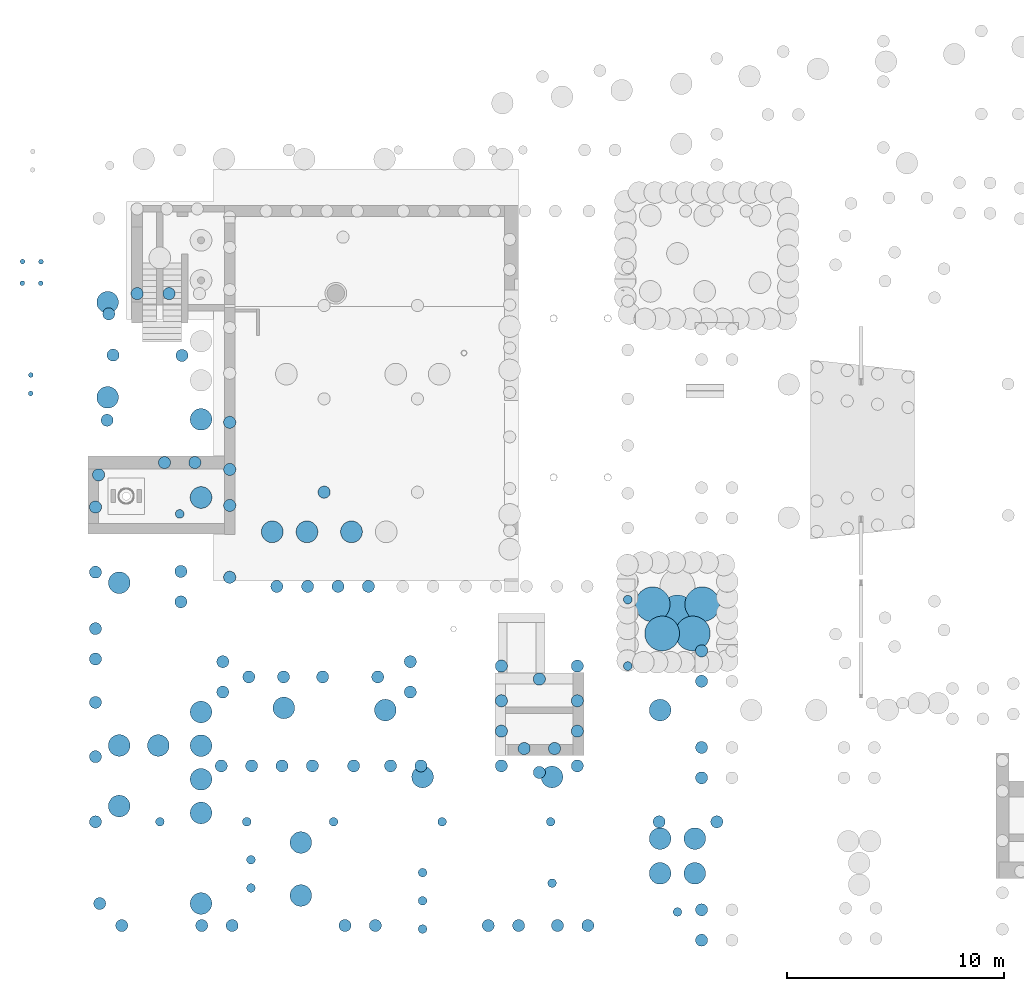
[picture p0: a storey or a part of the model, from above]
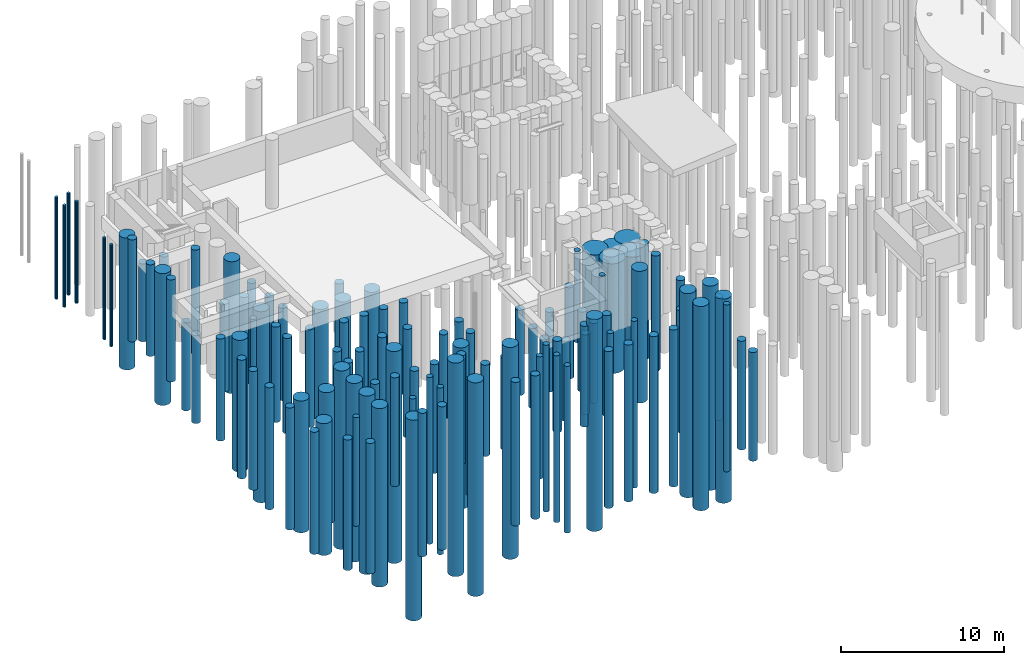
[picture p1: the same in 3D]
Properties of the parts of a building model (IFC2X3), part 1 of 18

# File
Description: ViewDefinition [CoordinationView_V2.0, QuantityTakeOffAddOnView]
File name: 219052
Time: 2021-05-28T06:18:43
Written by: The EXPRESS Data Manager Version 5.02.0100.07 : 28 Aug 2013
Made in: 20210416_1515(x64) - Exporter 19.5.1.0 - Alternate UI 19.5.1.0
Comment: STEP Physical File produced by: The EXPRESS Data Manager Version 5.02.0100.07 : 28 Aug 2013 * Module: EDMstepFileFactory/EDMstandAlone * Creation date: Fri May 28 06:18:43 2021 * Host: pbtutr100 * Database: C:\Users\FDAALH~1\AppData\Local\Temp\{68DC5530-F8EF-4A1F-8CA8-0C31A68B41FF}\ifc * Database version: 5507 * Database creation date: Fri May 28 06:17:17 2021 * Schema: IFC2X3 * Model: DataRepository.ifc * Model creation date: Fri May 28 06:17:18 2021 * Header model: DataRepository.ifc_HeaderModel * Header model creation date: Fri May 28 06:17:18 2021 * EDMuser: sdai-user * EDMgroup: sdai-group * License ID and type: 5605 : Permanent license. Expiry date: * EDMstepFileFactory options: 020000

# IfcProject, 219052
LongName: Theater aan de Parade; Phase: Technisch Ontwerp

# IfcSite, Theater aan de Parade
RefLatitude: 52, 22, 22, 799999; RefLongitude: 4, 53, 41, 279999; RefElevation: 0 mm
Pset_ProductRequirements - Category: Project Information

# IfcBuilding, Theater aan de Parade
LongName: Theater aan de Parade
Pset_BuildingCommon - NumberOfStoreys: 9
Pset_ProductRequirements - Category: Project Information
Pset_Pieters Projectinformatie - 1.1 Bedrijf: Pieters Bouwtechniek Utrecht; 1.2 Website: www.pietersbouwtechniek.nl; 1.3 Projectleider: ir. Y. van Diermen; 1.4 BIM-modelleur: Pieters Bouwtechniek Utrecht; 2.1 Projectnummer: 219052; 2.2 Projectnaam: Theater aan de Parade; 2.3 Project Address: Den Bosch; 2.4 Opdrachtgever: Gemeente Den Bosch; 2.5 Project Status: Technisch Ontwerp; 3.1 Model status: Definitief Ontwerp; 3.2 Datum model: 28-05-2021

# IfcBuildingStorey: Level:PBT_level (9)
In: Theater aan de Parade
Pset_ProductRequirements - Category: Levels
Name | LongName | Elevation (mm) | Pset_AirSideSystemInformation, Name = Pset_ProductRequirements, Name
-2 kelder | -2 kelder | -5520 | palenplan
-1 kelder | -1 kelder | -3300 | -1 kelder
00 begane grond | 00 begane grond | 3.49117e-09 | 00 begane grond
01 eerste verdieping | 01 eerste verdieping | 5020 | 01 eerste verdieping
02 tweede verdieping | 02 tweede verdieping | 8750 | 02 tweede verdieping
03 derde verdieping | 03 derde verdieping | 12480 | 03 derde verdieping
04 vierde verdieping | 04 vierde verdieping | 15820 | 04 vierde verdieping
05 vijfde verdieping | 05 vijfde verdieping | 20300 | 05 vijfde verdieping
06 zesde verdieping | 06 zesde verdieping | 26150 | 06 zesde verdieping

# IfcBeam: 21_PBT_SF_akoestische ontkoppeling:250x200, 21_PBT_SF_akoestische ontkoppeling:250x200:4782382
In: 05 vijfde verdieping
Type - Pset_BeamCommon - IsExternal: no; LoadBearing: yes
Type - Pset_ManufacturerTypeInformation - Manufacturer: Leverancier
Type - Pset_ProductRequirements - Category: Structural Framing
Type - Pset_ReinforcementBarPitchOfBeam - Description: akoestisch isolerende oplegging cf. opgave leverancier
Type - Pset_Pieters - Breedte: 250 mm; Hoogte: 200 mm; Codering - NL-SfB: 21.25; Omschrijving NL-SfB: buitenwanden - constructief, borstweringen; Materiaal: 00_PBT_MAT_volgens leverancier; Materiaalkwaliteit: volgens leverancier; Description: akoestisch isolerende oplegging cf. opgave leverancier
Classification: 21.25 buitenwanden - constructief, borstweringen (Uniformat); Material: 00_PBT_MAT_volgens leverancier
BaseQuantities - CrossSectionArea: 1827897 mm2; NetVolume: 0.197544 m3; Length: 3950.88 mm; NetSurfaceArea: 3655794 mm2
Pset_BeamCommon - Slope: 0 deg; Reference: 21_PBT_SF_akoestische ontkoppeling:250x200; Span: 3950.88 mm
Pset_QuantityTakeOff - Reference: 21_PBT_SF_akoestische ontkoppeling:250x200
Pset_ReinforcementBarPitchOfBeam - Reference: 21_PBT_SF_akoestische ontkoppeling:250x200
Pset_Pieters - Bouwlaag: Level: 05 vijfde verdieping; Naamgeving element: 21_PBT_SF_akoestische ontkoppeling: 250x200; Fase: Nieuw

# IfcBeam: 21_PBT_SF_akoestische ontkoppeling:250x300 (2)
In: 05 vijfde verdieping
Type - Pset_BeamCommon - IsExternal: no; LoadBearing: yes
Type - Pset_ManufacturerTypeInformation - Manufacturer: Leverancier
Type - Pset_ProductRequirements - Category: Structural Framing
Type - Pset_ReinforcementBarPitchOfBeam - Description: akoestisch isolerende oplegging cf. opgave leverancier
Type - Pset_Pieters - Breedte: 250 mm; Hoogte: 300 mm; Codering - NL-SfB: 21.25; Omschrijving NL-SfB: buitenwanden - constructief, borstweringen; Materiaal: 00_PBT_MAT_volgens leverancier; Materiaalkwaliteit: volgens leverancier; Description: akoestisch isolerende oplegging cf. opgave leverancier
Classification: 21.25 buitenwanden - constructief, borstweringen (Uniformat); Material: 00_PBT_MAT_volgens leverancier
Pset_BeamCommon - Slope: 0 deg; Reference: 21_PBT_SF_akoestische ontkoppeling:250x300
Pset_QuantityTakeOff - Reference: 21_PBT_SF_akoestische ontkoppeling:250x300
Pset_ReinforcementBarPitchOfBeam - Reference: 21_PBT_SF_akoestische ontkoppeling:250x300
Pset_Pieters - Bouwlaag: Level: 05 vijfde verdieping; Naamgeving element: 21_PBT_SF_akoestische ontkoppeling: 250x300; Fase: Nieuw
Name (21_PBT_SF_akoestische ontkoppeling:250x300:...) | CrossSectionArea (mm2) | NetVolume (m3) | Span (mm) = Length (mm) | NetSurfaceArea (mm2)
2983572 | 14127500 | 1.91625 | 25550 | 28255000
2986482 | 8379402 | 1.13242 | 15098.9 | 16758803

# IfcBeam: 28_PBT_SF_betonbalk enkele sponning:C30/37_1000x950/330x350_bestaand, 28_PBT_SF_betonbalk enkele sponning:C30/37_1000x950/330x350_bestaand:3179845
In: 00 begane grond
Type - Pset_BeamCommon - IsExternal: no; LoadBearing: yes
Type - Pset_ProductRequirements - Category: Structural Framing
Type - Pset_ReinforcementBarPitchOfBeam - Description: 1000x950/330x350
Type - Pset_Pieters - Breedte: 1000 mm; Hoogte: 950 mm; Codering - NL-SfB: 28.11; Omschrijving NL-SfB: hoofddraagconstructies - kolommen en liggers, kolom-/liggerconstructies; Materiaal: 00_PBT_MAT_beton t.p.g._C30/37; Materiaalkwaliteit: C30/37; Description: 1000x950/330x350
Classification: 28.11 hoofddraagconstructies - kolommen en liggers, kolom-/liggerconstructies (Uniformat); Material: 00_PBT_MAT_beton t.p.g._C30/37
BaseQuantities - CrossSectionArea: 31490673 mm2; NetVolume: 10.4303 m3; Length: 19109.8 mm; NetSurfaceArea: 62981346 mm2
Pset_BeamCommon - Slope: 0 deg; Reference: 28_PBT_SF_betonbalk enkele sponning:C30/37_1000x950/330x350_bestaand; Span: 19109.8 mm
Pset_QuantityTakeOff - Reference: 28_PBT_SF_betonbalk enkele sponning:C30/37_1000x950/330x350_bestaand
Pset_ReinforcementBarPitchOfBeam - Reference: 28_PBT_SF_betonbalk enkele sponning:C30/37_1000x950/330x350_bestaand
Pset_Pieters - Bouwlaag: Level: 00 begane grond; Naamgeving element: 28_PBT_SF_betonbalk enkele sponning: C30/37_1000x950/330x350_bestaand; Fase: Nieuw

# IfcBeam: 28_PBT_SF_betonbalk enkele sponning:C30/37_800x950/300x350_bestaand, 28_PBT_SF_betonbalk enkele sponning:C30/37_800x950/300x350_bestaand:3180236
In: 00 begane grond
Type - Pset_BeamCommon - IsExternal: no; LoadBearing: yes
Type - Pset_ProductRequirements - Category: Structural Framing
Type - Pset_ReinforcementBarPitchOfBeam - Description: 800x950/300x350
Type - Pset_Pieters - Breedte: 800 mm; Hoogte: 950 mm; Codering - NL-SfB: 28.11; Omschrijving NL-SfB: hoofddraagconstructies - kolommen en liggers, kolom-/liggerconstructies; Materiaal: 00_PBT_MAT_beton t.p.g._C30/37; Materiaalkwaliteit: C30/37; Description: 800x950/300x350
Classification: 28.11 hoofddraagconstructies - kolommen en liggers, kolom-/liggerconstructies (Uniformat); Material: 00_PBT_MAT_beton t.p.g._C30/37
BaseQuantities - CrossSectionArea: 5006200 mm2; NetVolume: 1.12397 m3; Length: 3733 mm; NetSurfaceArea: 10012400 mm2
Pset_BeamCommon - Slope: 0 deg; Reference: 28_PBT_SF_betonbalk enkele sponning:C30/37_800x950/300x350_bestaand; Span: 3733 mm
Pset_QuantityTakeOff - Reference: 28_PBT_SF_betonbalk enkele sponning:C30/37_800x950/300x350_bestaand
Pset_ReinforcementBarPitchOfBeam - Reference: 28_PBT_SF_betonbalk enkele sponning:C30/37_800x950/300x350_bestaand
Pset_Pieters - Bouwlaag: Level: 00 begane grond; Naamgeving element: 28_PBT_SF_betonbalk enkele sponning: C30/37_800x950/300x350_bestaand; Fase: Nieuw

# IfcBeam: 28_PBT_SF_betonbalk:250x580_bestaand, 28_PBT_SF_betonbalk:250x580_bestaand:1909526
In: 00 begane grond
Type - Pset_BeamCommon - IsExternal: no; LoadBearing: yes
Type - Pset_ProductRequirements - Category: Structural Framing
Type - Pset_ReinforcementBarPitchOfBeam - Description: 250x580
Type - Pset_Pieters - Breedte: 250 mm; Hoogte: 580 mm; Codering - NL-SfB: 28.11; Omschrijving NL-SfB: hoofddraagconstructies - kolommen en liggers, kolom-/liggerconstructies; Materiaal: 00_PBT_MAT_beton t.p.g.; Description: 250x580
Classification: 28.11 hoofddraagconstructies - kolommen en liggers, kolom-/liggerconstructies (Uniformat); Material: 00_PBT_MAT_beton t.p.g.
BaseQuantities - CrossSectionArea: 4129481 mm2; NetVolume: 0.695609 m3; Length: 4538.37 mm; NetSurfaceArea: 8258963 mm2
Pset_BeamCommon - Slope: 0 deg; Reference: 28_PBT_SF_betonbalk:250x580_bestaand; Span: 4538.37 mm
Pset_QuantityTakeOff - Reference: 28_PBT_SF_betonbalk:250x580_bestaand
Pset_ReinforcementBarPitchOfBeam - Reference: 28_PBT_SF_betonbalk:250x580_bestaand
Pset_Pieters - Dragend/niet dragend: yes; In/uitwendig: no; Bouwlaag: Level: 00 begane grond_Offset1000; Naamgeving element: 28_PBT_SF_betonbalk: 250x580_bestaand; Fase: Bestaand

# IfcBeam: 28_PBT_SF_betonbalk:400x800_bestaand (2)
In: 01 eerste verdieping
Type - PredefinedType: BEAM; Classification: 28.11 hoofddraagconstructies - kolommen en liggers, kolom-/liggerconstructies (Uniformat); Material: 00_PBT_MAT_beton t.p.g.
Type - Pset_BeamCommon - IsExternal: no; LoadBearing: yes
Type - Pset_ProductRequirements - Category: Structural Framing
Type - Pset_ReinforcementBarPitchOfBeam - Description: 400x800
Type - Pset_Pieters - Breedte: 400 mm; Hoogte: 800 mm; Codering - NL-SfB: 28.11; Omschrijving NL-SfB: hoofddraagconstructies - kolommen en liggers, kolom-/liggerconstructies; Materiaal: 00_PBT_MAT_beton t.p.g.; Description: 400x800
Pset_BeamCommon - Reference: 28_PBT_SF_betonbalk:400x800_bestaand; Slope: 14.1361 deg
Pset_QuantityTakeOff - Reference: 28_PBT_SF_betonbalk:400x800_bestaand
Pset_ReinforcementBarPitchOfBeam - Reference: 28_PBT_SF_betonbalk:400x800_bestaand
Pset_Pieters - Dragend/niet dragend: yes; In/uitwendig: no; Bouwlaag: Level: 01 eerste verdieping_Offset1000; Naamgeving element: 28_PBT_SF_betonbalk: 400x800_bestaand; Fase: Bestaand
Name (28_PBT_SF_betonbalk:400x800_bestaand:...) | Span (mm) = Length (mm) | CrossSectionArea (mm2) | NetVolume (m3) | NetSurfaceArea (mm2)
1565912 | 4600 | 4719124 | 1.06921 | 9438249
1930396 | 4625.59 | 4845457 | 1.12009 | 9690914

# IfcBeam: 28_PBT_SF_betonbalk:400x800_bestaand (6)
In: 01 eerste verdieping
Type - Pset_BeamCommon - IsExternal: no; LoadBearing: yes
Type - Pset_ProductRequirements - Category: Structural Framing
Type - Pset_ReinforcementBarPitchOfBeam - Description: 400x800
Type - Pset_Pieters - Breedte: 400 mm; Hoogte: 800 mm; Codering - NL-SfB: 28.11; Omschrijving NL-SfB: hoofddraagconstructies - kolommen en liggers, kolom-/liggerconstructies; Materiaal: 00_PBT_MAT_beton t.p.g.; Description: 400x800
Classification: 28.11 hoofddraagconstructies - kolommen en liggers, kolom-/liggerconstructies (Uniformat); Material: 00_PBT_MAT_beton t.p.g.
Pset_BeamCommon - Reference: 28_PBT_SF_betonbalk:400x800_bestaand
Pset_QuantityTakeOff - Reference: 28_PBT_SF_betonbalk:400x800_bestaand
Pset_ReinforcementBarPitchOfBeam - Reference: 28_PBT_SF_betonbalk:400x800_bestaand
Pset_Pieters - Dragend/niet dragend: yes; In/uitwendig: no; Bouwlaag: Level: 01 eerste verdieping_Offset1000; Naamgeving element: 28_PBT_SF_betonbalk: 400x800_bestaand; Fase: Bestaand
Name (28_PBT_SF_betonbalk:400x800_bestaand:...) | CrossSectionArea (mm2) | NetVolume (m3) | Slope (deg) | Span (mm) = Length (mm) | NetSurfaceArea (mm2)
1565437 | 4204902 | 0.95228 | 0 | 3969.1 | 8409803
1930000 | 4013368 | 0.905608 | 0 | 3773.37 | 8026736
1930004 | 4928468 | 1.14791 | 14.1361 | 4625.59 | 9856937
1930203 | 3938368 | 0.887608 | 0 | 3698.37 | 7876736
1930207 | 5603805 | 1.38064 | 14.1361 | 4625.59 | 11207611
1930394 | 3938368 | 0.887608 | 0 | 3698.37 | 7876736

# IfcBeam: 28_PBT_SF_betonbalk:460x200_bestaand (4)
In: 03 derde verdieping
Type - Pset_BeamCommon - IsExternal: no; LoadBearing: yes
Type - Pset_ProductRequirements - Category: Structural Framing
Type - Pset_ReinforcementBarPitchOfBeam - Description: 460x200
Type - Pset_Pieters - Breedte: 460 mm; Hoogte: 200 mm; Codering - NL-SfB: 28.11; Omschrijving NL-SfB: hoofddraagconstructies - kolommen en liggers, kolom-/liggerconstructies; Materiaal: 00_PBT_MAT_beton t.p.g.; Description: 460x200
Classification: 28.11 hoofddraagconstructies - kolommen en liggers, kolom-/liggerconstructies (Uniformat); Material: 00_PBT_MAT_beton t.p.g.
Pset_BeamCommon - Slope: 0 deg; Reference: 28_PBT_SF_betonbalk:460x200_bestaand
Pset_QuantityTakeOff - Reference: 28_PBT_SF_betonbalk:460x200_bestaand
Pset_ReinforcementBarPitchOfBeam - Reference: 28_PBT_SF_betonbalk:460x200_bestaand
Pset_Pieters - Dragend/niet dragend: yes; In/uitwendig: no; Bouwlaag: Level: 03 derde verdieping_Offset1000; Naamgeving element: 28_PBT_SF_betonbalk: 460x200_bestaand; Fase: Bestaand
Name (28_PBT_SF_betonbalk:460x200_bestaand:...) | CrossSectionArea (mm2) | NetVolume (m3) | Span (mm) = Length (mm) | NetSurfaceArea (mm2)
1677606 | 58809.2 | 0.00246754 | 81.1691 | 117618
1686086 | 50330.3 | 0.00173109 | 56.9438 | 100661
5755660 | 709531 | 0.058753 | 1618.83 | 1419062
5763070 | 751234 | 0.0661246 | 1643.06 | 1502468

# IfcBeam: 28_PBT_SF_betonbalk:460x400_bestaand (2)
In: 03 derde verdieping
Type - Pset_BeamCommon - IsExternal: no; LoadBearing: yes
Type - Pset_ProductRequirements - Category: Structural Framing
Type - Pset_ReinforcementBarPitchOfBeam - Description: 460x400
Type - Pset_Pieters - Breedte: 460 mm; Hoogte: 400 mm; Codering - NL-SfB: 28.11; Omschrijving NL-SfB: hoofddraagconstructies - kolommen en liggers, kolom-/liggerconstructies; Materiaal: 00_PBT_MAT_beton t.p.g.; Description: 460x400
Classification: 28.11 hoofddraagconstructies - kolommen en liggers, kolom-/liggerconstructies (Uniformat); Material: 00_PBT_MAT_beton t.p.g.
Pset_BeamCommon - Slope: 0 deg; Reference: 28_PBT_SF_betonbalk:460x400_bestaand
Pset_QuantityTakeOff - Reference: 28_PBT_SF_betonbalk:460x400_bestaand
Pset_ReinforcementBarPitchOfBeam - Reference: 28_PBT_SF_betonbalk:460x400_bestaand
Pset_Pieters - Dragend/niet dragend: yes; In/uitwendig: no; Bouwlaag: Level: 03 derde verdieping_Offset1000; Naamgeving element: 28_PBT_SF_betonbalk: 460x400_bestaand; Fase: Bestaand
Name (28_PBT_SF_betonbalk:460x400_bestaand:...) | CrossSectionArea (mm2) | NetVolume (m3) | Span (mm) = Length (mm) | NetSurfaceArea (mm2)
1681105 | 1529800 | 0.120005 | 3553.7 | 3059599
1686088 | 1718879 | 0.206605 | 3530.9 | 3437758

# IfcBeam: 28_PBT_SF_betonbalk:660x210_bestaand (3)
In: 03 derde verdieping
Type - Pset_BeamCommon - IsExternal: no; LoadBearing: yes
Type - Pset_ProductRequirements - Category: Structural Framing
Type - Pset_ReinforcementBarPitchOfBeam - Description: 660x210
Type - Pset_Pieters - Breedte: 660 mm; Hoogte: 210 mm; Codering - NL-SfB: 28.11; Omschrijving NL-SfB: hoofddraagconstructies - kolommen en liggers, kolom-/liggerconstructies; Materiaal: 00_PBT_MAT_beton t.p.g.; Description: 660x210
Classification: 28.11 hoofddraagconstructies - kolommen en liggers, kolom-/liggerconstructies (Uniformat); Material: 00_PBT_MAT_beton t.p.g.
Pset_BeamCommon - Slope: 0 deg; Reference: 28_PBT_SF_betonbalk:660x210_bestaand
Pset_QuantityTakeOff - Reference: 28_PBT_SF_betonbalk:660x210_bestaand
Pset_ReinforcementBarPitchOfBeam - Reference: 28_PBT_SF_betonbalk:660x210_bestaand
Pset_Pieters - Dragend/niet dragend: yes; In/uitwendig: no; Bouwlaag: Level: 03 derde verdieping_Offset1000; Naamgeving element: 28_PBT_SF_betonbalk: 660x210_bestaand; Fase: Bestaand
Name (28_PBT_SF_betonbalk:660x210_bestaand:...) | CrossSectionArea (mm2) | NetVolume (m3) | Span (mm) = Length (mm) | NetSurfaceArea (mm2)
1676867 | 1840709 | 0.23369 | 3901.17 | 3681417
1686084 | 2592921 | 0.378573 | 3876.94 | 5185842
1769211 | 1091486 | 0.126744 | 1618.83 | 2182971

# IfcBeam: 28_PBT_SF_betonbalk:C30/37_1000x1800, 28_PBT_SF_betonbalk:C30/37_1000x1800:2594089
In: 01 eerste verdieping
Type - Pset_BeamCommon - IsExternal: no; LoadBearing: yes
Type - Pset_ProductRequirements - Category: Structural Framing
Type - Pset_ReinforcementBarPitchOfBeam - Description: 1000x1800
Type - Pset_Pieters - Breedte: 1000 mm; Hoogte: 1800 mm; Codering - NL-SfB: 28.11; Omschrijving NL-SfB: hoofddraagconstructies - kolommen en liggers, kolom-/liggerconstructies; Materiaal: 00_PBT_MAT_beton t.p.g._C30/37; Materiaalkwaliteit: C30/37; Description: 1000x1800
Classification: 28.11 hoofddraagconstructies - kolommen en liggers, kolom-/liggerconstructies (Uniformat); Material: 00_PBT_MAT_beton t.p.g._C30/37
BaseQuantities - CrossSectionArea: 41120002 mm2; NetVolume: 17.92 m3; Length: 21950 mm; NetSurfaceArea: 82240004 mm2
Pset_BeamCommon - Slope: 0 deg; Reference: 28_PBT_SF_betonbalk:C30/37_1000x1800; Span: 21950 mm
Pset_QuantityTakeOff - Reference: 28_PBT_SF_betonbalk:C30/37_1000x1800
Pset_ReinforcementBarPitchOfBeam - Reference: 28_PBT_SF_betonbalk:C30/37_1000x1800
Pset_Pieters - Bouwlaag: Level: 01 eerste verdieping; Naamgeving element: 28_PBT_SF_betonbalk: C30/37_1000x1800; Fase: Nieuw

# IfcBeam: 28_PBT_SF_betonbalk:C30/37_1000x590, 28_PBT_SF_betonbalk:C30/37_1000x590:2683898
In: 00 begane grond
Type - Pset_BeamCommon - IsExternal: no; LoadBearing: yes
Type - Pset_ProductRequirements - Category: Structural Framing
Type - Pset_ReinforcementBarPitchOfBeam - Description: 1000x590
Type - Pset_Pieters - Breedte: 1000 mm; Hoogte: 590 mm; Codering - NL-SfB: 28.11; Omschrijving NL-SfB: hoofddraagconstructies - kolommen en liggers, kolom-/liggerconstructies; Materiaal: 00_PBT_MAT_beton t.p.g._C30/37; Materiaalkwaliteit: C30/37; Description: 1000x590
Classification: 28.11 hoofddraagconstructies - kolommen en liggers, kolom-/liggerconstructies (Uniformat); Material: 00_PBT_MAT_beton t.p.g._C30/37
BaseQuantities - CrossSectionArea: 7429589 mm2; NetVolume: 0.839773 m3; Length: 6560 mm; NetSurfaceArea: 14859177 mm2
Pset_BeamCommon - Slope: 0 deg; Reference: 28_PBT_SF_betonbalk:C30/37_1000x590; Span: 6560 mm
Pset_QuantityTakeOff - Reference: 28_PBT_SF_betonbalk:C30/37_1000x590
Pset_ReinforcementBarPitchOfBeam - Reference: 28_PBT_SF_betonbalk:C30/37_1000x590
Pset_Pieters - Bouwlaag: Level: 00 begane grond; Naamgeving element: 28_PBT_SF_betonbalk: C30/37_1000x590; Fase: Nieuw

# IfcBeam: 28_PBT_SF_betonbalk:C30/37_1200x800, 28_PBT_SF_betonbalk:C30/37_1200x800:5488795
In: 01 eerste verdieping
Type - Pset_BeamCommon - IsExternal: no; LoadBearing: yes
Type - Pset_ProductRequirements - Category: Structural Framing
Type - Pset_ReinforcementBarPitchOfBeam - Description: 1200x800
Type - Pset_Pieters - Breedte: 1200 mm; Hoogte: 800 mm; Codering - NL-SfB: 28.11; Omschrijving NL-SfB: hoofddraagconstructies - kolommen en liggers, kolom-/liggerconstructies; Materiaal: 00_PBT_MAT_beton t.p.g._C30/37; Materiaalkwaliteit: C30/37; Description: 1200x800
Classification: 28.11 hoofddraagconstructies - kolommen en liggers, kolom-/liggerconstructies (Uniformat); Material: 00_PBT_MAT_beton t.p.g._C30/37
BaseQuantities - CrossSectionArea: 7296007 mm2; NetVolume: 2.304 m3; Length: 4000 mm; NetSurfaceArea: 14592014 mm2
Pset_BeamCommon - Slope: 0 deg; Reference: 28_PBT_SF_betonbalk:C30/37_1200x800; Span: 4000 mm
Pset_QuantityTakeOff - Reference: 28_PBT_SF_betonbalk:C30/37_1200x800
Pset_ReinforcementBarPitchOfBeam - Reference: 28_PBT_SF_betonbalk:C30/37_1200x800
Pset_Pieters - Bouwlaag: Level: 01 eerste verdieping; Naamgeving element: 28_PBT_SF_betonbalk: C30/37_1200x800; Fase: Nieuw

# IfcBeam: 28_PBT_SF_betonbalk:C30/37_1250x550, 28_PBT_SF_betonbalk:C30/37_1250x550:2991065
In: 00 begane grond
Type - Pset_BeamCommon - IsExternal: no; LoadBearing: yes
Type - Pset_ProductRequirements - Category: Structural Framing
Type - Pset_ReinforcementBarPitchOfBeam - Description: 1250x550
Type - Pset_Pieters - Breedte: 1250 mm; Hoogte: 550 mm; Codering - NL-SfB: 28.11; Omschrijving NL-SfB: hoofddraagconstructies - kolommen en liggers, kolom-/liggerconstructies; Materiaal: 00_PBT_MAT_beton t.p.g._C30/37; Materiaalkwaliteit: C30/37; Description: 1250x550
Classification: 28.11 hoofddraagconstructies - kolommen en liggers, kolom-/liggerconstructies (Uniformat); Material: 00_PBT_MAT_beton t.p.g._C30/37
BaseQuantities - CrossSectionArea: 34014676 mm2; NetVolume: 6.55173 m3; Length: 23113.6 mm; NetSurfaceArea: 68029352 mm2
Pset_BeamCommon - Slope: 0 deg; Reference: 28_PBT_SF_betonbalk:C30/37_1250x550; Span: 23113.6 mm
Pset_QuantityTakeOff - Reference: 28_PBT_SF_betonbalk:C30/37_1250x550
Pset_ReinforcementBarPitchOfBeam - Reference: 28_PBT_SF_betonbalk:C30/37_1250x550
Pset_Pieters - Dragend/niet dragend: yes; In/uitwendig: no; Bouwlaag: Level: 00 begane grond; Naamgeving element: 28_PBT_SF_betonbalk: C30/37_1250x550; Fase: Nieuw

# IfcBeam: 28_PBT_SF_betonbalk:C30/37_200x250_opstort, 28_PBT_SF_betonbalk:C30/37_200x250_opstort:6442182
In: -1 kelder
Type - Pset_BeamCommon - IsExternal: no; LoadBearing: yes
Type - Pset_ProductRequirements - Category: Structural Framing
Type - Pset_ReinforcementBarPitchOfBeam - Description: opstort 220x250
Type - Pset_Pieters - Breedte: 220 mm; Hoogte: 250 mm; Codering - NL-SfB: 28.11; Omschrijving NL-SfB: hoofddraagconstructies - kolommen en liggers, kolom-/liggerconstructies; Materiaal: 00_PBT_MAT_beton t.p.g._C30/37; Materiaalkwaliteit: C30/37; Description: opstort 220x250
Classification: 28.11 hoofddraagconstructies - kolommen en liggers, kolom-/liggerconstructies (Uniformat); Material: 00_PBT_MAT_beton t.p.g._C30/37
BaseQuantities - CrossSectionArea: 1230000 mm2; NetVolume: 0.1375 m3; Length: 2632.5 mm; NetSurfaceArea: 2460000 mm2
Pset_BeamCommon - Slope: 0 deg; Reference: 28_PBT_SF_betonbalk:C30/37_200x250_opstort; Span: 2632.5 mm
Pset_QuantityTakeOff - Reference: 28_PBT_SF_betonbalk:C30/37_200x250_opstort
Pset_ReinforcementBarPitchOfBeam - Reference: 28_PBT_SF_betonbalk:C30/37_200x250_opstort
Pset_Pieters - Bouwlaag: Level: -1 kelder; Naamgeving element: 28_PBT_SF_betonbalk: C30/37_200x250_opstort; Fase: Nieuw

# IfcBeam: 28_PBT_SF_betonbalk:C30/37_500x1155, 28_PBT_SF_betonbalk:C30/37_500x1155:3469167
In: 05 vijfde verdieping
Type - Pset_BeamCommon - IsExternal: no; LoadBearing: yes
Type - Pset_ProductRequirements - Category: Structural Framing
Type - Pset_ReinforcementBarPitchOfBeam - Description: 500x1155
Type - Pset_Pieters - Breedte: 500 mm; Hoogte: 1155 mm; Codering - NL-SfB: 28.11; Omschrijving NL-SfB: hoofddraagconstructies - kolommen en liggers, kolom-/liggerconstructies; Materiaal: 00_PBT_MAT_beton t.p.g._C30/37; Materiaalkwaliteit: C30/37; Description: 500x1155
Classification: 28.11 hoofddraagconstructies - kolommen en liggers, kolom-/liggerconstructies (Uniformat); Material: 00_PBT_MAT_beton t.p.g._C30/37
BaseQuantities - CrossSectionArea: 5112010 mm2; NetVolume: 1.50675 m3; Length: 3292 mm; NetSurfaceArea: 10224020 mm2
Pset_BeamCommon - Slope: 0 deg; Reference: 28_PBT_SF_betonbalk:C30/37_500x1155; Span: 3292 mm
Pset_QuantityTakeOff - Reference: 28_PBT_SF_betonbalk:C30/37_500x1155
Pset_ReinforcementBarPitchOfBeam - Reference: 28_PBT_SF_betonbalk:C30/37_500x1155
Pset_Pieters - Bouwlaag: Level: 05 vijfde verdieping; Naamgeving element: 28_PBT_SF_betonbalk: C30/37_500x1155; Fase: Nieuw

# IfcBeam: 28_PBT_SF_betonbalk:C30/37_600x1460, 28_PBT_SF_betonbalk:C30/37_600x1460:6276495
In: -1 kelder
Type - Pset_BeamCommon - IsExternal: no; LoadBearing: yes
Type - Pset_ProductRequirements - Category: Structural Framing
Type - Pset_ReinforcementBarPitchOfBeam - Description: 600x1460
Type - Pset_Pieters - Breedte: 600 mm; Hoogte: 1460 mm; Codering - NL-SfB: 28.11; Omschrijving NL-SfB: hoofddraagconstructies - kolommen en liggers, kolom-/liggerconstructies; Materiaal: 00_PBT_MAT_beton t.p.g._C30/37; Materiaalkwaliteit: C30/37; Description: 600x1460
Classification: 28.11 hoofddraagconstructies - kolommen en liggers, kolom-/liggerconstructies (Uniformat); Material: 00_PBT_MAT_beton t.p.g._C30/37
BaseQuantities - CrossSectionArea: 5406000 mm2; NetVolume: 1.89 m3; Length: 2500 mm; NetSurfaceArea: 10812000 mm2
Pset_BeamCommon - Slope: 0 deg; Reference: 28_PBT_SF_betonbalk:C30/37_600x1460; Span: 2500 mm
Pset_QuantityTakeOff - Reference: 28_PBT_SF_betonbalk:C30/37_600x1460
Pset_ReinforcementBarPitchOfBeam - Reference: 28_PBT_SF_betonbalk:C30/37_600x1460
Pset_Pieters - Bouwlaag: Level: -1 kelder; Naamgeving element: 28_PBT_SF_betonbalk: C30/37_600x1460; Fase: Nieuw

# IfcBeam: 28_PBT_SF_betonbalk:C30/37_700x475 (6)
Type - Pset_BeamCommon - IsExternal: no; LoadBearing: yes
Type - Pset_ProductRequirements - Category: Structural Framing
Type - Pset_ReinforcementBarPitchOfBeam - Description: 700x475
Type - Pset_Pieters - Breedte: 700 mm; Hoogte: 475 mm; Codering - NL-SfB: 28.11; Omschrijving NL-SfB: hoofddraagconstructies - kolommen en liggers, kolom-/liggerconstructies; Materiaal: 00_PBT_MAT_beton t.p.g._C30/37; Materiaalkwaliteit: C30/37; Description: 700x475
Classification: 28.11 hoofddraagconstructies - kolommen en liggers, kolom-/liggerconstructies (Uniformat); Material: 00_PBT_MAT_beton t.p.g._C30/37
Pset_BeamCommon - Slope: 0 deg; Reference: 28_PBT_SF_betonbalk:C30/37_700x475
Pset_QuantityTakeOff - Reference: 28_PBT_SF_betonbalk:C30/37_700x475
Pset_ReinforcementBarPitchOfBeam - Reference: 28_PBT_SF_betonbalk:C30/37_700x475
Pset_Pieters - Naamgeving element: 28_PBT_SF_betonbalk: C30/37_700x475; Fase: Nieuw
Name (28_PBT_SF_betonbalk:C30/37_700x475:...) | In | CrossSectionArea (mm2) | NetVolume (m3) | Span (mm) = Length (mm) | Bouwlaag | NetSurfaceArea (mm2)
4480568 | 01 eerste verdieping | 3214397 | 0.815516 | 2452.68 | Level: 01 eerste verdieping | 6428795
4485362 | 01 eerste verdieping | 3263049 | 0.829283 | 2494.08 | Level: 01 eerste verdieping | 6526099
4485375 | 01 eerste verdieping | 2421318 | 0.31014 | 2400.73 | Level: 01 eerste verdieping | 4842636
4485550 | 02 tweede verdieping | 3142680 | 0.795221 | 2391.64 | Level: 02 tweede verdieping | 6285361
4485687 | 02 tweede verdieping | 3164496 | 0.801394 | 2410.21 | Level: 02 tweede verdieping | 6328991
4485700 | 02 tweede verdieping | 3054407 | 0.770242 | 2316.52 | Level: 02 tweede verdieping | 6108815

# IfcBeam: 28_PBT_SF_betonbalk:C30/37_715x1620, 28_PBT_SF_betonbalk:C30/37_715x1620:3781543
In: 00 begane grond
Type - Pset_BeamCommon - IsExternal: no; LoadBearing: yes
Type - Pset_ProductRequirements - Category: Structural Framing
Type - Pset_ReinforcementBarPitchOfBeam - Description: 715x1620
Type - Pset_Pieters - Breedte: 715 mm; Hoogte: 1620 mm; Codering - NL-SfB: 28.11; Omschrijving NL-SfB: hoofddraagconstructies - kolommen en liggers, kolom-/liggerconstructies; Materiaal: 00_PBT_MAT_beton t.p.g._C30/37; Materiaalkwaliteit: C30/37; Description: 715x1620
Classification: 28.11 hoofddraagconstructies - kolommen en liggers, kolom-/liggerconstructies (Uniformat); Material: 00_PBT_MAT_beton t.p.g._C30/37
BaseQuantities - CrossSectionArea: 28448347 mm2; NetVolume: 12.2539 m3; Length: 14873.2 mm; NetSurfaceArea: 56896695 mm2
Pset_BeamCommon - IsExternal: yes; Slope: 0 deg; Reference: 28_PBT_SF_betonbalk:C30/37_715x1620; Span: 14873.2 mm
Pset_QuantityTakeOff - Reference: 28_PBT_SF_betonbalk:C30/37_715x1620
Pset_ReinforcementBarPitchOfBeam - Reference: 28_PBT_SF_betonbalk:C30/37_715x1620
Pset_Pieters - Dragend/niet dragend: yes; In/uitwendig: yes; Bouwlaag: Level: 00 begane grond; Naamgeving element: 28_PBT_SF_betonbalk: C30/37_715x1620; Fase: Nieuw

# IfcBeam: 28_PBT_SF_betonbalk:C30/37_770x1155, 28_PBT_SF_betonbalk:C30/37_770x1155:3468080
In: 05 vijfde verdieping
Type - PredefinedType: BEAM; Classification: 28.11 hoofddraagconstructies - kolommen en liggers, kolom-/liggerconstructies (Uniformat); Material: 00_PBT_MAT_beton t.p.g._C30/37
Type - Pset_BeamCommon - IsExternal: no; LoadBearing: yes
Type - Pset_ProductRequirements - Category: Structural Framing
Type - Pset_ReinforcementBarPitchOfBeam - Description: 770x1155
Type - Pset_Pieters - Breedte: 770 mm; Hoogte: 1155 mm; Codering - NL-SfB: 28.11; Omschrijving NL-SfB: hoofddraagconstructies - kolommen en liggers, kolom-/liggerconstructies; Materiaal: 00_PBT_MAT_beton t.p.g._C30/37; Materiaalkwaliteit: C30/37; Description: 770x1155
Pset_BeamCommon - Slope: 0 deg; Reference: 28_PBT_SF_betonbalk:C30/37_770x1155; Span: 15448.8 mm
Pset_QuantityTakeOff - Reference: 28_PBT_SF_betonbalk:C30/37_770x1155
Pset_ReinforcementBarPitchOfBeam - Reference: 28_PBT_SF_betonbalk:C30/37_770x1155
Pset_Pieters - Bouwlaag: Level: 05 vijfde verdieping; Naamgeving element: 28_PBT_SF_betonbalk: C30/37_770x1155; Fase: Nieuw
BaseQuantities - Length: 15448.8 mm; CrossSectionArea: 24725361 mm2; OuterSurfaceArea: 2843.04 mm2; GrossSurfaceArea: 1781543 mm2; GrossVolume: 0.000656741 m3; NetVolume: 8.8651 m3; NetSurfaceArea: 49450722 mm2

# IfcBeam: 28_PBT_SF_betonbalk:C30/37_900x900, 28_PBT_SF_betonbalk:C30/37_900x900:5520784
In: 01 eerste verdieping
Type - Pset_BeamCommon - IsExternal: no; LoadBearing: yes
Type - Pset_ProductRequirements - Category: Structural Framing
Type - Pset_ReinforcementBarPitchOfBeam - Description: 900x900
Type - Pset_Pieters - Breedte: 900 mm; Hoogte: 900 mm; Codering - NL-SfB: 28.11; Omschrijving NL-SfB: hoofddraagconstructies - kolommen en liggers, kolom-/liggerconstructies; Materiaal: 00_PBT_MAT_beton t.p.g._C30/37; Materiaalkwaliteit: C30/37; Description: 900x900
Classification: 28.11 hoofddraagconstructies - kolommen en liggers, kolom-/liggerconstructies (Uniformat); Material: 00_PBT_MAT_beton t.p.g._C30/37
BaseQuantities - CrossSectionArea: 32310002 mm2; NetVolume: 14.1138 m3; Length: 17200 mm; NetSurfaceArea: 64620004 mm2
Pset_BeamCommon - Slope: 0 deg; Reference: 28_PBT_SF_betonbalk:C30/37_900x900; Span: 17200 mm
Pset_QuantityTakeOff - Reference: 28_PBT_SF_betonbalk:C30/37_900x900
Pset_ReinforcementBarPitchOfBeam - Reference: 28_PBT_SF_betonbalk:C30/37_900x900
Pset_Pieters - Dragend/niet dragend: yes; Bouwlaag: Level: 01 eerste verdieping; Naamgeving element: 28_PBT_SF_betonbalk: C30/37_900x900; Fase: Nieuw

# IfcBeam: 28_PBT_SF_betonbalk:C30/37_900x980, 28_PBT_SF_betonbalk:C30/37_900x980:2054561
In: 01 eerste verdieping
Type - Pset_BeamCommon - IsExternal: no; LoadBearing: yes
Type - Pset_ProductRequirements - Category: Structural Framing
Type - Pset_ReinforcementBarPitchOfBeam - Description: 900x980
Type - Pset_Pieters - Breedte: 900 mm; Hoogte: 980 mm; Codering - NL-SfB: 28.11; Omschrijving NL-SfB: hoofddraagconstructies - kolommen en liggers, kolom-/liggerconstructies; Materiaal: 00_PBT_MAT_beton t.p.g._C30/37; Materiaalkwaliteit: C30/37; Description: 900x980
Classification: 28.11 hoofddraagconstructies - kolommen en liggers, kolom-/liggerconstructies (Uniformat); Material: 00_PBT_MAT_beton t.p.g._C30/37
BaseQuantities - CrossSectionArea: 7811000 mm2; NetVolume: 2.7531 m3; Length: 4600 mm; NetSurfaceArea: 15622000 mm2
Pset_BeamCommon - Slope: 0 deg; Reference: 28_PBT_SF_betonbalk:C30/37_900x980; Span: 4600 mm
Pset_QuantityTakeOff - Reference: 28_PBT_SF_betonbalk:C30/37_900x980
Pset_ReinforcementBarPitchOfBeam - Reference: 28_PBT_SF_betonbalk:C30/37_900x980
Pset_Pieters - Dragend/niet dragend: yes; Bouwlaag: Level: 01 eerste verdieping; Naamgeving element: 28_PBT_SF_betonbalk: C30/37_900x980; Fase: Nieuw

# IfcBeam: 28_PBT_SF_betonbalk:C40/50_835x1620, 28_PBT_SF_betonbalk:C40/50_835x1620:3780095
In: 00 begane grond
Type - Pset_BeamCommon - IsExternal: no; LoadBearing: yes
Type - Pset_ProductRequirements - Category: Structural Framing
Type - Pset_ReinforcementBarPitchOfBeam - Description: 835x1620
Type - Pset_Pieters - Breedte: 835 mm; Hoogte: 1620 mm; Codering - NL-SfB: 28.11; Omschrijving NL-SfB: hoofddraagconstructies - kolommen en liggers, kolom-/liggerconstructies; Materiaal: 00_PBT_MAT_beton t.p.g._C40/50; Materiaalkwaliteit: C40/50; Description: 835x1620
Classification: 28.11 hoofddraagconstructies - kolommen en liggers, kolom-/liggerconstructies (Uniformat); Material: 00_PBT_MAT_beton t.p.g._C40/50
BaseQuantities - CrossSectionArea: 50391454 mm2; NetVolume: 23.9658 m3; Length: 27351.9 mm; NetSurfaceArea: 100782908 mm2
Pset_BeamCommon - IsExternal: yes; Slope: 0 deg; Reference: 28_PBT_SF_betonbalk:C40/50_835x1620; Span: 27351.9 mm
Pset_QuantityTakeOff - Reference: 28_PBT_SF_betonbalk:C40/50_835x1620
Pset_ReinforcementBarPitchOfBeam - Reference: 28_PBT_SF_betonbalk:C40/50_835x1620
Pset_Pieters - Dragend/niet dragend: yes; In/uitwendig: yes; Bouwlaag: Level: 00 begane grond; Naamgeving element: 28_PBT_SF_betonbalk: C40/50_835x1620; Fase: Nieuw

# IfcBeam: 28_PBT_SF_betontrap kelder A_B_15:betontrap_bestaand, 28_PBT_SF_betontrap kelder A_B_15:betontrap_bestaand:3055888
In: -2 kelder
Type - Pset_BeamCommon - IsExternal: no; LoadBearing: yes
Type - Pset_ProductRequirements - Category: Structural Framing
Type - Pset_Pieters - Codering - NL-SfB: 24.11; Omschrijving NL-SfB: trappen en hellingen - trappen, rechte steektrappen
Classification: 24.11 trappen en hellingen - trappen, rechte steektrappen (Uniformat); Material: 00_PBT_MAT_beton t.p.g.
BaseQuantities - CrossSectionArea: 7618870 mm2; NetVolume: 2.44768 m3; NetSurfaceArea: 15237740 mm2
Pset_BeamCommon - Slope: 90 deg; Reference: 28_PBT_SF_betontrap kelder A_B_15:betontrap_bestaand
Pset_QuantityTakeOff - Reference: 28_PBT_SF_betontrap kelder A_B_15:betontrap_bestaand; sets with these values: 2
Pset_Pieters - Dragend/niet dragend: yes; In/uitwendig: no; Bouwlaag: Level: 00 begane grond; Naamgeving element: 28_PBT_SF_betontrap kelder A_B_15: betontrap_bestaand; Fase: Bestaand; Materiaal: 00_PBT_MAT_beton t.p.g.

# IfcBeam: 28_PBT_SF_betontrap kelder A_B_15_behouden:betontrap_bestaand, 28_PBT_SF_betontrap kelder A_B_15_behouden:betontrap_bestaand:1833537
In: -2 kelder
Type - Pset_BeamCommon - IsExternal: no; LoadBearing: yes
Type - Pset_ProductRequirements - Category: Structural Framing
Type - Pset_Pieters - Codering - NL-SfB: 24.11; Omschrijving NL-SfB: trappen en hellingen - trappen, rechte steektrappen
Classification: 24.11 trappen en hellingen - trappen, rechte steektrappen (Uniformat); Material: 00_PBT_MAT_beton t.p.g.
BaseQuantities - CrossSectionArea: 8538996 mm2; NetVolume: 2.18986 m3; NetSurfaceArea: 17077993 mm2
Pset_BeamCommon - Reference: 28_PBT_SF_betontrap kelder A_B_15_behouden:betontrap_bestaand; Slope: 90 deg
Pset_QuantityTakeOff - Reference: 28_PBT_SF_betontrap kelder A_B_15_behouden:betontrap_bestaand; sets with these values: 2
Pset_Pieters - Dragend/niet dragend: yes; In/uitwendig: no; Bouwlaag: Level: -1 kelder_Offset1000; Naamgeving element: 28_PBT_SF_betontrap kelder A_B_15_behouden: betontrap_bestaand; Fase: Bestaand; Materiaal: 00_PBT_MAT_beton t.p.g.

# IfcBeam: 28_PBT_SF_betonvloer_hoofdzaal:betonvloer_hoofdzaal_bestaand, 28_PBT_SF_betonvloer_hoofdzaal:betonvloer_hoofdzaal_bestaand:1550202
In: 00 begane grond
Type - PredefinedType: BEAM; Classification: 23.21 vloeren - constructief, vrijdragende vloeren (Uniformat); Material: 00_PBT_MAT_beton t.p.g.
Type - Pset_BeamCommon - IsExternal: no; LoadBearing: yes
Type - Pset_ProductRequirements - Category: Structural Framing
Type - Pset_ReinforcementBarPitchOfBeam - Description: tribunevloer beton
Type - Pset_Pieters - Codering - NL-SfB: 23.21; Omschrijving NL-SfB: vloeren - constructief, vrijdragende vloeren; Description: tribunevloer beton
Pset_BeamCommon - Reference: 28_PBT_SF_betonvloer_hoofdzaal:betonvloer_hoofdzaal_bestaand
Pset_QuantityTakeOff - Reference: 28_PBT_SF_betonvloer_hoofdzaal:betonvloer_hoofdzaal_bestaand
Pset_ReinforcementBarPitchOfBeam - Reference: 28_PBT_SF_betonvloer_hoofdzaal:betonvloer_hoofdzaal_bestaand
Pset_Pieters - Dragend/niet dragend: yes; In/uitwendig: no; Naamgeving element: 28_PBT_SF_betonvloer_hoofdzaal: betonvloer_hoofdzaal_bestaand; Fase: Bestaand; Materiaal: 00_PBT_MAT_beton t.p.g.
BaseQuantities - CrossSectionArea: 380977124 mm2; NetVolume: 72.8145 m3; NetSurfaceArea: 761954247 mm2

# IfcBeam: 28_PBT_SF_betonvloer_hoofdzaal_boven:betonvloer_hoofdzaal_boven_bestaand, 28_PBT_SF_betonvloer_hoofdzaal_boven:betonvloer_hoofdzaal_boven_bestaand:1601338
In: 02 tweede verdieping
Type - PredefinedType: BEAM; Classification: 23.21 vloeren - constructief, vrijdragende vloeren (Uniformat); Material: 00_PBT_MAT_beton t.p.g.
Type - Pset_BeamCommon - IsExternal: no; LoadBearing: yes
Type - Pset_ProductRequirements - Category: Structural Framing
Type - Pset_ReinforcementBarPitchOfBeam - Description: tribunevloer beton
Type - Pset_Pieters - Codering - NL-SfB: 23.21; Omschrijving NL-SfB: vloeren - constructief, vrijdragende vloeren; Description: tribunevloer beton
Pset_BeamCommon - Reference: 28_PBT_SF_betonvloer_hoofdzaal_boven:betonvloer_hoofdzaal_boven_bestaand
Pset_QuantityTakeOff - Reference: 28_PBT_SF_betonvloer_hoofdzaal_boven:betonvloer_hoofdzaal_boven_bestaand
Pset_ReinforcementBarPitchOfBeam - Reference: 28_PBT_SF_betonvloer_hoofdzaal_boven:betonvloer_hoofdzaal_boven_bestaand
Pset_Pieters - Dragend/niet dragend: yes; In/uitwendig: no; Naamgeving element: 28_PBT_SF_betonvloer_hoofdzaal_boven: betonvloer_hoofdzaal_boven_bestaand; Fase: Bestaand; Materiaal: 00_PBT_MAT_beton t.p.g.
BaseQuantities - CrossSectionArea: 349638732 mm2; NetVolume: 118.36 m3; NetSurfaceArea: 699277465 mm2

# IfcBeam: 28_PBT_SF_betonvloer_hoofdzaal_boven_NIEUW:betonvloer_hoofdzaal_boven_C30/37, 28_PBT_SF_betonvloer_hoofdzaal_boven_NIEUW:betonvloer_hoofdzaal_boven_C30/37:2543734
In: 02 tweede verdieping
Type - PredefinedType: BEAM; Classification: 23.21 vloeren - constructief, vrijdragende vloeren (Uniformat); Material: 00_PBT_MAT_beton t.p.g._C30/37
Type - Pset_BeamCommon - IsExternal: no; LoadBearing: yes
Type - Pset_ProductRequirements - Category: Structural Framing
Type - Pset_ReinforcementBarPitchOfBeam - Description: betonvloer d=330
Type - Pset_Pieters - Codering - NL-SfB: 23.21; Omschrijving NL-SfB: vloeren - constructief, vrijdragende vloeren; Materiaal: 00_PBT_MAT_beton t.p.g._C30/37; Materiaalkwaliteit: C30/37; Description: betonvloer d=330
Pset_BeamCommon - Slope: 0 deg; Reference: 28_PBT_SF_betonvloer_hoofdzaal_boven_NIEUW:betonvloer_hoofdzaal_boven_C30/37
Pset_QuantityTakeOff - Reference: 28_PBT_SF_betonvloer_hoofdzaal_boven_NIEUW:betonvloer_hoofdzaal_boven_C30/37
Pset_ReinforcementBarPitchOfBeam - Reference: 28_PBT_SF_betonvloer_hoofdzaal_boven_NIEUW:betonvloer_hoofdzaal_boven_C30/37
Pset_Pieters - Dragend/niet dragend: yes; In/uitwendig: no; Naamgeving element: 28_PBT_SF_betonvloer_hoofdzaal_boven_NIEUW: betonvloer_hoofdzaal_boven_C30/37; Fase: Nieuw
BaseQuantities - CrossSectionArea: 38638512 mm2; NetVolume: 8.85695 m3; NetSurfaceArea: 77277024 mm2

# IfcBeam: 28_PBT_SF_paradezaal_dakboog:28_PBT_SF_paradezaal_dakboog (3)
In: 03 derde verdieping
Type - Pset_BeamCommon - IsExternal: no; LoadBearing: yes
Type - Pset_ProductRequirements - Category: Structural Framing
Type - Pset_ReinforcementBarPitchOfBeam - Description: prefab dakelement
Type - Pset_Pieters - Materiaal: 00_PBT_MAT_beton prefab; Materiaalkwaliteit: volgens leverancier; Description: prefab dakelement
Material: 00_PBT_MAT_beton prefab
Pset_BeamCommon - Slope: 0 deg; Reference: 28_PBT_SF_paradezaal_dakboog:28_PBT_SF_paradezaal_dakboog
Pset_QuantityTakeOff - Reference: 28_PBT_SF_paradezaal_dakboog:28_PBT_SF_paradezaal_dakboog
Pset_ReinforcementBarPitchOfBeam - Reference: 28_PBT_SF_paradezaal_dakboog:28_PBT_SF_paradezaal_dakboog
Pset_Pieters - Bouwlaag: Level: 03 derde verdieping; Naamgeving element: 28_PBT_SF_paradezaal_dakboog: 28_PBT_SF_paradezaal_dakboog; Fase: Nieuw
Name (28_PBT_SF_paradezaal_dakboog:28_PBT_SF_paradezaal_dakboog:...) | CrossSectionArea (mm2) | NetVolume (m3) | Span (mm) = Length (mm) | NetSurfaceArea (mm2)
2222553 | 208857253 | 30.4374 | 31573.3 | 222550647
2223689 | 174542821 | 23.1199 | 28925 | 169971156
2223741 | 201286884 | 28.1945 | 31573.3 | 207409909

# IfcBeam: 28_PBT_SF_raveelijzer:L-staal h=200 (3)
Type - PredefinedType: BEAM; Classification: 28.11 hoofddraagconstructies - kolommen en liggers, kolom-/liggerconstructies (Uniformat); Material: 00_PBT_MAT_staal (2)
Type - Pset_BeamCommon - IsExternal: no; LoadBearing: yes
Type - Pset_ProductRequirements - Category: Structural Framing
Type - Pset_ReinforcementBarPitchOfBeam - Description: raveelijzer
Type - Pset_Pieters - Codering - NL-SfB: 28.11; Omschrijving NL-SfB: hoofddraagconstructies - kolommen en liggers, kolom-/liggerconstructies; Materiaal: 00_PBT_MAT_staal; Materiaalkwaliteit: volgens leverancier; Description: raveelijzer; Type Comments: volgens opgave leverancier
Pset_BeamCommon - Slope: 0 deg; Reference: 28_PBT_SF_raveelijzer:L-staal h=200
Pset_QuantityTakeOff - Reference: 28_PBT_SF_raveelijzer:L-staal h=200
Pset_ReinforcementBarPitchOfBeam - Reference: 28_PBT_SF_raveelijzer:L-staal h=200
Pset_Pieters - Naamgeving element: 28_PBT_SF_raveelijzer: L-staal h=200; Fase: Nieuw
BaseQuantities - OuterSurfaceArea: 190500 mm2; GrossSurfaceArea: 196650 mm2; GrossVolume: 0.0009225 m3
Name (28_PBT_SF_raveelijzer:L-staal h=200:...) | In | Span (mm) = Length (mm) | Bouwlaag | CrossSectionArea (mm2) | NetVolume (m3) | NetSurfaceArea (mm2)
3345764 | 01 eerste verdieping | 2455 | Level: 01 eerste verdieping | 1011020 | 0.0140162 | 2022040
3768041 | 03 derde verdieping | 1910 | Level: 03 derde verdieping | 868100 | 0.0119528 | 1736200
3768527 | 02 tweede verdieping | 1925 | Level: 02 tweede verdieping | 874100 | 0.0120394 | 1748200

# IfcBeam: 28_PBT_SF_raveelijzer:L-staal h=320, 28_PBT_SF_raveelijzer:L-staal h=320:3346059
In: 04 vierde verdieping
Type - PredefinedType: BEAM; Classification: 28.11 hoofddraagconstructies - kolommen en liggers, kolom-/liggerconstructies (Uniformat); Material: 00_PBT_MAT_staal (2)
Type - Pset_BeamCommon - IsExternal: no; LoadBearing: yes
Type - Pset_ProductRequirements - Category: Structural Framing
Type - Pset_ReinforcementBarPitchOfBeam - Description: raveelijzer
Type - Pset_Pieters - Codering - NL-SfB: 28.11; Omschrijving NL-SfB: hoofddraagconstructies - kolommen en liggers, kolom-/liggerconstructies; Materiaal: 00_PBT_MAT_staal; Materiaalkwaliteit: volgens leverancier; Description: raveelijzer; Type Comments: volgens opgave leverancier
Pset_BeamCommon - Slope: 0 deg; Reference: 28_PBT_SF_raveelijzer:L-staal h=320; Span: 3130.2 mm
Pset_QuantityTakeOff - Reference: 28_PBT_SF_raveelijzer:L-staal h=320
Pset_ReinforcementBarPitchOfBeam - Reference: 28_PBT_SF_raveelijzer:L-staal h=320
Pset_Pieters - Bouwlaag: Level: 04 vierde verdieping; Naamgeving element: 28_PBT_SF_raveelijzer: L-staal h=320; Fase: Nieuw
BaseQuantities - Length: 3130.2 mm; CrossSectionArea: 1393380 mm2; OuterSurfaceArea: 262500 mm2; GrossSurfaceArea: 271050 mm2; GrossVolume: 0.0012825 m3; NetVolume: 0.0193594 m3; NetSurfaceArea: 2786760 mm2

# IfcBeam: 28_PBT_SF_rechthoekig hout:46x146 (14)
In: 03 derde verdieping
Type - Pset_BeamCommon - IsExternal: no; LoadBearing: yes
Type - Pset_ProductRequirements - Category: Structural Framing
Type - Pset_ReinforcementBarPitchOfBeam - Description: houten balklaag 46x146-600
Type - Pset_Pieters - Breedte: 46 mm; Hoogte: 146 mm; Codering - NL-SfB: 28.11; Omschrijving NL-SfB: hoofddraagconstructies - kolommen en liggers, kolom-/liggerconstructies; Materiaal: 00_PBT_MAT_hout; Description: houten balklaag 46x146-600; Type Comments: geschaafd
Classification: 28.11 hoofddraagconstructies - kolommen en liggers, kolom-/liggerconstructies (Uniformat); Material: 00_PBT_MAT_hout
BaseQuantities - GrossSurfaceArea: 0 mm2
Pset_BeamCommon - Slope: 0 deg; Reference: 28_PBT_SF_rechthoekig hout:46x146
Pset_QuantityTakeOff - Reference: 28_PBT_SF_rechthoekig hout:46x146
Pset_ReinforcementBarPitchOfBeam - Reference: 28_PBT_SF_rechthoekig hout:46x146
Pset_Pieters - Bouwlaag: Level: 03 derde verdieping; Naamgeving element: 28_PBT_SF_rechthoekig hout: 46x146; Fase: Nieuw
Name (28_PBT_SF_rechthoekig hout:46x146:...) | NetVolume (m3) | Span (mm) = Length (mm) | NetSurfaceArea (mm2) | Group
4337457 | 0.010108 | 1505.06 | 591377 | Model Group:Array Group 3:4337902
4337905 | 0.010108 | 1505.06 | 591377 | Model Group:Array Group 3:4337907
4337954 | 0.010108 | 1505.06 | 591377 | Model Group:Array Group 3:4337956
4337958 | 0.010108 | 1505.06 | 591377 | Model Group:Array Group 3:4337960
4337962 | 0.010108 | 1505.06 | 591377 | Model Group:Array Group 3:4337964
4337966 | 0.010108 | 1505.06 | 591377 | Model Group:Array Group 3:4337968
4337970 | 0.010108 | 1505.06 | 591377 | Model Group:Array Group 3:4337972
4337998 | 0.010108 | 1505.06 | 591377 | Model Group:Array Group 3:4338000
4338086 | 0.0149968 | 2233 | 870904 | Model Group:Array Group 6:4338291
4338294 | 0.0149968 | 2233 | 870904 | Model Group:Array Group 6:4338296
4338316 | 0.0149968 | 2233 | 870904 | Model Group:Array Group 6:4338318
4338320 | 0.0149968 | 2233 | 870904 | Model Group:Array Group 6:4338322
4338324 | 0.0149968 | 2233 | 870904 | Model Group:Array Group 6:4338326
4338344 | 0.0149968 | 2233 | 870904 | Model Group:Array Group 6:4338346

# IfcBeam: 28_PBT_SF_rechthoekig hout:59x159 (5)
In: 05 vijfde verdieping
Type - Pset_BeamCommon - IsExternal: no; LoadBearing: yes
Type - Pset_ProductRequirements - Category: Structural Framing
Type - Pset_ReinforcementBarPitchOfBeam - Description: houten balklaag 59x159-600
Type - Pset_Pieters - Breedte: 59 mm; Hoogte: 159 mm; Codering - NL-SfB: 28.11; Omschrijving NL-SfB: hoofddraagconstructies - kolommen en liggers, kolom-/liggerconstructies; Materiaal: 00_PBT_MAT_hout; Description: houten balklaag 59x159-600; Type Comments: geschaafd
Classification: 28.11 hoofddraagconstructies - kolommen en liggers, kolom-/liggerconstructies (Uniformat); Material: 00_PBT_MAT_hout
BaseQuantities - GrossSurfaceArea: 0 mm2; NetVolume: 0.0171203 m3; Length: 1825 mm; NetSurfaceArea: 814462 mm2
Pset_BeamCommon - Slope: 0 deg; Reference: 28_PBT_SF_rechthoekig hout:59x159; Span: 1825 mm
Pset_QuantityTakeOff - Reference: 28_PBT_SF_rechthoekig hout:59x159
Pset_ReinforcementBarPitchOfBeam - Reference: 28_PBT_SF_rechthoekig hout:59x159
Pset_Pieters - Bouwlaag: Level: 05 vijfde verdieping; Naamgeving element: 28_PBT_SF_rechthoekig hout: 59x159; Fase: Nieuw
Name (28_PBT_SF_rechthoekig hout:59x159:...)
4472617
4472976
4473002
4473013
4473024

# IfcBeam: 28_PBT_SF_rechthoekig hout:70x220 (70)
In: 04 vierde verdieping
Type - Pset_BeamCommon - IsExternal: no; LoadBearing: yes
Type - Pset_ProductRequirements - Category: Structural Framing
Type - Pset_ReinforcementBarPitchOfBeam - Description: houten balklaag 70x220
Type - Pset_Pieters - Breedte: 70 mm; Hoogte: 220 mm; Codering - NL-SfB: 28.11; Omschrijving NL-SfB: hoofddraagconstructies - kolommen en liggers, kolom-/liggerconstructies; Materiaal: 00_PBT_MAT_hout; Description: houten balklaag 70x220; Type Comments: geschaafd
Classification: 28.11 hoofddraagconstructies - kolommen en liggers, kolom-/liggerconstructies (Uniformat); Material: 00_PBT_MAT_hout
BaseQuantities - GrossSurfaceArea: 0 mm2
Pset_BeamCommon - Slope: 0 deg; Reference: 28_PBT_SF_rechthoekig hout:70x220
Pset_QuantityTakeOff - Reference: 28_PBT_SF_rechthoekig hout:70x220
Pset_ReinforcementBarPitchOfBeam - Reference: 28_PBT_SF_rechthoekig hout:70x220
Pset_Pieters - Bouwlaag: Level: 04 vierde verdieping; Naamgeving element: 28_PBT_SF_rechthoekig hout: 70x220; Fase: Nieuw
Name (28_PBT_SF_rechthoekig hout:70x220:...) | NetVolume (m3) | Span (mm) = Length (mm) | NetSurfaceArea (mm2) | Group
2967688 | 0.0416508 | 2950 | 1599468 | Model Group:Array Group 2 (members excluded):2967856
2967859 | 0.0424208 | 3000 | 1628468 | Model Group:Array Group 2:2967865
2967863 | 0.0416508 | 2950 | 1599468 | Model Group:Array Group 2:2967865
2967930 | 0.0424208 | 3000 | 1628468 | Model Group:Array Group 2:2967936
2967934 | 0.0416508 | 2950 | 1599468 | Model Group:Array Group 2:2967936
2967938 | 0.0424208 | 3000 | 1628468 | Model Group:Array Group 2:2967944
2967942 | 0.0416508 | 2950 | 1599468 | Model Group:Array Group 2:2967944
2967946 | 0.0424208 | 3000 | 1628468 | Model Group:Array Group 2:2967952
2967950 | 0.0416508 | 2950 | 1599468 | Model Group:Array Group 2:2967952
2967954 | 0.0424208 | 3000 | 1628468 | Model Group:Array Group 2:2967960
2967958 | 0.0416508 | 2950 | 1599468 | Model Group:Array Group 2:2967960
2967962 | 0.0424208 | 3000 | 1628468 | Model Group:Array Group 2:2967968
2967966 | 0.0416508 | 2950 | 1599468 | Model Group:Array Group 2:2967968
2967970 | 0.0424208 | 3000 | 1628468 | Model Group:Array Group 2:2967976
2967974 | 0.0416508 | 2950 | 1599468 | Model Group:Array Group 2:2967976
2967978 | 0.0424208 | 3000 | 1628468 | Model Group:Array Group 2:2967984
2967982 | 0.0416508 | 2950 | 1599468 | Model Group:Array Group 2:2967984
2967986 | 0.0424208 | 3000 | 1628468 | Model Group:Array Group 2:2967992
2967990 | 0.0416508 | 2950 | 1599468 | Model Group:Array Group 2:2967992
2967994 | 0.0424208 | 3000 | 1628468 | Model Group:Array Group 2:2968000
2967998 | 0.0416508 | 2950 | 1599468 | Model Group:Array Group 2:2968000
2968002 | 0.0424208 | 3000 | 1628468 | Model Group:Array Group 2:2968008
2968006 | 0.0416508 | 2950 | 1599468 | Model Group:Array Group 2:2968008
2968010 | 0.0424208 | 3000 | 1628468 | Model Group:Array Group 2:2968016
2968014 | 0.0416508 | 2950 | 1599468 | Model Group:Array Group 2:2968016
2968018 | 0.0424208 | 3000 | 1628468 | Model Group:Array Group 2:2968024
2968022 | 0.0416508 | 2950 | 1599468 | Model Group:Array Group 2:2968024
2968026 | 0.0424208 | 3000 | 1628468 | Model Group:Array Group 2:2968032
2968030 | 0.0416508 | 2950 | 1599468 | Model Group:Array Group 2:2968032
2968034 | 0.0424208 | 3000 | 1628468 | Model Group:Array Group 2:2968040
2968038 | 0.0416508 | 2950 | 1599468 | Model Group:Array Group 2:2968040
2968042 | 0.0424208 | 3000 | 1628468 | Model Group:Array Group 2:2968048
2968046 | 0.0416508 | 2950 | 1599468 | Model Group:Array Group 2:2968048
2968050 | 0.0424208 | 3000 | 1628468 | Model Group:Array Group 2:2968056
2968054 | 0.0416508 | 2950 | 1599468 | Model Group:Array Group 2:2968056
2968058 | 0.0424208 | 3000 | 1628468 | Model Group:Array Group 2:2968064
2968062 | 0.0416508 | 2950 | 1599468 | Model Group:Array Group 2:2968064
2968066 | 0.0424208 | 3000 | 1628468 | Model Group:Array Group 2:2968072
2968070 | 0.0416508 | 2950 | 1599468 | Model Group:Array Group 2:2968072
2968074 | 0.0424208 | 3000 | 1628468 | Model Group:Array Group 2:2968080
2968078 | 0.0416508 | 2950 | 1599468 | Model Group:Array Group 2:2968080
2968082 | 0.0424208 | 3000 | 1628468 | Model Group:Array Group 2:2968088
2968086 | 0.0416508 | 2950 | 1599468 | Model Group:Array Group 2:2968088
2968090 | 0.0424208 | 3000 | 1628468 | Model Group:Array Group 2:2968096
2968094 | 0.0416508 | 2950 | 1599468 | Model Group:Array Group 2:2968096
2968098 | 0.0424208 | 3000 | 1628468 | Model Group:Array Group 2:2968104
2968102 | 0.0416508 | 2950 | 1599468 | Model Group:Array Group 2:2968104
2968106 | 0.0424208 | 3000 | 1628468 | Model Group:Array Group 2:2968112
2968110 | 0.0416508 | 2950 | 1599468 | Model Group:Array Group 2:2968112
2968114 | 0.0424208 | 3000 | 1628468 | Model Group:Array Group 2:2968120
2968118 | 0.0416508 | 2950 | 1599468 | Model Group:Array Group 2:2968120
2968122 | 0.0424208 | 3000 | 1628468 | Model Group:Array Group 2:2968128
2968126 | 0.0416508 | 2950 | 1599468 | Model Group:Array Group 2:2968128
2968130 | 0.0424208 | 3000 | 1628468 | Model Group:Array Group 2:2968136
2968134 | 0.0416508 | 2950 | 1599468 | Model Group:Array Group 2:2968136
2968138 | 0.0424208 | 3000 | 1628468 | Model Group:Array Group 2:2968144
2968142 | 0.0416508 | 2950 | 1599468 | Model Group:Array Group 2:2968144
2968146 | 0.0424208 | 3000 | 1628468 | Model Group:Array Group 2:2968152
2968150 | 0.0416508 | 2950 | 1599468 | Model Group:Array Group 2:2968152
2968593 | 0.0424208 | 3000 | 1628468 | Model Group:Array Group 2:2968599
2968597 | 0.0416508 | 2950 | 1599468 | Model Group:Array Group 2:2968599
2968601 | 0.0424208 | 3000 | 1628468 | Model Group:Array Group 2:2968607
2968605 | 0.0416508 | 2950 | 1599468 | Model Group:Array Group 2:2968607
2968628 | 0.0424208 | 3000 | 1628468 | Model Group:Array Group 2:2968634
2968632 | 0.0416508 | 2950 | 1599468 | Model Group:Array Group 2:2968634
2968636 | 0.0424208 | 3000 | 1628468 | Model Group:Array Group 2:2968642
2968640 | 0.0416508 | 2950 | 1599468 | Model Group:Array Group 2:2968642
2971068 | 0.0183968 | 1365 | 723668
2971131 | 0.0424208 | 3000 | 1628468
2971171 | 0.0041555 | 480.238 | 187306

# IfcBeam: 28_PBT_SF_rechthoekig hout:70x270 (34)
In: 04 vierde verdieping
Type - Pset_BeamCommon - IsExternal: no; LoadBearing: yes
Type - Pset_ProductRequirements - Category: Structural Framing
Type - Pset_ReinforcementBarPitchOfBeam - Description: houten balklaag 70x270-600
Type - Pset_Pieters - Breedte: 70 mm; Hoogte: 270 mm; Codering - NL-SfB: 28.11; Omschrijving NL-SfB: hoofddraagconstructies - kolommen en liggers, kolom-/liggerconstructies; Materiaal: 00_PBT_MAT_hout; Description: houten balklaag 70x270-600; Type Comments: geschaafd
Classification: 28.11 hoofddraagconstructies - kolommen en liggers, kolom-/liggerconstructies (Uniformat); Material: 00_PBT_MAT_hout
BaseQuantities - GrossSurfaceArea: 0 mm2; NetVolume: 0.0837989 m3; Length: 4922.68 mm; NetSurfaceArea: 3092639 mm2
Pset_BeamCommon - Slope: 0 deg; Reference: 28_PBT_SF_rechthoekig hout:70x270; Span: 4922.68 mm
Pset_QuantityTakeOff - Reference: 28_PBT_SF_rechthoekig hout:70x270
Pset_ReinforcementBarPitchOfBeam - Reference: 28_PBT_SF_rechthoekig hout:70x270
Pset_Pieters - Bouwlaag: Level: 04 vierde verdieping; Naamgeving element: 28_PBT_SF_rechthoekig hout: 70x270; Fase: Nieuw
Name (28_PBT_SF_rechthoekig hout:70x270:...) | Group
2967652 | Model Group:Array Group 2 (members excluded):2967856
2967861 | Model Group:Array Group 2:2967865
2967932 | Model Group:Array Group 2:2967936
2967940 | Model Group:Array Group 2:2967944
2967948 | Model Group:Array Group 2:2967952
2967956 | Model Group:Array Group 2:2967960
2967964 | Model Group:Array Group 2:2967968
2967972 | Model Group:Array Group 2:2967976
2967980 | Model Group:Array Group 2:2967984
2967988 | Model Group:Array Group 2:2967992
2967996 | Model Group:Array Group 2:2968000
2968004 | Model Group:Array Group 2:2968008
2968012 | Model Group:Array Group 2:2968016
2968020 | Model Group:Array Group 2:2968024
2968028 | Model Group:Array Group 2:2968032
2968036 | Model Group:Array Group 2:2968040
2968044 | Model Group:Array Group 2:2968048
2968052 | Model Group:Array Group 2:2968056
2968060 | Model Group:Array Group 2:2968064
2968068 | Model Group:Array Group 2:2968072
2968076 | Model Group:Array Group 2:2968080
2968084 | Model Group:Array Group 2:2968088
2968092 | Model Group:Array Group 2:2968096
2968100 | Model Group:Array Group 2:2968104
2968108 | Model Group:Array Group 2:2968112
2968116 | Model Group:Array Group 2:2968120
2968124 | Model Group:Array Group 2:2968128
2968132 | Model Group:Array Group 2:2968136
2968140 | Model Group:Array Group 2:2968144
2968148 | Model Group:Array Group 2:2968152
2968595 | Model Group:Array Group 2:2968599
2968603 | Model Group:Array Group 2:2968607
2968630 | Model Group:Array Group 2:2968634
2968638 | Model Group:Array Group 2:2968642

# IfcBeam: 28_PBT_SF_staal_H-profiel (void):S355_HE1000A, 28_PBT_SF_staal_H-profiel (void):S355_HE1000A:2428143
In: 03 derde verdieping
Type - Pset_BeamCommon - IsExternal: no; LoadBearing: yes
Type - Pset_ProductRequirements - Category: Structural Framing
Type - Pset_ReinforcementBarPitchOfBeam - Description: HE1000A
Type - Pset_Pieters - Breedte: 300 mm; Hoogte: 990 mm; Codering - NL-SfB: 28.11; Omschrijving NL-SfB: hoofddraagconstructies - kolommen en liggers, kolom-/liggerconstructies; Materiaal: 00_PBT_MAT_staal_S355; Materiaalkwaliteit: S355; Description: HE1000A
Classification: 28.11 hoofddraagconstructies - kolommen en liggers, kolom-/liggerconstructies (Uniformat); Material: 00_PBT_MAT_staal_S355
BaseQuantities - CrossSectionArea: 42649672 mm2; NetVolume: 1.97217 m3; Length: 12169.2 mm; NetSurfaceArea: 63264084 mm2
Pset_BeamCommon - Slope: 0 deg; Reference: 28_PBT_SF_staal_H-profiel (void):S355_HE1000A; Span: 12169.2 mm
Pset_QuantityTakeOff - Reference: 28_PBT_SF_staal_H-profiel (void):S355_HE1000A
Pset_ReinforcementBarPitchOfBeam - Reference: 28_PBT_SF_staal_H-profiel (void):S355_HE1000A
Pset_Pieters - Bouwlaag: Level: 03 derde verdieping; Naamgeving element: 28_PBT_SF_staal_H-profiel (void): S355_HE1000A; Fase: Nieuw

# IfcBeam: 28_PBT_SF_staal_H-profiel (void):S355_HE200A (9)
Type - Pset_BeamCommon - IsExternal: no; LoadBearing: yes
Type - Pset_ProductRequirements - Category: Structural Framing
Type - Pset_ReinforcementBarPitchOfBeam - Description: HE200A
Type - Pset_Pieters - Breedte: 200 mm; Hoogte: 190 mm; Codering - NL-SfB: 28.11; Omschrijving NL-SfB: hoofddraagconstructies - kolommen en liggers, kolom-/liggerconstructies; Materiaal: 00_PBT_MAT_staal_S355; Materiaalkwaliteit: S355; Description: HE200A
Classification: 28.11 hoofddraagconstructies - kolommen en liggers, kolom-/liggerconstructies (Uniformat); Material: 00_PBT_MAT_staal_S355
Pset_BeamCommon - Slope: 0 deg; Reference: 28_PBT_SF_staal_H-profiel (void):S355_HE200A
Pset_QuantityTakeOff - Reference: 28_PBT_SF_staal_H-profiel (void):S355_HE200A
Pset_ReinforcementBarPitchOfBeam - Reference: 28_PBT_SF_staal_H-profiel (void):S355_HE200A
Pset_Pieters - Naamgeving element: 28_PBT_SF_staal_H-profiel (void): S355_HE200A; Fase: Nieuw
Name (28_PBT_SF_staal_H-profiel (void):S355_HE200A:...) | In | CrossSectionArea (mm2) | NetVolume (m3) | Span (mm) = Length (mm) | Bouwlaag | NetSurfaceArea (mm2)
2421167 | 02 tweede verdieping | 17620588 | 0.326653 | 15059 | Level: 02 tweede verdieping | 24953089
2421828 | 02 tweede verdieping | 3974234 | 0.0730171 | 3366.15 | Level: 02 tweede verdieping | 5611486
2945531 | 02 tweede verdieping | 4150831 | 0.0633721 | 2921.5 | Level: 02 tweede verdieping | 4875978
3866156 | 02 tweede verdieping | 5375647 | 0.0341719 | 4833.15 | Level: 02 tweede verdieping | 5793341
3875652 | 01 eerste verdieping | 7763309 | 0.12552 | 5786.58 | Level: 01 eerste verdieping | 9615235
3877644 | 03 derde verdieping | 3828949 | 0.0263762 | 3385 | Level: 03 derde verdieping | 4148097
3877647 | 04 vierde verdieping | 3988622 | 0.027181 | 3534.5 | Level: 04 vierde verdieping | 4317944
3878172 | 00 begane grond | 3828949 | 0.0263762 | 3385 | Level: 00 begane grond | 4148097
5912523 | 02 tweede verdieping | 1247772 | 0.0223422 | 1030 | Level: 02 tweede verdieping | 1747147

# IfcBeam: 28_PBT_SF_staal_H-profiel (void):S355_HE220A (4)
Type - Pset_BeamCommon - IsExternal: no; LoadBearing: yes
Type - Pset_ProductRequirements - Category: Structural Framing
Type - Pset_ReinforcementBarPitchOfBeam - Description: HE220A
Type - Pset_Pieters - Breedte: 220 mm; Hoogte: 210 mm; Codering - NL-SfB: 28.11; Omschrijving NL-SfB: hoofddraagconstructies - kolommen en liggers, kolom-/liggerconstructies; Materiaal: 00_PBT_MAT_staal_S355; Materiaalkwaliteit: S355; Description: HE220A
Classification: 28.11 hoofddraagconstructies - kolommen en liggers, kolom-/liggerconstructies (Uniformat); Material: 00_PBT_MAT_staal_S355
Pset_BeamCommon - Reference: 28_PBT_SF_staal_H-profiel (void):S355_HE220A
Pset_QuantityTakeOff - Reference: 28_PBT_SF_staal_H-profiel (void):S355_HE220A
Pset_ReinforcementBarPitchOfBeam - Reference: 28_PBT_SF_staal_H-profiel (void):S355_HE220A
Pset_Pieters - Naamgeving element: 28_PBT_SF_staal_H-profiel (void): S355_HE220A; Fase: Nieuw
Name (28_PBT_SF_staal_H-profiel (void):S355_HE220A:...) | In | CrossSectionArea (mm2) | NetVolume (m3) | Slope (deg) | Span (mm) = Length (mm) | Bouwlaag | NetSurfaceArea (mm2)
2831419 | 04 vierde verdieping | 3642869 | 0.0413115 | 0 | 2635.13 | Level: 04 vierde verdieping | 4062582
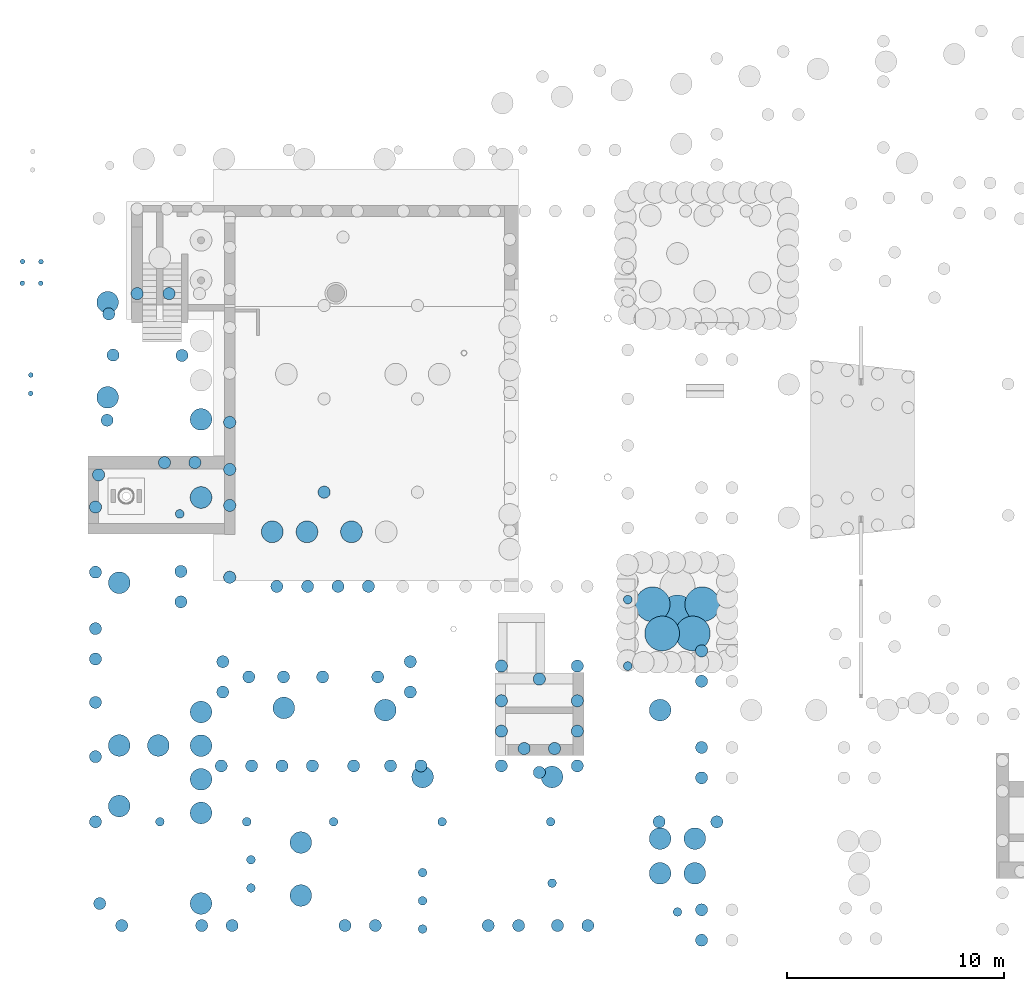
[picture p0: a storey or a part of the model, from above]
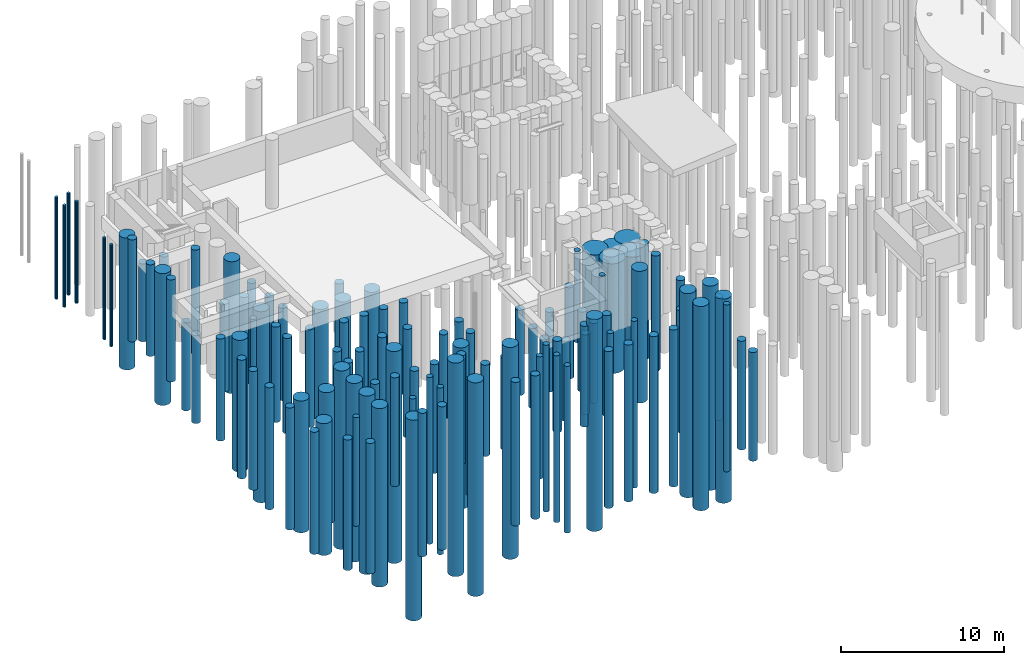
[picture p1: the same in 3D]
Properties of the parts of a building model (IFC2X3), part 2 of 18

# IfcBeam: 28_PBT_SF_staal_H-profiel (void):S355_HE220A (4)
Name (28_PBT_SF_staal_H-profiel (void):S355_HE220A:...) | In | CrossSectionArea (mm2) | NetVolume (m3) | Slope (deg) | Span (mm) = Length (mm) | Bouwlaag | NetSurfaceArea (mm2)
2960478 | 04 vierde verdieping | 5573031 | 0.100531 | 0 | 3820 | Level: 04 vierde verdieping | 7038062
4399534 | 05 vijfde verdieping | 5003120 | 0.032268 | 1.43377 | 4316.31 | Level: 05 vijfde verdieping | 5382078
4402115 | 05 vijfde verdieping | 5258548 | 0.0368873 | 1.34496 | 4601.27 | Level: 05 vijfde verdieping | 5596577

# IfcBeam: 28_PBT_SF_staal_H-profiel (void):S355_HE220B (2)
In: 04 vierde verdieping
Type - Pset_BeamCommon - IsExternal: no; LoadBearing: yes
Type - Pset_ProductRequirements - Category: Structural Framing
Type - Pset_ReinforcementBarPitchOfBeam - Description: HE220B
Type - Pset_Pieters - Breedte: 220 mm; Hoogte: 220 mm; Codering - NL-SfB: 28.11; Omschrijving NL-SfB: hoofddraagconstructies - kolommen en liggers, kolom-/liggerconstructies; Materiaal: 00_PBT_MAT_staal_S355; Materiaalkwaliteit: S355; Description: HE220B
Classification: 28.11 hoofddraagconstructies - kolommen en liggers, kolom-/liggerconstructies (Uniformat); Material: 00_PBT_MAT_staal_S355
Pset_BeamCommon - Slope: 0 deg; Reference: 28_PBT_SF_staal_H-profiel (void):S355_HE220B
Pset_QuantityTakeOff - Reference: 28_PBT_SF_staal_H-profiel (void):S355_HE220B
Pset_ReinforcementBarPitchOfBeam - Reference: 28_PBT_SF_staal_H-profiel (void):S355_HE220B
Pset_Pieters - Bouwlaag: Level: 04 vierde verdieping; Naamgeving element: 28_PBT_SF_staal_H-profiel (void): S355_HE220B; Fase: Nieuw
Name (28_PBT_SF_staal_H-profiel (void):S355_HE220B:...) | CrossSectionArea (mm2) | NetVolume (m3) | Span (mm) = Length (mm) | NetSurfaceArea (mm2)
6306352 | 4442343 | 0.0848186 | 2950 | 5488885
6307639 | 4589400 | 0.0876939 | 3050 | 5673000

# IfcBeam: 28_PBT_SF_staal_H-profiel (void):S355_HE260B, 28_PBT_SF_staal_H-profiel (void):S355_HE260B:4265009
In: 03 derde verdieping
Type - Pset_BeamCommon - IsExternal: no; LoadBearing: yes
Type - Pset_ProductRequirements - Category: Structural Framing
Type - Pset_ReinforcementBarPitchOfBeam - Description: HE260B
Type - Pset_Pieters - Breedte: 260 mm; Hoogte: 260 mm; Codering - NL-SfB: 28.11; Omschrijving NL-SfB: hoofddraagconstructies - kolommen en liggers, kolom-/liggerconstructies; Materiaal: 00_PBT_MAT_staal_S355; Materiaalkwaliteit: S355; Description: HE260B
Classification: 28.11 hoofddraagconstructies - kolommen en liggers, kolom-/liggerconstructies (Uniformat); Material: 00_PBT_MAT_staal_S355
BaseQuantities - CrossSectionArea: 6783762 mm2; NetVolume: 0.0732288 m3; Length: 5241.05 mm; NetSurfaceArea: 8206473 mm2
Pset_BeamCommon - Slope: 0 deg; Reference: 28_PBT_SF_staal_H-profiel (void):S355_HE260B; Span: 5241.05 mm
Pset_QuantityTakeOff - Reference: 28_PBT_SF_staal_H-profiel (void):S355_HE260B
Pset_ReinforcementBarPitchOfBeam - Reference: 28_PBT_SF_staal_H-profiel (void):S355_HE260B
Pset_Pieters - Bouwlaag: Level: 03 derde verdieping; Naamgeving element: 28_PBT_SF_staal_H-profiel (void): S355_HE260B; Fase: Nieuw

# IfcBeam: 28_PBT_SF_staal_H-profiel (void):S355_HE280A (4)
Type - Pset_BeamCommon - IsExternal: no; LoadBearing: yes
Type - Pset_ProductRequirements - Category: Structural Framing
Type - Pset_ReinforcementBarPitchOfBeam - Description: HE280A
Type - Pset_Pieters - Breedte: 280 mm; Hoogte: 270 mm; Codering - NL-SfB: 28.11; Omschrijving NL-SfB: hoofddraagconstructies - kolommen en liggers, kolom-/liggerconstructies; Materiaal: 00_PBT_MAT_staal_S355; Materiaalkwaliteit: S355; Description: HE280A
Classification: 28.11 hoofddraagconstructies - kolommen en liggers, kolom-/liggerconstructies (Uniformat); Material: 00_PBT_MAT_staal_S355
Pset_BeamCommon - Slope: 0 deg; Reference: 28_PBT_SF_staal_H-profiel (void):S355_HE280A
Pset_QuantityTakeOff - Reference: 28_PBT_SF_staal_H-profiel (void):S355_HE280A
Pset_ReinforcementBarPitchOfBeam - Reference: 28_PBT_SF_staal_H-profiel (void):S355_HE280A
Pset_Pieters - Naamgeving element: 28_PBT_SF_staal_H-profiel (void): S355_HE280A; Fase: Nieuw
Name (28_PBT_SF_staal_H-profiel (void):S355_HE280A:...) | In | CrossSectionArea (mm2) | NetVolume (m3) | Span (mm) = Length (mm) | Bouwlaag | NetSurfaceArea (mm2)
2284949 | 01 eerste verdieping | 10493321 | 0.246628 | 5665 | Level: 01 eerste verdieping | 13530642
2285201 | 01 eerste verdieping | 9755005 | 0.226377 | 5306.14 | Level: 01 eerste verdieping | 12513347
2285256 | 01 eerste verdieping | 10067809 | 0.233746 | 5478.86 | Level: 01 eerste verdieping | 12917879
2439401 | 05 vijfde verdieping | 39684382 | 0.931411 | 21831.7 | Level: 05 vijfde verdieping | 51219399

# IfcBeam: 28_PBT_SF_staal_H-profiel (void):S355_HE280B (14)
Type - Pset_BeamCommon - IsExternal: no; LoadBearing: yes
Type - Pset_ProductRequirements - Category: Structural Framing
Type - Pset_ReinforcementBarPitchOfBeam - Description: HE280B
Type - Pset_Pieters - Breedte: 280 mm; Hoogte: 280 mm; Codering - NL-SfB: 28.11; Omschrijving NL-SfB: hoofddraagconstructies - kolommen en liggers, kolom-/liggerconstructies; Materiaal: 00_PBT_MAT_staal_S355; Materiaalkwaliteit: S355; Description: HE280B
Classification: 28.11 hoofddraagconstructies - kolommen en liggers, kolom-/liggerconstructies (Uniformat); Material: 00_PBT_MAT_staal_S355
Pset_BeamCommon - Slope: 0 deg; Reference: 28_PBT_SF_staal_H-profiel (void):S355_HE280B
Pset_QuantityTakeOff - Reference: 28_PBT_SF_staal_H-profiel (void):S355_HE280B
Pset_ReinforcementBarPitchOfBeam - Reference: 28_PBT_SF_staal_H-profiel (void):S355_HE280B
Pset_Pieters - Naamgeving element: 28_PBT_SF_staal_H-profiel (void): S355_HE280B; Fase: Nieuw
Name (28_PBT_SF_staal_H-profiel (void):S355_HE280B:...) | In | CrossSectionArea (mm2) | NetVolume (m3) | Span (mm) = Length (mm) | Bouwlaag | NetSurfaceArea (mm2)
2255932 | 01 eerste verdieping | 26971876 | 0.678212 | 14711.4 | Level: 01 eerste verdieping | 34908301
2307048 | 01 eerste verdieping | 8332503 | 0.0778995 | 5930 | Level: 01 eerste verdieping | 9619806
2423783 | 03 derde verdieping | 33805116 | 0.811263 | 17725.5 | Level: 03 derde verdieping | 41829574
2428490 | 03 derde verdieping | 7540372 | 0.186166 | 4067.58 | Level: 03 derde verdieping | 9669444
2436713 | 04 vierde verdieping | 32361479 | 0.811263 | 17725.5 | Level: 04 vierde verdieping | 41829574
2437564 | 03 derde verdieping | 2178381 | 0.0216438 | 1275 | Level: 03 derde verdieping | 2264762
2440122 | 04 vierde verdieping | 26308135 | 0.937133 | 11953.2 | Level: 04 vierde verdieping | 37111331
2441571 | 04 vierde verdieping | 12539190 | 0.11264 | 8574.55 | Level: 04 vierde verdieping | 13898153
2647335 | 04 vierde verdieping | 2465286 | 0.0583545 | 1275 | Level: 04 vierde verdieping | 3093772
2945181 | 02 tweede verdieping | 27008223 | 0.679127 | 14731.4 | Level: 02 tweede verdieping | 34955395
3532805 | 05 vijfde verdieping | 3196499 | 0.0767695 | 1677.35 | Level: 05 vijfde verdieping | 4041188
3534989 | 06 zesde verdieping | 2322073 | 0.0210515 | 1602.52 | Level: 06 zesde verdieping | 2618823
4360340 | 03 derde verdieping | 7222545 | 0.0674013 | 5130.84 | Level: 03 derde verdieping | 8326921
5914043 | 02 tweede verdieping | 5859327 | 0.0520764 | 3964.25 | Level: 02 tweede verdieping | 6439618

# IfcBeam: 28_PBT_SF_staal_H-profiel (void):S355_HE280B_Z (3)
In: 03 derde verdieping
Type - Pset_BeamCommon - IsExternal: no; LoadBearing: yes
Type - Pset_ProductRequirements - Category: Structural Framing
Type - Pset_ReinforcementBarPitchOfBeam - Description: HE280B(Z)
Type - Pset_Pieters - Breedte: 280 mm; Hoogte: 280 mm; Codering - NL-SfB: 28.11; Omschrijving NL-SfB: hoofddraagconstructies - kolommen en liggers, kolom-/liggerconstructies; Materiaal: 00_PBT_MAT_staal_S355; Materiaalkwaliteit: S355; Description: HE280B(Z)
Classification: 28.11 hoofddraagconstructies - kolommen en liggers, kolom-/liggerconstructies (Uniformat); Material: 00_PBT_MAT_staal_S355
Pset_BeamCommon - Slope: 0 deg; Reference: 28_PBT_SF_staal_H-profiel (void):S355_HE280B_Z
Pset_QuantityTakeOff - Reference: 28_PBT_SF_staal_H-profiel (void):S355_HE280B_Z
Pset_ReinforcementBarPitchOfBeam - Reference: 28_PBT_SF_staal_H-profiel (void):S355_HE280B_Z
Pset_Pieters - Bouwlaag: Level: 03 derde verdieping; Naamgeving element: 28_PBT_SF_staal_H-profiel (void): S355_HE280B_Z; Fase: Nieuw
Name (28_PBT_SF_staal_H-profiel (void):S355_HE280B_Z:...) | CrossSectionArea (mm2) | NetVolume (m3) | Span (mm) = Length (mm) | NetSurfaceArea (mm2)
2838588 | 4846369 | 0.0449269 | 3420 | 5559137
6296691 | 5834241 | 0.0542704 | 4131.26 | 6709817
6296719 | 4962647 | 0.0460267 | 3503.72 | 5694579

# IfcBeam: 28_PBT_SF_staal_H-profiel (void):S355_HE300A (2)
Type - Pset_BeamCommon - IsExternal: no; LoadBearing: yes
Type - Pset_ProductRequirements - Category: Structural Framing
Type - Pset_ReinforcementBarPitchOfBeam - Description: HE300A
Type - Pset_Pieters - Breedte: 300 mm; Hoogte: 290 mm; Codering - NL-SfB: 28.11; Omschrijving NL-SfB: hoofddraagconstructies - kolommen en liggers, kolom-/liggerconstructies; Materiaal: 00_PBT_MAT_staal_S355; Materiaalkwaliteit: S355; Description: HE300A
Classification: 28.11 hoofddraagconstructies - kolommen en liggers, kolom-/liggerconstructies (Uniformat); Material: 00_PBT_MAT_staal_S355
Pset_BeamCommon - Slope: 0 deg; Reference: 28_PBT_SF_staal_H-profiel (void):S355_HE300A
Pset_QuantityTakeOff - Reference: 28_PBT_SF_staal_H-profiel (void):S355_HE300A
Pset_ReinforcementBarPitchOfBeam - Reference: 28_PBT_SF_staal_H-profiel (void):S355_HE300A
Pset_Pieters - Naamgeving element: 28_PBT_SF_staal_H-profiel (void): S355_HE300A; Fase: Nieuw
Name (28_PBT_SF_staal_H-profiel (void):S355_HE300A:...) | In | CrossSectionArea (mm2) | NetVolume (m3) | Span (mm) = Length (mm) | Bouwlaag | NetSurfaceArea (mm2)
2359844 | 01 eerste verdieping | 10480159 | 0.173104 | 6077 | Level: 01 eerste verdieping | 12721081
2831415 | 04 vierde verdieping | 10713527 | 0.178677 | 6202 | Level: 04 vierde verdieping | 13022817

# IfcBeam: 28_PBT_SF_staal_H-profiel (void):S355_HE300B (14)
Type - Pset_BeamCommon - IsExternal: no; LoadBearing: yes
Type - Pset_ProductRequirements - Category: Structural Framing
Type - Pset_ReinforcementBarPitchOfBeam - Description: HE300B
Type - Pset_Pieters - Breedte: 300 mm; Hoogte: 300 mm; Codering - NL-SfB: 28.11; Omschrijving NL-SfB: hoofddraagconstructies - kolommen en liggers, kolom-/liggerconstructies; Materiaal: 00_PBT_MAT_staal_S355; Materiaalkwaliteit: S355; Description: HE300B
Classification: 28.11 hoofddraagconstructies - kolommen en liggers, kolom-/liggerconstructies (Uniformat); Material: 00_PBT_MAT_staal_S355
Pset_BeamCommon - Slope: 0 deg; Reference: 28_PBT_SF_staal_H-profiel (void):S355_HE300B
Pset_QuantityTakeOff - Reference: 28_PBT_SF_staal_H-profiel (void):S355_HE300B
Pset_ReinforcementBarPitchOfBeam - Reference: 28_PBT_SF_staal_H-profiel (void):S355_HE300B
Pset_Pieters - Naamgeving element: 28_PBT_SF_staal_H-profiel (void): S355_HE300B; Fase: Nieuw
Name (28_PBT_SF_staal_H-profiel (void):S355_HE300B:...) | In | CrossSectionArea (mm2) | NetVolume (m3) | Span (mm) = Length (mm) | Bouwlaag | NetSurfaceArea (mm2)
2250741 | 03 derde verdieping | 16820825 | 0.179072 | 10915.4 | Level: 03 derde verdieping | 19119616
2250764 | 04 vierde verdieping | 10180350 | 0.177278 | 10920 | Level: 04 vierde verdieping | 18911200
2253620 | 01 eerste verdieping | 5880726 | 0.0562483 | 3773.06 | Level: 01 eerste verdieping | 6563416
2253622 | 01 eerste verdieping | 8655780 | 0.0827858 | 5553.16 | Level: 01 eerste verdieping | 9645925
2254036 | 02 tweede verdieping | 4018741 | 0.0524134 | 3528.52 | Level: 02 tweede verdieping | 6117978
2254038 | 02 tweede verdieping | 5788636 | 0.0828878 | 5560 | Level: 02 tweede verdieping | 9657768
2254425 | 03 derde verdieping | 13626570 | 0.131928 | 8849.56 | Level: 03 derde verdieping | 15354121
2254427 | 03 derde verdieping | 5788636 | 0.0828878 | 5560 | Level: 03 derde verdieping | 9657768
2254446 | 04 vierde verdieping | 13626570 | 0.131928 | 8849.56 | Level: 04 vierde verdieping | 15354121
2254448 | 04 vierde verdieping | 5788636 | 0.0828878 | 5560 | Level: 04 vierde verdieping | 9657768
2325871 | 01 eerste verdieping | 7713177 | 0.090629 | 4820 | Level: 01 eerste verdieping | 8846353
2329619 | 02 tweede verdieping | 8858420 | 0.199513 | 4820 | Level: 02 tweede verdieping | 11136840
2424006 | 03 derde verdieping | 27878491 | 0.773762 | 14843.8 | Level: 03 derde verdieping | 36969492
3872827 | 04 vierde verdieping | 6930883 | 0.184874 | 3524.5 | Level: 04 vierde verdieping | 8991826

# IfcBeam: 28_PBT_SF_staal_H-profiel (void):S355_HE360B (2)
In: 00 begane grond
Type - Pset_BeamCommon - IsExternal: no; LoadBearing: yes
Type - Pset_ProductRequirements - Category: Structural Framing
Type - Pset_ReinforcementBarPitchOfBeam - Description: HE360B
Type - Pset_Pieters - Breedte: 300 mm; Hoogte: 360 mm; Codering - NL-SfB: 28.11; Omschrijving NL-SfB: hoofddraagconstructies - kolommen en liggers, kolom-/liggerconstructies; Materiaal: 00_PBT_MAT_staal_S355; Materiaalkwaliteit: S355; Description: HE360B
Classification: 28.11 hoofddraagconstructies - kolommen en liggers, kolom-/liggerconstructies (Uniformat); Material: 00_PBT_MAT_staal_S355
Pset_BeamCommon - Slope: 0 deg; Reference: 28_PBT_SF_staal_H-profiel (void):S355_HE360B
Pset_QuantityTakeOff - Reference: 28_PBT_SF_staal_H-profiel (void):S355_HE360B
Pset_ReinforcementBarPitchOfBeam - Reference: 28_PBT_SF_staal_H-profiel (void):S355_HE360B
Pset_Pieters - Bouwlaag: Level: 00 begane grond; Naamgeving element: 28_PBT_SF_staal_H-profiel (void): S355_HE360B; Fase: Nieuw
Name (28_PBT_SF_staal_H-profiel (void):S355_HE360B:...) | CrossSectionArea (mm2) | NetVolume (m3) | Span (mm) = Length (mm) | NetSurfaceArea (mm2)
3466840 | 25304764 | 0.78944 | 12753.9 | 33629873
3467313 | 6023801 | 0.177651 | 2818.45 | 7856977

# IfcBeam: 28_PBT_SF_staal_H-profiel (void):S355_HE360M, 28_PBT_SF_staal_H-profiel (void):S355_HE360M:2449040
In: 03 derde verdieping
Type - Pset_BeamCommon - IsExternal: no; LoadBearing: yes
Type - Pset_ProductRequirements - Category: Structural Framing
Type - Pset_ReinforcementBarPitchOfBeam - Description: HE360M
Type - Pset_Pieters - Breedte: 308 mm; Hoogte: 395 mm; Codering - NL-SfB: 28.11; Omschrijving NL-SfB: hoofddraagconstructies - kolommen en liggers, kolom-/liggerconstructies; Materiaal: 00_PBT_MAT_staal_S355; Materiaalkwaliteit: S355; Description: HE360M
Classification: 28.11 hoofddraagconstructies - kolommen en liggers, kolom-/liggerconstructies (Uniformat); Material: 00_PBT_MAT_staal_S355
BaseQuantities - CrossSectionArea: 13275445 mm2; NetVolume: 0.321021 m3; Length: 7383.02 mm; NetSurfaceArea: 15227498 mm2
Pset_BeamCommon - Slope: 0 deg; Reference: 28_PBT_SF_staal_H-profiel (void):S355_HE360M; Span: 7383.02 mm
Pset_QuantityTakeOff - Reference: 28_PBT_SF_staal_H-profiel (void):S355_HE360M
Pset_ReinforcementBarPitchOfBeam - Reference: 28_PBT_SF_staal_H-profiel (void):S355_HE360M
Pset_Pieters - Bouwlaag: Level: 03 derde verdieping; Naamgeving element: 28_PBT_SF_staal_H-profiel (void): S355_HE360M; Fase: Nieuw

# IfcBeam: 28_PBT_SF_staal_H-profiel (void):S355_HE400B (3)
Type - Pset_BeamCommon - IsExternal: no; LoadBearing: yes
Type - Pset_ProductRequirements - Category: Structural Framing
Type - Pset_ReinforcementBarPitchOfBeam - Description: HE400B
Type - Pset_Pieters - Breedte: 300 mm; Hoogte: 400 mm; Codering - NL-SfB: 28.11; Omschrijving NL-SfB: hoofddraagconstructies - kolommen en liggers, kolom-/liggerconstructies; Materiaal: 00_PBT_MAT_staal_S355; Materiaalkwaliteit: S355; Description: HE400B
Classification: 28.11 hoofddraagconstructies - kolommen en liggers, kolom-/liggerconstructies (Uniformat); Material: 00_PBT_MAT_staal_S355
Pset_BeamCommon - Slope: 0 deg; Reference: 28_PBT_SF_staal_H-profiel (void):S355_HE400B
Pset_QuantityTakeOff - Reference: 28_PBT_SF_staal_H-profiel (void):S355_HE400B
Pset_ReinforcementBarPitchOfBeam - Reference: 28_PBT_SF_staal_H-profiel (void):S355_HE400B
Pset_Pieters - Naamgeving element: 28_PBT_SF_staal_H-profiel (void): S355_HE400B; Fase: Nieuw
Name (28_PBT_SF_staal_H-profiel (void):S355_HE400B:...) | In | CrossSectionArea (mm2) | NetVolume (m3) | Span (mm) = Length (mm) | Bouwlaag | NetSurfaceArea (mm2)
2257584 | 01 eerste verdieping | 45811047 | 1.02861 | 21300 | Level: 01 eerste verdieping_Offset1000 | 52901294
2257586 | 02 tweede verdieping | 49189996 | 1.39593 | 21300 | Level: 02 tweede verdieping | 60091992
4338958 | 03 derde verdieping | 1648625 | 0.0464464 | 695 | Level: 03 derde verdieping | 1996649

# IfcBeam: 28_PBT_SF_staal_H-profiel:S355_HE100A (27)
Type - Pset_BeamCommon - IsExternal: no; LoadBearing: yes
Type - Pset_ProductRequirements - Category: Structural Framing
Type - Pset_ReinforcementBarPitchOfBeam - Description: HE100A
Type - Pset_Pieters - Breedte: 100 mm; Hoogte: 96 mm; Codering - NL-SfB: 28.11; Omschrijving NL-SfB: hoofddraagconstructies - kolommen en liggers, kolom-/liggerconstructies; Materiaal: 00_PBT_MAT_staal_S355; Materiaalkwaliteit: S355; Description: HE100A
Classification: 28.11 hoofddraagconstructies - kolommen en liggers, kolom-/liggerconstructies (Uniformat); Material: 00_PBT_MAT_staal_S355
Pset_BeamCommon - Slope: 0 deg; Reference: 28_PBT_SF_staal_H-profiel:S355_HE100A
Pset_QuantityTakeOff - Reference: 28_PBT_SF_staal_H-profiel:S355_HE100A
Pset_ReinforcementBarPitchOfBeam - Reference: 28_PBT_SF_staal_H-profiel:S355_HE100A
Pset_Pieters - Naamgeving element: 28_PBT_SF_staal_H-profiel: S355_HE100A; Fase: Nieuw
Name (28_PBT_SF_staal_H-profiel:S355_HE100A:...) | In | CrossSectionArea (mm2) | NetVolume (m3) | Span (mm) = Length (mm) | Bouwlaag | NetSurfaceArea (mm2)
4328980 | 06 zesde verdieping | 1191422 | 0.00899764 | 4236.92 | Level: 06 zesde verdieping | 2382845
4329391 | 06 zesde verdieping | 805625 | 0.00607889 | 2862.5 | Level: 06 zesde verdieping | 1611250
4329404 | 06 zesde verdieping | 805789 | 0.00608013 | 2863.08 | Level: 06 zesde verdieping | 1611577
4329417 | 06 zesde verdieping | 960290 | 0.00724901 | 3413.5 | Level: 06 zesde verdieping | 1920580
4329430 | 06 zesde verdieping | 765345 | 0.00577415 | 2719 | Level: 06 zesde verdieping | 1530689
4329443 | 06 zesde verdieping | 819678 | 0.0061852 | 2912.56 | Level: 06 zesde verdieping | 1639356
4330039 | 05 vijfde verdieping | 805625 | 0.00607889 | 2862.5 | Level: 05 vijfde verdieping | 1611250
4330041 | 05 vijfde verdieping | 805789 | 0.00608013 | 2863.08 | Level: 05 vijfde verdieping | 1611577
4404428 | 05 vijfde verdieping | 1969123 | 0.0148813 | 7007.5 | Level: 05 vijfde verdieping | 3938245
4404779 | 05 vijfde verdieping | 1659816 | 0.0125413 | 5905.58 | Level: 05 vijfde verdieping | 3319631
4404820 | 05 vijfde verdieping | 1949310 | 0.0147314 | 6936.92 | Level: 05 vijfde verdieping | 3898620
4406057 | 06 zesde verdieping | 805789 | 0.00608013 | 2863.08 | Level: 06 zesde verdieping | 1611577
4407670 | 06 zesde verdieping | 805789 | 0.00608013 | 2863.08 | Level: 06 zesde verdieping | 1611577
4449139 | 06 zesde verdieping | 960290 | 0.00724901 | 3413.5 | Level: 06 zesde verdieping | 1920580
4449153 | 06 zesde verdieping | 765345 | 0.00577415 | 2719 | Level: 06 zesde verdieping | 1530689
4449167 | 06 zesde verdieping | 788722 | 0.00595101 | 2802.28 | Level: 06 zesde verdieping | 1577444
4449185 | 06 zesde verdieping | 663170 | 0.00500115 | 2355 | Level: 06 zesde verdieping | 1326340
4449199 | 06 zesde verdieping | 709485 | 0.00535154 | 2520 | Level: 06 zesde verdieping | 1418971
4449213 | 06 zesde verdieping | 1191422 | 0.00899764 | 4236.92 | Level: 06 zesde verdieping | 2382845
4790867 | 06 zesde verdieping | 805789 | 0.00608013 | 2863.08 | Level: 06 zesde verdieping | 1611577
4790869 | 06 zesde verdieping | 805789 | 0.00608013 | 2863.08 | Level: 06 zesde verdieping | 1611577
4790871 | 06 zesde verdieping | 960290 | 0.00724901 | 3413.5 | Level: 06 zesde verdieping | 1920580
4790873 | 06 zesde verdieping | 765345 | 0.00577415 | 2719 | Level: 06 zesde verdieping | 1530689
4790875 | 06 zesde verdieping | 788722 | 0.00595101 | 2802.28 | Level: 06 zesde verdieping | 1577444
4790877 | 06 zesde verdieping | 663170 | 0.00500115 | 2355 | Level: 06 zesde verdieping | 1326340
4790879 | 06 zesde verdieping | 709485 | 0.00535154 | 2520 | Level: 06 zesde verdieping | 1418971
4790881 | 06 zesde verdieping | 1191422 | 0.00899764 | 4236.92 | Level: 06 zesde verdieping | 2382845

# IfcBeam: 28_PBT_SF_staal_H-profiel:S355_HE140A (54)
Type - Pset_BeamCommon - IsExternal: no; LoadBearing: yes
Type - Pset_ProductRequirements - Category: Structural Framing
Type - Pset_ReinforcementBarPitchOfBeam - Description: HE140A
Type - Pset_Pieters - Breedte: 140 mm; Hoogte: 133 mm; Codering - NL-SfB: 28.11; Omschrijving NL-SfB: hoofddraagconstructies - kolommen en liggers, kolom-/liggerconstructies; Materiaal: 00_PBT_MAT_staal_S355; Materiaalkwaliteit: S355; Description: HE140A
Classification: 28.11 hoofddraagconstructies - kolommen en liggers, kolom-/liggerconstructies (Uniformat); Material: 00_PBT_MAT_staal_S355
Pset_BeamCommon - Reference: 28_PBT_SF_staal_H-profiel:S355_HE140A
Pset_QuantityTakeOff - Reference: 28_PBT_SF_staal_H-profiel:S355_HE140A
Pset_ReinforcementBarPitchOfBeam - Reference: 28_PBT_SF_staal_H-profiel:S355_HE140A
Pset_Pieters - Naamgeving element: 28_PBT_SF_staal_H-profiel: S355_HE140A; Fase: Nieuw
Name (28_PBT_SF_staal_H-profiel:S355_HE140A:...) | In | CrossSectionArea (mm2) | NetVolume (m3) | Slope (deg) | Span (mm) = Length (mm) | Bouwlaag | NetSurfaceArea (mm2)
2273384 | 02 tweede verdieping | 1760648 | 0.0139009 | 0 | 4424.75 | Level: 02 tweede verdieping | 3521297
2273530 | 02 tweede verdieping | 1476750 | 0.0116554 | 0 | 3710 | Level: 02 tweede verdieping | 2953501
2348000 | 02 tweede verdieping | 1679322 | 0.0132577 | 0 | 4220 | Level: 02 tweede verdieping | 3358644
2348002 | 02 tweede verdieping | 2279093 | 0.0180015 | 0 | 5730 | Level: 02 tweede verdieping | 4558185
2348083 | 02 tweede verdieping | 1679322 | 0.0132577 | 0 | 4220 | Level: 02 tweede verdieping | 3358644
2348085 | 02 tweede verdieping | 2279093 | 0.0180015 | 0 | 5730 | Level: 02 tweede verdieping | 4558185
2478320 | 04 vierde verdieping | 1076471 | 0.00848945 | 0 | 2702.24 | Level: 04 vierde verdieping | 2152942
2478487 | 04 vierde verdieping | 973136 | 0.00767212 | 0 | 2442.08 | Level: 04 vierde verdieping | 1946271
3394576 | 04 vierde verdieping | 898627 | 0.0070828 | 0 | 2254.5 | Level: 04 vierde verdieping | 1797254
3394630 | 04 vierde verdieping | 1264116 | 0.00997362 | 0 | 3174.67 | Level: 04 vierde verdieping | 2528232
3425335 | -1 kelder | 587024 | 0.00461822 | 0 | 1510 | Level: -1 kelder | 1174049
3425922 | -1 kelder | 602912 | 0.00474386 | 0 | 1510 | Level: -1 kelder | 1205825
3425946 | -1 kelder | 602912 | 0.00474386 | 0 | 1510 | Level: -1 kelder | 1205825
3747916 | 00 begane grond | 2216454 | 0.0175061 | 0 | 5710 | Level: 01 bk ruwe vloer bwd midden | 4432909
3747920 | 00 begane grond | 356967 | 0.00279856 | 90 | 1140 | Level: 01 bk ruwe vloer bwd midden | 713933
3747924 | 00 begane grond | 359866 | 0.0028215 | 90 | 1140 | Level: 01 bk ruwe vloer bwd midden | 719732
3747926 | 00 begane grond | 665375 | 0.00521248 | 31.5043 | 2181.56 | Level: 01 bk ruwe vloer bwd midden | 1330750
3747930 | 00 begane grond | 665375 | 0.00521248 | 31.5043 | 2181.56 | Level: 01 bk ruwe vloer bwd midden | 1330750
3747932 | 00 begane grond | 662654 | 0.00519107 | 31.642 | 2173.04 | Level: 01 bk ruwe vloer bwd midden | 1325308
3813184 | 03 derde verdieping | 2255261 | 0.017813 | 0 | 5670 | Level: 03 derde verdieping | 4510521
3813216 | 03 derde verdieping | 1734930 | 0.0136975 | 0 | 4360 | Level: 03 derde verdieping | 3469860
3813570 | 03 derde verdieping | 2255261 | 0.017813 | 0 | 5670 | Level: 03 derde verdieping | 4510521
3813573 | 03 derde verdieping | 1734930 | 0.0136975 | 0 | 4360 | Level: 03 derde verdieping | 3469860
3823307 | 06 zesde verdieping | 519501 | 0.00408412 | 0 | 1300 | Level: 06 zesde verdieping | 1039001
3823484 | 06 zesde verdieping | 519501 | 0.00408412 | 0 | 1300 | Level: 06 zesde verdieping | 1039001
3823530 | 06 zesde verdieping | 519501 | 0.00408412 | 0 | 1300 | Level: 06 zesde verdieping | 1039001
3823552 | 06 zesde verdieping | 519501 | 0.00408412 | 0 | 1300 | Level: 06 zesde verdieping | 1039001
3824672 | 06 zesde verdieping | 519501 | 0.00408412 | 0 | 1300 | Level: 06 zesde verdieping | 1039001
3824676 | 06 zesde verdieping | 519501 | 0.00408412 | 0 | 1300 | Level: 06 zesde verdieping | 1039001
3824680 | 06 zesde verdieping | 519501 | 0.00408412 | 0 | 1300 | Level: 06 zesde verdieping | 1039001
3824684 | 06 zesde verdieping | 519501 | 0.00408412 | 0 | 1300 | Level: 06 zesde verdieping | 1039001
3824688 | 06 zesde verdieping | 519501 | 0.00408412 | 0 | 1300 | Level: 06 zesde verdieping | 1039001
3825958 | 06 zesde verdieping | 519501 | 0.00408412 | 0 | 1300 | Level: 06 zesde verdieping | 1039001
3826049 | 06 zesde verdieping | 519501 | 0.00408412 | 0 | 1300 | Level: 06 zesde verdieping | 1039001
3841884 | 04 vierde verdieping | 1220622 | 0.00962961 | 0 | 3165.16 | Level: 04 vierde verdieping | 2441244
3848743 | 04 vierde verdieping | 1076471 | 0.00848945 | 0 | 2702.24 | Level: 04 vierde verdieping | 2152942
3848745 | 04 vierde verdieping | 400341 | 0.00314163 | 0 | 1100 | Level: 04 vierde verdieping | 800682
3848747 | 04 vierde verdieping | 857120 | 0.0067545 | 0 | 2150 | Level: 04 vierde verdieping | 1714240
3848751 | 04 vierde verdieping | 898627 | 0.0070828 | 0 | 2254.5 | Level: 04 vierde verdieping | 1797254
3848753 | 04 vierde verdieping | 1264116 | 0.00997362 | 0 | 3174.67 | Level: 04 vierde verdieping | 2528232
3849385 | 03 derde verdieping | 1076471 | 0.00848945 | 0 | 2702.24 | Level: 03 derde verdieping | 2152942
3849387 | 03 derde verdieping | 973136 | 0.00767212 | 0 | 2442.08 | Level: 03 derde verdieping | 1946271
3849389 | 03 derde verdieping | 1333759 | 0.0105245 | 0 | 3350 | Level: 03 derde verdieping | 2667517
3849393 | 03 derde verdieping | 898627 | 0.0070828 | 0 | 2254.5 | Level: 03 derde verdieping | 1797254
3849395 | 03 derde verdieping | 1264116 | 0.00997362 | 0 | 3174.67 | Level: 03 derde verdieping | 2528232
3849397 | 03 derde verdieping | 1220622 | 0.00962961 | 0 | 3165.16 | Level: 03 derde verdieping | 2441244
4236214 | 06 zesde verdieping | 519501 | 0.00408412 | 0 | 1300 | Level: 06 zesde verdieping | 1039001
4236497 | 06 zesde verdieping | 519501 | 0.00408412 | 0 | 1300 | Level: 06 zesde verdieping | 1039001
4236540 | 06 zesde verdieping | 519501 | 0.00408412 | 0 | 1300 | Level: 06 zesde verdieping | 1039001
4236642 | 06 zesde verdieping | 519501 | 0.00408412 | 0 | 1300 | Level: 06 zesde verdieping | 1039001
4236646 | 06 zesde verdieping | 519501 | 0.00408412 | 0 | 1300 | Level: 06 zesde verdieping | 1039001
4236650 | 06 zesde verdieping | 519501 | 0.00408412 | 0 | 1300 | Level: 06 zesde verdieping | 1039001
4391016 | 04 vierde verdieping | 1220622 | 0.00962961 | 0 | 3065.16 | Level: 04 vierde verdieping | 2441244
6291646 | 04 vierde verdieping | 973136 | 0.00767212 | 0 | 2542.08 | Level: 04 vierde verdieping | 1946271

# IfcBeam: 28_PBT_SF_staal_H-profiel:S355_HE160A (9)
Type - Pset_BeamCommon - IsExternal: no; LoadBearing: yes
Type - Pset_ProductRequirements - Category: Structural Framing
Type - Pset_ReinforcementBarPitchOfBeam - Description: HE160A
Type - Pset_Pieters - Breedte: 160 mm; Hoogte: 152 mm; Codering - NL-SfB: 28.11; Omschrijving NL-SfB: hoofddraagconstructies - kolommen en liggers, kolom-/liggerconstructies; Materiaal: 00_PBT_MAT_staal_S355; Materiaalkwaliteit: S355; Description: HE160A
Classification: 28.11 hoofddraagconstructies - kolommen en liggers, kolom-/liggerconstructies (Uniformat); Material: 00_PBT_MAT_staal_S355
Pset_BeamCommon - Slope: 0 deg; Reference: 28_PBT_SF_staal_H-profiel:S355_HE160A
Pset_QuantityTakeOff - Reference: 28_PBT_SF_staal_H-profiel:S355_HE160A
Pset_ReinforcementBarPitchOfBeam - Reference: 28_PBT_SF_staal_H-profiel:S355_HE160A
Pset_Pieters - Naamgeving element: 28_PBT_SF_staal_H-profiel: S355_HE160A; Fase: Nieuw
Name (28_PBT_SF_staal_H-profiel:S355_HE160A:...) | In | CrossSectionArea (mm2) | NetVolume (m3) | Span (mm) = Length (mm) | Bouwlaag | NetSurfaceArea (mm2)
2679878 | 06 zesde verdieping | 2092589 | 0.0178721 | 4925 | Level: 06 zesde verdieping | 4185179
2680103 | 06 zesde verdieping | 2133560 | 0.0182227 | 4700 | Level: 06 zesde verdieping | 4267119
2680262 | 06 zesde verdieping | 2133560 | 0.0182227 | 4700 | Level: 06 zesde verdieping | 4267119
2680285 | 06 zesde verdieping | 2133560 | 0.0182227 | 4700 | Level: 06 zesde verdieping | 4267119
2680322 | 06 zesde verdieping | 2246840 | 0.019192 | 4950 | Level: 06 zesde verdieping | 4493681
4544066 | 04 vierde verdieping | 1471999 | 0.012562 | 3240 | Level: 04 vierde verdieping | 2943997
4544069 | 04 vierde verdieping | 1714647 | 0.0146383 | 3775.5 | Level: 04 vierde verdieping | 3429293
4544528 | 04 vierde verdieping | 1714647 | 0.0146383 | 3775.5 | Level: 04 vierde verdieping | 3429293
4544576 | 04 vierde verdieping | 1471999 | 0.012562 | 3240 | Level: 04 vierde verdieping | 2943997

# IfcBeam: 28_PBT_SF_staal_H-profiel:S355_HE160A(Z) (3)
Type - Pset_BeamCommon - IsExternal: no; LoadBearing: yes
Type - Pset_ProductRequirements - Category: Structural Framing
Type - Pset_ReinforcementBarPitchOfBeam - Description: HE160A(Z)
Type - Pset_Pieters - Breedte: 160 mm; Hoogte: 152 mm; Codering - NL-SfB: 28.11; Omschrijving NL-SfB: hoofddraagconstructies - kolommen en liggers, kolom-/liggerconstructies; Materiaal: 00_PBT_MAT_staal_S355; Materiaalkwaliteit: S355; Description: HE160A(Z)
Classification: 28.11 hoofddraagconstructies - kolommen en liggers, kolom-/liggerconstructies (Uniformat); Material: 00_PBT_MAT_staal_S355
Pset_BeamCommon - Slope: 0 deg; Reference: 28_PBT_SF_staal_H-profiel:S355_HE160A(Z)
Pset_QuantityTakeOff - Reference: 28_PBT_SF_staal_H-profiel:S355_HE160A(Z)
Pset_ReinforcementBarPitchOfBeam - Reference: 28_PBT_SF_staal_H-profiel:S355_HE160A(Z)
Pset_Pieters - Naamgeving element: 28_PBT_SF_staal_H-profiel: S355_HE160A(Z); Fase: Nieuw
Name (28_PBT_SF_staal_H-profiel:S355_HE160A(Z):...) | In | CrossSectionArea (mm2) | NetVolume (m3) | Span (mm) = Length (mm) | Bouwlaag | NetSurfaceArea (mm2)
5911919 | 02 tweede verdieping | 2004869 | 0.0171215 | 4415.99 | Level: 02 tweede verdieping | 4009737
5912889 | 03 derde verdieping | 2056978 | 0.0175674 | 4530.99 | Level: 03 derde verdieping | 4113956
5912956 | 04 vierde verdieping | 2054599 | 0.0175471 | 4525.74 | Level: 04 vierde verdieping | 4109198

# IfcBeam: 28_PBT_SF_staal_H-profiel:S355_HE180A (112)
Type - Pset_BeamCommon - IsExternal: no; LoadBearing: yes
Type - Pset_ProductRequirements - Category: Structural Framing
Type - Pset_ReinforcementBarPitchOfBeam - Description: HE180A
Type - Pset_Pieters - Breedte: 180 mm; Hoogte: 171 mm; Codering - NL-SfB: 28.11; Omschrijving NL-SfB: hoofddraagconstructies - kolommen en liggers, kolom-/liggerconstructies; Materiaal: 00_PBT_MAT_staal_S355; Materiaalkwaliteit: S355; Description: HE180A
Classification: 28.11 hoofddraagconstructies - kolommen en liggers, kolom-/liggerconstructies (Uniformat); Material: 00_PBT_MAT_staal_S355
Pset_BeamCommon - Reference: 28_PBT_SF_staal_H-profiel:S355_HE180A
Pset_QuantityTakeOff - Reference: 28_PBT_SF_staal_H-profiel:S355_HE180A
Pset_ReinforcementBarPitchOfBeam - Reference: 28_PBT_SF_staal_H-profiel:S355_HE180A
Pset_Pieters - Naamgeving element: 28_PBT_SF_staal_H-profiel: S355_HE180A; Fase: Nieuw
Name (28_PBT_SF_staal_H-profiel:S355_HE180A:...) | In | CrossSectionArea (mm2) | NetVolume (m3) | Slope (deg) | Span (mm) = Length (mm) | Bouwlaag | NetSurfaceArea (mm2)
2210823 | 04 vierde verdieping | 1329543 | 0.011708 | 90 | 2820 | Level: 04 vierde verdieping | 2659087
2210825 | 04 vierde verdieping | 1329543 | 0.011708 | 90 | 2820 | Level: 04 vierde verdieping | 2659087
2210827 | 04 vierde verdieping | 1323039 | 0.0116505 | 90 | 2820 | Level: 04 vierde verdieping | 2646079
2210829 | 04 vierde verdieping | 1323039 | 0.0116505 | 90 | 2820 | Level: 04 vierde verdieping | 2646079
2210831 | 04 vierde verdieping | 1323039 | 0.0116505 | 90 | 2820 | Level: 04 vierde verdieping | 2646079
2210833 | 04 vierde verdieping | 1323039 | 0.0116505 | 90 | 2820 | Level: 04 vierde verdieping | 2646079
2210835 | 04 vierde verdieping | 1323039 | 0.0116505 | 90 | 2820 | Level: 04 vierde verdieping | 2646079
2210837 | 04 vierde verdieping | 1323039 | 0.0116505 | 90 | 2820 | Level: 04 vierde verdieping | 2646079
2210839 | 04 vierde verdieping | 1323039 | 0.0116505 | 90 | 2820 | Level: 04 vierde verdieping | 2646079
2210841 | 04 vierde verdieping | 1323039 | 0.0116505 | 90 | 2820 | Level: 04 vierde verdieping | 2646079
2210843 | 04 vierde verdieping | 1329543 | 0.011708 | 90 | 2820 | Level: 04 vierde verdieping | 2659087
2210845 | 04 vierde verdieping | 1229233 | 0.0107411 | 70.5472 | 2990.72 | Level: 04 vierde verdieping | 2458466
2210847 | 04 vierde verdieping | 1547881 | 0.0135958 | 54.7633 | 3452.6 | Level: 04 vierde verdieping | 3095762
2210849 | 04 vierde verdieping | 1524353 | 0.0133934 | 54.7633 | 3452.6 | Level: 04 vierde verdieping | 3048705
2210851 | 04 vierde verdieping | 1524353 | 0.0133934 | 54.7633 | 3452.6 | Level: 04 vierde verdieping | 3048705
2210853 | 04 vierde verdieping | 1524353 | 0.0133934 | 54.7633 | 3452.6 | Level: 04 vierde verdieping | 3048705
2210855 | 04 vierde verdieping | 1524352 | 0.0133934 | 54.7633 | 3452.6 | Level: 04 vierde verdieping | 3048705
2210857 | 04 vierde verdieping | 1524352 | 0.0133934 | 54.7633 | 3452.6 | Level: 04 vierde verdieping | 3048705
2210859 | 04 vierde verdieping | 1524352 | 0.0133934 | 54.7633 | 3452.6 | Level: 04 vierde verdieping | 3048705
2210861 | 04 vierde verdieping | 1524352 | 0.0133934 | 54.7633 | 3452.6 | Level: 04 vierde verdieping | 3048705
2210863 | 04 vierde verdieping | 1189813 | 0.0104058 | 70.5472 | 2990.72 | Level: 04 vierde verdieping | 2379625
2212789 | 04 vierde verdieping | 1323039 | 0.0116505 | 90 | 2820 | Level: 04 vierde verdieping | 2646079
2212791 | 04 vierde verdieping | 1323039 | 0.0116505 | 90 | 2820 | Level: 04 vierde verdieping | 2646079
2212793 | 04 vierde verdieping | 1323039 | 0.0116505 | 90 | 2820 | Level: 04 vierde verdieping | 2646079
2212795 | 04 vierde verdieping | 1323039 | 0.0116505 | 90 | 2820 | Level: 04 vierde verdieping | 2646079
2212797 | 04 vierde verdieping | 1323039 | 0.0116505 | 90 | 2820 | Level: 04 vierde verdieping | 2646079
2212799 | 04 vierde verdieping | 1323039 | 0.0116505 | 90 | 2820 | Level: 04 vierde verdieping | 2646079
2212801 | 04 vierde verdieping | 1323039 | 0.0116505 | 90 | 2820 | Level: 04 vierde verdieping | 2646079
2212803 | 04 vierde verdieping | 1323039 | 0.0116505 | 90 | 2820 | Level: 04 vierde verdieping | 2646079
2212805 | 04 vierde verdieping | 1323039 | 0.0116505 | 90 | 2820 | Level: 04 vierde verdieping | 2646079
2212807 | 04 vierde verdieping | 1323039 | 0.0116505 | 90 | 2820 | Level: 04 vierde verdieping | 2646079
2212809 | 04 vierde verdieping | 1323039 | 0.0116505 | 90 | 2820 | Level: 04 vierde verdieping | 2646079
2212811 | 04 vierde verdieping | 1189812 | 0.0104058 | 70.5472 | 2990.72 | Level: 04 vierde verdieping | 2379624
2212813 | 04 vierde verdieping | 1524353 | 0.0133934 | 54.7633 | 3452.6 | Level: 04 vierde verdieping | 3048705
2212815 | 04 vierde verdieping | 1524353 | 0.0133934 | 54.7633 | 3452.6 | Level: 04 vierde verdieping | 3048705
2212817 | 04 vierde verdieping | 1524353 | 0.0133934 | 54.7633 | 3452.6 | Level: 04 vierde verdieping | 3048705
2212819 | 04 vierde verdieping | 1524353 | 0.0133934 | 54.7633 | 3452.6 | Level: 04 vierde verdieping | 3048705
2212821 | 04 vierde verdieping | 1524352 | 0.0133934 | 54.7633 | 3452.6 | Level: 04 vierde verdieping | 3048705
2212823 | 04 vierde verdieping | 1524352 | 0.0133934 | 54.7633 | 3452.6 | Level: 04 vierde verdieping | 3048705
2212825 | 04 vierde verdieping | 1524352 | 0.0133934 | 54.7633 | 3452.6 | Level: 04 vierde verdieping | 3048705
2212827 | 04 vierde verdieping | 1524352 | 0.0133934 | 54.7633 | 3452.6 | Level: 04 vierde verdieping | 3048705
2212829 | 04 vierde verdieping | 1189813 | 0.0104058 | 70.5472 | 2990.72 | Level: 04 vierde verdieping | 2379625
2212914 | 04 vierde verdieping | 1323039 | 0.0116505 | 90 | 2820 | Level: 04 vierde verdieping | 2646079
2212916 | 04 vierde verdieping | 1323039 | 0.0116505 | 90 | 2820 | Level: 04 vierde verdieping | 2646079
2212918 | 04 vierde verdieping | 1323039 | 0.0116505 | 90 | 2820 | Level: 04 vierde verdieping | 2646079
2212920 | 04 vierde verdieping | 1323039 | 0.0116505 | 90 | 2820 | Level: 04 vierde verdieping | 2646079
2212922 | 04 vierde verdieping | 1323039 | 0.0116505 | 90 | 2820 | Level: 04 vierde verdieping | 2646079
2212924 | 04 vierde verdieping | 1323039 | 0.0116505 | 90 | 2820 | Level: 04 vierde verdieping | 2646079
2212926 | 04 vierde verdieping | 1323039 | 0.0116505 | 90 | 2820 | Level: 04 vierde verdieping | 2646079
2212928 | 04 vierde verdieping | 1323039 | 0.0116505 | 90 | 2820 | Level: 04 vierde verdieping | 2646079
2212930 | 04 vierde verdieping | 1323039 | 0.0116505 | 90 | 2820 | Level: 04 vierde verdieping | 2646079
2212932 | 04 vierde verdieping | 1323039 | 0.0116505 | 90 | 2820 | Level: 04 vierde verdieping | 2646079
2212934 | 04 vierde verdieping | 1323039 | 0.0116505 | 90 | 2820 | Level: 04 vierde verdieping | 2646079
2212936 | 04 vierde verdieping | 1189812 | 0.0104058 | 70.5472 | 2990.72 | Level: 04 vierde verdieping | 2379624
2212938 | 04 vierde verdieping | 1524353 | 0.0133934 | 54.7633 | 3452.6 | Level: 04 vierde verdieping | 3048705
2212940 | 04 vierde verdieping | 1524353 | 0.0133934 | 54.7633 | 3452.6 | Level: 04 vierde verdieping | 3048705
2212942 | 04 vierde verdieping | 1524353 | 0.0133934 | 54.7633 | 3452.6 | Level: 04 vierde verdieping | 3048705
2212944 | 04 vierde verdieping | 1524353 | 0.0133934 | 54.7633 | 3452.6 | Level: 04 vierde verdieping | 3048705
2212946 | 04 vierde verdieping | 1524352 | 0.0133934 | 54.7633 | 3452.6 | Level: 04 vierde verdieping | 3048705
2212948 | 04 vierde verdieping | 1524352 | 0.0133934 | 54.7633 | 3452.6 | Level: 04 vierde verdieping | 3048705
2212950 | 04 vierde verdieping | 1524352 | 0.0133934 | 54.7633 | 3452.6 | Level: 04 vierde verdieping | 3048705
2212952 | 04 vierde verdieping | 1524352 | 0.0133934 | 54.7633 | 3452.6 | Level: 04 vierde verdieping | 3048705
2212954 | 04 vierde verdieping | 1189813 | 0.0104058 | 70.5472 | 2990.72 | Level: 04 vierde verdieping | 2379625
2565152 | 04 vierde verdieping | 1072296 | 0.00943491 | 21.3 | 2084.99 | Level: 04 vierde verdieping | 2144592
2565344 | 04 vierde verdieping | 1008288 | 0.00886933 | 21.3 | 1960 | Level: 04 vierde verdieping | 2016576
2566549 | 04 vierde verdieping | 1008288 | 0.00886933 | 21.3 | 1960 | Level: 04 vierde verdieping | 2016576
3602741 | 02 tweede verdieping | 1230857 | 0.010836 | 90 | 2740 | Level: 03 ok ruwe vloer | 2461714
3602743 | 02 tweede verdieping | 1230857 | 0.010836 | 90 | 2740 | Level: 03 ok ruwe vloer | 2461714
3602745 | 02 tweede verdieping | 1230857 | 0.010836 | 90 | 2740 | Level: 03 ok ruwe vloer | 2461714
3602747 | 02 tweede verdieping | 1230857 | 0.010836 | 90 | 2740 | Level: 03 ok ruwe vloer | 2461714
3602749 | 02 tweede verdieping | 1312797 | 0.01156 | 90 | 2820 | Level: 03 ok ruwe vloer | 2625594
3602751 | 02 tweede verdieping | 1312797 | 0.01156 | 90 | 2820 | Level: 03 ok ruwe vloer | 2625594
3602753 | 02 tweede verdieping | 1312797 | 0.01156 | 90 | 2820 | Level: 03 ok ruwe vloer | 2625594
3602755 | 02 tweede verdieping | 1312797 | 0.01156 | 90 | 2820 | Level: 03 ok ruwe vloer | 2625594
3602757 | 02 tweede verdieping | 1312797 | 0.01156 | 90 | 2820 | Level: 03 ok ruwe vloer | 2625594
3602759 | 02 tweede verdieping | 1312797 | 0.01156 | 90 | 2820 | Level: 03 ok ruwe vloer | 2625594
3602761 | 02 tweede verdieping | 1312797 | 0.01156 | 90 | 2820 | Level: 03 ok ruwe vloer | 2625594
3602763 | 02 tweede verdieping | 1517508 | 0.0133348 | 54.7633 | 3452.6 | Level: 03 ok ruwe vloer | 3035015
3602765 | 02 tweede verdieping | 1517507 | 0.0133348 | 54.7633 | 3452.6 | Level: 03 ok ruwe vloer | 3035015
3602767 | 02 tweede verdieping | 1517507 | 0.0133348 | 54.7633 | 3452.6 | Level: 03 ok ruwe vloer | 3035015
3602769 | 02 tweede verdieping | 1517507 | 0.0133348 | 54.7633 | 3452.6 | Level: 03 ok ruwe vloer | 3035015
3602771 | 02 tweede verdieping | 1517507 | 0.0133348 | 54.7633 | 3452.6 | Level: 03 ok ruwe vloer | 3035015
3602773 | 02 tweede verdieping | 1185474 | 0.0103646 | 70.5472 | 2990.72 | Level: 03 ok ruwe vloer | 2370949
3611471 | 02 tweede verdieping | 1134607 | 0.00990957 | 70.0236 | 2915.41 | Level: 03 ok ruwe vloer | 2269214
3611473 | 02 tweede verdieping | 1447331 | 0.0127331 | 53.9826 | 3387.57 | Level: 03 ok ruwe vloer | 2894663
3611475 | 02 tweede verdieping | 1447331 | 0.0127331 | 53.9826 | 3387.57 | Level: 03 ok ruwe vloer | 2894663
3611477 | 02 tweede verdieping | 1447331 | 0.0127331 | 53.9826 | 3387.57 | Level: 03 ok ruwe vloer | 2894663
3819962 | 04 vierde verdieping | 772711 | 0.00678775 | 0 | 1500 | Level: 04 vierde verdieping | 1545422
3820281 | 04 vierde verdieping | 772711 | 0.00678775 | 0 | 1500 | Level: 04 vierde verdieping | 1545422
3820340 | 04 vierde verdieping | 772711 | 0.00678775 | 0 | 1500 | Level: 04 vierde verdieping | 1545422
3820381 | 04 vierde verdieping | 772711 | 0.00678775 | 0 | 1500 | Level: 04 vierde verdieping | 1545422
3820386 | 04 vierde verdieping | 772711 | 0.00678775 | 0 | 1500 | Level: 04 vierde verdieping | 1545422
3820419 | 04 vierde verdieping | 772711 | 0.00678775 | 0 | 1500 | Level: 04 vierde verdieping | 1545422
3820424 | 04 vierde verdieping | 772711 | 0.00678775 | 0 | 1500 | Level: 04 vierde verdieping | 1545422
3820457 | 04 vierde verdieping | 772711 | 0.00678775 | 0 | 1500 | Level: 04 vierde verdieping | 1545422
3820462 | 04 vierde verdieping | 772711 | 0.00678775 | 0 | 1500 | Level: 04 vierde verdieping | 1545422
3820495 | 04 vierde verdieping | 772711 | 0.00678775 | 0 | 1500 | Level: 04 vierde verdieping | 1545422
3820500 | 04 vierde verdieping | 772711 | 0.00678775 | 0 | 1500 | Level: 04 vierde verdieping | 1545422
3820533 | 04 vierde verdieping | 772711 | 0.00678775 | 0 | 1500 | Level: 04 vierde verdieping | 1545422
3820538 | 04 vierde verdieping | 772711 | 0.00678775 | 0 | 1500 | Level: 04 vierde verdieping | 1545422
3820571 | 04 vierde verdieping | 772711 | 0.00678775 | 0 | 1500 | Level: 04 vierde verdieping | 1545422
3820576 | 04 vierde verdieping | 772711 | 0.00678775 | 0 | 1500 | Level: 04 vierde verdieping | 1545422
3822362 | 06 zesde verdieping | 772711 | 0.00678775 | 0 | 1500 | Level: 06 zesde verdieping | 1545422
3823574 | 06 zesde verdieping | 772711 | 0.00678775 | 0 | 1500 | Level: 06 zesde verdieping | 1545422
3824474 | 06 zesde verdieping | 772711 | 0.00678775 | 0 | 1500 | Level: 06 zesde verdieping | 1545422
3824494 | 06 zesde verdieping | 772711 | 0.00678775 | 0 | 1500 | Level: 06 zesde verdieping | 1545422
3824559 | 06 zesde verdieping | 772711 | 0.00678775 | 0 | 1500 | Level: 06 zesde verdieping | 1545422
3824567 | 06 zesde verdieping | 772711 | 0.00678775 | 0 | 1500 | Level: 06 zesde verdieping | 1545422
3824571 | 06 zesde verdieping | 772711 | 0.00678775 | 0 | 1500 | Level: 06 zesde verdieping | 1545422
3824668 | 06 zesde verdieping | 772711 | 0.00678775 | 0 | 1500 | Level: 06 zesde verdieping | 1545422
3824692 | 06 zesde verdieping | 772711 | 0.00678775 | 0 | 1500 | Level: 06 zesde verdieping | 1545422
3826089 | 06 zesde verdieping | 772711 | 0.00678775 | 0 | 1500 | Level: 06 zesde verdieping | 1545422

# IfcBeam: 28_PBT_SF_staal_H-profiel:S355_HE200A (97)
Type - Pset_BeamCommon - IsExternal: no; LoadBearing: yes
Type - Pset_ProductRequirements - Category: Structural Framing
Type - Pset_ReinforcementBarPitchOfBeam - Description: HE200A
Type - Pset_Pieters - Breedte: 200 mm; Hoogte: 190 mm; Codering - NL-SfB: 28.11; Omschrijving NL-SfB: hoofddraagconstructies - kolommen en liggers, kolom-/liggerconstructies; Materiaal: 00_PBT_MAT_staal_S355; Materiaalkwaliteit: S355; Description: HE200A
Classification: 28.11 hoofddraagconstructies - kolommen en liggers, kolom-/liggerconstructies (Uniformat); Material: 00_PBT_MAT_staal_S355
Pset_BeamCommon - Reference: 28_PBT_SF_staal_H-profiel:S355_HE200A
Pset_QuantityTakeOff - Reference: 28_PBT_SF_staal_H-profiel:S355_HE200A
Pset_ReinforcementBarPitchOfBeam - Reference: 28_PBT_SF_staal_H-profiel:S355_HE200A
Pset_Pieters - Naamgeving element: 28_PBT_SF_staal_H-profiel: S355_HE200A; Fase: Nieuw
Name (28_PBT_SF_staal_H-profiel:S355_HE200A:...) | In | CrossSectionArea (mm2) | NetVolume (m3) | Slope (deg) | Span (mm) = Length (mm) | Bouwlaag | NetSurfaceArea (mm2)
2489959 | 05 vijfde verdieping | 1574504 | 0.0148699 | 0 | 2775 | Level: 07 bk ruwe vloer bwd zuid | 3149008
2489963 | 05 vijfde verdieping | 1064567 | 0.0100374 | 90 | 2417.5 | Level: 07 bk ruwe vloer bwd zuid | 2129134
2489965 | 05 vijfde verdieping | 1064567 | 0.0100374 | 90 | 2332.5 | Level: 07 bk ruwe vloer bwd zuid | 2129134
2489967 | 05 vijfde verdieping | 1108875 | 0.0104573 | 90 | 2520 | Level: 07 bk ruwe vloer bwd zuid | 2217749
2489969 | 05 vijfde verdieping | 1108875 | 0.0104573 | 90 | 2520 | Level: 07 bk ruwe vloer bwd zuid | 2217749
2489971 | 05 vijfde verdieping | 1108875 | 0.0104573 | 90 | 2520 | Level: 07 bk ruwe vloer bwd zuid | 2217749
2490050 | 05 vijfde verdieping | 1527016 | 0.0144199 | 0 | 2678.7 | Level: 07 bk ruwe vloer bwd zuid | 3054032
2490054 | 05 vijfde verdieping | 1071781 | 0.0101058 | 90 | 2417.5 | Level: 07 bk ruwe vloer bwd zuid | 2143562
2490056 | 05 vijfde verdieping | 1064567 | 0.0100374 | 90 | 2332.5 | Level: 07 bk ruwe vloer bwd zuid | 2129134
2490058 | 05 vijfde verdieping | 1108875 | 0.0104573 | 90 | 2520 | Level: 07 bk ruwe vloer bwd zuid | 2217749
2490060 | 05 vijfde verdieping | 1108875 | 0.0104573 | 90 | 2520 | Level: 07 bk ruwe vloer bwd zuid | 2217749
2490062 | 05 vijfde verdieping | 1108875 | 0.0104573 | 90 | 2520 | Level: 07 bk ruwe vloer bwd zuid | 2217749
2520239 | 01 eerste verdieping | 1673742 | 0.0158103 | 0 | 2937 | Level: 01 eerste verdieping | 3347484
2520534 | 01 eerste verdieping | 1513552 | 0.0142923 | 0 | 2655 | Level: 01 eerste verdieping | 3027105
2549240 | 03 derde verdieping | 1565686 | 0.0147864 | 0 | 2746.78 | Level: 03 derde verdieping | 3131373
2549258 | 03 derde verdieping | 1496511 | 0.0141308 | 0 | 2625 | Level: 03 derde verdieping | 2993022
2549276 | 03 derde verdieping | 1485150 | 0.0140231 | 0 | 2605 | Level: 03 derde verdieping | 2970300
2549293 | 03 derde verdieping | 1476629 | 0.0139424 | 0 | 2590 | Level: 03 derde verdieping | 2953259
2549309 | 03 derde verdieping | 1493671 | 0.0141039 | 0 | 2620 | Level: 03 derde verdieping | 2987342
2549326 | 03 derde verdieping | 1516393 | 0.0143192 | 0 | 2660 | Level: 03 derde verdieping | 3032786
2576889 | -2 kelder | 1728215 | 0.0162753 | 35.8161 | 3588.61 | Level: palenplan | 3456429
2576895 | -2 kelder | 1728215 | 0.0162753 | 35.8161 | 3588.61 | Level: palenplan | 3456429
2576899 | -2 kelder | 1728214 | 0.0162753 | 35.8161 | 3588.61 | Level: palenplan | 3456429
2585618 | 03 derde verdieping | 1800417 | 0.0170108 | 0 | 3160 | Level: 03 derde verdieping | 3600834
2644785 | 05 vijfde verdieping | 1003786 | 0.00946145 | 90 | 2335 | Level: 07 bk ruwe vloer bwd zuid | 2007571
2644787 | 05 vijfde verdieping | 1003786 | 0.00946145 | 90 | 2335 | Level: 07 bk ruwe vloer bwd zuid | 2007571
2644789 | 05 vijfde verdieping | 1003786 | 0.00946145 | 90 | 2335 | Level: 07 bk ruwe vloer bwd zuid | 2007571
2644791 | 05 vijfde verdieping | 1003786 | 0.00946145 | 90 | 2335 | Level: 07 bk ruwe vloer bwd zuid | 2007571
2644801 | 05 vijfde verdieping | 1574504 | 0.0148699 | 0 | 2775 | Level: 07 bk ruwe vloer bwd zuid | 3149008
2644807 | 05 vijfde verdieping | 1064567 | 0.0100374 | 90 | 2420 | Level: 07 bk ruwe vloer bwd zuid | 2129134
2644931 | 05 vijfde verdieping | 1064567 | 0.0100374 | 90 | 2335 | Level: 07 bk ruwe vloer bwd zuid | 2129134
2644933 | 05 vijfde verdieping | 1109443 | 0.0104627 | 90 | 2521 | Level: 07 bk ruwe vloer bwd zuid | 2218885
2644935 | 05 vijfde verdieping | 1109443 | 0.0104627 | 90 | 2521 | Level: 07 bk ruwe vloer bwd zuid | 2218885
2644937 | 05 vijfde verdieping | 1109443 | 0.0104627 | 90 | 2521 | Level: 07 bk ruwe vloer bwd zuid | 2218885
2644947 | 05 vijfde verdieping | 1574504 | 0.0148699 | 0 | 2775 | Level: 07 bk ruwe vloer bwd zuid | 3149008
2644953 | 05 vijfde verdieping | 1064567 | 0.0100374 | 90 | 2420 | Level: 07 bk ruwe vloer bwd zuid | 2129134
2690410 | 05 vijfde verdieping | 742457 | 0.00698494 | 90 | 1662.5 | Level: 07 bk ruwe vloer bwd zuid | 1484913
2690412 | 05 vijfde verdieping | 743987 | 0.00699944 | 90 | 1662.5 | Level: 07 bk ruwe vloer bwd zuid | 1487973
2690414 | 05 vijfde verdieping | 743987 | 0.00699944 | 90 | 1662.5 | Level: 07 bk ruwe vloer bwd zuid | 1487973
2690416 | 05 vijfde verdieping | 701016 | 0.00659222 | 90 | 1850 | Level: 07 bk ruwe vloer bwd zuid | 1402031
2861232 | 06 zesde verdieping | 232702 | 0.0021542 | 0 | 400.174 | Level: 06 zesde verdieping | 465403
2883638 | 06 zesde verdieping | 232702 | 0.0021542 | 0 | 400.174 | Level: 06 zesde verdieping | 465403
2883660 | 06 zesde verdieping | 214322 | 0.00198003 | 0 | 367.818 | Level: 06 zesde verdieping | 428644
2884175 | 06 zesde verdieping | 232702 | 0.0021542 | 0 | 400.174 | Level: 06 zesde verdieping | 465403
3537033 | 06 zesde verdieping | 233227 | 0.00215918 | 0 | 401.099 | Level: 06 zesde verdieping | 466455
3540780 | 06 zesde verdieping | 233227 | 0.00215918 | 0 | 401.099 | Level: 06 zesde verdieping | 466455
3540900 | 06 zesde verdieping | 233227 | 0.00215918 | 0 | 401.099 | Level: 06 zesde verdieping | 466455
3540952 | 06 zesde verdieping | 215843 | 0.00199444 | 0 | 385.664 | Level: 06 zesde verdieping | 431686
3541003 | 06 zesde verdieping | 233227 | 0.00215918 | 0 | 401.099 | Level: 06 zesde verdieping | 466455
3541018 | 06 zesde verdieping | 233227 | 0.00215918 | 0 | 401.099 | Level: 06 zesde verdieping | 466455
3541031 | 06 zesde verdieping | 233227 | 0.00215918 | 0 | 401.099 | Level: 06 zesde verdieping | 466455
3541044 | 06 zesde verdieping | 233227 | 0.00215918 | 0 | 401.099 | Level: 06 zesde verdieping | 466455
3541260 | 06 zesde verdieping | 915692 | 0.00862662 | 0 | 1602.52 | Level: 06 zesde verdieping | 1831384
3541262 | 06 zesde verdieping | 915692 | 0.00862662 | 0 | 1602.52 | Level: 06 zesde verdieping | 1831384
3541334 | 06 zesde verdieping | 915692 | 0.00862662 | 0 | 1602.52 | Level: 06 zesde verdieping | 1831384
3541348 | 06 zesde verdieping | 915692 | 0.00862662 | 0 | 1602.52 | Level: 06 zesde verdieping | 1831384
3541362 | 06 zesde verdieping | 898651 | 0.00846513 | 0 | 1587.52 | Level: 06 zesde verdieping | 1797301
3541378 | 06 zesde verdieping | 915692 | 0.00862662 | 0 | 1602.52 | Level: 06 zesde verdieping | 1831384
3543545 | 06 zesde verdieping | 738212 | 0.00694471 | 0 | 1290.08 | Level: 06 zesde verdieping | 1476423
3589896 | 05 vijfde verdieping | 374862 | 0.0035014 | 0 | 650.435 | Level: 05 vijfde verdieping | 749724
3702611 | 03 derde verdieping | 1728214 | 0.0162753 | 35.8161 | 3588.61 | Level: 04 ok ruwe vloer paradezaal buitendoos | 3456429
3702613 | 03 derde verdieping | 1728214 | 0.0162753 | 35.8161 | 3588.61 | Level: 04 ok ruwe vloer paradezaal buitendoos | 3456429
3702615 | 03 derde verdieping | 1041845 | 0.00982212 | 90 | 2100 | Level: 04 ok ruwe vloer paradezaal buitendoos | 2083690
3702621 | 03 derde verdieping | 1041845 | 0.00982212 | 90 | 2100 | Level: 04 ok ruwe vloer paradezaal buitendoos | 2083690
3702623 | 03 derde verdieping | 1041845 | 0.00982212 | 90 | 2100 | Level: 04 ok ruwe vloer paradezaal buitendoos | 2083690
3702625 | 03 derde verdieping | 1041845 | 0.00982212 | 90 | 2100 | Level: 04 ok ruwe vloer paradezaal buitendoos | 2083690
3702627 | 03 derde verdieping | 1041845 | 0.00982212 | 90 | 2100 | Level: 04 ok ruwe vloer paradezaal buitendoos | 2083690
3702629 | 03 derde verdieping | 1041845 | 0.00982212 | 90 | 2100 | Level: 04 ok ruwe vloer paradezaal buitendoos | 2083690
3702631 | 03 derde verdieping | 1041845 | 0.00982212 | 90 | 2100 | Level: 04 ok ruwe vloer paradezaal buitendoos | 2083690
3702633 | 03 derde verdieping | 1728215 | 0.0162755 | 35.8161 | 3588.61 | Level: 04 ok ruwe vloer paradezaal buitendoos | 3456430
3753124 | 04 vierde verdieping | 1955359 | 0.0184791 | 0 | 3432.76 | Level: 04 vierde verdieping | 3910718
3753499 | 04 vierde verdieping | 1814157 | 0.017141 | 0 | 3184.19 | Level: 04 vierde verdieping | 3628313
3753510 | 04 vierde verdieping | 1955359 | 0.0184791 | 0 | 3432.76 | Level: 04 vierde verdieping | 3910718
3753521 | 04 vierde verdieping | 1814157 | 0.017141 | 0 | 3184.19 | Level: 04 vierde verdieping | 3628313
3753532 | 04 vierde verdieping | 1961849 | 0.0185406 | 0 | 3444.19 | Level: 04 vierde verdieping | 3923699
3753543 | 04 vierde verdieping | 1814157 | 0.017141 | 0 | 3184.19 | Level: 04 vierde verdieping | 3628313
3753554 | 04 vierde verdieping | 1955359 | 0.0184791 | 0 | 3432.76 | Level: 04 vierde verdieping | 3910718
3753888 | 04 vierde verdieping | 3576492 | 0.0338419 | 0 | 6286.63 | Level: 04 vierde verdieping | 7152985
3754406 | 04 vierde verdieping | 3576492 | 0.0338419 | 0 | 6286.63 | Level: 04 vierde verdieping | 7152985
3754417 | 04 vierde verdieping | 3576492 | 0.0338419 | 0 | 6286.63 | Level: 04 vierde verdieping | 7152985
3754428 | 04 vierde verdieping | 3576492 | 0.0338419 | 0 | 6286.63 | Level: 04 vierde verdieping | 7152985
3754439 | 04 vierde verdieping | 3576492 | 0.0338419 | 0 | 6286.63 | Level: 04 vierde verdieping | 7152985
3754450 | 04 vierde verdieping | 3576492 | 0.0338419 | 0 | 6286.63 | Level: 04 vierde verdieping | 7152985
3754461 | 04 vierde verdieping | 3576492 | 0.0338419 | 0 | 6286.63 | Level: 04 vierde verdieping | 7152985
3971064 | 03 derde verdieping | 832737 | 0.00784286 | 0 | 1545 | Level: 03 derde verdieping | 1665474
3971318 | 03 derde verdieping | 844880 | 0.00795557 | 0 | 1477.86 | Level: 03 derde verdieping | 1689760
3971393 | 03 derde verdieping | 1156266 | 0.0109064 | 0 | 2026.03 | Level: 03 derde verdieping | 2312532
3971483 | 03 derde verdieping | 868817 | 0.00818241 | 0 | 1520 | Level: 03 derde verdieping | 1737635
4250258 | 03 derde verdieping | 883293 | 0.00831959 | 0 | 1545.48 | Level: 03 derde verdieping | 1766585
4250405 | 03 derde verdieping | 897980 | 0.00845877 | 0 | 1571.34 | Level: 03 derde verdieping | 1795959
4250681 | 03 derde verdieping | 895895 | 0.00843901 | 0 | 1567.67 | Level: 03 derde verdieping | 1791789
4328725 | 06 zesde verdieping | 915692 | 0.00862662 | 0 | 1602.52 | Level: 06 zesde verdieping | 1831384
4328771 | 06 zesde verdieping | 915692 | 0.00862662 | 0 | 1602.52 | Level: 06 zesde verdieping | 1831384
4419098 | 06 zesde verdieping | 715490 | 0.00672939 | 0 | 1250.08 | Level: 06 zesde verdieping | 1430979
4714033 | 05 vijfde verdieping | 1652037 | 0.0156047 | 0 | 2898.79 | Level: 07 bk ruwe vloer bwd zuid | 3304074
4714043 | 05 vijfde verdieping | 701016 | 0.00659222 | 90 | 1905 | Level: 07 bk ruwe vloer bwd zuid | 1402031
4720783 | 05 vijfde verdieping | 1772015 | 0.0167416 | 0 | 3110 | Level: 07 bk ruwe vloer bwd zuid | 3544029

# IfcBeam: 28_PBT_SF_staal_H-profiel:S355_HE200B (14)
Type - Pset_BeamCommon - IsExternal: no; LoadBearing: yes
Type - Pset_ProductRequirements - Category: Structural Framing
Type - Pset_ReinforcementBarPitchOfBeam - Description: HE200B
Type - Pset_Pieters - Breedte: 200 mm; Hoogte: 200 mm; Codering - NL-SfB: 28.11; Omschrijving NL-SfB: hoofddraagconstructies - kolommen en liggers, kolom-/liggerconstructies; Materiaal: 00_PBT_MAT_staal_S355; Materiaalkwaliteit: S355; Description: HE200B
Classification: 28.11 hoofddraagconstructies - kolommen en liggers, kolom-/liggerconstructies (Uniformat); Material: 00_PBT_MAT_staal_S355
Pset_BeamCommon - Reference: 28_PBT_SF_staal_H-profiel:S355_HE200B
Pset_QuantityTakeOff - Reference: 28_PBT_SF_staal_H-profiel:S355_HE200B
Pset_ReinforcementBarPitchOfBeam - Reference: 28_PBT_SF_staal_H-profiel:S355_HE200B
Pset_Pieters - Naamgeving element: 28_PBT_SF_staal_H-profiel: S355_HE200B; Fase: Nieuw
Name (28_PBT_SF_staal_H-profiel:S355_HE200B:...) | In | CrossSectionArea (mm2) | NetVolume (m3) | Slope (deg) | Span (mm) = Length (mm) | Bouwlaag | NetSurfaceArea (mm2)
2475106 | 04 vierde verdieping | 1299370 | 0.0175219 | 0 | 2244.05 | Level: 04 vierde verdieping | 2598741
2478048 | 04 vierde verdieping | 1299370 | 0.0175219 | 0 | 2244.05 | Level: 04 vierde verdieping | 2598741
2478125 | 04 vierde verdieping | 1299370 | 0.0175219 | 0 | 2244.05 | Level: 04 vierde verdieping | 2598741
2478132 | 04 vierde verdieping | 1299370 | 0.0175219 | 0 | 2244.05 | Level: 04 vierde verdieping | 2598741
2478139 | 04 vierde verdieping | 1299370 | 0.0175219 | 0 | 2244.05 | Level: 04 vierde verdieping | 2598741
2478515 | 04 vierde verdieping | 1935896 | 0.0261574 | 0 | 3350 | Level: 04 vierde verdieping | 3871793
2576891 | -2 kelder | 1705943 | 0.0229504 | 35.8161 | 3588.61 | Level: palenplan | 3411886
3394503 | 04 vierde verdieping | 1106127 | 0.0148974 | 0 | 2368.38 | Level: 04 vierde verdieping | 2212255
3702609 | 03 derde verdieping | 1747477 | 0.0235441 | 35.8161 | 3588.61 | Level: 04 ok ruwe vloer paradezaal buitendoos | 3494954
3702617 | 03 derde verdieping | 10432175 | 0.141422 | 0 | 17460 | Level: 04 ok ruwe vloer paradezaal buitendoos | 20864350
3841488 | 04 vierde verdieping | 1299370 | 0.0175219 | 0 | 2244.05 | Level: 04 vierde verdieping | 2598741
3877285 | 04 vierde verdieping | 1861075 | 0.0251423 | 0 | 3220 | Level: 04 vierde verdieping | 3722150
6291190 | 04 vierde verdieping | 1299370 | 0.0175219 | 0 | 2244.05 | Level: 04 vierde verdieping | 2598741
6292653 | 04 vierde verdieping | 267386 | 0.00351242 | 36.7474 | 720 | Level: 04 vierde verdieping | 534772

# IfcBeam: 28_PBT_SF_staal_H-profiel:S355_HE200B_Z, 28_PBT_SF_staal_H-profiel:S355_HE200B_Z:4329376
In: 06 zesde verdieping
Type - Pset_BeamCommon - IsExternal: no; LoadBearing: yes
Type - Pset_ProductRequirements - Category: Structural Framing
Type - Pset_ReinforcementBarPitchOfBeam - Description: HE200B(Z)
Type - Pset_Pieters - Breedte: 200 mm; Hoogte: 200 mm; Codering - NL-SfB: 28.11; Omschrijving NL-SfB: hoofddraagconstructies - kolommen en liggers, kolom-/liggerconstructies; Materiaal: 00_PBT_MAT_staal_S355; Materiaalkwaliteit: S355; Description: HE200B(Z)
Classification: 28.11 hoofddraagconstructies - kolommen en liggers, kolom-/liggerconstructies (Uniformat); Material: 00_PBT_MAT_staal_S355
BaseQuantities - CrossSectionArea: 2905696 mm2; NetVolume: 0.0393141 m3; Length: 5035 mm; NetSurfaceArea: 5811391 mm2
Pset_BeamCommon - Slope: 0 deg; Reference: 28_PBT_SF_staal_H-profiel:S355_HE200B_Z; Span: 5035 mm
Pset_QuantityTakeOff - Reference: 28_PBT_SF_staal_H-profiel:S355_HE200B_Z
Pset_ReinforcementBarPitchOfBeam - Reference: 28_PBT_SF_staal_H-profiel:S355_HE200B_Z
Pset_Pieters - Bouwlaag: Level: 06 zesde verdieping; Naamgeving element: 28_PBT_SF_staal_H-profiel: S355_HE200B_Z; Fase: Nieuw

# IfcBeam: 28_PBT_SF_staal_H-profiel:S355_HE220A (143)
Type - Pset_BeamCommon - IsExternal: no; LoadBearing: yes
Type - Pset_ProductRequirements - Category: Structural Framing
Type - Pset_ReinforcementBarPitchOfBeam - Description: HE220A
Type - Pset_Pieters - Breedte: 220 mm; Hoogte: 210 mm; Codering - NL-SfB: 28.11; Omschrijving NL-SfB: hoofddraagconstructies - kolommen en liggers, kolom-/liggerconstructies; Materiaal: 00_PBT_MAT_staal_S355; Materiaalkwaliteit: S355; Description: HE220A
Classification: 28.11 hoofddraagconstructies - kolommen en liggers, kolom-/liggerconstructies (Uniformat); Material: 00_PBT_MAT_staal_S355
Pset_BeamCommon - Reference: 28_PBT_SF_staal_H-profiel:S355_HE220A
Pset_QuantityTakeOff - Reference: 28_PBT_SF_staal_H-profiel:S355_HE220A
Pset_ReinforcementBarPitchOfBeam - Reference: 28_PBT_SF_staal_H-profiel:S355_HE220A
Pset_Pieters - Naamgeving element: 28_PBT_SF_staal_H-profiel: S355_HE220A; Fase: Nieuw
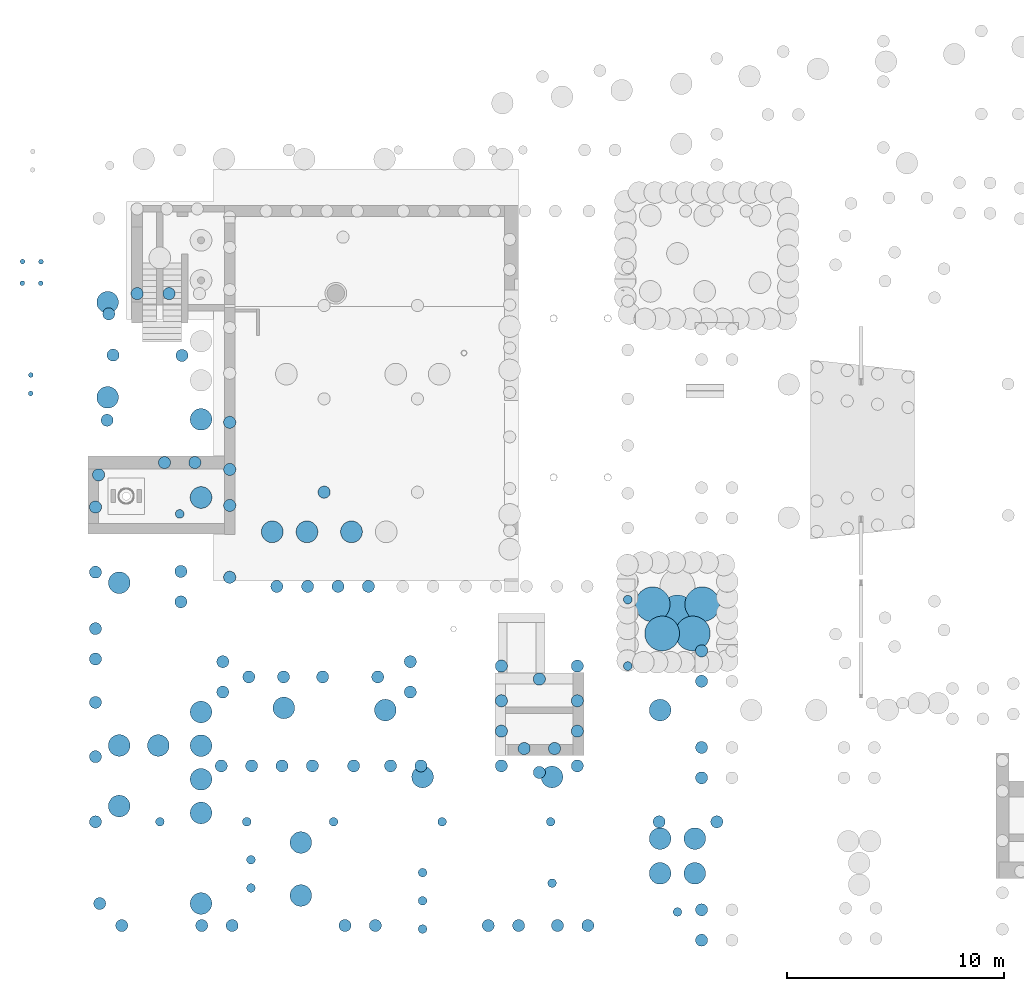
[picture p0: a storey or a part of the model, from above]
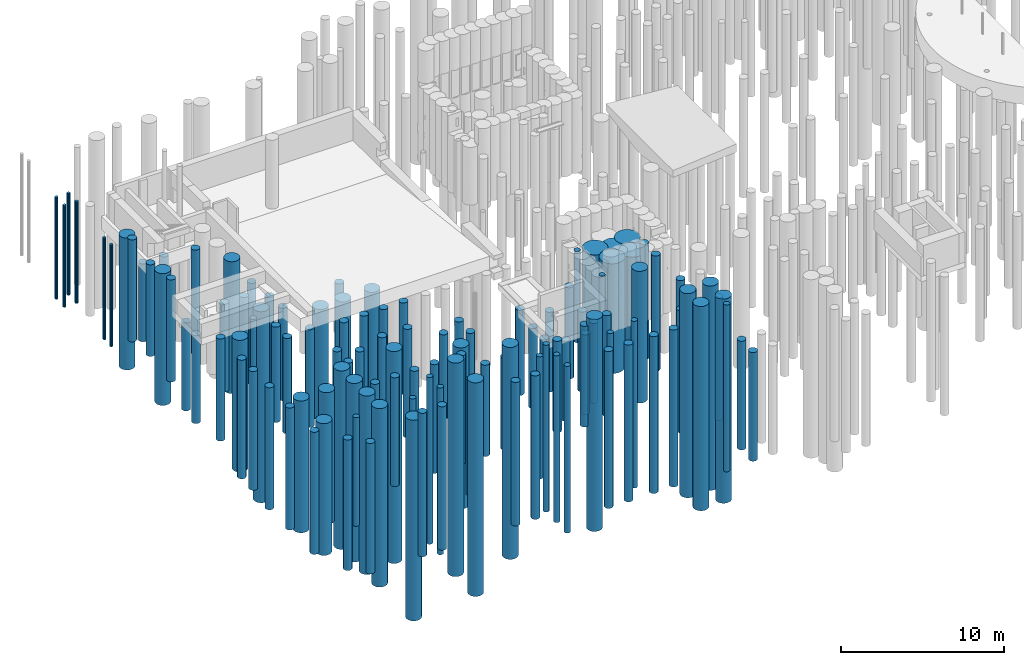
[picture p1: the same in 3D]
Properties of the parts of a building model (IFC2X3), part 3 of 18

# IfcBeam: 28_PBT_SF_staal_H-profiel:S355_HE220A (143)
Name (28_PBT_SF_staal_H-profiel:S355_HE220A:...) | In | CrossSectionArea (mm2) | NetVolume (m3) | Slope (deg) | Span (mm) = Length (mm) | Bouwlaag | NetSurfaceArea (mm2)
2272543 | 02 tweede verdieping | 3674456 | 0.0376077 | 0 | 5845 | Level: 02 tweede verdieping | 7348913
2272825 | 02 tweede verdieping | 2388610 | 0.0244241 | 0 | 3796 | Level: 02 tweede verdieping | 4777220
2272908 | 02 tweede verdieping | 1965955 | 0.0200907 | 0 | 3122.5 | Level: 02 tweede verdieping | 3931910
2498559 | 03 derde verdieping | 11365064 | 0.116458 | 0 | 18100 | Level: 04 bk staal paradezaal binnendoos | 22730129
2498649 | 03 derde verdieping | 3636813 | 0.0372217 | 0 | 5785.02 | Level: 04 bk staal paradezaal binnendoos | 7273627
2515310 | 03 derde verdieping | 3257136 | 0.033329 | 0 | 5180 | Level: 04 bk staal paradezaal binnendoos | 6514273
2515327 | 03 derde verdieping | 3602288 | 0.0368678 | 0 | 5730 | Level: 04 bk staal paradezaal binnendoos | 7204576
2515329 | 03 derde verdieping | 3602288 | 0.0368678 | 0 | 5730 | Level: 04 bk staal paradezaal binnendoos | 7204576
2515346 | 03 derde verdieping | 2692343 | 0.0275382 | 0 | 4280 | Level: 04 bk staal paradezaal binnendoos | 5384685
2515348 | 03 derde verdieping | 2692343 | 0.0275382 | 0 | 4280 | Level: 04 bk staal paradezaal binnendoos | 5384685
2515365 | 03 derde verdieping | 682295 | 0.0069295 | 0 | 1076.98 | Level: 04 bk staal paradezaal binnendoos | 1364589
2515367 | 03 derde verdieping | 682295 | 0.0069295 | 0 | 1076.98 | Level: 04 bk staal paradezaal binnendoos | 1364589
2515699 | 03 derde verdieping | 2624568 | 0.0268433 | 0 | 4172 | Level: 04 bk staal paradezaal binnendoos | 5249137
2516169 | 03 derde verdieping | 966584 | 0.00984428 | 0 | 1530 | Level: 04 bk staal paradezaal binnendoos | 1933169
2516292 | 03 derde verdieping | 966584 | 0.00984427 | 0 | 1530 | Level: 04 bk staal paradezaal binnendoos | 1933168
2516372 | 03 derde verdieping | 3611711 | 0.0369644 | 0 | 5745.02 | Level: 04 bk staal paradezaal binnendoos | 7223423
2516374 | 03 derde verdieping | 3232034 | 0.0330716 | 0 | 5140 | Level: 04 bk staal paradezaal binnendoos | 6464069
2516376 | 03 derde verdieping | 3602288 | 0.0368678 | 0 | 5730 | Level: 04 bk staal paradezaal binnendoos | 7204576
2516378 | 03 derde verdieping | 2692343 | 0.0275382 | 0 | 4280 | Level: 04 bk staal paradezaal binnendoos | 5384685
2516938 | 03 derde verdieping | 2624568 | 0.0268433 | 0 | 4172 | Level: 04 bk staal paradezaal binnendoos | 5249137
2516940 | 03 derde verdieping | 3611711 | 0.0369644 | 0 | 5745.02 | Level: 04 bk staal paradezaal binnendoos | 7223423
2516942 | 03 derde verdieping | 3213208 | 0.0328786 | 0 | 5110 | Level: 04 bk staal paradezaal binnendoos | 6426416
2516944 | 03 derde verdieping | 3583462 | 0.0366747 | 0 | 5700 | Level: 04 bk staal paradezaal binnendoos | 7166923
2516946 | 03 derde verdieping | 2692343 | 0.0275382 | 0 | 4280 | Level: 04 bk staal paradezaal binnendoos | 5384685
2516979 | 03 derde verdieping | 2624568 | 0.0268433 | 0 | 4172 | Level: 04 bk staal paradezaal binnendoos | 5249137
2516981 | 03 derde verdieping | 3636813 | 0.0372217 | 0 | 5785.02 | Level: 04 bk staal paradezaal binnendoos | 7273627
2516983 | 03 derde verdieping | 3257136 | 0.033329 | 0 | 5180 | Level: 04 bk staal paradezaal binnendoos | 6514273
2516985 | 03 derde verdieping | 3602288 | 0.0368678 | 0 | 5730 | Level: 04 bk staal paradezaal binnendoos | 7204576
2516987 | 03 derde verdieping | 2692343 | 0.0275382 | 0 | 4280 | Level: 04 bk staal paradezaal binnendoos | 5384685
2517024 | 03 derde verdieping | 2624568 | 0.0268433 | 0 | 4172 | Level: 04 bk staal paradezaal binnendoos | 5249137
2517026 | 03 derde verdieping | 3636813 | 0.0372217 | 0 | 5785.02 | Level: 04 bk staal paradezaal binnendoos | 7273627
2517028 | 03 derde verdieping | 3257136 | 0.033329 | 0 | 5180 | Level: 04 bk staal paradezaal binnendoos | 6514273
2517030 | 03 derde verdieping | 3602288 | 0.0368678 | 0 | 5730 | Level: 04 bk staal paradezaal binnendoos | 7204576
2517032 | 03 derde verdieping | 2692343 | 0.0275382 | 0 | 4280 | Level: 04 bk staal paradezaal binnendoos | 5384685
2517069 | 03 derde verdieping | 2624568 | 0.0268433 | 0 | 4172 | Level: 04 bk staal paradezaal binnendoos | 5249137
2517071 | 03 derde verdieping | 3636813 | 0.0372217 | 0 | 5785.02 | Level: 04 bk staal paradezaal binnendoos | 7273627
2517073 | 03 derde verdieping | 3257136 | 0.033329 | 0 | 5180 | Level: 04 bk staal paradezaal binnendoos | 6514273
2517075 | 03 derde verdieping | 3602288 | 0.0368678 | 0 | 5730 | Level: 04 bk staal paradezaal binnendoos | 7204576
2517077 | 03 derde verdieping | 2692343 | 0.0275382 | 0 | 4280 | Level: 04 bk staal paradezaal binnendoos | 5384685
2681740 | 03 derde verdieping | 3774874 | 0.0386373 | 0 | 6005.02 | Level: 04 bk staal paradezaal binnendoos | 7549748
2681742 | 03 derde verdieping | 3257136 | 0.033329 | 0 | 5180 | Level: 04 bk staal paradezaal binnendoos | 6514273
2681744 | 03 derde verdieping | 3602288 | 0.0368678 | 0 | 5730 | Level: 04 bk staal paradezaal binnendoos | 7204576
2681770 | 03 derde verdieping | 3774874 | 0.0386373 | 0 | 6005.02 | Level: 04 bk staal paradezaal binnendoos | 7549748
2681772 | 03 derde verdieping | 3257136 | 0.033329 | 0 | 5180 | Level: 04 bk staal paradezaal binnendoos | 6514273
2681774 | 03 derde verdieping | 3602288 | 0.0368678 | 0 | 5730 | Level: 04 bk staal paradezaal binnendoos | 7204576
2681892 | 03 derde verdieping | 3774874 | 0.0386373 | 0 | 6005.02 | Level: 04 bk staal paradezaal binnendoos | 7549748
2681894 | 03 derde verdieping | 3257136 | 0.033329 | 0 | 5180 | Level: 04 bk staal paradezaal binnendoos | 6514273
2681896 | 03 derde verdieping | 3602288 | 0.0368678 | 0 | 5730 | Level: 04 bk staal paradezaal binnendoos | 7204576
2681921 | 03 derde verdieping | 3749772 | 0.0383799 | 0 | 5965.02 | Level: 04 bk staal paradezaal binnendoos | 7499544
2681923 | 03 derde verdieping | 3232034 | 0.0330716 | 0 | 5140 | Level: 04 bk staal paradezaal binnendoos | 6464069
2681925 | 03 derde verdieping | 3602288 | 0.0368678 | 0 | 5730 | Level: 04 bk staal paradezaal binnendoos | 7204576
2682059 | 03 derde verdieping | 3749772 | 0.0383799 | 0 | 5965.02 | Level: 04 bk staal paradezaal binnendoos | 7499544
2682061 | 03 derde verdieping | 3232034 | 0.0330716 | 0 | 5140 | Level: 04 bk staal paradezaal binnendoos | 6464069
2682063 | 03 derde verdieping | 3602288 | 0.0368678 | 0 | 5730 | Level: 04 bk staal paradezaal binnendoos | 7204576
2682065 | 03 derde verdieping | 2692343 | 0.0275382 | 0 | 4280 | Level: 04 bk staal paradezaal binnendoos | 5384685
2682096 | 03 derde verdieping | 3774874 | 0.0386373 | 0 | 6005.02 | Level: 04 bk staal paradezaal binnendoos | 7549748
2682098 | 03 derde verdieping | 3257136 | 0.033329 | 0 | 5180 | Level: 04 bk staal paradezaal binnendoos | 6514273
2682100 | 03 derde verdieping | 3602288 | 0.0368678 | 0 | 5730 | Level: 04 bk staal paradezaal binnendoos | 7204576
2682102 | 03 derde verdieping | 2692343 | 0.0275382 | 0 | 4280 | Level: 04 bk staal paradezaal binnendoos | 5384685
2682369 | 03 derde verdieping | 3232034 | 0.0330716 | 0 | 5140 | Level: 04 bk staal paradezaal binnendoos | 6464069
2682463 | 03 derde verdieping | 3749772 | 0.0383799 | 0 | 5965.02 | Level: 04 bk staal paradezaal binnendoos | 7499544
2956429 | 04 vierde verdieping | 2315018 | 0.0236647 | 60 | 3810.86 | Level: 04 vierde verdieping | 4630035
2957115 | 04 vierde verdieping | 2253257 | 0.0230263 | 60 | 3820 | Level: 04 vierde verdieping | 4506514
2958102 | 04 vierde verdieping | 2253257 | 0.0230263 | 60 | 3810 | Level: 04 vierde verdieping | 4506514
2958132 | 04 vierde verdieping | 2253257 | 0.0230263 | 60 | 3800 | Level: 04 vierde verdieping | 4506514
2958801 | 04 vierde verdieping | 2207411 | 0.022556 | 60 | 3730 | Level: 04 vierde verdieping | 4414822
2958831 | 04 vierde verdieping | 2882329 | 0.0294544 | 60 | 5040 | Level: 04 vierde verdieping | 5764659
2959559 | 04 vierde verdieping | 2878110 | 0.0294111 | 60 | 5120 | Level: 04 vierde verdieping | 5756221
2959743 | 04 vierde verdieping | 2302913 | 0.0235352 | 60 | 3980 | Level: 04 vierde verdieping | 4605826
2965320 | 04 vierde verdieping | 3834596 | 0.0392496 | 0 | 6125.58 | Level: 04 vierde verdieping | 7669193
2965322 | 04 vierde verdieping | 4387676 | 0.0449202 | 0 | 7156.92 | Level: 04 vierde verdieping | 8775351
2965324 | 04 vierde verdieping | 4431970 | 0.0453744 | 0 | 7227.5 | Level: 04 vierde verdieping | 8863941
2965548 | 04 vierde verdieping | 3646332 | 0.0373193 | 0 | 6125.58 | Level: 04 vierde verdieping | 7292663
2965550 | 04 vierde verdieping | 4293543 | 0.0439551 | 0 | 7156.92 | Level: 04 vierde verdieping | 8587087
2965552 | 04 vierde verdieping | 4337838 | 0.0444092 | 0 | 7227.5 | Level: 04 vierde verdieping | 8675676
2965621 | 04 vierde verdieping | 3646332 | 0.0373193 | 0 | 6125.58 | Level: 04 vierde verdieping | 7292663
2965623 | 04 vierde verdieping | 4293543 | 0.0439551 | 0 | 7156.92 | Level: 04 vierde verdieping | 8587087
2965625 | 04 vierde verdieping | 4337838 | 0.0444092 | 0 | 7227.5 | Level: 04 vierde verdieping | 8675676
3669626 | 04 vierde verdieping | 1157735 | 0.0118041 | 90 | 2130 | Level: 04 vierde verdieping | 2315470
3669628 | 04 vierde verdieping | 1157735 | 0.0118041 | 90 | 2130 | Level: 04 vierde verdieping | 2315470
3669630 | 04 vierde verdieping | 1157735 | 0.0118041 | 90 | 2130 | Level: 04 vierde verdieping | 2315470
3669632 | 04 vierde verdieping | 1157735 | 0.0118041 | 90 | 2130 | Level: 04 vierde verdieping | 2315470
3669634 | 04 vierde verdieping | 1157735 | 0.0118041 | 90 | 2130 | Level: 04 vierde verdieping | 2315470
3669636 | 04 vierde verdieping | 1157735 | 0.0118041 | 90 | 2130 | Level: 04 vierde verdieping | 2315470
3669638 | 04 vierde verdieping | 1157735 | 0.0118041 | 90 | 2130 | Level: 04 vierde verdieping | 2315470
3669640 | 04 vierde verdieping | 1157735 | 0.0118041 | 90 | 2130 | Level: 04 vierde verdieping | 2315470
3669642 | 04 vierde verdieping | 1157735 | 0.0118041 | 90 | 2130 | Level: 04 vierde verdieping | 2315470
3669646 | 04 vierde verdieping | 1488104 | 0.0151099 | 46.8029 | 2921.8 | Level: 04 vierde verdieping | 2976209
3669648 | 04 vierde verdieping | 1488104 | 0.0151099 | 46.8029 | 2921.8 | Level: 04 vierde verdieping | 2976209
3669650 | 04 vierde verdieping | 1462351 | 0.014845 | 47.676 | 2880.91 | Level: 04 vierde verdieping | 2924703
3669652 | 04 vierde verdieping | 1488104 | 0.0151099 | 46.8029 | 2921.8 | Level: 04 vierde verdieping | 2976209
3669656 | 04 vierde verdieping | 1488104 | 0.0151099 | 46.8029 | 2921.8 | Level: 04 vierde verdieping | 2976209
3669658 | 04 vierde verdieping | 1488104 | 0.0151099 | 46.8029 | 2921.8 | Level: 04 vierde verdieping | 2976209
3669660 | 04 vierde verdieping | 1488104 | 0.0151099 | 46.8029 | 2921.8 | Level: 04 vierde verdieping | 2976209
3669662 | 04 vierde verdieping | 1488104 | 0.0151099 | 46.8029 | 2921.8 | Level: 04 vierde verdieping | 2976209
3704587 | 03 derde verdieping | 2010587 | 0.0204735 | 39.5138 | 3772.02 | Level: 04 ok ruwe vloer paradezaal buitendoos | 4021174
3704591 | 03 derde verdieping | 2010587 | 0.0204735 | 39.5138 | 3772.02 | Level: 04 ok ruwe vloer paradezaal buitendoos | 4021174
3704593 | 03 derde verdieping | 2010587 | 0.0204735 | 39.5138 | 3772.02 | Level: 04 ok ruwe vloer paradezaal buitendoos | 4021173
3704597 | 03 derde verdieping | 2010587 | 0.0204735 | 39.5138 | 3772.02 | Level: 04 ok ruwe vloer paradezaal buitendoos | 4021173
3704599 | 03 derde verdieping | 2010587 | 0.0204735 | 39.5138 | 3772.02 | Level: 04 ok ruwe vloer paradezaal buitendoos | 4021173
3704601 | 03 derde verdieping | 1327173 | 0.0135413 | 90 | 2400 | Level: 04 ok ruwe vloer paradezaal buitendoos | 2654346
3704607 | 03 derde verdieping | 1327173 | 0.0135413 | 90 | 2400 | Level: 04 ok ruwe vloer paradezaal buitendoos | 2654346
3704609 | 03 derde verdieping | 1327173 | 0.0135413 | 90 | 2400 | Level: 04 ok ruwe vloer paradezaal buitendoos | 2654346
3704611 | 03 derde verdieping | 1327173 | 0.0135413 | 90 | 2400 | Level: 04 ok ruwe vloer paradezaal buitendoos | 2654346
3704613 | 03 derde verdieping | 1327173 | 0.0135413 | 90 | 2400 | Level: 04 ok ruwe vloer paradezaal buitendoos | 2654346
3704615 | 03 derde verdieping | 1327173 | 0.0135413 | 90 | 2400 | Level: 04 ok ruwe vloer paradezaal buitendoos | 2654346
3704617 | 03 derde verdieping | 1327173 | 0.0135413 | 90 | 2400 | Level: 04 ok ruwe vloer paradezaal buitendoos | 2654346
3704619 | 03 derde verdieping | 2010587 | 0.0204735 | 39.5138 | 3772.02 | Level: 04 ok ruwe vloer paradezaal buitendoos | 4021174
3751205 | 03 derde verdieping | 3774874 | 0.0386373 | 0 | 6005.02 | Level: 04 bk staal paradezaal binnendoos | 7549748
3751359 | 03 derde verdieping | 3774874 | 0.0386373 | 0 | 6005.02 | Level: 04 bk staal paradezaal binnendoos | 7549748
3751465 | 03 derde verdieping | 3749772 | 0.0383799 | 0 | 5965.02 | Level: 04 bk staal paradezaal binnendoos | 7499544
3752034 | 03 derde verdieping | 3232034 | 0.0330716 | 0 | 5140 | Level: 04 bk staal paradezaal binnendoos | 6464069
3752094 | 03 derde verdieping | 3257136 | 0.033329 | 0 | 5180 | Level: 04 bk staal paradezaal binnendoos | 6514273
3752122 | 03 derde verdieping | 3257136 | 0.033329 | 0 | 5180 | Level: 04 bk staal paradezaal binnendoos | 6514273
3752161 | 03 derde verdieping | 3602288 | 0.0368678 | 0 | 5730 | Level: 04 bk staal paradezaal binnendoos | 7204576
3752195 | 03 derde verdieping | 3602288 | 0.0368678 | 0 | 5730 | Level: 04 bk staal paradezaal binnendoos | 7204576
3752233 | 03 derde verdieping | 2692343 | 0.0275382 | 0 | 4280 | Level: 04 bk staal paradezaal binnendoos | 5384685
3752245 | 03 derde verdieping | 2692343 | 0.0275382 | 0 | 4280 | Level: 04 bk staal paradezaal binnendoos | 5384685
3752283 | 03 derde verdieping | 2692343 | 0.0275382 | 0 | 4280 | Level: 04 bk staal paradezaal binnendoos | 5384685
3752294 | 03 derde verdieping | 2692343 | 0.0275382 | 0 | 4280 | Level: 04 bk staal paradezaal binnendoos | 5384685
3752336 | 03 derde verdieping | 2692343 | 0.0275382 | 0 | 4280 | Level: 04 bk staal paradezaal binnendoos | 5384685
3752390 | 03 derde verdieping | 2692343 | 0.0275382 | 0 | 4280 | Level: 04 bk staal paradezaal binnendoos | 5384685
3752567 | 03 derde verdieping | 2768905 | 0.0283232 | 0 | 4402 | Level: 04 bk staal paradezaal binnendoos | 5537809
3752569 | 03 derde verdieping | 2768905 | 0.0283232 | 0 | 4402 | Level: 04 bk staal paradezaal binnendoos | 5537809
3752571 | 03 derde verdieping | 2768905 | 0.0283232 | 0 | 4402 | Level: 04 bk staal paradezaal binnendoos | 5537809
3752573 | 03 derde verdieping | 2768905 | 0.0283232 | 0 | 4402 | Level: 04 bk staal paradezaal binnendoos | 5537809
3752726 | 03 derde verdieping | 2768905 | 0.0283232 | 0 | 4402 | Level: 04 bk staal paradezaal binnendoos | 5537809
3752763 | 03 derde verdieping | 2768905 | 0.0283232 | 0 | 4402 | Level: 04 bk staal paradezaal binnendoos | 5537809
3752815 | 03 derde verdieping | 2768905 | 0.0283232 | 0 | 4402 | Level: 04 bk staal paradezaal binnendoos | 5537809
3752862 | 03 derde verdieping | 2768905 | 0.0283232 | 0 | 4402 | Level: 04 bk staal paradezaal binnendoos | 5537809
3754520 | 04 vierde verdieping | 12689193 | 0.130034 | 0 | 20210 | Level: 04 vierde verdieping | 25378386
3754662 | 04 vierde verdieping | 12689193 | 0.130034 | 0 | 20210 | Level: 04 vierde verdieping | 25378386
3754675 | 04 vierde verdieping | 12689193 | 0.130034 | 0 | 20210 | Level: 04 vierde verdieping | 25378386
3754688 | 04 vierde verdieping | 12689193 | 0.130034 | 0 | 20210 | Level: 04 vierde verdieping | 25378386
3754701 | 04 vierde verdieping | 12689193 | 0.130034 | 0 | 20210 | Level: 04 vierde verdieping | 25378386
3754714 | 04 vierde verdieping | 12689193 | 0.130034 | 0 | 20210 | Level: 04 vierde verdieping | 25378386
3754727 | 04 vierde verdieping | 12689193 | 0.130034 | 0 | 20210 | Level: 04 vierde verdieping | 25378386
3754738 | 04 vierde verdieping | 12689193 | 0.130034 | 0 | 20210 | Level: 04 vierde verdieping | 25378386
4397813 | 05 vijfde verdieping | 4359687 | 0.0446333 | 0 | 6936.92 | Level: 05 vijfde verdieping | 8719374
4399443 | 05 vijfde verdieping | 2583009 | 0.0264121 | 0 | 4420 | Level: 05 vijfde verdieping | 5166018
4401622 | 05 vijfde verdieping | 3712475 | 0.0379975 | 0 | 5905.58 | Level: 05 vijfde verdieping | 7424951
4401678 | 05 vijfde verdieping | 4403982 | 0.0450874 | 0 | 7007.5 | Level: 05 vijfde verdieping | 8807963
4402167 | 05 vijfde verdieping | 2633981 | 0.0269347 | 0 | 4950.84 | Level: 05 vijfde verdieping | 5267963

# IfcBeam: 28_PBT_SF_staal_H-profiel:S355_HE220B (137)
Type - Pset_BeamCommon - IsExternal: no; LoadBearing: yes
Type - Pset_ProductRequirements - Category: Structural Framing
Type - Pset_ReinforcementBarPitchOfBeam - Description: HE220B
Type - Pset_Pieters - Breedte: 220 mm; Hoogte: 220 mm; Codering - NL-SfB: 28.11; Omschrijving NL-SfB: hoofddraagconstructies - kolommen en liggers, kolom-/liggerconstructies; Materiaal: 00_PBT_MAT_staal_S355; Materiaalkwaliteit: S355; Description: HE220B
Classification: 28.11 hoofddraagconstructies - kolommen en liggers, kolom-/liggerconstructies (Uniformat); Material: 00_PBT_MAT_staal_S355
Pset_BeamCommon - Reference: 28_PBT_SF_staal_H-profiel:S355_HE220B
Pset_QuantityTakeOff - Reference: 28_PBT_SF_staal_H-profiel:S355_HE220B
Pset_ReinforcementBarPitchOfBeam - Reference: 28_PBT_SF_staal_H-profiel:S355_HE220B
Pset_Pieters - Naamgeving element: 28_PBT_SF_staal_H-profiel: S355_HE220B; Fase: Nieuw
Name (28_PBT_SF_staal_H-profiel:S355_HE220B:...) | In | CrossSectionArea (mm2) | NetVolume (m3) | Slope (deg) | Span (mm) = Length (mm) | Bouwlaag | NetSurfaceArea (mm2)
2210437 | 04 vierde verdieping | 12595769 | 0.180445 | 0 | 19820 | Level: 04 vierde verdieping | 25191538
2210439 | 04 vierde verdieping | 12595769 | 0.180445 | 0 | 19820 | Level: 05 dak bwd midden | 25191538
2212785 | 04 vierde verdieping | 12595769 | 0.180445 | 0 | 19820 | Level: 04 vierde verdieping | 25191538
2212787 | 03 derde verdieping | 12595769 | 0.180445 | 0 | 19820 | Level: 04 bk staal paradezaal binnendoos | 25191538
2212910 | 04 vierde verdieping | 12595769 | 0.180445 | 0 | 19820 | Level: 04 vierde verdieping | 25191538
2212912 | 03 derde verdieping | 12595769 | 0.180445 | 0 | 19820 | Level: 04 bk staal paradezaal binnendoos | 25191538
2315315 | -2 kelder | 6760398 | 0.0967882 | 0 | 11242.6 | Level: palenplan | 13520796
2497730 | 03 derde verdieping | 12957747 | 0.185634 | 0 | 20390 | Level: 04 bk staal paradezaal binnendoos | 25915495
2677506 | 05 vijfde verdieping | 3152595 | 0.0450656 | 0 | 4950 | Level: 05 vijfde verdieping | 6305190
2678072 | 05 vijfde verdieping | 2993833 | 0.0427896 | 0 | 4700 | Level: 05 vijfde verdieping | 5987666
2678121 | 05 vijfde verdieping | 2993833 | 0.0427896 | 0 | 4700 | Level: 05 vijfde verdieping | 5987666
2678149 | 05 vijfde verdieping | 2993833 | 0.0427896 | 0 | 4700 | Level: 05 vijfde verdieping | 5987666
2678176 | 05 vijfde verdieping | 3136719 | 0.044838 | 0 | 4925 | Level: 05 vijfde verdieping | 6273438
2678269 | 05 vijfde verdieping | 3133544 | 0.0447925 | 0 | 4920 | Level: 05 vijfde verdieping | 6267087
2678271 | 05 vijfde verdieping | 2984307 | 0.042653 | 0 | 4685 | Level: 05 vijfde verdieping | 5968615
2678273 | 05 vijfde verdieping | 2993833 | 0.0427896 | 0 | 4700 | Level: 05 vijfde verdieping | 5987666
2678275 | 05 vijfde verdieping | 2993833 | 0.0427896 | 0 | 4700 | Level: 05 vijfde verdieping | 5987666
2678277 | 05 vijfde verdieping | 3136719 | 0.044838 | 0 | 4925 | Level: 05 vijfde verdieping | 6273438
2678306 | 05 vijfde verdieping | 3152595 | 0.0450656 | 0 | 4950 | Level: 05 vijfde verdieping | 6305190
2678308 | 05 vijfde verdieping | 2993833 | 0.0427896 | 0 | 4700 | Level: 05 vijfde verdieping | 5987666
2678310 | 05 vijfde verdieping | 2993833 | 0.0427896 | 0 | 4700 | Level: 05 vijfde verdieping | 5987666
2678312 | 05 vijfde verdieping | 2993833 | 0.0427896 | 0 | 4700 | Level: 05 vijfde verdieping | 5987666
2678314 | 05 vijfde verdieping | 3136719 | 0.044838 | 0 | 4925 | Level: 05 vijfde verdieping | 6273438
2678343 | 05 vijfde verdieping | 3152595 | 0.0450656 | 0 | 4950 | Level: 05 vijfde verdieping | 6305190
2678345 | 05 vijfde verdieping | 2993833 | 0.0427896 | 0 | 4700 | Level: 05 vijfde verdieping | 5987666
2678347 | 05 vijfde verdieping | 2993833 | 0.0427896 | 0 | 4700 | Level: 05 vijfde verdieping | 5987666
2678349 | 05 vijfde verdieping | 2993833 | 0.0427896 | 0 | 4700 | Level: 05 vijfde verdieping | 5987666
2678351 | 05 vijfde verdieping | 3136719 | 0.044838 | 0 | 4925 | Level: 05 vijfde verdieping | 6273438
2678380 | 05 vijfde verdieping | 3152595 | 0.0450656 | 0 | 4950 | Level: 05 vijfde verdieping | 6305190
2678382 | 05 vijfde verdieping | 2993833 | 0.0427896 | 0 | 4700 | Level: 05 vijfde verdieping | 5987666
2678384 | 05 vijfde verdieping | 2993833 | 0.0427896 | 0 | 4700 | Level: 05 vijfde verdieping | 5987666
2678386 | 05 vijfde verdieping | 2993833 | 0.0427896 | 0 | 4700 | Level: 05 vijfde verdieping | 5987666
2678388 | 05 vijfde verdieping | 3136719 | 0.044838 | 0 | 4925 | Level: 05 vijfde verdieping | 6273438
2678518 | 05 vijfde verdieping | 1841883 | 0.026275 | 0 | 3008.74 | Level: 05 vijfde verdieping | 3683765
2678774 | 05 vijfde verdieping | 1841883 | 0.026275 | 0 | 3008.74 | Level: 05 vijfde verdieping | 3683765
2678820 | 05 vijfde verdieping | 1052463 | 0.0149578 | 0 | 1778.36 | Level: 05 vijfde verdieping | 2104926
2678822 | 05 vijfde verdieping | 1052463 | 0.0149578 | 0 | 1778.36 | Level: 05 vijfde verdieping | 2104926
2678884 | 05 vijfde verdieping | 1774953 | 0.0253155 | 0 | 3026.05 | Level: 05 vijfde verdieping | 3549907
2678886 | 05 vijfde verdieping | 1774953 | 0.0253155 | 0 | 3026.05 | Level: 05 vijfde verdieping | 3549907
2678900 | 05 vijfde verdieping | 1774953 | 0.0253155 | 0 | 3026.05 | Level: 05 vijfde verdieping | 3549907
2678902 | 05 vijfde verdieping | 1774953 | 0.0253155 | 0 | 3026.05 | Level: 05 vijfde verdieping | 3549907
2678916 | 05 vijfde verdieping | 1107191 | 0.0157424 | 0 | 1974.54 | Level: 05 vijfde verdieping | 2214382
2678918 | 05 vijfde verdieping | 1107191 | 0.0157424 | 0 | 1974.54 | Level: 05 vijfde verdieping | 2214382
2678932 | 05 vijfde verdieping | 2250572 | 0.0321341 | 0 | 3790 | Level: 05 vijfde verdieping | 4501144
2678934 | 05 vijfde verdieping | 2250572 | 0.0321341 | 0 | 3790 | Level: 05 vijfde verdieping | 4501144
2679289 | 05 vijfde verdieping | 1833818 | 0.0261594 | 0 | 3183.74 | Level: 05 vijfde verdieping | 3667635
2679291 | 05 vijfde verdieping | 1611306 | 0.0229694 | 0 | 2768.36 | Level: 05 vijfde verdieping | 3222612
2679293 | 05 vijfde verdieping | 1774953 | 0.0253155 | 0 | 3026.05 | Level: 05 vijfde verdieping | 3549907
2679295 | 05 vijfde verdieping | 1774953 | 0.0253155 | 0 | 3026.05 | Level: 05 vijfde verdieping | 3549907
2679297 | 05 vijfde verdieping | 1415190 | 0.0201579 | 0 | 2459.54 | Level: 05 vijfde verdieping | 2830380
2679299 | 05 vijfde verdieping | 2501416 | 0.0357302 | 0 | 4185 | Level: 05 vijfde verdieping | 5002833
2679334 | 05 vijfde verdieping | 1833818 | 0.0261594 | 0 | 3183.74 | Level: 05 vijfde verdieping | 3667635
2679336 | 05 vijfde verdieping | 1611306 | 0.0229694 | 0 | 2768.36 | Level: 05 vijfde verdieping | 3222612
2679338 | 05 vijfde verdieping | 1774953 | 0.0253155 | 0 | 3026.05 | Level: 05 vijfde verdieping | 3549907
2679340 | 05 vijfde verdieping | 1774953 | 0.0253155 | 0 | 3026.05 | Level: 05 vijfde verdieping | 3549907
2679342 | 05 vijfde verdieping | 1415190 | 0.0201579 | 0 | 2459.54 | Level: 05 vijfde verdieping | 2830380
2679344 | 05 vijfde verdieping | 2501416 | 0.0357302 | 0 | 4185 | Level: 05 vijfde verdieping | 5002833
2679378 | 05 vijfde verdieping | 1833818 | 0.0261594 | 0 | 3183.74 | Level: 05 vijfde verdieping | 3667635
2679380 | 05 vijfde verdieping | 1611306 | 0.0229694 | 0 | 2768.36 | Level: 05 vijfde verdieping | 3222612
2679382 | 05 vijfde verdieping | 1774953 | 0.0253155 | 0 | 3026.05 | Level: 05 vijfde verdieping | 3549907
2679384 | 05 vijfde verdieping | 1774953 | 0.0253155 | 0 | 3026.05 | Level: 05 vijfde verdieping | 3549907
2679386 | 05 vijfde verdieping | 1415190 | 0.0201579 | 0 | 2459.54 | Level: 05 vijfde verdieping | 2830380
2679388 | 05 vijfde verdieping | 2501416 | 0.0357302 | 0 | 4185 | Level: 05 vijfde verdieping | 5002833
2679422 | 05 vijfde verdieping | 1833818 | 0.0261594 | 0 | 3183.74 | Level: 05 vijfde verdieping | 3667635
2679424 | 05 vijfde verdieping | 1611306 | 0.0229694 | 0 | 2768.36 | Level: 05 vijfde verdieping | 3222612
2679426 | 05 vijfde verdieping | 1774953 | 0.0253155 | 0 | 3026.05 | Level: 05 vijfde verdieping | 3549907
2679428 | 05 vijfde verdieping | 1774953 | 0.0253155 | 0 | 3026.05 | Level: 05 vijfde verdieping | 3549907
2679430 | 05 vijfde verdieping | 1415190 | 0.0201579 | 0 | 2459.54 | Level: 05 vijfde verdieping | 2830380
2679432 | 05 vijfde verdieping | 2501416 | 0.0357302 | 0 | 4185 | Level: 05 vijfde verdieping | 5002833
2679466 | 05 vijfde verdieping | 1833818 | 0.0261594 | 0 | 3183.74 | Level: 05 vijfde verdieping | 3667635
2679468 | 05 vijfde verdieping | 1611306 | 0.0229694 | 0 | 2768.36 | Level: 05 vijfde verdieping | 3222612
2679470 | 05 vijfde verdieping | 1774953 | 0.0253155 | 0 | 3026.05 | Level: 05 vijfde verdieping | 3549907
2679472 | 05 vijfde verdieping | 1774953 | 0.0253155 | 0 | 3026.05 | Level: 05 vijfde verdieping | 3549907
2679474 | 05 vijfde verdieping | 1415190 | 0.0201579 | 0 | 2459.54 | Level: 05 vijfde verdieping | 2830380
2679476 | 05 vijfde verdieping | 2501416 | 0.0357302 | 0 | 4185 | Level: 05 vijfde verdieping | 5002833
2679510 | 05 vijfde verdieping | 1833818 | 0.0261594 | 0 | 3183.74 | Level: 05 vijfde verdieping | 3667635
2679512 | 05 vijfde verdieping | 1611306 | 0.0229694 | 0 | 2768.36 | Level: 05 vijfde verdieping | 3222612
2679514 | 05 vijfde verdieping | 1774953 | 0.0253155 | 0 | 3026.05 | Level: 05 vijfde verdieping | 3549907
2679516 | 05 vijfde verdieping | 1774953 | 0.0253155 | 0 | 3026.05 | Level: 05 vijfde verdieping | 3549907
2679518 | 05 vijfde verdieping | 1415190 | 0.0201579 | 0 | 2459.54 | Level: 05 vijfde verdieping | 2830380
2679520 | 05 vijfde verdieping | 2501416 | 0.0357302 | 0 | 4185 | Level: 05 vijfde verdieping | 5002833
2679554 | 05 vijfde verdieping | 1833818 | 0.0261594 | 0 | 3183.74 | Level: 05 vijfde verdieping | 3667635
2679556 | 05 vijfde verdieping | 1611306 | 0.0229694 | 0 | 2768.36 | Level: 05 vijfde verdieping | 3222612
2679558 | 05 vijfde verdieping | 1774953 | 0.0253155 | 0 | 3026.05 | Level: 05 vijfde verdieping | 3549907
2679560 | 05 vijfde verdieping | 1774953 | 0.0253155 | 0 | 3026.05 | Level: 05 vijfde verdieping | 3549907
2679562 | 05 vijfde verdieping | 1415190 | 0.0201579 | 0 | 2459.54 | Level: 05 vijfde verdieping | 2830380
2679564 | 05 vijfde verdieping | 2501416 | 0.0357302 | 0 | 4185 | Level: 05 vijfde verdieping | 5002833
2679598 | 05 vijfde verdieping | 1833818 | 0.0261594 | 0 | 3183.74 | Level: 05 vijfde verdieping | 3667635
2679600 | 05 vijfde verdieping | 1611306 | 0.0229694 | 0 | 2768.36 | Level: 05 vijfde verdieping | 3222612
2679602 | 05 vijfde verdieping | 1774953 | 0.0253155 | 0 | 3026.05 | Level: 05 vijfde verdieping | 3549907
2679604 | 05 vijfde verdieping | 1774953 | 0.0253155 | 0 | 3026.05 | Level: 05 vijfde verdieping | 3549907
2679606 | 05 vijfde verdieping | 1415190 | 0.0201579 | 0 | 2459.54 | Level: 05 vijfde verdieping | 2830380
2679608 | 05 vijfde verdieping | 2501416 | 0.0357302 | 0 | 4185 | Level: 05 vijfde verdieping | 5002833
2679642 | 05 vijfde verdieping | 1833818 | 0.0261594 | 0 | 3183.74 | Level: 05 vijfde verdieping | 3667635
2679644 | 05 vijfde verdieping | 1611306 | 0.0229694 | 0 | 2768.36 | Level: 05 vijfde verdieping | 3222612
2679646 | 05 vijfde verdieping | 1774953 | 0.0253155 | 0 | 3026.05 | Level: 05 vijfde verdieping | 3549907
2679648 | 05 vijfde verdieping | 1774953 | 0.0253155 | 0 | 3026.05 | Level: 05 vijfde verdieping | 3549907
2679650 | 05 vijfde verdieping | 1415190 | 0.0201579 | 0 | 2459.54 | Level: 05 vijfde verdieping | 2830380
2679652 | 05 vijfde verdieping | 2501416 | 0.0357302 | 0 | 4185 | Level: 05 vijfde verdieping | 5002833
2679686 | 05 vijfde verdieping | 1833818 | 0.0261594 | 0 | 3183.74 | Level: 05 vijfde verdieping | 3667635
2679688 | 05 vijfde verdieping | 1611306 | 0.0229694 | 0 | 2768.36 | Level: 05 vijfde verdieping | 3222612
2679690 | 05 vijfde verdieping | 1774953 | 0.0253155 | 0 | 3026.05 | Level: 05 vijfde verdieping | 3549907
2679692 | 05 vijfde verdieping | 1774953 | 0.0253155 | 0 | 3026.05 | Level: 05 vijfde verdieping | 3549907
2679694 | 05 vijfde verdieping | 1415190 | 0.0201579 | 0 | 2459.54 | Level: 05 vijfde verdieping | 2830380
2679696 | 05 vijfde verdieping | 2501416 | 0.0357302 | 0 | 4185 | Level: 05 vijfde verdieping | 5002833
2679730 | 05 vijfde verdieping | 1833818 | 0.0261594 | 0 | 3183.74 | Level: 05 vijfde verdieping | 3667635
2679732 | 05 vijfde verdieping | 1052463 | 0.0149578 | 0 | 1778.36 | Level: 05 vijfde verdieping | 2104926
2679734 | 05 vijfde verdieping | 1774953 | 0.0253155 | 0 | 3026.05 | Level: 05 vijfde verdieping | 3549907
2679736 | 05 vijfde verdieping | 1774953 | 0.0253155 | 0 | 3026.05 | Level: 05 vijfde verdieping | 3549907
2679738 | 05 vijfde verdieping | 1107191 | 0.0157424 | 0 | 1974.54 | Level: 05 vijfde verdieping | 2214382
2679740 | 05 vijfde verdieping | 2250572 | 0.0321341 | 0 | 3790 | Level: 05 vijfde verdieping | 4501144
2679774 | 05 vijfde verdieping | 1833818 | 0.0261594 | 0 | 3183.74 | Level: 05 vijfde verdieping | 3667635
2679776 | 05 vijfde verdieping | 1052463 | 0.0149578 | 0 | 1778.36 | Level: 05 vijfde verdieping | 2104926
2679778 | 05 vijfde verdieping | 1774953 | 0.0253155 | 0 | 3026.05 | Level: 05 vijfde verdieping | 3549907
2679780 | 05 vijfde verdieping | 1774953 | 0.0253155 | 0 | 3026.05 | Level: 05 vijfde verdieping | 3549907
2679782 | 05 vijfde verdieping | 1107191 | 0.0157424 | 0 | 1974.54 | Level: 05 vijfde verdieping | 2214382
2679784 | 05 vijfde verdieping | 2250572 | 0.0321341 | 0 | 3790 | Level: 05 vijfde verdieping | 4501144
2872945 | 05 vijfde verdieping | 1382397 | 0.0196878 | 0 | 2162.5 | Level: 05 vijfde verdieping | 2764794
2873288 | 05 vijfde verdieping | 1482861 | 0.021128 | 0 | 2320.7 | Level: 05 vijfde verdieping | 2965723
3669622 | 04 vierde verdieping | 10666896 | 0.152792 | 0 | 15939.8 | Level: 04 vierde verdieping | 21333791
3669644 | 04 vierde verdieping | 2056672 | 0.0292784 | 32.1436 | 4003.44 | Level: 04 vierde verdieping | 4113345
3669654 | 04 vierde verdieping | 2083386 | 0.029661 | 31.6908 | 4054.55 | Level: 04 vierde verdieping | 4166773
3704589 | 03 derde verdieping | 1980460 | 0.0281756 | 39.5138 | 3772.02 | Level: 04 ok ruwe vloer paradezaal buitendoos | 3960919
3704595 | 03 derde verdieping | 1980460 | 0.0281756 | 39.5138 | 3772.02 | Level: 04 ok ruwe vloer paradezaal buitendoos | 3960919
3704603 | 03 derde verdieping | 11508093 | 0.164851 | 0 | 17460 | Level: 04 ok ruwe vloer paradezaal buitendoos | 23016186
4312505 | 05 vijfde verdieping | 3136719 | 0.044838 | 0 | 4925 | Level: 05 vijfde verdieping | 6273438
4312648 | 05 vijfde verdieping | 3152595 | 0.0450656 | 0 | 4950 | Level: 05 vijfde verdieping | 6305190
4313011 | 05 vijfde verdieping | 3152595 | 0.0450656 | 0 | 4950 | Level: 05 vijfde verdieping | 6305190
4313126 | 05 vijfde verdieping | 3136719 | 0.044838 | 0 | 4925 | Level: 05 vijfde verdieping | 6273438
4355863 | 05 vijfde verdieping | 3136719 | 0.044838 | 0 | 4925 | Level: 05 vijfde verdieping | 6273438
4355866 | 05 vijfde verdieping | 3136719 | 0.044838 | 0 | 4925 | Level: 05 vijfde verdieping | 6273438
4355986 | 05 vijfde verdieping | 3136719 | 0.044838 | 0 | 4925 | Level: 05 vijfde verdieping | 6273438
4355988 | 05 vijfde verdieping | 3136719 | 0.044838 | 0 | 4925 | Level: 05 vijfde verdieping | 6273438
4356244 | 05 vijfde verdieping | 3152595 | 0.0450656 | 0 | 4950 | Level: 05 vijfde verdieping | 6305190
4356246 | 05 vijfde verdieping | 3152595 | 0.0450656 | 0 | 4950 | Level: 05 vijfde verdieping | 6305190
4356450 | 05 vijfde verdieping | 3152595 | 0.0450656 | 0 | 4950 | Level: 05 vijfde verdieping | 6305190
4356452 | 05 vijfde verdieping | 3152595 | 0.0450656 | 0 | 4950 | Level: 05 vijfde verdieping | 6305190

# IfcBeam: 28_PBT_SF_staal_H-profiel:S355_HE240A, 28_PBT_SF_staal_H-profiel:S355_HE240A:2399531
In: 02 tweede verdieping
Type - Pset_BeamCommon - IsExternal: no; LoadBearing: yes
Type - Pset_ProductRequirements - Category: Structural Framing
Type - Pset_ReinforcementBarPitchOfBeam - Description: HE240A
Type - Pset_Pieters - Breedte: 240 mm; Hoogte: 230 mm; Codering - NL-SfB: 28.11; Omschrijving NL-SfB: hoofddraagconstructies - kolommen en liggers, kolom-/liggerconstructies; Materiaal: 00_PBT_MAT_staal_S355; Materiaalkwaliteit: S355; Description: HE240A
Classification: 28.11 hoofddraagconstructies - kolommen en liggers, kolom-/liggerconstructies (Uniformat); Material: 00_PBT_MAT_staal_S355
BaseQuantities - CrossSectionArea: 926247 mm2; NetVolume: 0.0103114 m3; Length: 1342 mm; NetSurfaceArea: 1852494 mm2
Pset_BeamCommon - Slope: 0 deg; Reference: 28_PBT_SF_staal_H-profiel:S355_HE240A; Span: 1342 mm
Pset_QuantityTakeOff - Reference: 28_PBT_SF_staal_H-profiel:S355_HE240A
Pset_ReinforcementBarPitchOfBeam - Reference: 28_PBT_SF_staal_H-profiel:S355_HE240A
Pset_Pieters - Bouwlaag: Level: 02 tweede verdieping; Naamgeving element: 28_PBT_SF_staal_H-profiel: S355_HE240A; Fase: Nieuw

# IfcBeam: 28_PBT_SF_staal_H-profiel:S355_HE240B (33)
Type - Pset_BeamCommon - IsExternal: no; LoadBearing: yes
Type - Pset_ProductRequirements - Category: Structural Framing
Type - Pset_ReinforcementBarPitchOfBeam - Description: HE240B
Type - Pset_Pieters - Breedte: 240 mm; Hoogte: 240 mm; Codering - NL-SfB: 28.11; Omschrijving NL-SfB: hoofddraagconstructies - kolommen en liggers, kolom-/liggerconstructies; Materiaal: 00_PBT_MAT_staal_S355; Materiaalkwaliteit: S355; Description: HE240B
Classification: 28.11 hoofddraagconstructies - kolommen en liggers, kolom-/liggerconstructies (Uniformat); Material: 00_PBT_MAT_staal_S355
Pset_BeamCommon - Reference: 28_PBT_SF_staal_H-profiel:S355_HE240B
Pset_QuantityTakeOff - Reference: 28_PBT_SF_staal_H-profiel:S355_HE240B
Pset_ReinforcementBarPitchOfBeam - Reference: 28_PBT_SF_staal_H-profiel:S355_HE240B
Pset_Pieters - Naamgeving element: 28_PBT_SF_staal_H-profiel: S355_HE240B; Fase: Nieuw
Name (28_PBT_SF_staal_H-profiel:S355_HE240B:...) | In | CrossSectionArea (mm2) | NetVolume (m3) | Span (mm) = Length (mm) | Slope (deg) | Bouwlaag | NetSurfaceArea (mm2)
2489975 | 05 vijfde verdieping | 1989195 | 0.0303052 | 4086.15 | 38.0768 | Level: 07 bk ruwe vloer bwd zuid | 3978390
2489977 | 05 vijfde verdieping | 1989195 | 0.0303052 | 4086.15 | 38.0768 | Level: 07 bk ruwe vloer bwd zuid | 3978390
2489979 | 05 vijfde verdieping | 1989195 | 0.0303052 | 4086.15 | 38.0768 | Level: 07 bk ruwe vloer bwd zuid | 3978390
2489981 | 05 vijfde verdieping | 1870348 | 0.0284849 | 3850.83 | 38.887 | Level: 07 bk ruwe vloer bwd zuid | 3740696
2490064 | 05 vijfde verdieping | 2145821 | 0.0326048 | 4302.84 | 35.8496 | Level: 07 bk ruwe vloer bwd zuid | 4291642
2490066 | 05 vijfde verdieping | 1992161 | 0.0303506 | 4092.65 | 38.0056 | Level: 07 bk ruwe vloer bwd zuid | 3984323
2490068 | 05 vijfde verdieping | 1989195 | 0.0303052 | 4086.15 | 38.0768 | Level: 07 bk ruwe vloer bwd zuid | 3978390
2490070 | 05 vijfde verdieping | 1992161 | 0.0303506 | 4092.65 | 38.0056 | Level: 07 bk ruwe vloer bwd zuid | 3984323
2490072 | 05 vijfde verdieping | 2219588 | 0.0337857 | 3850.83 | 38.887 | Level: 07 bk ruwe vloer bwd zuid | 4439176
2644793 | 05 vijfde verdieping | 2519913 | 0.0384339 | 4083.73 | 38.1034 | Level: 07 bk ruwe vloer bwd zuid | 5039825
2644795 | 05 vijfde verdieping | 2526131 | 0.0385292 | 4094.09 | 37.9899 | Level: 07 bk ruwe vloer bwd zuid | 5052262
2644797 | 05 vijfde verdieping | 2513739 | 0.0383393 | 4073.45 | 38.2169 | Level: 07 bk ruwe vloer bwd zuid | 5027477
2644799 | 05 vijfde verdieping | 2016504 | 0.0307234 | 3925.19 | 38.0633 | Level: 07 bk ruwe vloer bwd zuid | 4033008
2644939 | 05 vijfde verdieping | 1988753 | 0.0302984 | 4084.35 | 38.1144 | Level: 07 bk ruwe vloer bwd zuid | 3977505
2644941 | 05 vijfde verdieping | 1984059 | 0.0302265 | 4074.07 | 38.2279 | Level: 07 bk ruwe vloer bwd zuid | 3968119
2644943 | 05 vijfde verdieping | 1984059 | 0.0302265 | 4074.07 | 38.2279 | Level: 07 bk ruwe vloer bwd zuid | 3968119
2644945 | 05 vijfde verdieping | 1869257 | 0.0284681 | 3852.4 | 38.916 | Level: 07 bk ruwe vloer bwd zuid | 3738514
2690420 | 05 vijfde verdieping | 2083244 | 0.0317457 | 3526.47 | 28.1274 | Level: 07 bk ruwe vloer bwd zuid | 4166487
2690422 | 05 vijfde verdieping | 1916580 | 0.029193 | 3526.47 | 28.1274 | Level: 07 bk ruwe vloer bwd zuid | 3833161
2690424 | 05 vijfde verdieping | 1956455 | 0.0298037 | 3526.47 | 28.1274 | Level: 07 bk ruwe vloer bwd zuid | 3912910
2690426 | 05 vijfde verdieping | 2044500 | 0.0311523 | 3608.35 | 28.4232 | Level: 07 bk ruwe vloer bwd zuid | 4089000
2846772 | 03 derde verdieping | 2575720 | 0.039259 | 3800 | 60 | Level: 03 derde verdieping | 5151439
3599159 | 05 vijfde verdieping | 2221616 | 0.0336147 | 3625.93 | 40 | Level: 07 bk ruwe vloer bwd zuid | 4443233
3600887 | 02 tweede verdieping | 13133183 | 0.200992 | 18964 | 0 | Level: 03 ok ruwe vloer | 26266366
3600889 | 03 derde verdieping | 9417286 | 0.144078 | 13594 | 0 | Level: 04 ok ruwe vloer bwd zuid | 18834572
3872446 | 03 derde verdieping | 2575720 | 0.039259 | 3955 | 60 | Level: 03 derde verdieping | 5151439
4258446 | 03 derde verdieping | 2645237 | 0.0403238 | 4040 | 60 | Level: 03 derde verdieping | 5290473
4259597 | 03 derde verdieping | 2645237 | 0.0403238 | 4040 | 60 | Level: 03 derde verdieping | 5290473
4526431 | 05 vijfde verdieping | 2105202 | 0.032082 | 3027 | 0 | Level: 05 vijfde verdieping | 4210405
4526433 | 05 vijfde verdieping | 2115582 | 0.032241 | 3042 | 0 | Level: 05 vijfde verdieping | 4231164
4526435 | 05 vijfde verdieping | 2115582 | 0.032241 | 3042 | 0 | Level: 05 vijfde verdieping | 4231164
4526437 | 05 vijfde verdieping | 2115582 | 0.032241 | 3042 | 0 | Level: 05 vijfde verdieping | 4231164
4526439 | 05 vijfde verdieping | 2115582 | 0.032241 | 3042 | 0 | Level: 05 vijfde verdieping | 4231164

# IfcBeam: 28_PBT_SF_staal_H-profiel:S355_HE260A (10)
In: 04 vierde verdieping
Type - Pset_BeamCommon - IsExternal: no; LoadBearing: yes
Type - Pset_ProductRequirements - Category: Structural Framing
Type - Pset_ReinforcementBarPitchOfBeam - Description: HE260A
Type - Pset_Pieters - Breedte: 260 mm; Hoogte: 250 mm; Codering - NL-SfB: 28.11; Omschrijving NL-SfB: hoofddraagconstructies - kolommen en liggers, kolom-/liggerconstructies; Materiaal: 00_PBT_MAT_staal_S355; Materiaalkwaliteit: S355; Description: HE260A
Classification: 28.11 hoofddraagconstructies - kolommen en liggers, kolom-/liggerconstructies (Uniformat); Material: 00_PBT_MAT_staal_S355
Pset_BeamCommon - Reference: 28_PBT_SF_staal_H-profiel:S355_HE260A
Pset_QuantityTakeOff - Reference: 28_PBT_SF_staal_H-profiel:S355_HE260A
Pset_ReinforcementBarPitchOfBeam - Reference: 28_PBT_SF_staal_H-profiel:S355_HE260A
Pset_Pieters - Bouwlaag: Level: 04 vierde verdieping; Naamgeving element: 28_PBT_SF_staal_H-profiel: S355_HE260A; Fase: Nieuw
Name (28_PBT_SF_staal_H-profiel:S355_HE260A:...) | CrossSectionArea (mm2) | NetVolume (m3) | Slope (deg) | Span (mm) = Length (mm) | NetSurfaceArea (mm2)
3689381 | 1343802 | 0.0156242 | 90 | 2250 | 2687605
3689383 | 1343802 | 0.0156242 | 90 | 2250 | 2687605
3689385 | 1343802 | 0.0156242 | 90 | 2250 | 2687605
3689387 | 1274737 | 0.0147982 | 90 | 2250 | 2549474
3689389 | 1343802 | 0.0156242 | 90 | 2250 | 2687605
3689391 | 1343802 | 0.0156242 | 90 | 2250 | 2687605
3689393 | 1279975 | 0.01486 | 90 | 2250 | 2559950
3689399 | 2223915 | 0.0258521 | 36.4164 | 3790.12 | 4447830
3689401 | 2304010 | 0.0267827 | 35.112 | 3911.84 | 4608019
5855955 | 1596344 | 0.0185795 | 0 | 2140 | 3192689

# IfcBeam: 28_PBT_SF_staal_H-profiel:S355_HE260B (14)
Type - Pset_BeamCommon - IsExternal: no; LoadBearing: yes
Type - Pset_ProductRequirements - Category: Structural Framing
Type - Pset_ReinforcementBarPitchOfBeam - Description: HE260B
Type - Pset_Pieters - Breedte: 260 mm; Hoogte: 260 mm; Codering - NL-SfB: 28.11; Omschrijving NL-SfB: hoofddraagconstructies - kolommen en liggers, kolom-/liggerconstructies; Materiaal: 00_PBT_MAT_staal_S355; Materiaalkwaliteit: S355; Description: HE260B
Classification: 28.11 hoofddraagconstructies - kolommen en liggers, kolom-/liggerconstructies (Uniformat); Material: 00_PBT_MAT_staal_S355
Pset_BeamCommon - Reference: 28_PBT_SF_staal_H-profiel:S355_HE260B
Pset_QuantityTakeOff - Reference: 28_PBT_SF_staal_H-profiel:S355_HE260B
Pset_ReinforcementBarPitchOfBeam - Reference: 28_PBT_SF_staal_H-profiel:S355_HE260B
Pset_Pieters - Naamgeving element: 28_PBT_SF_staal_H-profiel: S355_HE260B; Fase: Nieuw
Name (28_PBT_SF_staal_H-profiel:S355_HE260B:...) | In | CrossSectionArea (mm2) | NetVolume (m3) | Span (mm) = Length (mm) | Slope (deg) | Bouwlaag | NetSurfaceArea (mm2)
2489973 | 05 vijfde verdieping | 2241359 | 0.0352383 | 4302.84 | 35.8496 | Level: 07 bk ruwe vloer bwd zuid | 4482719
2644803 | 05 vijfde verdieping | 2859939 | 0.0450152 | 4300.11 | 35.8759 | Level: 07 bk ruwe vloer bwd zuid | 5719878
2644949 | 05 vijfde verdieping | 2240748 | 0.0352286 | 4300.69 | 35.8867 | Level: 07 bk ruwe vloer bwd zuid | 4481497
2970775 | 04 vierde verdieping | 1249127 | 0.0191906 | 2640 | 16.3105 | Level: 04 vierde verdieping | 2498254
2970805 | 04 vierde verdieping | 1527313 | 0.0235995 | 3140 | 19.4479 | Level: 04 vierde verdieping | 3054625
2970999 | -1 kelder | 1249127 | 0.0191906 | 2640 | 16.3105 | Level: -1 kelder | 2498254
2971002 | -1 kelder | 1527313 | 0.0235995 | 3140 | 19.4479 | Level: -1 kelder | 3054625
3599157 | 05 vijfde verdieping | 2210277 | 0.034747 | 3850.83 | 38.887 | Level: 07 bk ruwe vloer bwd zuid | 4420554
3599161 | 05 vijfde verdieping | 2208988 | 0.0347267 | 3852.4 | 38.916 | Level: 07 bk ruwe vloer bwd zuid | 4417976
3599163 | 05 vijfde verdieping | 2208988 | 0.0347267 | 3852.4 | 38.916 | Level: 07 bk ruwe vloer bwd zuid | 4417976
3689397 | 04 vierde verdieping | 1965384 | 0.0307132 | 3363.41 | 41.9872 | Level: 04 vierde verdieping | 3930769
3689403 | 04 vierde verdieping | 1965385 | 0.0307132 | 3363.41 | 41.9872 | Level: 04 vierde verdieping | 3930770
3689407 | 04 vierde verdieping | 2066867 | 0.0323314 | 3514.61 | 39.8056 | Level: 04 vierde verdieping | 4133734
3689409 | 04 vierde verdieping | 2066866 | 0.0323314 | 3514.61 | 39.8056 | Level: 04 vierde verdieping | 4133733

# IfcBeam: 28_PBT_SF_staal_H-profiel:S355_HE280A (3)
In: 03 derde verdieping
Type - Pset_BeamCommon - IsExternal: no; LoadBearing: yes
Type - Pset_ProductRequirements - Category: Structural Framing
Type - Pset_ReinforcementBarPitchOfBeam - Description: HE280A
Type - Pset_Pieters - Breedte: 280 mm; Hoogte: 270 mm; Codering - NL-SfB: 28.11; Omschrijving NL-SfB: hoofddraagconstructies - kolommen en liggers, kolom-/liggerconstructies; Materiaal: 00_PBT_MAT_staal_S355; Materiaalkwaliteit: S355; Description: HE280A
Classification: 28.11 hoofddraagconstructies - kolommen en liggers, kolom-/liggerconstructies (Uniformat); Material: 00_PBT_MAT_staal_S355
Pset_BeamCommon - Slope: 0 deg; Reference: 28_PBT_SF_staal_H-profiel:S355_HE280A
Pset_QuantityTakeOff - Reference: 28_PBT_SF_staal_H-profiel:S355_HE280A
Pset_ReinforcementBarPitchOfBeam - Reference: 28_PBT_SF_staal_H-profiel:S355_HE280A
Pset_Pieters - Bouwlaag: Level: 03 derde verdieping; Naamgeving element: 28_PBT_SF_staal_H-profiel: S355_HE280A; Fase: Nieuw
Name (28_PBT_SF_staal_H-profiel:S355_HE280A:...) | CrossSectionArea (mm2) | NetVolume (m3) | Span (mm) = Length (mm) | NetSurfaceArea (mm2)
2529954 | 4050163 | 0.0490385 | 5041.73 | 8100326
2530096 | 3596899 | 0.0435373 | 4476.14 | 7193798
2530211 | 4050163 | 0.0490385 | 5041.73 | 8100326

# IfcBeam: 28_PBT_SF_staal_H-profiel:S355_HE280B (8)
Type - Pset_BeamCommon - IsExternal: no; LoadBearing: yes
Type - Pset_ProductRequirements - Category: Structural Framing
Type - Pset_ReinforcementBarPitchOfBeam - Description: HE280B
Type - Pset_Pieters - Breedte: 280 mm; Hoogte: 280 mm; Codering - NL-SfB: 28.11; Omschrijving NL-SfB: hoofddraagconstructies - kolommen en liggers, kolom-/liggerconstructies; Materiaal: 00_PBT_MAT_staal_S355; Materiaalkwaliteit: S355; Description: HE280B
Classification: 28.11 hoofddraagconstructies - kolommen en liggers, kolom-/liggerconstructies (Uniformat); Material: 00_PBT_MAT_staal_S355
Pset_BeamCommon - Slope: 0 deg; Reference: 28_PBT_SF_staal_H-profiel:S355_HE280B
Pset_QuantityTakeOff - Reference: 28_PBT_SF_staal_H-profiel:S355_HE280B
Pset_ReinforcementBarPitchOfBeam - Reference: 28_PBT_SF_staal_H-profiel:S355_HE280B
Pset_Pieters - Naamgeving element: 28_PBT_SF_staal_H-profiel: S355_HE280B; Fase: Nieuw
Name (28_PBT_SF_staal_H-profiel:S355_HE280B:...) | In | CrossSectionArea (mm2) | NetVolume (m3) | Span (mm) = Length (mm) | Bouwlaag | NetSurfaceArea (mm2)
2362754 | 02 tweede verdieping | 704689 | 0.0112308 | 854.931 | Level: 02 tweede verdieping | 1409378
2400074 | 02 tweede verdieping | 716014 | 0.0114147 | 868.931 | Level: 02 tweede verdieping | 1432027
2400200 | 02 tweede verdieping | 716014 | 0.0114147 | 868.931 | Level: 02 tweede verdieping | 1432027
2400220 | 02 tweede verdieping | 716014 | 0.0114147 | 868.931 | Level: 02 tweede verdieping | 1432027
2400240 | 02 tweede verdieping | 716014 | 0.0114147 | 868.931 | Level: 02 tweede verdieping | 1432027
3814043 | 02 tweede verdieping | 3653179 | 0.0591143 | 4000 | Level: 02 tweede verdieping | 7306358
4403636 | 05 vijfde verdieping | 2491763 | 0.0402529 | 3064.2 | Level: 05 vijfde verdieping | 4983526
4405419 | 05 vijfde verdieping | 2491763 | 0.0402529 | 3064.2 | Level: 05 vijfde verdieping | 4983526

# IfcBeam: 28_PBT_SF_staal_H-profiel:S355_HE300A, 28_PBT_SF_staal_H-profiel:S355_HE300A:4321634
In: 05 vijfde verdieping
Type - Pset_BeamCommon - IsExternal: no; LoadBearing: yes
Type - Pset_ProductRequirements - Category: Structural Framing
Type - Pset_ReinforcementBarPitchOfBeam - Description: HE300A
Type - Pset_Pieters - Breedte: 300 mm; Hoogte: 290 mm; Codering - NL-SfB: 28.11; Omschrijving NL-SfB: hoofddraagconstructies - kolommen en liggers, kolom-/liggerconstructies; Materiaal: 00_PBT_MAT_staal_S355; Materiaalkwaliteit: S355; Description: HE300A
Classification: 28.11 hoofddraagconstructies - kolommen en liggers, kolom-/liggerconstructies (Uniformat); Material: 00_PBT_MAT_staal_S355
BaseQuantities - CrossSectionArea: 17426627 mm2; NetVolume: 0.228321 m3; Length: 20290 mm; NetSurfaceArea: 34853254 mm2
Pset_BeamCommon - Slope: 0 deg; Reference: 28_PBT_SF_staal_H-profiel:S355_HE300A; Span: 20290 mm
Pset_QuantityTakeOff - Reference: 28_PBT_SF_staal_H-profiel:S355_HE300A
Pset_ReinforcementBarPitchOfBeam - Reference: 28_PBT_SF_staal_H-profiel:S355_HE300A
Pset_Pieters - Bouwlaag: Level: 05 vijfde verdieping; Naamgeving element: 28_PBT_SF_staal_H-profiel: S355_HE300A; Fase: Nieuw

# IfcBeam: 28_PBT_SF_staal_H-profiel:S355_HE300B (12)
Type - Pset_BeamCommon - IsExternal: no; LoadBearing: yes
Type - Pset_ProductRequirements - Category: Structural Framing
Type - Pset_ReinforcementBarPitchOfBeam - Description: HE300B
Type - Pset_Pieters - Breedte: 300 mm; Hoogte: 300 mm; Codering - NL-SfB: 28.11; Omschrijving NL-SfB: hoofddraagconstructies - kolommen en liggers, kolom-/liggerconstructies; Materiaal: 00_PBT_MAT_staal_S355; Materiaalkwaliteit: S355; Description: HE300B
Classification: 28.11 hoofddraagconstructies - kolommen en liggers, kolom-/liggerconstructies (Uniformat); Material: 00_PBT_MAT_staal_S355
Pset_BeamCommon - Reference: 28_PBT_SF_staal_H-profiel:S355_HE300B
Pset_QuantityTakeOff - Reference: 28_PBT_SF_staal_H-profiel:S355_HE300B
Pset_ReinforcementBarPitchOfBeam - Reference: 28_PBT_SF_staal_H-profiel:S355_HE300B
Pset_Pieters - Naamgeving element: 28_PBT_SF_staal_H-profiel: S355_HE300B; Fase: Nieuw
Name (28_PBT_SF_staal_H-profiel:S355_HE300B:...) | In | CrossSectionArea (mm2) | NetVolume (m3) | Slope (deg) | Span (mm) = Length (mm) | Bouwlaag | NetSurfaceArea (mm2)
2315317 | -2 kelder | 9586497 | 0.164805 | 0 | 11242.6 | Level: NAP | 19172995
2315319 | -2 kelder | 9599484 | 0.165029 | 0 | 11132.6 | Level: NAP | 19198968
2398780 | 05 vijfde verdieping | 3297732 | 0.0565242 | 0 | 3791.56 | Level: 05 vijfde verdieping | 6595464
2398782 | 05 vijfde verdieping | 3296070 | 0.0564955 | 0 | 3789.64 | Level: 05 vijfde verdieping | 6592139
2398784 | 05 vijfde verdieping | 3296070 | 0.0564955 | 0 | 3789.64 | Level: 05 vijfde verdieping | 6592139
2868189 | 03 derde verdieping | 5455351 | 0.0936744 | 0 | 6283.55 | Level: 03 derde verdieping | 10910702
3588231 | 05 vijfde verdieping | 3296070 | 0.0564955 | 0 | 3789.64 | Level: 05 vijfde verdieping | 6592139
3588248 | 05 vijfde verdieping | 3296070 | 0.0564955 | 0 | 3789.64 | Level: 05 vijfde verdieping | 6592139
3702619 | 04 vierde verdieping | 20149276 | 0.346677 | 0 | 23580 | Level: 05 ok ruwe vloer bwd zuid | 40298552
4714035 | 05 vijfde verdieping | 2743620 | 0.0469834 | 25.9134 | 3400 | Level: 07 bk ruwe vloer bwd zuid | 5487240
4714037 | 05 vijfde verdieping | 10763754 | 0.185075 | 0 | 12440 | Level: 07 bk ruwe vloer bwd zuid | 21527509
4714045 | 05 vijfde verdieping | 2014147 | 0.0344232 | 27.9747 | 4061.12 | Level: 07 bk ruwe vloer bwd zuid | 4028293

# IfcBeam: 28_PBT_SF_staal_H-profiel:S355_HE320B (2)
In: 04 vierde verdieping
Type - Pset_BeamCommon - IsExternal: no; LoadBearing: yes
Type - Pset_ProductRequirements - Category: Structural Framing
Type - Pset_ReinforcementBarPitchOfBeam - Description: HE320B
Type - Pset_Pieters - Breedte: 300 mm; Hoogte: 320 mm; Codering - NL-SfB: 28.11; Omschrijving NL-SfB: hoofddraagconstructies - kolommen en liggers, kolom-/liggerconstructies; Materiaal: 00_PBT_MAT_staal_S355; Materiaalkwaliteit: S355; Description: HE320B
Classification: 28.11 hoofddraagconstructies - kolommen en liggers, kolom-/liggerconstructies (Uniformat); Material: 00_PBT_MAT_staal_S355
Pset_BeamCommon - Slope: 0 deg; Reference: 28_PBT_SF_staal_H-profiel:S355_HE320B
Pset_QuantityTakeOff - Reference: 28_PBT_SF_staal_H-profiel:S355_HE320B
Pset_ReinforcementBarPitchOfBeam - Reference: 28_PBT_SF_staal_H-profiel:S355_HE320B
Pset_Pieters - Naamgeving element: 28_PBT_SF_staal_H-profiel: S355_HE320B; Fase: Nieuw
Name (28_PBT_SF_staal_H-profiel:S355_HE320B:...) | CrossSectionArea (mm2) | NetVolume (m3) | Span (mm) = Length (mm) | Bouwlaag | NetSurfaceArea (mm2)
3669624 | 20110400 | 0.366203 | 23079.6 | Level: 05 dak bwd midden | 40220799
3704605 | 20603967 | 0.375198 | 23580 | Level: 05 ok ruwe vloer bwd zuid | 41207934

# IfcBeam: 28_PBT_SF_staal_H-profiel:S355_HE360B (4)
In: 05 vijfde verdieping
Type - Pset_BeamCommon - IsExternal: no; LoadBearing: yes
Type - Pset_ProductRequirements - Category: Structural Framing
Type - Pset_ReinforcementBarPitchOfBeam - Description: HE360B
Type - Pset_Pieters - Breedte: 300 mm; Hoogte: 360 mm; Codering - NL-SfB: 28.11; Omschrijving NL-SfB: hoofddraagconstructies - kolommen en liggers, kolom-/liggerconstructies; Materiaal: 00_PBT_MAT_staal_S355; Materiaalkwaliteit: S355; Description: HE360B
Classification: 28.11 hoofddraagconstructies - kolommen en liggers, kolom-/liggerconstructies (Uniformat); Material: 00_PBT_MAT_staal_S355
Pset_BeamCommon - Slope: 0 deg; Reference: 28_PBT_SF_staal_H-profiel:S355_HE360B
Pset_QuantityTakeOff - Reference: 28_PBT_SF_staal_H-profiel:S355_HE360B
Pset_ReinforcementBarPitchOfBeam - Reference: 28_PBT_SF_staal_H-profiel:S355_HE360B
Pset_Pieters - Bouwlaag: Level: 07 bk ruwe vloer bwd zuid; Naamgeving element: 28_PBT_SF_staal_H-profiel: S355_HE360B; Fase: Nieuw
Name (28_PBT_SF_staal_H-profiel:S355_HE360B:...) | CrossSectionArea (mm2) | NetVolume (m3) | Span (mm) = Length (mm) | NetSurfaceArea (mm2)
4671535 | 13871019 | 0.270718 | 14987.1 | 27742039
4671539 | 13960022 | 0.272458 | 15083.4 | 27920045
4671543 | 13871019 | 0.270718 | 14987.1 | 27742039
4671547 | 13871019 | 0.270718 | 14987.1 | 27742039

# IfcBeam: 28_PBT_SF_staal_H-profiel:S355_HE400B (6)
Type - Pset_BeamCommon - IsExternal: no; LoadBearing: yes
Type - Pset_ProductRequirements - Category: Structural Framing
Type - Pset_ReinforcementBarPitchOfBeam - Description: HE400B
Type - Pset_Pieters - Breedte: 300 mm; Hoogte: 400 mm; Codering - NL-SfB: 28.11; Omschrijving NL-SfB: hoofddraagconstructies - kolommen en liggers, kolom-/liggerconstructies; Materiaal: 00_PBT_MAT_staal_S355; Materiaalkwaliteit: S355; Description: HE400B
Classification: 28.11 hoofddraagconstructies - kolommen en liggers, kolom-/liggerconstructies (Uniformat); Material: 00_PBT_MAT_staal_S355
Pset_BeamCommon - Reference: 28_PBT_SF_staal_H-profiel:S355_HE400B
Pset_QuantityTakeOff - Reference: 28_PBT_SF_staal_H-profiel:S355_HE400B
Pset_ReinforcementBarPitchOfBeam - Reference: 28_PBT_SF_staal_H-profiel:S355_HE400B
Pset_Pieters - Naamgeving element: 28_PBT_SF_staal_H-profiel: S355_HE400B; Fase: Nieuw
Name (28_PBT_SF_staal_H-profiel:S355_HE400B:...) | In | CrossSectionArea (mm2) | NetVolume (m3) | Slope (deg) | Span (mm) = Length (mm) | Bouwlaag | NetSurfaceArea (mm2)
2963310 | 04 vierde verdieping | 10882811 | 0.223028 | 0 | 11276.6 | Level: 04 vierde verdieping | 21765621
2964126 | 04 vierde verdieping | 10882811 | 0.223028 | 0 | 11276.6 | Level: 04 vierde verdieping | 21765621
3611469 | 03 derde verdieping | 6017427 | 0.123137 | 0 | 6226 | Level: 04 ok ruwe vloer bwd zuid | 12034855
3689377 | 04 vierde verdieping | 16177831 | 0.331739 | 0 | 16650 | Level: 04 vierde verdieping | 32355662
3689395 | 04 vierde verdieping | 2922257 | 0.0595476 | 40.8724 | 3438.39 | Level: 04 vierde verdieping | 5844513
3689405 | 04 vierde verdieping | 2805758 | 0.057128 | 42.5634 | 3326.41 | Level: 04 vierde verdieping | 5611516

# IfcBeam: 28_PBT_SF_staal_H-profiel:S355_HE450B, 28_PBT_SF_staal_H-profiel:S355_HE450B:3689379
In: 04 vierde verdieping
Type - Pset_BeamCommon - IsExternal: no; LoadBearing: yes
Type - Pset_ProductRequirements - Category: Structural Framing
Type - Pset_ReinforcementBarPitchOfBeam - Description: HE450B
Type - Pset_Pieters - Breedte: 300 mm; Hoogte: 450 mm; Codering - NL-SfB: 28.11; Omschrijving NL-SfB: hoofddraagconstructies - kolommen en liggers, kolom-/liggerconstructies; Materiaal: 00_PBT_MAT_staal_S355; Materiaalkwaliteit: S355; Description: HE450B
Classification: 28.11 hoofddraagconstructies - kolommen en liggers, kolom-/liggerconstructies (Uniformat); Material: 00_PBT_MAT_staal_S355
BaseQuantities - CrossSectionArea: 22312787 mm2; NetVolume: 0.479744 m3; Length: 22200 mm; NetSurfaceArea: 44625574 mm2
Pset_BeamCommon - Slope: 0 deg; Reference: 28_PBT_SF_staal_H-profiel:S355_HE450B; Span: 22200 mm
Pset_QuantityTakeOff - Reference: 28_PBT_SF_staal_H-profiel:S355_HE450B
Pset_ReinforcementBarPitchOfBeam - Reference: 28_PBT_SF_staal_H-profiel:S355_HE450B
Pset_Pieters - Bouwlaag: Level: 05 dak bwd midden; Naamgeving element: 28_PBT_SF_staal_H-profiel: S355_HE450B; Fase: Nieuw

# IfcBeam: 28_PBT_SF_staal_H-profiel:S355_HE600B (2)
In: 03 derde verdieping
Type - Pset_BeamCommon - IsExternal: no; LoadBearing: yes
Type - Pset_ProductRequirements - Category: Structural Framing
Type - Pset_ReinforcementBarPitchOfBeam - Description: HE600B
Type - Pset_Pieters - Breedte: 300 mm; Hoogte: 600 mm; Codering - NL-SfB: 28.11; Omschrijving NL-SfB: hoofddraagconstructies - kolommen en liggers, kolom-/liggerconstructies; Materiaal: 00_PBT_MAT_staal_S355; Materiaalkwaliteit: S355; Description: HE600B
Classification: 28.11 hoofddraagconstructies - kolommen en liggers, kolom-/liggerconstructies (Uniformat); Material: 00_PBT_MAT_staal_S355
Pset_BeamCommon - Slope: 0 deg; Reference: 28_PBT_SF_staal_H-profiel:S355_HE600B
Pset_QuantityTakeOff - Reference: 28_PBT_SF_staal_H-profiel:S355_HE600B
Pset_ReinforcementBarPitchOfBeam - Reference: 28_PBT_SF_staal_H-profiel:S355_HE600B
Pset_Pieters - Naamgeving element: 28_PBT_SF_staal_H-profiel: S355_HE600B; Fase: Nieuw
Name (28_PBT_SF_staal_H-profiel:S355_HE600B:...) | CrossSectionArea (mm2) | NetVolume (m3) | Span (mm) = Length (mm) | Bouwlaag | NetSurfaceArea (mm2)
2276159 | 12966824 | 0.300797 | 11155 | Level: 04 bk staal paradezaal binnendoos | 25933648
2278884 | 12931985 | 0.299987 | 11125 | Level: 03 derde verdieping | 25863969

# IfcBeam: 28_PBT_SF_staal_H-profiel_geknikt:S355_HE500B_knikhoogte=275, 28_PBT_SF_staal_H-profiel_geknikt:S355_HE500B_knikhoogte=275:2530737
In: 03 derde verdieping
Type - PredefinedType: BEAM; Classification: 28.11 hoofddraagconstructies - kolommen en liggers, kolom-/liggerconstructies (Uniformat); Material: 00_PBT_MAT_staal_S355
Type - Pset_BeamCommon - IsExternal: no; LoadBearing: yes
Type - Pset_ProductRequirements - Category: Structural Framing
Type - Pset_ReinforcementBarPitchOfBeam - Description: HE500B
Type - Pset_Pieters - Breedte: 300 mm; Hoogte: 500 mm; Codering - NL-SfB: 28.11; Omschrijving NL-SfB: hoofddraagconstructies - kolommen en liggers, kolom-/liggerconstructies; Materiaal: 00_PBT_MAT_staal_S355; Materiaalkwaliteit: S355; Description: HE500B
Pset_BeamCommon - Slope: 0 deg; Reference: 28_PBT_SF_staal_H-profiel_geknikt:S355_HE500B_knikhoogte=275; Span: 2404.15 mm
Pset_QuantityTakeOff - Reference: 28_PBT_SF_staal_H-profiel_geknikt:S355_HE500B_knikhoogte=275
Pset_ReinforcementBarPitchOfBeam - Reference: 28_PBT_SF_staal_H-profiel_geknikt:S355_HE500B_knikhoogte=275
Pset_Pieters - Bouwlaag: Level: 03 derde verdieping; Naamgeving element: 28_PBT_SF_staal_H-profiel_geknikt: S355_HE500B_knikhoogte=275; Fase: Nieuw
BaseQuantities - Length: 2404.15 mm; CrossSectionArea: 5461628 mm2; NetVolume: 0.127545 m3; NetSurfaceArea: 10923255 mm2

# IfcBeam: 28_PBT_SF_staal_H-profiel_geknikt:S355_HE500B_knikhoogte=335 (2)
In: 03 derde verdieping
Type - PredefinedType: BEAM; Classification: 28.11 hoofddraagconstructies - kolommen en liggers, kolom-/liggerconstructies (Uniformat); Material: 00_PBT_MAT_staal_S355
Type - Pset_BeamCommon - IsExternal: no; LoadBearing: yes
Type - Pset_ProductRequirements - Category: Structural Framing
Type - Pset_ReinforcementBarPitchOfBeam - Description: HE500B
Type - Pset_Pieters - Breedte: 300 mm; Hoogte: 500 mm; Codering - NL-SfB: 28.11; Omschrijving NL-SfB: hoofddraagconstructies - kolommen en liggers, kolom-/liggerconstructies; Materiaal: 00_PBT_MAT_staal_S355; Materiaalkwaliteit: S355; Description: HE500B
Pset_BeamCommon - Slope: 0 deg; Reference: 28_PBT_SF_staal_H-profiel_geknikt:S355_HE500B_knikhoogte=335
Pset_QuantityTakeOff - Reference: 28_PBT_SF_staal_H-profiel_geknikt:S355_HE500B_knikhoogte=335
Pset_ReinforcementBarPitchOfBeam - Reference: 28_PBT_SF_staal_H-profiel_geknikt:S355_HE500B_knikhoogte=335
Pset_Pieters - Bouwlaag: Level: 03 derde verdieping; Naamgeving element: 28_PBT_SF_staal_H-profiel_geknikt: S355_HE500B_knikhoogte=335; Fase: Nieuw
Name (28_PBT_SF_staal_H-profiel_geknikt:S355_HE500B_knikhoogte=335:...) | Span (mm) = Length (mm) | CrossSectionArea (mm2) | NetVolume (m3) | NetSurfaceArea (mm2)
2525202 | 6620 | 7836025 | 0.180939 | 15672050
2529843 | 6640 | 7857272 | 0.181416 | 15714543

# IfcBeam: 28_PBT_SF_staal_H-profiel_geknikt:S355_HE550B_knikhoogte=210, 28_PBT_SF_staal_H-profiel_geknikt:S355_HE550B_knikhoogte=210:5345146
In: 04 vierde verdieping
Type - PredefinedType: BEAM; Classification: 28.11 hoofddraagconstructies - kolommen en liggers, kolom-/liggerconstructies (Uniformat); Material: 00_PBT_MAT_staal_S355
Type - Pset_BeamCommon - IsExternal: no; LoadBearing: yes
Type - Pset_ProductRequirements - Category: Structural Framing
Type - Pset_ReinforcementBarPitchOfBeam - Description: HE550B
Type - Pset_Pieters - Breedte: 300 mm; Hoogte: 550 mm; Codering - NL-SfB: 28.11; Omschrijving NL-SfB: hoofddraagconstructies - kolommen en liggers, kolom-/liggerconstructies; Materiaal: 00_PBT_MAT_staal_S355; Materiaalkwaliteit: S355; Description: HE550B
Pset_BeamCommon - Slope: 0 deg; Reference: 28_PBT_SF_staal_H-profiel_geknikt:S355_HE550B_knikhoogte=210; Span: 900 mm
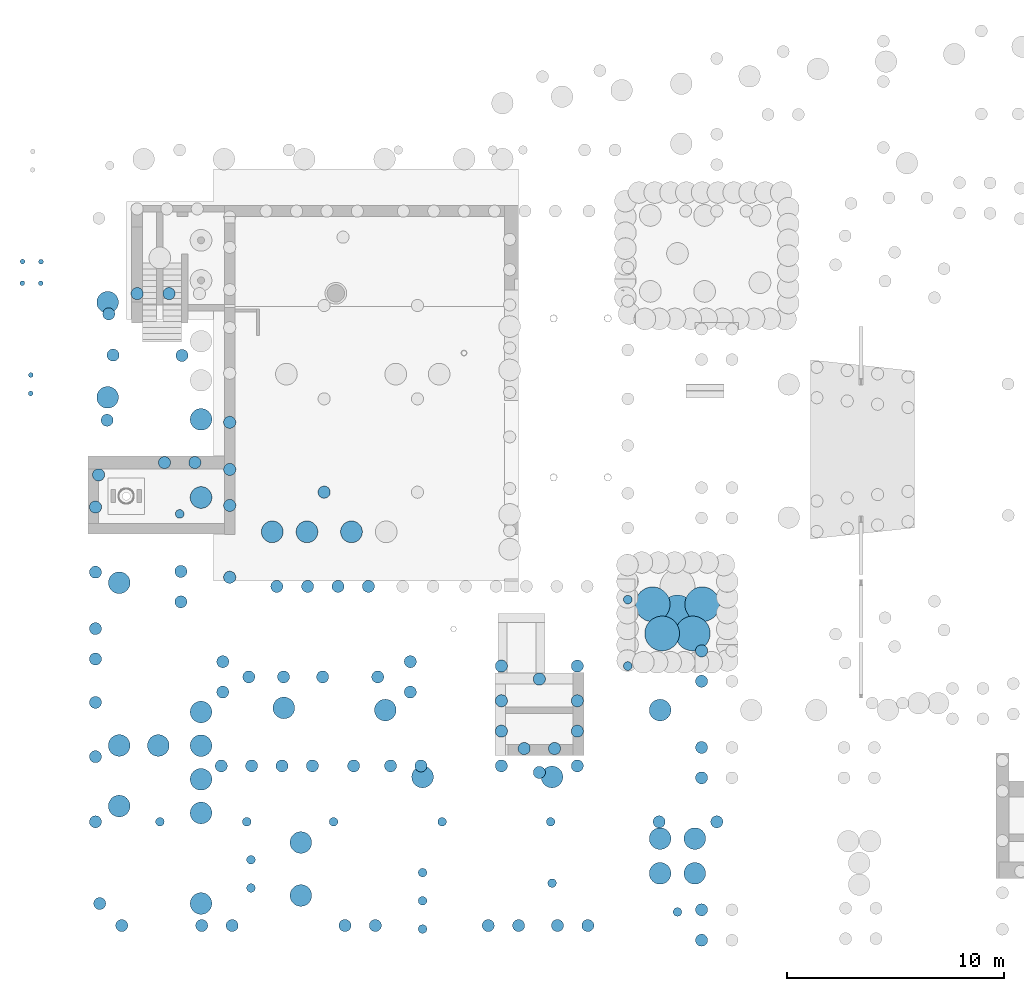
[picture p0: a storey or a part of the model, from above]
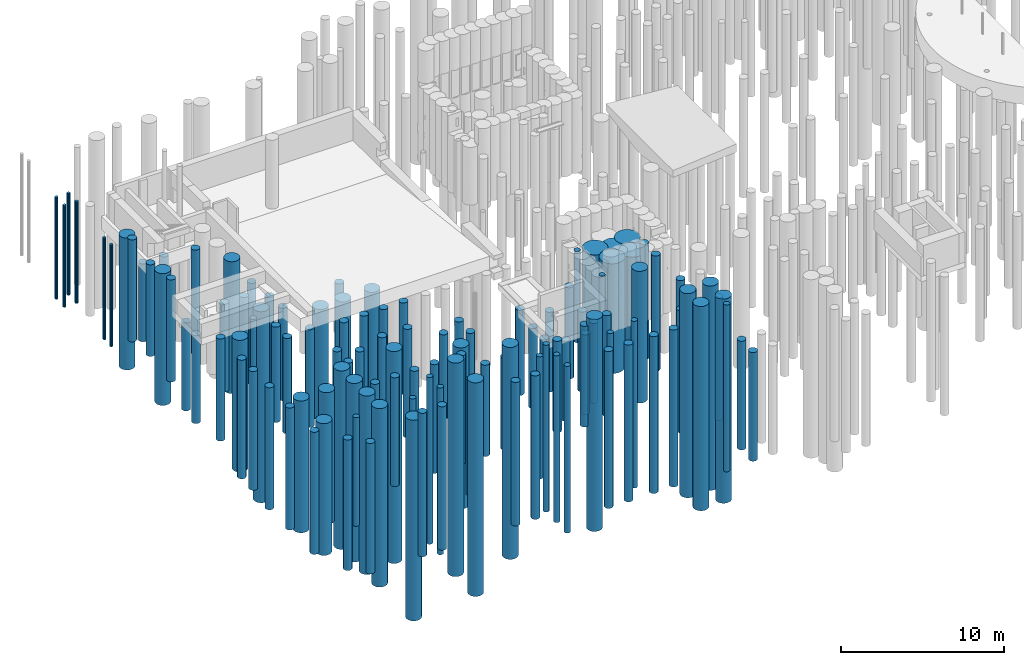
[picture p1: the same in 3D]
Properties of the parts of a building model (IFC2X3), part 4 of 18

# IfcBeam: 28_PBT_SF_staal_H-profiel_geknikt:S355_HE550B_knikhoogte=210, 28_PBT_SF_staal_H-profiel_geknikt:S355_HE550B_knikhoogte=210:5345146
Pset_QuantityTakeOff - Reference: 28_PBT_SF_staal_H-profiel_geknikt:S355_HE550B_knikhoogte=210
Pset_ReinforcementBarPitchOfBeam - Reference: 28_PBT_SF_staal_H-profiel_geknikt:S355_HE550B_knikhoogte=210
Pset_Pieters - Bouwlaag: Level: 04 vierde verdieping; Naamgeving element: 28_PBT_SF_staal_H-profiel_geknikt: S355_HE550B_knikhoogte=210; Fase: Nieuw
BaseQuantities - Length: 900 mm; CrossSectionArea: 1787265 mm2; NetVolume: 0.0459337 m3; NetSurfaceArea: 3574529 mm2

# IfcBeam: 28_PBT_SF_staal_H-profiel_geknikt:S355_HE550B_knikhoogte=335, 28_PBT_SF_staal_H-profiel_geknikt:S355_HE550B_knikhoogte=335:2530340
In: 03 derde verdieping
Type - PredefinedType: BEAM; Classification: 28.11 hoofddraagconstructies - kolommen en liggers, kolom-/liggerconstructies (Uniformat); Material: 00_PBT_MAT_staal_S355
Type - Pset_BeamCommon - IsExternal: no; LoadBearing: yes
Type - Pset_ProductRequirements - Category: Structural Framing
Type - Pset_ReinforcementBarPitchOfBeam - Description: HE550B
Type - Pset_Pieters - Breedte: 300 mm; Hoogte: 550 mm; Codering - NL-SfB: 28.11; Omschrijving NL-SfB: hoofddraagconstructies - kolommen en liggers, kolom-/liggerconstructies; Materiaal: 00_PBT_MAT_staal_S355; Materiaalkwaliteit: S355; Description: HE550B
Pset_BeamCommon - Slope: 0 deg; Reference: 28_PBT_SF_staal_H-profiel_geknikt:S355_HE550B_knikhoogte=335; Span: 7760 mm
Pset_QuantityTakeOff - Reference: 28_PBT_SF_staal_H-profiel_geknikt:S355_HE550B_knikhoogte=335
Pset_ReinforcementBarPitchOfBeam - Reference: 28_PBT_SF_staal_H-profiel_geknikt:S355_HE550B_knikhoogte=335
Pset_Pieters - Bouwlaag: Level: 03 derde verdieping; Naamgeving element: 28_PBT_SF_staal_H-profiel_geknikt: S355_HE550B_knikhoogte=335; Fase: Nieuw
BaseQuantities - Length: 7760 mm; CrossSectionArea: 9484861 mm2; NetVolume: 0.22213 m3; NetSurfaceArea: 18969721 mm2

# IfcBeam: 28_PBT_SF_staal_H-profiel_geknikt_met onderplaat:S355_HE400B_d=15_knikhoogte=460, 28_PBT_SF_staal_H-profiel_geknikt_met onderplaat:S355_HE400B_d=15_knikhoogte=460:3873777
In: 03 derde verdieping
Type - PredefinedType: BEAM; Classification: 28.11 hoofddraagconstructies - kolommen en liggers, kolom-/liggerconstructies (Uniformat); Material: 00_PBT_MAT_staal_S355
Type - Pset_BeamCommon - IsExternal: no; LoadBearing: yes
Type - Pset_ProductRequirements - Category: Structural Framing
Type - Pset_ReinforcementBarPitchOfBeam - Description: HE400B + onderplaat d=15
Type - Pset_Pieters - Breedte: 300 mm; Hoogte: 400 mm; Codering - NL-SfB: 28.11; Omschrijving NL-SfB: hoofddraagconstructies - kolommen en liggers, kolom-/liggerconstructies; Materiaal: 00_PBT_MAT_staal_S355; Materiaalkwaliteit: S355; Description: HE400B + onderplaat d=15
Pset_BeamCommon - Slope: 0 deg; Reference: 28_PBT_SF_staal_H-profiel_geknikt_met onderplaat:S355_HE400B_d=15_knikhoogte=460; Span: 6980 mm
Pset_QuantityTakeOff - Reference: 28_PBT_SF_staal_H-profiel_geknikt_met onderplaat:S355_HE400B_d=15_knikhoogte=460
Pset_ReinforcementBarPitchOfBeam - Reference: 28_PBT_SF_staal_H-profiel_geknikt_met onderplaat:S355_HE400B_d=15_knikhoogte=460
Pset_Pieters - Bouwlaag: Level: 03 derde verdieping; Naamgeving element: 28_PBT_SF_staal_H-profiel_geknikt_met onderplaat: S355_HE400B_d=15_knikhoogte=460; Fase: Nieuw
BaseQuantities - Length: 6980 mm; CrossSectionArea: 15523468 mm2; NetVolume: 0.273732 m3; NetSurfaceArea: 31046936 mm2

# IfcBeam: 28_PBT_SF_staal_H-profiel_geknikt_met onderplaat:S355_HE400B_d=30_knikhoogte=460 (2)
In: 03 derde verdieping
Type - PredefinedType: BEAM; Classification: 28.11 hoofddraagconstructies - kolommen en liggers, kolom-/liggerconstructies (Uniformat); Material: 00_PBT_MAT_staal_S355
Type - Pset_BeamCommon - IsExternal: no; LoadBearing: yes
Type - Pset_ProductRequirements - Category: Structural Framing
Type - Pset_ReinforcementBarPitchOfBeam - Description: HE400B + onderplaat d=30
Type - Pset_Pieters - Breedte: 300 mm; Hoogte: 400 mm; Codering - NL-SfB: 28.11; Omschrijving NL-SfB: hoofddraagconstructies - kolommen en liggers, kolom-/liggerconstructies; Materiaal: 00_PBT_MAT_staal_S355; Materiaalkwaliteit: S355; Description: HE400B + onderplaat d=30
Pset_BeamCommon - Slope: 0 deg; Reference: 28_PBT_SF_staal_H-profiel_geknikt_met onderplaat:S355_HE400B_d=30_knikhoogte=460
Pset_QuantityTakeOff - Reference: 28_PBT_SF_staal_H-profiel_geknikt_met onderplaat:S355_HE400B_d=30_knikhoogte=460
Pset_ReinforcementBarPitchOfBeam - Reference: 28_PBT_SF_staal_H-profiel_geknikt_met onderplaat:S355_HE400B_d=30_knikhoogte=460
Pset_Pieters - Bouwlaag: Level: 03 derde verdieping; Naamgeving element: 28_PBT_SF_staal_H-profiel_geknikt_met onderplaat: S355_HE400B_d=30_knikhoogte=460; Fase: Nieuw
Name (28_PBT_SF_staal_H-profiel_geknikt_met onderplaat:S355_HE400B_d=30_knikhoogte=460:...) | Span (mm) = Length (mm) | CrossSectionArea (mm2) | NetVolume (m3) | NetSurfaceArea (mm2)
2453547 | 7440 | 15866887 | 0.391169 | 31733774
2845420 | 6680 | 14476627 | 0.357652 | 28953254

# IfcBeam: 28_PBT_SF_staal_H-profiel_met_ondergelaste_strip (void):S355_HE180A + ondergelaste strip d=12 (4)
In: 05 vijfde verdieping
Type - PredefinedType: BEAM; Classification: 28.11 hoofddraagconstructies - kolommen en liggers, kolom-/liggerconstructies (Uniformat); Material: 00_PBT_MAT_staal_S355, 00_PBT_MAT_Lucht
Type - Pset_BeamCommon - IsExternal: no; LoadBearing: yes
Type - Pset_ProductRequirements - Category: Structural Framing
Type - Pset_ReinforcementBarPitchOfBeam - Description: HE180A + ondergelaste strip d=12
Type - Pset_Pieters - Breedte: 180 mm; Hoogte: 171 mm; Codering - NL-SfB: 28.11; Omschrijving NL-SfB: hoofddraagconstructies - kolommen en liggers, kolom-/liggerconstructies; Materiaal: 00_PBT_MAT_staal_S355; Materiaalkwaliteit: S355; Description: HE180A + ondergelaste strip d=12
Material: 00_PBT_MAT_staal_S355
Pset_BeamCommon - Slope: 0 deg; Reference: 28_PBT_SF_staal_H-profiel_met_ondergelaste_strip (void):S355_HE180A + ondergelaste strip d=12
Pset_QuantityTakeOff - Reference: 28_PBT_SF_staal_H-profiel_met_ondergelaste_strip (void):S355_HE180A + ondergelaste strip d=12
Pset_ReinforcementBarPitchOfBeam - Reference: 28_PBT_SF_staal_H-profiel_met_ondergelaste_strip (void):S355_HE180A + ondergelaste strip d=12
Pset_Pieters - Bouwlaag: Level: 05 vijfde verdieping; Naamgeving element: 28_PBT_SF_staal_H-profiel_met_ondergelaste_strip (void): S355_HE180A + ondergelaste strip d=12; Fase: Nieuw
Name (28_PBT_SF_staal_H-profiel_met_ondergelaste_strip (void):S355_HE180A + ondergelaste strip d=12:...) | Span (mm) = Length (mm) | CrossSectionArea (mm2) | OuterSurfaceArea (mm2) | GrossSurfaceArea (mm2) | GrossVolume (m3) | NetVolume (m3) | NetSurfaceArea (mm2)
4408519 | 3717.52 | 4932493 | 2318483 | 2325683 | 0.0133759 | 0.0301983 | 6142393
4408908 | 3245.31 | 4314315 | 2023826 | 2031026 | 0.0116759 | 0.0263615 | 5364079
4410622 | 3499.75 | 4647402 | 2182593 | 2189793 | 0.0125919 | 0.0284288 | 5783450
4410710 | 3462.32 | 4598411 | 2159241 | 2166441 | 0.0124572 | 0.0281248 | 5721768

# IfcBeam: 28_PBT_SF_staal_H-profiel_met_ondergelaste_strip (void):S355_HE200B + ondergelaste strip d=12, 28_PBT_SF_staal_H-profiel_met_ondergelaste_strip (void):S355_HE200B + ondergelaste strip d=12:4270043
In: 03 derde verdieping
Type - PredefinedType: BEAM; Classification: 28.11 hoofddraagconstructies - kolommen en liggers, kolom-/liggerconstructies (Uniformat); Material: 00_PBT_MAT_staal_S355, 00_PBT_MAT_Lucht
Type - Pset_BeamCommon - IsExternal: no; LoadBearing: yes
Type - Pset_ProductRequirements - Category: Structural Framing
Type - Pset_ReinforcementBarPitchOfBeam - Description: HE200B + ondergelaste strip d=12
Type - Pset_Pieters - Breedte: 200 mm; Hoogte: 200 mm; Codering - NL-SfB: 28.11; Omschrijving NL-SfB: hoofddraagconstructies - kolommen en liggers, kolom-/liggerconstructies; Materiaal: 00_PBT_MAT_staal_S355; Materiaalkwaliteit: S355; Description: HE200B + ondergelaste strip d=12
Material: 00_PBT_MAT_staal_S355
Pset_BeamCommon - Slope: 0 deg; Reference: 28_PBT_SF_staal_H-profiel_met_ondergelaste_strip (void):S355_HE200B + ondergelaste strip d=12; Span: 4885.52 mm
Pset_QuantityTakeOff - Reference: 28_PBT_SF_staal_H-profiel_met_ondergelaste_strip (void):S355_HE200B + ondergelaste strip d=12
Pset_ReinforcementBarPitchOfBeam - Reference: 28_PBT_SF_staal_H-profiel_met_ondergelaste_strip (void):S355_HE200B + ondergelaste strip d=12
Pset_Pieters - Bouwlaag: Level: 03 derde verdieping; Naamgeving element: 28_PBT_SF_staal_H-profiel_met_ondergelaste_strip (void): S355_HE200B + ondergelaste strip d=12; Fase: Nieuw
BaseQuantities - Length: 4885.52 mm; CrossSectionArea: 7943539 mm2; OuterSurfaceArea: 3242655 mm2; GrossSurfaceArea: 3250335 mm2; GrossVolume: 0.0187527 m3; NetVolume: 0.135536 m3; NetSurfaceArea: 11440568 mm2

# IfcBeam: 28_PBT_SF_staal_H-profiel_met_ondergelaste_strip (void):S355_HE220A + ondergelaste strip d=12 (3)
Type - PredefinedType: BEAM; Classification: 28.11 hoofddraagconstructies - kolommen en liggers, kolom-/liggerconstructies (Uniformat); Material: 00_PBT_MAT_staal_S355, 00_PBT_MAT_Lucht
Type - Pset_BeamCommon - IsExternal: no; LoadBearing: yes
Type - Pset_ProductRequirements - Category: Structural Framing
Type - Pset_ReinforcementBarPitchOfBeam - Description: HE220A + ondergelaste strip d=12
Type - Pset_Pieters - Breedte: 220 mm; Hoogte: 210 mm; Codering - NL-SfB: 28.11; Omschrijving NL-SfB: hoofddraagconstructies - kolommen en liggers, kolom-/liggerconstructies; Materiaal: 00_PBT_MAT_staal_S355; Materiaalkwaliteit: S355; Description: HE220A + ondergelaste strip d=12
Material: 00_PBT_MAT_staal_S355
Pset_BeamCommon - Slope: 0 deg; Reference: 28_PBT_SF_staal_H-profiel_met_ondergelaste_strip (void):S355_HE220A + ondergelaste strip d=12
Pset_QuantityTakeOff - Reference: 28_PBT_SF_staal_H-profiel_met_ondergelaste_strip (void):S355_HE220A + ondergelaste strip d=12
Pset_ReinforcementBarPitchOfBeam - Reference: 28_PBT_SF_staal_H-profiel_met_ondergelaste_strip (void):S355_HE220A + ondergelaste strip d=12
Pset_Pieters - Naamgeving element: 28_PBT_SF_staal_H-profiel_met_ondergelaste_strip (void): S355_HE220A + ondergelaste strip d=12; Fase: Nieuw
Name (28_PBT_SF_staal_H-profiel_met_ondergelaste_strip (void):S355_HE220A + ondergelaste strip d=12:...) | In | Span (mm) = Length (mm) | Bouwlaag | CrossSectionArea (mm2) | OuterSurfaceArea (mm2) | GrossSurfaceArea (mm2) | GrossVolume (m3) | NetVolume (m3) | NetSurfaceArea (mm2)
2402046 | 01 eerste verdieping | 1599 | Level: 01 eerste verdieping | 2596024 | 1124288 | 1132448 | 0.00651576 | 0.016804 | 3152217
2442303 | 04 vierde verdieping | 2477.21 | Level: 04 vierde verdieping | 4700314 | 1742550 | 1750710 | 0.0100989 | 0.0752919 | 6333289
3047887 | 02 tweede verdieping | 2480.14 | Level: 02 tweede verdieping | 3922514 | 964581 | 972741 | 0.00559018 | 0.043598 | 4774261

# IfcBeam: 28_PBT_SF_staal_H-profiel_met_ondergelaste_strip (void):S355_HE260A + ondergelaste strip d=12 (2)
Type - PredefinedType: BEAM; Classification: 28.11 hoofddraagconstructies - kolommen en liggers, kolom-/liggerconstructies (Uniformat); Material: 00_PBT_MAT_staal_S355, 00_PBT_MAT_Lucht
Type - Pset_BeamCommon - IsExternal: no; LoadBearing: yes
Type - Pset_ProductRequirements - Category: Structural Framing
Type - Pset_ReinforcementBarPitchOfBeam - Description: HE260A + ondergelaste strip d=12
Type - Pset_Pieters - Breedte: 260 mm; Hoogte: 250 mm; Codering - NL-SfB: 28.11; Omschrijving NL-SfB: hoofddraagconstructies - kolommen en liggers, kolom-/liggerconstructies; Materiaal: 00_PBT_MAT_staal_S355; Materiaalkwaliteit: S355; Description: HE260A + ondergelaste strip d=12
Material: 00_PBT_MAT_staal_S355
Pset_BeamCommon - Slope: 0 deg; Reference: 28_PBT_SF_staal_H-profiel_met_ondergelaste_strip (void):S355_HE260A + ondergelaste strip d=12; Span: 5372.37 mm
Pset_QuantityTakeOff - Reference: 28_PBT_SF_staal_H-profiel_met_ondergelaste_strip (void):S355_HE260A + ondergelaste strip d=12
Pset_ReinforcementBarPitchOfBeam - Reference: 28_PBT_SF_staal_H-profiel_met_ondergelaste_strip (void):S355_HE260A + ondergelaste strip d=12
Pset_Pieters - Naamgeving element: 28_PBT_SF_staal_H-profiel_met_ondergelaste_strip (void): S355_HE260A + ondergelaste strip d=12; Fase: Nieuw; Zeeg: 10
BaseQuantities - Length: 5372.37 mm
Name (28_PBT_SF_staal_H-profiel_met_ondergelaste_strip (void):S355_HE260A + ondergelaste strip d=12:...) | In | Bouwlaag | CrossSectionArea (mm2) | OuterSurfaceArea (mm2) | GrossSurfaceArea (mm2) | GrossVolume (m3) | NetVolume (m3) | NetSurfaceArea (mm2)
2351361 | 02 tweede verdieping | Level: 02 tweede verdieping | 9409137 | 1464805 | 1473925 | 0.00851978 | 0.153804 | 11907806
2360572 | 03 derde verdieping | Level: 03 derde verdieping | 9397548 | 1286837 | 1295957 | 0.00748466 | 0.159161 | 11884629

# IfcBeam: 28_PBT_SF_staal_H-profiel_met_ondergelaste_strip (void):S355_HE280A + ondergelaste strip d=15, 28_PBT_SF_staal_H-profiel_met_ondergelaste_strip (void):S355_HE280A + ondergelaste strip d=15:2331756
In: 02 tweede verdieping
Type - PredefinedType: BEAM; Classification: 28.11 hoofddraagconstructies - kolommen en liggers, kolom-/liggerconstructies (Uniformat); Material: 00_PBT_MAT_Lucht, 00_PBT_MAT_staal_S355
Type - Pset_BeamCommon - IsExternal: no; LoadBearing: yes
Type - Pset_ProductRequirements - Category: Structural Framing
Type - Pset_ReinforcementBarPitchOfBeam - Description: HE280A + ondergelaste strip d=15
Type - Pset_Pieters - Breedte: 280 mm; Hoogte: 270 mm; Codering - NL-SfB: 28.11; Omschrijving NL-SfB: hoofddraagconstructies - kolommen en liggers, kolom-/liggerconstructies; Materiaal: 00_PBT_MAT_staal_S355; Materiaalkwaliteit: S355; Description: HE280A + ondergelaste strip d=15
Material: 00_PBT_MAT_staal_S355
Pset_BeamCommon - Slope: 0 deg; Reference: 28_PBT_SF_staal_H-profiel_met_ondergelaste_strip (void):S355_HE280A + ondergelaste strip d=15; Span: 3344.23 mm
Pset_QuantityTakeOff - Reference: 28_PBT_SF_staal_H-profiel_met_ondergelaste_strip (void):S355_HE280A + ondergelaste strip d=15
Pset_ReinforcementBarPitchOfBeam - Reference: 28_PBT_SF_staal_H-profiel_met_ondergelaste_strip (void):S355_HE280A + ondergelaste strip d=15
Pset_Pieters - Bouwlaag: Level: 02 tweede verdieping; Naamgeving element: 28_PBT_SF_staal_H-profiel_met_ondergelaste_strip (void): S355_HE280A + ondergelaste strip d=15; Fase: Nieuw
BaseQuantities - Length: 3344.23 mm; CrossSectionArea: 7589602 mm2; OuterSurfaceArea: 2055517 mm2; GrossSurfaceArea: 2067517 mm2; GrossVolume: 0.0148592 m3; NetVolume: 0.185667 m3; NetSurfaceArea: 10669664 mm2

# IfcBeam: 28_PBT_SF_staal_H-profiel_met_ondergelaste_strip (void):S355_HE280B + ondergelaste strip d=12, 28_PBT_SF_staal_H-profiel_met_ondergelaste_strip (void):S355_HE280B + ondergelaste strip d=12:2213443
In: 02 tweede verdieping
Type - PredefinedType: BEAM; Classification: 28.11 hoofddraagconstructies - kolommen en liggers, kolom-/liggerconstructies (Uniformat); Material: 00_PBT_MAT_Lucht, 00_PBT_MAT_staal_S355
Type - Pset_BeamCommon - IsExternal: no; LoadBearing: yes
Type - Pset_ProductRequirements - Category: Structural Framing
Type - Pset_ReinforcementBarPitchOfBeam - Description: HE280B + ondergelaste strip d=12
Type - Pset_Pieters - Breedte: 280 mm; Hoogte: 280 mm; Codering - NL-SfB: 28.11; Omschrijving NL-SfB: hoofddraagconstructies - kolommen en liggers, kolom-/liggerconstructies; Materiaal: 00_PBT_MAT_staal_S355; Materiaalkwaliteit: S355; Description: HE280B + ondergelaste strip d=12
Material: 00_PBT_MAT_staal_S355
Pset_BeamCommon - Slope: 0 deg; Reference: 28_PBT_SF_staal_H-profiel_met_ondergelaste_strip (void):S355_HE280B + ondergelaste strip d=12; Span: 1817 mm
Pset_QuantityTakeOff - Reference: 28_PBT_SF_staal_H-profiel_met_ondergelaste_strip (void):S355_HE280B + ondergelaste strip d=12
Pset_ReinforcementBarPitchOfBeam - Reference: 28_PBT_SF_staal_H-profiel_met_ondergelaste_strip (void):S355_HE280B + ondergelaste strip d=12
Pset_Pieters - Bouwlaag: Level: 02 tweede verdieping; Naamgeving element: 28_PBT_SF_staal_H-profiel_met_ondergelaste_strip (void): S355_HE280B + ondergelaste strip d=12; Fase: Nieuw; Comments: Momentvast verbinden aan kolom
BaseQuantities - Length: 1817 mm; CrossSectionArea: 3995039 mm2; OuterSurfaceArea: 1454360 mm2; GrossSurfaceArea: 1463960 mm2; GrossVolume: 0.008472 m3; NetVolume: 0.0909761 m3; NetSurfaceArea: 5753087 mm2

# IfcBeam: 28_PBT_SF_staal_H-profiel_met_ondergelaste_strip (void):S355_HE280B + ondergelaste strip d=12 (4)
Type - PredefinedType: BEAM; Classification: 28.11 hoofddraagconstructies - kolommen en liggers, kolom-/liggerconstructies (Uniformat); Material: 00_PBT_MAT_staal_S355, 00_PBT_MAT_Lucht
Type - Pset_BeamCommon - IsExternal: no; LoadBearing: yes
Type - Pset_ProductRequirements - Category: Structural Framing
Type - Pset_ReinforcementBarPitchOfBeam - Description: HE280B + ondergelaste strip d=12
Type - Pset_Pieters - Breedte: 280 mm; Hoogte: 280 mm; Codering - NL-SfB: 28.11; Omschrijving NL-SfB: hoofddraagconstructies - kolommen en liggers, kolom-/liggerconstructies; Materiaal: 00_PBT_MAT_staal_S355; Materiaalkwaliteit: S355; Description: HE280B + ondergelaste strip d=12
Material: 00_PBT_MAT_staal_S355
Pset_BeamCommon - Slope: 0 deg; Reference: 28_PBT_SF_staal_H-profiel_met_ondergelaste_strip (void):S355_HE280B + ondergelaste strip d=12
Pset_QuantityTakeOff - Reference: 28_PBT_SF_staal_H-profiel_met_ondergelaste_strip (void):S355_HE280B + ondergelaste strip d=12
Pset_ReinforcementBarPitchOfBeam - Reference: 28_PBT_SF_staal_H-profiel_met_ondergelaste_strip (void):S355_HE280B + ondergelaste strip d=12
Pset_Pieters - Naamgeving element: 28_PBT_SF_staal_H-profiel_met_ondergelaste_strip (void): S355_HE280B + ondergelaste strip d=12; Fase: Nieuw
Name (28_PBT_SF_staal_H-profiel_met_ondergelaste_strip (void):S355_HE280B + ondergelaste strip d=12:...) | In | Span (mm) = Length (mm) | Bouwlaag | Comments | CrossSectionArea (mm2) | OuterSurfaceArea (mm2) | GrossSurfaceArea (mm2) | GrossVolume (m3) | NetVolume (m3) | NetSurfaceArea (mm2)
2213528 | 02 tweede verdieping | 1817 | Level: 02 tweede verdieping | Momentvast verbinden aan kolom | 3995041 | 1454361 | 1463961 | 0.00847201 | 0.0909761 | 5753090
2647634 | 06 zesde verdieping | 4088.16 | Level: 06 zesde verdieping |  | 7484707 | 3366993 | 3376593 | 0.0196136 | 0.0733177 | 10016671
3629863 | 02 tweede verdieping | 1817 | Level: 02 tweede verdieping | Momentvast verbinden aan kolom | 2545197 | 2858648 | 2884922 | 0.0232127 | 0.0316842 | 4348883
3629909 | 02 tweede verdieping | 1817 | Level: 02 tweede verdieping | Momentvast verbinden aan kolom | 3292935 | 1454360 | 1463960 | 0.008472 | 0.0316842 | 4348880

# IfcBeam: 28_PBT_SF_staal_H-profiel_met_ondergelaste_strip (void):S355_HE280B + ondergelaste strip d=15 (3)
In: 03 derde verdieping
Type - PredefinedType: BEAM; Classification: 28.11 hoofddraagconstructies - kolommen en liggers, kolom-/liggerconstructies (Uniformat); Material: 00_PBT_MAT_Lucht, 00_PBT_MAT_staal_S355
Type - Pset_BeamCommon - IsExternal: no; LoadBearing: yes
Type - Pset_ProductRequirements - Category: Structural Framing
Type - Pset_ReinforcementBarPitchOfBeam - Description: HE280B + ondergelaste strip d=15
Type - Pset_Pieters - Breedte: 280 mm; Hoogte: 280 mm; Codering - NL-SfB: 28.11; Omschrijving NL-SfB: hoofddraagconstructies - kolommen en liggers, kolom-/liggerconstructies; Materiaal: 00_PBT_MAT_staal_S355; Materiaalkwaliteit: S355; Description: HE280B + ondergelaste strip d=15
Material: 00_PBT_MAT_staal_S355
Pset_BeamCommon - Slope: 0 deg; Reference: 28_PBT_SF_staal_H-profiel_met_ondergelaste_strip (void):S355_HE280B + ondergelaste strip d=15
Pset_QuantityTakeOff - Reference: 28_PBT_SF_staal_H-profiel_met_ondergelaste_strip (void):S355_HE280B + ondergelaste strip d=15
Pset_ReinforcementBarPitchOfBeam - Reference: 28_PBT_SF_staal_H-profiel_met_ondergelaste_strip (void):S355_HE280B + ondergelaste strip d=15
Pset_Pieters - Bouwlaag: Level: 03 derde verdieping; Naamgeving element: 28_PBT_SF_staal_H-profiel_met_ondergelaste_strip (void): S355_HE280B + ondergelaste strip d=15; Fase: Nieuw
Name (28_PBT_SF_staal_H-profiel_met_ondergelaste_strip (void):S355_HE280B + ondergelaste strip d=15:...) | Span (mm) = Length (mm) | CrossSectionArea (mm2) | OuterSurfaceArea (mm2) | GrossSurfaceArea (mm2) | GrossVolume (m3) | NetVolume (m3) | NetSurfaceArea (mm2)
2428219 | 14736.7 | 32007107 | 7209959 | 7221959 | 0.0521202 | 0.924015 | 46602678
2478668 | 4226.69 | 9521202 | 1307824 | 1319824 | 0.00945415 | 0.289377 | 13381973
4261968 | 5445.52 | 12107828 | 4518118 | 4530118 | 0.0326611 | 0.281893 | 17444182

# IfcBeam: 28_PBT_SF_staal_H-profiel_met_ondergelaste_strip (void):S355_HE280B + ondergelaste strip d=15 (2)
In: 03 derde verdieping
Type - PredefinedType: BEAM; Classification: 28.11 hoofddraagconstructies - kolommen en liggers, kolom-/liggerconstructies (Uniformat); Material: 00_PBT_MAT_staal_S355, 00_PBT_MAT_Lucht
Type - Pset_BeamCommon - IsExternal: no; LoadBearing: yes
Type - Pset_ProductRequirements - Category: Structural Framing
Type - Pset_ReinforcementBarPitchOfBeam - Description: HE280B + ondergelaste strip d=15
Type - Pset_Pieters - Breedte: 280 mm; Hoogte: 280 mm; Codering - NL-SfB: 28.11; Omschrijving NL-SfB: hoofddraagconstructies - kolommen en liggers, kolom-/liggerconstructies; Materiaal: 00_PBT_MAT_staal_S355; Materiaalkwaliteit: S355; Description: HE280B + ondergelaste strip d=15
Material: 00_PBT_MAT_staal_S355
Pset_BeamCommon - Slope: 0 deg; Reference: 28_PBT_SF_staal_H-profiel_met_ondergelaste_strip (void):S355_HE280B + ondergelaste strip d=15
Pset_QuantityTakeOff - Reference: 28_PBT_SF_staal_H-profiel_met_ondergelaste_strip (void):S355_HE280B + ondergelaste strip d=15
Pset_ReinforcementBarPitchOfBeam - Reference: 28_PBT_SF_staal_H-profiel_met_ondergelaste_strip (void):S355_HE280B + ondergelaste strip d=15
Pset_Pieters - Bouwlaag: Level: 03 derde verdieping; Naamgeving element: 28_PBT_SF_staal_H-profiel_met_ondergelaste_strip (void): S355_HE280B + ondergelaste strip d=15; Fase: Nieuw
Name (28_PBT_SF_staal_H-profiel_met_ondergelaste_strip (void):S355_HE280B + ondergelaste strip d=15:...) | Span (mm) = Length (mm) | CrossSectionArea (mm2) | OuterSurfaceArea (mm2) | GrossSurfaceArea (mm2) | GrossVolume (m3) | NetVolume (m3) | NetSurfaceArea (mm2)
2067540 | 3762.23 | 6940603 | 2042818 | 2054818 | 0.0147674 | 0.104641 | 9013434 | Pset_Pieters - Dragend/niet dragend: yes
2431790 | 17054.8 | 38312340 | 14153783 | 14165783 | 0.102317 | 0.882883 | 54416052

# IfcBeam: 28_PBT_SF_staal_H-profiel_met_ondergelaste_strip (void):S355_HE300A + ondergelaste strip d=12 (6)
Type - PredefinedType: BEAM; Classification: 28.11 hoofddraagconstructies - kolommen en liggers, kolom-/liggerconstructies (Uniformat); Material: 00_PBT_MAT_Lucht, 00_PBT_MAT_staal_S355
Type - Pset_BeamCommon - IsExternal: no; LoadBearing: yes
Type - Pset_ProductRequirements - Category: Structural Framing
Type - Pset_ReinforcementBarPitchOfBeam - Description: HE300A + ondergelaste strip d=12
Type - Pset_Pieters - Breedte: 300 mm; Hoogte: 290 mm; Codering - NL-SfB: 28.11; Omschrijving NL-SfB: hoofddraagconstructies - kolommen en liggers, kolom-/liggerconstructies; Materiaal: 00_PBT_MAT_staal_S355; Materiaalkwaliteit: S355; Description: HE300A + ondergelaste strip d=12
Material: 00_PBT_MAT_staal_S355
Pset_BeamCommon - Slope: 0 deg; Reference: 28_PBT_SF_staal_H-profiel_met_ondergelaste_strip (void):S355_HE300A + ondergelaste strip d=12
Pset_QuantityTakeOff - Reference: 28_PBT_SF_staal_H-profiel_met_ondergelaste_strip (void):S355_HE300A + ondergelaste strip d=12
Pset_ReinforcementBarPitchOfBeam - Reference: 28_PBT_SF_staal_H-profiel_met_ondergelaste_strip (void):S355_HE300A + ondergelaste strip d=12
Pset_Pieters - Naamgeving element: 28_PBT_SF_staal_H-profiel_met_ondergelaste_strip (void): S355_HE300A + ondergelaste strip d=12; Fase: Nieuw
Name (28_PBT_SF_staal_H-profiel_met_ondergelaste_strip (void):S355_HE300A + ondergelaste strip d=12:...) | In | Span (mm) = Length (mm) | Bouwlaag | CrossSectionArea (mm2) | OuterSurfaceArea (mm2) | GrossSurfaceArea (mm2) | GrossVolume (m3) | NetVolume (m3) | NetSurfaceArea (mm2)
2250739 | 03 derde verdieping | 7920 | Level: 03 derde verdieping | 15595411 | 6809480 | 6817880 | 0.0332556 | 0.122378 | 20436223
2250745 | 03 derde verdieping | 4017.19 | Level: 03 derde verdieping | 7953559 | 2012566 | 2020966 | 0.00982881 | 0.11851 | 10343251
2451249 | 04 vierde verdieping | 3400 | Level: 04 vierde verdieping | 7567298 | 2592812 | 2601212 | 0.0126626 | 0.16324 | 10391597
2846327 | 04 vierde verdieping | 4697 | Level: 04 vierde verdieping | 9329642 | 2542158 | 2550558 | 0.0124152 | 0.13117 | 12090537
3747918 | 00 begane grond | 5710 | Level: 01 ok ruwe vloer | 11009595 | 4790458 | 4798858 | 0.0233953 | 0.0860996 | 14387031
3872601 | 04 vierde verdieping | 4500 | Level: 04 vierde verdieping | 10160905 | 3518785 | 3527185 | 0.0171848 | 0.220657 | 14019009

# IfcBeam: 28_PBT_SF_staal_H-profiel_met_ondergelaste_strip (void):S355_HE300A + ondergelaste strip d=12, 28_PBT_SF_staal_H-profiel_met_ondergelaste_strip (void):S355_HE300A + ondergelaste strip d=12:2356882
In: 02 tweede verdieping
Type - PredefinedType: BEAM; Classification: 28.11 hoofddraagconstructies - kolommen en liggers, kolom-/liggerconstructies (Uniformat); Material: 00_PBT_MAT_staal_S355, 00_PBT_MAT_Lucht
Type - Pset_BeamCommon - IsExternal: no; LoadBearing: yes
Type - Pset_ProductRequirements - Category: Structural Framing
Type - Pset_ReinforcementBarPitchOfBeam - Description: HE300A + ondergelaste strip d=12
Type - Pset_Pieters - Breedte: 300 mm; Hoogte: 290 mm; Codering - NL-SfB: 28.11; Omschrijving NL-SfB: hoofddraagconstructies - kolommen en liggers, kolom-/liggerconstructies; Materiaal: 00_PBT_MAT_staal_S355; Materiaalkwaliteit: S355; Description: HE300A + ondergelaste strip d=12
Material: 00_PBT_MAT_staal_S355
Pset_BeamCommon - Slope: 0 deg; Reference: 28_PBT_SF_staal_H-profiel_met_ondergelaste_strip (void):S355_HE300A + ondergelaste strip d=12; Span: 3727.77 mm
Pset_QuantityTakeOff - Reference: 28_PBT_SF_staal_H-profiel_met_ondergelaste_strip (void):S355_HE300A + ondergelaste strip d=12
Pset_ReinforcementBarPitchOfBeam - Reference: 28_PBT_SF_staal_H-profiel_met_ondergelaste_strip (void):S355_HE300A + ondergelaste strip d=12
Pset_Pieters - Bouwlaag: Level: 02 tweede verdieping; Naamgeving element: 28_PBT_SF_staal_H-profiel_met_ondergelaste_strip (void): S355_HE300A + ondergelaste strip d=12; Fase: Nieuw
BaseQuantities - Length: 3727.77 mm; CrossSectionArea: 5011809 mm2; OuterSurfaceArea: 6399258 mm2; GrossSurfaceArea: 6421765 mm2; GrossVolume: 0.0419493 m3; NetVolume: 0.114037 m3; NetSurfaceArea: 9597506 mm2

# IfcBeam: 28_PBT_SF_staal_H-profiel_met_ondergelaste_strip (void):S355_HE300B + ondergelaste strip (2)
Type - PredefinedType: BEAM; Classification: 28.11 hoofddraagconstructies - kolommen en liggers, kolom-/liggerconstructies (Uniformat); Material: 00_PBT_MAT_Lucht, 00_PBT_MAT_staal_S355
Type - Pset_BeamCommon - IsExternal: no; LoadBearing: yes
Type - Pset_ProductRequirements - Category: Structural Framing
Type - Pset_ReinforcementBarPitchOfBeam - Description: HE300B + ondergelaste strip
Type - Pset_Pieters - Breedte: 300 mm; Hoogte: 300 mm; Codering - NL-SfB: 28.11; Omschrijving NL-SfB: hoofddraagconstructies - kolommen en liggers, kolom-/liggerconstructies; Materiaal: 00_PBT_MAT_staal_S355; Materiaalkwaliteit: S355; Description: HE300B + ondergelaste strip
Material: 00_PBT_MAT_staal_S355
Pset_BeamCommon - Slope: 0 deg; Reference: 28_PBT_SF_staal_H-profiel_met_ondergelaste_strip (void):S355_HE300B + ondergelaste strip
Pset_QuantityTakeOff - Reference: 28_PBT_SF_staal_H-profiel_met_ondergelaste_strip (void):S355_HE300B + ondergelaste strip
Pset_ReinforcementBarPitchOfBeam - Reference: 28_PBT_SF_staal_H-profiel_met_ondergelaste_strip (void):S355_HE300B + ondergelaste strip
Pset_Pieters - Naamgeving element: 28_PBT_SF_staal_H-profiel_met_ondergelaste_strip (void): S355_HE300B + ondergelaste strip; Fase: Nieuw
Name (28_PBT_SF_staal_H-profiel_met_ondergelaste_strip (void):S355_HE300B + ondergelaste strip:...) | In | Span (mm) = Length (mm) | Bouwlaag | CrossSectionArea (mm2) | OuterSurfaceArea (mm2) | GrossSurfaceArea (mm2) | GrossVolume (m3) | NetVolume (m3) | NetSurfaceArea (mm2)
2254423 | 03 derde verdieping | 8227.18 | Level: 03 derde verdieping | 10963382 | 14246565 | 14276381 | 0.122652 | 0.304458 | 21187314
2926933 | 04 vierde verdieping | 3747.17 | Level: 04 vierde verdieping | 5302407 | 6488769 | 6518585 | 0.0558635 | 0.0794569 | 9789482

# IfcBeam: 28_PBT_SF_staal_H-profiel_met_ondergelaste_strip (void):S355_HE300B + ondergelaste strip, 28_PBT_SF_staal_H-profiel_met_ondergelaste_strip (void):S355_HE300B + ondergelaste strip:2835996
In: 04 vierde verdieping
Type - PredefinedType: BEAM; Classification: 28.11 hoofddraagconstructies - kolommen en liggers, kolom-/liggerconstructies (Uniformat); Material: 00_PBT_MAT_staal_S355, 00_PBT_MAT_Lucht
Type - Pset_BeamCommon - IsExternal: no; LoadBearing: yes
Type - Pset_ProductRequirements - Category: Structural Framing
Type - Pset_ReinforcementBarPitchOfBeam - Description: HE300B + ondergelaste strip
Type - Pset_Pieters - Breedte: 300 mm; Hoogte: 300 mm; Codering - NL-SfB: 28.11; Omschrijving NL-SfB: hoofddraagconstructies - kolommen en liggers, kolom-/liggerconstructies; Materiaal: 00_PBT_MAT_staal_S355; Materiaalkwaliteit: S355; Description: HE300B + ondergelaste strip
Material: 00_PBT_MAT_staal_S355
Pset_BeamCommon - Slope: 0 deg; Reference: 28_PBT_SF_staal_H-profiel_met_ondergelaste_strip (void):S355_HE300B + ondergelaste strip; Span: 4851.66 mm
Pset_QuantityTakeOff - Reference: 28_PBT_SF_staal_H-profiel_met_ondergelaste_strip (void):S355_HE300B + ondergelaste strip
Pset_ReinforcementBarPitchOfBeam - Reference: 28_PBT_SF_staal_H-profiel_met_ondergelaste_strip (void):S355_HE300B + ondergelaste strip
Pset_Pieters - Bouwlaag: Level: 04 vierde verdieping; Naamgeving element: 28_PBT_SF_staal_H-profiel_met_ondergelaste_strip (void): S355_HE300B + ondergelaste strip; Fase: Nieuw
BaseQuantities - Length: 4851.66 mm; CrossSectionArea: 9668352 mm2; OuterSurfaceArea: 4219208 mm2; GrossSurfaceArea: 4231808 mm2; GrossVolume: 0.0305529 m3; NetVolume: 0.102881 m3; NetSurfaceArea: 12662990 mm2

# IfcBeam: 28_PBT_SF_staal_H-profiel_met_ondergelaste_strip (void):S355_HE300B + ondergelaste strip d=12 (5)
Type - PredefinedType: BEAM; Classification: 28.11 hoofddraagconstructies - kolommen en liggers, kolom-/liggerconstructies (Uniformat); Material: 00_PBT_MAT_Lucht, 00_PBT_MAT_staal_S355
Type - Pset_BeamCommon - IsExternal: no; LoadBearing: yes
Type - Pset_ProductRequirements - Category: Structural Framing
Type - Pset_ReinforcementBarPitchOfBeam - Description: HE300B + ondergelaste strip d=12
Type - Pset_Pieters - Breedte: 300 mm; Hoogte: 300 mm; Codering - NL-SfB: 28.11; Omschrijving NL-SfB: hoofddraagconstructies - kolommen en liggers, kolom-/liggerconstructies; Materiaal: 00_PBT_MAT_staal_S355; Materiaalkwaliteit: S355; Description: HE300B + ondergelaste strip d=12
Material: 00_PBT_MAT_staal_S355
Pset_BeamCommon - Slope: 0 deg; Reference: 28_PBT_SF_staal_H-profiel_met_ondergelaste_strip (void):S355_HE300B + ondergelaste strip d=12
Pset_QuantityTakeOff - Reference: 28_PBT_SF_staal_H-profiel_met_ondergelaste_strip (void):S355_HE300B + ondergelaste strip d=12
Pset_ReinforcementBarPitchOfBeam - Reference: 28_PBT_SF_staal_H-profiel_met_ondergelaste_strip (void):S355_HE300B + ondergelaste strip d=12
Pset_Pieters - Naamgeving element: 28_PBT_SF_staal_H-profiel_met_ondergelaste_strip (void): S355_HE300B + ondergelaste strip d=12; Fase: Nieuw
Name (28_PBT_SF_staal_H-profiel_met_ondergelaste_strip (void):S355_HE300B + ondergelaste strip d=12:...) | In | Span (mm) = Length (mm) | Bouwlaag | CrossSectionArea (mm2) | OuterSurfaceArea (mm2) | GrossSurfaceArea (mm2) | GrossVolume (m3) | NetVolume (m3) | NetSurfaceArea (mm2)
2250762 | 04 vierde verdieping | 8227.18 | Level: 04 vierde verdieping | 10963461 | 14246565 | 14276381 | 0.122652 | 0.28747 | 21187472
2253618 | 01 eerste verdieping | 8227.18 | Level: 01 eerste verdieping | 16278084 | 7106556 | 7116636 | 0.0414549 | 0.164105 | 21393018
2254444 | 04 vierde verdieping | 8227.18 | Level: 04 vierde verdieping | 10941579 | 14246565 | 14276381 | 0.122652 | 0.306649 | 21143707
2452982 | 03 derde verdieping | 5867.39 | Level: 03 derde verdieping | 11646242 | 5067701 | 5077781 | 0.0295616 | 0.117032 | 15267849
3866412 | 03 derde verdieping | 4820 | Level: 03 derde verdieping | 9181542 | 966816 | 976896 | 0.00563976 | 0.216416 | 12350683

# IfcBeam: 28_PBT_SF_staal_H-profiel_met_ondergelaste_strip (void):S355_HE300B + ondergelaste strip d=12 (5)
Type - PredefinedType: BEAM; Classification: 28.11 hoofddraagconstructies - kolommen en liggers, kolom-/liggerconstructies (Uniformat); Material: 00_PBT_MAT_staal_S355, 00_PBT_MAT_Lucht
Type - Pset_BeamCommon - IsExternal: no; LoadBearing: yes
Type - Pset_ProductRequirements - Category: Structural Framing
Type - Pset_ReinforcementBarPitchOfBeam - Description: HE300B + ondergelaste strip d=12
Type - Pset_Pieters - Breedte: 300 mm; Hoogte: 300 mm; Codering - NL-SfB: 28.11; Omschrijving NL-SfB: hoofddraagconstructies - kolommen en liggers, kolom-/liggerconstructies; Materiaal: 00_PBT_MAT_staal_S355; Materiaalkwaliteit: S355; Description: HE300B + ondergelaste strip d=12
Material: 00_PBT_MAT_staal_S355
Pset_BeamCommon - Slope: 0 deg; Reference: 28_PBT_SF_staal_H-profiel_met_ondergelaste_strip (void):S355_HE300B + ondergelaste strip d=12
Pset_QuantityTakeOff - Reference: 28_PBT_SF_staal_H-profiel_met_ondergelaste_strip (void):S355_HE300B + ondergelaste strip d=12
Pset_ReinforcementBarPitchOfBeam - Reference: 28_PBT_SF_staal_H-profiel_met_ondergelaste_strip (void):S355_HE300B + ondergelaste strip d=12
Pset_Pieters - Naamgeving element: 28_PBT_SF_staal_H-profiel_met_ondergelaste_strip (void): S355_HE300B + ondergelaste strip d=12; Fase: Nieuw
Name (28_PBT_SF_staal_H-profiel_met_ondergelaste_strip (void):S355_HE300B + ondergelaste strip d=12:...) | In | Span (mm) = Length (mm) | Bouwlaag | CrossSectionArea (mm2) | OuterSurfaceArea (mm2) | GrossSurfaceArea (mm2) | GrossVolume (m3) | NetVolume (m3) | NetSurfaceArea (mm2)
2254034 | 02 tweede verdieping | 8227.18 | Level: 02 tweede verdieping | 11104175 | 14246565 | 14276381 | 0.122652 | 0.164105 | 21393018
2351251 | 02 tweede verdieping | 6077 | Level: 02 tweede verdieping | 11987150 | 2722462 | 2732542 | 0.015881 | 0.216298 | 15670892
2360570 | 03 derde verdieping | 6077 | Level: 03 derde verdieping | 11987521 | 2731102 | 2741182 | 0.0159314 | 0.215973 | 15671634
3874815 | 02 tweede verdieping | 4071.14 | Level: 02 tweede verdieping | 8517518 | 3515739 | 3525819 | 0.0205085 | 0.0812005 | 10605412
3875765 | 01 eerste verdieping | 5111.14 | Level: 01 eerste verdieping | 10652454 | 4414299 | 4424379 | 0.0257501 | 0.101946 | 13304883

# IfcBeam: 28_PBT_SF_staal_H-profiel_met_ondergelaste_strip (void):S355_HE300B + ondergelaste strip d=15 (2)
Type - PredefinedType: BEAM; Classification: 28.11 hoofddraagconstructies - kolommen en liggers, kolom-/liggerconstructies (Uniformat); Material: 00_PBT_MAT_staal_S355, 00_PBT_MAT_Lucht
Type - Pset_BeamCommon - IsExternal: no; LoadBearing: yes
Type - Pset_ProductRequirements - Category: Structural Framing
Type - Pset_ReinforcementBarPitchOfBeam - Description: HE300B + ondergelaste strip d=15
Type - Pset_Pieters - Breedte: 300 mm; Hoogte: 300 mm; Codering - NL-SfB: 28.11; Omschrijving NL-SfB: hoofddraagconstructies - kolommen en liggers, kolom-/liggerconstructies; Materiaal: 00_PBT_MAT_staal_S355; Materiaalkwaliteit: S355; Description: HE300B + ondergelaste strip d=15
Material: 00_PBT_MAT_staal_S355
Pset_BeamCommon - Slope: 0 deg; Reference: 28_PBT_SF_staal_H-profiel_met_ondergelaste_strip (void):S355_HE300B + ondergelaste strip d=15; Span: 8227.18 mm
Pset_QuantityTakeOff - Reference: 28_PBT_SF_staal_H-profiel_met_ondergelaste_strip (void):S355_HE300B + ondergelaste strip d=15
Pset_ReinforcementBarPitchOfBeam - Reference: 28_PBT_SF_staal_H-profiel_met_ondergelaste_strip (void):S355_HE300B + ondergelaste strip d=15
Pset_Pieters - Naamgeving element: 28_PBT_SF_staal_H-profiel_met_ondergelaste_strip (void): S355_HE300B + ondergelaste strip d=15; Fase: Nieuw
BaseQuantities - Length: 8227.18 mm; NetVolume: 0.174468 m3; NetSurfaceArea: 21444889 mm2
Name (28_PBT_SF_staal_H-profiel_met_ondergelaste_strip (void):S355_HE300B + ondergelaste strip d=15:...) | In | Bouwlaag | CrossSectionArea (mm2) | OuterSurfaceArea (mm2) | GrossSurfaceArea (mm2) | GrossVolume (m3)
2245718 | 01 eerste verdieping | Level: 01 eerste verdieping | 16304020 | 7155907 | 7168507 | 0.0518186
2250346 | 02 tweede verdieping | Level: 02 tweede verdieping | 11130110 | 14246565 | 14276381 | 0.122652

# IfcBeam: 28_PBT_SF_staal_H-profiel_met_ondergelaste_strip (void):S355_HE320B + ondergelaste strip, 28_PBT_SF_staal_H-profiel_met_ondergelaste_strip (void):S355_HE320B + ondergelaste strip:4474228
In: 03 derde verdieping
Type - PredefinedType: BEAM; Classification: 28.11 hoofddraagconstructies - kolommen en liggers, kolom-/liggerconstructies (Uniformat); Material: 00_PBT_MAT_Lucht, 00_PBT_MAT_staal_S355
Type - Pset_BeamCommon - IsExternal: no; LoadBearing: yes
Type - Pset_ProductRequirements - Category: Structural Framing
Type - Pset_ReinforcementBarPitchOfBeam - Description: HE320B + ondergelaste strip
Type - Pset_Pieters - Breedte: 300 mm; Hoogte: 320 mm; Codering - NL-SfB: 28.11; Omschrijving NL-SfB: hoofddraagconstructies - kolommen en liggers, kolom-/liggerconstructies; Materiaal: 00_PBT_MAT_staal_S355; Materiaalkwaliteit: S355; Description: HE320B + ondergelaste strip
Material: 00_PBT_MAT_staal_S355
Pset_BeamCommon - Slope: 0 deg; Reference: 28_PBT_SF_staal_H-profiel_met_ondergelaste_strip (void):S355_HE320B + ondergelaste strip; Span: 783.882 mm
Pset_QuantityTakeOff - Reference: 28_PBT_SF_staal_H-profiel_met_ondergelaste_strip (void):S355_HE320B + ondergelaste strip
Pset_ReinforcementBarPitchOfBeam - Reference: 28_PBT_SF_staal_H-profiel_met_ondergelaste_strip (void):S355_HE320B + ondergelaste strip
Pset_Pieters - Bouwlaag: Level: 03 derde verdieping; Naamgeving element: 28_PBT_SF_staal_H-profiel_met_ondergelaste_strip (void): S355_HE320B + ondergelaste strip; Fase: Nieuw
BaseQuantities - Length: 783.882 mm; CrossSectionArea: 1372496 mm2; OuterSurfaceArea: 539979 mm2; GrossSurfaceArea: 548379 mm2; GrossVolume: 0.00263711 m3; NetVolume: 0.0127999 m3; NetSurfaceArea: 1695947 mm2

# IfcBeam: 28_PBT_SF_staal_H-profiel_met_ondergelaste_strip (void):S355_HE320B + ondergelaste strip, 28_PBT_SF_staal_H-profiel_met_ondergelaste_strip (void):S355_HE320B + ondergelaste strip:2444342
In: 01 eerste verdieping
Type - PredefinedType: BEAM; Classification: 28.11 hoofddraagconstructies - kolommen en liggers, kolom-/liggerconstructies (Uniformat); Material: 00_PBT_MAT_staal_S355, 00_PBT_MAT_Lucht
Type - Pset_BeamCommon - IsExternal: no; LoadBearing: yes
Type - Pset_ProductRequirements - Category: Structural Framing
Type - Pset_ReinforcementBarPitchOfBeam - Description: HE320B + ondergelaste strip
Type - Pset_Pieters - Breedte: 300 mm; Hoogte: 320 mm; Codering - NL-SfB: 28.11; Omschrijving NL-SfB: hoofddraagconstructies - kolommen en liggers, kolom-/liggerconstructies; Materiaal: 00_PBT_MAT_staal_S355; Materiaalkwaliteit: S355; Description: HE320B + ondergelaste strip
Material: 00_PBT_MAT_staal_S355
Pset_BeamCommon - Slope: 0 deg; Reference: 28_PBT_SF_staal_H-profiel_met_ondergelaste_strip (void):S355_HE320B + ondergelaste strip; Span: 2468 mm
Pset_QuantityTakeOff - Reference: 28_PBT_SF_staal_H-profiel_met_ondergelaste_strip (void):S355_HE320B + ondergelaste strip
Pset_ReinforcementBarPitchOfBeam - Reference: 28_PBT_SF_staal_H-profiel_met_ondergelaste_strip (void):S355_HE320B + ondergelaste strip
Pset_Pieters - Bouwlaag: Level: 01 eerste verdieping; Naamgeving element: 28_PBT_SF_staal_H-profiel_met_ondergelaste_strip (void): S355_HE320B + ondergelaste strip; Fase: Nieuw
BaseQuantities - Length: 2468 mm; CrossSectionArea: 6018633 mm2; NetVolume: 0.135233 m3; NetSurfaceArea: 8084545 mm2

# IfcBeam: 28_PBT_SF_staal_H-profiel_met_ondergelaste_strip (void):S355_HE320B + ondergelaste strip d=15, 28_PBT_SF_staal_H-profiel_met_ondergelaste_strip (void):S355_HE320B + ondergelaste strip d=15:4264880
In: 03 derde verdieping
Type - PredefinedType: BEAM; Classification: 28.11 hoofddraagconstructies - kolommen en liggers, kolom-/liggerconstructies (Uniformat); Material: 00_PBT_MAT_Lucht, 00_PBT_MAT_staal_S355
Type - Pset_BeamCommon - IsExternal: no; LoadBearing: yes
Type - Pset_ProductRequirements - Category: Structural Framing
Type - Pset_ReinforcementBarPitchOfBeam - Description: HE320B + ondergelaste strip d=15
Type - Pset_Pieters - Breedte: 300 mm; Hoogte: 320 mm; Codering - NL-SfB: 28.11; Omschrijving NL-SfB: hoofddraagconstructies - kolommen en liggers, kolom-/liggerconstructies; Materiaal: 00_PBT_MAT_staal_S355; Materiaalkwaliteit: S355; Description: HE320B + ondergelaste strip d=15
Material: 00_PBT_MAT_staal_S355
Pset_BeamCommon - Slope: 0 deg; Reference: 28_PBT_SF_staal_H-profiel_met_ondergelaste_strip (void):S355_HE320B + ondergelaste strip d=15; Span: 8730.4 mm
Pset_QuantityTakeOff - Reference: 28_PBT_SF_staal_H-profiel_met_ondergelaste_strip (void):S355_HE320B + ondergelaste strip d=15
Pset_ReinforcementBarPitchOfBeam - Reference: 28_PBT_SF_staal_H-profiel_met_ondergelaste_strip (void):S355_HE320B + ondergelaste strip d=15
Pset_Pieters - Bouwlaag: Level: 03 derde verdieping; Naamgeving element: 28_PBT_SF_staal_H-profiel_met_ondergelaste_strip (void): S355_HE320B + ondergelaste strip d=15; Fase: Nieuw; Zeeg: 20
BaseQuantities - Length: 8730.4 mm; CrossSectionArea: 17419369 mm2; OuterSurfaceArea: 7593705 mm2; GrossSurfaceArea: 7606305 mm2; GrossVolume: 0.0549889 m3; NetVolume: 0.195848 m3; NetSurfaceArea: 23097015 mm2

# IfcBeam: 28_PBT_SF_staal_H-profiel_met_ondergelaste_strip (void):S355_HE360B + ondergelaste strip d=12 (2)
In: 06 zesde verdieping
Type - PredefinedType: BEAM; Classification: 28.11 hoofddraagconstructies - kolommen en liggers, kolom-/liggerconstructies (Uniformat); Material: 00_PBT_MAT_staal_S355, 00_PBT_MAT_Lucht
Type - Pset_BeamCommon - IsExternal: no; LoadBearing: yes
Type - Pset_ProductRequirements - Category: Structural Framing
Type - Pset_ReinforcementBarPitchOfBeam - Description: HE360B + ondergelaste strip d=12
Type - Pset_Pieters - Breedte: 300 mm; Hoogte: 360 mm; Codering - NL-SfB: 28.11; Omschrijving NL-SfB: hoofddraagconstructies - kolommen en liggers, kolom-/liggerconstructies; Materiaal: 00_PBT_MAT_staal_S355; Materiaalkwaliteit: S355; Description: HE360B + ondergelaste strip d=12
Material: 00_PBT_MAT_staal_S355
Pset_BeamCommon - Slope: 0 deg; Reference: 28_PBT_SF_staal_H-profiel_met_ondergelaste_strip (void):S355_HE360B + ondergelaste strip d=12; Span: 11989.7 mm
Pset_QuantityTakeOff - Reference: 28_PBT_SF_staal_H-profiel_met_ondergelaste_strip (void):S355_HE360B + ondergelaste strip d=12
Pset_ReinforcementBarPitchOfBeam - Reference: 28_PBT_SF_staal_H-profiel_met_ondergelaste_strip (void):S355_HE360B + ondergelaste strip d=12
Pset_Pieters - Bouwlaag: Level: 06 zesde verdieping; Naamgeving element: 28_PBT_SF_staal_H-profiel_met_ondergelaste_strip (void): S355_HE360B + ondergelaste strip d=12; Fase: Nieuw
BaseQuantities - Length: 11989.7 mm; CrossSectionArea: 16763146 mm2; OuterSurfaceArea: 22164729 mm2; GrossSurfaceArea: 22200857 mm2; GrossVolume: 0.216579 m3; NetVolume: 0.296962 m3; NetSurfaceArea: 32674280 mm2
Name (28_PBT_SF_staal_H-profiel_met_ondergelaste_strip (void):S355_HE360B + ondergelaste strip d=12:...)
4671545
4671840

# IfcBeam: 28_PBT_SF_staal_H-profiel_met_ondergelaste_strip (void):S355_HE400B + ondergelaste strip (3)
Type - PredefinedType: BEAM; Classification: 28.11 hoofddraagconstructies - kolommen en liggers, kolom-/liggerconstructies (Uniformat); Material: 00_PBT_MAT_Lucht, 00_PBT_MAT_staal_S355
Type - Pset_BeamCommon - IsExternal: no; LoadBearing: yes
Type - Pset_ProductRequirements - Category: Structural Framing
Type - Pset_ReinforcementBarPitchOfBeam - Description: HE400B + ondergelaste strip
Type - Pset_Pieters - Breedte: 300 mm; Hoogte: 400 mm; Codering - NL-SfB: 28.11; Omschrijving NL-SfB: hoofddraagconstructies - kolommen en liggers, kolom-/liggerconstructies; Materiaal: 00_PBT_MAT_staal_S355; Materiaalkwaliteit: S355; Description: HE400B + ondergelaste strip
Material: 00_PBT_MAT_staal_S355
Pset_BeamCommon - Slope: 0 deg; Reference: 28_PBT_SF_staal_H-profiel_met_ondergelaste_strip (void):S355_HE400B + ondergelaste strip
Pset_QuantityTakeOff - Reference: 28_PBT_SF_staal_H-profiel_met_ondergelaste_strip (void):S355_HE400B + ondergelaste strip
Pset_ReinforcementBarPitchOfBeam - Reference: 28_PBT_SF_staal_H-profiel_met_ondergelaste_strip (void):S355_HE400B + ondergelaste strip
Pset_Pieters - Naamgeving element: 28_PBT_SF_staal_H-profiel_met_ondergelaste_strip (void): S355_HE400B + ondergelaste strip; Fase: Nieuw
Name (28_PBT_SF_staal_H-profiel_met_ondergelaste_strip (void):S355_HE400B + ondergelaste strip:...) | In | Span (mm) = Length (mm) | Bouwlaag | CrossSectionArea (mm2) | OuterSurfaceArea (mm2) | GrossSurfaceArea (mm2) | GrossVolume (m3) | NetVolume (m3) | NetSurfaceArea (mm2)
2448124 | 02 tweede verdieping | 2413 | Level: 02 tweede verdieping | 6551933 | 2097570 | 2110170 | 0.0151893 | 0.183831 | 9233095
2988721 | 01 eerste verdieping | 8014.96 | Level: 01 eerste verdieping | 21351746 | 6971276 | 6983876 | 0.0504817 | 0.610639 | 30318701
2989325 | 02 tweede verdieping | 8014.96 | Level: 02 tweede verdieping | 21351746 | 6971276 | 6983876 | 0.0504817 | 0.610639 | 30318701

# IfcBeam: 28_PBT_SF_staal_H-profiel_met_ondergelaste_strip (void):S355_HE400B + ondergelaste strip, 28_PBT_SF_staal_H-profiel_met_ondergelaste_strip (void):S355_HE400B + ondergelaste strip:2447906
In: 02 tweede verdieping
Type - PredefinedType: BEAM; Classification: 28.11 hoofddraagconstructies - kolommen en liggers, kolom-/liggerconstructies (Uniformat); Material: 00_PBT_MAT_staal_S355, 00_PBT_MAT_Lucht
Type - Pset_BeamCommon - IsExternal: no; LoadBearing: yes
Type - Pset_ProductRequirements - Category: Structural Framing
Type - Pset_ReinforcementBarPitchOfBeam - Description: HE400B + ondergelaste strip
Type - Pset_Pieters - Breedte: 300 mm; Hoogte: 400 mm; Codering - NL-SfB: 28.11; Omschrijving NL-SfB: hoofddraagconstructies - kolommen en liggers, kolom-/liggerconstructies; Materiaal: 00_PBT_MAT_staal_S355; Materiaalkwaliteit: S355; Description: HE400B + ondergelaste strip
Material: 00_PBT_MAT_staal_S355
Pset_BeamCommon - Slope: 0 deg; Reference: 28_PBT_SF_staal_H-profiel_met_ondergelaste_strip (void):S355_HE400B + ondergelaste strip; Span: 2468 mm
Pset_QuantityTakeOff - Reference: 28_PBT_SF_staal_H-profiel_met_ondergelaste_strip (void):S355_HE400B + ondergelaste strip
Pset_ReinforcementBarPitchOfBeam - Reference: 28_PBT_SF_staal_H-profiel_met_ondergelaste_strip (void):S355_HE400B + ondergelaste strip
Pset_Pieters - Bouwlaag: Level: 02 tweede verdieping; Naamgeving element: 28_PBT_SF_staal_H-profiel_met_ondergelaste_strip (void): S355_HE400B + ondergelaste strip; Fase: Nieuw
BaseQuantities - Length: 2468 mm; CrossSectionArea: 6696417 mm2; OuterSurfaceArea: 2145420 mm2; GrossSurfaceArea: 2158020 mm2; GrossVolume: 0.0155358 m3; NetVolume: 0.188022 m3; NetSurfaceArea: 9440114 mm2

# IfcBeam: 28_PBT_SF_staal_H-profiel_met_ondergelaste_strip (void):S355_HE400B + ondergelaste strip d=15, 28_PBT_SF_staal_H-profiel_met_ondergelaste_strip (void):S355_HE400B + ondergelaste strip d=15:4254267
In: 03 derde verdieping
Type - PredefinedType: BEAM; Classification: 28.11 hoofddraagconstructies - kolommen en liggers, kolom-/liggerconstructies (Uniformat); Material: 00_PBT_MAT_Lucht, 00_PBT_MAT_staal_S355
Type - Pset_BeamCommon - IsExternal: no; LoadBearing: yes
Type - Pset_ProductRequirements - Category: Structural Framing
Type - Pset_ReinforcementBarPitchOfBeam - Description: HE400B + ondergelaste strip d=15
Type - Pset_Pieters - Breedte: 300 mm; Hoogte: 400 mm; Codering - NL-SfB: 28.11; Omschrijving NL-SfB: hoofddraagconstructies - kolommen en liggers, kolom-/liggerconstructies; Materiaal: 00_PBT_MAT_staal_S355; Materiaalkwaliteit: S355; Description: HE400B + ondergelaste strip d=15
Material: 00_PBT_MAT_staal_S355
Pset_BeamCommon - Slope: 0 deg; Reference: 28_PBT_SF_staal_H-profiel_met_ondergelaste_strip (void):S355_HE400B + ondergelaste strip d=15; Span: 8014.96 mm
Pset_QuantityTakeOff - Reference: 28_PBT_SF_staal_H-profiel_met_ondergelaste_strip (void):S355_HE400B + ondergelaste strip d=15
Pset_ReinforcementBarPitchOfBeam - Reference: 28_PBT_SF_staal_H-profiel_met_ondergelaste_strip (void):S355_HE400B + ondergelaste strip d=15
Pset_Pieters - Bouwlaag: Level: 03 derde verdieping; Naamgeving element: 28_PBT_SF_staal_H-profiel_met_ondergelaste_strip (void): S355_HE400B + ondergelaste strip d=15; Fase: Nieuw
BaseQuantities - Length: 8014.96 mm; CrossSectionArea: 21351746 mm2; OuterSurfaceArea: 6971276 mm2; GrossSurfaceArea: 6983876 mm2; GrossVolume: 0.0504817 m3; NetVolume: 0.610639 m3; NetSurfaceArea: 30318702 mm2

# IfcBeam: 28_PBT_SF_staal_H-profiel_met_ondergelaste_strip (void):S355_HE400B + ondergelaste strip d=25, 28_PBT_SF_staal_H-profiel_met_ondergelaste_strip (void):S355_HE400B + ondergelaste strip d=25:2449092
In: 03 derde verdieping
Type - PredefinedType: BEAM; Classification: 28.11 hoofddraagconstructies - kolommen en liggers, kolom-/liggerconstructies (Uniformat); Material: 00_PBT_MAT_Lucht, 00_PBT_MAT_staal_S355
Type - Pset_BeamCommon - IsExternal: no; LoadBearing: yes
Type - Pset_ProductRequirements - Category: Structural Framing
Type - Pset_ReinforcementBarPitchOfBeam - Description: HE400B + ondergelaste strip d=25
Type - Pset_Pieters - Breedte: 300 mm; Hoogte: 400 mm; Codering - NL-SfB: 28.11; Omschrijving NL-SfB: hoofddraagconstructies - kolommen en liggers, kolom-/liggerconstructies; Materiaal: 00_PBT_MAT_staal_S355; Materiaalkwaliteit: S355; Description: HE400B + ondergelaste strip d=25
Material: 00_PBT_MAT_staal_S355
Pset_BeamCommon - Slope: 0 deg; Reference: 28_PBT_SF_staal_H-profiel_met_ondergelaste_strip (void):S355_HE400B + ondergelaste strip d=25; Span: 7357.23 mm
Pset_QuantityTakeOff - Reference: 28_PBT_SF_staal_H-profiel_met_ondergelaste_strip (void):S355_HE400B + ondergelaste strip d=25
Pset_ReinforcementBarPitchOfBeam - Reference: 28_PBT_SF_staal_H-profiel_met_ondergelaste_strip (void):S355_HE400B + ondergelaste strip d=25
Pset_Pieters - Bouwlaag: Level: 03 derde verdieping; Naamgeving element: 28_PBT_SF_staal_H-profiel_met_ondergelaste_strip (void): S355_HE400B + ondergelaste strip d=25; Fase: Nieuw
BaseQuantities - Length: 7357.23 mm; CrossSectionArea: 18628489 mm2; OuterSurfaceArea: 4246392 mm2; GrossSurfaceArea: 4267392 mm2; GrossVolume: 0.0500979 m3; NetVolume: 0.575701 m3; NetSurfaceArea: 26019310 mm2

# IfcBeam: 28_PBT_SF_staal_H-profiel_met_ondergelaste_strip (void):S355_HE400B + ondergelaste strip d=25, 28_PBT_SF_staal_H-profiel_met_ondergelaste_strip (void):S355_HE400B + ondergelaste strip d=25:2449281
In: 03 derde verdieping
Type - PredefinedType: BEAM; Classification: 28.11 hoofddraagconstructies - kolommen en liggers, kolom-/liggerconstructies (Uniformat); Material: 00_PBT_MAT_staal_S355, 00_PBT_MAT_Lucht
Type - Pset_BeamCommon - IsExternal: no; LoadBearing: yes
Type - Pset_ProductRequirements - Category: Structural Framing
Type - Pset_ReinforcementBarPitchOfBeam - Description: HE400B + ondergelaste strip d=25
Type - Pset_Pieters - Breedte: 300 mm; Hoogte: 400 mm; Codering - NL-SfB: 28.11; Omschrijving NL-SfB: hoofddraagconstructies - kolommen en liggers, kolom-/liggerconstructies; Materiaal: 00_PBT_MAT_staal_S355; Materiaalkwaliteit: S355; Description: HE400B + ondergelaste strip d=25
Material: 00_PBT_MAT_staal_S355
Pset_BeamCommon - Slope: 0 deg; Reference: 28_PBT_SF_staal_H-profiel_met_ondergelaste_strip (void):S355_HE400B + ondergelaste strip d=25; Span: 4965.52 mm
Pset_QuantityTakeOff - Reference: 28_PBT_SF_staal_H-profiel_met_ondergelaste_strip (void):S355_HE400B + ondergelaste strip d=25
Pset_ReinforcementBarPitchOfBeam - Reference: 28_PBT_SF_staal_H-profiel_met_ondergelaste_strip (void):S355_HE400B + ondergelaste strip d=25
Pset_Pieters - Bouwlaag: Level: 03 derde verdieping; Naamgeving element: 28_PBT_SF_staal_H-profiel_met_ondergelaste_strip (void): S355_HE400B + ondergelaste strip d=25; Fase: Nieuw
BaseQuantities - Length: 4965.52 mm; CrossSectionArea: 13407670 mm2; OuterSurfaceArea: 4417529 mm2; GrossSurfaceArea: 4438529 mm2; GrossVolume: 0.0521169 m3; NetVolume: 0.409148 m3; NetSurfaceArea: 19141322 mm2

# IfcBeam: 28_PBT_SF_staal_H-profiel_met_onderplaat (void):S355_HE220A + onderplaat d=12 (2)
In: 05 vijfde verdieping
Type - PredefinedType: BEAM; Classification: 28.11 hoofddraagconstructies - kolommen en liggers, kolom-/liggerconstructies (Uniformat); Material: 00_PBT_MAT_Lucht, 00_PBT_MAT_staal_S355
Type - Pset_BeamCommon - IsExternal: no; LoadBearing: yes
Type - Pset_ProductRequirements - Category: Structural Framing
Type - Pset_ReinforcementBarPitchOfBeam - Description: HE220A + onderplaat d=12
Type - Pset_Pieters - Breedte: 220 mm; Hoogte: 210 mm; Codering - NL-SfB: 28.11; Omschrijving NL-SfB: hoofddraagconstructies - kolommen en liggers, kolom-/liggerconstructies; Materiaal: 00_PBT_MAT_staal_S355; Materiaalkwaliteit: S355; Description: HE220A + onderplaat d=12
Material: 00_PBT_MAT_staal_S355
Pset_BeamCommon - Reference: 28_PBT_SF_staal_H-profiel_met_onderplaat (void):S355_HE220A + onderplaat d=12; Slope: 1.41522 deg
Pset_QuantityTakeOff - Reference: 28_PBT_SF_staal_H-profiel_met_onderplaat (void):S355_HE220A + onderplaat d=12
Pset_ReinforcementBarPitchOfBeam - Reference: 28_PBT_SF_staal_H-profiel_met_onderplaat (void):S355_HE220A + onderplaat d=12
Pset_Pieters - Bouwlaag: Level: 05 vijfde verdieping; Naamgeving element: 28_PBT_SF_staal_H-profiel_met_onderplaat (void): S355_HE220A + onderplaat d=12; Fase: Nieuw
Name (28_PBT_SF_staal_H-profiel_met_onderplaat (void):S355_HE220A + onderplaat d=12:...) | Span (mm) = Length (mm) | CrossSectionArea (mm2) | OuterSurfaceArea (mm2) | GrossSurfaceArea (mm2) | GrossVolume (m3) | NetVolume (m3) | NetSurfaceArea (mm2)
4401308 | 6716.93 | 10849306 | 5631623 | 5642903 | 0.0329485 | 0.0832896 | 13737383
4401380 | 10008.1 | 16218943 | 11883369 | 11896238 | 0.0609207 | 0.2151 | 21894224

# IfcBeam: 28_PBT_SF_staal_H-profiel_met_onderplaat (void):S355_HE220A + onderplaat d=12 (2)
In: 05 vijfde verdieping
Type - PredefinedType: BEAM; Classification: 28.11 hoofddraagconstructies - kolommen en liggers, kolom-/liggerconstructies (Uniformat); Material: 00_PBT_MAT_staal_S355, 00_PBT_MAT_Lucht
Type - Pset_BeamCommon - IsExternal: no; LoadBearing: yes
Type - Pset_ProductRequirements - Category: Structural Framing
Type - Pset_ReinforcementBarPitchOfBeam - Description: HE220A + onderplaat d=12
Type - Pset_Pieters - Breedte: 220 mm; Hoogte: 210 mm; Codering - NL-SfB: 28.11; Omschrijving NL-SfB: hoofddraagconstructies - kolommen en liggers, kolom-/liggerconstructies; Materiaal: 00_PBT_MAT_staal_S355; Materiaalkwaliteit: S355; Description: HE220A + onderplaat d=12
Material: 00_PBT_MAT_staal_S355
Pset_BeamCommon - Reference: 28_PBT_SF_staal_H-profiel_met_onderplaat (void):S355_HE220A + onderplaat d=12; Slope: 1.41522 deg
Pset_QuantityTakeOff - Reference: 28_PBT_SF_staal_H-profiel_met_onderplaat (void):S355_HE220A + onderplaat d=12
Pset_ReinforcementBarPitchOfBeam - Reference: 28_PBT_SF_staal_H-profiel_met_onderplaat (void):S355_HE220A + onderplaat d=12
Pset_Pieters - Bouwlaag: Level: 05 vijfde verdieping; Naamgeving element: 28_PBT_SF_staal_H-profiel_met_onderplaat (void): S355_HE220A + onderplaat d=12; Fase: Nieuw
Name (28_PBT_SF_staal_H-profiel_met_onderplaat (void):S355_HE220A + onderplaat d=12:...) | Span (mm) = Length (mm) | CrossSectionArea (mm2) | OuterSurfaceArea (mm2) | GrossSurfaceArea (mm2) | GrossVolume (m3) | NetVolume (m3) | NetSurfaceArea (mm2)
4397451 | 6716.93 | 10849306 | 5631623 | 5642903 | 0.0329485 | 0.0832896 | 13737383
4399096 | 10008.1 | 16218943 | 11883369 | 11896238 | 0.0609207 | 0.2151 | 21894224

# IfcBeam: 28_PBT_SF_staal_H-profiel_met_onderplaat (void):S355_HE240A + onderplaat (2)
In: 02 tweede verdieping
Type - PredefinedType: BEAM; Classification: 28.11 hoofddraagconstructies - kolommen en liggers, kolom-/liggerconstructies (Uniformat); Material: 00_PBT_MAT_Lucht, 00_PBT_MAT_staal_S355
Type - Pset_BeamCommon - IsExternal: no; LoadBearing: yes
Type - Pset_ProductRequirements - Category: Structural Framing
Type - Pset_ReinforcementBarPitchOfBeam - Description: HE240A + onderplaat
Type - Pset_Pieters - Breedte: 240 mm; Hoogte: 230 mm; Codering - NL-SfB: 28.11; Omschrijving NL-SfB: hoofddraagconstructies - kolommen en liggers, kolom-/liggerconstructies; Materiaal: 00_PBT_MAT_staal_S355; Materiaalkwaliteit: S355; Description: HE240A + onderplaat
Material: 00_PBT_MAT_staal_S355
Pset_BeamCommon - Slope: 0 deg; Reference: 28_PBT_SF_staal_H-profiel_met_onderplaat (void):S355_HE240A + onderplaat
Pset_QuantityTakeOff - Reference: 28_PBT_SF_staal_H-profiel_met_onderplaat (void):S355_HE240A + onderplaat
Pset_ReinforcementBarPitchOfBeam - Reference: 28_PBT_SF_staal_H-profiel_met_onderplaat (void):S355_HE240A + onderplaat
Pset_Pieters - Bouwlaag: Level: 02 tweede verdieping; Naamgeving element: 28_PBT_SF_staal_H-profiel_met_onderplaat (void): S355_HE240A + onderplaat; Fase: Nieuw
Name (28_PBT_SF_staal_H-profiel_met_onderplaat (void):S355_HE240A + onderplaat:...) | Span (mm) = Length (mm) | CrossSectionArea (mm2) | OuterSurfaceArea (mm2) | GrossSurfaceArea (mm2) | GrossVolume (m3) | NetVolume (m3) | NetSurfaceArea (mm2)
2362312 | 3752.13 | 6819693 | 2410128 | 2419928 | 0.0118096 | 0.104407 | 9348246
2399548 | 3737.13 | 6793750 | 2395128 | 2404928 | 0.0117361 | 0.104218 | 9312712

# IfcBeam: 28_PBT_SF_staal_H-profiel_met_onderplaat (void):S355_HE240A + onderplaat, 28_PBT_SF_staal_H-profiel_met_onderplaat (void):S355_HE240A + onderplaat:2399695
In: 02 tweede verdieping
Type - PredefinedType: BEAM; Classification: 28.11 hoofddraagconstructies - kolommen en liggers, kolom-/liggerconstructies (Uniformat); Material: 00_PBT_MAT_staal_S355, 00_PBT_MAT_Lucht
Type - Pset_BeamCommon - IsExternal: no; LoadBearing: yes
Type - Pset_ProductRequirements - Category: Structural Framing
Type - Pset_ReinforcementBarPitchOfBeam - Description: HE240A + onderplaat
Type - Pset_Pieters - Breedte: 240 mm; Hoogte: 230 mm; Codering - NL-SfB: 28.11; Omschrijving NL-SfB: hoofddraagconstructies - kolommen en liggers, kolom-/liggerconstructies; Materiaal: 00_PBT_MAT_staal_S355; Materiaalkwaliteit: S355; Description: HE240A + onderplaat
Material: 00_PBT_MAT_staal_S355
Pset_BeamCommon - Slope: 0 deg; Reference: 28_PBT_SF_staal_H-profiel_met_onderplaat (void):S355_HE240A + onderplaat; Span: 3752.13 mm
Pset_QuantityTakeOff - Reference: 28_PBT_SF_staal_H-profiel_met_onderplaat (void):S355_HE240A + onderplaat
Pset_ReinforcementBarPitchOfBeam - Reference: 28_PBT_SF_staal_H-profiel_met_onderplaat (void):S355_HE240A + onderplaat
Pset_Pieters - Bouwlaag: Level: 02 tweede verdieping; Naamgeving element: 28_PBT_SF_staal_H-profiel_met_onderplaat (void): S355_HE240A + onderplaat; Fase: Nieuw
BaseQuantities - Length: 3752.13 mm; CrossSectionArea: 6819693 mm2; OuterSurfaceArea: 2410128 mm2; GrossSurfaceArea: 2419928 mm2; GrossVolume: 0.0118096 m3; NetVolume: 0.104407 m3; NetSurfaceArea: 9348246 mm2

# IfcBeam: 28_PBT_SF_staal_H-profiel_met_onderplaat (void):S355_HE260A + onderplaat d=12 (9)
In: 04 vierde verdieping
Type - PredefinedType: BEAM; Classification: 28.11 hoofddraagconstructies - kolommen en liggers, kolom-/liggerconstructies (Uniformat); Material: 00_PBT_MAT_Lucht, 00_PBT_MAT_staal_S355
Type - Pset_BeamCommon - IsExternal: no; LoadBearing: yes
Type - Pset_ProductRequirements - Category: Structural Framing
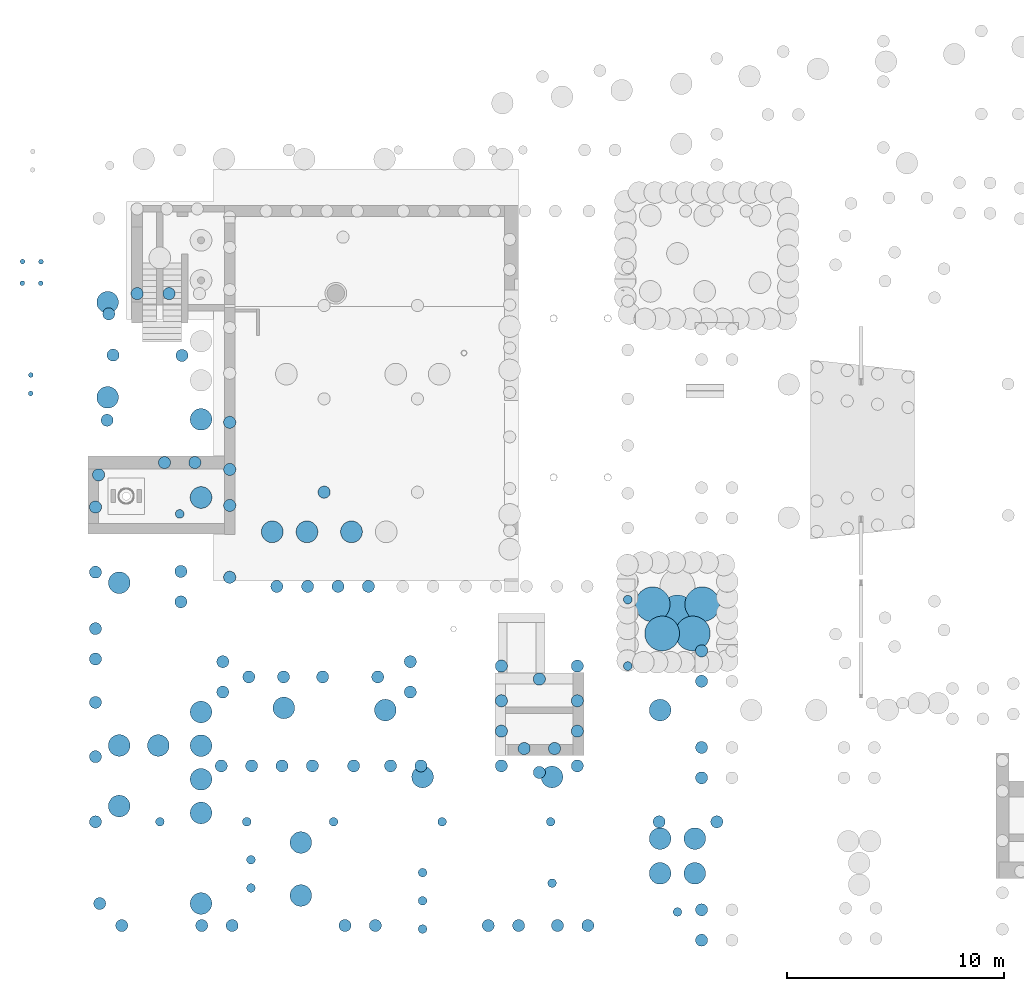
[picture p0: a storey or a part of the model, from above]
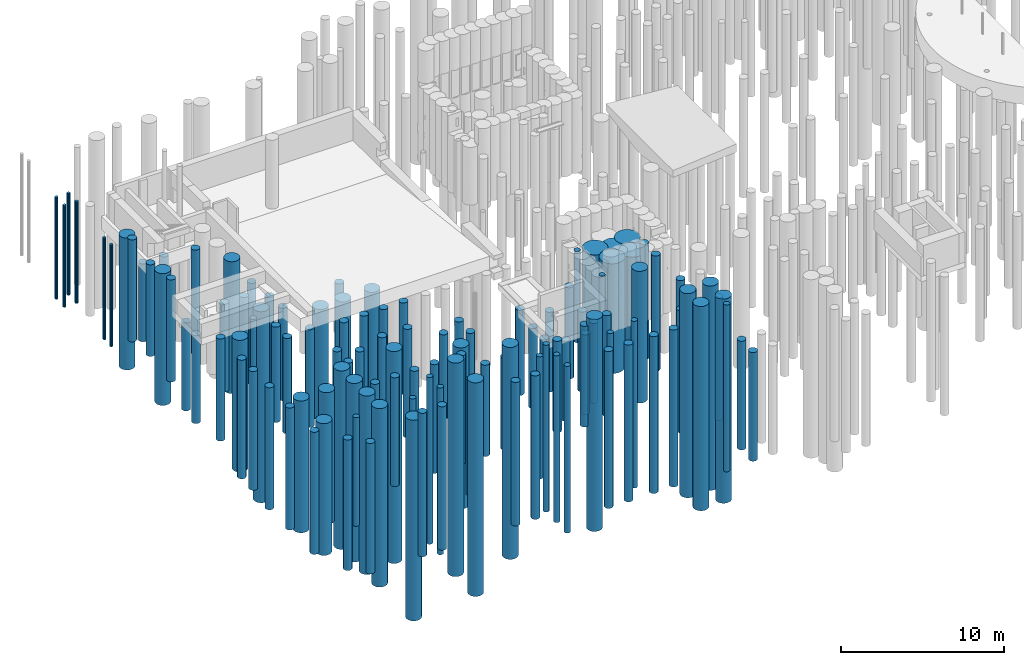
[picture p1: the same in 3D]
Properties of the parts of a building model (IFC2X3), part 5 of 18

# IfcBeam: 28_PBT_SF_staal_H-profiel_met_onderplaat (void):S355_HE260A + onderplaat d=12 (9)
Type - Pset_ReinforcementBarPitchOfBeam - Description: HE260A + onderplaat d=12
Type - Pset_Pieters - Breedte: 260 mm; Hoogte: 250 mm; Codering - NL-SfB: 28.11; Omschrijving NL-SfB: hoofddraagconstructies - kolommen en liggers, kolom-/liggerconstructies; Materiaal: 00_PBT_MAT_staal_S355; Materiaalkwaliteit: S355; Description: HE260A + onderplaat d=12
Material: 00_PBT_MAT_staal_S355
Pset_BeamCommon - Reference: 28_PBT_SF_staal_H-profiel_met_onderplaat (void):S355_HE260A + onderplaat d=12
Pset_QuantityTakeOff - Reference: 28_PBT_SF_staal_H-profiel_met_onderplaat (void):S355_HE260A + onderplaat d=12
Pset_ReinforcementBarPitchOfBeam - Reference: 28_PBT_SF_staal_H-profiel_met_onderplaat (void):S355_HE260A + onderplaat d=12
Pset_Pieters - Bouwlaag: Level: 04 vierde verdieping; Naamgeving element: 28_PBT_SF_staal_H-profiel_met_onderplaat (void): S355_HE260A + onderplaat d=12; Fase: Nieuw
Name (28_PBT_SF_staal_H-profiel_met_onderplaat (void):S355_HE260A + onderplaat d=12:...) | Span (mm) = Length (mm) | Slope (deg) | CrossSectionArea (mm2) | OuterSurfaceArea (mm2) | GrossSurfaceArea (mm2) | GrossVolume (m3) | NetVolume (m3) | NetSurfaceArea (mm2)
2795669 | 1540.6 | 4.57 | 2862092 | 1369999 | 1382239 | 0.00803103 | 0.0195079 | 3361101
2797981 | 2300 | 9 | 4328692 | 2183520 | 2195760 | 0.0127999 | 0.0311243 | 5345044
2797983 | 3215.52 | 9 | 4583623 | 4771182 | 4788546 | 0.027918 | 0.0475962 | 8157792
2798065 | 3560 | 4.57 | 5019007 | 5282315 | 5299680 | 0.0309089 | 0.0526952 | 9028560
2798067 | 2300 | 9 | 4328692 | 2183520 | 2195760 | 0.0127999 | 0.0311243 | 5345044
2798073 | 5520 | 21.3 | 7496247 | 8190556 | 8207921 | 0.0479261 | 0.0817071 | 13983041
2798128 | 3622.7 | 4.57 | 4760133 | 4978402 | 4995767 | 0.0291306 | 0.0496634 | 8510813
2798130 | 2300 | 9 | 4328692 | 2183520 | 2195760 | 0.0127999 | 0.0311243 | 5345044
2831417 | 5372.37 | 0 | 11250097 | 7971509 | 7988874 | 0.0466444 | 0.187514 | 15379097 | Pset_Pieters - Zeeg: 10

# IfcBeam: 28_PBT_SF_staal_H-profiel_met_onderplaat (void):S355_HE260A + onderplaat d=12 (12)
In: 04 vierde verdieping
Type - PredefinedType: BEAM; Classification: 28.11 hoofddraagconstructies - kolommen en liggers, kolom-/liggerconstructies (Uniformat); Material: 00_PBT_MAT_staal_S355, 00_PBT_MAT_Lucht
Type - Pset_BeamCommon - IsExternal: no; LoadBearing: yes
Type - Pset_ProductRequirements - Category: Structural Framing
Type - Pset_ReinforcementBarPitchOfBeam - Description: HE260A + onderplaat d=12
Type - Pset_Pieters - Breedte: 260 mm; Hoogte: 250 mm; Codering - NL-SfB: 28.11; Omschrijving NL-SfB: hoofddraagconstructies - kolommen en liggers, kolom-/liggerconstructies; Materiaal: 00_PBT_MAT_staal_S355; Materiaalkwaliteit: S355; Description: HE260A + onderplaat d=12
Material: 00_PBT_MAT_staal_S355
Pset_BeamCommon - Reference: 28_PBT_SF_staal_H-profiel_met_onderplaat (void):S355_HE260A + onderplaat d=12
Pset_QuantityTakeOff - Reference: 28_PBT_SF_staal_H-profiel_met_onderplaat (void):S355_HE260A + onderplaat d=12
Pset_ReinforcementBarPitchOfBeam - Reference: 28_PBT_SF_staal_H-profiel_met_onderplaat (void):S355_HE260A + onderplaat d=12
Pset_Pieters - Bouwlaag: Level: 04 vierde verdieping; Naamgeving element: 28_PBT_SF_staal_H-profiel_met_onderplaat (void): S355_HE260A + onderplaat d=12; Fase: Nieuw
Name (28_PBT_SF_staal_H-profiel_met_onderplaat (void):S355_HE260A + onderplaat d=12:...) | Span (mm) = Length (mm) | Slope (deg) | CrossSectionArea (mm2) | OuterSurfaceArea (mm2) | GrossSurfaceArea (mm2) | GrossVolume (m3) | NetVolume (m3) | NetSurfaceArea (mm2)
2751438 | 3520 | 4.57 | 4952399 | 5204119 | 5221484 | 0.0304513 | 0.0519151 | 8895345
2751693 | 2300 | 9 | 4328692 | 2183520 | 2195760 | 0.0127999 | 0.0311243 | 5345044
2751732 | 3180 | 9 | 4538726 | 4718473 | 4735837 | 0.0276096 | 0.0470704 | 8067997
2796358 | 5524.77 | 21.3 | 7502276 | 8197634 | 8214998 | 0.0479676 | 0.0817777 | 13995098
2797978 | 3652.32 | 4.57 | 4797571 | 5022353 | 5039718 | 0.0293878 | 0.0501019 | 8585689
2797985 | 1320 | 4.57 | 2445410 | 1139697 | 1151937 | 0.00668098 | 0.0162426 | 2803481
2797987 | 4265 | 21.3 | 8446840 | 6167300 | 6184664 | 0.0360873 | 0.107556 | 11156800
2798069 | 3180 | 9 | 4538726 |  |  |  | 0.0470704 | 8067997
2798071 | 1320 | 4.57 | 2445410 | 1139697 | 1151937 | 0.00668098 | 0.0162426 | 2803481
2798132 | 3200 | 9 | 4564004 | 4748149 | 4765513 | 0.0277833 | 0.0473665 | 8118553
2798134 | 1300 | 4.57 | 2407633 | 1118817 | 1131057 | 0.00655858 | 0.0159466 | 2752925
2798136 | 4140 | 21.3 | 5752068 | 6142917 | 6160282 | 0.0359446 | 0.0612803 | 10494682

# IfcBeam: 28_PBT_SF_staal_H-profiel_met_onderplaat (void):S355_HE260B + onderplaat d=12, 28_PBT_SF_staal_H-profiel_met_onderplaat (void):S355_HE260B + onderplaat d=12:2359846
In: 01 eerste verdieping
Type - PredefinedType: BEAM; Classification: 28.11 hoofddraagconstructies - kolommen en liggers, kolom-/liggerconstructies (Uniformat); Material: 00_PBT_MAT_staal_S355, 00_PBT_MAT_Lucht
Type - Pset_BeamCommon - IsExternal: no; LoadBearing: yes
Type - Pset_ProductRequirements - Category: Structural Framing
Type - Pset_ReinforcementBarPitchOfBeam - Description: HE260B + onderplaat d=12
Type - Pset_Pieters - Breedte: 260 mm; Hoogte: 260 mm; Codering - NL-SfB: 28.11; Omschrijving NL-SfB: hoofddraagconstructies - kolommen en liggers, kolom-/liggerconstructies; Materiaal: 00_PBT_MAT_staal_S355; Materiaalkwaliteit: S355; Description: HE260B + onderplaat d=12
Material: 00_PBT_MAT_staal_S355
Pset_BeamCommon - Slope: 0 deg; Reference: 28_PBT_SF_staal_H-profiel_met_onderplaat (void):S355_HE260B + onderplaat d=12; Span: 5372.37 mm
Pset_QuantityTakeOff - Reference: 28_PBT_SF_staal_H-profiel_met_onderplaat (void):S355_HE260B + onderplaat d=12
Pset_ReinforcementBarPitchOfBeam - Reference: 28_PBT_SF_staal_H-profiel_met_onderplaat (void):S355_HE260B + onderplaat d=12
Pset_Pieters - Bouwlaag: Level: 01 eerste verdieping; Naamgeving element: 28_PBT_SF_staal_H-profiel_met_onderplaat (void): S355_HE260B + onderplaat d=12; Fase: Nieuw; Zeeg: 10
BaseQuantities - Length: 5372.37 mm; CrossSectionArea: 11114310 mm2; OuterSurfaceArea: 8052095 mm2; GrossSurfaceArea: 8075784 mm2; GrossVolume: 0.0636345 m3; NetVolume: 0.194677 m3; NetSurfaceArea: 15316893 mm2

# IfcBeam: 28_PBT_SF_staal_H-profiel_met_onderplaat (void):S355_HE280B + onderplaat d=12 (11)
Type - PredefinedType: BEAM; Classification: 28.11 hoofddraagconstructies - kolommen en liggers, kolom-/liggerconstructies (Uniformat); Material: 00_PBT_MAT_Lucht, 00_PBT_MAT_staal_S355
Type - Pset_BeamCommon - IsExternal: no; LoadBearing: yes
Type - Pset_ProductRequirements - Category: Structural Framing
Type - Pset_ReinforcementBarPitchOfBeam - Description: HE280B + onderplaat d=12
Type - Pset_Pieters - Breedte: 280 mm; Hoogte: 280 mm; Codering - NL-SfB: 28.11; Omschrijving NL-SfB: hoofddraagconstructies - kolommen en liggers, kolom-/liggerconstructies; Materiaal: 00_PBT_MAT_staal_S355; Materiaalkwaliteit: S355; Description: HE280B + onderplaat d=12
Material: 00_PBT_MAT_staal_S355
Pset_BeamCommon - Slope: 0 deg; Reference: 28_PBT_SF_staal_H-profiel_met_onderplaat (void):S355_HE280B + onderplaat d=12
Pset_QuantityTakeOff - Reference: 28_PBT_SF_staal_H-profiel_met_onderplaat (void):S355_HE280B + onderplaat d=12
Pset_ReinforcementBarPitchOfBeam - Reference: 28_PBT_SF_staal_H-profiel_met_onderplaat (void):S355_HE280B + onderplaat d=12
Pset_Pieters - Naamgeving element: 28_PBT_SF_staal_H-profiel_met_onderplaat (void): S355_HE280B + onderplaat d=12; Fase: Nieuw
Name (28_PBT_SF_staal_H-profiel_met_onderplaat (void):S355_HE280B + onderplaat d=12:...) | In | Span (mm) = Length (mm) | Bouwlaag | CrossSectionArea (mm2) | OuterSurfaceArea (mm2) | GrossSurfaceArea (mm2) | GrossVolume (m3) | NetVolume (m3) | NetSurfaceArea (mm2)
2270918 | 02 tweede verdieping | 1327 | Level: 02 tweede verdieping | 2366385 | 2146820 | 2173094 | 0.0174325 | 0.0258719 | 3624284 | Pset_Pieters - Comments: Momentvast verbinden aan kolom
2271828 | 02 tweede verdieping | 1327 | Level: 02 tweede verdieping | 2366385 |  |  |  | 0.0258719 | 3624284 | Pset_Pieters - Comments: Momentvast verbinden aan kolom
2271833 | 02 tweede verdieping | 1327 | Level: 02 tweede verdieping | 2366385 |  |  |  | 0.0258719 | 3624284 | Pset_Pieters - Comments: Momentvast verbinden aan kolom
2273016 | 02 tweede verdieping | 1327 | Level: 02 tweede verdieping | 2366385 |  |  |  | 0.0258719 | 3624284 | Pset_Pieters - Comments: Momentvast verbinden aan kolom
2646918 | 05 vijfde verdieping | 4498 | Level: 05 vijfde verdieping | 10004416 | 7276849 | 7303122 | 0.0590892 | 0.187436 | 13787781
2647691 | 06 zesde verdieping | 4088.16 | Level: 06 zesde verdieping | 8416757 | 6699761 | 6726035 | 0.0544032 | 0.0796007 | 11040911
2662486 | 05 vijfde verdieping | 4498 | Level: 05 vijfde verdieping | 9222217 | 4875832 | 4888552 | 0.0286073 | 0.0876953 | 12191675
2662552 | 05 vijfde verdieping | 4498 | Level: 05 vijfde verdieping | 10009666 | 7276849 | 7303122 | 0.0590892 | 0.187436 | 13787781
2666648 | 06 zesde verdieping | 4088.16 | Level: 06 zesde verdieping | 8404211 | 4431561 | 4444281 | 0.0260007 | 0.0797048 | 11084360
3729274 | 05 vijfde verdieping | 4498 | Level: 05 vijfde verdieping | 9222217 | 4875832 | 4888552 | 0.0286073 | 0.0876953 | 12191675
3729825 | 06 zesde verdieping | 4088.16 | Level: 06 zesde verdieping | 8416757 | 6699761 | 6726035 | 0.0544032 | 0.0796007 | 11040911

# IfcBeam: 28_PBT_SF_staal_H-profiel_met_onderplaat (void):S355_HE280B + onderplaat d=12 (6)
Type - PredefinedType: BEAM; Classification: 28.11 hoofddraagconstructies - kolommen en liggers, kolom-/liggerconstructies (Uniformat); Material: 00_PBT_MAT_staal_S355, 00_PBT_MAT_Lucht
Type - Pset_BeamCommon - IsExternal: no; LoadBearing: yes
Type - Pset_ProductRequirements - Category: Structural Framing
Type - Pset_ReinforcementBarPitchOfBeam - Description: HE280B + onderplaat d=12
Type - Pset_Pieters - Breedte: 280 mm; Hoogte: 280 mm; Codering - NL-SfB: 28.11; Omschrijving NL-SfB: hoofddraagconstructies - kolommen en liggers, kolom-/liggerconstructies; Materiaal: 00_PBT_MAT_staal_S355; Materiaalkwaliteit: S355; Description: HE280B + onderplaat d=12
Material: 00_PBT_MAT_staal_S355
Pset_BeamCommon - Slope: 0 deg; Reference: 28_PBT_SF_staal_H-profiel_met_onderplaat (void):S355_HE280B + onderplaat d=12
Pset_QuantityTakeOff - Reference: 28_PBT_SF_staal_H-profiel_met_onderplaat (void):S355_HE280B + onderplaat d=12
Pset_ReinforcementBarPitchOfBeam - Reference: 28_PBT_SF_staal_H-profiel_met_onderplaat (void):S355_HE280B + onderplaat d=12
Pset_Pieters - Naamgeving element: 28_PBT_SF_staal_H-profiel_met_onderplaat (void): S355_HE280B + onderplaat d=12; Fase: Nieuw
Name (28_PBT_SF_staal_H-profiel_met_onderplaat (void):S355_HE280B + onderplaat d=12:...) | In | Span (mm) = Length (mm) | Bouwlaag | CrossSectionArea (mm2) | OuterSurfaceArea (mm2) | GrossSurfaceArea (mm2) | GrossVolume (m3) | NetVolume (m3) | NetSurfaceArea (mm2)
2213754 | 02 tweede verdieping | 1817 | Level: 02 tweede verdieping | 2960777 | 2858646 | 2884920 | 0.0232127 | 0.0344503 | 4813068 | Pset_Pieters - Comments: Momentvast verbinden aan kolom
2213756 | 02 tweede verdieping | 1817 | Level: 02 tweede verdieping | 2960778 | 2858648 | 2884922 | 0.0232127 | 0.0344504 | 4813071 | Pset_Pieters - Comments: Momentvast verbinden aan kolom
2646921 | 06 zesde verdieping | 4088.16 | Level: 06 zesde verdieping | 8404211 | 4431561 | 4444281 | 0.0260007 | 0.0797048 | 11084360
2647297 | 05 vijfde verdieping | 4533 | Level: 05 vijfde verdieping | 9286824 | 4913772 | 4926492 | 0.0288299 | 0.0883777 | 12286238
2666637 | 06 zesde verdieping | 4088.16 | Level: 06 zesde verdieping | 8465123 |  |  |  | 0.0800709 | 11137644
5913829 | 02 tweede verdieping | 1582.95 | Level: 02 tweede verdieping | 3556300 | 1715913 | 1728633 | 0.0100675 | 0.0308619 | 4315789

# IfcBeam: 28_PBT_SF_staal_H-profiel_met_onderplaat (void):S355_HE280B + onderplaat d=15 (3)
Type - PredefinedType: BEAM; Classification: 28.11 hoofddraagconstructies - kolommen en liggers, kolom-/liggerconstructies (Uniformat); Material: 00_PBT_MAT_Lucht, 00_PBT_MAT_staal_S355
Type - Pset_BeamCommon - IsExternal: no; LoadBearing: yes
Type - Pset_ProductRequirements - Category: Structural Framing
Type - Pset_ReinforcementBarPitchOfBeam - Description: HE280B + onderplaat d=15
Type - Pset_Pieters - Breedte: 280 mm; Hoogte: 280 mm; Codering - NL-SfB: 28.11; Omschrijving NL-SfB: hoofddraagconstructies - kolommen en liggers, kolom-/liggerconstructies; Materiaal: 00_PBT_MAT_staal_S355; Materiaalkwaliteit: S355; Description: HE280B + onderplaat d=15
Material: 00_PBT_MAT_staal_S355
Pset_BeamCommon - Slope: 0 deg; Reference: 28_PBT_SF_staal_H-profiel_met_onderplaat (void):S355_HE280B + onderplaat d=15
Pset_QuantityTakeOff - Reference: 28_PBT_SF_staal_H-profiel_met_onderplaat (void):S355_HE280B + onderplaat d=15
Pset_ReinforcementBarPitchOfBeam - Reference: 28_PBT_SF_staal_H-profiel_met_onderplaat (void):S355_HE280B + onderplaat d=15
Pset_Pieters - Naamgeving element: 28_PBT_SF_staal_H-profiel_met_onderplaat (void): S355_HE280B + onderplaat d=15; Fase: Nieuw
Name (28_PBT_SF_staal_H-profiel_met_onderplaat (void):S355_HE280B + onderplaat d=15:...) | In | Span (mm) = Length (mm) | Bouwlaag | CrossSectionArea (mm2) | OuterSurfaceArea (mm2) | GrossSurfaceArea (mm2) | GrossVolume (m3) | NetVolume (m3) | NetSurfaceArea (mm2)
2646747 | 04 vierde verdieping | 4498 | Level: 04 vierde verdieping | 9237301 | 4902820 | 4918720 | 0.0357591 | 0.0948471 | 12221843
3391876 | 03 derde verdieping | 4274.69 | Level: 03 derde verdieping | 9338264 | 1770914 | 1786814 | 0.0129163 | 0.242019 | 12764756
4256499 | 03 derde verdieping | 8880.4 | Level: 03 derde verdieping | 17146650 | 9511772 | 9527672 | 0.0693748 | 0.184009 | 23671478

# IfcBeam: 28_PBT_SF_staal_H-profiel_met_onderplaat (void):S355_HE280B + onderplaat d=15 (4)
Type - PredefinedType: BEAM; Classification: 28.11 hoofddraagconstructies - kolommen en liggers, kolom-/liggerconstructies (Uniformat); Material: 00_PBT_MAT_staal_S355, 00_PBT_MAT_Lucht
Type - Pset_BeamCommon - IsExternal: no; LoadBearing: yes
Type - Pset_ProductRequirements - Category: Structural Framing
Type - Pset_ReinforcementBarPitchOfBeam - Description: HE280B + onderplaat d=15
Type - Pset_Pieters - Breedte: 280 mm; Hoogte: 280 mm; Codering - NL-SfB: 28.11; Omschrijving NL-SfB: hoofddraagconstructies - kolommen en liggers, kolom-/liggerconstructies; Materiaal: 00_PBT_MAT_staal_S355; Materiaalkwaliteit: S355; Description: HE280B + onderplaat d=15
Material: 00_PBT_MAT_staal_S355
Pset_BeamCommon - Slope: 0 deg; Reference: 28_PBT_SF_staal_H-profiel_met_onderplaat (void):S355_HE280B + onderplaat d=15
Pset_QuantityTakeOff - Reference: 28_PBT_SF_staal_H-profiel_met_onderplaat (void):S355_HE280B + onderplaat d=15
Pset_ReinforcementBarPitchOfBeam - Reference: 28_PBT_SF_staal_H-profiel_met_onderplaat (void):S355_HE280B + onderplaat d=15
Pset_Pieters - Naamgeving element: 28_PBT_SF_staal_H-profiel_met_onderplaat (void): S355_HE280B + onderplaat d=15; Fase: Nieuw
Name (28_PBT_SF_staal_H-profiel_met_onderplaat (void):S355_HE280B + onderplaat d=15:...) | In | Span (mm) = Length (mm) | Bouwlaag | CrossSectionArea (mm2) | OuterSurfaceArea (mm2) | GrossSurfaceArea (mm2) | GrossVolume (m3) | NetVolume (m3) | NetSurfaceArea (mm2)
2452160 | 04 vierde verdieping | 4498 | Level: 04 vierde verdieping | 9237301 | 4902820 | 4918720 | 0.0357591 | 0.0948471 | 12221843
3391861 | 03 derde verdieping | 4274.69 | Level: 03 derde verdieping | 9338264 | 1770914 | 1786814 | 0.0129163 | 0.242019 | 12764756
3392078 | 03 derde verdieping | 4274.69 | Level: 03 derde verdieping | 9338264 | 1770914 | 1786814 | 0.0129163 | 0.242019 | 12764756
3393210 | 03 derde verdieping | 4274.69 | Level: 03 derde verdieping | 9707347 | 6915581 | 6941855 | 0.0561557 | 0.171445 | 12946212

# IfcBeam: 28_PBT_SF_staal_H-profiel_met_onderplaat (void):S355_HE300A + onderplaat d=12 (2)
In: 04 vierde verdieping
Type - PredefinedType: BEAM; Classification: 28.11 hoofddraagconstructies - kolommen en liggers, kolom-/liggerconstructies (Uniformat); Material: 00_PBT_MAT_staal_S355, 00_PBT_MAT_Lucht
Type - Pset_BeamCommon - IsExternal: no; LoadBearing: yes
Type - Pset_ProductRequirements - Category: Structural Framing
Type - Pset_ReinforcementBarPitchOfBeam - Description: HE300A + onderplaat d=12
Type - Pset_Pieters - Breedte: 300 mm; Hoogte: 290 mm; Codering - NL-SfB: 28.11; Omschrijving NL-SfB: hoofddraagconstructies - kolommen en liggers, kolom-/liggerconstructies; Materiaal: 00_PBT_MAT_staal_S355; Materiaalkwaliteit: S355; Description: HE300A + onderplaat d=12
Material: 00_PBT_MAT_staal_S355
Pset_BeamCommon - Slope: 0 deg; Reference: 28_PBT_SF_staal_H-profiel_met_onderplaat (void):S355_HE300A + onderplaat d=12
Pset_QuantityTakeOff - Reference: 28_PBT_SF_staal_H-profiel_met_onderplaat (void):S355_HE300A + onderplaat d=12
Pset_ReinforcementBarPitchOfBeam - Reference: 28_PBT_SF_staal_H-profiel_met_onderplaat (void):S355_HE300A + onderplaat d=12
Pset_Pieters - Bouwlaag: Level: 04 vierde verdieping; Naamgeving element: 28_PBT_SF_staal_H-profiel_met_onderplaat (void): S355_HE300A + onderplaat d=12; Fase: Nieuw
Name (28_PBT_SF_staal_H-profiel_met_onderplaat (void):S355_HE300A + onderplaat d=12:...) | Span (mm) = Length (mm) | CrossSectionArea (mm2) | OuterSurfaceArea (mm2) | GrossSurfaceArea (mm2) | GrossVolume (m3) | NetVolume (m3) | NetSurfaceArea (mm2)
2846329 | 3300 | 6643883 | 3290634 | 3303834 | 0.0193222 | 0.0528078 | 8435426
4258443 | 3420 | 6849079 | 3389869 | 3403069 | 0.0199049 | 0.054384 | 8686218

# IfcBeam: 28_PBT_SF_staal_H-profiel_met_onderplaat (void):S355_HE300B + onderplaat d=12 (2)
Type - PredefinedType: BEAM; Classification: 28.11 hoofddraagconstructies - kolommen en liggers, kolom-/liggerconstructies (Uniformat); Material: 00_PBT_MAT_Lucht, 00_PBT_MAT_staal_S355
Type - Pset_BeamCommon - IsExternal: no; LoadBearing: yes
Type - Pset_ProductRequirements - Category: Structural Framing
Type - Pset_ReinforcementBarPitchOfBeam - Description: HE300B + onderplaat d=12
Type - Pset_Pieters - Breedte: 300 mm; Hoogte: 300 mm; Codering - NL-SfB: 28.11; Omschrijving NL-SfB: hoofddraagconstructies - kolommen en liggers, kolom-/liggerconstructies; Materiaal: 00_PBT_MAT_staal_S355; Materiaalkwaliteit: S355; Description: HE300B + onderplaat d=12
Material: 00_PBT_MAT_staal_S355
Pset_BeamCommon - Slope: 0 deg; Reference: 28_PBT_SF_staal_H-profiel_met_onderplaat (void):S355_HE300B + onderplaat d=12
Pset_QuantityTakeOff - Reference: 28_PBT_SF_staal_H-profiel_met_onderplaat (void):S355_HE300B + onderplaat d=12
Pset_ReinforcementBarPitchOfBeam - Reference: 28_PBT_SF_staal_H-profiel_met_onderplaat (void):S355_HE300B + onderplaat d=12
Pset_Pieters - Naamgeving element: 28_PBT_SF_staal_H-profiel_met_onderplaat (void): S355_HE300B + onderplaat d=12; Fase: Nieuw
Name (28_PBT_SF_staal_H-profiel_met_onderplaat (void):S355_HE300B + onderplaat d=12:...) | In | Span (mm) = Length (mm) | Bouwlaag | CrossSectionArea (mm2) | OuterSurfaceArea (mm2) | GrossSurfaceArea (mm2) | GrossVolume (m3) | NetVolume (m3) | NetSurfaceArea (mm2)
2830634 | 04 vierde verdieping | 4815 | Level: 04 vierde verdieping | 11232784 | 8337876 | 8367692 | 0.071783 | 0.237069 | 15833687
2961882 | 05 vijfde verdieping | 7228 | Level: 05 vijfde verdieping | 16178341 | 12251915 | 12281731 | 0.10548 | 0.395029 | 22536113 | Pset_Pieters - Zeeg: 20

# IfcBeam: 28_PBT_SF_staal_H-profiel_met_onderplaat (void):S355_HE300B + onderplaat d=12 (5)
Type - PredefinedType: BEAM; Classification: 28.11 hoofddraagconstructies - kolommen en liggers, kolom-/liggerconstructies (Uniformat); Material: 00_PBT_MAT_staal_S355, 00_PBT_MAT_Lucht
Type - Pset_BeamCommon - IsExternal: no; LoadBearing: yes
Type - Pset_ProductRequirements - Category: Structural Framing
Type - Pset_ReinforcementBarPitchOfBeam - Description: HE300B + onderplaat d=12
Type - Pset_Pieters - Breedte: 300 mm; Hoogte: 300 mm; Codering - NL-SfB: 28.11; Omschrijving NL-SfB: hoofddraagconstructies - kolommen en liggers, kolom-/liggerconstructies; Materiaal: 00_PBT_MAT_staal_S355; Materiaalkwaliteit: S355; Description: HE300B + onderplaat d=12
Material: 00_PBT_MAT_staal_S355
Pset_BeamCommon - Slope: 0 deg; Reference: 28_PBT_SF_staal_H-profiel_met_onderplaat (void):S355_HE300B + onderplaat d=12
Pset_QuantityTakeOff - Reference: 28_PBT_SF_staal_H-profiel_met_onderplaat (void):S355_HE300B + onderplaat d=12
Pset_ReinforcementBarPitchOfBeam - Reference: 28_PBT_SF_staal_H-profiel_met_onderplaat (void):S355_HE300B + onderplaat d=12
Pset_Pieters - Naamgeving element: 28_PBT_SF_staal_H-profiel_met_onderplaat (void): S355_HE300B + onderplaat d=12; Fase: Nieuw
Name (28_PBT_SF_staal_H-profiel_met_onderplaat (void):S355_HE300B + onderplaat d=12:...) | In | Span (mm) = Length (mm) | Bouwlaag | CrossSectionArea (mm2) | OuterSurfaceArea (mm2) | GrossSurfaceArea (mm2) | GrossVolume (m3) | NetVolume (m3) | NetSurfaceArea (mm2)
2449946 | 03 derde verdieping | 3953.21 | Level: 03 derde verdieping | 9322317 | 6845560 | 6875377 | 0.0589352 | 0.157357 | 12472021
2450725 | 04 vierde verdieping | 7200 | Level: 04 vierde verdieping | 16409705 | 12467851 | 12497668 | 0.107339 | 0.303299 | 22864279
2961576 | 05 vijfde verdieping | 6672 | Level: 05 vijfde verdieping | 13795769 | 7499326 | 7512526 | 0.0440352 | 0.1435 | 19095881
4237456 | 03 derde verdieping | 4685 | Level: 03 derde verdieping | 10560848 | 5265937 | 5279137 | 0.030921 | 0.100764 | 13421711
4714041 | 05 vijfde verdieping | 12440 | Level: 06 ok ruwe vloer toneeltoren | 18351691 | 21497692 | 21527509 | 0.185079 | 0.267012 | 35494719

# IfcBeam: 28_PBT_SF_staal_H-profiel_met_onderplaat (void):S355_HE300B + onderplaat d=15 (2)
Type - PredefinedType: BEAM; Classification: 28.11 hoofddraagconstructies - kolommen en liggers, kolom-/liggerconstructies (Uniformat); Material: 00_PBT_MAT_Lucht, 00_PBT_MAT_staal_S355
Type - Pset_BeamCommon - IsExternal: no; LoadBearing: yes
Type - Pset_ProductRequirements - Category: Structural Framing
Type - Pset_ReinforcementBarPitchOfBeam - Description: HE300B + onderplaat d=15
Type - Pset_Pieters - Breedte: 300 mm; Hoogte: 300 mm; Codering - NL-SfB: 28.11; Omschrijving NL-SfB: hoofddraagconstructies - kolommen en liggers, kolom-/liggerconstructies; Materiaal: 00_PBT_MAT_staal_S355; Materiaalkwaliteit: S355; Description: HE300B + onderplaat d=15
Material: 00_PBT_MAT_staal_S355
Pset_BeamCommon - Slope: 0 deg; Reference: 28_PBT_SF_staal_H-profiel_met_onderplaat (void):S355_HE300B + onderplaat d=15; Span: 10580.6 mm
Pset_QuantityTakeOff - Reference: 28_PBT_SF_staal_H-profiel_met_onderplaat (void):S355_HE300B + onderplaat d=15
Pset_ReinforcementBarPitchOfBeam - Reference: 28_PBT_SF_staal_H-profiel_met_onderplaat (void):S355_HE300B + onderplaat d=15
Pset_Pieters - Naamgeving element: 28_PBT_SF_staal_H-profiel_met_onderplaat (void): S355_HE300B + onderplaat d=15; Fase: Nieuw
BaseQuantities - Length: 10580.6 mm; OuterSurfaceArea: 18040134 mm2; GrossSurfaceArea: 18069950 mm2; GrossVolume: 0.155312 m3
Name (28_PBT_SF_staal_H-profiel_met_onderplaat (void):S355_HE300B + onderplaat d=15:...) | In | Bouwlaag | CrossSectionArea (mm2) | NetVolume (m3) | NetSurfaceArea (mm2)
2393541 | 01 eerste verdieping | Level: 01 eerste verdieping | 23484953 | 0.429453 | 32734955
2413498 | 02 tweede verdieping | Level: 02 tweede verdieping | 23766554 | 0.467292 | 33298157

# IfcBeam: 28_PBT_SF_staal_H-profiel_met_onderplaat (void):S355_HE300B + onderplaat d=15 (2)
In: 04 vierde verdieping
Type - PredefinedType: BEAM; Classification: 28.11 hoofddraagconstructies - kolommen en liggers, kolom-/liggerconstructies (Uniformat); Material: 00_PBT_MAT_staal_S355, 00_PBT_MAT_Lucht
Type - Pset_BeamCommon - IsExternal: no; LoadBearing: yes
Type - Pset_ProductRequirements - Category: Structural Framing
Type - Pset_ReinforcementBarPitchOfBeam - Description: HE300B + onderplaat d=15
Type - Pset_Pieters - Breedte: 300 mm; Hoogte: 300 mm; Codering - NL-SfB: 28.11; Omschrijving NL-SfB: hoofddraagconstructies - kolommen en liggers, kolom-/liggerconstructies; Materiaal: 00_PBT_MAT_staal_S355; Materiaalkwaliteit: S355; Description: HE300B + onderplaat d=15
Material: 00_PBT_MAT_staal_S355
Pset_BeamCommon - Slope: 0 deg; Reference: 28_PBT_SF_staal_H-profiel_met_onderplaat (void):S355_HE300B + onderplaat d=15; Span: 4062 mm
Pset_QuantityTakeOff - Reference: 28_PBT_SF_staal_H-profiel_met_onderplaat (void):S355_HE300B + onderplaat d=15
Pset_ReinforcementBarPitchOfBeam - Reference: 28_PBT_SF_staal_H-profiel_met_onderplaat (void):S355_HE300B + onderplaat d=15
Pset_Pieters - Bouwlaag: Level: 04 vierde verdieping; Naamgeving element: 28_PBT_SF_staal_H-profiel_met_onderplaat (void): S355_HE300B + onderplaat d=15; Fase: Nieuw
BaseQuantities - Length: 4062 mm; CrossSectionArea: 8909486 mm2; OuterSurfaceArea: 4025060 mm2; GrossSurfaceArea: 4041560 mm2; GrossVolume: 0.0293865 m3; NetVolume: 0.127488 m3; NetSurfaceArea: 12195513 mm2
Name (28_PBT_SF_staal_H-profiel_met_onderplaat (void):S355_HE300B + onderplaat d=15:...)
2397561
2397565

# IfcBeam: 28_PBT_SF_staal_H-profiel_met_onderplaat (void):S355_HE360B + onderplaat d=12, 28_PBT_SF_staal_H-profiel_met_onderplaat (void):S355_HE360B + onderplaat d=12:4671541
In: 06 zesde verdieping
Type - PredefinedType: BEAM; Classification: 28.11 hoofddraagconstructies - kolommen en liggers, kolom-/liggerconstructies (Uniformat); Material: 00_PBT_MAT_Lucht, 00_PBT_MAT_staal_S355
Type - Pset_BeamCommon - IsExternal: no; LoadBearing: yes
Type - Pset_ProductRequirements - Category: Structural Framing
Type - Pset_ReinforcementBarPitchOfBeam - Description: HE360B + onderplaat d=12
Type - Pset_Pieters - Breedte: 300 mm; Hoogte: 360 mm; Codering - NL-SfB: 28.11; Omschrijving NL-SfB: hoofddraagconstructies - kolommen en liggers, kolom-/liggerconstructies; Materiaal: 00_PBT_MAT_staal_S355; Materiaalkwaliteit: S355; Description: HE360B + onderplaat d=12
Material: 00_PBT_MAT_staal_S355
Pset_BeamCommon - Slope: 0 deg; Reference: 28_PBT_SF_staal_H-profiel_met_onderplaat (void):S355_HE360B + onderplaat d=12; Span: 11989.7 mm
Pset_QuantityTakeOff - Reference: 28_PBT_SF_staal_H-profiel_met_onderplaat (void):S355_HE360B + onderplaat d=12
Pset_ReinforcementBarPitchOfBeam - Reference: 28_PBT_SF_staal_H-profiel_met_onderplaat (void):S355_HE360B + onderplaat d=12
Pset_Pieters - Bouwlaag: Level: 06 zesde verdieping; Naamgeving element: 28_PBT_SF_staal_H-profiel_met_onderplaat (void): S355_HE360B + onderplaat d=12; Fase: Nieuw
BaseQuantities - Length: 11989.7 mm; CrossSectionArea: 26543261 mm2; OuterSurfaceArea: 13476434 mm2; GrossSurfaceArea: 13489634 mm2; GrossVolume: 0.0791321 m3; NetVolume: 0.295707 m3; NetSurfaceArea: 35690491 mm2

# IfcBeam: 28_PBT_SF_staal_H-profiel_met_onderplaat (void):S355_HE360B + onderplaat d=12, 28_PBT_SF_staal_H-profiel_met_onderplaat (void):S355_HE360B + onderplaat d=12:4671537
In: 06 zesde verdieping
Type - PredefinedType: BEAM; Classification: 28.11 hoofddraagconstructies - kolommen en liggers, kolom-/liggerconstructies (Uniformat); Material: 00_PBT_MAT_staal_S355, 00_PBT_MAT_Lucht
Type - Pset_BeamCommon - IsExternal: no; LoadBearing: yes
Type - Pset_ProductRequirements - Category: Structural Framing
Type - Pset_ReinforcementBarPitchOfBeam - Description: HE360B + onderplaat d=12
Type - Pset_Pieters - Breedte: 300 mm; Hoogte: 360 mm; Codering - NL-SfB: 28.11; Omschrijving NL-SfB: hoofddraagconstructies - kolommen en liggers, kolom-/liggerconstructies; Materiaal: 00_PBT_MAT_staal_S355; Materiaalkwaliteit: S355; Description: HE360B + onderplaat d=12
Material: 00_PBT_MAT_staal_S355
Pset_BeamCommon - Slope: 0 deg; Reference: 28_PBT_SF_staal_H-profiel_met_onderplaat (void):S355_HE360B + onderplaat d=12; Span: 11989.7 mm
Pset_QuantityTakeOff - Reference: 28_PBT_SF_staal_H-profiel_met_onderplaat (void):S355_HE360B + onderplaat d=12
Pset_ReinforcementBarPitchOfBeam - Reference: 28_PBT_SF_staal_H-profiel_met_onderplaat (void):S355_HE360B + onderplaat d=12
Pset_Pieters - Bouwlaag: Level: 06 zesde verdieping; Naamgeving element: 28_PBT_SF_staal_H-profiel_met_onderplaat (void): S355_HE360B + onderplaat d=12; Fase: Nieuw
BaseQuantities - Length: 11989.7 mm; CrossSectionArea: 18539354 mm2; OuterSurfaceArea: 22164729 mm2; GrossSurfaceArea: 22200857 mm2; GrossVolume: 0.216579 m3; NetVolume: 0.295707 m3; NetSurfaceArea: 35690491 mm2

# IfcBeam: 28_PBT_SF_staal_H-profiel_met_onderplaat (void):S355_HE360M + onderplaat d=25 (2)
In: 03 derde verdieping
Type - PredefinedType: BEAM; Classification: 28.11 hoofddraagconstructies - kolommen en liggers, kolom-/liggerconstructies (Uniformat); Material: 00_PBT_MAT_Lucht, 00_PBT_MAT_staal_S355
Type - Pset_BeamCommon - IsExternal: no; LoadBearing: yes
Type - Pset_ProductRequirements - Category: Structural Framing
Type - Pset_ReinforcementBarPitchOfBeam - Description: HE360M + onderplaat d=25
Type - Pset_Pieters - Breedte: 308 mm; Hoogte: 395 mm; Codering - NL-SfB: 28.11; Omschrijving NL-SfB: hoofddraagconstructies - kolommen en liggers, kolom-/liggerconstructies; Materiaal: 00_PBT_MAT_staal_S355; Materiaalkwaliteit: S355; Description: HE360M + onderplaat d=25
Material: 00_PBT_MAT_staal_S355
Pset_BeamCommon - Slope: 0 deg; Reference: 28_PBT_SF_staal_H-profiel_met_onderplaat (void):S355_HE360M + onderplaat d=25
Pset_QuantityTakeOff - Reference: 28_PBT_SF_staal_H-profiel_met_onderplaat (void):S355_HE360M + onderplaat d=25
Pset_ReinforcementBarPitchOfBeam - Reference: 28_PBT_SF_staal_H-profiel_met_onderplaat (void):S355_HE360M + onderplaat d=25
Pset_Pieters - Bouwlaag: Level: 03 derde verdieping; Naamgeving element: 28_PBT_SF_staal_H-profiel_met_onderplaat (void): S355_HE360M + onderplaat d=25; Fase: Nieuw
Name (28_PBT_SF_staal_H-profiel_met_onderplaat (void):S355_HE360M + onderplaat d=25:...) | Span (mm) = Length (mm) | CrossSectionArea (mm2) | OuterSurfaceArea (mm2) | GrossSurfaceArea (mm2) | GrossVolume (m3) | NetVolume (m3) | NetSurfaceArea (mm2)
2449289 | 5115.52 | 12607164 | 9891597 | 9955359 | 0.163089 | 0.240694 | 16132803
2449952 | 8890 | 22411535 | 17190113 | 17253875 | 0.283424 | 0.696836 | 31131641

# IfcBeam: 28_PBT_SF_staal_H-profiel_met_onderplaat (void):S355_HE400A + onderplaat d=20 (8)
In: 04 vierde verdieping
Type - PredefinedType: BEAM; Classification: 28.11 hoofddraagconstructies - kolommen en liggers, kolom-/liggerconstructies (Uniformat); Material: 00_PBT_MAT_Lucht, 00_PBT_MAT_staal_S355
Type - Pset_BeamCommon - IsExternal: no; LoadBearing: yes
Type - Pset_ProductRequirements - Category: Structural Framing
Type - Pset_ReinforcementBarPitchOfBeam - Description: HE400A + onderplaat d=20
Type - Pset_Pieters - Breedte: 300 mm; Hoogte: 390 mm; Codering - NL-SfB: 28.11; Omschrijving NL-SfB: hoofddraagconstructies - kolommen en liggers, kolom-/liggerconstructies; Materiaal: 00_PBT_MAT_staal_S355; Materiaalkwaliteit: S355; Description: HE400A + onderplaat d=20
Material: 00_PBT_MAT_staal_S355
Pset_BeamCommon - Slope: 0 deg; Reference: 28_PBT_SF_staal_H-profiel_met_onderplaat (void):S355_HE400A + onderplaat d=20
Pset_QuantityTakeOff - Reference: 28_PBT_SF_staal_H-profiel_met_onderplaat (void):S355_HE400A + onderplaat d=20
Pset_ReinforcementBarPitchOfBeam - Reference: 28_PBT_SF_staal_H-profiel_met_onderplaat (void):S355_HE400A + onderplaat d=20
Pset_Pieters - Bouwlaag: Level: 04 vierde verdieping; Naamgeving element: 28_PBT_SF_staal_H-profiel_met_onderplaat (void): S355_HE400A + onderplaat d=20; Fase: Nieuw
Name (28_PBT_SF_staal_H-profiel_met_onderplaat (void):S355_HE400A + onderplaat d=20:...) | Span (mm) = Length (mm) | CrossSectionArea (mm2) | OuterSurfaceArea (mm2) | GrossSurfaceArea (mm2) | GrossVolume (m3) | NetVolume (m3) | NetSurfaceArea (mm2)
3382420 | 3980 | 8486869 | 4177530 | 4199530 | 0.0403095 | 0.0985672 | 11236553
3382422 | 3980 | 8486869 | 4177530 | 4199530 | 0.0403095 | 0.0985672 | 11236553
3382437 | 3979.08 | 6061716 | 7305032 | 7336828 | 0.0607525 | 0.102786 | 11715146
3382439 | 3979.08 | 6061716 | 7305032 | 7336828 | 0.0607525 | 0.102786 | 11715146
3382486 | 3980 | 8486869 | 4177530 | 4199530 | 0.0403095 | 0.0985672 | 11236553
3382488 | 3980 | 8486869 | 4177530 | 4199530 | 0.0403095 | 0.0985672 | 11236553
3382503 | 3980 | 8486869 | 4177530 | 4199530 | 0.0403095 | 0.0985672 | 11236553
3382505 | 3980 | 8486869 | 4177530 | 4199530 | 0.0403095 | 0.0985672 | 11236553

# IfcBeam: 28_PBT_SF_staal_H-profiel_met_onderplaat (void):S355_HE400A + onderplaat d=20 (6)
In: 04 vierde verdieping
Type - PredefinedType: BEAM; Classification: 28.11 hoofddraagconstructies - kolommen en liggers, kolom-/liggerconstructies (Uniformat); Material: 00_PBT_MAT_staal_S355, 00_PBT_MAT_Lucht
Type - Pset_BeamCommon - IsExternal: no; LoadBearing: yes
Type - Pset_ProductRequirements - Category: Structural Framing
Type - Pset_ReinforcementBarPitchOfBeam - Description: HE400A + onderplaat d=20
Type - Pset_Pieters - Breedte: 300 mm; Hoogte: 390 mm; Codering - NL-SfB: 28.11; Omschrijving NL-SfB: hoofddraagconstructies - kolommen en liggers, kolom-/liggerconstructies; Materiaal: 00_PBT_MAT_staal_S355; Materiaalkwaliteit: S355; Description: HE400A + onderplaat d=20
Material: 00_PBT_MAT_staal_S355
Pset_BeamCommon - Slope: 0 deg; Reference: 28_PBT_SF_staal_H-profiel_met_onderplaat (void):S355_HE400A + onderplaat d=20; Span: 3980 mm
Pset_QuantityTakeOff - Reference: 28_PBT_SF_staal_H-profiel_met_onderplaat (void):S355_HE400A + onderplaat d=20
Pset_ReinforcementBarPitchOfBeam - Reference: 28_PBT_SF_staal_H-profiel_met_onderplaat (void):S355_HE400A + onderplaat d=20
Pset_Pieters - Bouwlaag: Level: 04 vierde verdieping; Naamgeving element: 28_PBT_SF_staal_H-profiel_met_onderplaat (void): S355_HE400A + onderplaat d=20; Fase: Nieuw
BaseQuantities - Length: 3980 mm; NetVolume: 0.0985672 m3; NetSurfaceArea: 11236553 mm2
Name (28_PBT_SF_staal_H-profiel_met_onderplaat (void):S355_HE400A + onderplaat d=20:...) | CrossSectionArea (mm2)
3381166 | 8486869 | BaseQuantities - OuterSurfaceArea: 4177530 mm2; GrossSurfaceArea: 4199530 mm2; GrossVolume: 0.0403095 m3
3381663 | 5822420 | BaseQuantities - OuterSurfaceArea: 7005227 mm2; GrossSurfaceArea: 7037023 mm2; GrossVolume: 0.0582591 m3
3382522 | 5822420 | BaseQuantities - OuterSurfaceArea: 7005227 mm2; GrossSurfaceArea: 7037023 mm2; GrossVolume: 0.0582591 m3
3382524 | 5822420
3382539 | 5822420
3382541 | 5822420

# IfcBeam: 28_PBT_SF_staal_H-profiel_met_onderplaat (void):S355_HE400B + onderplaat, 28_PBT_SF_staal_H-profiel_met_onderplaat (void):S355_HE400B + onderplaat:2969722
In: -1 kelder
Type - PredefinedType: BEAM; Classification: 28.11 hoofddraagconstructies - kolommen en liggers, kolom-/liggerconstructies (Uniformat); Material: 00_PBT_MAT_Lucht, 00_PBT_MAT_staal_S355
Type - Pset_BeamCommon - IsExternal: no; LoadBearing: yes
Type - Pset_ProductRequirements - Category: Structural Framing
Type - Pset_ReinforcementBarPitchOfBeam - Description: HE400B + onderplaat
Type - Pset_Pieters - Breedte: 300 mm; Hoogte: 400 mm; Codering - NL-SfB: 28.11; Omschrijving NL-SfB: hoofddraagconstructies - kolommen en liggers, kolom-/liggerconstructies; Materiaal: 00_PBT_MAT_staal_S355; Materiaalkwaliteit: S355; Description: HE400B + onderplaat
Material: 00_PBT_MAT_staal_S355
Pset_BeamCommon - Reference: 28_PBT_SF_staal_H-profiel_met_onderplaat (void):S355_HE400B + onderplaat; Span: 7380 mm; Slope: 9 deg
Pset_QuantityTakeOff - Reference: 28_PBT_SF_staal_H-profiel_met_onderplaat (void):S355_HE400B + onderplaat
Pset_ReinforcementBarPitchOfBeam - Reference: 28_PBT_SF_staal_H-profiel_met_onderplaat (void):S355_HE400B + onderplaat
Pset_Pieters - Bouwlaag: Level: -1 kelder; Naamgeving element: 28_PBT_SF_staal_H-profiel_met_onderplaat (void): S355_HE400B + onderplaat; Fase: Nieuw
BaseQuantities - Length: 7380 mm; CrossSectionArea: 14224493 mm2; OuterSurfaceArea: 13547594 mm2; GrossSurfaceArea: 13587150 mm2; GrossVolume: 0.139075 m3; NetVolume: 0.171114 m3; NetSurfaceArea: 19108186 mm2

# IfcBeam: 28_PBT_SF_staal_H-profiel_met_onderplaat (void):S355_HE400B + onderplaat (3)
In: 04 vierde verdieping
Type - PredefinedType: BEAM; Classification: 28.11 hoofddraagconstructies - kolommen en liggers, kolom-/liggerconstructies (Uniformat); Material: 00_PBT_MAT_staal_S355, 00_PBT_MAT_Lucht
Type - Pset_BeamCommon - IsExternal: no; LoadBearing: yes
Type - Pset_ProductRequirements - Category: Structural Framing
Type - Pset_ReinforcementBarPitchOfBeam - Description: HE400B + onderplaat
Type - Pset_Pieters - Breedte: 300 mm; Hoogte: 400 mm; Codering - NL-SfB: 28.11; Omschrijving NL-SfB: hoofddraagconstructies - kolommen en liggers, kolom-/liggerconstructies; Materiaal: 00_PBT_MAT_staal_S355; Materiaalkwaliteit: S355; Description: HE400B + onderplaat
Material: 00_PBT_MAT_staal_S355
Pset_BeamCommon - Reference: 28_PBT_SF_staal_H-profiel_met_onderplaat (void):S355_HE400B + onderplaat
Pset_QuantityTakeOff - Reference: 28_PBT_SF_staal_H-profiel_met_onderplaat (void):S355_HE400B + onderplaat
Pset_ReinforcementBarPitchOfBeam - Reference: 28_PBT_SF_staal_H-profiel_met_onderplaat (void):S355_HE400B + onderplaat
Pset_Pieters - Bouwlaag: Level: 04 vierde verdieping; Naamgeving element: 28_PBT_SF_staal_H-profiel_met_onderplaat (void): S355_HE400B + onderplaat; Fase: Nieuw
Name (28_PBT_SF_staal_H-profiel_met_onderplaat (void):S355_HE400B + onderplaat:...) | Span (mm) = Length (mm) | Slope (deg) | CrossSectionArea (mm2) | OuterSurfaceArea (mm2) | GrossSurfaceArea (mm2) | GrossVolume (m3) | NetVolume (m3) | NetSurfaceArea (mm2)
2968889 | 7380 | 9 | 14224493 | 13547594 | 13587150 | 0.139075 | 0.171114 | 19108186
2969124 | 3744.83 | 0 | 8679269 | 4530328 | 4546528 | 0.0330592 | 0.113447 | 12416289
2969908 | 3744.83 | 0 | 8679269 | 4530328 | 4546528 | 0.0330592 | 0.113447 | 12416289

# IfcBeam: 28_PBT_SF_staal_H-profiel_met_onderplaat (void):S355_HE400B + onderplaat d=15 (3)
Type - PredefinedType: BEAM; Classification: 28.11 hoofddraagconstructies - kolommen en liggers, kolom-/liggerconstructies (Uniformat); Material: 00_PBT_MAT_Lucht, 00_PBT_MAT_staal_S355
Type - Pset_BeamCommon - IsExternal: no; LoadBearing: yes
Type - Pset_ProductRequirements - Category: Structural Framing
Type - Pset_ReinforcementBarPitchOfBeam - Description: HE400B + onderplaat d=15
Type - Pset_Pieters - Breedte: 300 mm; Hoogte: 400 mm; Codering - NL-SfB: 28.11; Omschrijving NL-SfB: hoofddraagconstructies - kolommen en liggers, kolom-/liggerconstructies; Materiaal: 00_PBT_MAT_staal_S355; Materiaalkwaliteit: S355; Description: HE400B + onderplaat d=15
Material: 00_PBT_MAT_staal_S355
Pset_BeamCommon - Slope: 0 deg; Reference: 28_PBT_SF_staal_H-profiel_met_onderplaat (void):S355_HE400B + onderplaat d=15
Pset_QuantityTakeOff - Reference: 28_PBT_SF_staal_H-profiel_met_onderplaat (void):S355_HE400B + onderplaat d=15
Pset_ReinforcementBarPitchOfBeam - Reference: 28_PBT_SF_staal_H-profiel_met_onderplaat (void):S355_HE400B + onderplaat d=15
Pset_Pieters - Naamgeving element: 28_PBT_SF_staal_H-profiel_met_onderplaat (void): S355_HE400B + onderplaat d=15; Fase: Nieuw
Name (28_PBT_SF_staal_H-profiel_met_onderplaat (void):S355_HE400B + onderplaat d=15:...) | In | Span (mm) = Length (mm) | Bouwlaag | CrossSectionArea (mm2) | OuterSurfaceArea (mm2) | GrossSurfaceArea (mm2) | GrossVolume (m3) | NetVolume (m3) | NetSurfaceArea (mm2)
2448393 | 01 eerste verdieping | 7190 | Level: 01 eerste verdieping | 16554271 | 7980900 | 7997100 | 0.058239 | 0.200442 | 21889241
2448521 | 02 tweede verdieping | 7190 | Level: 02 tweede verdieping | 16554271 | 7980900 | 7997100 | 0.058239 | 0.200442 | 21889241
4394029 | 01 eerste verdieping | 8600 | Level: 01 eerste verdieping | 19745556 | 9546000 | 9562200 | 0.06966 | 0.23975 | 26170912

# IfcBeam: 28_PBT_SF_staal_H-profiel_met_onderplaat (void):S355_HE400B + onderplaat d=15 (5)
Type - PredefinedType: BEAM; Classification: 28.11 hoofddraagconstructies - kolommen en liggers, kolom-/liggerconstructies (Uniformat); Material: 00_PBT_MAT_staal_S355, 00_PBT_MAT_Lucht
Type - Pset_BeamCommon - IsExternal: no; LoadBearing: yes
Type - Pset_ProductRequirements - Category: Structural Framing
Type - Pset_ReinforcementBarPitchOfBeam - Description: HE400B + onderplaat d=15
Type - Pset_Pieters - Breedte: 300 mm; Hoogte: 400 mm; Codering - NL-SfB: 28.11; Omschrijving NL-SfB: hoofddraagconstructies - kolommen en liggers, kolom-/liggerconstructies; Materiaal: 00_PBT_MAT_staal_S355; Materiaalkwaliteit: S355; Description: HE400B + onderplaat d=15
Material: 00_PBT_MAT_staal_S355
Pset_BeamCommon - Slope: 0 deg; Reference: 28_PBT_SF_staal_H-profiel_met_onderplaat (void):S355_HE400B + onderplaat d=15
Pset_QuantityTakeOff - Reference: 28_PBT_SF_staal_H-profiel_met_onderplaat (void):S355_HE400B + onderplaat d=15
Pset_ReinforcementBarPitchOfBeam - Reference: 28_PBT_SF_staal_H-profiel_met_onderplaat (void):S355_HE400B + onderplaat d=15
Pset_Pieters - Naamgeving element: 28_PBT_SF_staal_H-profiel_met_onderplaat (void): S355_HE400B + onderplaat d=15; Fase: Nieuw
Name (28_PBT_SF_staal_H-profiel_met_onderplaat (void):S355_HE400B + onderplaat d=15:...) | In | Span (mm) = Length (mm) | Bouwlaag | CrossSectionArea (mm2) | OuterSurfaceArea (mm2) | GrossSurfaceArea (mm2) | GrossVolume (m3) | NetVolume (m3) | NetSurfaceArea (mm2)
2447585 | 01 eerste verdieping | 7957.52 | Level: 01 eerste verdieping | 18291420 | 8832849 | 8849049 | 0.0644559 | 0.221839 | 24219933
2447610 | 01 eerste verdieping | 8600 | Level: 01 eerste verdieping | 19745556 | 9546000 | 9562200 | 0.06966 | 0.23975 | 26170912
2448501 | 02 tweede verdieping | 7977.52 | Level: 02 tweede verdieping | 18336686 | 8855049 | 8871249 | 0.0646179 | 0.222396 | 24280665
2448507 | 02 tweede verdieping | 8600 | Level: 02 tweede verdieping | 20739280 | 16569156 | 16608712 | 0.170093 | 0.368685 | 28288760
4394360 | 02 tweede verdieping | 8600 | Level: 02 tweede verdieping | 19745556 | 9546000 | 9562200 | 0.06966 | 0.23975 | 26170912

# IfcBeam: 28_PBT_SF_staal_H-profiel_met_onderplaat (void):S355_HE400B + onderplaat d=25 (4)
Type - PredefinedType: BEAM; Classification: 28.11 hoofddraagconstructies - kolommen en liggers, kolom-/liggerconstructies (Uniformat); Material: 00_PBT_MAT_Lucht, 00_PBT_MAT_staal_S355
Type - Pset_BeamCommon - IsExternal: no; LoadBearing: yes
Type - Pset_ProductRequirements - Category: Structural Framing
Type - Pset_ReinforcementBarPitchOfBeam - Description: HE400B + onderplaat d=25
Type - Pset_Pieters - Breedte: 300 mm; Hoogte: 400 mm; Codering - NL-SfB: 28.11; Omschrijving NL-SfB: hoofddraagconstructies - kolommen en liggers, kolom-/liggerconstructies; Materiaal: 00_PBT_MAT_staal_S355; Materiaalkwaliteit: S355; Description: HE400B + onderplaat d=25
Material: 00_PBT_MAT_staal_S355
Pset_BeamCommon - Slope: 0 deg; Reference: 28_PBT_SF_staal_H-profiel_met_onderplaat (void):S355_HE400B + onderplaat d=25
Pset_QuantityTakeOff - Reference: 28_PBT_SF_staal_H-profiel_met_onderplaat (void):S355_HE400B + onderplaat d=25
Pset_ReinforcementBarPitchOfBeam - Reference: 28_PBT_SF_staal_H-profiel_met_onderplaat (void):S355_HE400B + onderplaat d=25
Pset_Pieters - Naamgeving element: 28_PBT_SF_staal_H-profiel_met_onderplaat (void): S355_HE400B + onderplaat d=25; Fase: Nieuw
Name (28_PBT_SF_staal_H-profiel_met_onderplaat (void):S355_HE400B + onderplaat d=25:...) | In | Span (mm) = Length (mm) | Bouwlaag | CrossSectionArea (mm2) | OuterSurfaceArea (mm2) | GrossSurfaceArea (mm2) | GrossVolume (m3) | NetVolume (m3) | NetSurfaceArea (mm2)
2039694 | 01 eerste verdieping | 8014.31 | Level: 01 eerste verdieping | 18755486 | 8592869 | 8619869 | 0.102658 | 0.302255 | 25294252 | Pset_Pieters - Dragend/niet dragend: yes
2041812 | 01 eerste verdieping | 8014.31 | Level: 01 eerste verdieping | 19101520 |  |  |  | 0.348921 | 25986321 | Pset_Pieters - Dragend/niet dragend: yes
2444647 | 01 eerste verdieping | 7190 | Level: 01 eerste verdieping | 16631571 | 8124700 | 8151700 | 0.097065 | 0.239268 | 22043841
2448495 | 02 tweede verdieping | 7190 | Level: 02 tweede verdieping | 16631571 | 8124700 | 8151700 | 0.097065 | 0.239268 | 22043841

# IfcBeam: 28_PBT_SF_staal_H-profiel_met_onderplaat (void):S355_HE400B + onderplaat d=25 (5)
Type - PredefinedType: BEAM; Classification: 28.11 hoofddraagconstructies - kolommen en liggers, kolom-/liggerconstructies (Uniformat); Material: 00_PBT_MAT_staal_S355, 00_PBT_MAT_Lucht
Type - Pset_BeamCommon - IsExternal: no; LoadBearing: yes
Type - Pset_ProductRequirements - Category: Structural Framing
Type - Pset_ReinforcementBarPitchOfBeam - Description: HE400B + onderplaat d=25
Type - Pset_Pieters - Breedte: 300 mm; Hoogte: 400 mm; Codering - NL-SfB: 28.11; Omschrijving NL-SfB: hoofddraagconstructies - kolommen en liggers, kolom-/liggerconstructies; Materiaal: 00_PBT_MAT_staal_S355; Materiaalkwaliteit: S355; Description: HE400B + onderplaat d=25
Material: 00_PBT_MAT_staal_S355
Pset_BeamCommon - Slope: 0 deg; Reference: 28_PBT_SF_staal_H-profiel_met_onderplaat (void):S355_HE400B + onderplaat d=25
Pset_QuantityTakeOff - Reference: 28_PBT_SF_staal_H-profiel_met_onderplaat (void):S355_HE400B + onderplaat d=25
Pset_ReinforcementBarPitchOfBeam - Reference: 28_PBT_SF_staal_H-profiel_met_onderplaat (void):S355_HE400B + onderplaat d=25
Pset_Pieters - Naamgeving element: 28_PBT_SF_staal_H-profiel_met_onderplaat (void): S355_HE400B + onderplaat d=25; Fase: Nieuw
Name (28_PBT_SF_staal_H-profiel_met_onderplaat (void):S355_HE400B + onderplaat d=25:...) | In | Span (mm) = Length (mm) | Bouwlaag | CrossSectionArea (mm2) | OuterSurfaceArea (mm2) | GrossSurfaceArea (mm2) | GrossVolume (m3) | NetVolume (m3) | NetSurfaceArea (mm2)
2039521 | 01 eerste verdieping | 8014.31 | Level: 01 eerste verdieping | 18755486 | 8592869 | 8619869 | 0.102658 | 0.302255 | 25294252 | Pset_Pieters - Dragend/niet dragend: yes
2444641 | 01 eerste verdieping | 7013.24 | Level: 01 eerste verdieping | 16229748 | 7924966 | 7951966 | 0.0946788 | 0.233386 | 21503562
2448098 | 02 tweede verdieping | 2468 | Level: 02 tweede verdieping | 5896939 | 2788840 | 2815840 | 0.033318 | 0.0821298 | 7610359
2448489 | 02 tweede verdieping | 4245.24 | Level: 02 tweede verdieping | 9937190 | 4797126 | 4824126 | 0.0573108 | 0.141273 | 13042766
2450734 | 04 vierde verdieping | 7866.85 | Level: 04 vierde verdieping | 19871263 | 15156635 | 15196191 | 0.155592 | 0.480042 | 27544919

# IfcBeam: 28_PBT_SF_staal_H-profiel_met_oplegstrippen (void):S355_HE300M + oplegstrippen d=12 (2)
In: 03 derde verdieping
Type - PredefinedType: BEAM; Classification: 28.11 hoofddraagconstructies - kolommen en liggers, kolom-/liggerconstructies (Uniformat); Material: 00_PBT_MAT_Lucht, 00_PBT_MAT_staal_S355
Type - Pset_BeamCommon - IsExternal: no; LoadBearing: yes
Type - Pset_ProductRequirements - Category: Structural Framing
Type - Pset_ReinforcementBarPitchOfBeam - Description: HE300M + oplegstrippen d=12
Type - Pset_Pieters - Breedte: 310 mm; Hoogte: 340 mm; Codering - NL-SfB: 28.11; Omschrijving NL-SfB: hoofddraagconstructies - kolommen en liggers, kolom-/liggerconstructies; Materiaal: 00_PBT_MAT_staal_S355; Materiaalkwaliteit: S355; Description: HE300M + oplegstrippen d=12
Material: 00_PBT_MAT_staal_S355
Pset_BeamCommon - Slope: 0 deg; Reference: 28_PBT_SF_staal_H-profiel_met_oplegstrippen (void):S355_HE300M + oplegstrippen d=12
Pset_QuantityTakeOff - Reference: 28_PBT_SF_staal_H-profiel_met_oplegstrippen (void):S355_HE300M + oplegstrippen d=12
Pset_ReinforcementBarPitchOfBeam - Reference: 28_PBT_SF_staal_H-profiel_met_oplegstrippen (void):S355_HE300M + oplegstrippen d=12
Pset_Pieters - Bouwlaag: Level: 03 derde verdieping; Naamgeving element: 28_PBT_SF_staal_H-profiel_met_oplegstrippen (void): S355_HE300M + oplegstrippen d=12; Fase: Nieuw
Name (28_PBT_SF_staal_H-profiel_met_oplegstrippen (void):S355_HE300M + oplegstrippen d=12:...) | Span (mm) = Length (mm) | CrossSectionArea (mm2) | OuterSurfaceArea (mm2) | GrossSurfaceArea (mm2) | GrossVolume (m3) | NetVolume (m3) | NetSurfaceArea (mm2)
2423106 | 4728 | 9877194 | 3037999 | 3045679 | 0.0175692 | 0.173806 | 14532305
2423117 | 4680 | 9919890 | 3051279 | 3058959 | 0.017646 | 0.174566 | 14595498

# IfcBeam: 28_PBT_SF_staal_H-profiel_met_oplegstrippen (void):S355_HE300M + oplegstrippen d=12 (2)
In: 03 derde verdieping
Type - PredefinedType: BEAM; Classification: 28.11 hoofddraagconstructies - kolommen en liggers, kolom-/liggerconstructies (Uniformat); Material: 00_PBT_MAT_staal_S355, 00_PBT_MAT_Lucht
Type - Pset_BeamCommon - IsExternal: no; LoadBearing: yes
Type - Pset_ProductRequirements - Category: Structural Framing
Type - Pset_ReinforcementBarPitchOfBeam - Description: HE300M + oplegstrippen d=12
Type - Pset_Pieters - Breedte: 310 mm; Hoogte: 340 mm; Codering - NL-SfB: 28.11; Omschrijving NL-SfB: hoofddraagconstructies - kolommen en liggers, kolom-/liggerconstructies; Materiaal: 00_PBT_MAT_staal_S355; Materiaalkwaliteit: S355; Description: HE300M + oplegstrippen d=12
Material: 00_PBT_MAT_staal_S355
Pset_BeamCommon - Slope: 0 deg; Reference: 28_PBT_SF_staal_H-profiel_met_oplegstrippen (void):S355_HE300M + oplegstrippen d=12; Span: 4728 mm
Pset_QuantityTakeOff - Reference: 28_PBT_SF_staal_H-profiel_met_oplegstrippen (void):S355_HE300M + oplegstrippen d=12
Pset_ReinforcementBarPitchOfBeam - Reference: 28_PBT_SF_staal_H-profiel_met_oplegstrippen (void):S355_HE300M + oplegstrippen d=12
Pset_Pieters - Bouwlaag: Level: 03 derde verdieping; Naamgeving element: 28_PBT_SF_staal_H-profiel_met_oplegstrippen (void): S355_HE300M + oplegstrippen d=12; Fase: Nieuw
BaseQuantities - Length: 4728 mm; CrossSectionArea: 9877194 mm2; OuterSurfaceArea: 3037999 mm2; GrossSurfaceArea: 3045679 mm2; GrossVolume: 0.0175692 m3; NetVolume: 0.173806 m3; NetSurfaceArea: 14532305 mm2
Name (28_PBT_SF_staal_H-profiel_met_oplegstrippen (void):S355_HE300M + oplegstrippen d=12:...)
2422621
2439096

# IfcBeam: 28_PBT_SF_staal_H-profiel_met_oplegstrippen (void):S355_HE450B + oplegstrip d=12, 28_PBT_SF_staal_H-profiel_met_oplegstrippen (void):S355_HE450B + oplegstrip d=12:2644805
In: 06 zesde verdieping
Type - PredefinedType: BEAM; Classification: 28.11 hoofddraagconstructies - kolommen en liggers, kolom-/liggerconstructies (Uniformat); Material: 00_PBT_MAT_Lucht, 00_PBT_MAT_staal_S355
Type - Pset_BeamCommon - IsExternal: no; LoadBearing: yes
Type - Pset_ProductRequirements - Category: Structural Framing
Type - Pset_ReinforcementBarPitchOfBeam - Description: HE450B + oplegstrip d=12
Type - Pset_Pieters - Breedte: 300 mm; Hoogte: 450 mm; Codering - NL-SfB: 28.11; Omschrijving NL-SfB: hoofddraagconstructies - kolommen en liggers, kolom-/liggerconstructies; Materiaal: 00_PBT_MAT_staal_S355; Materiaalkwaliteit: S355; Description: HE450B + oplegstrip d=12
Material: 00_PBT_MAT_staal_S355
Pset_BeamCommon - Slope: 0 deg; Reference: 28_PBT_SF_staal_H-profiel_met_oplegstrippen (void):S355_HE450B + oplegstrip d=12; Span: 6158.85 mm
Pset_QuantityTakeOff - Reference: 28_PBT_SF_staal_H-profiel_met_oplegstrippen (void):S355_HE450B + oplegstrip d=12
Pset_ReinforcementBarPitchOfBeam - Reference: 28_PBT_SF_staal_H-profiel_met_oplegstrippen (void):S355_HE450B + oplegstrip d=12
Pset_Pieters - Bouwlaag: Level: 06 zesde verdieping; Naamgeving element: 28_PBT_SF_staal_H-profiel_met_oplegstrippen (void): S355_HE450B + oplegstrip d=12; Fase: Nieuw
BaseQuantities - Length: 6158.85 mm; CrossSectionArea: 11759314 mm2; OuterSurfaceArea: 3466431 mm2; GrossSurfaceArea: 3472911 mm2; GrossVolume: 0.0199135 m3; NetVolume: 0.153887 m3; NetSurfaceArea: 15966442 mm2

# IfcBeam: 28_PBT_SF_staal_H-profiel_met_oplegstrippen (void):S355_HE450B + oplegstrip d=12, 28_PBT_SF_staal_H-profiel_met_oplegstrippen (void):S355_HE450B + oplegstrip d=12:2644951
In: 06 zesde verdieping
Type - PredefinedType: BEAM; Classification: 28.11 hoofddraagconstructies - kolommen en liggers, kolom-/liggerconstructies (Uniformat); Material: 00_PBT_MAT_staal_S355, 00_PBT_MAT_Lucht
Type - Pset_BeamCommon - IsExternal: no; LoadBearing: yes
Type - Pset_ProductRequirements - Category: Structural Framing
Type - Pset_ReinforcementBarPitchOfBeam - Description: HE450B + oplegstrip d=12
Type - Pset_Pieters - Breedte: 300 mm; Hoogte: 450 mm; Codering - NL-SfB: 28.11; Omschrijving NL-SfB: hoofddraagconstructies - kolommen en liggers, kolom-/liggerconstructies; Materiaal: 00_PBT_MAT_staal_S355; Materiaalkwaliteit: S355; Description: HE450B + oplegstrip d=12
Material: 00_PBT_MAT_staal_S355
Pset_BeamCommon - Slope: 0 deg; Reference: 28_PBT_SF_staal_H-profiel_met_oplegstrippen (void):S355_HE450B + oplegstrip d=12; Span: 6158.85 mm
Pset_QuantityTakeOff - Reference: 28_PBT_SF_staal_H-profiel_met_oplegstrippen (void):S355_HE450B + oplegstrip d=12
Pset_ReinforcementBarPitchOfBeam - Reference: 28_PBT_SF_staal_H-profiel_met_oplegstrippen (void):S355_HE450B + oplegstrip d=12
Pset_Pieters - Bouwlaag: Level: 06 zesde verdieping; Naamgeving element: 28_PBT_SF_staal_H-profiel_met_oplegstrippen (void): S355_HE450B + oplegstrip d=12; Fase: Nieuw
BaseQuantities - Length: 6158.85 mm; CrossSectionArea: 11783378 mm2; OuterSurfaceArea: 3473594 mm2; GrossSurfaceArea: 3480074 mm2; GrossVolume: 0.0199547 m3; NetVolume: 0.154205 m3; NetSurfaceArea: 15999331 mm2

# IfcBeam: 28_PBT_SF_staal_H-profiel_met_oplegstrippen (void):S355_HE450B + oplegstrippen d=12, 28_PBT_SF_staal_H-profiel_met_oplegstrippen (void):S355_HE450B + oplegstrippen d=12:4720785
In: 05 vijfde verdieping
Type - PredefinedType: BEAM; Classification: 28.11 hoofddraagconstructies - kolommen en liggers, kolom-/liggerconstructies (Uniformat); Material: 00_PBT_MAT_Lucht, 00_PBT_MAT_staal_S355
Type - Pset_BeamCommon - IsExternal: no; LoadBearing: yes
Type - Pset_ProductRequirements - Category: Structural Framing
Type - Pset_ReinforcementBarPitchOfBeam - Description: HE450B + oplegstrippen d=12
Type - Pset_Pieters - Breedte: 300 mm; Hoogte: 450 mm; Codering - NL-SfB: 28.11; Omschrijving NL-SfB: hoofddraagconstructies - kolommen en liggers, kolom-/liggerconstructies; Materiaal: 00_PBT_MAT_staal_S355; Materiaalkwaliteit: S355; Description: HE450B + oplegstrippen d=12
Material: 00_PBT_MAT_staal_S355
Pset_BeamCommon - Slope: 0 deg; Reference: 28_PBT_SF_staal_H-profiel_met_oplegstrippen (void):S355_HE450B + oplegstrippen d=12; Span: 3110 mm
Pset_QuantityTakeOff - Reference: 28_PBT_SF_staal_H-profiel_met_oplegstrippen (void):S355_HE450B + oplegstrippen d=12
Pset_ReinforcementBarPitchOfBeam - Reference: 28_PBT_SF_staal_H-profiel_met_oplegstrippen (void):S355_HE450B + oplegstrippen d=12
Pset_Pieters - Bouwlaag: Level: 06 ok ruwe vloer toneeltoren; Naamgeving element: 28_PBT_SF_staal_H-profiel_met_oplegstrippen (void): S355_HE450B + oplegstrippen d=12; Fase: Nieuw
BaseQuantities - Length: 3110 mm; CrossSectionArea: 6243895 mm2; OuterSurfaceArea: 6299759 mm2; GrossSurfaceArea: 6343356 mm2; GrossVolume: 0.0677926 m3; NetVolume: 0.0879442 m3; NetSurfaceArea: 9864396 mm2

# IfcBeam: 28_PBT_SF_staal_H-profiel_met_oplegstrippen (void):S355_HE450B + oplegstrippen d=12 (3)
Type - PredefinedType: BEAM; Classification: 28.11 hoofddraagconstructies - kolommen en liggers, kolom-/liggerconstructies (Uniformat); Material: 00_PBT_MAT_staal_S355, 00_PBT_MAT_Lucht
Type - Pset_BeamCommon - IsExternal: no; LoadBearing: yes
Type - Pset_ProductRequirements - Category: Structural Framing
Type - Pset_ReinforcementBarPitchOfBeam - Description: HE450B + oplegstrippen d=12
Type - Pset_Pieters - Breedte: 300 mm; Hoogte: 450 mm; Codering - NL-SfB: 28.11; Omschrijving NL-SfB: hoofddraagconstructies - kolommen en liggers, kolom-/liggerconstructies; Materiaal: 00_PBT_MAT_staal_S355; Materiaalkwaliteit: S355; Description: HE450B + oplegstrippen d=12
Material: 00_PBT_MAT_staal_S355
Pset_BeamCommon - Slope: 0 deg; Reference: 28_PBT_SF_staal_H-profiel_met_oplegstrippen (void):S355_HE450B + oplegstrippen d=12
Pset_QuantityTakeOff - Reference: 28_PBT_SF_staal_H-profiel_met_oplegstrippen (void):S355_HE450B + oplegstrippen d=12
Pset_ReinforcementBarPitchOfBeam - Reference: 28_PBT_SF_staal_H-profiel_met_oplegstrippen (void):S355_HE450B + oplegstrippen d=12
Pset_Pieters - Naamgeving element: 28_PBT_SF_staal_H-profiel_met_oplegstrippen (void): S355_HE450B + oplegstrippen d=12; Fase: Nieuw
Name (28_PBT_SF_staal_H-profiel_met_oplegstrippen (void):S355_HE450B + oplegstrippen d=12:...) | In | Span (mm) = Length (mm) | Bouwlaag | CrossSectionArea (mm2) | OuterSurfaceArea (mm2) | GrossSurfaceArea (mm2) | GrossVolume (m3) | NetVolume (m3) | NetSurfaceArea (mm2)
2489961 | 06 zesde verdieping | 6158.85 | Level: 06 zesde verdieping | 13523415 | 3473594 | 3480074 | 0.0199547 | 0.174159 | 19479405
2490052 | 06 zesde verdieping | 6070 | Level: 06 zesde verdieping | 13329994 | 3423480 | 3429960 | 0.0196668 | 0.171647 | 19199188
4714039 | 05 vijfde verdieping | 3274 | Level: 06 ok ruwe vloer toneeltoren | 6206524 | 6251751 | 6295348 | 0.067276 | 0.087274 | 9789654

# IfcBeam: 28_PBT_SF_staal_H-profiel_met_oplegstrippen (void):S355_HE500B + oplegstrip_d=12_vloer=300, 28_PBT_SF_staal_H-profiel_met_oplegstrippen (void):S355_HE500B + oplegstrip_d=12_vloer=300:2330946
In: 02 tweede verdieping
Type - PredefinedType: BEAM; Classification: 28.11 hoofddraagconstructies - kolommen en liggers, kolom-/liggerconstructies (Uniformat); Material: 00_PBT_MAT_Lucht, 00_PBT_MAT_staal_S355
Type - Pset_BeamCommon - IsExternal: no; LoadBearing: yes
Type - Pset_ProductRequirements - Category: Structural Framing
Type - Pset_ReinforcementBarPitchOfBeam - Description: HE500B + oplegstrippen d=12
Type - Pset_Pieters - Breedte: 300 mm; Hoogte: 500 mm; Codering - NL-SfB: 28.11; Omschrijving NL-SfB: hoofddraagconstructies - kolommen en liggers, kolom-/liggerconstructies; Materiaal: 00_PBT_MAT_staal_S355; Materiaalkwaliteit: S355; Description: HE500B + oplegstrippen d=12
Material: 00_PBT_MAT_staal_S355
Pset_BeamCommon - Slope: 0 deg; Reference: 28_PBT_SF_staal_H-profiel_met_oplegstrippen (void):S355_HE500B + oplegstrip_d=12_vloer=300; Span: 10320 mm
Pset_QuantityTakeOff - Reference: 28_PBT_SF_staal_H-profiel_met_oplegstrippen (void):S355_HE500B + oplegstrip_d=12_vloer=300
Pset_ReinforcementBarPitchOfBeam - Reference: 28_PBT_SF_staal_H-profiel_met_oplegstrippen (void):S355_HE500B + oplegstrip_d=12_vloer=300
Pset_Pieters - Bouwlaag: Level: 02 tweede verdieping; Naamgeving element: 28_PBT_SF_staal_H-profiel_met_oplegstrippen (void): S355_HE500B + oplegstrip_d=12_vloer=300; Fase: Nieuw
BaseQuantities - Length: 10320 mm; CrossSectionArea: 23061999 mm2; OuterSurfaceArea: 2460120 mm2; GrossSurfaceArea: 2467800 mm2; GrossVolume: 0.0142272 m3; NetVolume: 0.677698 m3; NetSurfaceArea: 32177398 mm2

# IfcBeam: 28_PBT_SF_staal_H-profiel_met_oplegstrippen (void):S355_HE500B + oplegstrip_d=15_vloer=300, 28_PBT_SF_staal_H-profiel_met_oplegstrippen (void):S355_HE500B + oplegstrip_d=15_vloer=300:2255717
In: 01 eerste verdieping
Type - PredefinedType: BEAM; Classification: 28.11 hoofddraagconstructies - kolommen en liggers, kolom-/liggerconstructies (Uniformat); Material: 00_PBT_MAT_staal_S355, 00_PBT_MAT_Lucht
Type - Pset_BeamCommon - IsExternal: no; LoadBearing: yes
Type - Pset_ProductRequirements - Category: Structural Framing
Type - Pset_ReinforcementBarPitchOfBeam - Description: HE500B + oplegstrippen d=15
Type - Pset_Pieters - Breedte: 300 mm; Hoogte: 500 mm; Codering - NL-SfB: 28.11; Omschrijving NL-SfB: hoofddraagconstructies - kolommen en liggers, kolom-/liggerconstructies; Materiaal: 00_PBT_MAT_staal_S355; Materiaalkwaliteit: S355; Description: HE500B + oplegstrippen d=15
Material: 00_PBT_MAT_staal_S355
Pset_BeamCommon - Slope: 0 deg; Reference: 28_PBT_SF_staal_H-profiel_met_oplegstrippen (void):S355_HE500B + oplegstrip_d=15_vloer=300; Span: 10317.6 mm
Pset_QuantityTakeOff - Reference: 28_PBT_SF_staal_H-profiel_met_oplegstrippen (void):S355_HE500B + oplegstrip_d=15_vloer=300
Pset_ReinforcementBarPitchOfBeam - Reference: 28_PBT_SF_staal_H-profiel_met_oplegstrippen (void):S355_HE500B + oplegstrip_d=15_vloer=300
Pset_Pieters - Bouwlaag: Level: 01 eerste verdieping; Naamgeving element: 28_PBT_SF_staal_H-profiel_met_oplegstrippen (void): S355_HE500B + oplegstrip_d=15_vloer=300; Fase: Nieuw
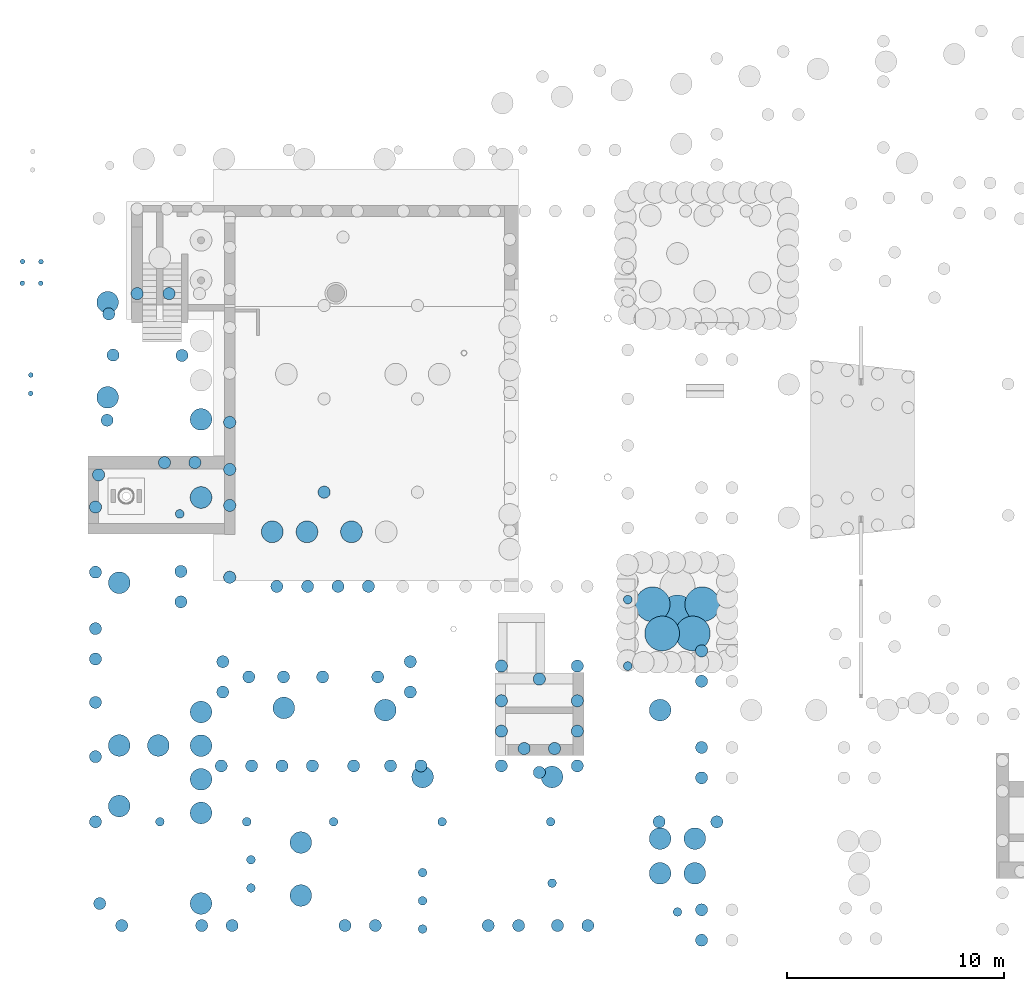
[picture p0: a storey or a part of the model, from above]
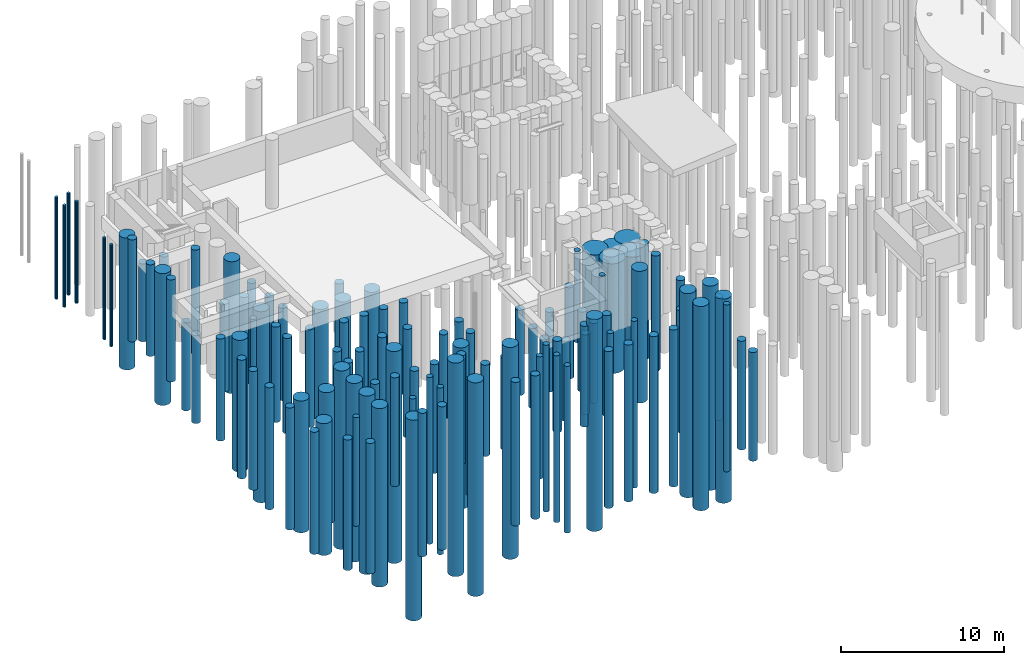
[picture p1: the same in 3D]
Properties of the parts of a building model (IFC2X3), part 6 of 18

# IfcBeam: 28_PBT_SF_staal_H-profiel_met_oplegstrippen (void):S355_HE500B + oplegstrip_d=15_vloer=300, 28_PBT_SF_staal_H-profiel_met_oplegstrippen (void):S355_HE500B + oplegstrip_d=15_vloer=300:2255717
BaseQuantities - Length: 10317.6 mm; CrossSectionArea: 23309190 mm2; OuterSurfaceArea: 1810711 mm2; GrossSurfaceArea: 1820311 mm2; GrossVolume: 0.0129723 m3; NetVolume: 0.739452 m3; NetSurfaceArea: 32675033 mm2

# IfcBeam: 28_PBT_SF_staal_H-profiel_met_oplegstrippen (void):S355_HE550B + oplegstrip d=15_ h=325, 28_PBT_SF_staal_H-profiel_met_oplegstrippen (void):S355_HE550B + oplegstrip d=15_ h=325:5343958
In: 04 vierde verdieping
Type - PredefinedType: BEAM; Classification: 28.11 hoofddraagconstructies - kolommen en liggers, kolom-/liggerconstructies (Uniformat); Material: 00_PBT_MAT_Lucht, 00_PBT_MAT_staal_S355
Type - Pset_BeamCommon - IsExternal: no; LoadBearing: yes
Type - Pset_ProductRequirements - Category: Structural Framing
Type - Pset_ReinforcementBarPitchOfBeam - Description: HE550B + oplegstrippen
Type - Pset_Pieters - Breedte: 300 mm; Hoogte: 550 mm; Codering - NL-SfB: 28.11; Omschrijving NL-SfB: hoofddraagconstructies - kolommen en liggers, kolom-/liggerconstructies; Materiaal: 00_PBT_MAT_staal_S355; Materiaalkwaliteit: S355; Description: HE550B + oplegstrippen
Material: 00_PBT_MAT_staal_S355
Pset_BeamCommon - Slope: 0 deg; Reference: 28_PBT_SF_staal_H-profiel_met_oplegstrippen (void):S355_HE550B + oplegstrip d=15_ h=325; Span: 2167 mm
Pset_QuantityTakeOff - Reference: 28_PBT_SF_staal_H-profiel_met_oplegstrippen (void):S355_HE550B + oplegstrip d=15_ h=325
Pset_ReinforcementBarPitchOfBeam - Reference: 28_PBT_SF_staal_H-profiel_met_oplegstrippen (void):S355_HE550B + oplegstrip d=15_ h=325
Pset_Pieters - Bouwlaag: Level: 04 vierde verdieping; Naamgeving element: 28_PBT_SF_staal_H-profiel_met_oplegstrippen (void): S355_HE550B + oplegstrip d=15_ h=325; Fase: Nieuw
BaseQuantities - Length: 2167 mm; CrossSectionArea: 6675678 mm2; OuterSurfaceArea: 1451890 mm2; GrossSurfaceArea: 1461490 mm2; GrossVolume: 0.0104016 m3; NetVolume: 0.216706 m3; NetSurfaceArea: 9170236 mm2

# IfcBeam: 28_PBT_SF_staal_H-profiel_met_oplegstrippen (void):S355_HE550B + oplegstrippen d=25_ h=115/325, 28_PBT_SF_staal_H-profiel_met_oplegstrippen (void):S355_HE550B + oplegstrippen d=25_ h=115/325:5008854
In: 04 vierde verdieping
Type - PredefinedType: BEAM; Classification: 28.11 hoofddraagconstructies - kolommen en liggers, kolom-/liggerconstructies (Uniformat); Material: 00_PBT_MAT_Lucht, 00_PBT_MAT_staal_S355
Type - Pset_BeamCommon - IsExternal: no; LoadBearing: yes
Type - Pset_ProductRequirements - Category: Structural Framing
Type - Pset_ReinforcementBarPitchOfBeam - Description: HE550B + oplegstrippen
Type - Pset_Pieters - Breedte: 300 mm; Hoogte: 550 mm; Codering - NL-SfB: 28.11; Omschrijving NL-SfB: hoofddraagconstructies - kolommen en liggers, kolom-/liggerconstructies; Materiaal: 00_PBT_MAT_staal_S355; Materiaalkwaliteit: S355; Description: HE550B + oplegstrippen
Material: 00_PBT_MAT_staal_S355
Pset_BeamCommon - Slope: 0 deg; Reference: 28_PBT_SF_staal_H-profiel_met_oplegstrippen (void):S355_HE550B + oplegstrippen d=25_ h=115/325; Span: 1354.8 mm
Pset_QuantityTakeOff - Reference: 28_PBT_SF_staal_H-profiel_met_oplegstrippen (void):S355_HE550B + oplegstrippen d=25_ h=115/325
Pset_ReinforcementBarPitchOfBeam - Reference: 28_PBT_SF_staal_H-profiel_met_oplegstrippen (void):S355_HE550B + oplegstrippen d=25_ h=115/325
Pset_Pieters - Bouwlaag: Level: 04 vierde verdieping; Naamgeving element: 28_PBT_SF_staal_H-profiel_met_oplegstrippen (void): S355_HE550B + oplegstrippen d=25_ h=115/325; Fase: Nieuw
BaseQuantities - Length: 1354.8 mm; CrossSectionArea: 3754921 mm2; NetVolume: 0.0532421 m3; NetSurfaceArea: 4758188 mm2

# IfcBeam: 28_PBT_SF_staal_H-profiel_met_oplegstrippen (void):S355_HE550B + oplegstrippen d=25_ h=325, 28_PBT_SF_staal_H-profiel_met_oplegstrippen (void):S355_HE550B + oplegstrippen d=25_ h=325:5007343
In: 04 vierde verdieping
Type - PredefinedType: BEAM; Classification: 28.11 hoofddraagconstructies - kolommen en liggers, kolom-/liggerconstructies (Uniformat); Material: 00_PBT_MAT_staal_S355, 00_PBT_MAT_Lucht
Type - Pset_BeamCommon - IsExternal: no; LoadBearing: yes
Type - Pset_ProductRequirements - Category: Structural Framing
Type - Pset_ReinforcementBarPitchOfBeam - Description: HE550B + oplegstrippen d=25
Type - Pset_Pieters - Breedte: 300 mm; Hoogte: 550 mm; Codering - NL-SfB: 28.11; Omschrijving NL-SfB: hoofddraagconstructies - kolommen en liggers, kolom-/liggerconstructies; Materiaal: 00_PBT_MAT_staal_S355; Materiaalkwaliteit: S355; Description: HE550B + oplegstrippen d=25
Material: 00_PBT_MAT_staal_S355
Pset_BeamCommon - Slope: 0 deg; Reference: 28_PBT_SF_staal_H-profiel_met_oplegstrippen (void):S355_HE550B + oplegstrippen d=25_ h=325; Span: 5368.2 mm
Pset_QuantityTakeOff - Reference: 28_PBT_SF_staal_H-profiel_met_oplegstrippen (void):S355_HE550B + oplegstrippen d=25_ h=325
Pset_ReinforcementBarPitchOfBeam - Reference: 28_PBT_SF_staal_H-profiel_met_oplegstrippen (void):S355_HE550B + oplegstrippen d=25_ h=325
Pset_Pieters - Bouwlaag: Level: 04 vierde verdieping; Naamgeving element: 28_PBT_SF_staal_H-profiel_met_oplegstrippen (void): S355_HE550B + oplegstrippen d=25_ h=325; Fase: Nieuw
BaseQuantities - Length: 5368.2 mm; CrossSectionArea: 13678926 mm2; OuterSurfaceArea: 3596692 mm2; GrossSurfaceArea: 3606292 mm2; GrossVolume: 0.0257673 m3; NetVolume: 0.259169 m3; NetSurfaceArea: 19940068 mm2

# IfcBeam: 28_PBT_SF_staal_H-profiel_met_oplegstrippen (void):S355_HE600B + oplegstrip_vloer h=500, 28_PBT_SF_staal_H-profiel_met_oplegstrippen (void):S355_HE600B + oplegstrip_vloer h=500:2465474
In: 04 vierde verdieping
Type - PredefinedType: BEAM; Classification: 28.11 hoofddraagconstructies - kolommen en liggers, kolom-/liggerconstructies (Uniformat); Material: 00_PBT_MAT_staal_S355, 00_PBT_MAT_Lucht
Type - Pset_BeamCommon - IsExternal: no; LoadBearing: yes
Type - Pset_ProductRequirements - Category: Structural Framing
Type - Pset_ReinforcementBarPitchOfBeam - Description: HE600B + oplegstrippen
Type - Pset_Pieters - Breedte: 300 mm; Hoogte: 600 mm; Codering - NL-SfB: 28.11; Omschrijving NL-SfB: hoofddraagconstructies - kolommen en liggers, kolom-/liggerconstructies; Materiaal: 00_PBT_MAT_staal_S355; Materiaalkwaliteit: S355; Description: HE600B + oplegstrippen
Material: 00_PBT_MAT_staal_S355
Pset_BeamCommon - Slope: 0 deg; Reference: 28_PBT_SF_staal_H-profiel_met_oplegstrippen (void):S355_HE600B + oplegstrip_vloer h=500; Span: 21812.1 mm
Pset_QuantityTakeOff - Reference: 28_PBT_SF_staal_H-profiel_met_oplegstrippen (void):S355_HE600B + oplegstrip_vloer h=500
Pset_ReinforcementBarPitchOfBeam - Reference: 28_PBT_SF_staal_H-profiel_met_oplegstrippen (void):S355_HE600B + oplegstrip_vloer h=500
Pset_Pieters - Bouwlaag: Level: 04 vierde verdieping; Naamgeving element: 28_PBT_SF_staal_H-profiel_met_oplegstrippen (void): S355_HE600B + oplegstrip_vloer h=500; Fase: Nieuw; Zeeg: 100
BaseQuantities - Length: 21812.1 mm; CrossSectionArea: 49808366 mm2; OuterSurfaceArea: 4639519 mm2; GrossSurfaceArea: 4641919 mm2; GrossVolume: 0.0248546 m3; NetVolume: 0.704863 m3; NetSurfaceArea: 67062769 mm2

# IfcBeam: 28_PBT_SF_staal_H-profiel_met_oplegstrippen (void):S355_HE600B + oplegstrippen d=15_vloer h=500 (3)
In: 04 vierde verdieping
Type - PredefinedType: BEAM; Classification: 28.11 hoofddraagconstructies - kolommen en liggers, kolom-/liggerconstructies (Uniformat); Material: 00_PBT_MAT_Lucht, 00_PBT_MAT_staal_S355
Type - Pset_BeamCommon - IsExternal: no; LoadBearing: yes
Type - Pset_ProductRequirements - Category: Structural Framing
Type - Pset_ReinforcementBarPitchOfBeam - Description: HE600B + oplegstrippen d=15
Type - Pset_Pieters - Breedte: 300 mm; Hoogte: 600 mm; Codering - NL-SfB: 28.11; Omschrijving NL-SfB: hoofddraagconstructies - kolommen en liggers, kolom-/liggerconstructies; Materiaal: 00_PBT_MAT_staal_S355; Materiaalkwaliteit: S355; Description: HE600B + oplegstrippen d=15
Material: 00_PBT_MAT_staal_S355
Pset_BeamCommon - Slope: 0 deg; Reference: 28_PBT_SF_staal_H-profiel_met_oplegstrippen (void):S355_HE600B + oplegstrippen d=15_vloer h=500; Span: 21812.1 mm
Pset_QuantityTakeOff - Reference: 28_PBT_SF_staal_H-profiel_met_oplegstrippen (void):S355_HE600B + oplegstrippen d=15_vloer h=500
Pset_ReinforcementBarPitchOfBeam - Reference: 28_PBT_SF_staal_H-profiel_met_oplegstrippen (void):S355_HE600B + oplegstrippen d=15_vloer h=500
Pset_Pieters - Bouwlaag: Level: 04 vierde verdieping; Naamgeving element: 28_PBT_SF_staal_H-profiel_met_oplegstrippen (void): S355_HE600B + oplegstrippen d=15_vloer h=500; Fase: Nieuw; Zeeg: 100
BaseQuantities - Length: 21812.1 mm; CrossSectionArea: 53742540 mm2; OuterSurfaceArea: 13290771 mm2; GrossSurfaceArea: 13297971 mm2; GrossVolume: 0.0766775 m3; NetVolume: 0.730928 m3; NetSurfaceArea: 74931117 mm2
Name (28_PBT_SF_staal_H-profiel_met_oplegstrippen (void):S355_HE600B + oplegstrippen d=15_vloer h=500:...) | Group
3373589 | Model Group:Array Group 17:3373591
3373593 | Model Group:Array Group 17:3373595
3373605 | Model Group:Array Group 17:3373607

# IfcBeam: 28_PBT_SF_staal_H-profiel_met_oplegstrippen (void):S355_HE600B + oplegstrippen d=15_vloer h=500 (3)
In: 04 vierde verdieping
Type - PredefinedType: BEAM; Classification: 28.11 hoofddraagconstructies - kolommen en liggers, kolom-/liggerconstructies (Uniformat); Material: 00_PBT_MAT_staal_S355, 00_PBT_MAT_Lucht
Type - Pset_BeamCommon - IsExternal: no; LoadBearing: yes
Type - Pset_ProductRequirements - Category: Structural Framing
Type - Pset_ReinforcementBarPitchOfBeam - Description: HE600B + oplegstrippen d=15
Type - Pset_Pieters - Breedte: 300 mm; Hoogte: 600 mm; Codering - NL-SfB: 28.11; Omschrijving NL-SfB: hoofddraagconstructies - kolommen en liggers, kolom-/liggerconstructies; Materiaal: 00_PBT_MAT_staal_S355; Materiaalkwaliteit: S355; Description: HE600B + oplegstrippen d=15
Material: 00_PBT_MAT_staal_S355
Pset_BeamCommon - Slope: 0 deg; Reference: 28_PBT_SF_staal_H-profiel_met_oplegstrippen (void):S355_HE600B + oplegstrippen d=15_vloer h=500; Span: 21812.1 mm
Pset_QuantityTakeOff - Reference: 28_PBT_SF_staal_H-profiel_met_oplegstrippen (void):S355_HE600B + oplegstrippen d=15_vloer h=500
Pset_ReinforcementBarPitchOfBeam - Reference: 28_PBT_SF_staal_H-profiel_met_oplegstrippen (void):S355_HE600B + oplegstrippen d=15_vloer h=500
Pset_Pieters - Bouwlaag: Level: 04 vierde verdieping; Naamgeving element: 28_PBT_SF_staal_H-profiel_met_oplegstrippen (void): S355_HE600B + oplegstrippen d=15_vloer h=500; Fase: Nieuw; Zeeg: 100
BaseQuantities - Length: 21812.1 mm; CrossSectionArea: 53742540 mm2; OuterSurfaceArea: 13290771 mm2; GrossSurfaceArea: 13297971 mm2; GrossVolume: 0.0766775 m3; NetVolume: 0.730928 m3; NetSurfaceArea: 74931117 mm2
Name (28_PBT_SF_staal_H-profiel_met_oplegstrippen (void):S355_HE600B + oplegstrippen d=15_vloer h=500:...) | Group
3373577 | Model Group:Array Group 17:3373579
3373597 | Model Group:Array Group 17:3373599
3373601 | Model Group:Array Group 17:3373603

# IfcBeam: 28_PBT_SF_staal_IPE-profiel:S355_IPE100 (14)
Type - Pset_BeamCommon - IsExternal: no; LoadBearing: yes
Type - Pset_ProductRequirements - Category: Structural Framing
Type - Pset_ReinforcementBarPitchOfBeam - Description: IPE100
Type - Pset_Pieters - Breedte: 55 mm; Hoogte: 100 mm; Codering - NL-SfB: 28.11; Omschrijving NL-SfB: hoofddraagconstructies - kolommen en liggers, kolom-/liggerconstructies; Materiaal: 00_PBT_MAT_staal_S355; Materiaalkwaliteit: S355; Description: IPE100
Classification: 28.11 hoofddraagconstructies - kolommen en liggers, kolom-/liggerconstructies (Uniformat); Material: 00_PBT_MAT_staal_S355
Pset_BeamCommon - Slope: 0 deg; Reference: 28_PBT_SF_staal_IPE-profiel:S355_IPE100
Pset_QuantityTakeOff - Reference: 28_PBT_SF_staal_IPE-profiel:S355_IPE100
Pset_ReinforcementBarPitchOfBeam - Reference: 28_PBT_SF_staal_IPE-profiel:S355_IPE100
Pset_Pieters - Naamgeving element: 28_PBT_SF_staal_IPE-profiel: S355_IPE100; Fase: Nieuw
Name (28_PBT_SF_staal_IPE-profiel:S355_IPE100:...) | In | CrossSectionArea (mm2) | NetVolume (m3) | Span (mm) = Length (mm) | Bouwlaag | NetSurfaceArea (mm2)
3471057 | 02 tweede verdieping | 257293 | 0.00132344 | 1282 | Level: 02 tweede verdieping | 514586
3471087 | 02 tweede verdieping | 257293 | 0.00132344 | 1282 | Level: 02 tweede verdieping | 514586
3471197 | 02 tweede verdieping | 257293 | 0.00132344 | 1282 | Level: 02 tweede verdieping | 514586
3471492 | 02 tweede verdieping | 162731 | 0.000835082 | 808.931 | Level: 02 tweede verdieping | 325461
3471580 | 02 tweede verdieping | 162731 | 0.000835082 | 808.931 | Level: 02 tweede verdieping | 325461
3471594 | 02 tweede verdieping | 162731 | 0.000835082 | 808.931 | Level: 02 tweede verdieping | 325461
3471610 | 02 tweede verdieping | 162731 | 0.000835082 | 808.931 | Level: 02 tweede verdieping | 325461
3471685 | 02 tweede verdieping | 162731 | 0.000835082 | 808.931 | Level: 02 tweede verdieping | 325461
3817148 | 04 vierde verdieping | 575639 | 0.00296753 | 3000 | Level: 04 vierde verdieping_bk staal drycooler | 1151279
3817711 | 04 vierde verdieping | 2248808 | 0.0116085 | 11245 | Level: 04 vierde verdieping_bk staal drycooler | 4497617
3817815 | 04 vierde verdieping | 2248808 | 0.0116085 | 11245 | Level: 04 vierde verdieping_bk staal drycooler | 4497617
3817900 | 04 vierde verdieping | 575639 | 0.00296753 | 3000 | Level: 04 vierde verdieping_bk staal drycooler | 1151279
3818018 | 04 vierde verdieping | 575639 | 0.00296753 | 3000 | Level: 04 vierde verdieping_bk staal drycooler | 1151279
3818032 | 04 vierde verdieping | 575639 | 0.00296753 | 3000 | Level: 04 vierde verdieping_bk staal drycooler | 1151279

# IfcBeam: 28_PBT_SF_staal_IPE-profiel:S355_IPE220 (13)
Type - Pset_BeamCommon - IsExternal: no; LoadBearing: yes
Type - Pset_ProductRequirements - Category: Structural Framing
Type - Pset_ReinforcementBarPitchOfBeam - Description: IPE220
Type - Pset_Pieters - Breedte: 110 mm; Hoogte: 220 mm; Codering - NL-SfB: 28.11; Omschrijving NL-SfB: hoofddraagconstructies - kolommen en liggers, kolom-/liggerconstructies; Materiaal: 00_PBT_MAT_staal_S355; Materiaalkwaliteit: S355; Description: IPE220
Classification: 28.11 hoofddraagconstructies - kolommen en liggers, kolom-/liggerconstructies (Uniformat); Material: 00_PBT_MAT_staal_S355
Pset_BeamCommon - Slope: 0 deg; Reference: 28_PBT_SF_staal_IPE-profiel:S355_IPE220
Pset_QuantityTakeOff - Reference: 28_PBT_SF_staal_IPE-profiel:S355_IPE220
Pset_ReinforcementBarPitchOfBeam - Reference: 28_PBT_SF_staal_IPE-profiel:S355_IPE220
Pset_Pieters - Naamgeving element: 28_PBT_SF_staal_IPE-profiel: S355_IPE220; Fase: Nieuw
Name (28_PBT_SF_staal_IPE-profiel:S355_IPE220:...) | In | CrossSectionArea (mm2) | NetVolume (m3) | Span (mm) = Length (mm) | Bouwlaag | NetSurfaceArea (mm2)
2873399 | 05 vijfde verdieping | 782762 | 0.00613733 | 1974.54 | Level: 05 vijfde verdieping | 1565525
2873494 | 05 vijfde verdieping | 782762 | 0.00613733 | 1974.54 | Level: 05 vijfde verdieping | 1565525
2873625 | 05 vijfde verdieping | 1221058 | 0.00958855 | 3183.74 | Level: 05 vijfde verdieping | 2442115
2873627 | 05 vijfde verdieping | 746240 | 0.00584974 | 1888.36 | Level: 05 vijfde verdieping | 1492479
2873629 | 05 vijfde verdieping | 1275011 | 0.0100134 | 3026.05 | Level: 05 vijfde verdieping | 2550021
2873631 | 05 vijfde verdieping | 1275011 | 0.0100134 | 3026.05 | Level: 05 vijfde verdieping | 2550021
2873633 | 05 vijfde verdieping | 1180036 | 0.00926554 | 3790 | Level: 05 vijfde verdieping | 2360073
2873730 | 06 zesde verdieping | 1273058 | 0.009998 | 3183.74 | Level: 06 zesde verdieping | 2546116
2873732 | 05 vijfde verdieping | 1000519 | 0.00785199 | 2488.36 | Level: 05 vijfde verdieping | 2001038
2873734 | 05 vijfde verdieping | 1275011 | 0.0100134 | 3026.05 | Level: 05 vijfde verdieping | 2550021
2873736 | 05 vijfde verdieping | 1275011 | 0.0100134 | 3026.05 | Level: 05 vijfde verdieping | 2550021
2873738 | 05 vijfde verdieping | 1180036 | 0.00926554 | 3789.56 | Level: 05 vijfde verdieping | 2360073
2873830 | 05 vijfde verdieping | 483114 | 0.00377785 | 1392.49 | Level: 05 vijfde verdieping | 966229

# IfcBeam: 28_PBT_SF_staal_L-profiel:S355_L100x100x10 (32)
In: 03 derde verdieping
Type - Pset_BeamCommon - IsExternal: no; LoadBearing: yes
Type - Pset_ProductRequirements - Category: Structural Framing
Type - Pset_ReinforcementBarPitchOfBeam - Description: L100x100x10
Type - Pset_Pieters - Breedte: 100 mm; Hoogte: 100 mm; Codering - NL-SfB: 28.11; Omschrijving NL-SfB: hoofddraagconstructies - kolommen en liggers, kolom-/liggerconstructies; Materiaal: 00_PBT_MAT_staal_S355; Materiaalkwaliteit: S355; Description: L100x100x10
Classification: 28.11 hoofddraagconstructies - kolommen en liggers, kolom-/liggerconstructies (Uniformat); Material: 00_PBT_MAT_staal_S355
Pset_BeamCommon - Slope: 0 deg; Reference: 28_PBT_SF_staal_L-profiel:S355_L100x100x10
Pset_QuantityTakeOff - Reference: 28_PBT_SF_staal_L-profiel:S355_L100x100x10
Pset_ReinforcementBarPitchOfBeam - Reference: 28_PBT_SF_staal_L-profiel:S355_L100x100x10
Pset_Pieters - Bouwlaag: Level: 04 bk staal paradezaal binnendoos; Naamgeving element: 28_PBT_SF_staal_L-profiel: S355_L100x100x10; Fase: Nieuw
Name (28_PBT_SF_staal_L-profiel:S355_L100x100x10:...) | CrossSectionArea (mm2) | NetVolume (m3) | Span (mm) = Length (mm) | NetSurfaceArea (mm2)
2518120 | 1152470 | 0.0113104 | 6204.84 | 2304941
2518122 | 1168686 | 0.0114698 | 6288.06 | 2337372
6302145 | 1152470 | 0.0113104 | 6204.84 | 2304941
6302147 | 1168686 | 0.0114698 | 6288.06 | 2337372
6302644 | 1152470 | 0.0113104 | 6204.84 | 2304941
6302646 | 1168686 | 0.0114698 | 6288.06 | 2337372
6302651 | 1152470 | 0.0113104 | 6204.84 | 2304941
6302653 | 1168686 | 0.0114698 | 6288.06 | 2337372
6302719 | 1062369 | 0.0104247 | 5809.04 | 2124738
6302726 | 1043916 | 0.0102433 | 5809.03 | 2087831
6303147 | 1044343 | 0.0102475 | 5716.52 | 2088685
6303150 | 1026343 | 0.0100705 | 5718.85 | 2052685
6303393 | 829865 | 0.0081391 | 4615.79 | 1659731
6303396 | 811671 | 0.00796023 | 4617.11 | 1623342
6303563 | 1062369 | 0.0104247 | 5809.04 | 2124738
6303566 | 1043916 | 0.0102433 | 5809.03 | 2087831
6303569 | 1044796 | 0.010252 | 5718.85 | 2089591
6303572 | 1026343 | 0.0100705 | 5718.85 | 2052685
6303618 | 829866 | 0.0081391 | 4615.79 | 1659731
6303621 | 811412 | 0.00795769 | 4615.79 | 1622825
6304722 | 1370312 | 0.0134519 | 7322.84 | 2740624
6304726 | 1370312 | 0.0134519 | 7322.84 | 2740624
6304729 | 1370312 | 0.0134519 | 7322.84 | 2740624
6304732 | 1370312 | 0.0134519 | 7322.84 | 2740624
6304735 | 1277659 | 0.0125411 | 6913.94 | 2555318
6304738 | 1259581 | 0.0123634 | 6915.86 | 2519161
6304741 | 1106531 | 0.0108588 | 6035.68 | 2213062
6304744 | 1088275 | 0.0106794 | 6036.69 | 2176551
6304747 | 1278034 | 0.0125448 | 6915.86 | 2556067
6304750 | 1259581 | 0.0123634 | 6915.86 | 2519161
6304753 | 1106531 | 0.0108588 | 6035.68 | 2213062
6304756 | 1088078 | 0.0106774 | 6035.68 | 2176155

# IfcBeam: 28_PBT_SF_staal_L-profiel:S355_L150x150x15 (60)
Type - Pset_BeamCommon - IsExternal: no; LoadBearing: yes
Type - Pset_ProductRequirements - Category: Structural Framing
Type - Pset_ReinforcementBarPitchOfBeam - Description: L150x150x15
Type - Pset_Pieters - Breedte: 150 mm; Hoogte: 150 mm; Codering - NL-SfB: 28.11; Omschrijving NL-SfB: hoofddraagconstructies - kolommen en liggers, kolom-/liggerconstructies; Materiaal: 00_PBT_MAT_staal_S355; Materiaalkwaliteit: S355; Description: L150x150x15
Classification: 28.11 hoofddraagconstructies - kolommen en liggers, kolom-/liggerconstructies (Uniformat); Material: 00_PBT_MAT_staal_S355
Pset_BeamCommon - Slope: 0 deg; Reference: 28_PBT_SF_staal_L-profiel:S355_L150x150x15
Pset_QuantityTakeOff - Reference: 28_PBT_SF_staal_L-profiel:S355_L150x150x15
Pset_ReinforcementBarPitchOfBeam - Reference: 28_PBT_SF_staal_L-profiel:S355_L150x150x15
Pset_Pieters - Naamgeving element: 28_PBT_SF_staal_L-profiel: S355_L150x150x15; Fase: Nieuw
Name (28_PBT_SF_staal_L-profiel:S355_L150x150x15:...) | In | CrossSectionArea (mm2) | NetVolume (m3) | Span (mm) = Length (mm) | Bouwlaag | NetSurfaceArea (mm2)
2317201 | 01 eerste verdieping | 906897 | 0.0132479 | 3079.13 | Level: 01 eerste verdieping | 1813793
2317203 | 01 eerste verdieping | 994956 | 0.0145404 | 3379.54 | Level: 01 eerste verdieping | 1989913
2326061 | 02 tweede verdieping | 1294889 | 0.0189427 | 4402.74 | Level: 02 tweede verdieping | 2589779
2326063 | 02 tweede verdieping | 1295092 | 0.0189456 | 4403.43 | Level: 02 tweede verdieping | 2590184
2394180 | 01 eerste verdieping | 367784 | 0.00533502 | 1239.99 | Level: 01 eerste verdieping | 735568
2394418 | 01 eerste verdieping | 303297 | 0.00438851 | 1020 | Level: 01 eerste verdieping | 606594
2405117 | 02 tweede verdieping | 367784 | 0.00533502 | 1239.99 | Level: 02 tweede verdieping | 735568
2414082 | 02 tweede verdieping | 303297 | 0.00438851 | 1020 | Level: 02 tweede verdieping | 606594
2427904 | 03 derde verdieping | 367784 | 0.00533502 | 1239.99 | Level: 03 derde verdieping | 735568
2427907 | 03 derde verdieping | 303297 | 0.00438851 | 1020 | Level: 03 derde verdieping | 606594
2427918 | 04 vierde verdieping | 360457 | 0.00522747 | 1214.99 | Level: 04 vierde verdieping | 720913
2427921 | 04 vierde verdieping | 353923 | 0.00513158 | 1192.71 | Level: 04 vierde verdieping | 707847
3352167 | 02 tweede verdieping | 371228 | 0.00538557 | 1251.74 | Level: 02 tweede verdieping | 742456
3352170 | 02 tweede verdieping | 357591 | 0.00518541 | 1205.22 | Level: 02 tweede verdieping | 715181
3352280 | 01 eerste verdieping | 293104 | 0.00423889 | 985.223 | Level: 01 eerste verdieping | 586207
3352282 | 01 eerste verdieping | 357591 | 0.00518541 | 1205.22 | Level: 01 eerste verdieping | 715181
3352462 | 00 begane grond | 293104 | 0.00423889 | 985.223 | Level: 00 begane grond | 586207
3352464 | 00 begane grond | 357591 | 0.00518541 | 1205.22 | Level: 00 begane grond | 715181
3424955 | -1 kelder | 473315 | 0.00688396 | 1600 | Level: -1 kelder | 946630
3425197 | -1 kelder | 474781 | 0.00690547 | 1605 | Level: -1 kelder | 949561
3460667 | 02 tweede verdieping | 710790 | 0.0103695 | 2410.13 | Level: 02 tweede verdieping | 1421580
3461618 | 02 tweede verdieping | 710790 | 0.0103695 | 2410.13 | Level: 02 tweede verdieping | 1421580
3523348 | 05 vijfde verdieping | 4532884 | 0.0664685 | 15448.9 | Level: 05 vijfde verdieping | 9065769
3523678 | 05 vijfde verdieping | 8244503 | 0.120946 | 28110.8 | Level: 05 vijfde verdieping | 16489005
4330768 | 01 eerste verdieping | 629740 | 0.0091799 | 2246.33 | Level: 01 eerste verdieping | 1259480
4330978 | 01 eerste verdieping | 849486 | 0.0124052 | 2883.28 | Level: 01 eerste verdieping | 1698972
4331112 | 01 eerste verdieping | 502628 | 0.0073142 | 1700 | Level: 01 eerste verdieping | 1005256
4331114 | 01 eerste verdieping | 440279 | 0.00639907 | 1600 | Level: 01 eerste verdieping | 880558
4334365 | 01 eerste verdieping | 641732 | 0.00935591 | 2174.54 | Level: 01 eerste verdieping | 1283465
4340781 | 01 eerste verdieping | 641732 | 0.00935591 | 2174.54 | Level: 01 eerste verdieping | 1283465
5488321 | 00 begane grond | 354596 | 0.00514145 | 1195 | Level: 00 begane grond | 709192
5916852 | 04 vierde verdieping | 73645 | 0.00101687 | 315 | Level: 04 vierde verdieping | 147290
5917143 | 04 vierde verdieping | 157694 | 0.00225045 | 743.365 | Level: 04 vierde verdieping | 315387
6068208 | 01 eerste verdieping | 394169 | 0.00572229 | 1330 | Level: 01 eerste verdieping | 788338
6068379 | 01 eerste verdieping | 394169 | 0.00572229 | 1330 | Level: 01 eerste verdieping | 788338
6068577 | 01 eerste verdieping | 579514 | 0.0084427 | 1962.29 | Level: 01 eerste verdieping | 1159028
6068579 | 01 eerste verdieping | 512888 | 0.00746479 | 1735 | Level: 01 eerste verdieping | 1025776
6068962 | 02 tweede verdieping | 394169 | 0.00572229 | 1330 | Level: 02 tweede verdieping | 788338
6068966 | 02 tweede verdieping | 403635 | 0.00586123 | 1362.29 | Level: 02 tweede verdieping | 807270
6068968 | 02 tweede verdieping | 341405 | 0.00494784 | 1150 | Level: 02 tweede verdieping | 682810
6068971 | 03 derde verdieping | 394169 | 0.00572229 | 1330 | Level: 03 derde verdieping | 788338
6068973 | 03 derde verdieping | 320214 | 0.00463681 | 1077.71 | Level: 03 derde verdieping | 640428
6068975 | 03 derde verdieping | 300583 | 0.00434867 | 1010.74 | Level: 03 derde verdieping | 601165
6069040 | 00 begane grond | 271053 | 0.00391525 | 910 | Level: 00 begane grond | 542107
6069042 | 00 begane grond | 461590 | 0.00671186 | 1560 | Level: 00 begane grond | 923179
6069044 | 00 begane grond | 759117 | 0.0110788 | 2574.99 | Level: 00 begane grond | 1518234
6069046 | 00 begane grond | 580306 | 0.00845432 | 1964.99 | Level: 00 begane grond | 1160612
6069555 | 00 begane grond | 275450 | 0.00397979 | 925 | Level: 00 begane grond | 550901
6069722 | 00 begane grond | 461590 | 0.00671186 | 1560 | Level: 00 begane grond | 923179
6070199 | 04 vierde verdieping | 394169 | 0.00572229 | 1330 | Level: 04 vierde verdieping | 788338
6070203 | 04 vierde verdieping | 535329 | 0.00779417 | 1811.56 | Level: 04 vierde verdieping | 1070657
6070205 | 04 vierde verdieping | 303970 | 0.00439839 | 1022.29 | Level: 04 vierde verdieping | 607940
6070580 | 02 tweede verdieping | 353803 | 0.00512981 | 1192.29 | Level: 02 tweede verdieping | 707605
6136187 | 04 vierde verdieping | 358993 | 0.00520599 | 1210 | Level: 04 vierde verdieping | 717986
6136294 | 02 tweede verdieping | 320214 | 0.00463681 | 1077.71 | Level: 02 tweede verdieping | 640428
6136772 | 02 tweede verdieping | 600034 | 0.00874388 | 2032.29 | Level: 02 tweede verdieping | 1200068
6217357 | 02 tweede verdieping | 350199 | 0.00507692 | 1180 | Level: 02 tweede verdieping | 700398
6360991 | 02 tweede verdieping | 962238 | 0.0140602 | 3267.93 | Level: 02 tweede verdieping | 1924477
6382215 | -1 kelder | 322938 | 0.00467679 | 1087 | Level: -1 kelder | 645876
6386432 | -1 kelder | 319007 | 0.00461909 | 1073.59 | Level: -1 kelder | 638014

# IfcBeam: 28_PBT_SF_staal_L-profiel:S355_L150x150x15 + opgelaste doken (2)
In: 03 derde verdieping
Type - Pset_BeamCommon - IsExternal: no; LoadBearing: yes
Type - Pset_ProductRequirements - Category: Structural Framing
Type - Pset_ReinforcementBarPitchOfBeam - Description: L150x150x15 + opgelaste doken
Type - Pset_Pieters - Breedte: 150 mm; Hoogte: 150 mm; Codering - NL-SfB: 28.11; Omschrijving NL-SfB: hoofddraagconstructies - kolommen en liggers, kolom-/liggerconstructies; Materiaal: 00_PBT_MAT_staal_S355; Materiaalkwaliteit: S355; Description: L150x150x15 + opgelaste doken
Classification: 28.11 hoofddraagconstructies - kolommen en liggers, kolom-/liggerconstructies (Uniformat); Material: 00_PBT_MAT_staal_S355
BaseQuantities - CrossSectionArea: 279326 mm2; NetVolume: 0.00403667 m3; Length: 950.921 mm; NetSurfaceArea: 558651 mm2
Pset_BeamCommon - Slope: 0 deg; Reference: 28_PBT_SF_staal_L-profiel:S355_L150x150x15 + opgelaste doken; Span: 950.921 mm
Pset_QuantityTakeOff - Reference: 28_PBT_SF_staal_L-profiel:S355_L150x150x15 + opgelaste doken
Pset_ReinforcementBarPitchOfBeam - Reference: 28_PBT_SF_staal_L-profiel:S355_L150x150x15 + opgelaste doken
Pset_Pieters - Bouwlaag: Level: 03 derde verdieping; Naamgeving element: 28_PBT_SF_staal_L-profiel: S355_L150x150x15 + opgelaste doken; Fase: Nieuw
Name (28_PBT_SF_staal_L-profiel:S355_L150x150x15 + opgelaste doken:...)
4335813
4335971

# IfcBeam: 28_PBT_SF_staal_L-profiel:S355_L200x200x20 (80)
Type - Pset_BeamCommon - IsExternal: no; LoadBearing: yes
Type - Pset_ProductRequirements - Category: Structural Framing
Type - Pset_ReinforcementBarPitchOfBeam - Description: L200x200x20
Type - Pset_Pieters - Breedte: 200 mm; Hoogte: 200 mm; Codering - NL-SfB: 28.11; Omschrijving NL-SfB: hoofddraagconstructies - kolommen en liggers, kolom-/liggerconstructies; Materiaal: 00_PBT_MAT_staal_S355; Materiaalkwaliteit: S355; Description: L200x200x20
Classification: 28.11 hoofddraagconstructies - kolommen en liggers, kolom-/liggerconstructies (Uniformat); Material: 00_PBT_MAT_staal_S355
Pset_BeamCommon - Reference: 28_PBT_SF_staal_L-profiel:S355_L200x200x20
Pset_QuantityTakeOff - Reference: 28_PBT_SF_staal_L-profiel:S355_L200x200x20
Pset_ReinforcementBarPitchOfBeam - Reference: 28_PBT_SF_staal_L-profiel:S355_L200x200x20
Pset_Pieters - Naamgeving element: 28_PBT_SF_staal_L-profiel: S355_L200x200x20; Fase: Nieuw
Name (28_PBT_SF_staal_L-profiel:S355_L200x200x20:...) | In | CrossSectionArea (mm2) | NetVolume (m3) | Slope (deg) | Span (mm) = Length (mm) | Bouwlaag | NetSurfaceArea (mm2)
2390046 | 01 eerste verdieping | 2632319 | 0.0510837 | 0 | 6916.34 | Level: 01 eerste verdieping | 5264638
2392705 | 01 eerste verdieping | 1587265 | 0.030744 | 0 | 4026.85 | Level: 01 eerste verdieping | 3174530
2394531 | 01 eerste verdieping | 635274 | 0.0122156 | 0 | 1600 | Level: 01 eerste verdieping | 1270547
2394778 | 01 eerste verdieping | 8559216 | 0.166438 | 0 | 21800 | Level: 01 eerste verdieping | 17118431
2394838 | 01 eerste verdieping | 6354464 | 0.123527 | 0 | 16179.6 | Level: 01 eerste verdieping | 12708928
2396037 | 04 vierde verdieping | 596781 | 0.0114664 | 0 | 1501.87 | Level: 04 vierde verdieping | 1193561
2397563 | 04 vierde verdieping | 1404916 | 0.027195 | 0 | 3562 | Level: 04 vierde verdieping | 2809832
2401627 | 01 eerste verdieping | 875859 | 0.0168981 | 0 | 2213.31 | Level: 01 eerste verdieping | 1751718
2401712 | 01 eerste verdieping | 720274 | 0.01387 | 0 | 1816.69 | Level: 01 eerste verdieping | 1440548
2401766 | 01 eerste verdieping | 1588498 | 0.0307681 | 0 | 4029.99 | Level: 01 eerste verdieping | 3176996
2405115 | 02 tweede verdieping | 1587265 | 0.030744 | 0 | 4026.85 | Level: 02 tweede verdieping | 3174530
2405119 | 02 tweede verdieping | 639196 | 0.012292 | 0 | 1610 | Level: 02 tweede verdieping | 1278393
2405123 | 02 tweede verdieping | 8559216 | 0.166438 | 0 | 21800 | Level: 02 tweede verdieping | 17118431
2405125 | 02 tweede verdieping | 5552448 | 0.107918 | 0 | 14135 | Level: 02 tweede verdieping | 11104897
2405129 | 02 tweede verdieping | 11305400 | 0.219886 | 0 | 28800.7 | Level: 02 tweede verdieping | 22610799
2405131 | 02 tweede verdieping | 12267769 | 0.238617 | 0 | 31254 | Level: 02 tweede verdieping | 24535539
2414255 | 02 tweede verdieping | 1940623 | 0.0374226 | 0 | 5265.15 | Level: 02 tweede verdieping | 3881245
2414397 | 02 tweede verdieping | 1917691 | 0.0370038 | 0 | 5160 | Level: 02 tweede verdieping | 3835382
2414658 | 02 tweede verdieping | 1862352 | 0.036098 | 0 | 4840.81 | Level: 02 tweede verdieping | 3724705
2415474 | 02 tweede verdieping | 588201 | 0.0112995 | 0 | 1480 | Level: 02 tweede verdieping | 1176402
2424641 | 03 derde verdieping | 1478664 | 0.0286304 | 0 | 3750 | Level: 03 derde verdieping | 2957327
2424643 | 03 derde verdieping | 12267769 | 0.238617 | 0 | 31254 | Level: 03 derde verdieping | 24535539
2425838 | 03 derde verdieping | 11305400 | 0.219886 | 0 | 28800.7 | Level: 03 derde verdieping | 22610799
2425936 | 03 derde verdieping | 1126793 | 0.021782 | 0 | 2853 | Level: 03 derde verdieping | 2253587
2426628 | 03 derde verdieping | 1469583 | 0.0284536 | 0 | 3726.85 | Level: 03 derde verdieping | 2939165
2426630 | 03 derde verdieping | 639196 | 0.012292 | 0 | 1610 | Level: 03 derde verdieping | 1278393
2428150 | 03 derde verdieping | 1776007 | 0.0344175 | 0 | 4508 | Level: 03 derde verdieping | 3552015
2428152 | 03 derde verdieping | 964885 | 0.0186308 | 0 | 2440.26 | Level: 03 derde verdieping | 1929770
2431702 | 03 derde verdieping | 6687812 | 0.130015 | 0 | 17344.8 | Level: 03 derde verdieping | 13375624
2454956 | 03 derde verdieping | 917711 | 0.0177126 | 0 | 2320 | Level: 03 derde verdieping | 1835422
2504722 | 01 eerste verdieping | 3047333 | 0.0591611 | 0 | 8364.31 | Level: 01 eerste verdieping | 6094665
2645333 | 06 zesde verdieping | 7205376 | 0.140088 | 0 | 18348.7 | Level: 06 zesde verdieping | 14410752
2645545 | 06 zesde verdieping | 7205376 | 0.140088 | 0 | 18348.7 | Level: 06 zesde verdieping | 14410752
2645825 | 06 zesde verdieping | 7205205 | 0.140085 | 0 | 18348.3 | Level: 06 zesde verdieping | 14410411
2646155 | 06 zesde verdieping | 7028682 | 0.136649 | 0 | 17898.3 | Level: 06 zesde verdieping | 14057364
2691509 | 04 vierde verdieping | 1759257 | 0.0340915 | 0 | 4653 | Level: 04 vierde verdieping | 3518515
2691970 | 05 vijfde verdieping | 1772085 | 0.0343412 | 0 | 4498 | Level: 05 vijfde verdieping | 3544170
2752360 | 04 vierde verdieping | 1325677 | 0.0256528 | 4.57 | 3360 | Level: 04 vierde verdieping | 2651353
2752362 | 04 vierde verdieping | 440106 | 0.00841712 | 9 | 1102.47 | Level: 04 vierde verdieping | 880212
2800102 | 04 vierde verdieping | 368527 | 0.00702399 | 4.57 | 920 | Level: 04 vierde verdieping | 737054
2800380 | 04 vierde verdieping | 1242338 | 0.0240308 | 8.86743 | 3147.55 | Level: 04 vierde verdieping | 2484675
2800893 | 04 vierde verdieping | 357978 | 0.00681867 | 8.86743 | 893.108 | Level: 04 vierde verdieping | 715956
2801314 | 04 vierde verdieping | 399909 | 0.00763477 | 21.3 | 1000 | Level: 04 vierde verdieping | 799818
2801467 | 04 vierde verdieping | 1325677 | 0.0256528 | 4.57 | 3360 | Level: 04 vierde verdieping | 2651353
2801469 | 04 vierde verdieping | 440106 | 0.00841712 | 9 | 1102.47 | Level: 04 vierde verdieping | 880212
2801471 | 04 vierde verdieping | 368527 | 0.00702399 | 4.57 | 920 | Level: 04 vierde verdieping | 737054
2801473 | 04 vierde verdieping | 1242338 | 0.0240308 | 8.86743 | 3147.55 | Level: 04 vierde verdieping | 2484675
2801475 | 04 vierde verdieping | 357978 | 0.00681867 | 8.86743 | 893.108 | Level: 04 vierde verdieping | 715956
2801477 | 04 vierde verdieping | 1098157 | 0.0212247 | 21.3 | 2780 | Level: 04 vierde verdieping | 2196315
2831422 | 04 vierde verdieping | 517591 | 0.00992519 | 0 | 1300 | Level: 04 vierde verdieping | 1035183
2843328 | 03 derde verdieping | 2307146 | 0.044755 | 0 | 5862 | Level: 03 derde verdieping | 4614292
2974552 | 04 vierde verdieping | 1290728 | 0.0249726 | 8.86743 | 3270.91 | Level: 04 vierde verdieping | 2581457
2974554 | 04 vierde verdieping | 1515116 | 0.0293399 | 9 | 4169.75 | Level: 04 vierde verdieping | 3030233
2974556 | 04 vierde verdieping | 1616031 | 0.0313039 | 0 | 3944.83 | Level: 04 vierde verdieping | 3232061
2974585 | 04 vierde verdieping | 1361255 | 0.0263453 | 8.86743 | 3450.7 | Level: 04 vierde verdieping | 2722510
2974587 | 04 vierde verdieping | 1443544 | 0.0279469 | 9 | 3987.3 | Level: 04 vierde verdieping | 2887088
2974589 | 04 vierde verdieping | 1616031 | 0.0313039 | 0 | 3944.83 | Level: 04 vierde verdieping | 3232061
3046235 | 02 tweede verdieping | 510019 | 0.00977782 | 0 | 1280.7 | Level: 02 tweede verdieping | 1020038
3047146 | 02 tweede verdieping | 1392363 | 0.0269507 | 0 | 3530 | Level: 02 tweede verdieping | 2784726
3155228 | 01 eerste verdieping | 3933904 | 0.0764162 | 0 | 10009 | Level: 01 eerste verdieping | 7867807
3155230 | 01 eerste verdieping | 3933904 | 0.0764162 | 0 | 10009 | Level: 01 eerste verdieping | 7867807
3454714 | 04 vierde verdieping | 1541646 | 0.0298562 | 0 | 3910.56 | Level: 04 vierde verdieping | 3083292
3574589 | 03 derde verdieping | 1797426 | 0.0348344 | 0 | 4878 | Level: 03 derde verdieping | 3594851
3768877 | 02 tweede verdieping | 497703 | 0.0095381 | 0 | 1249.3 | Level: 02 tweede verdieping | 995406
3769063 | 03 derde verdieping | 497703 | 0.00953811 | 0 | 1249.3 | Level: 03 derde verdieping | 995406
3862565 | 01 eerste verdieping | 1670878 | 0.0323714 | 0 | 4240 | Level: 01 eerste verdieping | 3341756
3863877 | 01 eerste verdieping | 6260488 | 0.121698 | 0 | 15940 | Level: 01 eerste verdieping | 12520975
3864693 | 01 eerste verdieping | 1317831 | 0.0255001 | 0 | 3465 | Level: 01 eerste verdieping | 2635662
3865100 | 02 tweede verdieping | 1384518 | 0.026798 | 0 | 3510 | Level: 02 tweede verdieping | 2769035
3865655 | 02 tweede verdieping | 6268333 | 0.121851 | 0 | 15960 | Level: 02 tweede verdieping | 12536666
3865803 | 02 tweede verdieping | 1648980 | 0.0319452 | 0 | 4184.18 | Level: 02 tweede verdieping | 3297961
3867305 | 03 derde verdieping | 3098757 | 0.0601619 | 0 | 7880 | Level: 03 derde verdieping | 6197513
3868760 | 03 derde verdieping | 293004 | 0.0055541 | 0 | 727.475 | Level: 03 derde verdieping | 586009
3927398 | -1 kelder | 3686227 | 0.0715958 | 0 | 9778 | Level: -1 kelder | 7372453
4265517 | 03 derde verdieping | 1924097 | 0.0372997 | 0 | 4885.52 | Level: 03 derde verdieping | 3848194
4267286 | 03 derde verdieping | 1994707 | 0.038674 | 0 | 5065.52 | Level: 03 derde verdieping | 3989413
4467022 | 04 vierde verdieping | 2253876 | 0.0437182 | 0 | 5876.2 | Level: 04 vierde verdieping | 4507752
4756884 | 04 vierde verdieping | 1154344 | 0.0222808 | 0 | 2917.52 | Level: 04 vierde verdieping | 2308688
5177315 | 02 tweede verdieping | 1235945 | 0.0239064 | 0 | 3313.95 | Level: 02 tweede verdieping | 2471890
6214959 | 01 eerste verdieping | 182404 | 0.0034015 | 0 | 445.528 | Level: 01 eerste verdieping | 364808

# IfcBeam: 28_PBT_SF_staal_L-profiel:S355_L70x70x7 (8)
In: 03 derde verdieping
Type - Pset_BeamCommon - IsExternal: no; LoadBearing: yes
Type - Pset_ProductRequirements - Category: Structural Framing
Type - Pset_ReinforcementBarPitchOfBeam - Description: L70x70x7
Type - Pset_Pieters - Breedte: 70 mm; Hoogte: 70 mm; Codering - NL-SfB: 28.11; Omschrijving NL-SfB: hoofddraagconstructies - kolommen en liggers, kolom-/liggerconstructies; Materiaal: 00_PBT_MAT_staal_S355; Materiaalkwaliteit: S355; Description: L70x70x7
Classification: 28.11 hoofddraagconstructies - kolommen en liggers, kolom-/liggerconstructies (Uniformat); Material: 00_PBT_MAT_staal_S355
Pset_BeamCommon - Slope: 0 deg; Reference: 28_PBT_SF_staal_L-profiel:S355_L70x70x7
Pset_QuantityTakeOff - Reference: 28_PBT_SF_staal_L-profiel:S355_L70x70x7
Pset_ReinforcementBarPitchOfBeam - Reference: 28_PBT_SF_staal_L-profiel:S355_L70x70x7
Pset_Pieters - Bouwlaag: Level: 04 bk staal paradezaal binnendoos; Naamgeving element: 28_PBT_SF_staal_L-profiel: S355_L70x70x7; Fase: Nieuw
Name (28_PBT_SF_staal_L-profiel:S355_L70x70x7:...) | CrossSectionArea (mm2) | NetVolume (m3) | Span (mm) = Length (mm) | NetSurfaceArea (mm2)
2517668 | 917037 | 0.0063234 | 7029.23 | 1834075
2517966 | 975690 | 0.00672825 | 7460.06 | 1951380
2518248 | 805685 | 0.00555479 | 6211.28 | 1611370
2518288 | 735005 | 0.00506691 | 5692.1 | 1470010
2518442 | 917037 | 0.0063234 | 7029.22 | 1834075
2518446 | 975690 | 0.00672825 | 7460.06 | 1951380
2518456 | 805685 | 0.00555479 | 6211.28 | 1611370
2518460 | 735005 | 0.00506691 | 5692.1 | 1470010

# IfcBeam: 28_PBT_SF_staal_L-profiel_achtergelaste plaat:S355_L200x200x20, 28_PBT_SF_staal_L-profiel_achtergelaste plaat:S355_L200x200x20:2414814
In: 02 tweede verdieping
Type - PredefinedType: BEAM; Classification: 28.11 hoofddraagconstructies - kolommen en liggers, kolom-/liggerconstructies (Uniformat); Material: 00_PBT_MAT_staal_S355
Type - Pset_BeamCommon - IsExternal: no; LoadBearing: yes
Type - Pset_ProductRequirements - Category: Structural Framing
Type - Pset_ReinforcementBarPitchOfBeam - Description: L200x200x20 + plaat t=20
Type - Pset_Pieters - Breedte: 200 mm; Hoogte: 200 mm; Codering - NL-SfB: 28.11; Omschrijving NL-SfB: hoofddraagconstructies - kolommen en liggers, kolom-/liggerconstructies; Materiaal: 00_PBT_MAT_staal_S355; Materiaalkwaliteit: S355; Description: L200x200x20 + plaat t=20
Pset_BeamCommon - Slope: 0 deg; Reference: 28_PBT_SF_staal_L-profiel_achtergelaste plaat:S355_L200x200x20; Span: 1517.06 mm
Pset_QuantityTakeOff - Reference: 28_PBT_SF_staal_L-profiel_achtergelaste plaat:S355_L200x200x20
Pset_ReinforcementBarPitchOfBeam - Reference: 28_PBT_SF_staal_L-profiel_achtergelaste plaat:S355_L200x200x20
Pset_Pieters - Bouwlaag: Level: 02 tweede verdieping; Naamgeving element: 28_PBT_SF_staal_L-profiel_achtergelaste plaat: S355_L200x200x20; Fase: Nieuw
BaseQuantities - Length: 1517.06 mm; CrossSectionArea: 1201795 mm2; OuterSurfaceArea: 1183310 mm2; GrossSurfaceArea: 1198110 mm2; GrossVolume: 0.0112263 m3; NetVolume: 0.0228087 m3; NetSurfaceArea: 2403590 mm2

# IfcBeam: 28_PBT_SF_staal_UNP-profiel:S355_UNP140 (20)
In: 02 tweede verdieping
Type - Pset_BeamCommon - IsExternal: no; LoadBearing: yes
Type - Pset_ProductRequirements - Category: Structural Framing
Type - Pset_ReinforcementBarPitchOfBeam - Description: UNP140
Type - Pset_Pieters - Breedte: 60 mm; Hoogte: 140 mm; Codering - NL-SfB: 28.11; Omschrijving NL-SfB: hoofddraagconstructies - kolommen en liggers, kolom-/liggerconstructies; Materiaal: 00_PBT_MAT_staal_S355; Materiaalkwaliteit: S355; Description: UNP140
Classification: 28.11 hoofddraagconstructies - kolommen en liggers, kolom-/liggerconstructies (Uniformat); Material: 00_PBT_MAT_staal_S355
Pset_BeamCommon - Slope: 0 deg; Reference: 28_PBT_SF_staal_UNP-profiel:S355_UNP140
Pset_QuantityTakeOff - Reference: 28_PBT_SF_staal_UNP-profiel:S355_UNP140
Pset_ReinforcementBarPitchOfBeam - Reference: 28_PBT_SF_staal_UNP-profiel:S355_UNP140
Pset_Pieters - Bouwlaag: Level: 02 tweede verdieping; Naamgeving element: 28_PBT_SF_staal_UNP-profiel: S355_UNP140; Fase: Nieuw
Name (28_PBT_SF_staal_UNP-profiel:S355_UNP140:...) | CrossSectionArea (mm2) | NetVolume (m3) | Span (mm) = Length (mm) | NetSurfaceArea (mm2)
2362403 | 832706 | 0.0069461 | 3410 | 1665412
2362617 | 1001697 | 0.00835921 | 4103.73 | 2003394
2362644 | 832706 | 0.0069461 | 3410 | 1665412
2362756 | 1151819 | 0.00961454 | 4720 | 2303639
2400198 | 1151819 | 0.00961454 | 4720 | 2303639
2400218 | 1151819 | 0.00961454 | 4720 | 2303639
2400238 | 1005661 | 0.00839235 | 4120 | 2011321
2400939 | 138452 | 0.00114071 | 560 | 276904
2401383 | 314330 | 0.00261141 | 1282 | 628659
3467813 | 1224868 | 0.0102254 | 5019.87 | 2449736
6362503 | 2531798 | 0.021154 | 10385 | 5063597 | Pset_Pieters - Dragend/niet dragend: yes; In/uitwendig: no
6377401 | 3959530 | 0.0330928 | 16246 | 7919060 | Pset_Pieters - Dragend/niet dragend: yes; In/uitwendig: no
6377729 | 2531798 | 0.021154 | 10385 | 5063597 | Pset_Pieters - Dragend/niet dragend: yes; In/uitwendig: no
6377778 | 403243 | 0.0033549 | 1647 | 806486 | Pset_Pieters - Dragend/niet dragend: yes; In/uitwendig: no
6377922 | 403243 | 0.0033549 | 1647 | 806486 | Pset_Pieters - Dragend/niet dragend: yes; In/uitwendig: no
6488270 | 313593 | 0.00260525 | 1278.98 | 627186 | Pset_Pieters - Dragend/niet dragend: yes; In/uitwendig: no
6488287 | 726162 | 0.00605524 | 2973.5 | 1452325 | Pset_Pieters - Dragend/niet dragend: yes; In/uitwendig: no
6488304 | 4193238 | 0.035046 | 17205.9 | 8386476 | Pset_Pieters - Dragend/niet dragend: yes; In/uitwendig: no
6488320 | 726162 | 0.00605524 | 2973.5 | 1452325 | Pset_Pieters - Dragend/niet dragend: yes; In/uitwendig: no
6488338 | 2037.01 | 0.00223164 | 1095.56 | 537828 | Pset_Pieters - Dragend/niet dragend: yes; In/uitwendig: no; BaseQuantities - OuterSurfaceArea: 533754 mm2; GrossVolume: 2231668 m3; GrossSurfaceArea: 537828 mm2

# IfcBeam: 28_PBT_SF_staal_UNP-profiel:S355_UNP180 (14)
Type - Pset_BeamCommon - IsExternal: no; LoadBearing: yes
Type - Pset_ProductRequirements - Category: Structural Framing
Type - Pset_ReinforcementBarPitchOfBeam - Description: UNP180
Type - Pset_Pieters - Breedte: 70 mm; Hoogte: 180 mm; Codering - NL-SfB: 28.11; Omschrijving NL-SfB: hoofddraagconstructies - kolommen en liggers, kolom-/liggerconstructies; Materiaal: 00_PBT_MAT_staal_S355; Materiaalkwaliteit: S355; Description: UNP180
Classification: 28.11 hoofddraagconstructies - kolommen en liggers, kolom-/liggerconstructies (Uniformat); Material: 00_PBT_MAT_staal_S355
Pset_BeamCommon - Slope: 0 deg; Reference: 28_PBT_SF_staal_UNP-profiel:S355_UNP180
Pset_QuantityTakeOff - Reference: 28_PBT_SF_staal_UNP-profiel:S355_UNP180
Pset_ReinforcementBarPitchOfBeam - Reference: 28_PBT_SF_staal_UNP-profiel:S355_UNP180
Pset_Pieters - Naamgeving element: 28_PBT_SF_staal_UNP-profiel: S355_UNP180; Fase: Nieuw
Name (28_PBT_SF_staal_UNP-profiel:S355_UNP180:...) | In | CrossSectionArea (mm2) | NetVolume (m3) | Span (mm) = Length (mm) | Bouwlaag | NetSurfaceArea (mm2)
3843659 | 06 zesde verdieping | 3829639 | 0.0355109 | 12698 | Level: 06 zesde verdieping_bk staal dakopbouw | 7659277
3844513 | 06 zesde verdieping | 3213620 | 0.0297946 | 10654 | Level: 06 zesde verdieping_bk staal dakopbouw | 6427239
3844619 | 06 zesde verdieping | 3213620 | 0.0297946 | 10654 | Level: 06 zesde verdieping_bk staal dakopbouw | 6427239
3844676 | 06 zesde verdieping | 3829639 | 0.0355109 | 12698 | Level: 06 zesde verdieping_bk staal dakopbouw | 7659277
3844734 | 04 vierde verdieping | 1395143 | 0.0129202 | 4620 | Level: 05 vijfde verdieping_bk staal dakopbouw | 2790285
3844737 | 04 vierde verdieping | 7787704 | 0.0722396 | 25831.4 | Level: 05 vijfde verdieping_bk staal dakopbouw | 15575407
3844739 | 04 vierde verdieping | 5153271 | 0.0477935 | 17090 | Level: 05 vijfde verdieping_bk staal dakopbouw | 10306543
3844741 | 04 vierde verdieping | 1395143 | 0.0129202 | 4620 | Level: 05 vijfde verdieping_bk staal dakopbouw | 2790285
3845132 | 04 vierde verdieping | 1395143 | 0.0129202 | 4620 | Level: 05 vijfde verdieping_bk staal dakopbouw | 2790285
4235399 | 06 zesde verdieping | 3417498 | 0.0316865 | 11330.5 | Level: 06 zesde verdieping_bk staal dakopbouw | 6834996
4235459 | 06 zesde verdieping | 3417498 | 0.0316865 | 11330.5 | Level: 06 zesde verdieping_bk staal dakopbouw | 6834996
4236741 | 06 zesde verdieping | 3829639 | 0.0355109 | 12698 | Level: 06 zesde verdieping_bk staal dakopbouw | 7659277
4236757 | 06 zesde verdieping | 3829639 | 0.0355109 | 12698 | Level: 06 zesde verdieping_bk staal dakopbouw | 7659277
4314383 | 04 vierde verdieping | 2275581 | 0.0210902 | 7541.42 | Level: 05 vijfde verdieping_bk staal dakopbouw | 4551161

# IfcBeam: 28_PBT_SF_staal_UNP-profiel:S355_UNP200 (2)
In: 01 eerste verdieping
Type - Pset_BeamCommon - IsExternal: no; LoadBearing: yes
Type - Pset_ProductRequirements - Category: Structural Framing
Type - Pset_ReinforcementBarPitchOfBeam - Description: UNP200
Type - Pset_Pieters - Breedte: 75 mm; Hoogte: 200 mm; Codering - NL-SfB: 28.11; Omschrijving NL-SfB: hoofddraagconstructies - kolommen en liggers, kolom-/liggerconstructies; Materiaal: 00_PBT_MAT_staal_S355; Materiaalkwaliteit: S355; Description: UNP200
Classification: 28.11 hoofddraagconstructies - kolommen en liggers, kolom-/liggerconstructies (Uniformat); Material: 00_PBT_MAT_staal_S355
Pset_BeamCommon - Slope: 0 deg; Reference: 28_PBT_SF_staal_UNP-profiel:S355_UNP200
Pset_QuantityTakeOff - Reference: 28_PBT_SF_staal_UNP-profiel:S355_UNP200
Pset_ReinforcementBarPitchOfBeam - Reference: 28_PBT_SF_staal_UNP-profiel:S355_UNP200
Pset_Pieters - Bouwlaag: Level: 01 eerste verdieping; Naamgeving element: 28_PBT_SF_staal_UNP-profiel: S355_UNP200; Fase: Nieuw
Name (28_PBT_SF_staal_UNP-profiel:S355_UNP200:...) | CrossSectionArea (mm2) | NetVolume (m3) | Span (mm) = Length (mm) | NetSurfaceArea (mm2)
3756775 | 991779 | 0.0096364 | 2994.07 | 1983558
3757448 | 989550 | 0.00961467 | 2987.32 | 1979099

# IfcBeam: 28_PBT_SF_staal_UNP-profiel_met_ingelaste_strip (void):S355_UNP400 + ingelaste strip_d=15 (12)
Type - PredefinedType: BEAM; Classification: 28.11 hoofddraagconstructies - kolommen en liggers, kolom-/liggerconstructies (Uniformat); Material: 00_PBT_MAT_staal_S355
Type - Pset_BeamCommon - IsExternal: no; LoadBearing: yes
Type - Pset_ProductRequirements - Category: Structural Framing
Type - Pset_ReinforcementBarPitchOfBeam - Description: UNP400 + ingelaste strip d=15
Type - Pset_Pieters - Breedte: 110 mm; Hoogte: 400 mm; Codering - NL-SfB: 28.11; Omschrijving NL-SfB: hoofddraagconstructies - kolommen en liggers, kolom-/liggerconstructies; Materiaal: 00_PBT_MAT_staal_S355; Materiaalkwaliteit: S355; Description: UNP400 + ingelaste strip d=15
Pset_BeamCommon - Slope: 0 deg; Reference: 28_PBT_SF_staal_UNP-profiel_met_ingelaste_strip (void):S355_UNP400 + ingelaste strip_d=15
Pset_QuantityTakeOff - Reference: 28_PBT_SF_staal_UNP-profiel_met_ingelaste_strip (void):S355_UNP400 + ingelaste strip_d=15
Pset_ReinforcementBarPitchOfBeam - Reference: 28_PBT_SF_staal_UNP-profiel_met_ingelaste_strip (void):S355_UNP400 + ingelaste strip_d=15
Pset_Pieters - Naamgeving element: 28_PBT_SF_staal_UNP-profiel_met_ingelaste_strip (void): S355_UNP400 + ingelaste strip_d=15; Fase: Nieuw
Name (28_PBT_SF_staal_UNP-profiel_met_ingelaste_strip (void):S355_UNP400 + ingelaste strip_d=15:...) | In | Span (mm) = Length (mm) | Bouwlaag | CrossSectionArea (mm2) | OuterSurfaceArea (mm2) | GrossSurfaceArea (mm2) | GrossVolume (m3) | NetVolume (m3) | NetSurfaceArea (mm2)
2315803 | 01 eerste verdieping | 5686.26 | Level: 01 eerste verdieping | 4876942 | 6759956 | 6778277 | 0.0520888 | 0.0730702 | 9753885
2317068 | 01 eerste verdieping | 5403.92 | Level: 01 eerste verdieping | 4648723 | 2820844 | 2828224 | 0.0199405 | 0.069442 | 9270846
2317142 | 01 eerste verdieping | 5460.14 | Level: 01 eerste verdieping | 4696820 | 2850195 | 2857575 | 0.0201479 | 0.0701645 | 9367040
2317144 | 01 eerste verdieping | 5466.83 | Level: 01 eerste verdieping | 3912891 | 1287686 | 1295066 | 0.00910261 | 0.0591805 | 7812483
2317178 | 01 eerste verdieping | 5495.44 | Level: 01 eerste verdieping | 3937366 | 1302622 | 1310002 | 0.00920819 | 0.0595481 | 7861432
2317180 | 01 eerste verdieping | 5497.98 | Level: 01 eerste verdieping | 4729186 | 2869946 | 2877326 | 0.0202875 | 0.0706507 | 9431773
2326049 | 02 tweede verdieping | 6695.63 | Level: 02 tweede verdieping | 5740366 | 7959914 | 7978235 | 0.0613351 | 0.0860408 | 11480731
2326051 | 02 tweede verdieping | 6705.31 | Level: 02 tweede verdieping | 5761952 | 3500173 | 3507553 | 0.0247426 | 0.0861653 | 11497304
2326053 | 02 tweede verdieping | 6797.87 | Level: 02 tweede verdieping | 5841129 | 3548489 | 3555869 | 0.0250841 | 0.0873547 | 11655657
2326055 | 02 tweede verdieping | 6800.92 | Level: 02 tweede verdieping | 5843740 | 3550083 | 3557463 | 0.0250954 | 0.087394 | 11660879
2326057 | 02 tweede verdieping | 6789.35 | Level: 02 tweede verdieping | 5833842 | 3544043 | 3551423 | 0.0250527 | 0.0872453 | 11641083
2326059 | 02 tweede verdieping | 6784.94 | Level: 02 tweede verdieping | 5830069 | 3541740 | 3549120 | 0.0250364 | 0.0871886 | 11633538

# IfcBeam: 28_PBT_SF_staal_aangelaste plaat trapboom willemsanker:plaat (4)
Type - Pset_BeamCommon - IsExternal: no; LoadBearing: yes; Span: 160 mm
Type - Pset_ProductRequirements - Category: Structural Framing
Type - Pset_ReinforcementBarPitchOfBeam - Description: stalen oplegschoen
Type - Pset_Pieters - Breedte: 25 mm; Hoogte: 266 mm; Materiaal: 00_PBT_MAT_staal_S355; Materiaalkwaliteit: S355; Description: stalen oplegschoen; Type Comments: stalen oplegschoen t.b.v. glijdende oplegging in 1 horizontale richting
Material: 00_PBT_MAT_staal_S355
BaseQuantities - Length: 25 mm; CrossSectionArea: 26523.6 mm2; OuterSurfaceArea: 20504.1 mm2; GrossVolume: 663089 m3; NetVolume: 0.000663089 m3; GrossSurfaceArea: 71195.1 mm2; NetSurfaceArea: 73552 mm2
Pset_BeamCommon - Reference: 28_PBT_SF_staal_aangelaste plaat trapboom willemsanker:plaat
Pset_QuantityTakeOff - Reference: 28_PBT_SF_staal_aangelaste plaat trapboom willemsanker:plaat
Pset_ReinforcementBarPitchOfBeam - Reference: 28_PBT_SF_staal_aangelaste plaat trapboom willemsanker:plaat
Pset_Pieters - Naamgeving element: 28_PBT_SF_staal_aangelaste plaat trapboom willemsanker: plaat; Fase: Nieuw
Name (28_PBT_SF_staal_aangelaste plaat trapboom willemsanker:plaat:...) | In
6322598 | 01 eerste verdieping
6324470 | 01 eerste verdieping
6324694 | 00 begane grond
6324822 | 00 begane grond

# IfcBeam: 28_PBT_SF_staal_baluster balkon:baluster HEA100 (28)
In: 02 tweede verdieping
Type - PredefinedType: BEAM; Material: 00_PBT_MAT_staal_S355
Type - Pset_BeamCommon - IsExternal: no; LoadBearing: yes
Type - Pset_ProductRequirements - Category: Structural Framing
Type - Pset_ReinforcementBarPitchOfBeam - Description: baluster HEA100
Type - Pset_Pieters - Materiaal: 00_PBT_MAT_staal_S355; Description: baluster HEA100; Type Comments: h.o.h. 1000mm
Pset_BeamCommon - Reference: 28_PBT_SF_staal_baluster balkon:baluster HEA100
Pset_QuantityTakeOff - Reference: 28_PBT_SF_staal_baluster balkon:baluster HEA100
Pset_ReinforcementBarPitchOfBeam - Reference: 28_PBT_SF_staal_baluster balkon:baluster HEA100
Pset_Pieters - Dragend/niet dragend: yes; In/uitwendig: no; Naamgeving element: 28_PBT_SF_staal_baluster balkon: baluster HEA100; Fase: Nieuw
BaseQuantities - CrossSectionArea: 336184 mm2; NetVolume: 0.00256048 m3; NetSurfaceArea: 672367 mm2
Name (28_PBT_SF_staal_baluster balkon:baluster HEA100:...)
6480655 | BaseQuantities - Length: 133 mm; OuterSurfaceArea: 40432 mm2; GrossSurfaceArea: 43792 mm2; GrossVolume: 0.00022344 m3
6489355
6489550 | BaseQuantities - Length: 133 mm; OuterSurfaceArea: 40432 mm2; GrossSurfaceArea: 43792 mm2; GrossVolume: 0.00022344 m3
6489570
6489571
6489584
6489585
6489586
6489587
6489873
6489881
6489891
6490118
6490152
6490245
6490246
6490247
6490248
6490249
6490250
6490251
6490252
6490253
6490254
6490255
6490256
6490257
6490258

# IfcBeam: 28_PBT_SF_staal_buis:S355_B152.4x10, 28_PBT_SF_staal_buis:S355_B152.4x10:3739971
In: 02 tweede verdieping
Type - Pset_BeamCommon - IsExternal: no; LoadBearing: yes
Type - Pset_ProductRequirements - Category: Structural Framing
Type - Pset_ReinforcementBarPitchOfBeam - Description: B152.4x10
Type - Pset_Pieters - Diameter: 152.4 mm; Codering - NL-SfB: 28.11; Omschrijving NL-SfB: hoofddraagconstructies - kolommen en liggers, kolom-/liggerconstructies; Materiaal: 00_PBT_MAT_staal_S355; Materiaalkwaliteit: S355; Description: B152.4x10
Classification: 28.11 hoofddraagconstructies - kolommen en liggers, kolom-/liggerconstructies (Uniformat); Material: 00_PBT_MAT_staal_S355
BaseQuantities - CrossSectionArea: 1536830 mm2; NetVolume: 0.0153192 m3; Length: 3600 mm; NetSurfaceArea: 3073661 mm2
Pset_BeamCommon - Reference: 28_PBT_SF_staal_buis:S355_B152.4x10; Span: 3600 mm; Slope: 67.1188 deg
Pset_QuantityTakeOff - Reference: 28_PBT_SF_staal_buis:S355_B152.4x10
Pset_ReinforcementBarPitchOfBeam - Reference: 28_PBT_SF_staal_buis:S355_B152.4x10
Pset_Pieters - Bouwlaag: Level: 02 tweede verdieping; Naamgeving element: 28_PBT_SF_staal_buis: S355_B152.4x10; Fase: Nieuw; Comments: wanddikte ter indicatie

# IfcBeam: 28_PBT_SF_staal_ingelaste schotten roldeur expeditie:schotten, 28_PBT_SF_staal_ingelaste schotten roldeur expeditie:schotten:6018711
In: 01 eerste verdieping
Type - PredefinedType: BEAM; Material: 00_PBT_MAT_staal_S355
Type - Pset_BeamCommon - IsExternal: no; LoadBearing: yes
Type - Pset_ProductRequirements - Category: Structural Framing
Type - Pset_ReinforcementBarPitchOfBeam - Description: ingelaste schotten
Type - Pset_Pieters - Materiaal: 00_PBT_MAT_staal_S355; Materiaalkwaliteit: S355; Description: ingelaste schotten
Pset_BeamCommon - Slope: 0 deg; Reference: 28_PBT_SF_staal_ingelaste schotten roldeur expeditie:schotten
Pset_QuantityTakeOff - Reference: 28_PBT_SF_staal_ingelaste schotten roldeur expeditie:schotten
Pset_ReinforcementBarPitchOfBeam - Reference: 28_PBT_SF_staal_ingelaste schotten roldeur expeditie:schotten
Pset_Pieters - Bouwlaag: Level: 01 eerste verdieping; Naamgeving element: 28_PBT_SF_staal_ingelaste schotten roldeur expeditie: schotten; Fase: Nieuw
BaseQuantities - Length: 205 mm; CrossSectionArea: 485775 mm2; OuterSurfaceArea: 129150 mm2; GrossSurfaceArea: 138150 mm2; GrossVolume: 0.0009225 m3; NetVolume: 0.0066825 m3; NetSurfaceArea: 971550 mm2

# IfcBeam: 28_PBT_SF_staal_koker:S235_K100x100x6.3 (6)
In: 06 zesde verdieping
Type - Pset_BeamCommon - IsExternal: no; LoadBearing: yes
Type - Pset_ProductRequirements - Category: Structural Framing
Type - Pset_ReinforcementBarPitchOfBeam - Description: #100x100x6.3
Type - Pset_Pieters - Breedte: 100 mm; Hoogte: 100 mm; Codering - NL-SfB: 28.11; Omschrijving NL-SfB: hoofddraagconstructies - kolommen en liggers, kolom-/liggerconstructies; Materiaal: 00_PBT_MAT_staal_S235; Materiaalkwaliteit: S235; Description: #100x100x6.3
Classification: 28.11 hoofddraagconstructies - kolommen en liggers, kolom-/liggerconstructies (Uniformat); Material: 00_PBT_MAT_staal_S235
BaseQuantities - Length: 11989.7 mm; CrossSectionArea: 2318.62 mm2; OuterSurfaceArea: 8663287 mm2; GrossVolume: 27799546 m3; NetVolume: 0.0277998 m3; GrossSurfaceArea: 4606001 mm2; NetSurfaceArea: 8667924 mm2
Pset_BeamCommon - Slope: 0 deg; Reference: 28_PBT_SF_staal_koker:S235_K100x100x6.3; Span: 11989.7 mm
Pset_QuantityTakeOff - Reference: 28_PBT_SF_staal_koker:S235_K100x100x6.3
Pset_ReinforcementBarPitchOfBeam - Reference: 28_PBT_SF_staal_koker:S235_K100x100x6.3
Pset_Pieters - Bouwlaag: Level: 06 zesde verdieping; Naamgeving element: 28_PBT_SF_staal_koker: S235_K100x100x6.3; Fase: Nieuw
Name (28_PBT_SF_staal_koker:S235_K100x100x6.3:...)
2984234
2984660
2984685
2984747
2984749
2984766

# IfcBeam: 28_PBT_SF_staal_koker:S235_K100x200x8 (8)
In: 03 derde verdieping
Type - Pset_BeamCommon - IsExternal: no; LoadBearing: yes
Type - Pset_ProductRequirements - Category: Structural Framing
Type - Pset_ReinforcementBarPitchOfBeam - Description: K200x100x8
Type - Pset_Pieters - Breedte: 100 mm; Hoogte: 200 mm; Codering - NL-SfB: 28.11; Omschrijving NL-SfB: hoofddraagconstructies - kolommen en liggers, kolom-/liggerconstructies; Materiaal: 00_PBT_MAT_staal_S235; Materiaalkwaliteit: S235; Description: K200x100x8
Classification: 28.11 hoofddraagconstructies - kolommen en liggers, kolom-/liggerconstructies (Uniformat); Material: 00_PBT_MAT_staal_S235
BaseQuantities - CrossSectionArea: 4475.27 mm2
Pset_BeamCommon - Slope: 0 deg; Reference: 28_PBT_SF_staal_koker:S235_K100x200x8
Pset_QuantityTakeOff - Reference: 28_PBT_SF_staal_koker:S235_K100x200x8
Pset_ReinforcementBarPitchOfBeam - Reference: 28_PBT_SF_staal_koker:S235_K100x200x8
Pset_Pieters - Bouwlaag: Level: 03 derde verdieping; Naamgeving element: 28_PBT_SF_staal_koker: S235_K100x200x8; Fase: Nieuw
Name (28_PBT_SF_staal_koker:S235_K100x200x8:...) | Length (mm) = Span (mm) | OuterSurfaceArea (mm2) | GrossVolume (m3) | NetVolume (m3) | GrossSurfaceArea (mm2) | NetSurfaceArea (mm2)
2449094 | 4802.48 | 5290722 | 21492399 | 0.0214926 | 2791501 | 5299673
3240918 | 2285 | 2517302 | 10225985 | 0.0102261 | 1332875 | 2526252
3240920 | 2340 | 2577893 | 10472125 | 0.0104722 | 1364742 | 2586844
3965333 | 1615 | 1779187 | 7227556 | 0.00722763 | 944679 | 1788137
3965335 | 1670.08 | 1839870 | 7474069 | 0.00747414 | 976594 | 1848821
3965368 | 905 | 997006 | 4050117 | 0.00405016 | 533306 | 1005956
3965370 | 939.229 | 1034714 | 4203300 | 0.00420334 | 553138 | 1043665
4254412 | 8014.96 | 8829791 | 35869089 | 0.0358694 | 4652804 | 8838742

# IfcBeam: 28_PBT_SF_staal_koker:S235_K120x120x6.3 (4)
Type - Pset_BeamCommon - IsExternal: no; LoadBearing: yes
Type - Pset_ProductRequirements - Category: Structural Framing
Type - Pset_ReinforcementBarPitchOfBeam - Description: #120x120x6.3
Type - Pset_Pieters - Breedte: 120 mm; Hoogte: 120 mm; Codering - NL-SfB: 28.11; Omschrijving NL-SfB: hoofddraagconstructies - kolommen en liggers, kolom-/liggerconstructies; Materiaal: 00_PBT_MAT_staal_S235; Materiaalkwaliteit: S235; Description: #120x120x6.3
Classification: 28.11 hoofddraagconstructies - kolommen en liggers, kolom-/liggerconstructies (Uniformat); Material: 00_PBT_MAT_staal_S235
BaseQuantities - CrossSectionArea: 2822.61 mm2
Pset_BeamCommon - Slope: 0 deg; Reference: 28_PBT_SF_staal_koker:S235_K120x120x6.3
Pset_QuantityTakeOff - Reference: 28_PBT_SF_staal_koker:S235_K120x120x6.3
Pset_ReinforcementBarPitchOfBeam - Reference: 28_PBT_SF_staal_koker:S235_K120x120x6.3
Pset_Pieters - Naamgeving element: 28_PBT_SF_staal_koker: S235_K120x120x6.3; Fase: Nieuw
Name (28_PBT_SF_staal_koker:S235_K120x120x6.3:...) | In | Length (mm) = Span (mm) | OuterSurfaceArea (mm2) | GrossVolume (m3) | NetVolume (m3) | Bouwlaag | GrossSurfaceArea (mm2) | NetSurfaceArea (mm2)
5868452 | 00 begane grond | 1690.83 | 1492260 | 4772564 | 0.00477261 | Level: 00 begane grond | 789812 | 1497905
5869530 | 00 begane grond | 1755 | 1548893 | 4953689 | 0.00495373 | Level: 00 begane grond | 819572 | 1554538
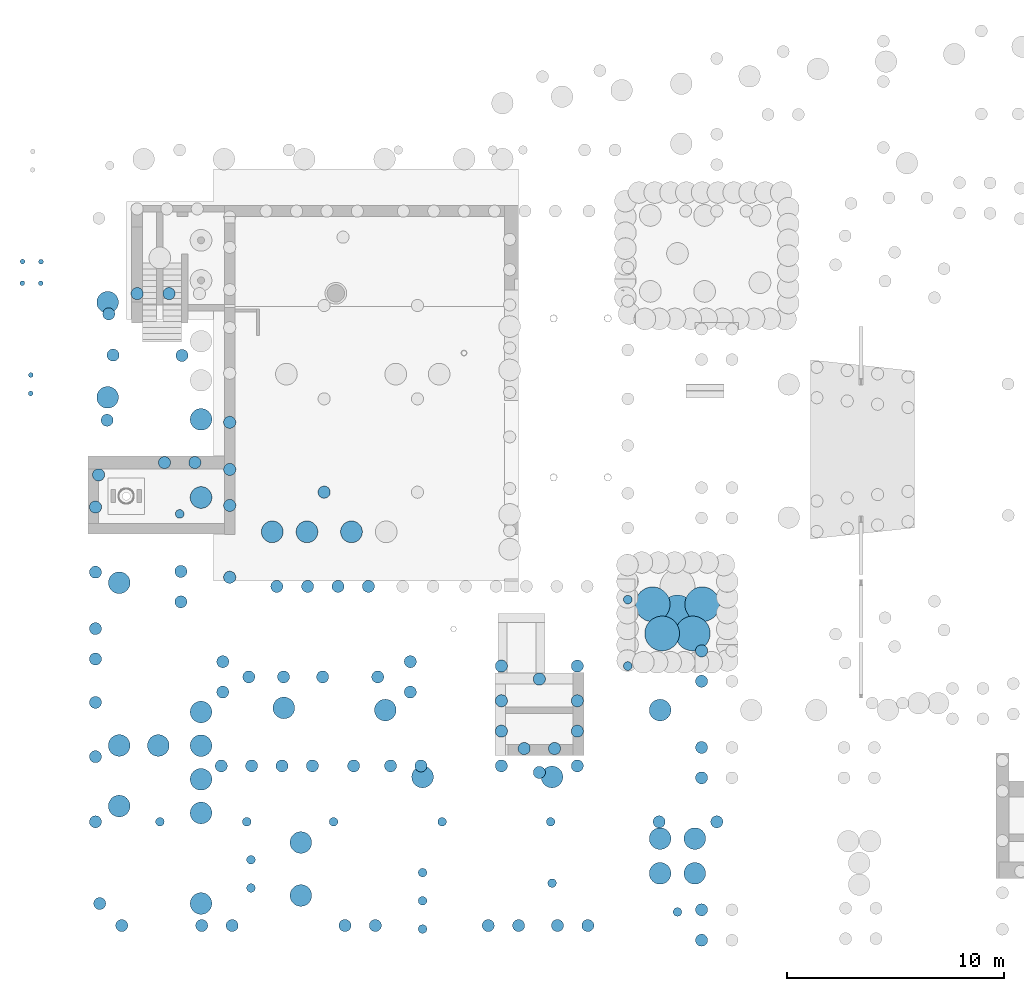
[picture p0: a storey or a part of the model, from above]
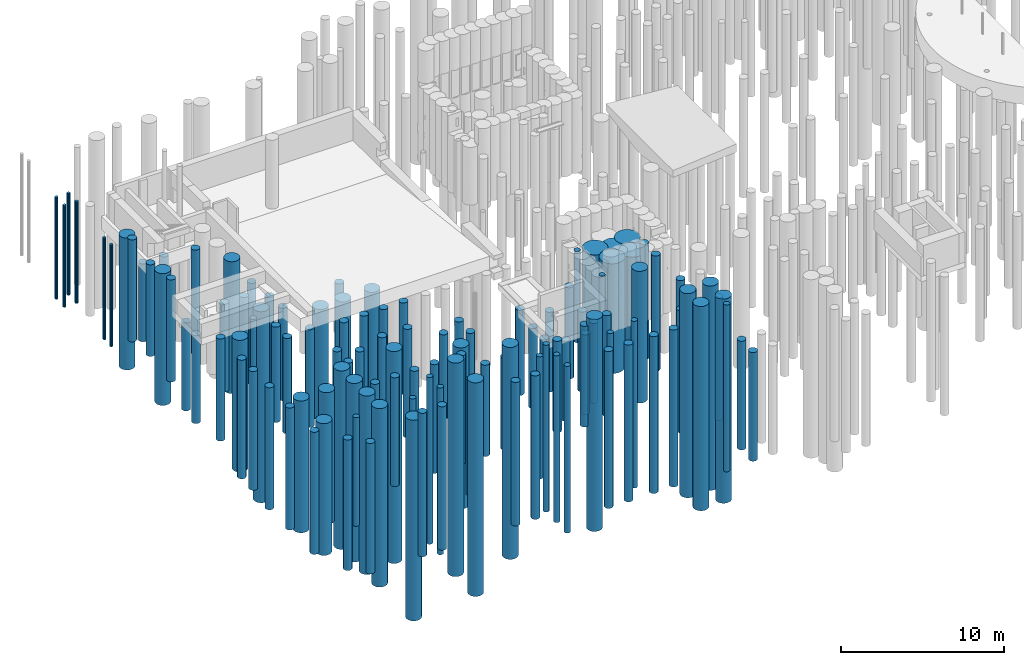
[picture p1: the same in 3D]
Properties of the parts of a building model (IFC2X3), part 7 of 18

# IfcBeam: 28_PBT_SF_staal_koker:S235_K120x120x6.3 (4)
Name (28_PBT_SF_staal_koker:S235_K120x120x6.3:...) | In | Length (mm) = Span (mm) | OuterSurfaceArea (mm2) | GrossVolume (m3) | NetVolume (m3) | Bouwlaag | GrossSurfaceArea (mm2) | NetSurfaceArea (mm2)
5870344 | 01 eerste verdieping | 1735 | 1531242 | 4897236 | 0.00489728 | Level: 01 eerste verdieping | 810297 | 1536887
5871057 | 01 eerste verdieping | 1735 | 1531242 | 4897236 | 0.00489728 | Level: 01 eerste verdieping | 810297 | 1536887

# IfcBeam: 28_PBT_SF_staal_koker:S235_K40x80x5 (2)
In: 06 zesde verdieping
Type - Pset_BeamCommon - IsExternal: no; LoadBearing: yes
Type - Pset_ProductRequirements - Category: Structural Framing
Type - Pset_ReinforcementBarPitchOfBeam - Description: K80x40x5
Type - Pset_Pieters - Breedte: 80 mm; Hoogte: 40 mm; Codering - NL-SfB: 28.11; Omschrijving NL-SfB: hoofddraagconstructies - kolommen en liggers, kolom-/liggerconstructies; Materiaal: 00_PBT_MAT_staal_S235; Materiaalkwaliteit: S235; Description: K80x40x5
Classification: 28.11 hoofddraagconstructies - kolommen en liggers, kolom-/liggerconstructies (Uniformat); Material: 00_PBT_MAT_staal_S235
BaseQuantities - Length: 12426.3 mm; CrossSectionArea: 1073.15 mm2; OuterSurfaceArea: 5200901 mm2; GrossVolume: 13335340 m3; NetVolume: 0.0133355 m3; GrossSurfaceArea: 2824456 mm2; NetSurfaceArea: 5203048 mm2
Pset_BeamCommon - Slope: 0 deg; Reference: 28_PBT_SF_staal_koker:S235_K40x80x5; Span: 12426.3 mm
Pset_QuantityTakeOff - Reference: 28_PBT_SF_staal_koker:S235_K40x80x5
Pset_ReinforcementBarPitchOfBeam - Reference: 28_PBT_SF_staal_koker:S235_K40x80x5
Pset_Pieters - Bouwlaag: Level: 06 zesde verdieping; Naamgeving element: 28_PBT_SF_staal_koker: S235_K40x80x5; Fase: Nieuw
Name (28_PBT_SF_staal_koker:S235_K40x80x5:...)
2984818
2984903

# IfcBeam: 28_PBT_SF_staal_koker:S235_K50x90x5 (16)
In: 02 tweede verdieping
Type - Pset_BeamCommon - IsExternal: no; LoadBearing: yes
Type - Pset_ProductRequirements - Category: Structural Framing
Type - Pset_ReinforcementBarPitchOfBeam - Description: #90x50x5
Type - Pset_Pieters - Breedte: 90 mm; Hoogte: 50 mm; Codering - NL-SfB: 28.11; Omschrijving NL-SfB: hoofddraagconstructies - kolommen en liggers, kolom-/liggerconstructies; Materiaal: 00_PBT_MAT_staal_S235; Materiaalkwaliteit: S235; Description: #90x50x5
Classification: 28.11 hoofddraagconstructies - kolommen en liggers, kolom-/liggerconstructies (Uniformat); Material: 00_PBT_MAT_staal_S235
BaseQuantities - CrossSectionArea: 1273.15 mm2
Pset_BeamCommon - Slope: 0 deg; Reference: 28_PBT_SF_staal_koker:S235_K50x90x5
Pset_QuantityTakeOff - Reference: 28_PBT_SF_staal_koker:S235_K50x90x5
Pset_ReinforcementBarPitchOfBeam - Reference: 28_PBT_SF_staal_koker:S235_K50x90x5
Pset_Pieters - Bouwlaag: Level: 02 tweede verdieping; Naamgeving element: 28_PBT_SF_staal_koker: S235_K50x90x5; Fase: Nieuw
Name (28_PBT_SF_staal_koker:S235_K50x90x5:...) | Length (mm) | OuterSurfaceArea (mm2) | GrossVolume (m3) | NetVolume (m3) | Span (mm) | GrossSurfaceArea (mm2) | NetSurfaceArea (mm2)
3630729 | 1837 | 915818 | 2338783 | 0.00233881 | 1837 | 493253 | 918364
3630969 | 1837 | 915818 | 2338783 | 0.00233881 | 1907 | 493253 | 918364
3631001 | 1837 | 915818 | 2338783 | 0.00233881 | 1907 | 493253 | 918364
3631044 | 1837 | 915818 | 2338783 | 0.00233881 | 1907 | 493253 | 918364
3631165 | 1837 | 915818 | 2338785 | 0.00233881 | 1837 | 493253 | 918365
3631167 | 1837 | 915818 | 2338785 | 0.00233881 | 1907 | 493253 | 918365
3631169 | 1837 | 915818 | 2338785 | 0.00233881 | 1907 | 493253 | 918365
3631171 | 1837 | 915818 | 2338785 | 0.00233881 | 1907 | 493253 | 918365
3816344 | 1327 | 661564 | 1689478 | 0.0016895 | 1327 | 357020 | 664110
3816531 | 1327 | 661564 | 1689478 | 0.0016895 | 1327 | 357020 | 664110
3816652 | 1327 | 661564 | 1689478 | 0.0016895 | 1327 | 357020 | 664110
3816654 | 1327 | 661564 | 1689478 | 0.0016895 | 1327 | 357020 | 664110
3816671 | 1326 | 661065 | 1688205 | 0.00168822 | 1326 | 356753 | 663611
3816673 | 1326 | 661065 | 1688205 | 0.00168822 | 1326 | 356753 | 663611
3816690 | 1327 | 661564 | 1689478 | 0.0016895 | 1327 | 357020 | 664110
3816692 | 1327 | 661564 | 1689478 | 0.0016895 | 1327 | 357020 | 664110

# IfcBeam: 28_PBT_SF_staal_koker:S235_K80x120x6.3 (58)
Type - Pset_BeamCommon - IsExternal: no; LoadBearing: yes
Type - Pset_ProductRequirements - Category: Structural Framing
Type - Pset_ReinforcementBarPitchOfBeam - Description: #120x80x6.3
Type - Pset_Pieters - Breedte: 120 mm; Hoogte: 80 mm; Codering - NL-SfB: 28.11; Omschrijving NL-SfB: hoofddraagconstructies - kolommen en liggers, kolom-/liggerconstructies; Materiaal: 00_PBT_MAT_staal_S235; Materiaalkwaliteit: S235; Description: #120x80x6.3
Classification: 28.11 hoofddraagconstructies - kolommen en liggers, kolom-/liggerconstructies (Uniformat); Material: 00_PBT_MAT_staal_S235
BaseQuantities - CrossSectionArea: 2318.62 mm2
Pset_BeamCommon - Slope: 0 deg; Reference: 28_PBT_SF_staal_koker:S235_K80x120x6.3
Pset_QuantityTakeOff - Reference: 28_PBT_SF_staal_koker:S235_K80x120x6.3
Pset_ReinforcementBarPitchOfBeam - Reference: 28_PBT_SF_staal_koker:S235_K80x120x6.3
Pset_Pieters - Naamgeving element: 28_PBT_SF_staal_koker: S235_K80x120x6.3; Fase: Nieuw
Name (28_PBT_SF_staal_koker:S235_K80x120x6.3:...) | In | Length (mm) = Span (mm) | OuterSurfaceArea (mm2) | GrossVolume (m3) | NetVolume (m3) | Bouwlaag | GrossSurfaceArea (mm2) | NetSurfaceArea (mm2)
2443934 | 01 eerste verdieping | 2183 | 1577349 | 5061541 | 0.00506159 | Level: 01 eerste verdieping | 842420 | 1581986
2444643 | 01 eerste verdieping | 7013.24 | 5067491 | 16261028 | 0.0162612 | Level: 01 eerste verdieping | 2696153 | 5072128
2444645 | 01 eerste verdieping | 4245.24 | 3067444 | 9843096 | 0.00984319 | Level: 01 eerste verdieping | 1633861 | 3072082
2444649 | 01 eerste verdieping | 4256.31 | 3075439 | 9868749 | 0.00986885 | Level: 01 eerste verdieping | 1638107 | 3080076
2444651 | 01 eerste verdieping | 6741.34 | 4871024 | 15630586 | 0.0156307 | Level: 01 eerste verdieping | 2591802 | 4875661
2447587 | 01 eerste verdieping | 7977.52 | 5764239 | 18496818 | 0.018497 | Level: 01 eerste verdieping | 3066219 | 5768877
2447589 | 01 eerste verdieping | 7957.52 | 5749788 | 18450445 | 0.0184506 | Level: 01 eerste verdieping | 3058544 | 5754425
2447612 | 01 eerste verdieping | 8600 | 6214017 | 19940107 | 0.0199403 | Level: 01 eerste verdieping | 3305112 | 6218655
2447614 | 01 eerste verdieping | 6716.34 | 4852960 | 15572621 | 0.0155728 | Level: 01 eerste verdieping | 2582208 | 4857597
2447908 | 02 tweede verdieping | 2413 | 1743538 | 5594823 | 0.00559488 | Level: 02 tweede verdieping | 930689 | 1748175
2448100 | 02 tweede verdieping | 2468 | 1783278 | 5722347 | 0.0057224 | Level: 02 tweede verdieping | 951797 | 1787916
2448126 | 02 tweede verdieping | 2413 | 1743538 | 5594823 | 0.00559488 | Level: 02 tweede verdieping | 930689 | 1748175
2448395 | 01 eerste verdieping | 6761.34 | 4885475 | 15676959 | 0.0156771 | Level: 01 eerste verdieping | 2599478 | 4890112
2448397 | 01 eerste verdieping | 6761.34 | 4885475 | 15676959 | 0.0156771 | Level: 01 eerste verdieping | 2599478 | 4890112
2448491 | 02 tweede verdieping | 4245.24 | 3067444 | 9843096 | 0.00984319 | Level: 02 tweede verdieping | 1633861 | 3072082
2448493 | 02 tweede verdieping | 4245.24 | 3067444 | 9843096 | 0.00984319 | Level: 02 tweede verdieping | 1633861 | 3072082
2448497 | 02 tweede verdieping | 4225.24 | 3052993 | 9796724 | 0.00979682 | Level: 02 tweede verdieping | 1626185 | 3057631
2448499 | 02 tweede verdieping | 7190 | 5195208 | 16670857 | 0.016671 | Level: 02 tweede verdieping | 2763987 | 5199845
2448503 | 02 tweede verdieping | 7977.52 | 5764239 | 18496818 | 0.018497 | Level: 02 tweede verdieping | 3066219 | 5768877
2448505 | 02 tweede verdieping | 7977.52 | 5764239 | 18496818 | 0.018497 | Level: 02 tweede verdieping | 3066219 | 5768877
2448509 | 02 tweede verdieping | 8600 | 6214017 | 19940107 | 0.0199403 | Level: 02 tweede verdieping | 3305112 | 6218655
2448511 | 02 tweede verdieping | 5950.41 | 4299527 | 13796715 | 0.0137968 | Level: 02 tweede verdieping | 2288261 | 4304164
2448523 | 02 tweede verdieping | 7190 | 5195208 | 16670857 | 0.016671 | Level: 02 tweede verdieping | 2763987 | 5199845
2448525 | 02 tweede verdieping | 7190 | 5195208 | 16670857 | 0.016671 | Level: 02 tweede verdieping | 2763987 | 5199845
2449283 | 03 derde verdieping | 4945.52 | 3573433 | 11466758 | 0.0114669 | Level: 03 derde verdieping | 1902608 | 3578070
2449291 | 03 derde verdieping | 4965.52 | 3587884 | 11513130 | 0.0115132 | Level: 03 derde verdieping | 1910284 | 3592521
2449293 | 03 derde verdieping | 3260 | 2355546 | 7558692 | 0.00755877 | Level: 03 derde verdieping | 1255747 | 2360183
2449954 | 03 derde verdieping | 4660 | 3367130 | 10804756 | 0.0108049 | Level: 03 derde verdieping | 1793034 | 3371768
2449956 | 03 derde verdieping | 5790.41 | 4183917 | 13425736 | 0.0134259 | Level: 03 derde verdieping | 2226857 | 4188555
2450736 | 04 vierde verdieping | 7866.85 | 5684272 | 18240212 | 0.0182404 | Level: 04 vierde verdieping | 3023746 | 5688910
2450738 | 04 vierde verdieping | 3221.8 | 2327947 | 7470128 | 0.0074702 | Level: 04 vierde verdieping | 1241088 | 2332584
2513725 | 02 tweede verdieping | 8014.96 | 5791291 | 18583624 | 0.0185838 | Level: 02 tweede verdieping | 3080588 | 5795928
2812901 | 01 eerste verdieping | 7711.31 | 5571884 | 17879571 | 0.0178797 | Level: 01 eerste verdieping | 2964053 | 5576522
2812903 | 01 eerste verdieping | 7711.31 | 5571884 | 17879571 | 0.0178797 | Level: 01 eerste verdieping | 2964053 | 5576522
2813071 | 01 eerste verdieping | 7711.31 | 5571884 | 17879571 | 0.0178797 | Level: 01 eerste verdieping | 2964053 | 5576522
2813073 | 01 eerste verdieping | 6734.31 | 4865943 | 15614283 | 0.0156144 | Level: 01 eerste verdieping | 2589104 | 4870580
2813094 | 01 eerste verdieping | 7711.31 | 5571884 | 17879571 | 0.0178797 | Level: 01 eerste verdieping | 2964053 | 5576522
2813096 | 01 eerste verdieping | 7711.31 | 5571884 | 17879571 | 0.0178797 | Level: 01 eerste verdieping | 2964053 | 5576522
2948648 | 01 eerste verdieping | 8014.96 | 5791291 | 18583624 | 0.0185838 | Level: 01 eerste verdieping | 3080588 | 5795928
3240611 | 03 derde verdieping | 4820.02 | 3482757 | 11175788 | 0.0111759 | Level: 03 derde verdieping | 1854447 | 3487394
3240785 | 03 derde verdieping | 4820.02 | 3482757 | 11175788 | 0.0111759 | Level: 03 derde verdieping | 1854447 | 3487394
3965329 | 03 derde verdieping | 4820 | 3482740 | 11175734 | 0.0111758 | Level: 03 derde verdieping | 1854438 | 3487377
3965331 | 03 derde verdieping | 4820.02 | 3482757 | 11175788 | 0.0111759 | Level: 03 derde verdieping | 1854447 | 3487394
3965364 | 03 derde verdieping | 5862 | 4235646 | 13591729 | 0.0135919 | Level: 03 derde verdieping | 2254332 | 4240283
3965366 | 03 derde verdieping | 5862 | 4235646 | 13591729 | 0.0135919 | Level: 03 derde verdieping | 2254332 | 4240283
4247275 | 03 derde verdieping | 1499.69 | 1083617 | 3477211 | 0.00347724 | Level: 03 derde verdieping | 580183 | 1088255
4247493 | 03 derde verdieping | 4149.69 | 2998402 | 9621546 | 0.00962164 | Level: 03 derde verdieping | 1597190 | 3003039
4247555 | 03 derde verdieping | 1499.69 | 1083617 | 3477211 | 0.00347724 | Level: 03 derde verdieping | 580183 | 1088255
4247590 | 03 derde verdieping | 1499.69 | 1083617 | 3477211 | 0.00347724 | Level: 03 derde verdieping | 580183 | 1088255
4247632 | 03 derde verdieping | 1499.69 | 1083617 | 3477211 | 0.00347724 | Level: 03 derde verdieping | 580183 | 1088255
4247634 | 03 derde verdieping | 1499.69 | 1083617 | 3477211 | 0.00347724 | Level: 03 derde verdieping | 580183 | 1088255
4247649 | 03 derde verdieping | 1499.69 | 1083617 | 3477211 | 0.00347724 | Level: 03 derde verdieping | 580183 | 1088255
4247651 | 03 derde verdieping | 1499.69 | 1083617 | 3477211 | 0.00347724 | Level: 03 derde verdieping | 580183 | 1088255
4247668 | 03 derde verdieping | 1576.69 | 1139255 | 3655744 | 0.00365578 | Level: 03 derde verdieping | 609734 | 1143892
4394031 | 01 eerste verdieping | 8600 | 6214017 | 19940107 | 0.0199403 | Level: 01 eerste verdieping | 3305112 | 6218655
4394033 | 01 eerste verdieping | 8600 | 6214017 | 19940107 | 0.0199403 | Level: 01 eerste verdieping | 3305112 | 6218655
4394362 | 02 tweede verdieping | 8600 | 6214017 | 19940107 | 0.0199403 | Level: 02 tweede verdieping | 3305112 | 6218655
4394364 | 02 tweede verdieping | 8600 | 6214017 | 19940107 | 0.0199403 | Level: 02 tweede verdieping | 3305112 | 6218655

# IfcBeam: 28_PBT_SF_staal_koker:S355_K100x100x8 (12)
In: 03 derde verdieping
Type - Pset_BeamCommon - IsExternal: no; LoadBearing: yes
Type - Pset_ProductRequirements - Category: Structural Framing
Type - Pset_ReinforcementBarPitchOfBeam - Description: #100x100x6.3
Type - Pset_Pieters - Breedte: 100 mm; Hoogte: 100 mm; Codering - NL-SfB: 28.11; Omschrijving NL-SfB: hoofddraagconstructies - kolommen en liggers, kolom-/liggerconstructies; Materiaal: 00_PBT_MAT_staal_S355; Materiaalkwaliteit: S355; Description: #100x100x6.3
Classification: 28.11 hoofddraagconstructies - kolommen en liggers, kolom-/liggerconstructies (Uniformat); Material: 00_PBT_MAT_staal_S355
BaseQuantities - CrossSectionArea: 2875.27 mm2
Pset_BeamCommon - Slope: 0 deg; Reference: 28_PBT_SF_staal_koker:S355_K100x100x8
Pset_QuantityTakeOff - Reference: 28_PBT_SF_staal_koker:S355_K100x100x8
Pset_ReinforcementBarPitchOfBeam - Reference: 28_PBT_SF_staal_koker:S355_K100x100x8
Pset_Pieters - Bouwlaag: Level: 04 bk staal paradezaal binnendoos; Naamgeving element: 28_PBT_SF_staal_koker: S355_K100x100x8; Fase: Nieuw
Name (28_PBT_SF_staal_koker:S355_K100x100x8:...) | Length (mm) = Span (mm) | OuterSurfaceArea (mm2) | GrossVolume (m3) | NetVolume (m3) | GrossSurfaceArea (mm2) | NetSurfaceArea (mm2)
6303682 | 3582 | 2513359 | 10299235 | 0.0102994 | 1364755 | 2519110
6304128 | 4280 | 3003121 | 12306179 | 0.0123063 | 1629575 | 3008872
6304145 | 4280 | 3003121 | 12306177 | 0.0123063 | 1629575 | 3008871
6304160 | 3582 | 2513359 | 10299235 | 0.0102994 | 1364755 | 2519110
6304177 | 1528 | 1072143 | 4393425 | 0.00439348 | 585472 | 1077894
6304258 | 1528 | 1072142 | 4393418 | 0.00439347 | 585471 | 1077892
6305861 | 3582 | 2513359 | 10299235 | 0.0102994 | 1364755 | 2519110
6305863 | 4280 | 3003121 | 12306179 | 0.0123063 | 1629575 | 3008872
6305865 | 4280 | 3003121 | 12306177 | 0.0123063 | 1629575 | 3008871
6305867 | 3582 | 2513359 | 10299235 | 0.0102994 | 1364755 | 2519110
6305869 | 1528 | 1072143 | 4393425 | 0.00439348 | 585472 | 1077894
6305871 | 1528 | 1072142 | 4393418 | 0.00439347 | 585471 | 1077892

# IfcBeam: 28_PBT_SF_staal_koker:S355_K140x70x5 (4)
In: 02 tweede verdieping
Type - Pset_BeamCommon - IsExternal: no; LoadBearing: yes
Type - Pset_ProductRequirements - Category: Structural Framing
Type - Pset_ReinforcementBarPitchOfBeam - Description: #70x140x5
Type - Pset_Pieters - Breedte: 70 mm; Hoogte: 140 mm; Codering - NL-SfB: 28.11; Omschrijving NL-SfB: hoofddraagconstructies - kolommen en liggers, kolom-/liggerconstructies; Materiaal: 00_PBT_MAT_staal_S355; Materiaalkwaliteit: S355; Description: #70x140x5
Classification: 28.11 hoofddraagconstructies - kolommen en liggers, kolom-/liggerconstructies (Uniformat); Material: 00_PBT_MAT_staal_S355
BaseQuantities - CrossSectionArea: 1966.49 mm2
Pset_BeamCommon - Slope: 0 deg; Reference: 28_PBT_SF_staal_koker:S355_K140x70x5
Pset_QuantityTakeOff - Reference: 28_PBT_SF_staal_koker:S355_K140x70x5
Pset_ReinforcementBarPitchOfBeam - Reference: 28_PBT_SF_staal_koker:S355_K140x70x5
Pset_Pieters - Bouwlaag: Level: 02 tweede verdieping; Naamgeving element: 28_PBT_SF_staal_koker: S355_K140x70x5; Fase: Nieuw
Name (28_PBT_SF_staal_koker:S355_K140x70x5:...) | Length (mm) = Span (mm) | OuterSurfaceArea (mm2) | GrossVolume (m3) | NetVolume (m3) | GrossSurfaceArea (mm2) | NetSurfaceArea (mm2)
2362589 | 3800 | 2955189 | 7472671 | 0.00747275 | 1547742 | 2959122
2362691 | 3705.01 | 2881321 | 7285883 | 0.00728596 | 1509153 | 2885254
3470906 | 1272 | 989211 | 2501378 | 0.00250141 | 520703 | 993144
3471759 | 1272 | 989211 | 2501378 | 0.00250141 | 520703 | 993144

# IfcBeam: 28_PBT_SF_staal_koker:S355_K150x150x10 (9)
In: 02 tweede verdieping
Type - Pset_BeamCommon - IsExternal: no; LoadBearing: yes
Type - Pset_ProductRequirements - Category: Structural Framing
Type - Pset_ReinforcementBarPitchOfBeam - Description: #150x150x10
Type - Pset_Pieters - Breedte: 150 mm; Hoogte: 150 mm; Codering - NL-SfB: 28.11; Omschrijving NL-SfB: hoofddraagconstructies - kolommen en liggers, kolom-/liggerconstructies; Materiaal: 00_PBT_MAT_staal_S355; Materiaalkwaliteit: S355; Description: #150x150x10
Classification: 28.11 hoofddraagconstructies - kolommen en liggers, kolom-/liggerconstructies (Uniformat); Material: 00_PBT_MAT_staal_S355
BaseQuantities - CrossSectionArea: 5492.61 mm2
Pset_BeamCommon - Slope: 0 deg; Reference: 28_PBT_SF_staal_koker:S355_K150x150x10
Pset_QuantityTakeOff - Reference: 28_PBT_SF_staal_koker:S355_K150x150x10
Pset_ReinforcementBarPitchOfBeam - Reference: 28_PBT_SF_staal_koker:S355_K150x150x10
Pset_Pieters - Bouwlaag: Level: 02 tweede verdieping; Naamgeving element: 28_PBT_SF_staal_koker: S355_K150x150x10; Fase: Nieuw
Name (28_PBT_SF_staal_koker:S355_K150x150x10:...) | Length (mm) = Span (mm) | OuterSurfaceArea (mm2) | GrossVolume (m3) | NetVolume (m3) | GrossSurfaceArea (mm2) | NetSurfaceArea (mm2)
2272116 | 3122.5 | 3363181 | 17150681 | 0.0171509 | 1804074 | 3374166
2272318 | 1323.5 | 1425514 | 7269465 | 0.00726954 | 771001 | 1436499
2272821 | 1033 | 1112623 | 5673868 | 0.00567393 | 604183 | 1123608
2347826 | 4220 | 4545276 | 23178823 | 0.0231791 | 2434311 | 4556261
2347878 | 5670 | 6107042 | 31143111 | 0.0311434 | 3266970 | 6118027
2348087 | 4220 | 4545276 | 23178823 | 0.0231791 | 2434311 | 4556261
2348089 | 5670 | 6107042 | 31143111 | 0.0311434 | 3266970 | 6118027
3815707 | 5845 | 6295530 | 32104318 | 0.0321047 | 3367464 | 6306516
6394974 | 3796 | 4088596 | 20849962 | 0.0208502 | 2190830 | 4099581

# IfcBeam: 28_PBT_SF_staal_koker:S355_K150x250x10 (3)
In: 02 tweede verdieping
Type - Pset_BeamCommon - IsExternal: no; LoadBearing: yes
Type - Pset_ProductRequirements - Category: Structural Framing
Type - Pset_ReinforcementBarPitchOfBeam - Description: #250x150x10
Type - Pset_Pieters - Breedte: 250 mm; Hoogte: 150 mm; Codering - NL-SfB: 28.11; Omschrijving NL-SfB: hoofddraagconstructies - kolommen en liggers, kolom-/liggerconstructies; Materiaal: 00_PBT_MAT_staal_S355; Materiaalkwaliteit: S355; Description: #250x150x10
Classification: 28.11 hoofddraagconstructies - kolommen en liggers, kolom-/liggerconstructies (Uniformat); Material: 00_PBT_MAT_staal_S355
BaseQuantities - CrossSectionArea: 7492.6 mm2
Pset_BeamCommon - Slope: 0 deg; Reference: 28_PBT_SF_staal_koker:S355_K150x250x10
Pset_QuantityTakeOff - Reference: 28_PBT_SF_staal_koker:S355_K150x250x10
Pset_ReinforcementBarPitchOfBeam - Reference: 28_PBT_SF_staal_koker:S355_K150x250x10
Pset_Pieters - Bouwlaag: Level: 02 tweede verdieping; Naamgeving element: 28_PBT_SF_staal_koker: S355_K150x250x10; Fase: Nieuw
Name (28_PBT_SF_staal_koker:S355_K150x250x10:...) | Length (mm) = Span (mm) | OuterSurfaceArea (mm2) | GrossVolume (m3) | NetVolume (m3) | GrossSurfaceArea (mm2) | NetSurfaceArea (mm2)
2345738 | 5381.14 | 7948377 | 40318764 | 0.0403191 | 4181323 | 7963362
2347308 | 5815 | 8589218 | 43569482 | 0.0435698 | 4517236 | 8604203
2347359 | 5628.86 | 8314272 | 42174795 | 0.0421751 | 4373116 | 8329257

# IfcBeam: 28_PBT_SF_staal_koker:S355_K180x180x12.5 (7)
In: -2 kelder
Type - Pset_BeamCommon - IsExternal: no; LoadBearing: yes
Type - Pset_ProductRequirements - Category: Structural Framing
Type - Pset_ReinforcementBarPitchOfBeam - Description: K180x180x12.5
Type - Pset_Pieters - Breedte: 180 mm; Hoogte: 180 mm; Codering - NL-SfB: 28.11; Omschrijving NL-SfB: hoofddraagconstructies - kolommen en liggers, kolom-/liggerconstructies; Materiaal: 00_PBT_MAT_staal_S355; Materiaalkwaliteit: S355; Description: K180x180x12.5
Classification: 28.11 hoofddraagconstructies - kolommen en liggers, kolom-/liggerconstructies (Uniformat); Material: 00_PBT_MAT_staal_S355
Pset_BeamCommon - Reference: 28_PBT_SF_staal_koker:S355_K180x180x12.5
Pset_QuantityTakeOff - Reference: 28_PBT_SF_staal_koker:S355_K180x180x12.5
Pset_ReinforcementBarPitchOfBeam - Reference: 28_PBT_SF_staal_koker:S355_K180x180x12.5
Pset_Pieters - Bouwlaag: Level: palenplan; Naamgeving element: 28_PBT_SF_staal_koker: S355_K180x180x12.5; Fase: Nieuw
Name (28_PBT_SF_staal_koker:S355_K180x180x12.5:...) | Length (mm) | CrossSectionArea (mm2) | NetVolume (m3) | Slope (deg) | Span (mm) | NetSurfaceArea (mm2)
2315321 | 7207.3 | 8207.21 | 0.0591525 | 90 | 7330 | 9287521 | BaseQuantities - OuterSurfaceArea: 9271107 mm2; GrossVolume: 59151813 m3; GrossSurfaceArea: 4973665 mm2
2315323 | 7207.3 | 8207.21 | 0.0591525 | 90 | 7330 | 9287521 | BaseQuantities - OuterSurfaceArea: 9271107 mm2; GrossVolume: 59151813 m3; GrossSurfaceArea: 4973665 mm2
2315325 | 7207.3 | 8207.21 | 0.0591525 | 90 | 7330 | 9287521 | BaseQuantities - OuterSurfaceArea: 9271107 mm2; GrossVolume: 59151813 m3; GrossSurfaceArea: 4973665 mm2
2315327 | 4799.14 | 4290379 | 0.0348309 | 53.3433 | 4799.14 | 5480638
2315329 | 4782.76 | 4344032 | 0.0349441 | 53.6078 | 4782.76 | 5502748
2315331 | 4719.58 | 4332538 | 0.0350052 | 54.6616 | 4719.58 | 5510674
2315333 | 4733.55 | 4300599 | 0.0346624 | 54.4238 | 4733.55 | 5457272

# IfcBeam: 28_PBT_SF_staal_koker:S355_K200x200x10 (7)
In: -1 kelder
Type - Pset_BeamCommon - IsExternal: no; LoadBearing: yes
Type - Pset_ProductRequirements - Category: Structural Framing
Type - Pset_ReinforcementBarPitchOfBeam - Description: #200x200x10
Type - Pset_Pieters - Breedte: 150 mm; Hoogte: 150 mm; Codering - NL-SfB: 28.11; Omschrijving NL-SfB: hoofddraagconstructies - kolommen en liggers, kolom-/liggerconstructies; Materiaal: 00_PBT_MAT_staal_S355; Materiaalkwaliteit: S355; Description: #200x200x10
Classification: 28.11 hoofddraagconstructies - kolommen en liggers, kolom-/liggerconstructies (Uniformat); Material: 00_PBT_MAT_staal_S355
BaseQuantities - CrossSectionArea: 5492.61 mm2
Pset_BeamCommon - Slope: 0 deg; Reference: 28_PBT_SF_staal_koker:S355_K200x200x10
Pset_QuantityTakeOff - Reference: 28_PBT_SF_staal_koker:S355_K200x200x10
Pset_ReinforcementBarPitchOfBeam - Reference: 28_PBT_SF_staal_koker:S355_K200x200x10
Pset_Pieters - Dragend/niet dragend: yes; In/uitwendig: no; Bouwlaag: Level: -1 kelder; Naamgeving element: 28_PBT_SF_staal_koker: S355_K200x200x10; Fase: Nieuw
Name (28_PBT_SF_staal_koker:S355_K200x200x10:...) | Length (mm) = Span (mm) | OuterSurfaceArea (mm2) | GrossVolume (m3) | NetVolume (m3) | GrossSurfaceArea (mm2) | NetSurfaceArea (mm2)
6466478 | 2713.75 | 2922925 | 14905576 | 0.0149057 | 1569350 | 2933910
6467162 | 2692.01 | 2899511 | 14786178 | 0.0147863 | 1556867 | 2910497
6467452 | 2675.3 | 2881513 | 14694393 | 0.0146945 | 1547271 | 2892498
6467483 | 2648.94 | 2853116 | 14549582 | 0.0145497 | 1532131 | 2864101
6468019 | 2706.25 | 2914847 | 14864382 | 0.0148645 | 1565043 | 2925832
6468021 | 2719.51 | 2929131 | 14937225 | 0.0149374 | 1572659 | 2940116
6468023 | 2662.8 | 2868049 | 14625735 | 0.0146259 | 1540093 | 2879034

# IfcBeam: 28_PBT_SF_staal_koker:S355_K250x150x10, 28_PBT_SF_staal_koker:S355_K250x150x10:4340427
In: 01 eerste verdieping
Type - Pset_BeamCommon - IsExternal: no; LoadBearing: yes
Type - Pset_ProductRequirements - Category: Structural Framing
Type - Pset_ReinforcementBarPitchOfBeam - Description: K250x150x10
Type - Pset_Pieters - Breedte: 150 mm; Hoogte: 250 mm; Codering - NL-SfB: 28.11; Omschrijving NL-SfB: hoofddraagconstructies - kolommen en liggers, kolom-/liggerconstructies; Materiaal: 00_PBT_MAT_staal_S355; Materiaalkwaliteit: S355; Description: K250x150x10
Classification: 28.11 hoofddraagconstructies - kolommen en liggers, kolom-/liggerconstructies (Uniformat); Material: 00_PBT_MAT_staal_S355
BaseQuantities - Length: 1599 mm; CrossSectionArea: 7492.6 mm2; OuterSurfaceArea: 2361850 mm2; GrossVolume: 11980671 m3; NetVolume: 0.0119808 m3; GrossSurfaceArea: 1253007 mm2; NetSurfaceArea: 2376836 mm2
Pset_BeamCommon - Slope: 0 deg; Reference: 28_PBT_SF_staal_koker:S355_K250x150x10; Span: 1599 mm
Pset_QuantityTakeOff - Reference: 28_PBT_SF_staal_koker:S355_K250x150x10
Pset_ReinforcementBarPitchOfBeam - Reference: 28_PBT_SF_staal_koker:S355_K250x150x10
Pset_Pieters - Bouwlaag: Level: 01 eerste verdieping; Naamgeving element: 28_PBT_SF_staal_koker: S355_K250x150x10; Fase: Nieuw

# IfcBeam: 28_PBT_SF_staal_koker:S355_K300x100x10 (2)
In: 00 begane grond
Type - Pset_BeamCommon - IsExternal: no; LoadBearing: yes
Type - Pset_ProductRequirements - Category: Structural Framing
Type - Pset_ReinforcementBarPitchOfBeam - Description: K300x100x10
Type - Pset_Pieters - Breedte: 100 mm; Hoogte: 300 mm; Codering - NL-SfB: 28.11; Omschrijving NL-SfB: hoofddraagconstructies - kolommen en liggers, kolom-/liggerconstructies; Materiaal: 00_PBT_MAT_staal_S355; Materiaalkwaliteit: S355; Description: K300x100x10
Classification: 28.11 hoofddraagconstructies - kolommen en liggers, kolom-/liggerconstructies (Uniformat); Material: 00_PBT_MAT_staal_S355
BaseQuantities - Length: 4117.04 mm; CrossSectionArea: 7492.6 mm2; OuterSurfaceArea: 6081196 mm2; GrossVolume: 30847344 m3; NetVolume: 0.0308476 m3; GrossSurfaceArea: 3202594 mm2; NetSurfaceArea: 6096181 mm2
Pset_BeamCommon - Slope: 0 deg; Reference: 28_PBT_SF_staal_koker:S355_K300x100x10; Span: 4117.04 mm
Pset_QuantityTakeOff - Reference: 28_PBT_SF_staal_koker:S355_K300x100x10
Pset_ReinforcementBarPitchOfBeam - Reference: 28_PBT_SF_staal_koker:S355_K300x100x10
Pset_Pieters - Bouwlaag: Level: 00 begane grond; Naamgeving element: 28_PBT_SF_staal_koker: S355_K300x100x10; Fase: Nieuw
Name (28_PBT_SF_staal_koker:S355_K300x100x10:...)
5867976
5868390

# IfcBeam: 28_PBT_SF_staal_koker:S355_K300x300x16 (11)
Type - Pset_BeamCommon - IsExternal: no; LoadBearing: yes
Type - Pset_ProductRequirements - Category: Structural Framing
Type - Pset_ReinforcementBarPitchOfBeam - Description: K300x300x12.5
Type - Pset_Pieters - Breedte: 300 mm; Hoogte: 300 mm; Codering - NL-SfB: 28.11; Omschrijving NL-SfB: hoofddraagconstructies - kolommen en liggers, kolom-/liggerconstructies; Materiaal: 00_PBT_MAT_staal_S355; Materiaalkwaliteit: S355; Description: K300x300x12.5
Classification: 28.11 hoofddraagconstructies - kolommen en liggers, kolom-/liggerconstructies (Uniformat); Material: 00_PBT_MAT_staal_S355
Pset_BeamCommon - Reference: 28_PBT_SF_staal_koker:S355_K300x300x16
Pset_QuantityTakeOff - Reference: 28_PBT_SF_staal_koker:S355_K300x300x16
Pset_ReinforcementBarPitchOfBeam - Reference: 28_PBT_SF_staal_koker:S355_K300x300x16
Pset_Pieters - Naamgeving element: 28_PBT_SF_staal_koker: S355_K300x300x16; Fase: Nieuw
Name (28_PBT_SF_staal_koker:S355_K300x300x16:...) | In | CrossSectionArea (mm2) | NetVolume (m3) | Span (mm) | Slope (deg) | Bouwlaag | Length (mm) | NetSurfaceArea (mm2)
2257588 | 01 eerste verdieping | 6751526 | 0.0681771 | 4592.96 | 54.3028 | Level: 01 eerste verdieping_Offset1000 | 4592.96 | 8480174
2257590 | 01 eerste verdieping | 7526094 | 0.0767446 | 5056.51 | 47.5327 | Level: 01 eerste verdieping_Offset1000 | 5056.51 | 9520188
2257592 | 01 eerste verdieping | 6996987 | 0.0710295 | 4746.89 | 51.7926 | Level: 01 eerste verdieping_Offset1000 | 4746.89 | 8811394
2257594 | 01 eerste verdieping | 8542725 | 0.0872166 | 5665.96 | 41.1717 | Level: 01 eerste verdieping_Offset1000 | 5665.96 | 10805173
2257596 | 01 eerste verdieping | 8711579 | 0.0890798 | 5776.66 | 40.2183 | Level: 01 eerste verdieping_Offset1000 | 5776.66 | 11035119
2261302 | 00 begane grond | 17859 | 0.0590174 | 3730 | 90 | Level: 01 ok ruwe vloer | 3304.6 | 7311160 | BaseQuantities - OuterSurfaceArea: 7275442 mm2; GrossVolume: 59016768 m3; GrossSurfaceArea: 3859403 mm2
2589252 | 00 begane grond | 7735863 | 0.0785135 | 5076.81 | 47.283 | Level: 01 ok ruwe vloer | 5076.81 | 9729863
2593129 | 00 begane grond | 17859 | 0.0590174 | 3730 | 90 | Level: 01 ok ruwe vloer | 3304.6 | 7311160 | BaseQuantities - OuterSurfaceArea: 7275442 mm2; GrossVolume: 59016768 m3; GrossSurfaceArea: 3859403 mm2
2593131 | 00 begane grond | 17859 | 0.0590174 | 3730 | 90 | Level: 01 ok ruwe vloer | 3304.6 | 7311160 | BaseQuantities - OuterSurfaceArea: 7275442 mm2; GrossVolume: 59016768 m3; GrossSurfaceArea: 3859403 mm2
2745194 | 00 begane grond | 17859 | 0.0590174 | 3730 | 90 | Level: 01 ok ruwe vloer | 3304.6 | 7311160 | BaseQuantities - OuterSurfaceArea: 7275442 mm2; GrossVolume: 59016768 m3; GrossSurfaceArea: 3859403 mm2
2745196 | 00 begane grond | 17859 | 0.0590174 | 3730 | 90 | Level: 01 ok ruwe vloer | 3304.6 | 7311160 | BaseQuantities - OuterSurfaceArea: 7275442 mm2; GrossVolume: 59016768 m3; GrossSurfaceArea: 3859403 mm2

# IfcBeam: 28_PBT_SF_staal_koker:S355_K80x80x5 (4)
In: 04 vierde verdieping
Type - PredefinedType: BEAM; Classification: 28.11 hoofddraagconstructies - kolommen en liggers, kolom-/liggerconstructies (Uniformat); Material: 00_PBT_MAT_staal_S355
Type - Pset_BeamCommon - IsExternal: no; LoadBearing: yes
Type - Pset_ProductRequirements - Category: Structural Framing
Type - Pset_ReinforcementBarPitchOfBeam - Description: K80x80x5
Type - Pset_Pieters - Breedte: 80 mm; Hoogte: 80 mm; Codering - NL-SfB: 28.11; Omschrijving NL-SfB: hoofddraagconstructies - kolommen en liggers, kolom-/liggerconstructies; Materiaal: 00_PBT_MAT_staal_S355; Materiaalkwaliteit: S355; Description: K80x80x5
Pset_BeamCommon - Reference: 28_PBT_SF_staal_koker:S355_K80x80x5
Pset_QuantityTakeOff - Reference: 28_PBT_SF_staal_koker:S355_K80x80x5
Pset_ReinforcementBarPitchOfBeam - Reference: 28_PBT_SF_staal_koker:S355_K80x80x5
Pset_Pieters - Bouwlaag: Level: 04 vierde verdieping; Naamgeving element: 28_PBT_SF_staal_koker: S355_K80x80x5; Fase: Nieuw
Name (28_PBT_SF_staal_koker:S355_K80x80x5:...) | Span (mm) = Length (mm) | Slope (deg) | CrossSectionArea (mm2) | NetVolume (m3) | NetSurfaceArea (mm2)
3707448 | 3935.81 | 34.675 | 1718459 | 0.00560308 | 2215432
3707780 | 3935.81 | 34.675 | 1718459 | 0.00560308 | 2215432
4523744 | 4090 | 27.1473 | 1781617 | 0.00580205 | 2294393
4523750 | 4080 | 27.1473 | 1779284 | 0.00579799 | 2292799

# IfcBeam: 28_PBT_SF_staal_koker:S355_K80x80x5 (16)
Type - Pset_BeamCommon - IsExternal: no; LoadBearing: yes
Type - Pset_ProductRequirements - Category: Structural Framing
Type - Pset_ReinforcementBarPitchOfBeam - Description: K80x80x5
Type - Pset_Pieters - Breedte: 80 mm; Hoogte: 80 mm; Codering - NL-SfB: 28.11; Omschrijving NL-SfB: hoofddraagconstructies - kolommen en liggers, kolom-/liggerconstructies; Materiaal: 00_PBT_MAT_staal_S355; Materiaalkwaliteit: S355; Description: K80x80x5
Classification: 28.11 hoofddraagconstructies - kolommen en liggers, kolom-/liggerconstructies (Uniformat); Material: 00_PBT_MAT_staal_S355
Pset_BeamCommon - Reference: 28_PBT_SF_staal_koker:S355_K80x80x5
Pset_QuantityTakeOff - Reference: 28_PBT_SF_staal_koker:S355_K80x80x5
Pset_ReinforcementBarPitchOfBeam - Reference: 28_PBT_SF_staal_koker:S355_K80x80x5
Pset_Pieters - Naamgeving element: 28_PBT_SF_staal_koker: S355_K80x80x5; Fase: Nieuw
Name (28_PBT_SF_staal_koker:S355_K80x80x5:...) | In | Length (mm) = Span (mm) | CrossSectionArea (mm2) | OuterSurfaceArea (mm2) | GrossVolume (m3) | NetVolume (m3) | Slope (deg) | Bouwlaag | GrossSurfaceArea (mm2) | NetSurfaceArea (mm2)
3707080 | 04 vierde verdieping | 3418.27 | 1473.15 | 1977607 | 5035638 | 0.00503569 | 5.20325 | Level: 04 vierde verdieping | 1052780 | 1980553
3707406 | 04 vierde verdieping | 3660 | 1592323 |  |  | 0.00520219 | 22.5141 | Level: 04 vierde verdieping |  | 2047869
3707774 | 04 vierde verdieping | 3418.27 | 1473.15 | 1977607 | 5035638 | 0.00503569 | 5.20325 | Level: 04 vierde verdieping | 1052780 | 1980553
3707777 | 04 vierde verdieping | 3660 | 1592323 |  |  | 0.00520219 | 22.5141 | Level: 04 vierde verdieping |  | 2047869
4523738 | 04 vierde verdieping | 3715.75 | 1473.15 | 2149709 | 5473867 | 0.00547392 | 0 | Level: 04 vierde verdieping | 1144142 | 2152656
4523741 | 04 vierde verdieping | 4125 | 1820829 |  |  | 0.00600422 | 30.9309 | Level: 04 vierde verdieping |  | 2362068
4523746 | 04 vierde verdieping | 3715.75 | 1473.15 | 2149709 | 5473867 | 0.00547392 | 0 | Level: 04 vierde verdieping | 1144142 | 2152656
4523748 | 04 vierde verdieping | 4125 | 1820829 |  |  | 0.00600422 | 30.9309 | Level: 04 vierde verdieping |  | 2362068
6410625 | 01 eerste verdieping | 4065.5 | 1473.15 | 2352054 | 5989103 | 0.00598916 | 0 | Level: 01 eerste verdieping | 1251559 | 2355001
6411885 | 01 eerste verdieping | 3940 | 1473.15 | 2279447 | 5804221 | 0.00580428 | 0 | Level: 01 eerste verdieping | 1213014 | 2282393
6412188 | 01 eerste verdieping | 4540 | 1473.15 | 2626571 | 6688113 | 0.00668818 | 0 | Level: 01 eerste verdieping | 1397289 | 2629517
6412972 | 01 eerste verdieping | 2323.25 | 1473.15 | 1344093 | 3422502 | 0.00342254 | 0 | Level: 01 eerste verdieping | 716472 | 1347039
6413077 | 01 eerste verdieping | 2323.25 | 1473.15 | 1344093 | 3422502 | 0.00342254 | 0 | Level: 01 eerste verdieping | 716472 | 1347039
6419560 | 02 tweede verdieping | 2340 | 1473.15 | 1353783 | 3447177 | 0.00344721 | 0 | Level: 02 tweede verdieping | 721616 | 1356729
6426661 | 02 tweede verdieping | 3239.99 | 1473.15 | 1874461 | 4772995 | 0.00477304 | 0 | Level: 02 tweede verdieping | 998024 | 1877408
6426798 | 02 tweede verdieping | 2140 | 1473.15 | 1238075 | 3152546 | 0.00315258 | 0 | Level: 02 tweede verdieping | 660191 | 1241022

# IfcBeam: 28_PBT_SF_staal_koker_met_ondergelaste_strip:S355_K150x150x10 + ondergelaste strip (2)
Type - PredefinedType: BEAM; Classification: 28.11 hoofddraagconstructies - kolommen en liggers, kolom-/liggerconstructies (Uniformat); Material: 00_PBT_MAT_staal_S355
Type - Pset_BeamCommon - IsExternal: no; LoadBearing: yes
Type - Pset_ProductRequirements - Category: Structural Framing
Type - Pset_ReinforcementBarPitchOfBeam - Description: #150x150x10 + ondergelaste strip
Type - Pset_Pieters - Breedte: 150 mm; Hoogte: 150 mm; Codering - NL-SfB: 28.11; Omschrijving NL-SfB: hoofddraagconstructies - kolommen en liggers, kolom-/liggerconstructies; Materiaal: 00_PBT_MAT_staal_S355; Materiaalkwaliteit: S355; Description: #150x150x10 + ondergelaste strip
Pset_BeamCommon - Slope: 0 deg; Reference: 28_PBT_SF_staal_koker_met_ondergelaste_strip:S355_K150x150x10 + ondergelaste strip
Pset_QuantityTakeOff - Reference: 28_PBT_SF_staal_koker_met_ondergelaste_strip:S355_K150x150x10 + ondergelaste strip
Pset_ReinforcementBarPitchOfBeam - Reference: 28_PBT_SF_staal_koker_met_ondergelaste_strip:S355_K150x150x10 + ondergelaste strip
Pset_Pieters - Naamgeving element: 28_PBT_SF_staal_koker_met_ondergelaste_strip: S355_K150x150x10 + ondergelaste strip; Fase: Nieuw
Name (28_PBT_SF_staal_koker_met_ondergelaste_strip:S355_K150x150x10 + ondergelaste strip:...) | In | Span (mm) = Length (mm) | Bouwlaag | CrossSectionArea (mm2) | NetVolume (m3) | NetSurfaceArea (mm2)
2319187 | 01 eerste verdieping | 24235.8 | Level: 01 eerste verdieping | 26865525 | 0.199119 | 39804374
2329224 | 02 tweede verdieping | 24800.2 | Level: 02 tweede verdieping | 27408208 | 0.203146 | 40608779

# IfcBeam: 28_PBT_SF_staal_koker_met_ondergelaste_strip:S355_K150x150x10 + ondergelaste strip (4)
Type - PredefinedType: BEAM; Classification: 28.11 hoofddraagconstructies - kolommen en liggers, kolom-/liggerconstructies (Uniformat); Material: 00_PBT_MAT_staal_S355 (2)
Type - Pset_BeamCommon - IsExternal: no; LoadBearing: yes
Type - Pset_ProductRequirements - Category: Structural Framing
Type - Pset_ReinforcementBarPitchOfBeam - Description: #150x150x10 + ondergelaste strip
Type - Pset_Pieters - Breedte: 150 mm; Hoogte: 150 mm; Codering - NL-SfB: 28.11; Omschrijving NL-SfB: hoofddraagconstructies - kolommen en liggers, kolom-/liggerconstructies; Materiaal: 00_PBT_MAT_staal_S355; Materiaalkwaliteit: S355; Description: #150x150x10 + ondergelaste strip
Pset_BeamCommon - Slope: 0 deg; Reference: 28_PBT_SF_staal_koker_met_ondergelaste_strip:S355_K150x150x10 + ondergelaste strip
Pset_QuantityTakeOff - Reference: 28_PBT_SF_staal_koker_met_ondergelaste_strip:S355_K150x150x10 + ondergelaste strip
Pset_ReinforcementBarPitchOfBeam - Reference: 28_PBT_SF_staal_koker_met_ondergelaste_strip:S355_K150x150x10 + ondergelaste strip
Pset_Pieters - Naamgeving element: 28_PBT_SF_staal_koker_met_ondergelaste_strip: S355_K150x150x10 + ondergelaste strip; Fase: Nieuw
Name (28_PBT_SF_staal_koker_met_ondergelaste_strip:S355_K150x150x10 + ondergelaste strip:...) | In | Span (mm) = Length (mm) | Bouwlaag | CrossSectionArea (mm2) | OuterSurfaceArea (mm2) | GrossSurfaceArea (mm2) | GrossVolume (m3) | NetVolume (m3) | NetSurfaceArea (mm2)
2348323 | 02 tweede verdieping | 861.986 | Level: 02 tweede verdieping | 718123 | 494994 | 505979 | 0.00473456 | 0.00710507 | 1436246
2390398 | 01 eerste verdieping | 2590.81 | Level: 01 eerste verdieping | 2908068 | 1430445 | 1482261 | 0.00712473 | 0.0213552 | 4283755
2402703 | 02 tweede verdieping | 2590.81 | Level: 02 tweede verdieping | 2908068 | 1430445 | 1482261 | 0.00712473 | 0.0213552 | 4283755
3629774 | 02 tweede verdieping | 1096.98 | Level: 02 tweede verdieping | 911652 | 629941 | 640926 | 0.00602531 | 0.00904208 | 1823305

# IfcBeam: 28_PBT_SF_staal_krans:28_PBT_SF_staal_krans_d=700_323.9 (17)
In: 00 begane grond
Type - PredefinedType: BEAM; Material: 00_PBT_MAT_staal_S355
Type - Pset_BeamCommon - IsExternal: no; LoadBearing: yes
Type - Pset_ProductRequirements - Category: Structural Framing
Type - Pset_Pieters - Materiaal: 00_PBT_MAT_staal_S355; Materiaalkwaliteit: S355
Pset_BeamCommon - Reference: 28_PBT_SF_staal_krans:28_PBT_SF_staal_krans_d=700_323.9
Pset_QuantityTakeOff - Reference: 28_PBT_SF_staal_krans:28_PBT_SF_staal_krans_d=700_323.9; sets with these values: 2
Pset_Pieters - Naamgeving element: 28_PBT_SF_staal_krans: 28_PBT_SF_staal_krans_d=700_323.9; Fase: Nieuw
BaseQuantities - CrossSectionArea: 526180 mm2; NetVolume: 0.010971 m3; NetSurfaceArea: 1052360 mm2
Name (28_PBT_SF_staal_krans:28_PBT_SF_staal_krans_d=700_323.9:...)
4594690 | BaseQuantities - Length: 25 mm; OuterSurfaceArea: 54977.9 mm2; GrossSurfaceArea: 824635 mm2; GrossVolume: 0.00962071 m3
4598077
4599129
4599137
4599145
4599153
4599159
4607987
4608387
4608403
4608411
4608487
4608495
4608511
4608519
4608537
4608545

# IfcBeam: 28_PBT_SF_staal_krans:28_PBT_SF_staal_krans_d=700_323.9_VOID_235 (2)
In: 00 begane grond
Type - PredefinedType: BEAM; Material: 00_PBT_MAT_staal_S355
Type - Pset_BeamCommon - IsExternal: no; LoadBearing: yes
Type - Pset_ProductRequirements - Category: Structural Framing
Type - Pset_Pieters - Materiaal: 00_PBT_MAT_staal_S355; Materiaalkwaliteit: S355
Pset_BeamCommon - Reference: 28_PBT_SF_staal_krans:28_PBT_SF_staal_krans_d=700_323.9_VOID_235
Pset_QuantityTakeOff - Reference: 28_PBT_SF_staal_krans:28_PBT_SF_staal_krans_d=700_323.9_VOID_235; sets with these values: 2
Pset_Pieters - Naamgeving element: 28_PBT_SF_staal_krans: 28_PBT_SF_staal_krans_d=700_323.9_VOID_235; Fase: Nieuw
BaseQuantities - CrossSectionArea: 477366 mm2; NetVolume: 0.00985132 m3; NetSurfaceArea: 954733 mm2
Name (28_PBT_SF_staal_krans:28_PBT_SF_staal_krans_d=700_323.9_VOID_235:...)
4599113 | BaseQuantities - Length: 25 mm; OuterSurfaceArea: 53340 mm2; GrossSurfaceArea: 740420 mm2; GrossVolume: 0.0085885 m3
4599121

# IfcBeam: 28_PBT_SF_staal_krans:28_PBT_SF_staal_krans_d=700_323.9_VOID_250 (6)
In: 00 begane grond
Type - PredefinedType: BEAM; Material: 00_PBT_MAT_staal_S355
Type - Pset_BeamCommon - IsExternal: no; LoadBearing: yes
Type - Pset_ProductRequirements - Category: Structural Framing
Type - Pset_Pieters - Materiaal: 00_PBT_MAT_staal_S355; Materiaalkwaliteit: S355
Pset_BeamCommon - Reference: 28_PBT_SF_staal_krans:28_PBT_SF_staal_krans_d=700_323.9_VOID_250
Pset_QuantityTakeOff - Reference: 28_PBT_SF_staal_krans:28_PBT_SF_staal_krans_d=700_323.9_VOID_250; sets with these values: 2
Pset_Pieters - Naamgeving element: 28_PBT_SF_staal_krans: 28_PBT_SF_staal_krans_d=700_323.9_VOID_250; Fase: Nieuw
BaseQuantities - CrossSectionArea: 486711 mm2; NetVolume: 0.0100622 m3; NetSurfaceArea: 973423 mm2
Name (28_PBT_SF_staal_krans:28_PBT_SF_staal_krans_d=700_323.9_VOID_250:...)
4608427 | BaseQuantities - Length: 25 mm; OuterSurfaceArea: 53659.4 mm2; GrossSurfaceArea: 755875 mm2; GrossVolume: 0.00877769 m3
4608435
4608445
4608453
4608461
4608471

# IfcBeam: 28_PBT_SF_staal_krans:28_PBT_SF_staal_krans_d=700_355.6_VOID_250 2 (5)
In: 00 begane grond
Type - PredefinedType: BEAM; Material: 00_PBT_MAT_staal_S355
Type - Pset_BeamCommon - IsExternal: no; LoadBearing: yes
Type - Pset_ProductRequirements - Category: Structural Framing
Type - Pset_Pieters - Materiaal: 00_PBT_MAT_staal_S355; Materiaalkwaliteit: S355
Pset_BeamCommon - Reference: 28_PBT_SF_staal_krans:28_PBT_SF_staal_krans_d=700_355.6_VOID_250 2
Pset_QuantityTakeOff - Reference: 28_PBT_SF_staal_krans:28_PBT_SF_staal_krans_d=700_355.6_VOID_250 2; sets with these values: 2
Pset_Pieters - Naamgeving element: 28_PBT_SF_staal_krans: 28_PBT_SF_staal_krans_d=700_355.6_VOID_250 2; Fase: Nieuw
BaseQuantities - CrossSectionArea: 484998 mm2; NetVolume: 0.0100392 m3; NetSurfaceArea: 969996 mm2
Name (28_PBT_SF_staal_krans:28_PBT_SF_staal_krans_d=700_355.6_VOID_250 2:...)
4608395 | BaseQuantities - Length: 25 mm; OuterSurfaceArea: 53659.4 mm2; GrossSurfaceArea: 755875 mm2; GrossVolume: 0.00877769 m3
4608419
4608479
4608503
4608527

# IfcBeam: 28_PBT_SF_staal_massief_rond:S355_D16 (8)
In: 04 vierde verdieping
Type - Pset_BeamCommon - IsExternal: no; LoadBearing: yes
Type - Pset_ProductRequirements - Category: Structural Framing
Type - Pset_ReinforcementBarPitchOfBeam - Description: $16
Type - Pset_Pieters - Diameter: 16 mm; Codering - NL-SfB: 28.11; Omschrijving NL-SfB: hoofddraagconstructies - kolommen en liggers, kolom-/liggerconstructies; Materiaal: 00_PBT_MAT_staal_S355; Materiaalkwaliteit: S355; Description: $16
Classification: 28.11 hoofddraagconstructies - kolommen en liggers, kolom-/liggerconstructies (Uniformat); Material: 00_PBT_MAT_staal_S355
Pset_BeamCommon - Reference: 28_PBT_SF_staal_massief_rond:S355_D16
Pset_QuantityTakeOff - Reference: 28_PBT_SF_staal_massief_rond:S355_D16
Pset_ReinforcementBarPitchOfBeam - Reference: 28_PBT_SF_staal_massief_rond:S355_D16
Pset_Pieters - Bouwlaag: Level: 04 vierde verdieping; Naamgeving element: 28_PBT_SF_staal_massief_rond: S355_D16; Fase: Nieuw
Name (28_PBT_SF_staal_massief_rond:S355_D16:...) | CrossSectionArea (mm2) | NetVolume (m3) | Span (mm) = Length (mm) | Slope (deg) | NetSurfaceArea (mm2)
3847465 | 81231.3 | 0.000648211 | 3370.32 | 27.1011 | 162463
3847507 | 81229.5 | 0.000648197 | 3360 | 27.0987 | 162459
3847554 | 81231.3 | 0.000648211 | 3370.32 | 27.1011 | 162463
3847557 | 82904.5 | 0.000661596 | 3360 | 27.0987 | 165809
3847948 | 101235 | 0.000808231 | 4020 | 22.4916 | 202469
3848086 | 101109 | 0.000807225 | 4015 | 22.4926 | 202218
3848125 | 101235 | 0.000808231 | 4020 | 22.4916 | 202469
3848128 | 101235 | 0.000808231 | 4020 | 22.4926 | 202469

# IfcBeam: 28_PBT_SF_staal_massief_rond:S355_D20 (16)
Type - Pset_BeamCommon - IsExternal: no; LoadBearing: yes
Type - Pset_ProductRequirements - Category: Structural Framing
Type - Pset_ReinforcementBarPitchOfBeam - Description: $20
Type - Pset_Pieters - Diameter: 20 mm; Codering - NL-SfB: 28.11; Omschrijving NL-SfB: hoofddraagconstructies - kolommen en liggers, kolom-/liggerconstructies; Materiaal: 00_PBT_MAT_staal_S355; Materiaalkwaliteit: S355; Description: $20
Classification: 28.11 hoofddraagconstructies - kolommen en liggers, kolom-/liggerconstructies (Uniformat); Material: 00_PBT_MAT_staal_S355
Pset_BeamCommon - Reference: 28_PBT_SF_staal_massief_rond:S355_D20
Pset_QuantityTakeOff - Reference: 28_PBT_SF_staal_massief_rond:S355_D20
Pset_ReinforcementBarPitchOfBeam - Reference: 28_PBT_SF_staal_massief_rond:S355_D20
Pset_Pieters - Naamgeving element: 28_PBT_SF_staal_massief_rond: S355_D20; Fase: Nieuw
Name (28_PBT_SF_staal_massief_rond:S355_D20:...) | In | CrossSectionArea (mm2) | NetVolume (m3) | Slope (deg) | Span (mm) = Length (mm) | Bouwlaag | NetSurfaceArea (mm2)
3847134 | 04 vierde verdieping | 174567 | 0.00174245 | 0 | 5797.56 | Level: 05 vijfde verdieping_bk staal dakopbouw | 349134
3847270 | 04 vierde verdieping | 174567 | 0.00174245 | 0 | 5797.56 | Level: 05 vijfde verdieping_bk staal dakopbouw | 349134
3849098 | 04 vierde verdieping | 105018 | 0.00104699 | 0 | 3622.83 | Level: 04 vierde verdieping | 210036
3849196 | 04 vierde verdieping | 105018 | 0.00104699 | 0 | 3622.83 | Level: 04 vierde verdieping | 210036
3850554 | 03 derde verdieping | 109810 | 0.0010949 | 24.4845 | 3788.61 | Level: 03 derde verdieping | 219619
3850619 | 03 derde verdieping | 109810 | 0.0010949 | 24.4845 | 3788.61 | Level: 03 derde verdieping | 219619
3850794 | 03 derde verdieping | 106992 | 0.00106673 | 35.6341 | 3475 | Level: 03 derde verdieping | 213984
3850908 | 03 derde verdieping | 106992 | 0.00106673 | 35.6341 | 3475 | Level: 03 derde verdieping | 213984
4406810 | 05 vijfde verdieping | 108010 | 0.0010769 | 31.0363 | 3563.84 | Level: 05 vijfde verdieping | 216019
4407176 | 05 vijfde verdieping | 106703 | 0.00106383 | 31.243 | 3583.05 | Level: 05 vijfde verdieping | 213405
4407264 | 06 zesde verdieping | 97066.8 | 0.000967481 | 19.6569 | 3269.07 | Level: 06 zesde verdieping | 194134
4407441 | 05 vijfde verdieping | 108010 | 0.0010769 | 31.0363 | 3563.84 | Level: 05 vijfde verdieping | 216019
4407444 | 05 vijfde verdieping | 106724 | 0.00106405 | 31.243 | 3583.05 | Level: 05 vijfde verdieping | 213448
4407447 | 06 zesde verdieping | 97238.6 | 0.000969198 | 19.6717 | 3274.85 | Level: 06 zesde verdieping | 194477
4790938 | 06 zesde verdieping | 102425 | 0.00102107 | 11.4054 | 3303.69 | Level: 06 zesde verdieping | 204851
4790940 | 06 zesde verdieping | 101587 | 0.00101268 | 11.4044 | 3303.01 | Level: 06 zesde verdieping | 203173

# IfcBeam: 28_PBT_SF_staal_massief_rond:S355_D32 (4)
In: 01 eerste verdieping
Type - Pset_BeamCommon - IsExternal: no; LoadBearing: yes
Type - Pset_ProductRequirements - Category: Structural Framing
Type - Pset_ReinforcementBarPitchOfBeam - Description: $32
Type - Pset_Pieters - Diameter: 32 mm; Codering - NL-SfB: 28.11; Omschrijving NL-SfB: hoofddraagconstructies - kolommen en liggers, kolom-/liggerconstructies; Materiaal: 00_PBT_MAT_staal_S355; Materiaalkwaliteit: S355; Description: $32
Classification: 28.11 hoofddraagconstructies - kolommen en liggers, kolom-/liggerconstructies (Uniformat); Material: 00_PBT_MAT_staal_S355
Pset_BeamCommon - Reference: 28_PBT_SF_staal_massief_rond:S355_D32; Slope: 56.0374 deg
Pset_QuantityTakeOff - Reference: 28_PBT_SF_staal_massief_rond:S355_D32
Pset_ReinforcementBarPitchOfBeam - Reference: 28_PBT_SF_staal_massief_rond:S355_D32
Pset_Pieters - Bouwlaag: Level: 01 eerste verdieping; Naamgeving element: 28_PBT_SF_staal_massief_rond: S355_D32; Fase: Nieuw
Name (28_PBT_SF_staal_massief_rond:S355_D32:...) | CrossSectionArea (mm2) | NetVolume (m3) | Span (mm) = Length (mm) | NetSurfaceArea (mm2)
3829177 | 201866 | 0.00321684 | 4000 | 403732
3829181 | 200852 | 0.00318971 | 3980 | 401705
3830365 | 201866 | 0.00321684 | 4000 | 403732
3830367 | 200861 | 0.00320075 | 3980 | 401722

# IfcBeam: 28_PBT_SF_staal_oplegschoen vakwerk:oplegschoen HEB400 PZ (3)
In: 01 eerste verdieping
Type - PredefinedType: BEAM; Material: 00_PBT_MAT_staal_S355
Type - Pset_BeamCommon - IsExternal: no; LoadBearing: yes
Type - Pset_ProductRequirements - Category: Structural Framing
Type - Pset_ReinforcementBarPitchOfBeam - Description: stalen oplegschoen
Type - Pset_Pieters - Materiaal: 00_PBT_MAT_staal_S355; Materiaalkwaliteit: S355; Description: stalen oplegschoen; Type Comments: stalen oplegschoen t.b.v. glijdende oplegging in 1 horizontale richting
Pset_BeamCommon - Reference: 28_PBT_SF_staal_oplegschoen vakwerk:oplegschoen HEB400 PZ
Pset_QuantityTakeOff - Reference: 28_PBT_SF_staal_oplegschoen vakwerk:oplegschoen HEB400 PZ
Pset_ReinforcementBarPitchOfBeam - Reference: 28_PBT_SF_staal_oplegschoen vakwerk:oplegschoen HEB400 PZ
Pset_Pieters - Naamgeving element: 28_PBT_SF_staal_oplegschoen vakwerk: oplegschoen HEB400 PZ; Fase: Nieuw
BaseQuantities - CrossSectionArea: 577816 mm2; NetVolume: 0.012098 m3; NetSurfaceArea: 1155632 mm2
Name (28_PBT_SF_staal_oplegschoen vakwerk:oplegschoen HEB400 PZ:...)
4905537 | BaseQuantities - Length: 675 mm; OuterSurfaceArea: 573750 mm2; GrossSurfaceArea: 593750 mm2; GrossVolume: 0.00675 m3
4906930
4906960

# IfcBeam: 28_PBT_SF_staal_oplegschoen vakwerk:oplegschoen vakwerk toneeltoren (5)
In: 05 vijfde verdieping
Type - PredefinedType: BEAM; Material: 00_PBT_MAT_staal_S355
Type - Pset_BeamCommon - IsExternal: no; LoadBearing: yes
Type - Pset_ProductRequirements - Category: Structural Framing
Type - Pset_ReinforcementBarPitchOfBeam - Description: stalen oplegschoen
Type - Pset_Pieters - Materiaal: 00_PBT_MAT_staal_S355; Materiaalkwaliteit: S355; Description: stalen oplegschoen; Type Comments: stalen oplegschoen t.b.v. glijdende oplegging in 1 horizontale richting
Pset_BeamCommon - Reference: 28_PBT_SF_staal_oplegschoen vakwerk:oplegschoen vakwerk toneeltoren
Pset_QuantityTakeOff - Reference: 28_PBT_SF_staal_oplegschoen vakwerk:oplegschoen vakwerk toneeltoren
Pset_ReinforcementBarPitchOfBeam - Reference: 28_PBT_SF_staal_oplegschoen vakwerk:oplegschoen vakwerk toneeltoren
Pset_Pieters - Naamgeving element: 28_PBT_SF_staal_oplegschoen vakwerk: oplegschoen vakwerk toneeltoren; Fase: Nieuw
BaseQuantities - CrossSectionArea: 246377 mm2; NetVolume: 0.0039695 m3; NetSurfaceArea: 492755 mm2
Name (28_PBT_SF_staal_oplegschoen vakwerk:oplegschoen vakwerk toneeltoren:...)
4797855 | BaseQuantities - Length: 330 mm; OuterSurfaceArea: 204600 mm2; GrossSurfaceArea: 216200 mm2; GrossVolume: 0.001914 m3
4800775
4800783
4800793
4801022

# IfcBeam: 28_PBT_SF_staal_strip:strip 100x10 (42)
Type - Pset_BeamCommon - IsExternal: no; LoadBearing: yes
Type - Pset_ProductRequirements - Category: Structural Framing
Type - Pset_ReinforcementBarPitchOfBeam - Description: wvb ǵ 100x10
Type - Pset_Pieters - Breedte: 100 mm; Hoogte: 10 mm; Codering - NL-SfB: 28.11; Omschrijving NL-SfB: hoofddraagconstructies - kolommen en liggers, kolom-/liggerconstructies; Materiaal: 00_PBT_MAT_staal; Description: wvb ǵ 100x10
Classification: 28.11 hoofddraagconstructies - kolommen en liggers, kolom-/liggerconstructies (Uniformat); Material: 00_PBT_MAT_staal
Pset_BeamCommon - Reference: 28_PBT_SF_staal_strip:strip 100x10
Pset_QuantityTakeOff - Reference: 28_PBT_SF_staal_strip:strip 100x10
Pset_ReinforcementBarPitchOfBeam - Reference: 28_PBT_SF_staal_strip:strip 100x10
Pset_Pieters - Naamgeving element: 28_PBT_SF_staal_strip: strip 100x10; Fase: Nieuw
Name (28_PBT_SF_staal_strip:strip 100x10:...) | In | CrossSectionArea (mm2) | NetVolume (m3) | Span (mm) = Length (mm) | Slope (deg) | Bouwlaag | NetSurfaceArea (mm2)
2754867 | 04 vierde verdieping | 499696 | 0.0045336 | 4868.17 | 3.69585 | Level: 04 vierde verdieping | 999392
2754914 | 04 vierde verdieping | 444570 | 0.00403246 | 4885.56 | 3.70279 | Level: 04 vierde verdieping | 889141
2755276 | 04 vierde verdieping | 512328 | 0.00464844 | 4983 | 3.69585 | Level: 04 vierde verdieping | 1024657
2755278 | 04 vierde verdieping | 449433 | 0.00407666 | 4593.94 | 3.70279 | Level: 04 vierde verdieping | 898865
2801189 | 04 vierde verdieping | 493092 | 0.00447356 | 4473.56 | 6.83175 | Level: 04 vierde verdieping | 986183
2801191 | 04 vierde verdieping | 492692 | 0.00446992 | 4469.92 | 6.83734 | Level: 04 vierde verdieping | 985383
2852029 | 04 vierde verdieping | 488375 | 0.00443068 | 4430.68 | 3.37816 | Level: 04 vierde verdieping | 976751
2852117 | 04 vierde verdieping | 481065 | 0.00436423 | 4436.52 | 3.37816 | Level: 04 vierde verdieping | 962131
2852222 | 04 vierde verdieping | 493092 | 0.00447356 | 4473.56 | 6.83175 | Level: 04 vierde verdieping | 986183
2852224 | 04 vierde verdieping | 492692 | 0.00446992 | 4469.92 | 6.83734 | Level: 04 vierde verdieping | 985383
2852227 | 04 vierde verdieping | 488375 | 0.00443068 | 4430.68 | 3.37816 | Level: 04 vierde verdieping | 976751
2852229 | 04 vierde verdieping | 493632 | 0.00447847 | 4436.52 | 3.37816 | Level: 04 vierde verdieping | 987264
2852249 | 04 vierde verdieping | 493092 | 0.00447356 | 4473.56 | 6.83175 | Level: 04 vierde verdieping | 986183
2852251 | 04 vierde verdieping | 492692 | 0.00446992 | 4469.92 | 6.83734 | Level: 04 vierde verdieping | 985383
2852253 | 04 vierde verdieping | 488375 | 0.00443068 | 4430.68 | 3.37816 | Level: 04 vierde verdieping | 976751
2852255 | 04 vierde verdieping | 489017 | 0.00443652 | 4436.52 | 3.37816 | Level: 04 vierde verdieping | 978034
4403963 | 05 vijfde verdieping | 742516 | 0.00674105 | 7266.3 | 0.761182 | Level: 05 vijfde verdieping | 1485032
4404926 | 05 vijfde verdieping | 684809 | 0.00621644 | 6524.43 | 0.34672 | Level: 05 vijfde verdieping | 1369617
4405040 | 05 vijfde verdieping | 742516 | 0.00674105 | 7266.3 | 0.761182 | Level: 05 vijfde verdieping | 1485032
4405043 | 05 vijfde verdieping | 684809 | 0.00621644 | 6494.95 | 0.348294 | Level: 05 vijfde verdieping | 1369617
4405086 | 05 vijfde verdieping | 866589 | 0.00786899 | 8229.16 | 0.676631 | Level: 05 vijfde verdieping | 1733178
4405089 | 05 vijfde verdieping | 773440 | 0.00702219 | 7548.32 | 0.299689 | Level: 05 vijfde verdieping | 1546881
4405222 | 05 vijfde verdieping | 869345 | 0.00789404 | 8229.16 | 0.676631 | Level: 05 vijfde verdieping | 1738690
4405224 | 05 vijfde verdieping | 773440 | 0.00702219 | 7548.32 | 0.299689 | Level: 05 vijfde verdieping | 1546881
4405272 | 05 vijfde verdieping | 856920 | 0.00778109 | 8148.79 | 0.676631 | Level: 05 vijfde verdieping | 1713840
4405274 | 05 vijfde verdieping | 765736 | 0.00695215 | 7548.32 | 0.299689 | Level: 05 vijfde verdieping | 1531473
4405276 | 05 vijfde verdieping | 856920 | 0.00778109 | 8148.79 | 0.676631 | Level: 05 vijfde verdieping | 1713840
4405278 | 05 vijfde verdieping | 784186 | 0.00711988 | 7519.29 | 0.300846 | Level: 05 vijfde verdieping | 1568373
4408037 | 05 vijfde verdieping | 578093 | 0.0052463 | 5573.88 | 2.12483 | Level: 05 vijfde verdieping | 1156186
4408039 | 05 vijfde verdieping | 576240 | 0.00522945 | 5557.03 | 0.20621 | Level: 05 vijfde verdieping | 1152479
4408041 | 05 vijfde verdieping | 580780 | 0.00527073 | 5598.31 | 1.02881 | Level: 05 vijfde verdieping | 1161561
4408246 | 05 vijfde verdieping | 578287 | 0.00524807 | 5575.65 | 1.08438 | Level: 05 vijfde verdieping | 1156575
4411615 | 05 vijfde verdieping | 588507 | 0.00534097 | 5668.55 | 0.016791 | Level: 05 vijfde verdieping | 1177014
4411617 | 05 vijfde verdieping | 560451 | 0.00508592 | 5413.5 | 1.42897 | Level: 05 vijfde verdieping | 1120903
4411619 | 05 vijfde verdieping | 565566 | 0.00513242 | 5460 | 0.896659 | Level: 05 vijfde verdieping | 1131132
4411621 | 05 vijfde verdieping | 593559 | 0.0053869 | 5714.48 | 0.974293 | Level: 05 vijfde verdieping | 1187118
5859327 | 02 tweede verdieping | 241262 | 0.0021842 | 2184.2 | 0 | Level: 02 tweede verdieping | 482525
5859329 | 02 tweede verdieping | 241262 | 0.0021842 | 2184.2 | 0 | Level: 02 tweede verdieping | 482525
5859434 | 02 tweede verdieping | 265656 | 0.00240596 | 2405.96 | 0 | Level: 02 tweede verdieping | 531311
5859436 | 02 tweede verdieping | 265656 | 0.00240596 | 2405.96 | 0 | Level: 02 tweede verdieping | 531311
5859687 | 02 tweede verdieping | 265656 | 0.00240596 | 2405.96 | 0 | Level: 02 tweede verdieping | 531311
5859689 | 02 tweede verdieping | 265656 | 0.00240596 | 2405.96 | 0 | Level: 02 tweede verdieping | 531311

# IfcBeam: 28_PBT_SF_staal_strip:strip 100x15 (10)
Type - Pset_BeamCommon - IsExternal: no; LoadBearing: yes
Type - Pset_ProductRequirements - Category: Structural Framing
Type - Pset_ReinforcementBarPitchOfBeam - Description: wvb ǵ 100x15
Type - Pset_Pieters - Breedte: 100 mm; Hoogte: 15 mm; Codering - NL-SfB: 28.11; Omschrijving NL-SfB: hoofddraagconstructies - kolommen en liggers, kolom-/liggerconstructies; Materiaal: 00_PBT_MAT_staal; Description: wvb ǵ 100x15
Classification: 28.11 hoofddraagconstructies - kolommen en liggers, kolom-/liggerconstructies (Uniformat); Material: 00_PBT_MAT_staal
Pset_BeamCommon - Slope: 0 deg; Reference: 28_PBT_SF_staal_strip:strip 100x15
Pset_QuantityTakeOff - Reference: 28_PBT_SF_staal_strip:strip 100x15
Pset_ReinforcementBarPitchOfBeam - Reference: 28_PBT_SF_staal_strip:strip 100x15
Pset_Pieters - Naamgeving element: 28_PBT_SF_staal_strip: strip 100x15; Fase: Nieuw
Name (28_PBT_SF_staal_strip:strip 100x15:...) | In | CrossSectionArea (mm2) | NetVolume (m3) | Span (mm) = Length (mm) | Bouwlaag | NetSurfaceArea (mm2)
5868857 | 00 begane grond | 306612 | 0.00397972 | 2881.53 | Level: 00 begane grond | 613224
5869021 | 00 begane grond | 265830 | 0.00344778 | 2414.9 | Level: 00 begane grond | 531659
5869260 | 00 begane grond | 306612 | 0.00397972 | 2881.53 | Level: 00 begane grond | 613224
5869262 | 00 begane grond | 265830 | 0.00344778 | 2414.9 | Level: 00 begane grond | 531659
5870009 | 00 begane grond | 232535 | 0.00301351 | 2200.32 | Level: 00 begane grond | 465071
5870011 | 00 begane grond | 234054 | 0.00303331 | 2206.92 | Level: 00 begane grond | 468108
5870036 | 00 begane grond | 232467 | 0.00301261 | 2259.88 | Level: 00 begane grond | 464934
5870038 | 00 begane grond | 234054 | 0.00303331 | 2206.92 | Level: 00 begane grond | 468108
5870348 | 01 eerste verdieping | 254718 | 0.00330284 | 2383.92 | Level: 01 eerste verdieping | 509436
5871334 | 01 eerste verdieping | 254718 | 0.00330284 | 2383.92 | Level: 01 eerste verdieping | 509436

# IfcBeam: 28_PBT_SF_staal_strip:strip 10x100 (2)
In: 03 derde verdieping
Type - Pset_BeamCommon - IsExternal: no; LoadBearing: yes
Type - Pset_ProductRequirements - Category: Structural Framing
Type - Pset_ReinforcementBarPitchOfBeam - Description: wvb ǵ 10x100
Type - Pset_Pieters - Breedte: 10 mm; Hoogte: 100 mm; Codering - NL-SfB: 28.11; Omschrijving NL-SfB: hoofddraagconstructies - kolommen en liggers, kolom-/liggerconstructies; Materiaal: 00_PBT_MAT_staal; Description: wvb ǵ 10x100
Classification: 28.11 hoofddraagconstructies - kolommen en liggers, kolom-/liggerconstructies (Uniformat); Material: 00_PBT_MAT_staal
BaseQuantities - CrossSectionArea: 525768 mm2; NetVolume: 0.00477061 m3; Length: 4770.61 mm; NetSurfaceArea: 1051535 mm2
Pset_BeamCommon - Reference: 28_PBT_SF_staal_strip:strip 10x100; Span: 4770.61 mm; Slope: 47.3913 deg
Pset_QuantityTakeOff - Reference: 28_PBT_SF_staal_strip:strip 10x100
Pset_ReinforcementBarPitchOfBeam - Reference: 28_PBT_SF_staal_strip:strip 10x100
Pset_Pieters - Bouwlaag: Level: 03 derde verdieping; Naamgeving element: 28_PBT_SF_staal_strip: strip 10x100; Fase: Nieuw
Name (28_PBT_SF_staal_strip:strip 10x100:...)
4547787
4548062

# IfcBeam: 28_PBT_SF_staal_strip:strip 10x150 (32)
Type - Pset_BeamCommon - IsExternal: no; LoadBearing: yes
Type - Pset_ProductRequirements - Category: Structural Framing
Type - Pset_ReinforcementBarPitchOfBeam - Description: wvb ǵ 10x150
Type - Pset_Pieters - Breedte: 10 mm; Hoogte: 150 mm; Codering - NL-SfB: 28.11; Omschrijving NL-SfB: hoofddraagconstructies - kolommen en liggers, kolom-/liggerconstructies; Materiaal: 00_PBT_MAT_staal; Description: wvb ǵ 10x150
Classification: 28.11 hoofddraagconstructies - kolommen en liggers, kolom-/liggerconstructies (Uniformat); Material: 00_PBT_MAT_staal
Pset_BeamCommon - Reference: 28_PBT_SF_staal_strip:strip 10x150
Pset_QuantityTakeOff - Reference: 28_PBT_SF_staal_strip:strip 10x150
Pset_ReinforcementBarPitchOfBeam - Reference: 28_PBT_SF_staal_strip:strip 10x150
Pset_Pieters - Naamgeving element: 28_PBT_SF_staal_strip: strip 10x150; Fase: Nieuw
Name (28_PBT_SF_staal_strip:strip 10x150:...) | In | CrossSectionArea (mm2) | NetVolume (m3) | Span (mm) = Length (mm) | Slope (deg) | Bouwlaag | NetSurfaceArea (mm2)
2805408 | 00 begane grond | 885285 | 0.00828549 | 6025.85 | 56.2462 | Level: 00 begane grond | 1770571
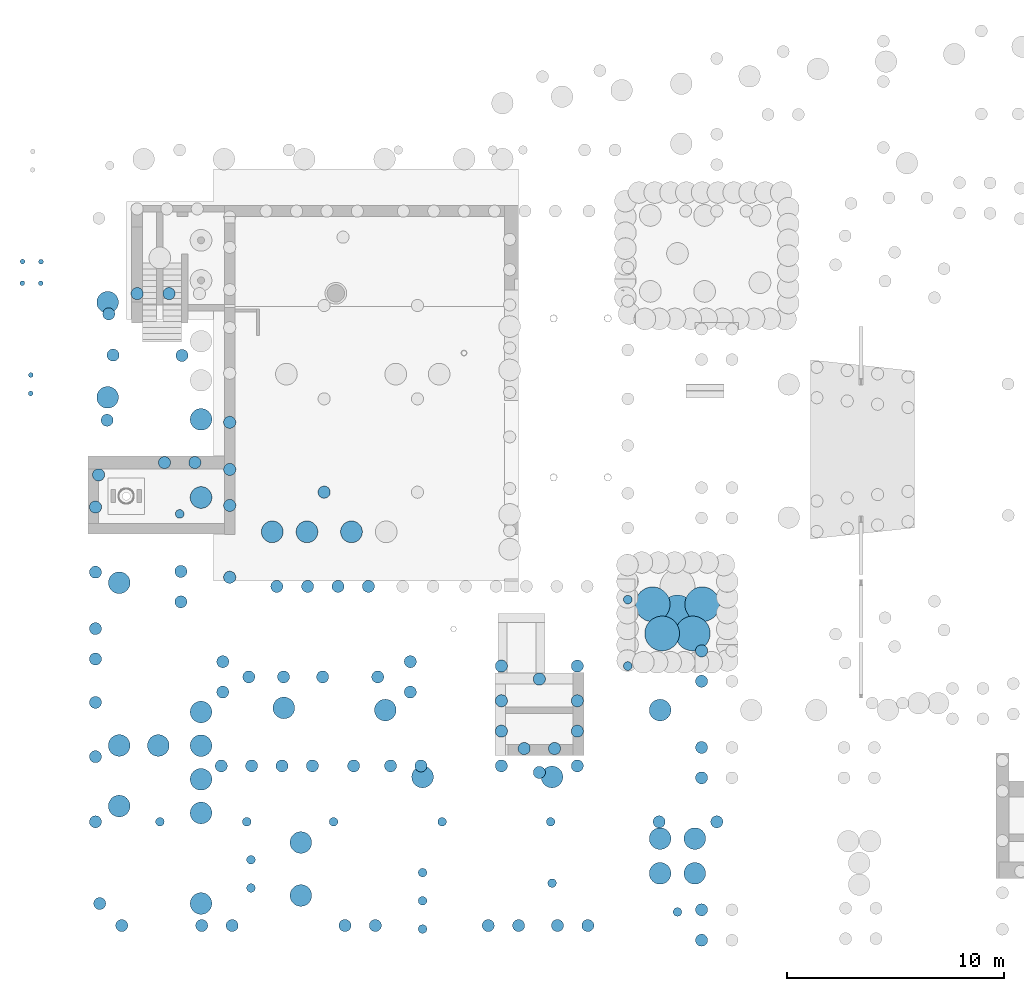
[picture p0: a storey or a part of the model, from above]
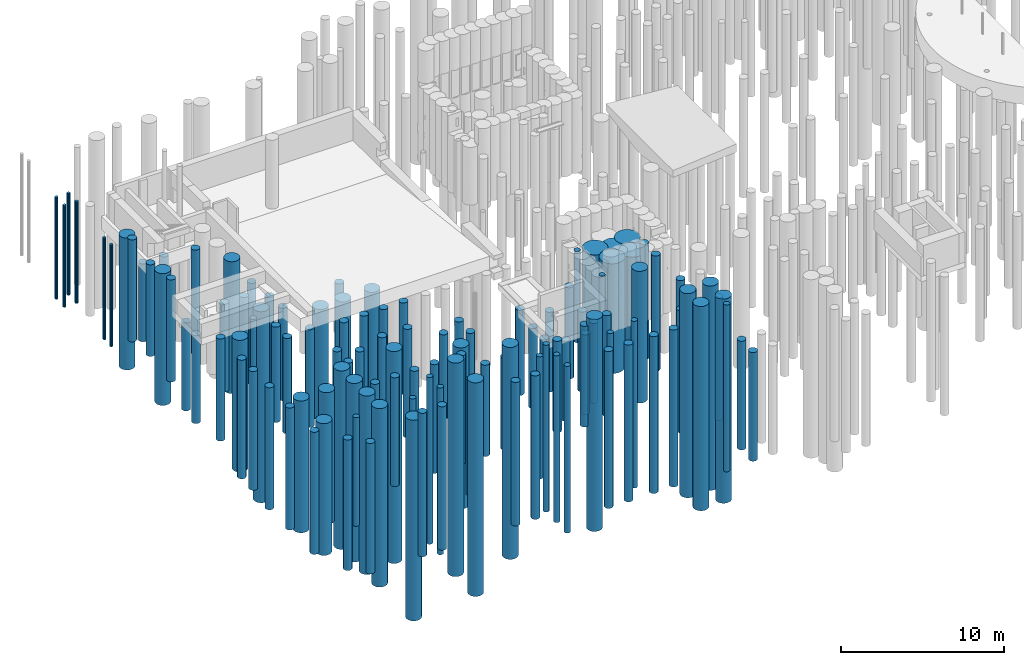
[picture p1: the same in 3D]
Properties of the parts of a building model (IFC2X3), part 8 of 18

# IfcBeam: 28_PBT_SF_staal_strip:strip 10x150 (32)
Name (28_PBT_SF_staal_strip:strip 10x150:...) | In | CrossSectionArea (mm2) | NetVolume (m3) | Span (mm) = Length (mm) | Slope (deg) | Bouwlaag | NetSurfaceArea (mm2)
2805516 | 00 begane grond | 885285 | 0.00828549 | 6025.85 | 56.2462 | Level: 00 begane grond | 1770571
2805634 | 01 eerste verdieping | 690739 | 0.00646162 | 5012.23 | 48.0887 | Level: 01 eerste verdieping | 1381478
2805727 | 01 eerste verdieping | 690739 | 0.00646162 | 5012.23 | 48.0887 | Level: 01 eerste verdieping | 1381478
2805775 | 02 tweede verdieping | 714323 | 0.00668272 | 5162.79 | 49.5715 | Level: 02 tweede verdieping | 1428646
2805777 | 02 tweede verdieping | 713018 | 0.00667048 | 5162.79 | 49.6434 | Level: 02 tweede verdieping | 1426035
2806174 | 03 derde verdieping | 702492 | 0.0065718 | 4883.39 | 46.6365 | Level: 03 derde verdieping | 1404984
2806240 | 03 derde verdieping | 701328 | 0.00656089 | 4876.11 | 46.7171 | Level: 03 derde verdieping | 1402656
2807151 | 00 begane grond | 796153 | 0.00744987 | 5620 | 67.2572 | Level: 00 begane grond | 1592306
2807245 | 01 eerste verdieping | 625852 | 0.0058533 | 4300 | 59.5462 | Level: 01 eerste verdieping | 1251704
2807362 | 02 tweede verdieping | 641852 | 0.0060033 | 4400 | 62.1025 | Level: 02 tweede verdieping | 1283704
2807589 | 03 derde verdieping | 633073 | 0.005921 | 4345.13 | 59.6253 | Level: 03 derde verdieping | 1266147
2807707 | 00 begane grond | 780605 | 0.00730411 | 5620 | 67.2572 | Level: 00 begane grond | 1561210
2807710 | 01 eerste verdieping | 625852 | 0.0058533 | 4300 | 59.5462 | Level: 01 eerste verdieping | 1251704
2807854 | 01 eerste verdieping | 625852 | 0.0058533 | 4300 | 59.5462 | Level: 01 eerste verdieping | 1251704
2807857 | 02 tweede verdieping | 647734 | 0.00605845 | 4436.77 | 62.1025 | Level: 02 tweede verdieping | 1295469
2807860 | 03 derde verdieping | 600252 | 0.0056133 | 4140 | 59.6253 | Level: 03 derde verdieping | 1200504
2807869 | 01 eerste verdieping | 625852 | 0.0058533 | 4300 | 59.5462 | Level: 01 eerste verdieping | 1251704
2811694 | 00 begane grond | 790829 | 0.00739996 | 4933.3 | 51.4623 | Level: 00 begane grond | 1581658
2811919 | 00 begane grond | 783378 | 0.0073301 | 4886.74 | 51.3709 | Level: 00 begane grond | 1566756
2812077 | 01 eerste verdieping | 699804 | 0.0065466 | 5012.23 | 48.0887 | Level: 01 eerste verdieping | 1399609
2812167 | 02 tweede verdieping | 723895 | 0.00677245 | 5162.79 | 49.584 | Level: 02 tweede verdieping | 1447790
2812269 | 03 derde verdieping | 675448 | 0.00631826 | 4860 | 46.6386 | Level: 03 derde verdieping | 1350896
2812359 | 01 eerste verdieping | 699804 | 0.0065466 | 5012.23 | 48.0887 | Level: 01 eerste verdieping | 1399609
2834286 | 03 derde verdieping | 625852 | 0.0058533 | 4300 | 60.0237 | Level: 03 derde verdieping | 1251704
2853790 | 02 tweede verdieping | 657852 | 0.0061533 | 4500 | 60.9327 | Level: 02 tweede verdieping | 1315704
2853912 | 03 derde verdieping | 557695 | 0.00521433 | 3880 | 60.0237 | Level: 03 derde verdieping | 1115390
2854320 | 02 tweede verdieping | 708610 | 0.00662915 | 5162.79 | 49.6096 | Level: 02 tweede verdieping | 1417219
2854369 | 03 derde verdieping | 665308 | 0.0062232 | 4880 | 46.5417 | Level: 03 derde verdieping | 1330616
2854968 | 02 tweede verdieping | 657852 | 0.0061533 | 4500 | 60.9327 | Level: 02 tweede verdieping | 1315704
5402115 | 00 begane grond | 776378 | 0.00726448 | 5360 | 67.2572 | Level: 00 begane grond | 1552756
5402285 | 00 begane grond | 675971 | 0.00632316 | 5360 | 67.2572 | Level: 00 begane grond | 1351942

# IfcBeam: 28_PBT_SF_staal_strip:strip 10x60 (8)
In: 04 vierde verdieping
Type - Pset_BeamCommon - IsExternal: no; LoadBearing: yes
Type - Pset_ProductRequirements - Category: Structural Framing
Type - Pset_ReinforcementBarPitchOfBeam - Description: wvb ǵ 10x60
Type - Pset_Pieters - Breedte: 10 mm; Hoogte: 60 mm; Codering - NL-SfB: 28.11; Omschrijving NL-SfB: hoofddraagconstructies - kolommen en liggers, kolom-/liggerconstructies; Materiaal: 00_PBT_MAT_staal; Description: wvb ǵ 10x60
Classification: 28.11 hoofddraagconstructies - kolommen en liggers, kolom-/liggerconstructies (Uniformat); Material: 00_PBT_MAT_staal
Pset_BeamCommon - Reference: 28_PBT_SF_staal_strip:strip 10x60
Pset_QuantityTakeOff - Reference: 28_PBT_SF_staal_strip:strip 10x60
Pset_ReinforcementBarPitchOfBeam - Reference: 28_PBT_SF_staal_strip:strip 10x60
Pset_Pieters - Bouwlaag: Level: 04 vierde verdieping; Naamgeving element: 28_PBT_SF_staal_strip: strip 10x60; Fase: Nieuw
Name (28_PBT_SF_staal_strip:strip 10x60:...) | CrossSectionArea (mm2) | NetVolume (m3) | Span (mm) = Length (mm) | Slope (deg) | NetSurfaceArea (mm2)
4546061 | 247000 | 0.002112 | 3520 | 12.7584 | 494000
4546506 | 247000 | 0.002112 | 3520 | 12.7584 | 494000
4546905 | 235417 | 0.00201272 | 3354.53 | 13.5955 | 470834
4547033 | 226000 | 0.001932 | 3220 | 13.5983 | 452000
4547340 | 227400 | 0.001944 | 3240 | 13.5955 | 454800
4547343 | 228800 | 0.001956 | 3260 | 13.5983 | 457600
4547382 | 247000 | 0.002112 | 3520 | 12.7584 | 494000
4547385 | 247000 | 0.002112 | 3520 | 12.7584 | 494000

# IfcBeam: 28_PBT_SF_staal_strip:strip 15x95, 28_PBT_SF_staal_strip:strip 15x95:4264194
In: 03 derde verdieping
Type - Pset_BeamCommon - IsExternal: no; LoadBearing: yes
Type - Pset_ProductRequirements - Category: Structural Framing
Type - Pset_ReinforcementBarPitchOfBeam - Description: wvb ǵ 15x95
Type - Pset_Pieters - Breedte: 15 mm; Hoogte: 95 mm; Codering - NL-SfB: 28.11; Omschrijving NL-SfB: hoofddraagconstructies - kolommen en liggers, kolom-/liggerconstructies; Materiaal: 00_PBT_MAT_staal; Description: wvb ǵ 15x95
Classification: 28.11 hoofddraagconstructies - kolommen en liggers, kolom-/liggerconstructies (Uniformat); Material: 00_PBT_MAT_staal
BaseQuantities - CrossSectionArea: 282447 mm2; NetVolume: 0.00364051 m3; Length: 2554.74 mm; NetSurfaceArea: 564894 mm2
Pset_BeamCommon - Slope: 0 deg; Reference: 28_PBT_SF_staal_strip:strip 15x95; Span: 2554.74 mm
Pset_QuantityTakeOff - Reference: 28_PBT_SF_staal_strip:strip 15x95
Pset_ReinforcementBarPitchOfBeam - Reference: 28_PBT_SF_staal_strip:strip 15x95
Pset_Pieters - Bouwlaag: Level: 03 derde verdieping; Naamgeving element: 28_PBT_SF_staal_strip: strip 15x95; Fase: Nieuw

# IfcBeam: 28_PBT_SF_staal_strip:strip 200x30_opgelaste plaat (12)
Type - Pset_BeamCommon - IsExternal: no; LoadBearing: yes
Type - Pset_ProductRequirements - Category: Structural Framing
Type - Pset_ReinforcementBarPitchOfBeam - Description: opgelaste plaat ǵ 200x30
Type - Pset_Pieters - Breedte: 200 mm; Hoogte: 30 mm; Codering - NL-SfB: 28.11; Omschrijving NL-SfB: hoofddraagconstructies - kolommen en liggers, kolom-/liggerconstructies; Materiaal: 00_PBT_MAT_staal; Description: opgelaste plaat ǵ 200x30
Classification: 28.11 hoofddraagconstructies - kolommen en liggers, kolom-/liggerconstructies (Uniformat); Material: 00_PBT_MAT_staal
BaseQuantities - CrossSectionArea: 52000 mm2; NetVolume: 0.0012 m3; Length: 200 mm; NetSurfaceArea: 104000 mm2
Pset_BeamCommon - Slope: 0 deg; Reference: 28_PBT_SF_staal_strip:strip 200x30_opgelaste plaat; Span: 200 mm
Pset_QuantityTakeOff - Reference: 28_PBT_SF_staal_strip:strip 200x30_opgelaste plaat
Pset_ReinforcementBarPitchOfBeam - Reference: 28_PBT_SF_staal_strip:strip 200x30_opgelaste plaat
Pset_Pieters - Naamgeving element: 28_PBT_SF_staal_strip: strip 200x30_opgelaste plaat; Fase: Nieuw
Name (28_PBT_SF_staal_strip:strip 200x30_opgelaste plaat:...) | In | Bouwlaag
5850602 | 01 eerste verdieping | Level: 01 eerste verdieping
5850980 | 01 eerste verdieping | Level: 01 eerste verdieping
5851088 | 01 eerste verdieping | Level: 01 eerste verdieping
5851308 | 01 eerste verdieping | Level: 01 eerste verdieping
5851393 | 01 eerste verdieping | Level: 01 eerste verdieping
5851395 | 01 eerste verdieping | Level: 01 eerste verdieping
6472001 | 02 tweede verdieping | Level: 02 tweede verdieping
6472003 | 02 tweede verdieping | Level: 02 tweede verdieping
6472005 | 02 tweede verdieping | Level: 02 tweede verdieping
6472007 | 02 tweede verdieping | Level: 02 tweede verdieping
6472009 | 02 tweede verdieping | Level: 02 tweede verdieping
6472011 | 02 tweede verdieping | Level: 02 tweede verdieping

# IfcBeam: 28_PBT_SF_staal_strip:strip 270x15, 28_PBT_SF_staal_strip:strip 270x15:3505815
In: 04 vierde verdieping
Type - Pset_BeamCommon - IsExternal: no; LoadBearing: yes
Type - Pset_ProductRequirements - Category: Structural Framing
Type - Pset_ReinforcementBarPitchOfBeam - Description: plaat ǵ 270x15
Type - Pset_Pieters - Breedte: 270 mm; Hoogte: 15 mm; Codering - NL-SfB: 28.11; Omschrijving NL-SfB: hoofddraagconstructies - kolommen en liggers, kolom-/liggerconstructies; Materiaal: 00_PBT_MAT_staal; Description: plaat ǵ 270x15
Classification: 28.11 hoofddraagconstructies - kolommen en liggers, kolom-/liggerconstructies (Uniformat); Material: 00_PBT_MAT_staal
BaseQuantities - CrossSectionArea: 748180 mm2; NetVolume: 0.0105745 m3; Length: 2610.98 mm; NetSurfaceArea: 1496361 mm2
Pset_BeamCommon - Slope: 0 deg; Reference: 28_PBT_SF_staal_strip:strip 270x15; Span: 2610.98 mm
Pset_QuantityTakeOff - Reference: 28_PBT_SF_staal_strip:strip 270x15
Pset_ReinforcementBarPitchOfBeam - Reference: 28_PBT_SF_staal_strip:strip 270x15
Pset_Pieters - Bouwlaag: Level: 04 vierde verdieping; Naamgeving element: 28_PBT_SF_staal_strip: strip 270x15; Fase: Nieuw

# IfcBeam: 28_PBT_SF_staal_strip:strip 6x100 (12)
Type - Pset_BeamCommon - IsExternal: no; LoadBearing: yes
Type - Pset_ProductRequirements - Category: Structural Framing
Type - Pset_ReinforcementBarPitchOfBeam - Description: wvb ǵ 6x100
Type - Pset_Pieters - Breedte: 6 mm; Hoogte: 100 mm; Codering - NL-SfB: 28.11; Omschrijving NL-SfB: hoofddraagconstructies - kolommen en liggers, kolom-/liggerconstructies; Materiaal: 00_PBT_MAT_staal; Description: wvb ǵ 6x100
Classification: 28.11 hoofddraagconstructies - kolommen en liggers, kolom-/liggerconstructies (Uniformat); Material: 00_PBT_MAT_staal
Pset_BeamCommon - Reference: 28_PBT_SF_staal_strip:strip 6x100
Pset_QuantityTakeOff - Reference: 28_PBT_SF_staal_strip:strip 6x100
Pset_ReinforcementBarPitchOfBeam - Reference: 28_PBT_SF_staal_strip:strip 6x100
Pset_Pieters - Naamgeving element: 28_PBT_SF_staal_strip: strip 6x100; Fase: Nieuw
Name (28_PBT_SF_staal_strip:strip 6x100:...) | In | CrossSectionArea (mm2) | NetVolume (m3) | Span (mm) = Length (mm) | Slope (deg) | Bouwlaag | NetSurfaceArea (mm2)
2274010 | 01 eerste verdieping | 634242 | 0.00358665 | 6380 | 51.6375 | Level: 01 eerste verdieping | 1268484
2275544 | 01 eerste verdieping | 677385 | 0.00383086 | 6700 | 47.913 | Level: 01 eerste verdieping | 1354769
2275829 | 02 tweede verdieping | 672011 | 0.00380044 | 6800 | 54.807 | Level: 02 tweede verdieping | 1344023
2275960 | 02 tweede verdieping | 718122 | 0.00406145 | 6960 | 51.0995 | Level: 02 tweede verdieping | 1436244
3564761 | 01 eerste verdieping | 549113 | 0.00310479 | 5320 | 40.8133 | Level: 01 eerste verdieping | 1098226
3564764 | 01 eerste verdieping | 531557 | 0.00300542 | 5389.53 | 40.7771 | Level: 01 eerste verdieping | 1063114
3569489 | 02 tweede verdieping | 621623 | 0.00351522 | 5858.7 | 68.7092 | Level: 02 tweede verdieping | 1243245
3569492 | 02 tweede verdieping | 621617 | 0.00351519 | 5858.66 | 68.8038 | Level: 02 tweede verdieping | 1243235
3569524 | 02 tweede verdieping | 625716 | 0.00353839 | 5897.32 | 66.98 | Level: 02 tweede verdieping | 1251433
3569527 | 02 tweede verdieping | 629709 | 0.00356099 | 5934.99 | 66.9681 | Level: 02 tweede verdieping | 1259417
3570429 | 02 tweede verdieping | 678652 | 0.00383803 | 6396.72 | 59.6841 | Level: 02 tweede verdieping | 1357304
3570432 | 02 tweede verdieping | 673208 | 0.00380721 | 6345.36 | 59.5238 | Level: 02 tweede verdieping | 1346416

# IfcBeam: 28_PBT_SF_staal_strip:strip 6x60 (24)
Type - Pset_BeamCommon - IsExternal: no; LoadBearing: yes
Type - Pset_ProductRequirements - Category: Structural Framing
Type - Pset_ReinforcementBarPitchOfBeam - Description: wvb ǵ 6x60
Type - Pset_Pieters - Breedte: 6 mm; Hoogte: 60 mm; Codering - NL-SfB: 28.11; Omschrijving NL-SfB: hoofddraagconstructies - kolommen en liggers, kolom-/liggerconstructies; Materiaal: 00_PBT_MAT_staal; Description: wvb ǵ 6x60
Classification: 28.11 hoofddraagconstructies - kolommen en liggers, kolom-/liggerconstructies (Uniformat); Material: 00_PBT_MAT_staal
Pset_BeamCommon - Reference: 28_PBT_SF_staal_strip:strip 6x60
Pset_QuantityTakeOff - Reference: 28_PBT_SF_staal_strip:strip 6x60
Pset_ReinforcementBarPitchOfBeam - Reference: 28_PBT_SF_staal_strip:strip 6x60
Pset_Pieters - Naamgeving element: 28_PBT_SF_staal_strip: strip 6x60; Fase: Nieuw
Name (28_PBT_SF_staal_strip:strip 6x60:...) | In | CrossSectionArea (mm2) | NetVolume (m3) | Span (mm) = Length (mm) | Slope (deg) | Bouwlaag | NetSurfaceArea (mm2)
2749070 | 02 tweede verdieping | 330360 | 0.0018 | 5000 | 34.5066 | Level: 02 tweede verdieping | 660720
2749138 | 02 tweede verdieping | 322440 | 0.0017568 | 4880 | 34.4502 | Level: 02 tweede verdieping | 644880
2749456 | 02 tweede verdieping | 326400 | 0.0017784 | 4940 | 34.5066 | Level: 02 tweede verdieping | 652800
2749459 | 02 tweede verdieping | 323760 | 0.001764 | 4900 | 34.4502 | Level: 02 tweede verdieping | 647520
3570763 | 02 tweede verdieping | 224760 | 0.001224 | 3400 | 52.2148 | Level: 02 tweede verdieping | 449520
3570766 | 02 tweede verdieping | 277560 | 0.001512 | 4200 | 40.9904 | Level: 02 tweede verdieping | 555120
3571221 | 02 tweede verdieping | 237960 | 0.001296 | 3600 | 52.2148 | Level: 02 tweede verdieping | 475920
3571224 | 02 tweede verdieping | 284160 | 0.001548 | 4300 | 40.9904 | Level: 02 tweede verdieping | 568320
3828466 | 02 tweede verdieping | 268696 | 0.00146365 | 4380 | 36.5462 | Level: 02 tweede verdieping | 537392
3828591 | 02 tweede verdieping | 212882 | 0.00115921 | 3554.75 | 47.7317 | Level: 02 tweede verdieping | 425764
3828774 | 02 tweede verdieping | 239280 | 0.0013032 | 3620 | 52.2148 | Level: 02 tweede verdieping | 478560
3828856 | 02 tweede verdieping | 286800 | 0.0015624 | 4340 | 40.9904 | Level: 02 tweede verdieping | 573600
3828955 | 02 tweede verdieping | 212509 | 0.00115718 | 3580 | 47.8546 | Level: 02 tweede verdieping | 425018
3829047 | 02 tweede verdieping | 267827 | 0.00145891 | 4400 | 36.5982 | Level: 02 tweede verdieping | 535654
3829609 | 02 tweede verdieping | 320397 | 0.00174565 | 5120 | 30.3513 | Level: 02 tweede verdieping | 640793
3829611 | 02 tweede verdieping | 316212 | 0.00172283 | 5180 | 30.3435 | Level: 02 tweede verdieping | 632424
3830248 | 03 derde verdieping | 263052 | 0.00143287 | 4120 | 36.5462 | Level: 03 derde verdieping | 526104
3830250 | 03 derde verdieping | 212882 | 0.00115921 | 3534.89 | 47.7317 | Level: 03 derde verdieping | 425764
3830252 | 02 tweede verdieping | 239280 | 0.0013032 | 3620 | 52.2148 | Level: 02 tweede verdieping | 478560
3830254 | 02 tweede verdieping | 286800 | 0.0015624 | 4340 | 40.9904 | Level: 02 tweede verdieping | 573600
3830256 | 03 derde verdieping | 212132 | 0.00115512 | 3560 | 47.8546 | Level: 03 derde verdieping | 424264
3830258 | 03 derde verdieping | 261993 | 0.00142709 | 4400 | 36.5982 | Level: 03 derde verdieping | 523987
3830260 | 03 derde verdieping | 318464 | 0.00173511 | 5120 | 30.3513 | Level: 03 derde verdieping | 636927
3830262 | 03 derde verdieping | 319531 | 0.00174093 | 5200 | 30.3435 | Level: 03 derde verdieping | 639062

# IfcBeam: 28_PBT_SF_staal_strip:strip 70x7 (6)
In: 04 vierde verdieping
Type - Pset_BeamCommon - IsExternal: no; LoadBearing: yes
Type - Pset_ProductRequirements - Category: Structural Framing
Type - Pset_ReinforcementBarPitchOfBeam - Description: wvb ǵ 70x7
Type - Pset_Pieters - Breedte: 70 mm; Hoogte: 7 mm; Codering - NL-SfB: 28.11; Omschrijving NL-SfB: hoofddraagconstructies - kolommen en liggers, kolom-/liggerconstructies; Materiaal: 00_PBT_MAT_staal; Description: wvb ǵ 70x7
Classification: 28.11 hoofddraagconstructies - kolommen en liggers, kolom-/liggerconstructies (Uniformat); Material: 00_PBT_MAT_staal
Pset_BeamCommon - Slope: 0 deg; Reference: 28_PBT_SF_staal_strip:strip 70x7
Pset_QuantityTakeOff - Reference: 28_PBT_SF_staal_strip:strip 70x7
Pset_ReinforcementBarPitchOfBeam - Reference: 28_PBT_SF_staal_strip:strip 70x7
Pset_Pieters - Bouwlaag: Level: 04 vierde verdieping; Naamgeving element: 28_PBT_SF_staal_strip: strip 70x7; Fase: Nieuw
Name (28_PBT_SF_staal_strip:strip 70x7:...) | CrossSectionArea (mm2) | NetVolume (m3) | Span (mm) = Length (mm) | NetSurfaceArea (mm2)
2972912 | 589683 | 0.00374941 | 7651.85 | 1179366
2973385 | 702025 | 0.00446431 | 9110.85 | 1404050
2973404 | 525274 | 0.00333953 | 6815.37 | 1050547
2973408 | 525481 | 0.00334085 | 6818.07 | 1050962
2973547 | 698814 | 0.00444388 | 9069.14 | 1397627
2973549 | 585846 | 0.00372499 | 7602.03 | 1171693

# IfcBeam: 28_PBT_SF_staal_strip:strip 8x80 (26)
Type - Pset_BeamCommon - IsExternal: no; LoadBearing: yes
Type - Pset_ProductRequirements - Category: Structural Framing
Type - Pset_ReinforcementBarPitchOfBeam - Description: wvb ǵ 8x80
Type - Pset_Pieters - Breedte: 8 mm; Hoogte: 80 mm; Codering - NL-SfB: 28.11; Omschrijving NL-SfB: hoofddraagconstructies - kolommen en liggers, kolom-/liggerconstructies; Materiaal: 00_PBT_MAT_staal; Description: wvb ǵ 8x80
Classification: 28.11 hoofddraagconstructies - kolommen en liggers, kolom-/liggerconstructies (Uniformat); Material: 00_PBT_MAT_staal
Pset_BeamCommon - Reference: 28_PBT_SF_staal_strip:strip 8x80
Pset_QuantityTakeOff - Reference: 28_PBT_SF_staal_strip:strip 8x80
Pset_ReinforcementBarPitchOfBeam - Reference: 28_PBT_SF_staal_strip:strip 8x80
Pset_Pieters - Naamgeving element: 28_PBT_SF_staal_strip: strip 8x80; Fase: Nieuw
Name (28_PBT_SF_staal_strip:strip 8x80:...) | In | CrossSectionArea (mm2) | NetVolume (m3) | Span (mm) = Length (mm) | Slope (deg) | Bouwlaag | NetSurfaceArea (mm2)
3820927 | 04 vierde verdieping | 304283 | 0.00220831 | 3706.76 | 49.6827 | Level: 04 vierde verdieping | 608565
3821098 | 04 vierde verdieping | 291108 | 0.0021125 | 3600 | 47.8156 | Level: 04 vierde verdieping | 582217
3821387 | 04 vierde verdieping | 356160 | 0.0025856 | 4040 | 39.6104 | Level: 04 vierde verdieping | 712320
3821450 | 04 vierde verdieping | 363200 | 0.0026368 | 4120 | 39.6101 | Level: 04 vierde verdieping | 726400
3821609 | 04 vierde verdieping | 356160 | 0.0025856 | 4040 | 39.6104 | Level: 04 vierde verdieping | 712320
3821612 | 04 vierde verdieping | 363200 | 0.0026368 | 4120 | 39.6101 | Level: 04 vierde verdieping | 726400
3821707 | 04 vierde verdieping | 360930 | 0.00262029 | 4094.2 | 39.5861 | Level: 04 vierde verdieping | 721860
3821711 | 04 vierde verdieping | 365857 | 0.00265613 | 4150.2 | 39.6358 | Level: 04 vierde verdieping | 731714
3821713 | 04 vierde verdieping | 361370 | 0.00262349 | 4099.2 | 39.5861 | Level: 04 vierde verdieping | 722740
3821715 | 04 vierde verdieping | 366264 | 0.00265908 | 4154.82 | 39.6358 | Level: 04 vierde verdieping | 732528
3824990 | 06 zesde verdieping | 254127 | 0.00184354 | 2960 | 40.621 | Level: 06 zesde verdieping | 508254
3825188 | 06 zesde verdieping | 246584 | 0.00178868 | 2900 | 40.7278 | Level: 06 zesde verdieping | 493167
3826446 | 06 zesde verdieping | 256767 | 0.00186274 | 2990 | 40.621 | Level: 06 zesde verdieping | 513534
3826450 | 06 zesde verdieping | 258354 | 0.00187428 | 3000 | 40.7278 | Level: 06 zesde verdieping | 516707
3826820 | 06 zesde verdieping | 343840 | 0.002496 | 3900 | 29.0634 | Level: 06 zesde verdieping | 687680
3826954 | 06 zesde verdieping | 342080 | 0.0024832 | 3880 | 29.082 | Level: 06 zesde verdieping | 684160
3827100 | 06 zesde verdieping | 323991 | 0.00235164 | 3674.44 | 32.0688 | Level: 06 zesde verdieping | 647982
3827104 | 06 zesde verdieping | 324920 | 0.0023584 | 3685 | 32.0466 | Level: 06 zesde verdieping | 649840
3827523 | 06 zesde verdieping | 361440 | 0.002624 | 4100 | 39.9349 | Level: 06 zesde verdieping | 722880
3827627 | 06 zesde verdieping | 364960 | 0.0026496 | 4140 | 39.9349 | Level: 06 zesde verdieping | 729920
3827793 | 06 zesde verdieping | 361440 | 0.002624 | 4100 | 39.9349 | Level: 06 zesde verdieping | 722880
3827796 | 06 zesde verdieping | 364960 | 0.0026496 | 4140 | 39.9349 | Level: 06 zesde verdieping | 729920
4313996 | 06 zesde verdieping | 326240 | 0.002368 | 3700 | 31.7928 | Level: 06 zesde verdieping | 652480
4314121 | 06 zesde verdieping | 320960 | 0.0023296 | 3640 | 31.7928 | Level: 06 zesde verdieping | 641920
4314332 | 06 zesde verdieping | 326240 | 0.002368 | 3700 | 31.7928 | Level: 06 zesde verdieping | 652480
4314335 | 06 zesde verdieping | 320960 | 0.0023296 | 3640 | 31.7928 | Level: 06 zesde verdieping | 641920

# IfcBeam: 28_PBT_SF_staal_strip:trekstrip 20x200 (20)
Type - Pset_BeamCommon - IsExternal: no; LoadBearing: yes
Type - Pset_ProductRequirements - Category: Structural Framing
Type - Pset_ReinforcementBarPitchOfBeam - Description: trekstrip ǵ 20x200
Type - Pset_Pieters - Breedte: 20 mm; Hoogte: 200 mm; Codering - NL-SfB: 28.11; Omschrijving NL-SfB: hoofddraagconstructies - kolommen en liggers, kolom-/liggerconstructies; Materiaal: 00_PBT_MAT_staal; Description: trekstrip ǵ 20x200
Classification: 28.11 hoofddraagconstructies - kolommen en liggers, kolom-/liggerconstructies (Uniformat); Material: 00_PBT_MAT_staal
Pset_BeamCommon - Slope: 0 deg; Reference: 28_PBT_SF_staal_strip:trekstrip 20x200
Pset_QuantityTakeOff - Reference: 28_PBT_SF_staal_strip:trekstrip 20x200
Pset_ReinforcementBarPitchOfBeam - Reference: 28_PBT_SF_staal_strip:trekstrip 20x200
Pset_Pieters - Naamgeving element: 28_PBT_SF_staal_strip: trekstrip 20x200; Fase: Nieuw; Comments: boven deursparing
Name (28_PBT_SF_staal_strip:trekstrip 20x200:...) | In | CrossSectionArea (mm2) | NetVolume (m3) | Span (mm) = Length (mm) | Bouwlaag | NetSurfaceArea (mm2)
5363791 | 03 derde verdieping | 1154807 | 0.0209238 | 5230.94 | Level: 03 derde verdieping | 2309613
5364147 | 04 vierde verdieping | 1459232 | 0.0264588 | 6614.69 | Level: 04 vierde verdieping | 2918463
5399096 | 03 derde verdieping | 1154807 | 0.0209238 | 5230.94 | Level: 03 derde verdieping | 2309613
5399103 | 04 vierde verdieping | 1459232 | 0.0264588 | 6614.69 | Level: 04 vierde verdieping | 2918463
5452318 | 03 derde verdieping | 1459232 | 0.0264588 | 6614.69 | Level: 03 derde verdieping | 2918463
5452443 | 02 tweede verdieping | 1154807 | 0.0209238 | 5230.94 | Level: 02 tweede verdieping | 2309613
5452637 | 02 tweede verdieping | 1154807 | 0.0209238 | 5230.94 | Level: 02 tweede verdieping | 2309613
5452679 | 03 derde verdieping | 1407600 | 0.02552 | 6380 | Level: 03 derde verdieping | 2815200
5453166 | 03 derde verdieping | 1154807 | 0.0209238 | 5230.94 | Level: 03 derde verdieping | 2309613
5453169 | 04 vierde verdieping | 1459232 | 0.0264588 | 6614.69 | Level: 04 vierde verdieping | 2918463
5453171 | 03 derde verdieping | 1459232 | 0.0264588 | 6614.69 | Level: 03 derde verdieping | 2918463
5453248 | 03 derde verdieping | 1154807 | 0.0209238 | 5230.94 | Level: 03 derde verdieping | 2309613
5453250 | 04 vierde verdieping | 1459232 | 0.0264588 | 6614.69 | Level: 04 vierde verdieping | 2918463
5453252 | 03 derde verdieping | 1412000 | 0.0256 | 6400 | Level: 03 derde verdieping | 2824000
5772031 | 00 begane grond | 777783 | 0.0140688 | 3517.2 | Level: 00 begane grond | 1555566
5772033 | 00 begane grond | 777783 | 0.0140688 | 3517.2 | Level: 00 begane grond | 1555566
5772035 | 00 begane grond | 777783 | 0.0140688 | 3517.2 | Level: 00 begane grond | 1555566
5772246 | 00 begane grond | 777783 | 0.0140688 | 3517.2 | Level: 00 begane grond | 1555566
5772248 | 00 begane grond | 777783 | 0.0140688 | 3517.2 | Level: 00 begane grond | 1555566
5772250 | 00 begane grond | 777783 | 0.0140688 | 3517.2 | Level: 00 begane grond | 1555566

# IfcBeam: 28_PBT_SF_staal_trapboom_glas:trapboom (12)
Type - PredefinedType: BEAM; Classification: 28.11 hoofddraagconstructies - kolommen en liggers, kolom-/liggerconstructies (Uniformat); Material: 00_PBT_MAT_staal_S355
Type - Pset_BeamCommon - IsExternal: no; LoadBearing: yes
Type - Pset_ProductRequirements - Category: Structural Framing
Type - Pset_ReinforcementBarPitchOfBeam - Description: trapboom
Type - Pset_Pieters - Breedte: 30 mm; Codering - NL-SfB: 28.11; Omschrijving NL-SfB: hoofddraagconstructies - kolommen en liggers, kolom-/liggerconstructies; Materiaal: 00_PBT_MAT_staal_S355; Description: trapboom
Pset_BeamCommon - Reference: 28_PBT_SF_staal_trapboom_glas:trapboom
Pset_QuantityTakeOff - Reference: 28_PBT_SF_staal_trapboom_glas:trapboom
Pset_ReinforcementBarPitchOfBeam - Reference: 28_PBT_SF_staal_trapboom_glas:trapboom
Pset_Pieters - Naamgeving element: 28_PBT_SF_staal_trapboom_glas: trapboom; Fase: Nieuw
Name (28_PBT_SF_staal_trapboom_glas:trapboom:...) | In | Span (mm) = Length (mm) | Slope (deg) | Bouwlaag | CrossSectionArea (mm2) | OuterSurfaceArea (mm2) | GrossSurfaceArea (mm2) | GrossVolume (m3) | NetVolume (m3) | NetSurfaceArea (mm2)
5496641 | -1 kelder | 7720 | 30.1772 | Level: -1 kelder | 4781347 | 4286872 | 4305472 | 0.0586293 | 0.120691 | 9562694
5501805 | 00 begane grond | 8583.94 | 29.9854 | Level: 00 begane grond | 5695258 | 5033894 | 5052494 | 0.0688459 | 0.144001 | 11390516
5501808 | -1 kelder | 7720 | 30.1772 | Level: -1 kelder | 4759777 | 4286872 | 4305472 | 0.0586293 | 0.120321 | 9519555
5501810 | 01 eerste verdieping | 4573.59 | 29.9854 | Level: 01 eerste verdieping | 2166444 | 1927280 | 1945880 | 0.0263584 | 0.054474 | 4332888
5501836 | 01 eerste verdieping | 2340 | 0 | Level: 01 eerste verdieping | 1349946 | 1215461 | 1234061 | 0.0166232 | 0.0337475 | 2699893
5503405 | -1 kelder | 7720 | 30.1772 | Level: -1 kelder | 4790736 | 4280514 | 4299114 | 0.0585423 | 0.121116 | 9581472
5508329 | 00 begane grond | 4800 | 0 | Level: 00 begane grond | 3498032 | 3061751 | 3080351 | 0.0418739 | 0.0883026 | 6996063
5508782 | 01 eerste verdieping | 2260 | 0 | Level: 01 eerste verdieping | 1349946 | 1215461 | 1234061 | 0.0166232 | 0.0337475 | 2699893
5508818 | 01 eerste verdieping | 4573.59 | 29.9854 | Level: 01 eerste verdieping | 2166444 | 1927280 | 1945880 | 0.0263584 | 0.054474 | 4332888
5869304 | 00 begane grond | 2544.38 | 0 | Level: 00 begane grond | 1955507 | 1687540 | 1706140 | 0.0230796 | 0.0491372 | 3911015
6336705 | 01 eerste verdieping | 462.388 | 0 | Level: 01 eerste verdieping | 262800 | 240937 | 259537 | 0.00329517 | 0.00617754 | 525601
6337207 | 01 eerste verdieping | 462.388 | 0 | Level: 01 eerste verdieping | 262800 | 240937 | 259537 | 0.00329517 | 0.00617754 | 525601

# IfcBeam: 28_PBT_SF_staal_trapboom_glas:trapboom, 28_PBT_SF_staal_trapboom_glas:trapboom:5508729
In: 00 begane grond
Type - PredefinedType: BEAM; Classification: 28.11 hoofddraagconstructies - kolommen en liggers, kolom-/liggerconstructies (Uniformat); Material: 00_PBT_MAT_staal_S355 (7)
Type - Pset_BeamCommon - IsExternal: no; LoadBearing: yes
Type - Pset_ProductRequirements - Category: Structural Framing
Type - Pset_ReinforcementBarPitchOfBeam - Description: trapboom
Type - Pset_Pieters - Breedte: 30 mm; Codering - NL-SfB: 28.11; Omschrijving NL-SfB: hoofddraagconstructies - kolommen en liggers, kolom-/liggerconstructies; Materiaal: 00_PBT_MAT_staal_S355; Description: trapboom
Pset_BeamCommon - Reference: 28_PBT_SF_staal_trapboom_glas:trapboom; Span: 8583.94 mm; Slope: 29.9854 deg
Pset_QuantityTakeOff - Reference: 28_PBT_SF_staal_trapboom_glas:trapboom
Pset_ReinforcementBarPitchOfBeam - Reference: 28_PBT_SF_staal_trapboom_glas:trapboom
Pset_Pieters - Bouwlaag: Level: 00 begane grond; Naamgeving element: 28_PBT_SF_staal_trapboom_glas: trapboom; Fase: Nieuw
BaseQuantities - Length: 8583.94 mm; CrossSectionArea: 5489648 mm2; OuterSurfaceArea: 466529 mm2; GrossSurfaceArea: 4762748 mm2; GrossVolume: 0.0644433 m3; NetVolume: 0.13755 m3; NetSurfaceArea: 10979297 mm2

# IfcBeam: 28_PBT_SF_staal_trapboom_oplegplaat:kopplaat, 28_PBT_SF_staal_trapboom_oplegplaat:kopplaat:6337323
In: 00 begane grond
Type - PredefinedType: BEAM; Material: 00_PBT_MAT_staal_S355
Type - Pset_BeamCommon - IsExternal: no; LoadBearing: yes; Span: 1940 mm
Type - Pset_ProductRequirements - Category: Structural Framing
Type - Pset_ReinforcementBarPitchOfBeam - Description: oplegplaat
Type - Pset_Pieters - Breedte: 30 mm; Hoogte: 310 mm; Materiaal: 00_PBT_MAT_staal_S355; Description: oplegplaat
Pset_BeamCommon - Reference: 28_PBT_SF_staal_trapboom_oplegplaat:kopplaat
Pset_QuantityTakeOff - Reference: 28_PBT_SF_staal_trapboom_oplegplaat:kopplaat
Pset_ReinforcementBarPitchOfBeam - Reference: 28_PBT_SF_staal_trapboom_oplegplaat:kopplaat
Pset_Pieters - Naamgeving element: 28_PBT_SF_staal_trapboom_oplegplaat: kopplaat; Fase: Nieuw; Comments: betonvulling
BaseQuantities - Length: 1940 mm; CrossSectionArea: 776985 mm2; NetVolume: 0.019486 m3; NetSurfaceArea: 1553969 mm2

# IfcBeam: 28_PBT_SF_staal_trede:K70x70x5 (64)
Type - PredefinedType: BEAM; Material: 00_PBT_MAT_staal_S355, 00_PBT_MAT_beton t.p.g._C30/37
Type - Pset_BeamCommon - IsExternal: no; LoadBearing: yes; Span: 1760 mm
Type - Pset_ProductRequirements - Category: Structural Framing
Type - Pset_ReinforcementBarPitchOfBeam - Description: #70x70x5
Type - Pset_Pieters - Breedte: 70 mm; Hoogte: 70 mm; Materiaal: 00_PBT_MAT_staal_S355; Materiaalkwaliteit: S355; Description: #70x70x5; Type Comments: plaat t=10
Material: 00_PBT_MAT_beton t.p.g._C30/37, 00_PBT_MAT_staal_S355
Pset_BeamCommon - Reference: 28_PBT_SF_staal_trede:K70x70x5
Pset_QuantityTakeOff - Reference: 28_PBT_SF_staal_trede:K70x70x5
Pset_ReinforcementBarPitchOfBeam - Reference: 28_PBT_SF_staal_trede:K70x70x5
Pset_Pieters - Naamgeving element: 28_PBT_SF_staal_trede: K70x70x5; Fase: Nieuw
BaseQuantities - Length: 1760 mm; CrossSectionArea: 1999984 mm2; NetVolume: 0.0346143 m3; NetSurfaceArea: 3999969 mm2
Name (28_PBT_SF_staal_trede:K70x70x5:...) | In | Group
5980830 | -1 kelder | Model Group:Array Group 9:5989923
5989926 | -1 kelder | Model Group:Array Group 9:5989927
5989946 | -1 kelder | Model Group:Array Group 9:5989947
5989949 | -1 kelder | Model Group:Array Group 9:5989950
5989952 | -1 kelder | Model Group:Array Group 9:5989953
5989955 | -1 kelder | Model Group:Array Group 9:5989956
5989958 | -1 kelder | Model Group:Array Group 9:5989959
5989961 | -1 kelder | Model Group:Array Group 9:5989962
5989964 | -1 kelder | Model Group:Array Group 9:5989965
5989967 | -1 kelder | Model Group:Array Group 9:5989968
5989970 | -1 kelder | Model Group:Array Group 9:5989971
5989973 | -1 kelder | Model Group:Array Group 9:5989974
5989976 | -1 kelder | Model Group:Array Group 9:5989977
5989979 | -1 kelder | Model Group:Array Group 9:5989980
5989982 | -1 kelder | Model Group:Array Group 9:5989983
5989985 | -1 kelder | Model Group:Array Group 9:5989986
5989988 | -1 kelder | Model Group:Array Group 9:5989989
5990208 | -2 kelder | Model Group:Array Group 10:5990271
5990274 | -2 kelder | Model Group:Array Group 10:5990275
5990298 | -1 kelder | Model Group:Array Group 10:5990299
5990301 | -1 kelder | Model Group:Array Group 10:5990302
5990304 | -1 kelder | Model Group:Array Group 10:5990305
5990307 | -1 kelder | Model Group:Array Group 10:5990308
5990310 | -1 kelder | Model Group:Array Group 10:5990311
5990313 | -1 kelder | Model Group:Array Group 10:5990314
5990316 | -1 kelder | Model Group:Array Group 10:5990317
5990319 | -1 kelder | Model Group:Array Group 10:5990320
5990322 | -1 kelder | Model Group:Array Group 10:5990323
5990325 | -1 kelder | Model Group:Array Group 10:5990326
5990328 | -1 kelder | Model Group:Array Group 10:5990329
5990331 | -1 kelder | Model Group:Array Group 10:5990332
5990334 | -1 kelder | Model Group:Array Group 10:5990335
5990337 | -1 kelder | Model Group:Array Group 10:5990338
5990340 | -1 kelder | Model Group:Array Group 10:5990341
5990354 | -1 kelder | Model Group:Array Group 11:5990420
5990423 | -1 kelder | Model Group:Array Group 11:5990424
5990440 | -1 kelder | Model Group:Array Group 11:5990441
5990443 | 00 begane grond | Model Group:Array Group 11:5990444
5990446 | 00 begane grond | Model Group:Array Group 11:5990447
5990449 | 00 begane grond | Model Group:Array Group 11:5990450
5990452 | 00 begane grond | Model Group:Array Group 11:5990453
5990455 | 00 begane grond | Model Group:Array Group 11:5990456
5990458 | 00 begane grond | Model Group:Array Group 11:5990459
5990461 | 00 begane grond | Model Group:Array Group 11:5990462
5990464 | 00 begane grond | Model Group:Array Group 11:5990465
5990467 | 00 begane grond | Model Group:Array Group 11:5990468
5990470 | 00 begane grond | Model Group:Array Group 11:5990471
5990473 | 00 begane grond | Model Group:Array Group 11:5990474
5990476 | 00 begane grond | Model Group:Array Group 11:5990477
5990479 | 00 begane grond | Model Group:Array Group 11:5990480
5990482 | 00 begane grond | Model Group:Array Group 11:5990483
5990485 | 00 begane grond | Model Group:Array Group 11:5990486
5990488 | 00 begane grond | Model Group:Array Group 11:5990489
5990491 | 00 begane grond | Model Group:Array Group 11:5990492
5990494 | 00 begane grond | Model Group:Array Group 11:5990495
5990511 | 00 begane grond | Model Group:Array Group 12:5990580 | Pset_Pieters - Comments: betonvulling
5990583 | 00 begane grond | Model Group:Array Group 12:5990584 | Pset_Pieters - Comments: betonvulling
5990616 | 00 begane grond | Model Group:Array Group 12:5990617 | Pset_Pieters - Comments: betonvulling
5990619 | 00 begane grond | Model Group:Array Group 12:5990620 | Pset_Pieters - Comments: betonvulling
5990622 | 00 begane grond | Model Group:Array Group 12:5990623 | Pset_Pieters - Comments: betonvulling
5990625 | 00 begane grond | Model Group:Array Group 12:5990626 | Pset_Pieters - Comments: betonvulling
5990628 | 00 begane grond | Model Group:Array Group 12:5990629 | Pset_Pieters - Comments: betonvulling
5990631 | 00 begane grond | Model Group:Array Group 12:5990632 | Pset_Pieters - Comments: betonvulling
5990634 | 00 begane grond | Model Group:Array Group 12:5990635 | Pset_Pieters - Comments: betonvulling

# IfcBeam: 28_PBT_SF_staal_voetplaat_vloerrand:voetplaat_280x280x15_geen kopplaat (10)
In: 02 tweede verdieping
Type - Pset_BeamCommon - IsExternal: no; LoadBearing: yes
Type - Pset_ProductRequirements - Category: Structural Framing
Type - Pset_ReinforcementBarPitchOfBeam - Description: #70x70x5
Type - Pset_Pieters - Materiaal: 00_PBT_MAT_staal_S355; Description: #70x70x5; Type Comments: plaat t=10
Material: 00_PBT_MAT_staal_S355
BaseQuantities - Length: 280 mm; CrossSectionArea: 4200 mm2; OuterSurfaceArea: 165200 mm2; GrossVolume: 1176000 m3; NetVolume: 0.001176 m3; GrossSurfaceArea: 173600 mm2; NetSurfaceArea: 173600 mm2
Pset_BeamCommon - Reference: 28_PBT_SF_staal_voetplaat_vloerrand:voetplaat_280x280x15_geen kopplaat
Pset_QuantityTakeOff - Reference: 28_PBT_SF_staal_voetplaat_vloerrand:voetplaat_280x280x15_geen kopplaat
Pset_ReinforcementBarPitchOfBeam - Reference: 28_PBT_SF_staal_voetplaat_vloerrand:voetplaat_280x280x15_geen kopplaat
Pset_Pieters - Dragend/niet dragend: yes; In/uitwendig: no; Naamgeving element: 28_PBT_SF_staal_voetplaat_vloerrand: voetplaat_280x280x15_geen kopplaat; Fase: Nieuw
Name (28_PBT_SF_staal_voetplaat_vloerrand:voetplaat_280x280x15_geen kopplaat:...)
6366577
6375978
6376263
6376419
6376485
6377483
6377484
6377486
6377487
6378309

# IfcBeam: 28_PBT_SF_staal_voetplaat_vloerrand:voetplaat_280x280x15_kopplaat_280x210x15 (17)
In: 02 tweede verdieping
Type - PredefinedType: BEAM; Material: 00_PBT_MAT_staal_S355
Type - Pset_BeamCommon - IsExternal: no; LoadBearing: yes
Type - Pset_ProductRequirements - Category: Structural Framing
Type - Pset_ReinforcementBarPitchOfBeam - Description: voetplaat
Type - Pset_Pieters - Materiaal: 00_PBT_MAT_staal_S355; Description: voetplaat
Pset_BeamCommon - IsExternal: yes; Reference: 28_PBT_SF_staal_voetplaat_vloerrand:voetplaat_280x280x15_kopplaat_280x210x15
Pset_QuantityTakeOff - Reference: 28_PBT_SF_staal_voetplaat_vloerrand:voetplaat_280x280x15_kopplaat_280x210x15
Pset_ReinforcementBarPitchOfBeam - Reference: 28_PBT_SF_staal_voetplaat_vloerrand:voetplaat_280x280x15_kopplaat_280x210x15
Pset_Pieters - Dragend/niet dragend: yes; In/uitwendig: yes; Naamgeving element: 28_PBT_SF_staal_voetplaat_vloerrand: voetplaat_280x280x15_kopplaat_280x210x15; Fase: Nieuw
BaseQuantities - CrossSectionArea: 158850 mm2; NetVolume: 0.002142 m3; NetSurfaceArea: 317700 mm2
Name (28_PBT_SF_staal_voetplaat_vloerrand:voetplaat_280x280x15_kopplaat_280x210x15:...)
6375888 | BaseQuantities - Length: 15 mm; OuterSurfaceArea: 16800 mm2; GrossSurfaceArea: 173600 mm2; GrossVolume: 0.001176 m3
6375962
6375970
6376159
6376468
6376591
6376628
6377485 | BaseQuantities - Length: 15 mm; OuterSurfaceArea: 16800 mm2; GrossSurfaceArea: 173600 mm2; GrossVolume: 0.001176 m3
6377534
6377535
6377536
6377537
6377538
6377539
6377540
6378380
6378415

# IfcBeam: 28_PBT_SF_toneeltoren_dakafschuining:28_PBT_SF_toneeltoren_dakafschuining, 28_PBT_SF_toneeltoren_dakafschuining:28_PBT_SF_toneeltoren_dakafschuining:2601638
In: 06 zesde verdieping
Type - Pset_BeamCommon - IsExternal: no; LoadBearing: yes
Type - Pset_ProductRequirements - Category: Structural Framing
Type - Pset_Pieters - Materiaal: 00_PBT_MAT_beton t.p.g._C30/37; Materiaalkwaliteit: C30/37
Material: 00_PBT_MAT_beton t.p.g._C30/37
BaseQuantities - CrossSectionArea: 19661444 mm2; NetVolume: 3.85189 m3; Length: 15380.2 mm; NetSurfaceArea: 39322888 mm2
Pset_BeamCommon - Slope: 0 deg; Reference: 28_PBT_SF_toneeltoren_dakafschuining:28_PBT_SF_toneeltoren_dakafschuining; Span: 15380.2 mm
Pset_QuantityTakeOff - Reference: 28_PBT_SF_toneeltoren_dakafschuining:28_PBT_SF_toneeltoren_dakafschuining; sets with these values: 2
Pset_Pieters - Bouwlaag: Level: 06 zesde verdieping; Naamgeving element: 28_PBT_SF_toneeltoren_dakafschuining: 28_PBT_SF_toneeltoren_dakafschuining; Fase: Nieuw

# IfcBeam: 28_PBT_SF_toneeltoren_dakboog:28_PBT_SF_toneeltoren_dakboog as 1, 28_PBT_SF_toneeltoren_dakboog:28_PBT_SF_toneeltoren_dakboog as 1:2583254
In: 05 vijfde verdieping
Type - Pset_BeamCommon - IsExternal: no; LoadBearing: yes
Type - Pset_ProductRequirements - Category: Structural Framing
Type - Pset_ReinforcementBarPitchOfBeam - Description: prefab dakelement
Type - Pset_Pieters - Materiaal: 00_PBT_MAT_beton prefab; Materiaalkwaliteit: volgens leverancier; Description: prefab dakelement
Material: 00_PBT_MAT_beton prefab
BaseQuantities - CrossSectionArea: 119269135 mm2; NetVolume: 27.2415 m3; Length: 22995.5 mm; NetSurfaceArea: 238538269 mm2
Pset_BeamCommon - Slope: 0 deg; Reference: 28_PBT_SF_toneeltoren_dakboog:28_PBT_SF_toneeltoren_dakboog as 1; Span: 22995.5 mm
Pset_QuantityTakeOff - Reference: 28_PBT_SF_toneeltoren_dakboog:28_PBT_SF_toneeltoren_dakboog as 1
Pset_ReinforcementBarPitchOfBeam - Reference: 28_PBT_SF_toneeltoren_dakboog:28_PBT_SF_toneeltoren_dakboog as 1
Pset_Pieters - Bouwlaag: Level: 05 vijfde verdieping; Naamgeving element: 28_PBT_SF_toneeltoren_dakboog: 28_PBT_SF_toneeltoren_dakboog as 1; Fase: Nieuw

# IfcBeam: 28_PBT_SF_toneeltoren_dakboog:28_PBT_SF_toneeltoren_dakboog as K/2, 28_PBT_SF_toneeltoren_dakboog:28_PBT_SF_toneeltoren_dakboog as K/2:4317351
In: 05 vijfde verdieping
Type - Pset_BeamCommon - IsExternal: no; LoadBearing: yes
Type - Pset_ProductRequirements - Category: Structural Framing
Type - Pset_ReinforcementBarPitchOfBeam - Description: prefab dakelement
Type - Pset_Pieters - Materiaal: 00_PBT_MAT_beton prefab; Materiaalkwaliteit: volgens leverancier; Description: prefab dakelement
Material: 00_PBT_MAT_beton prefab
BaseQuantities - CrossSectionArea: 30841837 mm2; NetVolume: 6.97621 m3; Length: 4853 mm; NetSurfaceArea: 61683675 mm2
Pset_BeamCommon - Slope: 0 deg; Reference: 28_PBT_SF_toneeltoren_dakboog:28_PBT_SF_toneeltoren_dakboog as K/2; Span: 4853 mm
Pset_QuantityTakeOff - Reference: 28_PBT_SF_toneeltoren_dakboog:28_PBT_SF_toneeltoren_dakboog as K/2
Pset_ReinforcementBarPitchOfBeam - Reference: 28_PBT_SF_toneeltoren_dakboog:28_PBT_SF_toneeltoren_dakboog as K/2
Pset_Pieters - Bouwlaag: Level: 05 vijfde verdieping; Naamgeving element: 28_PBT_SF_toneeltoren_dakboog: 28_PBT_SF_toneeltoren_dakboog as K/2; Fase: Nieuw

# IfcBeam: 28_PBT_SF_toneeltoren_dakboog:28_PBT_SF_toneeltoren_dakboog as K/20, 28_PBT_SF_toneeltoren_dakboog:28_PBT_SF_toneeltoren_dakboog as K/20:2582059
In: 05 vijfde verdieping
Type - Pset_BeamCommon - IsExternal: no; LoadBearing: yes
Type - Pset_ProductRequirements - Category: Structural Framing
Type - Pset_ReinforcementBarPitchOfBeam - Description: prefab dakelement
Type - Pset_Pieters - Materiaal: 00_PBT_MAT_beton prefab; Materiaalkwaliteit: volgens leverancier; Description: prefab dakelement
Material: 00_PBT_MAT_beton prefab
BaseQuantities - CrossSectionArea: 27890044 mm2; NetVolume: 6.26138 m3; Length: 4316.56 mm; NetSurfaceArea: 55780088 mm2
Pset_BeamCommon - Slope: 0 deg; Reference: 28_PBT_SF_toneeltoren_dakboog:28_PBT_SF_toneeltoren_dakboog as K/20; Span: 4316.56 mm
Pset_QuantityTakeOff - Reference: 28_PBT_SF_toneeltoren_dakboog:28_PBT_SF_toneeltoren_dakboog as K/20
Pset_ReinforcementBarPitchOfBeam - Reference: 28_PBT_SF_toneeltoren_dakboog:28_PBT_SF_toneeltoren_dakboog as K/20
Pset_Pieters - Bouwlaag: Level: 05 vijfde verdieping; Naamgeving element: 28_PBT_SF_toneeltoren_dakboog: 28_PBT_SF_toneeltoren_dakboog as K/20; Fase: Nieuw

# IfcBeam: 28_PBT_SF_toneeltoren_dakboog:28_PBT_SF_toneeltoren_dakboog as R (2)
In: 05 vijfde verdieping
Type - Pset_BeamCommon - IsExternal: no; LoadBearing: yes
Type - Pset_ProductRequirements - Category: Structural Framing
Type - Pset_ReinforcementBarPitchOfBeam - Description: prefab dakelement
Type - Pset_Pieters - Materiaal: 00_PBT_MAT_beton prefab; Materiaalkwaliteit: volgens leverancier; Description: prefab dakelement
Material: 00_PBT_MAT_beton prefab
Pset_BeamCommon - Slope: 0 deg; Reference: 28_PBT_SF_toneeltoren_dakboog:28_PBT_SF_toneeltoren_dakboog as R
Pset_QuantityTakeOff - Reference: 28_PBT_SF_toneeltoren_dakboog:28_PBT_SF_toneeltoren_dakboog as R
Pset_ReinforcementBarPitchOfBeam - Reference: 28_PBT_SF_toneeltoren_dakboog:28_PBT_SF_toneeltoren_dakboog as R
Pset_Pieters - Bouwlaag: Level: 05 vijfde verdieping; Naamgeving element: 28_PBT_SF_toneeltoren_dakboog: 28_PBT_SF_toneeltoren_dakboog as R; Fase: Nieuw
Name (28_PBT_SF_toneeltoren_dakboog:28_PBT_SF_toneeltoren_dakboog as R:...) | CrossSectionArea (mm2) | NetVolume (m3) | Span (mm) = Length (mm) | NetSurfaceArea (mm2)
2583113 | 238328700 | 56.9556 | 35200 | 476657401
2584242 | 141572963 | 33.4335 | 22167.1 | 283145927

# IfcBuildingElementProxy: 00_PBT_GM_nulpunt:Kubus, 00_PBT_GM_nulpunt:Kubus:1048449
In: 00 begane grond
Type - Classification: - (Uniformat); Material: White
Type - Pset_ProductRequirements - Category: Generic Models
Material: White, Pieters blauw
Pset_BuildingElementProxyCommon - Reference: 00_PBT_GM_nulpunt:Kubus; sets with these values: 2

# IfcBuildingElementProxy: 28_SCO_WTS530:M30 (4)
Type - Classification: 2B(28.10) (Uniformat); Material: <Unnamed>
Type - Pset_ManufacturerTypeInformation - Manufacturer: Willems Anker BV
Type - Pset_ProductRequirements - Category: Structural Connections
Pset_BuildingElementProxyCommon - Reference: 28_SCO_WTS530:M30; sets with these values: 2
Name (28_SCO_WTS530:M30:...) | In
6320878 | 01 eerste verdieping
6324619 | 01 eerste verdieping
6324940 | 00 begane grond
6325063 | 00 begane grond

# IfcBuildingElementProxy: Generic Models 1:Generic Models 1, Generic Models 1:Generic Models 1:1317685
In: -1 kelder
Type - Classification: 16.20 funderingsconstructies - keerwanden, algemeen (verzamelniveau) (Uniformat); Material: 00_PBT_MAT_beton t.p.g.
Type - Pset_ProductRequirements - Category: Generic Models
Pset_BuildingElementProxyCommon - Reference: Generic Models 1:Generic Models 1; sets with these values: 2
Pset_ProvisionForVoid - Width: 1840 mm; Depth: 1840 mm

# IfcBuildingElementProxy: Generic Models 4:Generic Models 1, Generic Models 4:Generic Models 1:1390084
In: -1 kelder
Type - Classification: 28.10 hoofddraagconstructies - kolommen en liggers, algemeen (verzamelniveau) (Uniformat); Material: 00_PBT_MAT_beton t.p.g.
Type - Pset_ProductRequirements - Category: Generic Models
Pset_BuildingElementProxyCommon - Reference: Generic Models 4:Generic Models 1; sets with these values: 2
Pset_ProvisionForVoid - Width: 1690 mm; Depth: 1690 mm

# IfcBuildingElementProxy: Poer P20:Poer P20, Poer P20:Poer P20:1326230
In: -2 kelder
Type - Classification: 16.13 funderingsconstructies - voeten en balken, fundatie poeren (Uniformat); Material: 00_PBT_MAT_beton t.p.g.
Type - Pset_ProductRequirements - Category: Generic Models
Pset_BuildingElementProxyCommon - Reference: Poer P20:Poer P20; sets with these values: 2

# IfcColumn: 16_PBT_SC_beton_rechthoekig:1100x400_bestaand, 16_PBT_SC_beton_rechthoekig:1100x400_bestaand:1387818
In: -1 kelder
Type - PredefinedType: COLUMN; Classification: 28.11 hoofddraagconstructies - kolommen en liggers, kolom-/liggerconstructies (Uniformat); Material: 00_PBT_MAT_beton t.p.g.
Type - Pset_ColumnCommon - IsExternal: no; LoadBearing: yes
Type - Pset_ProductRequirements - Category: Structural Columns
Type - Pset_ReinforcementBarPitchOfColumn - Description: 1100x400
Type - Pset_Pieters - Breedte: 1100 mm; Hoogte: 400 mm; Codering - NL-SfB: 28.11; Omschrijving NL-SfB: hoofddraagconstructies - kolommen en liggers, kolom-/liggerconstructies; Materiaal: 00_PBT_MAT_beton t.p.g.; Description: 1100x400
BaseQuantities - CrossSectionArea: 3479650 mm2; NetVolume: 0.794073 m3
Pset_ColumnCommon - Reference: 16_PBT_SC_beton_rechthoekig:1100x400_bestaand
Pset_QuantityTakeOff - Reference: 16_PBT_SC_beton_rechthoekig:1100x400_bestaand
Pset_ReinforcementBarPitchOfColumn - Reference: 16_PBT_SC_beton_rechthoekig:1100x400_bestaand
Pset_Pieters - Dragend/niet dragend: yes; In/uitwendig: no; Bouwlaag: Level: -1 kelder_Offset1000; Naamgeving element: 16_PBT_SC_beton_rechthoekig: 1100x400_bestaand; Fase: Bestaand

# IfcColumn: 16_PBT_SC_beton_rechthoekig:350x350_bestaand (6)
In: -1 kelder
Type - PredefinedType: COLUMN; Classification: 28.11 hoofddraagconstructies - kolommen en liggers, kolom-/liggerconstructies (Uniformat); Material: 00_PBT_MAT_beton t.p.g.
Type - Pset_ColumnCommon - IsExternal: no; LoadBearing: yes
Type - Pset_ProductRequirements - Category: Structural Columns
Type - Pset_ReinforcementBarPitchOfColumn - Description: 350x350
Type - Pset_Pieters - Breedte: 350 mm; Hoogte: 350 mm; Codering - NL-SfB: 28.11; Omschrijving NL-SfB: hoofddraagconstructies - kolommen en liggers, kolom-/liggerconstructies; Materiaal: 00_PBT_MAT_beton t.p.g.; Description: 350x350
Pset_ColumnCommon - IsExternal: yes; Reference: 16_PBT_SC_beton_rechthoekig:350x350_bestaand
Pset_QuantityTakeOff - Reference: 16_PBT_SC_beton_rechthoekig:350x350_bestaand
Pset_ReinforcementBarPitchOfColumn - Reference: 16_PBT_SC_beton_rechthoekig:350x350_bestaand
Pset_Pieters - Dragend/niet dragend: yes; In/uitwendig: yes; Bouwlaag: Level: -1 kelder_Offset1000; Naamgeving element: 16_PBT_SC_beton_rechthoekig: 350x350_bestaand; Fase: Bestaand
Name (16_PBT_SC_beton_rechthoekig:350x350_bestaand:...) | CrossSectionArea (mm2) | NetVolume (m3)
1315917 | 906800 | 0.07728 | Pset_ColumnCommon - Slope: 0 deg
1315998 | 906800 | 0.07728
1316017 | 845000 | 0.0532
1316038 | 845000 | 0.0532
1316057 | 845000 | 0.0532
1316076 | 822500 | 0.04655

# IfcColumn: 16_PBT_SC_beton_rechthoekig:500x500_bestaand, 16_PBT_SC_beton_rechthoekig:500x500_bestaand:1356606
In: -1 kelder
Type - PredefinedType: COLUMN; Classification: 28.11 hoofddraagconstructies - kolommen en liggers, kolom-/liggerconstructies (Uniformat); Material: 00_PBT_MAT_beton t.p.g.
Type - Pset_ColumnCommon - IsExternal: no; LoadBearing: yes
Type - Pset_ProductRequirements - Category: Structural Columns
Type - Pset_ReinforcementBarPitchOfColumn - Description: 500x500
Type - Pset_Pieters - Breedte: 500 mm; Hoogte: 500 mm; Codering - NL-SfB: 28.11; Omschrijving NL-SfB: hoofddraagconstructies - kolommen en liggers, kolom-/liggerconstructies; Materiaal: 00_PBT_MAT_beton t.p.g.; Description: 500x500
BaseQuantities - CrossSectionArea: 1700000 mm2; NetVolume: 0.2625 m3
Pset_ColumnCommon - IsExternal: yes; Reference: 16_PBT_SC_beton_rechthoekig:500x500_bestaand
Pset_QuantityTakeOff - Reference: 16_PBT_SC_beton_rechthoekig:500x500_bestaand
Pset_ReinforcementBarPitchOfColumn - Reference: 16_PBT_SC_beton_rechthoekig:500x500_bestaand
Pset_Pieters - Dragend/niet dragend: yes; In/uitwendig: yes; Bouwlaag: Level: -1 kelder_Offset1000; Naamgeving element: 16_PBT_SC_beton_rechthoekig: 500x500_bestaand; Fase: Bestaand

# IfcColumn: 16_PBT_SC_beton_rechthoekig:510x500_bestaand (2)
Type - PredefinedType: COLUMN; Classification: 28.11 hoofddraagconstructies - kolommen en liggers, kolom-/liggerconstructies (Uniformat); Material: 00_PBT_MAT_beton t.p.g.
Type - Pset_ColumnCommon - IsExternal: no; LoadBearing: yes
Type - Pset_ProductRequirements - Category: Structural Columns
Type - Pset_ReinforcementBarPitchOfColumn - Description: 510x500
Type - Pset_Pieters - Breedte: 510 mm; Hoogte: 500 mm; Codering - NL-SfB: 28.11; Omschrijving NL-SfB: hoofddraagconstructies - kolommen en liggers, kolom-/liggerconstructies; Materiaal: 00_PBT_MAT_beton t.p.g.; Description: 510x500
Pset_ColumnCommon - Reference: 16_PBT_SC_beton_rechthoekig:510x500_bestaand
Pset_QuantityTakeOff - Reference: 16_PBT_SC_beton_rechthoekig:510x500_bestaand
Pset_ReinforcementBarPitchOfColumn - Reference: 16_PBT_SC_beton_rechthoekig:510x500_bestaand
Pset_Pieters - Dragend/niet dragend: yes; In/uitwendig: no; Naamgeving element: 16_PBT_SC_beton_rechthoekig: 510x500_bestaand; Fase: Bestaand
Name (16_PBT_SC_beton_rechthoekig:510x500_bestaand:...) | In | CrossSectionArea (mm2) | NetVolume (m3) | Bouwlaag
1386857 | -1 kelder | 1983500 | 0.2703 | Level: -1 kelder_Offset1000
1407315 | -2 kelder | 1678200 | 0.22644 | Level: -2 kelder_Offset1000

# IfcColumn: 16_PBT_SC_beton_rechthoekig:640x500_bestaand, 16_PBT_SC_beton_rechthoekig:640x500_bestaand:1302164
In: -1 kelder
Type - PredefinedType: COLUMN; Classification: 28.11 hoofddraagconstructies - kolommen en liggers, kolom-/liggerconstructies (Uniformat); Material: 00_PBT_MAT_beton t.p.g.
Type - Pset_ColumnCommon - IsExternal: no; LoadBearing: yes
Type - Pset_ProductRequirements - Category: Structural Columns
Type - Pset_ReinforcementBarPitchOfColumn - Description: 640x500
Type - Pset_Pieters - Breedte: 640 mm; Hoogte: 500 mm; Codering - NL-SfB: 28.11; Omschrijving NL-SfB: hoofddraagconstructies - kolommen en liggers, kolom-/liggerconstructies; Materiaal: 00_PBT_MAT_beton t.p.g.; Description: 640x500
BaseQuantities - CrossSectionArea: 1431100 mm2; NetVolume: 0.16224 m3
Pset_ColumnCommon - Reference: 16_PBT_SC_beton_rechthoekig:640x500_bestaand; IsExternal: yes
Pset_QuantityTakeOff - Reference: 16_PBT_SC_beton_rechthoekig:640x500_bestaand
Pset_ReinforcementBarPitchOfColumn - Reference: 16_PBT_SC_beton_rechthoekig:640x500_bestaand
Pset_Pieters - Dragend/niet dragend: yes; Bouwlaag: Level: -1 kelder_Offset1000; Naamgeving element: 16_PBT_SC_beton_rechthoekig: 640x500_bestaand; Fase: Bestaand; In/uitwendig: yes

# IfcColumn: 16_PBT_SC_beton_rechthoekig:660x570_bestaand, 16_PBT_SC_beton_rechthoekig:660x570_bestaand:1333022
In: -1 kelder
Type - PredefinedType: COLUMN; Classification: 28.11 hoofddraagconstructies - kolommen en liggers, kolom-/liggerconstructies (Uniformat); Material: 00_PBT_MAT_beton t.p.g.
Type - Pset_ColumnCommon - IsExternal: no; LoadBearing: yes
Type - Pset_ProductRequirements - Category: Structural Columns
Type - Pset_ReinforcementBarPitchOfColumn - Description: 660x570
Type - Pset_Pieters - Breedte: 660 mm; Hoogte: 570 mm; Codering - NL-SfB: 28.11; Omschrijving NL-SfB: hoofddraagconstructies - kolommen en liggers, kolom-/liggerconstructies; Materiaal: 00_PBT_MAT_beton t.p.g.; Description: 660x570
BaseQuantities - CrossSectionArea: 3072800 mm2; NetVolume: 0.616704 m3
Pset_ColumnCommon - IsExternal: yes; Reference: 16_PBT_SC_beton_rechthoekig:660x570_bestaand
Pset_QuantityTakeOff - Reference: 16_PBT_SC_beton_rechthoekig:660x570_bestaand
Pset_ReinforcementBarPitchOfColumn - Reference: 16_PBT_SC_beton_rechthoekig:660x570_bestaand
Pset_Pieters - Dragend/niet dragend: yes; In/uitwendig: yes; Bouwlaag: Level: -1 kelder_Offset1000; Naamgeving element: 16_PBT_SC_beton_rechthoekig: 660x570_bestaand; Fase: Bestaand

# IfcColumn: 16_PBT_SC_beton_rechthoekig:700x350_bestaand, 16_PBT_SC_beton_rechthoekig:700x350_bestaand:1302572
In: -1 kelder
Type - PredefinedType: COLUMN; Classification: 28.11 hoofddraagconstructies - kolommen en liggers, kolom-/liggerconstructies (Uniformat); Material: 00_PBT_MAT_beton t.p.g.
Type - Pset_ColumnCommon - IsExternal: no; LoadBearing: yes
Type - Pset_ProductRequirements - Category: Structural Columns
Type - Pset_ReinforcementBarPitchOfColumn - Description: 700x350
Type - Pset_Pieters - Breedte: 700 mm; Hoogte: 350 mm; Codering - NL-SfB: 28.11; Omschrijving NL-SfB: hoofddraagconstructies - kolommen en liggers, kolom-/liggerconstructies; Materiaal: 00_PBT_MAT_beton t.p.g.; Description: 700x350
BaseQuantities - CrossSectionArea: 3468201 mm2; NetVolume: 0.752045 m3
Pset_ColumnCommon - Reference: 16_PBT_SC_beton_rechthoekig:700x350_bestaand
Pset_QuantityTakeOff - Reference: 16_PBT_SC_beton_rechthoekig:700x350_bestaand
Pset_ReinforcementBarPitchOfColumn - Reference: 16_PBT_SC_beton_rechthoekig:700x350_bestaand
Pset_Pieters - Dragend/niet dragend: yes; In/uitwendig: no; Bouwlaag: Level: -1 kelder_Offset1000; Naamgeving element: 16_PBT_SC_beton_rechthoekig: 700x350_bestaand; Fase: Bestaand

# IfcColumn: 16_PBT_SC_beton_rechthoekig:C30/37_300x300_penant, 16_PBT_SC_beton_rechthoekig:C30/37_300x300_penant:5976961
In: 00 begane grond
Type - PredefinedType: COLUMN; Classification: 28.11 hoofddraagconstructies - kolommen en liggers, kolom-/liggerconstructies (Uniformat); Material: 00_PBT_MAT_beton t.p.g._C30/37
Type - Pset_ColumnCommon - IsExternal: no; LoadBearing: yes
Type - Pset_ProductRequirements - Category: Structural Columns
Type - Pset_ReinforcementBarPitchOfColumn - Description: penant 300x300
Type - Pset_Pieters - Breedte: 300 mm; Hoogte: 300 mm; Codering - NL-SfB: 28.11; Omschrijving NL-SfB: hoofddraagconstructies - kolommen en liggers, kolom-/liggerconstructies; Materiaal: 00_PBT_MAT_beton t.p.g._C30/37; Materiaalkwaliteit: C30/37; Description: penant 300x300
BaseQuantities - CrossSectionArea: 2334000 mm2; NetVolume: 0.3366 m3
Pset_ColumnCommon - Reference: 16_PBT_SC_beton_rechthoekig:C30/37_300x300_penant
Pset_QuantityTakeOff - Reference: 16_PBT_SC_beton_rechthoekig:C30/37_300x300_penant
Pset_ReinforcementBarPitchOfColumn - Reference: 16_PBT_SC_beton_rechthoekig:C30/37_300x300_penant
Pset_Pieters - Bouwlaag: Level: 00 begane grond; Naamgeving element: 16_PBT_SC_beton_rechthoekig: C30/37_300x300_penant; Fase: Nieuw

# IfcColumn: 16_PBT_SC_beton_rechthoekig:C30/37_300x400_penant, 16_PBT_SC_beton_rechthoekig:C30/37_300x400_penant:4915226
In: 00 begane grond
Type - PredefinedType: COLUMN; Classification: 28.11 hoofddraagconstructies - kolommen en liggers, kolom-/liggerconstructies (Uniformat); Material: 00_PBT_MAT_beton t.p.g._C30/37
Type - Pset_ColumnCommon - IsExternal: no; LoadBearing: yes
Type - Pset_ProductRequirements - Category: Structural Columns
Type - Pset_ReinforcementBarPitchOfColumn - Description: penant 300x400
Type - Pset_Pieters - Breedte: 400 mm; Hoogte: 300 mm; Codering - NL-SfB: 28.11; Omschrijving NL-SfB: hoofddraagconstructies - kolommen en liggers, kolom-/liggerconstructies; Materiaal: 00_PBT_MAT_beton t.p.g._C30/37; Materiaalkwaliteit: C30/37; Description: penant 300x400
BaseQuantities - CrossSectionArea: 1930000 mm2; NetVolume: 0.2244 m3
Pset_ColumnCommon - Reference: 16_PBT_SC_beton_rechthoekig:C30/37_300x400_penant
Pset_QuantityTakeOff - Reference: 16_PBT_SC_beton_rechthoekig:C30/37_300x400_penant
Pset_ReinforcementBarPitchOfColumn - Reference: 16_PBT_SC_beton_rechthoekig:C30/37_300x400_penant
Pset_Pieters - Bouwlaag: Level: 00 begane grond; Naamgeving element: 16_PBT_SC_beton_rechthoekig: C30/37_300x400_penant; Fase: Nieuw

# IfcColumn: 16_PBT_SC_beton_rechthoekig:C30/37_690x660, 16_PBT_SC_beton_rechthoekig:C30/37_690x660:4636520
In: -1 kelder
Type - PredefinedType: COLUMN; Classification: 28.11 hoofddraagconstructies - kolommen en liggers, kolom-/liggerconstructies (Uniformat); Material: 00_PBT_MAT_beton t.p.g._C30/37
Type - Pset_ColumnCommon - IsExternal: no; LoadBearing: yes
Type - Pset_ProductRequirements - Category: Structural Columns
Type - Pset_ReinforcementBarPitchOfColumn - Description: 690x660
Type - Pset_Pieters - Breedte: 690 mm; Hoogte: 660 mm; Codering - NL-SfB: 28.11; Omschrijving NL-SfB: hoofddraagconstructies - kolommen en liggers, kolom-/liggerconstructies; Materiaal: 00_PBT_MAT_beton t.p.g._C30/37; Materiaalkwaliteit: C30/37; Description: 690x660
BaseQuantities - CrossSectionArea: 3772800 mm2; NetVolume: 0.92736 m3
Pset_ColumnCommon - Reference: 16_PBT_SC_beton_rechthoekig:C30/37_690x660
Pset_QuantityTakeOff - Reference: 16_PBT_SC_beton_rechthoekig:C30/37_690x660
Pset_ReinforcementBarPitchOfColumn - Reference: 16_PBT_SC_beton_rechthoekig:C30/37_690x660
Pset_Pieters - Dragend/niet dragend: yes; In/uitwendig: no; Bouwlaag: Level: -1 kelder_Offset1000; Naamgeving element: 16_PBT_SC_beton_rechthoekig: C30/37_690x660; Fase: Nieuw

# IfcColumn: 28_PBT_SC_beton_opdikking wand:opdikking wand grote zaal_bestaand (2)
In: 03 derde verdieping
Type - PredefinedType: COLUMN; Classification: 28.11 hoofddraagconstructies - kolommen en liggers, kolom-/liggerconstructies (Uniformat); Material: 00_PBT_MAT_beton t.p.g.
Type - Pset_ColumnCommon - IsExternal: no; LoadBearing: yes
Type - Pset_ProductRequirements - Category: Structural Columns
Type - Pset_ReinforcementBarPitchOfColumn - Description: 350x350
Type - Pset_Pieters - Breedte: 350 mm; Hoogte: 350 mm; Codering - NL-SfB: 28.11; Omschrijving NL-SfB: hoofddraagconstructies - kolommen en liggers, kolom-/liggerconstructies; Materiaal: 00_PBT_MAT_beton t.p.g.; Description: 350x350
Pset_ColumnCommon - Reference: 28_PBT_SC_beton_opdikking wand:opdikking wand grote zaal_bestaand
Pset_QuantityTakeOff - Reference: 28_PBT_SC_beton_opdikking wand:opdikking wand grote zaal_bestaand
Pset_ReinforcementBarPitchOfColumn - Reference: 28_PBT_SC_beton_opdikking wand:opdikking wand grote zaal_bestaand
Pset_Pieters - Dragend/niet dragend: yes; In/uitwendig: no; Bouwlaag: Level: 03 derde verdieping_Offset1000; Naamgeving element: 28_PBT_SC_beton_opdikking wand: opdikking wand grote zaal_bestaand; Fase: Bestaand
Name (28_PBT_SC_beton_opdikking wand:opdikking wand grote zaal_bestaand:...) | CrossSectionArea (mm2) | NetVolume (m3)
1770934 | 11247892 | 1.7557
1802126 | 11642718 | 1.87708

# IfcColumn: 28_PBT_SC_beton_rechthoekig:1120x400_bestaand, 28_PBT_SC_beton_rechthoekig:1120x400_bestaand:1313276
In: -1 kelder
Type - PredefinedType: COLUMN; Classification: 28.11 hoofddraagconstructies - kolommen en liggers, kolom-/liggerconstructies (Uniformat); Material: 00_PBT_MAT_beton t.p.g.
Type - Pset_ColumnCommon - IsExternal: no; LoadBearing: yes
Type - Pset_ProductRequirements - Category: Structural Columns
Type - Pset_ReinforcementBarPitchOfColumn - Description: 1120x400
Type - Pset_Pieters - Breedte: 1120 mm; Hoogte: 400 mm; Codering - NL-SfB: 28.11; Omschrijving NL-SfB: hoofddraagconstructies - kolommen en liggers, kolom-/liggerconstructies; Materiaal: 00_PBT_MAT_beton t.p.g.; Description: 1120x400
BaseQuantities - CrossSectionArea: 4256400 mm2; NetVolume: 1.05616 m3
Pset_ColumnCommon - Reference: 28_PBT_SC_beton_rechthoekig:1120x400_bestaand
Pset_QuantityTakeOff - Reference: 28_PBT_SC_beton_rechthoekig:1120x400_bestaand
Pset_ReinforcementBarPitchOfColumn - Reference: 28_PBT_SC_beton_rechthoekig:1120x400_bestaand
Pset_Pieters - Dragend/niet dragend: yes; In/uitwendig: no; Bouwlaag: Level: -1 kelder_Offset1000; Naamgeving element: 28_PBT_SC_beton_rechthoekig: 1120x400_bestaand; Fase: Bestaand

# IfcColumn: 28_PBT_SC_beton_rechthoekig:1520x350_bestaand, 28_PBT_SC_beton_rechthoekig:1520x350_bestaand:1313274
In: -1 kelder
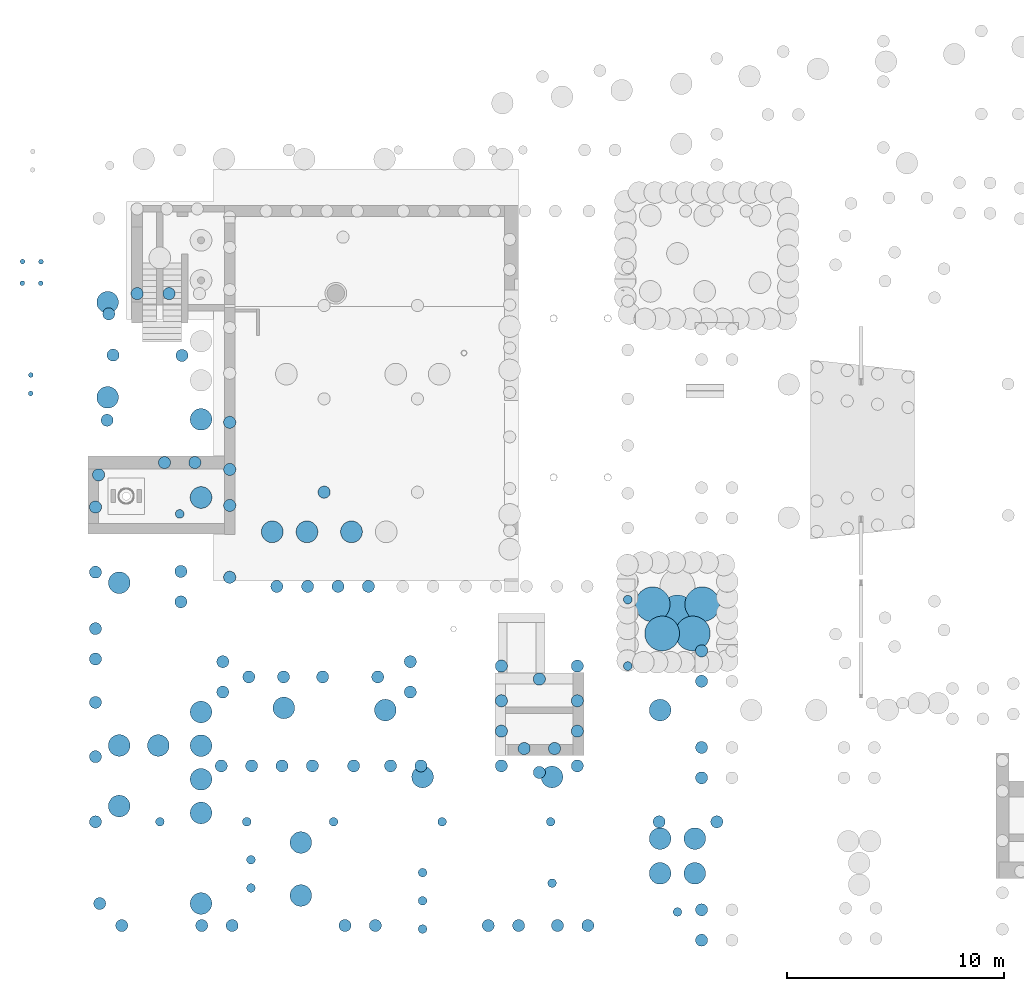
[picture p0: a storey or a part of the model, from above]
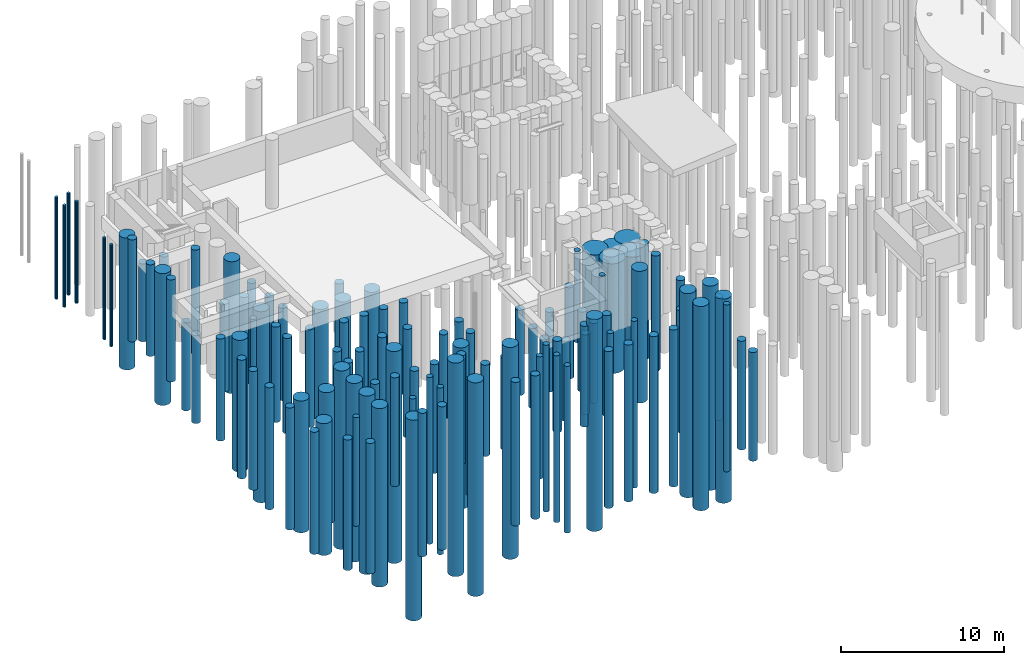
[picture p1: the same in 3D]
Properties of the parts of a building model (IFC2X3), part 9 of 18

# IfcColumn: 28_PBT_SC_beton_rechthoekig:1520x350_bestaand, 28_PBT_SC_beton_rechthoekig:1520x350_bestaand:1313274
Type - PredefinedType: COLUMN; Classification: 28.11 hoofddraagconstructies - kolommen en liggers, kolom-/liggerconstructies (Uniformat); Material: 00_PBT_MAT_beton t.p.g.
Type - Pset_ColumnCommon - IsExternal: no; LoadBearing: yes
Type - Pset_ProductRequirements - Category: Structural Columns
Type - Pset_ReinforcementBarPitchOfColumn - Description: 1520x350
Type - Pset_Pieters - Breedte: 1520 mm; Hoogte: 350 mm; Codering - NL-SfB: 28.11; Omschrijving NL-SfB: hoofddraagconstructies - kolommen en liggers, kolom-/liggerconstructies; Materiaal: 00_PBT_MAT_beton t.p.g.; Description: 1520x350
BaseQuantities - CrossSectionArea: 5482400 mm2; NetVolume: 1.37494 m3
Pset_ColumnCommon - Reference: 28_PBT_SC_beton_rechthoekig:1520x350_bestaand
Pset_QuantityTakeOff - Reference: 28_PBT_SC_beton_rechthoekig:1520x350_bestaand
Pset_ReinforcementBarPitchOfColumn - Reference: 28_PBT_SC_beton_rechthoekig:1520x350_bestaand
Pset_Pieters - Dragend/niet dragend: yes; In/uitwendig: no; Bouwlaag: Level: -1 kelder_Offset1000; Naamgeving element: 28_PBT_SC_beton_rechthoekig: 1520x350_bestaand; Fase: Bestaand

# IfcColumn: 28_PBT_SC_beton_rechthoekig:300x300_bestaand (12)
In: -1 kelder
Type - PredefinedType: COLUMN; Classification: 28.11 hoofddraagconstructies - kolommen en liggers, kolom-/liggerconstructies (Uniformat); Material: 00_PBT_MAT_beton t.p.g.
Type - Pset_ColumnCommon - IsExternal: no; LoadBearing: yes
Type - Pset_ProductRequirements - Category: Structural Columns
Type - Pset_ReinforcementBarPitchOfColumn - Description: 300x300
Type - Pset_Pieters - Breedte: 300 mm; Hoogte: 300 mm; Codering - NL-SfB: 28.11; Omschrijving NL-SfB: hoofddraagconstructies - kolommen en liggers, kolom-/liggerconstructies; Materiaal: 00_PBT_MAT_beton t.p.g.; Description: 300x300
Pset_ColumnCommon - Reference: 28_PBT_SC_beton_rechthoekig:300x300_bestaand
Pset_QuantityTakeOff - Reference: 28_PBT_SC_beton_rechthoekig:300x300_bestaand
Pset_ReinforcementBarPitchOfColumn - Reference: 28_PBT_SC_beton_rechthoekig:300x300_bestaand
Pset_Pieters - Dragend/niet dragend: yes; In/uitwendig: no; Bouwlaag: Level: -1 kelder_Offset1000; Naamgeving element: 28_PBT_SC_beton_rechthoekig: 300x300_bestaand; Fase: Bestaand
Name (28_PBT_SC_beton_rechthoekig:300x300_bestaand:...) | CrossSectionArea (mm2) | NetVolume (m3)
1371060 | 1878000 | 0.2682
1371077 | 1878000 | 0.2682
1371146 | 1878000 | 0.2682
1371148 | 1878000 | 0.2682
1371764 | 1878000 | 0.2682
1372634 | 1878000 | 0.2682
1372653 | 1878000 | 0.2682
1372907 | 1878000 | 0.2682
1373101 | 1896000 | 0.2574
1373103 | 1878000 | 0.2682
1373105 | 1896000 | 0.2574
1373107 | 1878000 | 0.2682

# IfcColumn: 28_PBT_SC_beton_rechthoekig:350x350_bestaand (7)
In: -1 kelder
Type - PredefinedType: COLUMN; Classification: 28.11 hoofddraagconstructies - kolommen en liggers, kolom-/liggerconstructies (Uniformat); Material: 00_PBT_MAT_beton t.p.g.
Type - Pset_ColumnCommon - IsExternal: no; LoadBearing: yes
Type - Pset_ProductRequirements - Category: Structural Columns
Type - Pset_ReinforcementBarPitchOfColumn - Description: 350x350
Type - Pset_Pieters - Breedte: 350 mm; Hoogte: 350 mm; Codering - NL-SfB: 28.11; Omschrijving NL-SfB: hoofddraagconstructies - kolommen en liggers, kolom-/liggerconstructies; Materiaal: 00_PBT_MAT_beton t.p.g.; Description: 350x350
BaseQuantities - CrossSectionArea: 2271500 mm2; NetVolume: 0.376075 m3
Pset_ColumnCommon - Reference: 28_PBT_SC_beton_rechthoekig:350x350_bestaand
Pset_QuantityTakeOff - Reference: 28_PBT_SC_beton_rechthoekig:350x350_bestaand
Pset_ReinforcementBarPitchOfColumn - Reference: 28_PBT_SC_beton_rechthoekig:350x350_bestaand
Pset_Pieters - Bouwlaag: Level: -1 kelder_Offset1000; Naamgeving element: 28_PBT_SC_beton_rechthoekig: 350x350_bestaand; Fase: Bestaand; Dragend/niet dragend: yes; In/uitwendig: no
Name (28_PBT_SC_beton_rechthoekig:350x350_bestaand:...)
1297378
1298959
1298975
1298990
1299005
1299020
1299074

# IfcColumn: 28_PBT_SC_beton_rechthoekig:420x250_bestaand, 28_PBT_SC_beton_rechthoekig:420x250_bestaand:1369682
In: -1 kelder
Type - PredefinedType: COLUMN; Classification: 28.11 hoofddraagconstructies - kolommen en liggers, kolom-/liggerconstructies (Uniformat); Material: 00_PBT_MAT_beton t.p.g.
Type - Pset_ColumnCommon - IsExternal: no; LoadBearing: yes
Type - Pset_ProductRequirements - Category: Structural Columns
Type - Pset_ReinforcementBarPitchOfColumn - Description: 420x250
Type - Pset_Pieters - Breedte: 420 mm; Hoogte: 250 mm; Codering - NL-SfB: 28.11; Omschrijving NL-SfB: hoofddraagconstructies - kolommen en liggers, kolom-/liggerconstructies; Materiaal: 00_PBT_MAT_beton t.p.g.; Description: 420x250
BaseQuantities - CrossSectionArea: 1512000 mm2; NetVolume: 0.2205 m3
Pset_ColumnCommon - Reference: 28_PBT_SC_beton_rechthoekig:420x250_bestaand
Pset_QuantityTakeOff - Reference: 28_PBT_SC_beton_rechthoekig:420x250_bestaand
Pset_ReinforcementBarPitchOfColumn - Reference: 28_PBT_SC_beton_rechthoekig:420x250_bestaand
Pset_Pieters - Dragend/niet dragend: yes; In/uitwendig: no; Bouwlaag: Level: -1 kelder_Offset1000; Naamgeving element: 28_PBT_SC_beton_rechthoekig: 420x250_bestaand; Fase: Bestaand

# IfcColumn: 28_PBT_SC_beton_rechthoekig:500x300_bestaand (2)
In: -1 kelder
Type - PredefinedType: COLUMN; Classification: 28.11 hoofddraagconstructies - kolommen en liggers, kolom-/liggerconstructies (Uniformat); Material: 00_PBT_MAT_beton t.p.g.
Type - Pset_ColumnCommon - IsExternal: no; LoadBearing: yes
Type - Pset_ProductRequirements - Category: Structural Columns
Type - Pset_ReinforcementBarPitchOfColumn - Description: 500x300
Type - Pset_Pieters - Breedte: 500 mm; Hoogte: 300 mm; Codering - NL-SfB: 28.11; Omschrijving NL-SfB: hoofddraagconstructies - kolommen en liggers, kolom-/liggerconstructies; Materiaal: 00_PBT_MAT_beton t.p.g.; Description: 500x300
Pset_ColumnCommon - Reference: 28_PBT_SC_beton_rechthoekig:500x300_bestaand
Pset_QuantityTakeOff - Reference: 28_PBT_SC_beton_rechthoekig:500x300_bestaand
Pset_ReinforcementBarPitchOfColumn - Reference: 28_PBT_SC_beton_rechthoekig:500x300_bestaand
Pset_Pieters - Dragend/niet dragend: yes; In/uitwendig: no; Bouwlaag: Level: -1 kelder_Offset1000; Naamgeving element: 28_PBT_SC_beton_rechthoekig: 500x300_bestaand; Fase: Bestaand
Name (28_PBT_SC_beton_rechthoekig:500x300_bestaand:...) | CrossSectionArea (mm2) | NetVolume (m3)
1369363 | 1830000 | 0.315
1369752 | 2278000 | 0.399

# IfcColumn: 28_PBT_SC_beton_rechthoekig:600x200_bestaand (2)
In: -2 kelder
Type - PredefinedType: COLUMN; Classification: 28.11 hoofddraagconstructies - kolommen en liggers, kolom-/liggerconstructies (Uniformat); Material: 00_PBT_MAT_beton t.p.g.
Type - Pset_ColumnCommon - IsExternal: no; LoadBearing: yes
Type - Pset_ProductRequirements - Category: Structural Columns
Type - Pset_ReinforcementBarPitchOfColumn - Description: 600x200
Type - Pset_Pieters - Breedte: 600 mm; Hoogte: 200 mm; Codering - NL-SfB: 28.11; Omschrijving NL-SfB: hoofddraagconstructies - kolommen en liggers, kolom-/liggerconstructies; Materiaal: 00_PBT_MAT_beton t.p.g.; Description: 600x200
BaseQuantities - CrossSectionArea: 760000 mm2; NetVolume: 0.096 m3
Pset_ColumnCommon - Reference: 28_PBT_SC_beton_rechthoekig:600x200_bestaand
Pset_QuantityTakeOff - Reference: 28_PBT_SC_beton_rechthoekig:600x200_bestaand
Pset_ReinforcementBarPitchOfColumn - Reference: 28_PBT_SC_beton_rechthoekig:600x200_bestaand
Pset_Pieters - Dragend/niet dragend: yes; In/uitwendig: no; Bouwlaag: Level: -2 kelder_Offset1000; Naamgeving element: 28_PBT_SC_beton_rechthoekig: 600x200_bestaand; Fase: Bestaand
Name (28_PBT_SC_beton_rechthoekig:600x200_bestaand:...)
1657491
1658145

# IfcColumn: 28_PBT_SC_beton_rechthoekig:600x600_bestaand, 28_PBT_SC_beton_rechthoekig:600x600_bestaand:1377782
In: -1 kelder
Type - PredefinedType: COLUMN; Classification: 28.11 hoofddraagconstructies - kolommen en liggers, kolom-/liggerconstructies (Uniformat); Material: 00_PBT_MAT_beton t.p.g.
Type - Pset_ColumnCommon - IsExternal: no; LoadBearing: yes
Type - Pset_ProductRequirements - Category: Structural Columns
Type - Pset_ReinforcementBarPitchOfColumn - Description: 600x600
Type - Pset_Pieters - Breedte: 600 mm; Hoogte: 600 mm; Codering - NL-SfB: 28.11; Omschrijving NL-SfB: hoofddraagconstructies - kolommen en liggers, kolom-/liggerconstructies; Materiaal: 00_PBT_MAT_beton t.p.g.; Description: 600x600
BaseQuantities - CrossSectionArea: 3696000 mm2; NetVolume: 1.0008 m3
Pset_ColumnCommon - Reference: 28_PBT_SC_beton_rechthoekig:600x600_bestaand
Pset_QuantityTakeOff - Reference: 28_PBT_SC_beton_rechthoekig:600x600_bestaand
Pset_ReinforcementBarPitchOfColumn - Reference: 28_PBT_SC_beton_rechthoekig:600x600_bestaand
Pset_Pieters - Dragend/niet dragend: yes; In/uitwendig: no; Bouwlaag: Level: -1 kelder_Offset1000; Naamgeving element: 28_PBT_SC_beton_rechthoekig: 600x600_bestaand; Fase: Bestaand

# IfcColumn: 28_PBT_SC_beton_rechthoekig:645x400_bestaand, 28_PBT_SC_beton_rechthoekig:645x400_bestaand:1302621
In: -1 kelder
Type - PredefinedType: COLUMN; Classification: 28.11 hoofddraagconstructies - kolommen en liggers, kolom-/liggerconstructies (Uniformat); Material: 00_PBT_MAT_beton t.p.g.
Type - Pset_ColumnCommon - IsExternal: no; LoadBearing: yes
Type - Pset_ProductRequirements - Category: Structural Columns
Type - Pset_ReinforcementBarPitchOfColumn - Description: 645x400
Type - Pset_Pieters - Breedte: 645 mm; Hoogte: 400 mm; Codering - NL-SfB: 28.11; Omschrijving NL-SfB: hoofddraagconstructies - kolommen en liggers, kolom-/liggerconstructies; Materiaal: 00_PBT_MAT_beton t.p.g.; Description: 645x400
BaseQuantities - CrossSectionArea: 2536888 mm2; NetVolume: 0.444356 m3
Pset_ColumnCommon - Reference: 28_PBT_SC_beton_rechthoekig:645x400_bestaand
Pset_QuantityTakeOff - Reference: 28_PBT_SC_beton_rechthoekig:645x400_bestaand
Pset_ReinforcementBarPitchOfColumn - Reference: 28_PBT_SC_beton_rechthoekig:645x400_bestaand
Pset_Pieters - Dragend/niet dragend: yes; In/uitwendig: no; Bouwlaag: Level: -1 kelder_Offset1000; Naamgeving element: 28_PBT_SC_beton_rechthoekig: 645x400_bestaand; Fase: Bestaand

# IfcColumn: 28_PBT_SC_beton_rechthoekig:700x350_bestaand (5)
In: -1 kelder
Type - PredefinedType: COLUMN; Classification: 28.11 hoofddraagconstructies - kolommen en liggers, kolom-/liggerconstructies (Uniformat); Material: 00_PBT_MAT_beton t.p.g.
Type - Pset_ColumnCommon - IsExternal: no; LoadBearing: yes
Type - Pset_ProductRequirements - Category: Structural Columns
Type - Pset_ReinforcementBarPitchOfColumn - Description: 700x350
Type - Pset_Pieters - Breedte: 700 mm; Hoogte: 350 mm; Codering - NL-SfB: 28.11; Omschrijving NL-SfB: hoofddraagconstructies - kolommen en liggers, kolom-/liggerconstructies; Materiaal: 00_PBT_MAT_beton t.p.g.; Description: 700x350
Pset_ColumnCommon - Reference: 28_PBT_SC_beton_rechthoekig:700x350_bestaand
Pset_QuantityTakeOff - Reference: 28_PBT_SC_beton_rechthoekig:700x350_bestaand
Pset_ReinforcementBarPitchOfColumn - Reference: 28_PBT_SC_beton_rechthoekig:700x350_bestaand
Pset_Pieters - Dragend/niet dragend: yes; In/uitwendig: no; Bouwlaag: Level: -1 kelder_Offset1000; Naamgeving element: 28_PBT_SC_beton_rechthoekig: 700x350_bestaand; Fase: Bestaand
Name (28_PBT_SC_beton_rechthoekig:700x350_bestaand:...) | CrossSectionArea (mm2) | NetVolume (m3)
1299123 | 3468500 | 0.75215
1299125 | 3468500 | 0.75215
1299127 | 3468500 | 0.75215
1299129 | 3468500 | 0.75215
1328565 | 2442500 | 0.4298

# IfcColumn: 28_PBT_SC_beton_rechthoekig:C30/37_1785x600 (2)
Type - PredefinedType: COLUMN; Classification: 28.11 hoofddraagconstructies - kolommen en liggers, kolom-/liggerconstructies (Uniformat); Material: 00_PBT_MAT_beton t.p.g._C30/37
Type - Pset_ColumnCommon - IsExternal: no; LoadBearing: yes
Type - Pset_ProductRequirements - Category: Structural Columns
Type - Pset_ReinforcementBarPitchOfColumn - Description: 1785x600
Type - Pset_Pieters - Breedte: 1785 mm; Hoogte: 600 mm; Codering - NL-SfB: 28.11; Omschrijving NL-SfB: hoofddraagconstructies - kolommen en liggers, kolom-/liggerconstructies; Materiaal: 00_PBT_MAT_beton t.p.g._C30/37; Materiaalkwaliteit: C30/37; Description: 1785x600
Pset_ColumnCommon - Slope: 0 deg; Reference: 28_PBT_SC_beton_rechthoekig:C30/37_1785x600
Pset_QuantityTakeOff - Reference: 28_PBT_SC_beton_rechthoekig:C30/37_1785x600
Pset_ReinforcementBarPitchOfColumn - Reference: 28_PBT_SC_beton_rechthoekig:C30/37_1785x600
Pset_Pieters - Dragend/niet dragend: yes; Naamgeving element: 28_PBT_SC_beton_rechthoekig: C30/37_1785x600; Fase: Nieuw
Name (28_PBT_SC_beton_rechthoekig:C30/37_1785x600:...) | In | CrossSectionArea (mm2) | NetVolume (m3) | Bouwlaag
1985242 | -1 kelder | 8583750 | 3.37365 | Level: -1 kelder
2005862 | 00 begane grond | 11469600 | 4.66956 | Level: 00 begane grond

# IfcColumn: 28_PBT_SC_beton_rechthoekig:C40/50_1500x700 (6)
In: 00 begane grond
Type - PredefinedType: COLUMN; Classification: 28.11 hoofddraagconstructies - kolommen en liggers, kolom-/liggerconstructies (Uniformat); Material: 00_PBT_MAT_beton t.p.g._C40/50
Type - Pset_ColumnCommon - IsExternal: no; LoadBearing: yes
Type - Pset_ProductRequirements - Category: Structural Columns
Type - Pset_ReinforcementBarPitchOfColumn - Description: 1500x700
Type - Pset_Pieters - Breedte: 1500 mm; Hoogte: 700 mm; Codering - NL-SfB: 28.11; Omschrijving NL-SfB: hoofddraagconstructies - kolommen en liggers, kolom-/liggerconstructies; Materiaal: 00_PBT_MAT_beton t.p.g._C40/50; Materiaalkwaliteit: C40/50; Description: 1500x700
Pset_ColumnCommon - Reference: 28_PBT_SC_beton_rechthoekig:C40/50_1500x700
Pset_QuantityTakeOff - Reference: 28_PBT_SC_beton_rechthoekig:C40/50_1500x700
Pset_ReinforcementBarPitchOfColumn - Reference: 28_PBT_SC_beton_rechthoekig:C40/50_1500x700
Pset_Pieters - Bouwlaag: Level: 00 begane grond; Naamgeving element: 28_PBT_SC_beton_rechthoekig: C40/50_1500x700; Fase: Nieuw
Name (28_PBT_SC_beton_rechthoekig:C40/50_1500x700:...) | CrossSectionArea (mm2) | NetVolume (m3) | Slope (deg)
2415780 | 39655350 | 14.1426
2416001 | 37839500 | 13.2892 | 0
2416022 | 37839500 | 13.2892 | 0
2416041 | 37839500 | 13.2892 | 0
2416060 | 37839500 | 13.2892 | 0
2416079 | 37839500 | 13.2892

# IfcColumn: 28_PBT_SC_beton_rond:C30/37_Ø800, 28_PBT_SC_beton_rond:C30/37_Ø800:2857955
In: -2 kelder
Type - PredefinedType: COLUMN; Classification: 28.11 hoofddraagconstructies - kolommen en liggers, kolom-/liggerconstructies (Uniformat); Material: 00_PBT_MAT_beton t.p.g._C30/37
Type - Pset_ColumnCommon - IsExternal: no; LoadBearing: yes
Type - Pset_ProductRequirements - Category: Structural Columns
Type - Pset_ReinforcementBarPitchOfColumn - Description: Ø800
Type - Pset_Pieters - Diameter: 800 mm; Codering - NL-SfB: 28.11; Omschrijving NL-SfB: hoofddraagconstructies - kolommen en liggers, kolom-/liggerconstructies; Materiaal: 00_PBT_MAT_beton t.p.g._C30/37; Materiaalkwaliteit: C30/37; Description: Ø800
BaseQuantities - CrossSectionArea: 6974318 mm2; NetVolume: 2.58863 m3
Pset_ColumnCommon - Reference: 28_PBT_SC_beton_rond:C30/37_Ø800
Pset_QuantityTakeOff - Reference: 28_PBT_SC_beton_rond:C30/37_Ø800
Pset_ReinforcementBarPitchOfColumn - Reference: 28_PBT_SC_beton_rond:C30/37_Ø800
Pset_Pieters - Dragend/niet dragend: yes; Bouwlaag: Level: -2 kelder; Naamgeving element: 28_PBT_SC_beton_rond: C30/37_Ø800; Fase: Nieuw

# IfcColumn: 28_PBT_SC_beton_rond:Ø300_bestaand (2)
In: -1 kelder
Type - PredefinedType: COLUMN; Classification: 28.11 hoofddraagconstructies - kolommen en liggers, kolom-/liggerconstructies (Uniformat); Material: 00_PBT_MAT_beton t.p.g.
Type - Pset_ColumnCommon - IsExternal: no; LoadBearing: yes
Type - Pset_ProductRequirements - Category: Structural Columns
Type - Pset_ReinforcementBarPitchOfColumn - Description: Ø300
Type - Pset_Pieters - Diameter: 300 mm; Codering - NL-SfB: 28.11; Omschrijving NL-SfB: hoofddraagconstructies - kolommen en liggers, kolom-/liggerconstructies; Materiaal: 00_PBT_MAT_beton t.p.g.; Description: Ø300
BaseQuantities - CrossSectionArea: 1517380 mm2; NetVolume: 0.216995 m3
Pset_ColumnCommon - Reference: 28_PBT_SC_beton_rond:Ø300_bestaand
Pset_QuantityTakeOff - Reference: 28_PBT_SC_beton_rond:Ø300_bestaand
Pset_ReinforcementBarPitchOfColumn - Reference: 28_PBT_SC_beton_rond:Ø300_bestaand
Pset_Pieters - Dragend/niet dragend: yes; In/uitwendig: no; Bouwlaag: Level: -1 kelder_Offset1000; Naamgeving element: 28_PBT_SC_beton_rond: Ø300_bestaand; Fase: Bestaand
Name (28_PBT_SC_beton_rond:Ø300_bestaand:...)
1299252
1299254

# IfcColumn: 28_PBT_SC_staal_H-profiel:HE140A_bestaand (4)
In: 00 begane grond
Type - PredefinedType: COLUMN; Classification: 28.11 hoofddraagconstructies - kolommen en liggers, kolom-/liggerconstructies (Uniformat); Material: 00_PBT_MAT_staal
Type - Pset_ColumnCommon - IsExternal: no; LoadBearing: yes
Type - Pset_ProductRequirements - Category: Structural Columns
Type - Pset_ReinforcementBarPitchOfColumn - Description: HE140A
Type - Pset_Pieters - Breedte: 140 mm; Hoogte: 133 mm; Codering - NL-SfB: 28.11; Omschrijving NL-SfB: hoofddraagconstructies - kolommen en liggers, kolom-/liggerconstructies; Materiaal: 00_PBT_MAT_staal; Description: HE140A
Pset_ColumnCommon - Reference: 28_PBT_SC_staal_H-profiel:HE140A_bestaand
Pset_QuantityTakeOff - Reference: 28_PBT_SC_staal_H-profiel:HE140A_bestaand
Pset_ReinforcementBarPitchOfColumn - Reference: 28_PBT_SC_staal_H-profiel:HE140A_bestaand
Pset_Pieters - Dragend/niet dragend: yes; In/uitwendig: no; Bouwlaag: Level: 00 begane grond_Offset1000; Naamgeving element: 28_PBT_SC_staal_H-profiel: HE140A_bestaand; Fase: Bestaand
Name (28_PBT_SC_staal_H-profiel:HE140A_bestaand:...) | CrossSectionArea (mm2) | NetVolume (m3)
1533858 | 477795 | 0.00375425
1533986 | 358635 | 0.00281176
1570779 | 477795 | 0.00375425
1570781 | 358635 | 0.00281176

# IfcColumn: 28_PBT_SC_staal_H-profiel:S355_HE140A (25)
Type - PredefinedType: COLUMN; Classification: 28.11 hoofddraagconstructies - kolommen en liggers, kolom-/liggerconstructies (Uniformat); Material: 00_PBT_MAT_staal_S355
Type - Pset_ColumnCommon - IsExternal: no; LoadBearing: yes
Type - Pset_ProductRequirements - Category: Structural Columns
Type - Pset_ReinforcementBarPitchOfColumn - Description: HE140A
Type - Pset_Pieters - Breedte: 140 mm; Hoogte: 133 mm; Codering - NL-SfB: 28.11; Omschrijving NL-SfB: hoofddraagconstructies - kolommen en liggers, kolom-/liggerconstructies; Materiaal: 00_PBT_MAT_staal_S355; Materiaalkwaliteit: S355; Description: HE140A
Pset_ColumnCommon - Reference: 28_PBT_SC_staal_H-profiel:S355_HE140A
Pset_QuantityTakeOff - Reference: 28_PBT_SC_staal_H-profiel:S355_HE140A
Pset_ReinforcementBarPitchOfColumn - Reference: 28_PBT_SC_staal_H-profiel:S355_HE140A
Pset_Pieters - Naamgeving element: 28_PBT_SC_staal_H-profiel: S355_HE140A; Fase: Nieuw
Name (28_PBT_SC_staal_H-profiel:S355_HE140A:...) | In | CrossSectionArea (mm2) | NetVolume (m3) | Bouwlaag
3823486 | 06 zesde verdieping | 784315 | 0.00617866 | Level: 06 zesde verdieping
3823532 | 06 zesde verdieping | 784315 | 0.00617866 | Level: 06 zesde verdieping
3823554 | 06 zesde verdieping | 784315 | 0.00617866 | Level: 06 zesde verdieping
3824674 | 06 zesde verdieping | 784315 | 0.00617866 | Level: 06 zesde verdieping
3824678 | 06 zesde verdieping | 784315 | 0.00617866 | Level: 06 zesde verdieping
3824682 | 06 zesde verdieping | 784315 | 0.00617866 | Level: 06 zesde verdieping
3824686 | 06 zesde verdieping | 784315 | 0.00617866 | Level: 06 zesde verdieping
3824690 | 06 zesde verdieping | 784315 | 0.00617866 | Level: 06 zesde verdieping
3825613 | 06 zesde verdieping | 784315 | 0.00617866 | Level: 06 zesde verdieping
3825960 | 06 zesde verdieping | 784315 | 0.00617866 | Level: 06 zesde verdieping
3826051 | 06 zesde verdieping | 784315 | 0.00617866 | Level: 06 zesde verdieping
3827898 | 01 eerste verdieping | 1435044 | 0.0113256 | Level: 01 eerste verdieping | Pset_ColumnCommon - Slope: 0 deg
3827962 | 02 tweede verdieping | 1188384 | 0.00937462 | Level: 02 tweede verdieping | Pset_ColumnCommon - Slope: 0 deg
3828038 | 03 derde verdieping | 996139 | 0.00785407 | Level: 03 derde verdieping | Pset_ColumnCommon - Slope: 0 deg
3830111 | 01 eerste verdieping | 1435044 | 0.0113256 | Level: 01 eerste verdieping | Pset_ColumnCommon - Slope: 0 deg
3830114 | 02 tweede verdieping | 1188384 | 0.00937462 | Level: 02 tweede verdieping | Pset_ColumnCommon - Slope: 0 deg
3830117 | 03 derde verdieping | 996139 | 0.00785407 | Level: 03 derde verdieping | Pset_ColumnCommon - Slope: 0 deg
4236216 | 06 zesde verdieping | 784315 | 0.00617866 | Level: 06 zesde verdieping
4236499 | 06 zesde verdieping | 784315 | 0.00617866 | Level: 06 zesde verdieping
4236542 | 06 zesde verdieping | 784315 | 0.00617866 | Level: 06 zesde verdieping
4236644 | 06 zesde verdieping | 784315 | 0.00617866 | Level: 06 zesde verdieping
4236648 | 06 zesde verdieping | 784315 | 0.00617866 | Level: 06 zesde verdieping
4236652 | 06 zesde verdieping | 784315 | 0.00617866 | Level: 06 zesde verdieping
4544682 | 04 vierde verdieping | 306205 | 0.00239706 | Level: 04 vierde verdieping | Pset_ColumnCommon - Slope: 0 deg
4544684 | 04 vierde verdieping | 306205 | 0.00239706 | Level: 04 vierde verdieping | Pset_ColumnCommon - Slope: 0 deg

# IfcColumn: 28_PBT_SC_staal_H-profiel:S355_HE160A (8)
In: 04 vierde verdieping
Type - PredefinedType: COLUMN; Classification: 28.11 hoofddraagconstructies - kolommen en liggers, kolom-/liggerconstructies (Uniformat); Material: 00_PBT_MAT_staal_S355
Type - Pset_ColumnCommon - IsExternal: no; LoadBearing: yes
Type - Pset_ProductRequirements - Category: Structural Columns
Type - Pset_ReinforcementBarPitchOfColumn - Description: HE160A
Type - Pset_Pieters - Breedte: 160 mm; Hoogte: 152 mm; Codering - NL-SfB: 28.11; Omschrijving NL-SfB: hoofddraagconstructies - kolommen en liggers, kolom-/liggerconstructies; Materiaal: 00_PBT_MAT_staal_S355; Materiaalkwaliteit: S355; Description: HE160A
Pset_ColumnCommon - Reference: 28_PBT_SC_staal_H-profiel:S355_HE160A
Pset_QuantityTakeOff - Reference: 28_PBT_SC_staal_H-profiel:S355_HE160A
Pset_ReinforcementBarPitchOfColumn - Reference: 28_PBT_SC_staal_H-profiel:S355_HE160A
Pset_Pieters - Bouwlaag: Level: 04 vierde verdieping; Naamgeving element: 28_PBT_SC_staal_H-profiel: S355_HE160A; Fase: Nieuw
Name (28_PBT_SC_staal_H-profiel:S355_HE160A:...) | CrossSectionArea (mm2) | NetVolume (m3)
2957430 | 1520030 | 0.012973
2957994 | 1520030 | 0.012973
2958108 | 1512417 | 0.0129079 | Pset_ColumnCommon - Slope: 0 deg
2958138 | 1408652 | 0.01202 | Pset_ColumnCommon - Slope: 0 deg
2970148 | 330126 | 0.00279156
2970150 | 330126 | 0.00279156
2970221 | 172668 | 0.00144405 | Pset_ColumnCommon - Slope: 0 deg
2970320 | 172668 | 0.00144405 | Pset_ColumnCommon - Slope: 0 deg

# IfcColumn: 28_PBT_SC_staal_H-profiel:S355_HE180A (36)
Type - PredefinedType: COLUMN; Classification: 28.11 hoofddraagconstructies - kolommen en liggers, kolom-/liggerconstructies (Uniformat); Material: 00_PBT_MAT_staal_S355
Type - Pset_ColumnCommon - IsExternal: no; LoadBearing: yes
Type - Pset_ProductRequirements - Category: Structural Columns
Type - Pset_ReinforcementBarPitchOfColumn - Description: HE180A
Type - Pset_Pieters - Breedte: 180 mm; Hoogte: 171 mm; Codering - NL-SfB: 28.11; Omschrijving NL-SfB: hoofddraagconstructies - kolommen en liggers, kolom-/liggerconstructies; Materiaal: 00_PBT_MAT_staal_S355; Materiaalkwaliteit: S355; Description: HE180A
Pset_ColumnCommon - Reference: 28_PBT_SC_staal_H-profiel:S355_HE180A
Pset_QuantityTakeOff - Reference: 28_PBT_SC_staal_H-profiel:S355_HE180A
Pset_ReinforcementBarPitchOfColumn - Reference: 28_PBT_SC_staal_H-profiel:S355_HE180A
Pset_Pieters - Naamgeving element: 28_PBT_SC_staal_H-profiel: S355_HE180A; Fase: Nieuw
Name (28_PBT_SC_staal_H-profiel:S355_HE180A:...) | In | CrossSectionArea (mm2) | NetVolume (m3) | Bouwlaag
3819014 | 04 vierde verdieping | 1453836 | 0.0128062 | Level: 04 vierde verdieping
3819959 | 04 vierde verdieping | 1361654 | 0.0119917 | Level: 04 vierde verdieping
3819982 | 04 vierde verdieping | 1453836 | 0.0128062 | Level: 04 vierde verdieping
3820095 | 04 vierde verdieping | 1090228 | 0.00959336 | Level: 04 vierde verdieping
3820098 | 04 vierde verdieping | 1314538 | 0.0115754 | Level: 04 vierde verdieping | Pset_ColumnCommon - Slope: 0 deg
3820102 | 04 vierde verdieping | 1314538 | 0.0115754 | Level: 04 vierde verdieping
3820193 | 04 vierde verdieping | 1361654 | 0.0119917 | Level: 04 vierde verdieping
3820196 | 04 vierde verdieping | 1361654 | 0.0119917 | Level: 04 vierde verdieping
3820377 | 04 vierde verdieping | 1361654 | 0.0119917 | Level: 04 vierde verdieping
3820379 | 04 vierde verdieping | 1361654 | 0.0119917 | Level: 04 vierde verdieping
3820415 | 04 vierde verdieping | 1361654 | 0.0119917 | Level: 04 vierde verdieping
3820417 | 04 vierde verdieping | 1361654 | 0.0119917 | Level: 04 vierde verdieping
3820453 | 04 vierde verdieping | 1361654 | 0.0119917 | Level: 04 vierde verdieping
3820455 | 04 vierde verdieping | 1361654 | 0.0119917 | Level: 04 vierde verdieping
3820491 | 04 vierde verdieping | 1361654 | 0.0119917 | Level: 04 vierde verdieping
3820493 | 04 vierde verdieping | 1361654 | 0.0119917 | Level: 04 vierde verdieping
3820529 | 04 vierde verdieping | 1361654 | 0.0119917 | Level: 04 vierde verdieping
3820531 | 04 vierde verdieping | 1361654 | 0.0119917 | Level: 04 vierde verdieping
3820567 | 04 vierde verdieping | 1361654 | 0.0119917 | Level: 04 vierde verdieping
3820569 | 04 vierde verdieping | 1361654 | 0.0119917 | Level: 04 vierde verdieping
3822436 | 06 zesde verdieping | 1352284 | 0.0119089 | Level: 06 zesde verdieping
3822843 | 06 zesde verdieping | 1441906 | 0.0127008 | Level: 06 zesde verdieping
3823142 | 06 zesde verdieping | 1441906 | 0.0127008 | Level: 06 zesde verdieping
3823287 | 06 zesde verdieping | 1352284 | 0.0119089 | Level: 06 zesde verdieping
3823576 | 06 zesde verdieping | 1352284 | 0.0119089 | Level: 06 zesde verdieping
3824005 | 06 zesde verdieping | 1441906 | 0.0127008 | Level: 06 zesde verdieping
3824476 | 06 zesde verdieping | 1352284 | 0.0119089 | Level: 06 zesde verdieping
3824496 | 06 zesde verdieping | 1352284 | 0.0119089 | Level: 06 zesde verdieping
3824561 | 06 zesde verdieping | 1352284 | 0.0119089 | Level: 06 zesde verdieping
3824565 | 06 zesde verdieping | 1441906 | 0.0127008 | Level: 06 zesde verdieping
3824569 | 06 zesde verdieping | 1352284 | 0.0119089 | Level: 06 zesde verdieping
3824573 | 06 zesde verdieping | 1352284 | 0.0119089 | Level: 06 zesde verdieping
3824670 | 06 zesde verdieping | 1352284 | 0.0119089 | Level: 06 zesde verdieping
3824694 | 06 zesde verdieping | 1352284 | 0.0119089 | Level: 06 zesde verdieping
3913034 | 03 derde verdieping | 2272210 | 0.0200375 | Level: 03 derde verdieping | Pset_ColumnCommon - Slope: 0 deg
3913036 | 03 derde verdieping | 2318301 | 0.0204447 | Level: 03 derde verdieping | Pset_ColumnCommon - Slope: 0 deg

# IfcColumn: 28_PBT_SC_staal_H-profiel:S355_HE180A_1/2, 28_PBT_SC_staal_H-profiel:S355_HE180A_1/2:4773609
In: 05 vijfde verdieping
Type - PredefinedType: COLUMN; Classification: 28.11 hoofddraagconstructies - kolommen en liggers, kolom-/liggerconstructies (Uniformat); Material: 00_PBT_MAT_staal_S355
Type - Pset_ColumnCommon - IsExternal: no; LoadBearing: yes
Type - Pset_ProductRequirements - Category: Structural Columns
Type - Pset_ReinforcementBarPitchOfColumn - Description: 1/2 HE180A
Type - Pset_Pieters - Breedte: 180 mm; Hoogte: 171 mm; Codering - NL-SfB: 28.11; Omschrijving NL-SfB: hoofddraagconstructies - kolommen en liggers, kolom-/liggerconstructies; Materiaal: 00_PBT_MAT_staal_S355; Materiaalkwaliteit: S355; Description: 1/2 HE180A
BaseQuantities - CrossSectionArea: 116250 mm2; NetVolume: 0.000995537 m3
Pset_ColumnCommon - Slope: 0 deg; Reference: 28_PBT_SC_staal_H-profiel:S355_HE180A_1/2
Pset_QuantityTakeOff - Reference: 28_PBT_SC_staal_H-profiel:S355_HE180A_1/2
Pset_ReinforcementBarPitchOfColumn - Reference: 28_PBT_SC_staal_H-profiel:S355_HE180A_1/2
Pset_Pieters - Bouwlaag: Level: 05 vijfde verdieping; Naamgeving element: 28_PBT_SC_staal_H-profiel: S355_HE180A_1/2; Fase: Nieuw

# IfcColumn: 28_PBT_SC_staal_H-profiel:S355_HE200A (12)
In: 06 zesde verdieping
Type - PredefinedType: COLUMN; Classification: 28.11 hoofddraagconstructies - kolommen en liggers, kolom-/liggerconstructies (Uniformat); Material: 00_PBT_MAT_staal_S355
Type - Pset_ColumnCommon - IsExternal: no; LoadBearing: yes
Type - Pset_ProductRequirements - Category: Structural Columns
Type - Pset_ReinforcementBarPitchOfColumn - Description: HE200A
Type - Pset_Pieters - Breedte: 200 mm; Hoogte: 190 mm; Codering - NL-SfB: 28.11; Omschrijving NL-SfB: hoofddraagconstructies - kolommen en liggers, kolom-/liggerconstructies; Materiaal: 00_PBT_MAT_staal_S355; Materiaalkwaliteit: S355; Description: HE200A
Pset_ColumnCommon - Slope: 0 deg; Reference: 28_PBT_SC_staal_H-profiel:S355_HE200A
Pset_QuantityTakeOff - Reference: 28_PBT_SC_staal_H-profiel:S355_HE200A
Pset_ReinforcementBarPitchOfColumn - Reference: 28_PBT_SC_staal_H-profiel:S355_HE200A
Pset_Pieters - Bouwlaag: Level: 06 zesde verdieping; Naamgeving element: 28_PBT_SC_staal_H-profiel: S355_HE200A; Fase: Nieuw; Comments: om-en-om met staanders vakwerk t.b.v. opvang L-staal
Name (28_PBT_SC_staal_H-profiel:S355_HE200A:...) | CrossSectionArea (mm2) | NetVolume (m3)
5302071 | 421823 | 0.00393913
5302892 | 460384 | 0.00430456
5302923 | 475159 | 0.00444489
5302981 | 475159 | 0.00444489
5302999 | 439719 | 0.0041106
5303016 | 421465 | 0.00393704
5303146 | 402889 | 0.00376009
5303148 | 460384 | 0.00430456
5303150 | 475433 | 0.00444748
5303152 | 481028 | 0.00450061
5303154 | 440370 | 0.00411526
5303156 | 421757 | 0.00393981

# IfcColumn: 28_PBT_SC_staal_H-profiel:S355_HE200B (18)
Type - PredefinedType: COLUMN; Classification: 28.11 hoofddraagconstructies - kolommen en liggers, kolom-/liggerconstructies (Uniformat); Material: 00_PBT_MAT_staal_S355
Type - Pset_ColumnCommon - IsExternal: no; LoadBearing: yes
Type - Pset_ProductRequirements - Category: Structural Columns
Type - Pset_ReinforcementBarPitchOfColumn - Description: HE200B
Type - Pset_Pieters - Breedte: 200 mm; Hoogte: 200 mm; Codering - NL-SfB: 28.11; Omschrijving NL-SfB: hoofddraagconstructies - kolommen en liggers, kolom-/liggerconstructies; Materiaal: 00_PBT_MAT_staal_S355; Materiaalkwaliteit: S355; Description: HE200B
Pset_ColumnCommon - Reference: 28_PBT_SC_staal_H-profiel:S355_HE200B
Pset_QuantityTakeOff - Reference: 28_PBT_SC_staal_H-profiel:S355_HE200B
Pset_ReinforcementBarPitchOfColumn - Reference: 28_PBT_SC_staal_H-profiel:S355_HE200B
Pset_Pieters - Naamgeving element: 28_PBT_SC_staal_H-profiel: S355_HE200B; Fase: Nieuw
Name (28_PBT_SC_staal_H-profiel:S355_HE200B:...) | In | CrossSectionArea (mm2) | NetVolume (m3) | Bouwlaag
2434991 | 03 derde verdieping | 2088417 | 0.0282265 | Level: 03 derde verdieping
2435399 | 03 derde verdieping | 2088417 | 0.0282265 | Level: 03 derde verdieping
2435418 | 03 derde verdieping | 2088417 | 0.0282265 | Level: 03 derde verdieping
2585323 | 02 tweede verdieping | 2051006 | 0.027719 | Level: 02 tweede verdieping | Pset_ColumnCommon - Slope: 0 deg
2585329 | 01 eerste verdieping | 2033740 | 0.0274847 | Level: 01 eerste verdieping | Pset_ColumnCommon - Slope: 0 deg
2802157 | 03 derde verdieping | 1915752 | 0.0258841 | Level: 03 derde verdieping | Pset_ColumnCommon - Slope: 0 deg
3840993 | 04 vierde verdieping | 301338 | 0.00398216 | Level: 04 vierde verdieping
3841146 | 04 vierde verdieping | 49247.8 | 0.000562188 | Level: 04 vierde verdieping
3841172 | 04 vierde verdieping | 49247.8 | 0.000562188 | Level: 04 vierde verdieping
3841194 | 04 vierde verdieping | 49247.8 | 0.000562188 | Level: 04 vierde verdieping
3841490 | 04 vierde verdieping | 49247.8 | 0.000562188 | Level: 04 vierde verdieping
3842310 | 04 vierde verdieping | 49247.8 | 0.000562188 | Level: 04 vierde verdieping
4262473 | 03 derde verdieping | 33708 | 0.000351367 | Level: 03 derde verdieping | Pset_ColumnCommon - Slope: 0 deg; Pset_Pieters - Comments: momentvast aan liggers verbinden
4265415 | 03 derde verdieping | 111407 | 0.00140547 | Level: 03 derde verdieping | Pset_ColumnCommon - Slope: 0 deg; Pset_Pieters - Comments: momentvast aan liggers verbinden
4390942 | 04 vierde verdieping | 49247.8 | 0.000562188 | Level: 04 vierde verdieping
5209305 | 03 derde verdieping | 145940 | 0.00187396 | Level: 03 derde verdieping | Pset_ColumnCommon - Slope: 0 deg; Pset_Pieters - Comments: momentvast aan liggers verbinden
6291527 | 04 vierde verdieping | 47907.3 | 0.000537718 | Level: 04 vierde verdieping
6291574 | 04 vierde verdieping | 49247.8 | 0.000562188 | Level: 04 vierde verdieping

# IfcColumn: 28_PBT_SC_staal_H-profiel:S355_HE220B (5)
In: 04 vierde verdieping
Type - PredefinedType: COLUMN; Classification: 28.11 hoofddraagconstructies - kolommen en liggers, kolom-/liggerconstructies (Uniformat); Material: 00_PBT_MAT_staal_S355
Type - Pset_ColumnCommon - IsExternal: no; LoadBearing: yes
Type - Pset_ProductRequirements - Category: Structural Columns
Type - Pset_ReinforcementBarPitchOfColumn - Description: HE220B
Type - Pset_Pieters - Breedte: 220 mm; Hoogte: 220 mm; Codering - NL-SfB: 28.11; Omschrijving NL-SfB: hoofddraagconstructies - kolommen en liggers, kolom-/liggerconstructies; Materiaal: 00_PBT_MAT_staal_S355; Materiaalkwaliteit: S355; Description: HE220B
Pset_ColumnCommon - Reference: 28_PBT_SC_staal_H-profiel:S355_HE220B
Pset_QuantityTakeOff - Reference: 28_PBT_SC_staal_H-profiel:S355_HE220B
Pset_ReinforcementBarPitchOfColumn - Reference: 28_PBT_SC_staal_H-profiel:S355_HE220B
Pset_Pieters - Bouwlaag: Level: 04 vierde verdieping; Naamgeving element: 28_PBT_SC_staal_H-profiel: S355_HE220B; Fase: Nieuw
Name (28_PBT_SC_staal_H-profiel:S355_HE220B:...) | CrossSectionArea (mm2) | NetVolume (m3)
2439548 | 2288929 | 0.0326839
2439550 | 2273053 | 0.0324563
2439552 | 2273053 | 0.0324563
2439554 | 2273053 | 0.0324563
2977634 | 2273053 | 0.0324563

# IfcColumn: 28_PBT_SC_staal_H-profiel:S355_HE240B (17)
Type - PredefinedType: COLUMN; Classification: 28.11 hoofddraagconstructies - kolommen en liggers, kolom-/liggerconstructies (Uniformat); Material: 00_PBT_MAT_staal_S355
Type - Pset_ColumnCommon - IsExternal: no; LoadBearing: yes
Type - Pset_ProductRequirements - Category: Structural Columns
Type - Pset_ReinforcementBarPitchOfColumn - Description: HE240B
Type - Pset_Pieters - Breedte: 240 mm; Hoogte: 240 mm; Codering - NL-SfB: 28.11; Omschrijving NL-SfB: hoofddraagconstructies - kolommen en liggers, kolom-/liggerconstructies; Materiaal: 00_PBT_MAT_staal_S355; Materiaalkwaliteit: S355; Description: HE240B
Pset_ColumnCommon - Reference: 28_PBT_SC_staal_H-profiel:S355_HE240B
Pset_QuantityTakeOff - Reference: 28_PBT_SC_staal_H-profiel:S355_HE240B
Pset_ReinforcementBarPitchOfColumn - Reference: 28_PBT_SC_staal_H-profiel:S355_HE240B
Pset_Pieters - Naamgeving element: 28_PBT_SC_staal_H-profiel: S355_HE240B; Fase: Nieuw
Name (28_PBT_SC_staal_H-profiel:S355_HE240B:...) | In | CrossSectionArea (mm2) | NetVolume (m3) | Bouwlaag
2226099 | 01 eerste verdieping | 7376656 | 0.112822 | Level: 01 eerste verdieping | Pset_ColumnCommon - Slope: 0 deg
2226187 | 01 eerste verdieping | 7376656 | 0.112822 | Level: 01 eerste verdieping | Pset_ColumnCommon - Slope: 0 deg
2226220 | 01 eerste verdieping | 7376656 | 0.112822 | Level: 01 eerste verdieping | Pset_ColumnCommon - Slope: 0 deg
2226289 | 02 tweede verdieping | 3868351 | 0.0590873 | Level: 02 tweede verdieping
2226291 | 02 tweede verdieping | 3868351 | 0.0590873 | Level: 02 tweede verdieping
2226295 | 02 tweede verdieping | 3868351 | 0.0590873 | Level: 02 tweede verdieping
2226298 | 02 tweede verdieping | 3868351 | 0.0590873 | Level: 02 tweede verdieping
2226301 | 02 tweede verdieping | 3868351 | 0.0590873 | Level: 02 tweede verdieping
2437091 | 03 derde verdieping | 2456725 | 0.0374661 | Level: 03 derde verdieping
2437108 | 03 derde verdieping | 2456725 | 0.0374661 | Level: 03 derde verdieping
2437218 | 03 derde verdieping | 2456725 | 0.0374661 | Level: 03 derde verdieping
2437233 | 03 derde verdieping | 2456725 | 0.0374661 | Level: 03 derde verdieping
3569361 | 02 tweede verdieping | 3902949 | 0.0596172 | Level: 02 tweede verdieping | Pset_ColumnCommon - Slope: 0 deg
4308229 | 03 derde verdieping | 62053.7 | 0.000785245 | Level: 03 derde verdieping
5526717 | 03 derde verdieping | 103572 | 0.00142116 | Level: 03 derde verdieping
5877230 | 03 derde verdieping | 98037.9 | 0.0013364 | Level: 03 derde verdieping
5877548 | 03 derde verdieping | 98037.9 | 0.0013364 | Level: 03 derde verdieping

# IfcColumn: 28_PBT_SC_staal_H-profiel:S355_HE260B (2)
In: 04 vierde verdieping
Type - PredefinedType: COLUMN; Classification: 28.11 hoofddraagconstructies - kolommen en liggers, kolom-/liggerconstructies (Uniformat); Material: 00_PBT_MAT_staal_S355
Type - Pset_ColumnCommon - IsExternal: no; LoadBearing: yes
Type - Pset_ProductRequirements - Category: Structural Columns
Type - Pset_ReinforcementBarPitchOfColumn - Description: HE260B
Type - Pset_Pieters - Breedte: 260 mm; Hoogte: 260 mm; Codering - NL-SfB: 28.11; Omschrijving NL-SfB: hoofddraagconstructies - kolommen en liggers, kolom-/liggerconstructies; Materiaal: 00_PBT_MAT_staal_S355; Materiaalkwaliteit: S355; Description: HE260B
BaseQuantities - CrossSectionArea: 551411 mm2; NetVolume: 0.00852805 m3
Pset_ColumnCommon - Reference: 28_PBT_SC_staal_H-profiel:S355_HE260B
Pset_QuantityTakeOff - Reference: 28_PBT_SC_staal_H-profiel:S355_HE260B
Pset_ReinforcementBarPitchOfColumn - Reference: 28_PBT_SC_staal_H-profiel:S355_HE260B
Pset_Pieters - Bouwlaag: Level: 04 vierde verdieping; Naamgeving element: 28_PBT_SC_staal_H-profiel: S355_HE260B; Fase: Nieuw
Name (28_PBT_SC_staal_H-profiel:S355_HE260B:...)
2992933
2992988

# IfcColumn: 28_PBT_SC_staal_H-profiel:S355_HE280B (75)
Type - PredefinedType: COLUMN; Classification: 28.11 hoofddraagconstructies - kolommen en liggers, kolom-/liggerconstructies (Uniformat); Material: 00_PBT_MAT_staal_S355
Type - Pset_ColumnCommon - IsExternal: no; LoadBearing: yes
Type - Pset_ProductRequirements - Category: Structural Columns
Type - Pset_ReinforcementBarPitchOfColumn - Description: HE280B
Type - Pset_Pieters - Breedte: 280 mm; Hoogte: 280 mm; Codering - NL-SfB: 28.11; Omschrijving NL-SfB: hoofddraagconstructies - kolommen en liggers, kolom-/liggerconstructies; Materiaal: 00_PBT_MAT_staal_S355; Materiaalkwaliteit: S355; Description: HE280B
Pset_ColumnCommon - Reference: 28_PBT_SC_staal_H-profiel:S355_HE280B
Pset_QuantityTakeOff - Reference: 28_PBT_SC_staal_H-profiel:S355_HE280B
Pset_ReinforcementBarPitchOfColumn - Reference: 28_PBT_SC_staal_H-profiel:S355_HE280B
Pset_Pieters - Naamgeving element: 28_PBT_SC_staal_H-profiel: S355_HE280B; Fase: Nieuw
Name (28_PBT_SC_staal_H-profiel:S355_HE280B:...) | In | CrossSectionArea (mm2) | NetVolume (m3) | Bouwlaag | Slope (deg)
2211713 | 01 eerste verdieping | 8801816 | 0.142728 | Level: 01 eerste verdieping
2212583 | 01 eerste verdieping | 8801816 | 0.142728 | Level: 01 eerste verdieping
2212641 | 03 derde verdieping | 2003026 | 0.0323158 | Level: 03 derde verdieping | 0
2212660 | 01 eerste verdieping | 7750248 | 0.125651 | Level: 01 eerste verdieping
2212662 | 01 eerste verdieping | 7750248 | 0.125651 | Level: 01 eerste verdieping
2212681 | 01 eerste verdieping | 7750248 | 0.125651 | Level: 01 eerste verdieping
2212683 | 01 eerste verdieping | 7750248 | 0.125651 | Level: 01 eerste verdieping
2225752 | 01 eerste verdieping | 8623858 | 0.139838 | Level: 01 eerste verdieping | 0
2225755 | 01 eerste verdieping | 8623858 | 0.139838 | Level: 01 eerste verdieping | 0
2242575 | 00 begane grond | 3196151 | 0.0516922 | Level: 00 begane grond | 0
2242939 | 00 begane grond | 3232552 | 0.0522833 | Level: 00 begane grond
2246467 | 00 begane grond | 3232552 | 0.0522833 | Level: 00 begane grond | 0
2250340 | 01 eerste verdieping | 2840236 | 0.0459121 | Level: 01 eerste verdieping | 0
2250344 | 01 eerste verdieping | 2783613 | 0.0449926 | Level: 01 eerste verdieping | 0
2250350 | 01 eerste verdieping | 2775524 | 0.0448612 | Level: 01 eerste verdieping | 0
2250528 | 01 eerste verdieping | 2795747 | 0.0451896 | Level: 01 eerste verdieping | 0
2250731 | 02 tweede verdieping | 2949437 | 0.0476855 | Level: 02 tweede verdieping | 0
2250733 | 02 tweede verdieping | 2880681 | 0.0465689 | Level: 02 tweede verdieping | 0
2250737 | 02 tweede verdieping | 2941348 | 0.0475542 | Level: 02 tweede verdieping | 0
2250743 | 02 tweede verdieping | 2941348 | 0.0475542 | Level: 02 tweede verdieping | 0
2250747 | 02 tweede verdieping | 2957526 | 0.0478169 | Level: 02 tweede verdieping
2250754 | 03 derde verdieping | 2698679 | 0.0436132 | Level: 03 derde verdieping | 0
2250756 | 03 derde verdieping | 2690590 | 0.0434819 | Level: 03 derde verdieping | 0
2250760 | 03 derde verdieping | 2690590 | 0.0434819 | Level: 03 derde verdieping | 0
2250766 | 03 derde verdieping | 2876636 | 0.0465033 | Level: 03 derde verdieping | 0
2250770 | 03 derde verdieping | 3596556 | 0.0581948 | Level: 03 derde verdieping
2252923 | 00 begane grond | 3786647 | 0.0612818 | Level: 00 begane grond
2252927 | 00 begane grond | 3772896 | 0.0610585 | Level: 00 begane grond | 0
2252929 | 00 begane grond | 3772896 | 0.0610585 | Level: 00 begane grond | 0
2252931 | 00 begane grond | 3760762 | 0.0608615 | Level: 00 begane grond | 0
2253829 | 01 eerste verdieping | 2771480 | 0.0447955 | Level: 01 eerste verdieping
2253833 | 01 eerste verdieping | 2777951 | 0.0449006 | Level: 01 eerste verdieping | 0
2253835 | 01 eerste verdieping | 2777951 | 0.0449006 | Level: 01 eerste verdieping | 0
2253837 | 01 eerste verdieping | 2777951 | 0.0449006 | Level: 01 eerste verdieping | 0
2253839 | 01 eerste verdieping | 2731035 | 0.0441387 | Level: 01 eerste verdieping
2254413 | 02 tweede verdieping | 2949437 | 0.0476855 | Level: 02 tweede verdieping | 0
2254415 | 02 tweede verdieping | 2949437 | 0.0476855 | Level: 02 tweede verdieping | 0
2254417 | 02 tweede verdieping | 2949437 | 0.0476855 | Level: 02 tweede verdieping | 0
2254419 | 02 tweede verdieping | 2937304 | 0.0474885 | Level: 02 tweede verdieping | 0
2254421 | 02 tweede verdieping | 2949437 | 0.0476855 | Level: 02 tweede verdieping
2254434 | 03 derde verdieping | 2694634 | 0.0435475 | Level: 03 derde verdieping | 0
2254436 | 03 derde verdieping | 2698679 | 0.0436132 | Level: 03 derde verdieping
2254438 | 03 derde verdieping | 2698679 | 0.0436132 | Level: 03 derde verdieping
2254440 | 03 derde verdieping | 2698679 | 0.0436132 | Level: 03 derde verdieping
2254442 | 03 derde verdieping | 2864503 | 0.0463062 | Level: 03 derde verdieping
2270698 | 01 eerste verdieping | 2880681 | 0.0465689 | Level: 01 eerste verdieping
2271825 | 01 eerste verdieping | 2880681 | 0.0465689 | Level: 01 eerste verdieping
2271830 | 01 eerste verdieping | 2880681 | 0.0465689 | Level: 01 eerste verdieping
2273013 | 01 eerste verdieping | 2880681 | 0.0465689 | Level: 01 eerste verdieping
2330386 | 00 begane grond | 3786647 | 0.0612818 | Level: 00 begane grond
2330390 | 01 eerste verdieping | 2771480 | 0.0447955 | Level: 01 eerste verdieping
2330816 | 00 begane grond | 3758336 | 0.0608221 | Level: 00 begane grond | 0
2330820 | 01 eerste verdieping | 2775524 | 0.0448612 | Level: 01 eerste verdieping | 0
2428312 | 02 tweede verdieping | 2561166 | 0.04138 | Level: 02 tweede verdieping | 0
2429258 | 02 tweede verdieping | 2472187 | 0.039935 | Level: 02 tweede verdieping
2429314 | 02 tweede verdieping | 2864503 | 0.0463062 | Level: 02 tweede verdieping | 0
2429329 | 02 tweede verdieping | 5853382 | 0.0948456 | Level: 02 tweede verdieping | 0
2440031 | 03 derde verdieping | 2500499 | 0.0403948 | Level: 03 derde verdieping | 0
2496788 | 02 tweede verdieping | 2601611 | 0.0420368 | Level: 02 tweede verdieping | 0
2524230 | 01 eerste verdieping | 8316477 | 0.134846 | Level: 01 eerste verdieping | 0
2524247 | 01 eerste verdieping | 8316477 | 0.134846 | Level: 01 eerste verdieping | 0
2524295 | 01 eerste verdieping | 6326587 | 0.10253 | Level: 01 eerste verdieping | 0
2524310 | 01 eerste verdieping | 6326587 | 0.10253 | Level: 01 eerste verdieping | 0
2589623 | 02 tweede verdieping | 5812937 | 0.0941888 | Level: 02 tweede verdieping | 0
2758811 | 02 tweede verdieping | 3167840 | 0.0512324 | Level: 02 tweede verdieping | 65.7
2802281 | 03 derde verdieping | 2981837 | 0.0482013 | Level: 03 derde verdieping | 65.7
2803526 | 02 tweede verdieping | 3238655 | 0.052372 | Level: 02 tweede verdieping | 65.7
2803528 | 03 derde verdieping | 2908665 | 0.0470032 | Level: 03 derde verdieping | 65.7
2809397 | 01 eerste verdieping | 2775524 | 0.0448612 | Level: 01 eerste verdieping | 0
2926853 | 04 vierde verdieping | 692611 | 0.0110347 | Level: 04 vierde verdieping
2926855 | 04 vierde verdieping | 692611 | 0.0110347 | Level: 04 vierde verdieping
3869787 | 03 derde verdieping | 2705150 | 0.0437183 | Level: 03 derde verdieping | 0
4259721 | 03 derde verdieping | 2985838 | 0.0482767 | Level: 03 derde verdieping
4339116 | 03 derde verdieping | 336696 | 0.00525461 | Level: 03 derde verdieping
5356305 | 00 begane grond | 3721935 | 0.0602309 | Level: 00 begane grond | 0

# IfcColumn: 28_PBT_SC_staal_H-profiel:S355_HE800B (4)
In: 05 vijfde verdieping
Type - PredefinedType: COLUMN; Classification: 28.11 hoofddraagconstructies - kolommen en liggers, kolom-/liggerconstructies (Uniformat); Material: 00_PBT_MAT_staal_S355
Type - Pset_ColumnCommon - IsExternal: no; LoadBearing: yes
Type - Pset_ProductRequirements - Category: Structural Columns
Type - Pset_ReinforcementBarPitchOfColumn - Description: HE800B
Type - Pset_Pieters - Breedte: 300 mm; Hoogte: 800 mm; Codering - NL-SfB: 28.11; Omschrijving NL-SfB: hoofddraagconstructies - kolommen en liggers, kolom-/liggerconstructies; Materiaal: 00_PBT_MAT_staal_S355; Materiaalkwaliteit: S355; Description: HE800B
BaseQuantities - CrossSectionArea: 7595453 mm2; NetVolume: 0.185674 m3
Pset_ColumnCommon - Reference: 28_PBT_SC_staal_H-profiel:S355_HE800B
Pset_QuantityTakeOff - Reference: 28_PBT_SC_staal_H-profiel:S355_HE800B
Pset_ReinforcementBarPitchOfColumn - Reference: 28_PBT_SC_staal_H-profiel:S355_HE800B
Pset_Pieters - Bouwlaag: Level: 05 vijfde verdieping; Naamgeving element: 28_PBT_SC_staal_H-profiel: S355_HE800B; Fase: Nieuw
Name (28_PBT_SC_staal_H-profiel:S355_HE800B:...)
2479958
2489985
2490076
2490167

# IfcColumn: 28_PBT_SC_staal_H-profiel_dak toneeltoren:S355_HE800B (4)
In: 05 vijfde verdieping
Type - PredefinedType: COLUMN; Material: 00_PBT_MAT_staal_S355
Type - Pset_ColumnCommon - IsExternal: no; LoadBearing: yes
Type - Pset_ProductRequirements - Category: Structural Columns
Type - Pset_ReinforcementBarPitchOfColumn - Description: stalen console HE800B
Type - Pset_Pieters - Breedte: 300 mm; Hoogte: 800 mm; Materiaal: 00_PBT_MAT_staal_S355; Materiaalkwaliteit: S355; Description: stalen console HE800B; Type Comments: oplegnok HEM400 in later aan te storten kas
BaseQuantities - CrossSectionArea: 7834666 mm2; NetVolume: 0.240709 m3
Pset_ColumnCommon - Reference: 28_PBT_SC_staal_H-profiel_dak toneeltoren:S355_HE800B
Pset_QuantityTakeOff - Reference: 28_PBT_SC_staal_H-profiel_dak toneeltoren:S355_HE800B
Pset_ReinforcementBarPitchOfColumn - Reference: 28_PBT_SC_staal_H-profiel_dak toneeltoren:S355_HE800B
Pset_Pieters - Naamgeving element: 28_PBT_SC_staal_H-profiel_dak toneeltoren: S355_HE800B; Fase: Nieuw
Name (28_PBT_SC_staal_H-profiel_dak toneeltoren:S355_HE800B:...)
2483945
2489987
2490078
2490169

# IfcColumn: 28_PBT_SC_staal_H-profiel_geknikt_dubbel:S355_HE180A (6)
In: 03 derde verdieping
Type - PredefinedType: COLUMN; Classification: 28.11 hoofddraagconstructies - kolommen en liggers, kolom-/liggerconstructies (Uniformat); Material: 00_PBT_MAT_staal_S355
Type - Pset_ColumnCommon - IsExternal: no; LoadBearing: yes
Type - Pset_ProductRequirements - Category: Structural Columns
Type - Pset_ReinforcementBarPitchOfColumn - Description: HE180A
Type - Pset_Pieters - Breedte: 180 mm; Hoogte: 171 mm; Codering - NL-SfB: 28.11; Omschrijving NL-SfB: hoofddraagconstructies - kolommen en liggers, kolom-/liggerconstructies; Materiaal: 00_PBT_MAT_staal_S355; Materiaalkwaliteit: S355; Description: HE180A
Pset_ColumnCommon - Reference: 28_PBT_SC_staal_H-profiel_geknikt_dubbel:S355_HE180A
Pset_QuantityTakeOff - Reference: 28_PBT_SC_staal_H-profiel_geknikt_dubbel:S355_HE180A
Pset_ReinforcementBarPitchOfColumn - Reference: 28_PBT_SC_staal_H-profiel_geknikt_dubbel:S355_HE180A
Pset_Pieters - Bouwlaag: Level: 03 derde verdieping; Naamgeving element: 28_PBT_SC_staal_H-profiel_geknikt_dubbel: S355_HE180A; Fase: Nieuw
Name (28_PBT_SC_staal_H-profiel_geknikt_dubbel:S355_HE180A:...) | CrossSectionArea (mm2) | NetVolume (m3)
2559423 | 1344763 | 0.0118417
2562157 | 1318254 | 0.0116075
2562178 | 1477311 | 0.0130129
2562932 | 1318254 | 0.0116075
2562934 | 1477311 | 0.0130129
2562936 | 1583349 | 0.0139499

# IfcColumn: 28_PBT_SC_staal_H-profiel_gekromd_dak paradezaal voorgevel:S355_HE200B_betondak voorgevel (5)
In: 03 derde verdieping
Type - PredefinedType: COLUMN; Material: 00_PBT_MAT_staal_S355
Type - Pset_ColumnCommon - IsExternal: no; LoadBearing: yes
Type - Pset_ProductRequirements - Category: Structural Columns
Type - Pset_ReinforcementBarPitchOfColumn - Description: HE200B + zijplaat
Type - Pset_Pieters - Breedte: 200 mm; Hoogte: 200 mm; Materiaal: 00_PBT_MAT_staal_S355; Materiaalkwaliteit: S355; Description: HE200B + zijplaat
BaseQuantities - CrossSectionArea: 3898097 mm2; NetVolume: 0.0506167 m3
Pset_ColumnCommon - Reference: 28_PBT_SC_staal_H-profiel_gekromd_dak paradezaal voorgevel:S355_HE200B_betondak voorgevel
Pset_QuantityTakeOff - Reference: 28_PBT_SC_staal_H-profiel_gekromd_dak paradezaal voorgevel:S355_HE200B_betondak voorgevel
Pset_ReinforcementBarPitchOfColumn - Reference: 28_PBT_SC_staal_H-profiel_gekromd_dak paradezaal voorgevel:S355_HE200B_betondak voorgevel
Pset_Pieters - Naamgeving element: 28_PBT_SC_staal_H-profiel_gekromd_dak paradezaal voorgevel: S355_HE200B_betondak voorgevel; Fase: Nieuw
Name (28_PBT_SC_staal_H-profiel_gekromd_dak paradezaal voorgevel:S355_HE200B_betondak voorgevel:...) | Group
2468604 | Model Group:Array Group 1:2468830
2468833 | Model Group:Array Group 1:2468835
2468917 | Model Group:Array Group 1:2468919
2468921 | Model Group:Array Group 1:2468923
2468925 | Model Group:Array Group 1:2468927

# IfcColumn: 28_PBT_SC_staal_H-profiel_gekromd_dak paradezaal zijgevel:S355_HE180M_betondak as B (7)
In: 03 derde verdieping
Type - PredefinedType: COLUMN; Material: 00_PBT_MAT_staal_S355
Type - Pset_ColumnCommon - IsExternal: no; LoadBearing: yes
Type - Pset_ProductRequirements - Category: Structural Columns
Type - Pset_ReinforcementBarPitchOfColumn - Description: HE180M + zijplaat
Type - Pset_Pieters - Breedte: 186 mm; Hoogte: 200 mm; Materiaal: 00_PBT_MAT_staal_S355; Materiaalkwaliteit: S355; Description: HE180M + zijplaat
BaseQuantities - CrossSectionArea: 3208443 mm2; NetVolume: 0.0529765 m3
Pset_ColumnCommon - Reference: 28_PBT_SC_staal_H-profiel_gekromd_dak paradezaal zijgevel:S355_HE180M_betondak as B
Pset_QuantityTakeOff - Reference: 28_PBT_SC_staal_H-profiel_gekromd_dak paradezaal zijgevel:S355_HE180M_betondak as B
Pset_ReinforcementBarPitchOfColumn - Reference: 28_PBT_SC_staal_H-profiel_gekromd_dak paradezaal zijgevel:S355_HE180M_betondak as B
Pset_Pieters - Naamgeving element: 28_PBT_SC_staal_H-profiel_gekromd_dak paradezaal zijgevel: S355_HE180M_betondak as B; Fase: Nieuw
Name (28_PBT_SC_staal_H-profiel_gekromd_dak paradezaal zijgevel:S355_HE180M_betondak as B:...) | Group
2458107 | Model Group:Array Group 21:3378563
3378566 | Model Group:Array Group 21:3378568
3378583 | Model Group:Array Group 21:3378585
3378587 | Model Group:Array Group 21:3378589
3378591 | Model Group:Array Group 21:3378593
3378595 | Model Group:Array Group 21:3378597
3378599 | Model Group:Array Group 21:3378601

# IfcColumn: 28_PBT_SC_staal_H-profiel_gekromd_dak paradezaal zijgevel:S355_HE180M_betondak as F (7)
In: 03 derde verdieping
Type - PredefinedType: COLUMN; Material: 00_PBT_MAT_staal_S355
Type - Pset_ColumnCommon - IsExternal: no; LoadBearing: yes
Type - Pset_ProductRequirements - Category: Structural Columns
Type - Pset_ReinforcementBarPitchOfColumn - Description: HE180M + zijplaat
Type - Pset_Pieters - Breedte: 186 mm; Hoogte: 200 mm; Materiaal: 00_PBT_MAT_staal_S355; Materiaalkwaliteit: S355; Description: HE180M + zijplaat
BaseQuantities - CrossSectionArea: 2946721 mm2; NetVolume: 0.0486279 m3
Pset_ColumnCommon - Reference: 28_PBT_SC_staal_H-profiel_gekromd_dak paradezaal zijgevel:S355_HE180M_betondak as F
Pset_QuantityTakeOff - Reference: 28_PBT_SC_staal_H-profiel_gekromd_dak paradezaal zijgevel:S355_HE180M_betondak as F
Pset_ReinforcementBarPitchOfColumn - Reference: 28_PBT_SC_staal_H-profiel_gekromd_dak paradezaal zijgevel:S355_HE180M_betondak as F
Pset_Pieters - Naamgeving element: 28_PBT_SC_staal_H-profiel_gekromd_dak paradezaal zijgevel: S355_HE180M_betondak as F; Fase: Nieuw
Name (28_PBT_SC_staal_H-profiel_gekromd_dak paradezaal zijgevel:S355_HE180M_betondak as F:...) | Group
2463025 | Model Group:Array Group 22:3381867
3381870 | Model Group:Array Group 22:3381872
3381890 | Model Group:Array Group 22:3381892
3381894 | Model Group:Array Group 22:3381896
3381898 | Model Group:Array Group 22:3381900 | Pset_ColumnCommon - Slope: 0 deg
3381902 | Model Group:Array Group 22:3381904
3381906 | Model Group:Array Group 22:3381908

# IfcColumn: 28_PBT_SC_staal_H-profiel_gekromd_dak paradezaal_hout_hoog:S355_HE200B_houten dak (9)
In: 03 derde verdieping
Type - PredefinedType: COLUMN; Material: 00_PBT_MAT_staal_S355
Type - Pset_ColumnCommon - IsExternal: no; LoadBearing: yes
Type - Pset_ProductRequirements - Category: Structural Columns
Type - Pset_ReinforcementBarPitchOfColumn - Description: HE200B
Type - Pset_Pieters - Breedte: 200 mm; Hoogte: 200 mm; Materiaal: 00_PBT_MAT_staal_S355; Materiaalkwaliteit: S355; Description: HE200B
BaseQuantities - CrossSectionArea: 2972132 mm2; NetVolume: 0.0399675 m3
Pset_ColumnCommon - Reference: 28_PBT_SC_staal_H-profiel_gekromd_dak paradezaal_hout_hoog:S355_HE200B_houten dak
Pset_QuantityTakeOff - Reference: 28_PBT_SC_staal_H-profiel_gekromd_dak paradezaal_hout_hoog:S355_HE200B_houten dak
Pset_ReinforcementBarPitchOfColumn - Reference: 28_PBT_SC_staal_H-profiel_gekromd_dak paradezaal_hout_hoog:S355_HE200B_houten dak
Pset_Pieters - Naamgeving element: 28_PBT_SC_staal_H-profiel_gekromd_dak paradezaal_hout_hoog: S355_HE200B_houten dak; Fase: Nieuw
Name (28_PBT_SC_staal_H-profiel_gekromd_dak paradezaal_hout_hoog:S355_HE200B_houten dak:...)
2469065
2478046
2478123
2478130
2478137
3392717
3394751
3841953
3889131

# IfcColumn: 28_PBT_SC_staal_H-profiel_gekromd_dak toneeltoren hoek:S355_HE200B_betondak_as 1 (2)
In: 05 vijfde verdieping
Type - PredefinedType: COLUMN; Material: 00_PBT_MAT_staal_S355
Type - Pset_ColumnCommon - IsExternal: no; LoadBearing: yes
Type - Pset_ProductRequirements - Category: Structural Columns
Type - Pset_ReinforcementBarPitchOfColumn - Description: HE200B
Type - Pset_Pieters - Breedte: 200 mm; Hoogte: 200 mm; Materiaal: 00_PBT_MAT_staal_S355; Materiaalkwaliteit: S355; Description: HE200B
BaseQuantities - CrossSectionArea: 4082367 mm2; NetVolume: 0.0552709 m3
Pset_ColumnCommon - Reference: 28_PBT_SC_staal_H-profiel_gekromd_dak toneeltoren hoek:S355_HE200B_betondak_as 1
Pset_QuantityTakeOff - Reference: 28_PBT_SC_staal_H-profiel_gekromd_dak toneeltoren hoek:S355_HE200B_betondak_as 1
Pset_ReinforcementBarPitchOfColumn - Reference: 28_PBT_SC_staal_H-profiel_gekromd_dak toneeltoren hoek:S355_HE200B_betondak_as 1
Pset_Pieters - Naamgeving element: 28_PBT_SC_staal_H-profiel_gekromd_dak toneeltoren hoek: S355_HE200B_betondak_as 1; Fase: Nieuw
Name (28_PBT_SC_staal_H-profiel_gekromd_dak toneeltoren hoek:S355_HE200B_betondak_as 1:...)
3620106
3625016

# IfcColumn: 28_PBT_SC_staal_H-profiel_gekromd_dak toneeltoren hoek:S355_HE200B_betondak_as 20, 28_PBT_SC_staal_H-profiel_gekromd_dak toneeltoren hoek:S355_HE200B_betondak_as 20:3625036
In: 05 vijfde verdieping
Type - PredefinedType: COLUMN; Material: 00_PBT_MAT_staal_S355
Type - Pset_ColumnCommon - IsExternal: no; LoadBearing: yes
Type - Pset_ProductRequirements - Category: Structural Columns
Type - Pset_ReinforcementBarPitchOfColumn - Description: HE200B
Type - Pset_Pieters - Breedte: 200 mm; Hoogte: 200 mm; Materiaal: 00_PBT_MAT_staal_S355; Materiaalkwaliteit: S355; Description: HE200B
BaseQuantities - CrossSectionArea: 4059344 mm2; NetVolume: 0.0549585 m3
Pset_ColumnCommon - Reference: 28_PBT_SC_staal_H-profiel_gekromd_dak toneeltoren hoek:S355_HE200B_betondak_as 20
Pset_QuantityTakeOff - Reference: 28_PBT_SC_staal_H-profiel_gekromd_dak toneeltoren hoek:S355_HE200B_betondak_as 20
Pset_ReinforcementBarPitchOfColumn - Reference: 28_PBT_SC_staal_H-profiel_gekromd_dak toneeltoren hoek:S355_HE200B_betondak_as 20
Pset_Pieters - Naamgeving element: 28_PBT_SC_staal_H-profiel_gekromd_dak toneeltoren hoek: S355_HE200B_betondak_as 20; Fase: Nieuw

# IfcColumn: 28_PBT_SC_staal_H-profiel_gekromd_dak toneeltoren hoek:S355_HE200B_betondak_as K, 28_PBT_SC_staal_H-profiel_gekromd_dak toneeltoren hoek:S355_HE200B_betondak_as K:3625055
In: 05 vijfde verdieping
Type - PredefinedType: COLUMN; Material: 00_PBT_MAT_staal_S355
Type - Pset_ColumnCommon - IsExternal: no; LoadBearing: yes
Type - Pset_ProductRequirements - Category: Structural Columns
Type - Pset_ReinforcementBarPitchOfColumn - Description: HE200B
Type - Pset_Pieters - Breedte: 200 mm; Hoogte: 200 mm; Materiaal: 00_PBT_MAT_staal_S355; Materiaalkwaliteit: S355; Description: HE200B
BaseQuantities - CrossSectionArea: 4065100 mm2; NetVolume: 0.0550366 m3
Pset_ColumnCommon - Reference: 28_PBT_SC_staal_H-profiel_gekromd_dak toneeltoren hoek:S355_HE200B_betondak_as K
Pset_QuantityTakeOff - Reference: 28_PBT_SC_staal_H-profiel_gekromd_dak toneeltoren hoek:S355_HE200B_betondak_as K
Pset_ReinforcementBarPitchOfColumn - Reference: 28_PBT_SC_staal_H-profiel_gekromd_dak toneeltoren hoek:S355_HE200B_betondak_as K
Pset_Pieters - Naamgeving element: 28_PBT_SC_staal_H-profiel_gekromd_dak toneeltoren hoek: S355_HE200B_betondak_as K; Fase: Nieuw

# IfcColumn: 28_PBT_SC_staal_H-profiel_gekromd_dak toneeltoren:S355_HE200B_betondak_as 1 (6)
In: 05 vijfde verdieping
Type - PredefinedType: COLUMN; Material: 00_PBT_MAT_staal_S355
Type - Pset_ColumnCommon - IsExternal: no; LoadBearing: yes
Type - Pset_ProductRequirements - Category: Structural Columns
Type - Pset_ReinforcementBarPitchOfColumn - Description: HE200B + zijplaat
Type - Pset_Pieters - Breedte: 200 mm; Hoogte: 200 mm; Materiaal: 00_PBT_MAT_staal_S355; Materiaalkwaliteit: S355; Description: HE200B + zijplaat
Pset_ColumnCommon - Reference: 28_PBT_SC_staal_H-profiel_gekromd_dak toneeltoren:S355_HE200B_betondak_as 1
Pset_QuantityTakeOff - Reference: 28_PBT_SC_staal_H-profiel_gekromd_dak toneeltoren:S355_HE200B_betondak_as 1
Pset_ReinforcementBarPitchOfColumn - Reference: 28_PBT_SC_staal_H-profiel_gekromd_dak toneeltoren:S355_HE200B_betondak_as 1
Pset_Pieters - Naamgeving element: 28_PBT_SC_staal_H-profiel_gekromd_dak toneeltoren: S355_HE200B_betondak_as 1; Fase: Nieuw
Name (28_PBT_SC_staal_H-profiel_gekromd_dak toneeltoren:S355_HE200B_betondak_as 1:...) | CrossSectionArea (mm2) | NetVolume (m3)
2664401 | 7026012 | 0.0893508
2666505 | 7026012 | 0.0893508
2666520 | 7026012 | 0.0893508
2666537 | 7026012 | 0.0893508
2666552 | 6985213 | 0.0888443
3532573 | 6985213 | 0.0888443

# IfcColumn: 28_PBT_SC_staal_H-profiel_gekromd_dak toneeltoren:S355_HE200B_betondak_as 20 (5)
In: 05 vijfde verdieping
Type - PredefinedType: COLUMN; Material: 00_PBT_MAT_staal_S355
Type - Pset_ColumnCommon - IsExternal: no; LoadBearing: yes
Type - Pset_ProductRequirements - Category: Structural Columns
Type - Pset_ReinforcementBarPitchOfColumn - Description: HE200B + zijplaat
Type - Pset_Pieters - Breedte: 200 mm; Hoogte: 200 mm; Materiaal: 00_PBT_MAT_staal_S355; Materiaalkwaliteit: S355; Description: HE200B + zijplaat
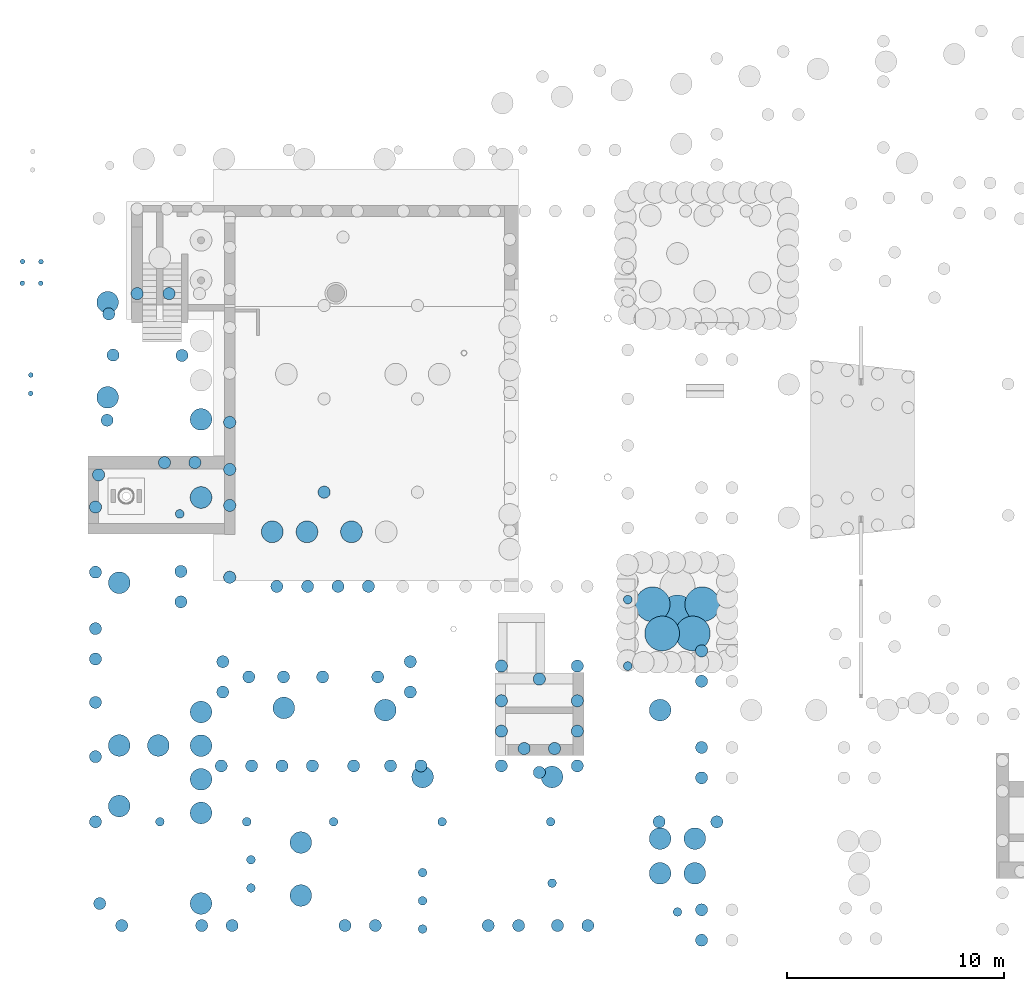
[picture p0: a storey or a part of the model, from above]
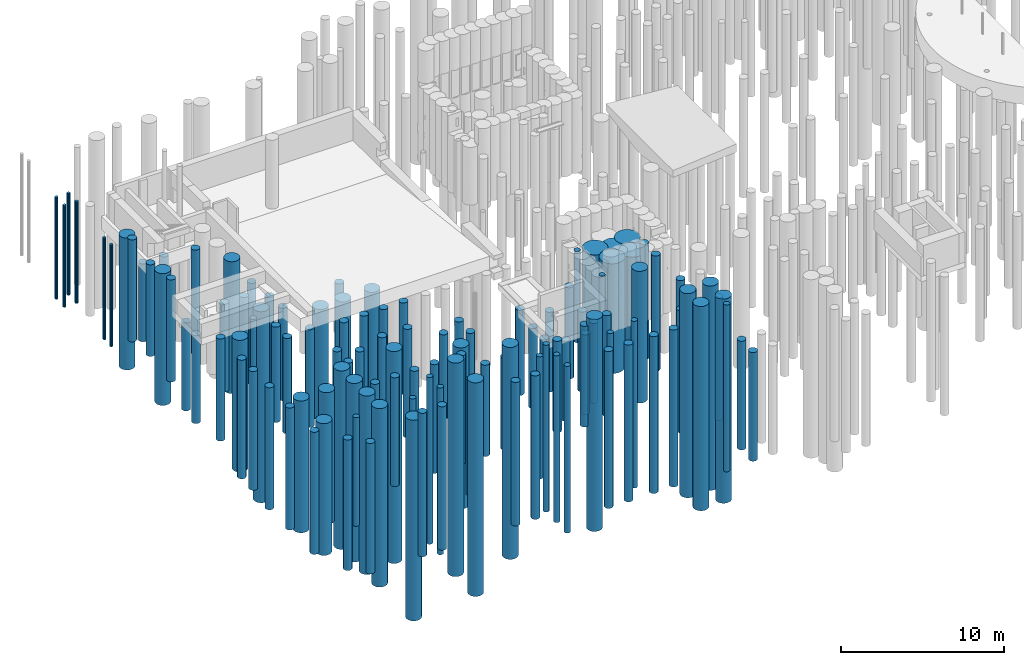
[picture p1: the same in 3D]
Properties of the parts of a building model (IFC2X3), part 10 of 18

# IfcColumn: 28_PBT_SC_staal_H-profiel_gekromd_dak toneeltoren:S355_HE200B_betondak_as 20 (5)
Pset_ColumnCommon - Reference: 28_PBT_SC_staal_H-profiel_gekromd_dak toneeltoren:S355_HE200B_betondak_as 20
Pset_QuantityTakeOff - Reference: 28_PBT_SC_staal_H-profiel_gekromd_dak toneeltoren:S355_HE200B_betondak_as 20
Pset_ReinforcementBarPitchOfColumn - Reference: 28_PBT_SC_staal_H-profiel_gekromd_dak toneeltoren:S355_HE200B_betondak_as 20
Pset_Pieters - Naamgeving element: 28_PBT_SC_staal_H-profiel_gekromd_dak toneeltoren: S355_HE200B_betondak_as 20; Fase: Nieuw
Name (28_PBT_SC_staal_H-profiel_gekromd_dak toneeltoren:S355_HE200B_betondak_as 20:...) | CrossSectionArea (mm2) | NetVolume (m3)
2666731 | 6963750 | 0.0885582
2666834 | 6963750 | 0.0885582
2667177 | 6963750 | 0.0885582
3526686 | 6922951 | 0.0880516
3531985 | 6922951 | 0.0880516

# IfcColumn: 28_PBT_SC_staal_H-profiel_gekromd_dak toneeltoren:S355_HE200B_betondak_as K (4)
In: 05 vijfde verdieping
Type - PredefinedType: COLUMN; Material: 00_PBT_MAT_staal_S355
Type - Pset_ColumnCommon - IsExternal: no; LoadBearing: yes
Type - Pset_ProductRequirements - Category: Structural Columns
Type - Pset_ReinforcementBarPitchOfColumn - Description: HE200B + zijplaat
Type - Pset_Pieters - Breedte: 200 mm; Hoogte: 200 mm; Materiaal: 00_PBT_MAT_staal_S355; Materiaalkwaliteit: S355; Description: HE200B + zijplaat
Pset_ColumnCommon - Reference: 28_PBT_SC_staal_H-profiel_gekromd_dak toneeltoren:S355_HE200B_betondak_as K
Pset_QuantityTakeOff - Reference: 28_PBT_SC_staal_H-profiel_gekromd_dak toneeltoren:S355_HE200B_betondak_as K
Pset_ReinforcementBarPitchOfColumn - Reference: 28_PBT_SC_staal_H-profiel_gekromd_dak toneeltoren:S355_HE200B_betondak_as K
Pset_Pieters - Naamgeving element: 28_PBT_SC_staal_H-profiel_gekromd_dak toneeltoren: S355_HE200B_betondak_as K; Fase: Nieuw
Name (28_PBT_SC_staal_H-profiel_gekromd_dak toneeltoren:S355_HE200B_betondak_as K:...) | CrossSectionArea (mm2) | NetVolume (m3)
2720317 | 6974127 | 0.0886903
2720327 | 6974127 | 0.0886903
3526668 | 6933328 | 0.0881837
3532413 | 6933328 | 0.0881837

# IfcColumn: 28_PBT_SC_staal_H-profiel_gekromd_dak toneeltoren:S355_HE200B_betondak_as R (8)
In: 05 vijfde verdieping
Type - PredefinedType: COLUMN; Material: 00_PBT_MAT_staal_S355
Type - Pset_ColumnCommon - IsExternal: no; LoadBearing: yes
Type - Pset_ProductRequirements - Category: Structural Columns
Type - Pset_ReinforcementBarPitchOfColumn - Description: HE200B + zijplaat
Type - Pset_Pieters - Breedte: 200 mm; Hoogte: 200 mm; Materiaal: 00_PBT_MAT_staal_S355; Materiaalkwaliteit: S355; Description: HE200B + zijplaat
Pset_ColumnCommon - Reference: 28_PBT_SC_staal_H-profiel_gekromd_dak toneeltoren:S355_HE200B_betondak_as R
Pset_QuantityTakeOff - Reference: 28_PBT_SC_staal_H-profiel_gekromd_dak toneeltoren:S355_HE200B_betondak_as R
Pset_ReinforcementBarPitchOfColumn - Reference: 28_PBT_SC_staal_H-profiel_gekromd_dak toneeltoren:S355_HE200B_betondak_as R
Pset_Pieters - Naamgeving element: 28_PBT_SC_staal_H-profiel_gekromd_dak toneeltoren: S355_HE200B_betondak_as R; Fase: Nieuw
Name (28_PBT_SC_staal_H-profiel_gekromd_dak toneeltoren:S355_HE200B_betondak_as R:...) | CrossSectionArea (mm2) | NetVolume (m3)
2714721 | 6963750 | 0.0885582
2714798 | 6963750 | 0.0885582
2720190 | 6963750 | 0.0885582
2720203 | 6963750 | 0.0885582
2720216 | 6963750 | 0.0885582
2720231 | 6963750 | 0.0885582
3531939 | 6922951 | 0.0880516
3532590 | 6922951 | 0.0880516

# IfcColumn: 28_PBT_SC_staal_H-profiel_gekromd_dak toneeltoren:S355_HE200B_houten_dak_as K (7)
In: 05 vijfde verdieping
Type - PredefinedType: COLUMN; Material: 00_PBT_MAT_staal_S355
Type - Pset_ColumnCommon - IsExternal: no; LoadBearing: yes
Type - Pset_ProductRequirements - Category: Structural Columns
Type - Pset_ReinforcementBarPitchOfColumn - Description: HE200B
Type - Pset_Pieters - Breedte: 200 mm; Hoogte: 200 mm; Materiaal: 00_PBT_MAT_staal_S355; Materiaalkwaliteit: S355; Description: HE200B
BaseQuantities - CrossSectionArea: 6403375 mm2; NetVolume: 0.048644 m3
Pset_ColumnCommon - Reference: 28_PBT_SC_staal_H-profiel_gekromd_dak toneeltoren:S355_HE200B_houten_dak_as K
Pset_QuantityTakeOff - Reference: 28_PBT_SC_staal_H-profiel_gekromd_dak toneeltoren:S355_HE200B_houten_dak_as K
Pset_ReinforcementBarPitchOfColumn - Reference: 28_PBT_SC_staal_H-profiel_gekromd_dak toneeltoren:S355_HE200B_houten_dak_as K
Pset_Pieters - Naamgeving element: 28_PBT_SC_staal_H-profiel_gekromd_dak toneeltoren: S355_HE200B_houten_dak_as K; Fase: Nieuw
Name (28_PBT_SC_staal_H-profiel_gekromd_dak toneeltoren:S355_HE200B_houten_dak_as K:...)
2720319
2720321
2720323
2720325
4324967
4325037
4325110

# IfcColumn: 28_PBT_SC_staal_H-profiel_met ingelaste strippen:S355_HE500B (2)
In: 00 begane grond
Type - PredefinedType: COLUMN; Classification: 28.11 hoofddraagconstructies - kolommen en liggers, kolom-/liggerconstructies (Uniformat); Material: 00_PBT_MAT_staal_S355
Type - Pset_ColumnCommon - IsExternal: no; LoadBearing: yes
Type - Pset_ProductRequirements - Category: Structural Columns
Type - Pset_ReinforcementBarPitchOfColumn - Description: HE500B + ingelaste strippen t=25
Type - Pset_Pieters - Breedte: 300 mm; Hoogte: 500 mm; Codering - NL-SfB: 28.11; Omschrijving NL-SfB: hoofddraagconstructies - kolommen en liggers, kolom-/liggerconstructies; Materiaal: 00_PBT_MAT_staal_S355; Materiaalkwaliteit: S355; Description: HE500B + ingelaste strippen t=25
Pset_ColumnCommon - Reference: 28_PBT_SC_staal_H-profiel_met ingelaste strippen:S355_HE500B
Pset_QuantityTakeOff - Reference: 28_PBT_SC_staal_H-profiel_met ingelaste strippen:S355_HE500B
Pset_ReinforcementBarPitchOfColumn - Reference: 28_PBT_SC_staal_H-profiel_met ingelaste strippen:S355_HE500B
Pset_Pieters - Bouwlaag: Level: 00 begane grond; Naamgeving element: 28_PBT_SC_staal_H-profiel_met ingelaste strippen: S355_HE500B; Fase: Nieuw
Name (28_PBT_SC_staal_H-profiel_met ingelaste strippen:S355_HE500B:...) | CrossSectionArea (mm2) | NetVolume (m3)
2256157 | 10217707 | 0.234235
2256864 | 18479041 | 0.424479

# IfcColumn: 28_PBT_SC_staal_IPE-profiel:S355_IPE330 (10)
In: 00 begane grond
Type - PredefinedType: COLUMN; Classification: 28.11 hoofddraagconstructies - kolommen en liggers, kolom-/liggerconstructies (Uniformat); Material: 00_PBT_MAT_staal_S355
Type - Pset_ColumnCommon - IsExternal: no; LoadBearing: yes
Type - Pset_ProductRequirements - Category: Structural Columns
Type - Pset_ReinforcementBarPitchOfColumn - Description: IPE330
Type - Pset_Pieters - Breedte: 160 mm; Hoogte: 330 mm; Codering - NL-SfB: 28.11; Omschrijving NL-SfB: hoofddraagconstructies - kolommen en liggers, kolom-/liggerconstructies; Materiaal: 00_PBT_MAT_staal_S355; Materiaalkwaliteit: S355; Description: IPE330
BaseQuantities - CrossSectionArea: 11870022 mm2; NetVolume: 0.118452 m3
Pset_ColumnCommon - Reference: 28_PBT_SC_staal_IPE-profiel:S355_IPE330
Pset_QuantityTakeOff - Reference: 28_PBT_SC_staal_IPE-profiel:S355_IPE330
Pset_ReinforcementBarPitchOfColumn - Reference: 28_PBT_SC_staal_IPE-profiel:S355_IPE330
Pset_Pieters - Bouwlaag: Level: 00 begane grond; Naamgeving element: 28_PBT_SC_staal_IPE-profiel: S355_IPE330; Fase: Nieuw
Name (28_PBT_SC_staal_IPE-profiel:S355_IPE330:...)
2417411
2417714
2417943
2417962
2418024
2418043
2762826
2762960
2762979
2762998

# IfcColumn: 28_PBT_SC_staal_L-profiel:L40x40x4_bestaand (49)
In: -1 kelder
Type - PredefinedType: COLUMN; Classification: 28.11 hoofddraagconstructies - kolommen en liggers, kolom-/liggerconstructies (Uniformat); Material: 00_PBT_MAT_staal
Type - Pset_ColumnCommon - IsExternal: no; LoadBearing: yes
Type - Pset_ProductRequirements - Category: Structural Columns
Type - Pset_ReinforcementBarPitchOfColumn - Description: L40x40x4
Type - Pset_Pieters - Breedte: 40 mm; Hoogte: 40 mm; Codering - NL-SfB: 28.11; Omschrijving NL-SfB: hoofddraagconstructies - kolommen en liggers, kolom-/liggerconstructies; Materiaal: 00_PBT_MAT_staal; Description: L40x40x4
BaseQuantities - CrossSectionArea: 116445 mm2; NetVolume: 0.000461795 m3
Pset_ColumnCommon - Reference: 28_PBT_SC_staal_L-profiel:L40x40x4_bestaand; LoadBearing: no
Pset_QuantityTakeOff - Reference: 28_PBT_SC_staal_L-profiel:L40x40x4_bestaand
Pset_ReinforcementBarPitchOfColumn - Reference: 28_PBT_SC_staal_L-profiel:L40x40x4_bestaand
Pset_Pieters - In/uitwendig: no; Bouwlaag: Level: -1 kelder_Offset1000; Naamgeving element: 28_PBT_SC_staal_L-profiel: L40x40x4_bestaand; Fase: Bestaand; Dragend/niet dragend: no
Name (28_PBT_SC_staal_L-profiel:L40x40x4_bestaand:...)
1300648
1301053
1301071
1301088
1301138
1301140
1301142
1301144
1301171
1301173
1301175
1301177
1301204
1301206
1301208
1301210
1301237
1301239
1301241
1301243
1301270
1301272
1301274
1301276
1301336
1301338
1301340
1301342
1301371
1301373
1301375
1301377
1301434
1301436
1301438
1301440
1301467
1301469
1301471
1301473
1301554
1301556
1301558
1301560
1344123
1344125
1344255
1344257
1627436

# IfcColumn: 28_PBT_SC_staal_buis:B250x dikte onbekend_bestaand (2)
In: -2 kelder
Type - PredefinedType: COLUMN; Classification: 28.11 hoofddraagconstructies - kolommen en liggers, kolom-/liggerconstructies (Uniformat); Material: 00_PBT_MAT_staal
Type - Pset_ColumnCommon - IsExternal: no; LoadBearing: yes
Type - Pset_ProductRequirements - Category: Structural Columns
Type - Pset_ReinforcementBarPitchOfColumn - Description: B250x (dikte onbekend)
Type - Pset_Pieters - Diameter: 250 mm; Codering - NL-SfB: 28.11; Omschrijving NL-SfB: hoofddraagconstructies - kolommen en liggers, kolom-/liggerconstructies; Materiaal: 00_PBT_MAT_staal; Description: B250x (dikte onbekend)
Pset_ColumnCommon - IsExternal: yes; Reference: 28_PBT_SC_staal_buis:B250x dikte onbekend_bestaand
Pset_QuantityTakeOff - Reference: 28_PBT_SC_staal_buis:B250x dikte onbekend_bestaand
Pset_ReinforcementBarPitchOfColumn - Reference: 28_PBT_SC_staal_buis:B250x dikte onbekend_bestaand
Pset_Pieters - Dragend/niet dragend: yes; In/uitwendig: yes; Bouwlaag: Level: -2 kelder_Offset1000; Naamgeving element: 28_PBT_SC_staal_buis: B250x dikte onbekend_bestaand; Fase: Bestaand
Name (28_PBT_SC_staal_buis:B250x dikte onbekend_bestaand:...) | CrossSectionArea (mm2) | NetVolume (m3)
1881813 | 5725153 | 0.0190489
1882749 | 4268868 | 0.0141616

# IfcColumn: 28_PBT_SC_staal_buis:B323.9x7.1_bestaand (8)
In: -2 kelder
Type - PredefinedType: COLUMN; Classification: 28.11 hoofddraagconstructies - kolommen en liggers, kolom-/liggerconstructies (Uniformat); Material: 00_PBT_MAT_staal
Type - Pset_ColumnCommon - IsExternal: no; LoadBearing: yes
Type - Pset_ProductRequirements - Category: Structural Columns
Type - Pset_ReinforcementBarPitchOfColumn - Description: B323.9x7.1
Type - Pset_Pieters - Diameter: 323.9 mm; Codering - NL-SfB: 28.11; Omschrijving NL-SfB: hoofddraagconstructies - kolommen en liggers, kolom-/liggerconstructies; Materiaal: 00_PBT_MAT_staal; Description: B323.9x7.1
Pset_ColumnCommon - IsExternal: yes; Reference: 28_PBT_SC_staal_buis:B323.9x7.1_bestaand
Pset_QuantityTakeOff - Reference: 28_PBT_SC_staal_buis:B323.9x7.1_bestaand
Pset_ReinforcementBarPitchOfColumn - Reference: 28_PBT_SC_staal_buis:B323.9x7.1_bestaand
Pset_Pieters - Dragend/niet dragend: yes; In/uitwendig: yes; Bouwlaag: Level: -2 kelder_Offset1000; Naamgeving element: 28_PBT_SC_staal_buis: B323.9x7.1_bestaand; Fase: Bestaand
Name (28_PBT_SC_staal_buis:B323.9x7.1_bestaand:...) | CrossSectionArea (mm2) | NetVolume (m3)
1352439 | 9343212 | 0.0441624
1353170 | 9343212 | 0.0441624
1353187 | 9343212 | 0.0441624
1353204 | 9343212 | 0.0441624
1392545 | 7861480 | 0.0370964
1392606 | 7861480 | 0.0370964
1392621 | 7861480 | 0.0370964
1392636 | 7861480 | 0.0370964

# IfcColumn: 28_PBT_SC_staal_buis:B700.0x0.4_bestaand, 28_PBT_SC_staal_buis:B700.0x0.4_bestaand:1403052
In: -2 kelder
Type - PredefinedType: COLUMN; Classification: 28.11 hoofddraagconstructies - kolommen en liggers, kolom-/liggerconstructies (Uniformat); Material: 00_PBT_MAT_staal
Type - Pset_ColumnCommon - IsExternal: no; LoadBearing: yes
Type - Pset_ProductRequirements - Category: Structural Columns
Type - Pset_ReinforcementBarPitchOfColumn - Description: B323.9x7.1
Type - Pset_Pieters - Diameter: 700 mm; Codering - NL-SfB: 28.11; Omschrijving NL-SfB: hoofddraagconstructies - kolommen en liggers, kolom-/liggerconstructies; Materiaal: 00_PBT_MAT_staal; Description: B323.9x7.1
BaseQuantities - CrossSectionArea: 13151633 mm2; NetVolume: 0.0341097 m3
Pset_ColumnCommon - IsExternal: yes; Reference: 28_PBT_SC_staal_buis:B700.0x0.4_bestaand
Pset_QuantityTakeOff - Reference: 28_PBT_SC_staal_buis:B700.0x0.4_bestaand
Pset_ReinforcementBarPitchOfColumn - Reference: 28_PBT_SC_staal_buis:B700.0x0.4_bestaand
Pset_Pieters - Dragend/niet dragend: yes; In/uitwendig: yes; Bouwlaag: Level: -2 kelder_Offset1000; Naamgeving element: 28_PBT_SC_staal_buis: B700.0x0.4_bestaand; Fase: Bestaand

# IfcColumn: 28_PBT_SC_staal_buis:S355_B152.4x10, 28_PBT_SC_staal_buis:S355_B152.4x10:3738293
In: 01 eerste verdieping
Type - PredefinedType: COLUMN; Classification: 28.11 hoofddraagconstructies - kolommen en liggers, kolom-/liggerconstructies (Uniformat); Material: 00_PBT_MAT_staal_S355
Type - Pset_ColumnCommon - IsExternal: no; LoadBearing: yes
Type - Pset_ProductRequirements - Category: Structural Columns
Type - Pset_ReinforcementBarPitchOfColumn - Description: B152.4x10
Type - Pset_Pieters - Diameter: 152.4 mm; Codering - NL-SfB: 28.11; Omschrijving NL-SfB: hoofddraagconstructies - kolommen en liggers, kolom-/liggerconstructies; Materiaal: 00_PBT_MAT_staal_S355; Materiaalkwaliteit: S355; Description: B152.4x10
BaseQuantities - CrossSectionArea: 1478533 mm2; NetVolume: 0.0147399 m3
Pset_ColumnCommon - Reference: 28_PBT_SC_staal_buis:S355_B152.4x10
Pset_QuantityTakeOff - Reference: 28_PBT_SC_staal_buis:S355_B152.4x10
Pset_ReinforcementBarPitchOfColumn - Reference: 28_PBT_SC_staal_buis:S355_B152.4x10
Pset_Pieters - Bouwlaag: Level: 01 eerste verdieping; Naamgeving element: 28_PBT_SC_staal_buis: S355_B152.4x10; Fase: Nieuw; Comments: wanddikte ter indicatie

# IfcColumn: 28_PBT_SC_staal_buis:S355_B323.9x10_GB_C40/50 (4)
Type - PredefinedType: COLUMN; Classification: 28.11 hoofddraagconstructies - kolommen en liggers, kolom-/liggerconstructies (Uniformat); Material: 00_PBT_MAT_beton t.p.g._C40/50, 00_PBT_MAT_staal_S355
Type - Pset_ColumnCommon - IsExternal: no; LoadBearing: yes
Type - Pset_ProductRequirements - Category: Structural Columns
Type - Pset_ReinforcementBarPitchOfColumn - Description: B323.9x10 (GB)
Type - Pset_Pieters - Diameter: 323.9 mm; Codering - NL-SfB: 28.11; Omschrijving NL-SfB: hoofddraagconstructies - kolommen en liggers, kolom-/liggerconstructies; Materiaal: 00_PBT_MAT_staal_S355; Materiaalkwaliteit: S355; Description: B323.9x10 (GB)
Pset_ColumnCommon - Reference: 28_PBT_SC_staal_buis:S355_B323.9x10_GB_C40/50
Pset_QuantityTakeOff - Reference: 28_PBT_SC_staal_buis:S355_B323.9x10_GB_C40/50
Pset_ReinforcementBarPitchOfColumn - Reference: 28_PBT_SC_staal_buis:S355_B323.9x10_GB_C40/50
Pset_Pieters - Dragend/niet dragend: yes; Naamgeving element: 28_PBT_SC_staal_buis: S355_B323.9x10_GB_C40/50; Fase: Nieuw
Name (28_PBT_SC_staal_buis:S355_B323.9x10_GB_C40/50:...) | In | CrossSectionArea (mm2) | NetVolume (m3) | Bouwlaag
4230682 | -1 kelder | 4370473 | 0.241412 | Level: -1 kelder
4230970 | -1 kelder | 4370473 | 0.241412 | Level: -1 kelder
4291912 | 00 begane grond | 4560730 | 0.252123 | Level: 00 begane grond
4292006 | 00 begane grond | 4560730 | 0.252123 | Level: 00 begane grond

# IfcColumn: 28_PBT_SC_staal_buis:S355_B323.9x10_GB_C40/50 (20)
Type - PredefinedType: COLUMN; Classification: 28.11 hoofddraagconstructies - kolommen en liggers, kolom-/liggerconstructies (Uniformat); Material: 00_PBT_MAT_staal_S355, 00_PBT_MAT_beton t.p.g._C40/50
Type - Pset_ColumnCommon - IsExternal: no; LoadBearing: yes
Type - Pset_ProductRequirements - Category: Structural Columns
Type - Pset_ReinforcementBarPitchOfColumn - Description: B323.9x10 (GB)
Type - Pset_Pieters - Diameter: 323.9 mm; Codering - NL-SfB: 28.11; Omschrijving NL-SfB: hoofddraagconstructies - kolommen en liggers, kolom-/liggerconstructies; Materiaal: 00_PBT_MAT_staal_S355; Materiaalkwaliteit: S355; Description: B323.9x10 (GB)
Pset_ColumnCommon - Reference: 28_PBT_SC_staal_buis:S355_B323.9x10_GB_C40/50
Pset_QuantityTakeOff - Reference: 28_PBT_SC_staal_buis:S355_B323.9x10_GB_C40/50
Pset_ReinforcementBarPitchOfColumn - Reference: 28_PBT_SC_staal_buis:S355_B323.9x10_GB_C40/50
Pset_Pieters - Dragend/niet dragend: yes; Naamgeving element: 28_PBT_SC_staal_buis: S355_B323.9x10_GB_C40/50; Fase: Nieuw
Name (28_PBT_SC_staal_buis:S355_B323.9x10_GB_C40/50:...) | In | CrossSectionArea (mm2) | NetVolume (m3) | Bouwlaag
1972797 | -2 kelder | 6975523 | 0.388072 | Level: -2 kelder
1972838 | -2 kelder | 6975523 | 0.388072 | Level: -2 kelder
1972897 | -1 kelder | 3726528 | 0.205159 | Level: -1 kelder
1972916 | -1 kelder | 3924102 | 0.216282 | Level: -1 kelder
2097981 | -1 kelder | 2863057 | 0.156547 | Level: -1 kelder
2097998 | -1 kelder | 2863057 | 0.156547 | Level: -1 kelder
2098028 | -1 kelder | 2863057 | 0.156547 | Level: -1 kelder
2098043 | -1 kelder | 2863057 | 0.156547 | Level: -1 kelder
2098058 | -1 kelder | 2863057 | 0.156547 | Level: -1 kelder
2098073 | -1 kelder | 2863057 | 0.156547 | Level: -1 kelder
2098306 | -1 kelder | 2826469 | 0.154487 | Level: -1 kelder
2098323 | -1 kelder | 2826469 | 0.154487 | Level: -1 kelder
2098353 | -1 kelder | 2863057 | 0.156547 | Level: -1 kelder
2098370 | -1 kelder | 2863057 | 0.156547 | Level: -1 kelder
2098464 | -1 kelder | 2716706 | 0.148308 | Level: -1 kelder
2098511 | -1 kelder | 2716706 | 0.148308 | Level: -1 kelder
2098526 | -1 kelder | 2716706 | 0.148308 | Level: -1 kelder
4450861 | -1 kelder | 2716706 | 0.148308 | Level: -1 kelder
4450878 | -1 kelder | 2716706 | 0.148308 | Level: -1 kelder
4450894 | -1 kelder | 2716706 | 0.148308 | Level: -1 kelder

# IfcColumn: 28_PBT_SC_staal_buis:S355_B323.9x16_GB_C40/50 (5)
In: 00 begane grond
Type - PredefinedType: COLUMN; Classification: 28.11 hoofddraagconstructies - kolommen en liggers, kolom-/liggerconstructies (Uniformat); Material: 00_PBT_MAT_beton t.p.g._C40/50, 00_PBT_MAT_staal_S355
Type - Pset_ColumnCommon - IsExternal: no; LoadBearing: yes
Type - Pset_ProductRequirements - Category: Structural Columns
Type - Pset_ReinforcementBarPitchOfColumn - Description: B323.9x16 (GB)
Type - Pset_Pieters - Diameter: 323.9 mm; Codering - NL-SfB: 28.11; Omschrijving NL-SfB: hoofddraagconstructies - kolommen en liggers, kolom-/liggerconstructies; Materiaal: 00_PBT_MAT_staal_S355; Materiaalkwaliteit: S355; Description: B323.9x16 (GB)
Pset_ColumnCommon - Reference: 28_PBT_SC_staal_buis:S355_B323.9x16_GB_C40/50
Pset_QuantityTakeOff - Reference: 28_PBT_SC_staal_buis:S355_B323.9x16_GB_C40/50
Pset_ReinforcementBarPitchOfColumn - Reference: 28_PBT_SC_staal_buis:S355_B323.9x16_GB_C40/50
Pset_Pieters - Dragend/niet dragend: yes; Bouwlaag: Level: 00 begane grond; Naamgeving element: 28_PBT_SC_staal_buis: S355_B323.9x16_GB_C40/50; Fase: Nieuw
Name (28_PBT_SC_staal_buis:S355_B323.9x16_GB_C40/50:...) | CrossSectionArea (mm2) | NetVolume (m3)
2005480 | 5970989 | 0.340284
2005482 | 5970989 | 0.340284
2005531 | 7083122 | 0.40455
2005533 | 7083122 | 0.40455
2812991 | 7026090 | 0.401255

# IfcColumn: 28_PBT_SC_staal_buis:S355_B323.9x16_GB_C40/50 (3)
In: -1 kelder
Type - PredefinedType: COLUMN; Classification: 28.11 hoofddraagconstructies - kolommen en liggers, kolom-/liggerconstructies (Uniformat); Material: 00_PBT_MAT_staal_S355, 00_PBT_MAT_beton t.p.g._C40/50
Type - Pset_ColumnCommon - IsExternal: no; LoadBearing: yes
Type - Pset_ProductRequirements - Category: Structural Columns
Type - Pset_ReinforcementBarPitchOfColumn - Description: B323.9x16 (GB)
Type - Pset_Pieters - Diameter: 323.9 mm; Codering - NL-SfB: 28.11; Omschrijving NL-SfB: hoofddraagconstructies - kolommen en liggers, kolom-/liggerconstructies; Materiaal: 00_PBT_MAT_staal_S355; Materiaalkwaliteit: S355; Description: B323.9x16 (GB)
Pset_ColumnCommon - Reference: 28_PBT_SC_staal_buis:S355_B323.9x16_GB_C40/50
Pset_QuantityTakeOff - Reference: 28_PBT_SC_staal_buis:S355_B323.9x16_GB_C40/50
Pset_ReinforcementBarPitchOfColumn - Reference: 28_PBT_SC_staal_buis:S355_B323.9x16_GB_C40/50
Pset_Pieters - Dragend/niet dragend: yes; Bouwlaag: Level: -1 kelder; Naamgeving element: 28_PBT_SC_staal_buis: S355_B323.9x16_GB_C40/50; Fase: Nieuw
Name (28_PBT_SC_staal_buis:S355_B323.9x16_GB_C40/50:...) | CrossSectionArea (mm2) | NetVolume (m3)
1972935 | 3825142 | 0.216282
1976854 | 4031885 | 0.228229
1977092 | 4031885 | 0.228229

# IfcColumn: 28_PBT_SC_staal_buis:S355_B355.6x10_GB_C40/50 (5)
In: -1 kelder
Type - PredefinedType: COLUMN; Classification: 28.11 hoofddraagconstructies - kolommen en liggers, kolom-/liggerconstructies (Uniformat); Material: 00_PBT_MAT_staal_S355, 00_PBT_MAT_beton t.p.g._C40/50
Type - Pset_ColumnCommon - IsExternal: no; LoadBearing: yes
Type - Pset_ProductRequirements - Category: Structural Columns
Type - Pset_ReinforcementBarPitchOfColumn - Description: B355.6x10 (GB)
Type - Pset_Pieters - Diameter: 355.6 mm; Codering - NL-SfB: 28.11; Omschrijving NL-SfB: hoofddraagconstructies - kolommen en liggers, kolom-/liggerconstructies; Materiaal: 00_PBT_MAT_staal_S355; Materiaalkwaliteit: S355; Description: B355.6x10 (GB)
BaseQuantities - CrossSectionArea: 3163799 mm2; NetVolume: 0.188689 m3
Pset_ColumnCommon - Reference: 28_PBT_SC_staal_buis:S355_B355.6x10_GB_C40/50
Pset_QuantityTakeOff - Reference: 28_PBT_SC_staal_buis:S355_B355.6x10_GB_C40/50
Pset_ReinforcementBarPitchOfColumn - Reference: 28_PBT_SC_staal_buis:S355_B355.6x10_GB_C40/50
Pset_Pieters - Dragend/niet dragend: yes; Bouwlaag: Level: -1 kelder; Naamgeving element: 28_PBT_SC_staal_buis: S355_B355.6x10_GB_C40/50; Fase: Nieuw
Name (28_PBT_SC_staal_buis:S355_B355.6x10_GB_C40/50:...)
2097712
2098013
2098338
2098387
2996340

# IfcColumn: 28_PBT_SC_staal_buis:S355_B406.4x20_GB_C40/50, 28_PBT_SC_staal_buis:S355_B406.4x20_GB_C40/50:2164801
In: 01 eerste verdieping
Type - PredefinedType: COLUMN; Classification: 28.11 hoofddraagconstructies - kolommen en liggers, kolom-/liggerconstructies (Uniformat); Material: 00_PBT_MAT_staal_S355, 00_PBT_MAT_beton t.p.g._C40/50
Type - Pset_ColumnCommon - IsExternal: no; LoadBearing: yes
Type - Pset_ProductRequirements - Category: Structural Columns
Type - Pset_ReinforcementBarPitchOfColumn - Description: B406.4x20 (GB)
Type - Pset_Pieters - Diameter: 406.4 mm; Codering - NL-SfB: 28.11; Omschrijving NL-SfB: hoofddraagconstructies - kolommen en liggers, kolom-/liggerconstructies; Materiaal: 00_PBT_MAT_staal_S355; Materiaalkwaliteit: S355; Description: B406.4x20 (GB)
BaseQuantities - CrossSectionArea: 6151216 mm2; NetVolume: 0.436483 m3
Pset_ColumnCommon - Reference: 28_PBT_SC_staal_buis:S355_B406.4x20_GB_C40/50
Pset_QuantityTakeOff - Reference: 28_PBT_SC_staal_buis:S355_B406.4x20_GB_C40/50
Pset_ReinforcementBarPitchOfColumn - Reference: 28_PBT_SC_staal_buis:S355_B406.4x20_GB_C40/50
Pset_Pieters - Dragend/niet dragend: yes; Bouwlaag: Level: 01 eerste verdieping; Naamgeving element: 28_PBT_SC_staal_buis: S355_B406.4x20_GB_C40/50; Fase: Nieuw

# IfcColumn: 28_PBT_SC_staal_buis:S355_B406.4x6.3_GB_C40/50 (2)
In: -1 kelder
Type - PredefinedType: COLUMN; Classification: 28.11 hoofddraagconstructies - kolommen en liggers, kolom-/liggerconstructies (Uniformat); Material: 00_PBT_MAT_beton t.p.g._C40/50, 00_PBT_MAT_staal_S355
Type - Pset_ColumnCommon - IsExternal: no; LoadBearing: yes
Type - Pset_ProductRequirements - Category: Structural Columns
Type - Pset_ReinforcementBarPitchOfColumn - Description: B406.4x6.3 (GB)
Type - Pset_Pieters - Diameter: 406.4 mm; Codering - NL-SfB: 28.11; Omschrijving NL-SfB: hoofddraagconstructies - kolommen en liggers, kolom-/liggerconstructies; Materiaal: 00_PBT_MAT_staal_S355; Materiaalkwaliteit: S355; Description: B406.4x6.3 (GB)
BaseQuantities - CrossSectionArea: 4940449 mm2; NetVolume: 0.332713 m3
Pset_ColumnCommon - Reference: 28_PBT_SC_staal_buis:S355_B406.4x6.3_GB_C40/50
Pset_QuantityTakeOff - Reference: 28_PBT_SC_staal_buis:S355_B406.4x6.3_GB_C40/50
Pset_ReinforcementBarPitchOfColumn - Reference: 28_PBT_SC_staal_buis:S355_B406.4x6.3_GB_C40/50
Pset_Pieters - Dragend/niet dragend: yes; Bouwlaag: Level: -1 kelder; Naamgeving element: 28_PBT_SC_staal_buis: S355_B406.4x6.3_GB_C40/50; Fase: Nieuw
Name (28_PBT_SC_staal_buis:S355_B406.4x6.3_GB_C40/50:...)
1997388
1997571

# IfcColumn: 28_PBT_SC_staal_koker:S355_K100x100x5 (27)
In: 02 tweede verdieping
Type - PredefinedType: COLUMN; Classification: 28.11 hoofddraagconstructies - kolommen en liggers, kolom-/liggerconstructies (Uniformat); Material: 00_PBT_MAT_staal_S355
Type - Pset_ColumnCommon - IsExternal: no; LoadBearing: yes
Type - Pset_ProductRequirements - Category: Structural Columns
Type - Pset_ReinforcementBarPitchOfColumn - Description: #100x100x5
Type - Pset_Pieters - Breedte: 100 mm; Hoogte: 100 mm; Codering - NL-SfB: 28.11; Omschrijving NL-SfB: hoofddraagconstructies - kolommen en liggers, kolom-/liggerconstructies; Materiaal: 00_PBT_MAT_staal_S355; Materiaalkwaliteit: S355; Description: #100x100x5
Pset_ColumnCommon - Reference: 28_PBT_SC_staal_koker:S355_K100x100x5
Pset_QuantityTakeOff - Reference: 28_PBT_SC_staal_koker:S355_K100x100x5
Pset_ReinforcementBarPitchOfColumn - Reference: 28_PBT_SC_staal_koker:S355_K100x100x5
Pset_Pieters - Dragend/niet dragend: yes; In/uitwendig: no; Bouwlaag: Level: 02 tweede verdieping; Naamgeving element: 28_PBT_SC_staal_koker: S355_K100x100x5; Fase: Nieuw; Comments: hoh. max. 1500mm
Name (28_PBT_SC_staal_koker:S355_K100x100x5:...) | CrossSectionArea (mm2) | NetVolume (m3)
6361944 | 263316 | 0.0013262
6363222 | 263316 | 0.0013262
6363261 | 254084 | 0.00127937
6363313 | 254084 | 0.00127937
6363355 | 254084 | 0.00127937
6376157 | 254084 | 0.00127937
6376261 | 263316 | 0.0013262
6376417 | 263316 | 0.0013262
6376466 | 254084 | 0.00127937
6376483 | 254084 | 0.00127937
6376589 | 254084 | 0.00127937
6376626 | 254084 | 0.00127937
6377582 | 263316 | 0.0013262
6377584 | 263316 | 0.0013262
6377586 | 254084 | 0.00127937
6377588 | 254084 | 0.00127937
6377590 | 254084 | 0.00127937
6377592 | 254084 | 0.00127937
6377594 | 254084 | 0.00127937
6377596 | 263316 | 0.0013262
6377598 | 254084 | 0.00127937
6377600 | 254084 | 0.00127937
6377602 | 254084 | 0.00127937
6377604 | 254084 | 0.00127937
6378307 | 263316 | 0.0013262
6378378 | 254084 | 0.00127937
6378413 | 254084 | 0.00127937

# IfcColumn: 28_PBT_SC_staal_koker:S355_K100x100x6.3 (9)
Type - PredefinedType: COLUMN; Classification: 28.11 hoofddraagconstructies - kolommen en liggers, kolom-/liggerconstructies (Uniformat); Material: 00_PBT_MAT_staal_S355
Type - Pset_ColumnCommon - IsExternal: no; LoadBearing: yes
Type - Pset_ProductRequirements - Category: Structural Columns
Type - Pset_ReinforcementBarPitchOfColumn - Description: #100x100x6.3
Type - Pset_Pieters - Breedte: 100 mm; Hoogte: 100 mm; Codering - NL-SfB: 28.11; Omschrijving NL-SfB: hoofddraagconstructies - kolommen en liggers, kolom-/liggerconstructies; Materiaal: 00_PBT_MAT_staal_S355; Materiaalkwaliteit: S355; Description: #100x100x6.3
Pset_ColumnCommon - Reference: 28_PBT_SC_staal_koker:S355_K100x100x6.3
Pset_QuantityTakeOff - Reference: 28_PBT_SC_staal_koker:S355_K100x100x6.3
Pset_ReinforcementBarPitchOfColumn - Reference: 28_PBT_SC_staal_koker:S355_K100x100x6.3
Pset_Pieters - Naamgeving element: 28_PBT_SC_staal_koker: S355_K100x100x6.3; Fase: Nieuw
Name (28_PBT_SC_staal_koker:S355_K100x100x6.3:...) | In | CrossSectionArea (mm2) | NetVolume (m3) | Bouwlaag
2422011 | 01 eerste verdieping | 1274025 | 0.00816161 | Level: 01 eerste verdieping
2422523 | 01 eerste verdieping | 1324604 | 0.00848622 | Level: 01 eerste verdieping
2422542 | 01 eerste verdieping | 1320991 | 0.00846304 | Level: 01 eerste verdieping
2422559 | 01 eerste verdieping | 1277637 | 0.0081848 | Level: 01 eerste verdieping
3425788 | -2 kelder | 579283 | 0.00370287 | Level: -2 kelder | Pset_Pieters - Dragend/niet dragend: yes; In/uitwendig: no
3425924 | -2 kelder | 579283 | 0.00370287 | Level: -2 kelder | Pset_Pieters - Dragend/niet dragend: yes; In/uitwendig: no
3425948 | -2 kelder | 579283 | 0.00370287 | Level: -2 kelder | Pset_Pieters - Dragend/niet dragend: yes; In/uitwendig: no
5916394 | 03 derde verdieping | 1259573 | 0.00806887 | Level: 03 derde verdieping
5916577 | 03 derde verdieping | 1259573 | 0.00806887 | Level: 03 derde verdieping

# IfcColumn: 28_PBT_SC_staal_koker:S355_K100x100x8 (8)
In: 04 vierde verdieping
Type - PredefinedType: COLUMN; Classification: 28.11 hoofddraagconstructies - kolommen en liggers, kolom-/liggerconstructies (Uniformat); Material: 00_PBT_MAT_staal_S355
Type - Pset_ColumnCommon - IsExternal: no; LoadBearing: yes
Type - Pset_ProductRequirements - Category: Structural Columns
Type - Pset_ReinforcementBarPitchOfColumn - Description: #100x100x8
Type - Pset_Pieters - Breedte: 100 mm; Hoogte: 100 mm; Codering - NL-SfB: 28.11; Omschrijving NL-SfB: hoofddraagconstructies - kolommen en liggers, kolom-/liggerconstructies; Materiaal: 00_PBT_MAT_staal_S355; Materiaalkwaliteit: S355; Description: #100x100x8
BaseQuantities - CrossSectionArea: 528923 mm2; NetVolume: 0.00435419 m3
Pset_ColumnCommon - Reference: 28_PBT_SC_staal_koker:S355_K100x100x8
Pset_QuantityTakeOff - Reference: 28_PBT_SC_staal_koker:S355_K100x100x8
Pset_ReinforcementBarPitchOfColumn - Reference: 28_PBT_SC_staal_koker:S355_K100x100x8
Pset_Pieters - Bouwlaag: Level: 04 vierde verdieping; Naamgeving element: 28_PBT_SC_staal_koker: S355_K100x100x8; Fase: Nieuw
Name (28_PBT_SC_staal_koker:S355_K100x100x8:...)
3818472
3818814
3818870
3818872
3818896
3818898
3818921
3818923

# IfcColumn: 28_PBT_SC_staal_koker:S355_K180x180x12.5, 28_PBT_SC_staal_koker:S355_K180x180x12.5:4485920
In: 02 tweede verdieping
Type - PredefinedType: COLUMN; Classification: 28.11 hoofddraagconstructies - kolommen en liggers, kolom-/liggerconstructies (Uniformat); Material: 00_PBT_MAT_staal_S355
Type - Pset_ColumnCommon - IsExternal: no; LoadBearing: yes
Type - Pset_ProductRequirements - Category: Structural Columns
Type - Pset_ReinforcementBarPitchOfColumn - Description: K180x180x12.5
Type - Pset_Pieters - Breedte: 180 mm; Hoogte: 180 mm; Codering - NL-SfB: 28.11; Omschrijving NL-SfB: hoofddraagconstructies - kolommen en liggers, kolom-/liggerconstructies; Materiaal: 00_PBT_MAT_staal_S355; Materiaalkwaliteit: S355; Description: K180x180x12.5
BaseQuantities - CrossSectionArea: 2149979 mm2; NetVolume: 0.0273303 m3
Pset_ColumnCommon - Reference: 28_PBT_SC_staal_koker:S355_K180x180x12.5
Pset_QuantityTakeOff - Reference: 28_PBT_SC_staal_koker:S355_K180x180x12.5
Pset_ReinforcementBarPitchOfColumn - Reference: 28_PBT_SC_staal_koker:S355_K180x180x12.5
Pset_Pieters - Bouwlaag: Level: 02 tweede verdieping; Naamgeving element: 28_PBT_SC_staal_koker: S355_K180x180x12.5; Fase: Nieuw

# IfcColumn: 28_PBT_SC_staal_koker:S355_K250x150x10 (3)
In: 01 eerste verdieping
Type - PredefinedType: COLUMN; Classification: 28.11 hoofddraagconstructies - kolommen en liggers, kolom-/liggerconstructies (Uniformat); Material: 00_PBT_MAT_staal_S355
Type - Pset_ColumnCommon - IsExternal: no; LoadBearing: yes
Type - Pset_ProductRequirements - Category: Structural Columns
Type - Pset_ReinforcementBarPitchOfColumn - Description: K250x150x10
Type - Pset_Pieters - Breedte: 150 mm; Hoogte: 250 mm; Codering - NL-SfB: 28.11; Omschrijving NL-SfB: hoofddraagconstructies - kolommen en liggers, kolom-/liggerconstructies; Materiaal: 00_PBT_MAT_staal_S355; Materiaalkwaliteit: S355; Description: K250x150x10
Pset_ColumnCommon - Reference: 28_PBT_SC_staal_koker:S355_K250x150x10
Pset_QuantityTakeOff - Reference: 28_PBT_SC_staal_koker:S355_K250x150x10
Pset_ReinforcementBarPitchOfColumn - Reference: 28_PBT_SC_staal_koker:S355_K250x150x10
Pset_Pieters - Dragend/niet dragend: yes; Bouwlaag: Level: 01 eerste verdieping; Naamgeving element: 28_PBT_SC_staal_koker: S355_K250x150x10; Fase: Nieuw
Name (28_PBT_SC_staal_koker:S355_K250x150x10:...) | CrossSectionArea (mm2) | NetVolume (m3)
2067586 | 5151422 | 0.0521864
2067823 | 5151422 | 0.0521864
2067840 | 5114495 | 0.0518118

# IfcColumn: 28_PBT_SC_staal_koker:S355_K250x250x12.5, 28_PBT_SC_staal_koker:S355_K250x250x12.5:2310848
In: 01 eerste verdieping
Type - PredefinedType: COLUMN; Classification: 28.11 hoofddraagconstructies - kolommen en liggers, kolom-/liggerconstructies (Uniformat); Material: 00_PBT_MAT_staal_S355
Type - Pset_ColumnCommon - IsExternal: no; LoadBearing: yes
Type - Pset_ProductRequirements - Category: Structural Columns
Type - Pset_ReinforcementBarPitchOfColumn - Description: K250x250x12.5
Type - Pset_Pieters - Breedte: 250 mm; Hoogte: 250 mm; Codering - NL-SfB: 28.11; Omschrijving NL-SfB: hoofddraagconstructies - kolommen en liggers, kolom-/liggerconstructies; Materiaal: 00_PBT_MAT_staal_S355; Materiaalkwaliteit: S355; Description: K250x250x12.5
BaseQuantities - CrossSectionArea: 1885752 mm2; NetVolume: 0.0237658 m3
Pset_ColumnCommon - Reference: 28_PBT_SC_staal_koker:S355_K250x250x12.5
Pset_QuantityTakeOff - Reference: 28_PBT_SC_staal_koker:S355_K250x250x12.5
Pset_ReinforcementBarPitchOfColumn - Reference: 28_PBT_SC_staal_koker:S355_K250x250x12.5
Pset_Pieters - Bouwlaag: Level: 01 eerste verdieping; Naamgeving element: 28_PBT_SC_staal_koker: S355_K250x250x12.5; Fase: Nieuw

# IfcColumn: 28_PBT_SC_staal_koker:S355_K250x250x20_GB_C40/50 (5)
Type - PredefinedType: COLUMN; Classification: 28.11 hoofddraagconstructies - kolommen en liggers, kolom-/liggerconstructies (Uniformat); Material: 00_PBT_MAT_beton t.p.g._C40/50, 00_PBT_MAT_staal_S355
Type - Pset_ColumnCommon - IsExternal: no; LoadBearing: yes
Type - Pset_ProductRequirements - Category: Structural Columns
Type - Pset_ReinforcementBarPitchOfColumn - Description: K250x250x20 (GB)
Type - Pset_Pieters - Breedte: 250 mm; Hoogte: 250 mm; Codering - NL-SfB: 28.11; Omschrijving NL-SfB: hoofddraagconstructies - kolommen en liggers, kolom-/liggerconstructies; Materiaal: 00_PBT_MAT_staal_S355; Materiaalkwaliteit: S355; Description: K250x250x20 (GB)
Pset_ColumnCommon - Reference: 28_PBT_SC_staal_koker:S355_K250x250x20_GB_C40/50
Pset_QuantityTakeOff - Reference: 28_PBT_SC_staal_koker:S355_K250x250x20_GB_C40/50
Pset_ReinforcementBarPitchOfColumn - Reference: 28_PBT_SC_staal_koker:S355_K250x250x20_GB_C40/50
Pset_Pieters - Naamgeving element: 28_PBT_SC_staal_koker: S355_K250x250x20_GB_C40/50; Fase: Nieuw
Name (28_PBT_SC_staal_koker:S355_K250x250x20_GB_C40/50:...) | In | CrossSectionArea (mm2) | NetVolume (m3) | Bouwlaag
3863668 | 00 begane grond | 4116585 | 0.0846616 | Level: 00 begane grond
3864543 | -1 kelder | 2600626 | 0.0533459 | Level: -1 kelder
3864626 | 01 eerste verdieping | 3041312 | 0.0624493 | Level: 01 eerste verdieping
3865487 | 02 tweede verdieping | 3195552 | 0.0656355 | Level: 02 tweede verdieping
3869789 | 03 derde verdieping | 2951412 | 0.0605922 | Level: 03 derde verdieping

# IfcColumn: 28_PBT_SC_staal_koker:S355_K300x300x16, 28_PBT_SC_staal_koker:S355_K300x300x16:2824680
In: 01 eerste verdieping
Type - PredefinedType: COLUMN; Classification: 28.11 hoofddraagconstructies - kolommen en liggers, kolom-/liggerconstructies (Uniformat); Material: 00_PBT_MAT_staal_S355
Type - Pset_ColumnCommon - IsExternal: no; LoadBearing: yes
Type - Pset_ProductRequirements - Category: Structural Columns
Type - Pset_ReinforcementBarPitchOfColumn - Description: K300x300x16
Type - Pset_Pieters - Breedte: 300 mm; Hoogte: 300 mm; Codering - NL-SfB: 28.11; Omschrijving NL-SfB: hoofddraagconstructies - kolommen en liggers, kolom-/liggerconstructies; Materiaal: 00_PBT_MAT_staal_S355; Materiaalkwaliteit: S355; Description: K300x300x16
BaseQuantities - CrossSectionArea: 3617492 mm2; NetVolume: 0.0583994 m3
Pset_ColumnCommon - Reference: 28_PBT_SC_staal_koker:S355_K300x300x16
Pset_QuantityTakeOff - Reference: 28_PBT_SC_staal_koker:S355_K300x300x16
Pset_ReinforcementBarPitchOfColumn - Reference: 28_PBT_SC_staal_koker:S355_K300x300x16
Pset_Pieters - Bouwlaag: Level: 01 eerste verdieping; Naamgeving element: 28_PBT_SC_staal_koker: S355_K300x300x16; Fase: Nieuw

# IfcColumn: 28_PBT_SC_staal_koker:S355_K80x80x5 (2)
In: 02 tweede verdieping
Type - PredefinedType: COLUMN; Classification: 28.11 hoofddraagconstructies - kolommen en liggers, kolom-/liggerconstructies (Uniformat); Material: 00_PBT_MAT_staal_S355
Type - Pset_ColumnCommon - IsExternal: no; LoadBearing: yes
Type - Pset_ProductRequirements - Category: Structural Columns
Type - Pset_ReinforcementBarPitchOfColumn - Description: K80x80x5
Type - Pset_Pieters - Breedte: 80 mm; Hoogte: 80 mm; Codering - NL-SfB: 28.11; Omschrijving NL-SfB: hoofddraagconstructies - kolommen en liggers, kolom-/liggerconstructies; Materiaal: 00_PBT_MAT_staal_S355; Materiaalkwaliteit: S355; Description: K80x80x5
BaseQuantities - CrossSectionArea: 857712 mm2; NetVolume: 0.00436058 m3
Pset_ColumnCommon - Reference: 28_PBT_SC_staal_koker:S355_K80x80x5
Pset_QuantityTakeOff - Reference: 28_PBT_SC_staal_koker:S355_K80x80x5
Pset_ReinforcementBarPitchOfColumn - Reference: 28_PBT_SC_staal_koker:S355_K80x80x5
Pset_Pieters - Bouwlaag: Level: 02 tweede verdieping; Naamgeving element: 28_PBT_SC_staal_koker: S355_K80x80x5; Fase: Nieuw
Name (28_PBT_SC_staal_koker:S355_K80x80x5:...)
4335304
4335413

# IfcColumn: 28_PBT_SC_staal_koker:S355_K80x80x6.3 (13)
Type - PredefinedType: COLUMN; Classification: 28.11 hoofddraagconstructies - kolommen en liggers, kolom-/liggerconstructies (Uniformat); Material: 00_PBT_MAT_staal_S355
Type - Pset_ColumnCommon - IsExternal: no; LoadBearing: yes
Type - Pset_ProductRequirements - Category: Structural Columns
Type - Pset_ReinforcementBarPitchOfColumn - Description: K80x80x6.3
Type - Pset_Pieters - Breedte: 80 mm; Hoogte: 80 mm; Codering - NL-SfB: 28.11; Omschrijving NL-SfB: hoofddraagconstructies - kolommen en liggers, kolom-/liggerconstructies; Materiaal: 00_PBT_MAT_staal_S355; Materiaalkwaliteit: S355; Description: K80x80x6.3
Pset_ColumnCommon - Reference: 28_PBT_SC_staal_koker:S355_K80x80x6.3
Pset_QuantityTakeOff - Reference: 28_PBT_SC_staal_koker:S355_K80x80x6.3
Pset_ReinforcementBarPitchOfColumn - Reference: 28_PBT_SC_staal_koker:S355_K80x80x6.3
Pset_Pieters - Naamgeving element: 28_PBT_SC_staal_koker: S355_K80x80x6.3; Fase: Nieuw
Name (28_PBT_SC_staal_koker:S355_K80x80x6.3:...) | In | CrossSectionArea (mm2) | NetVolume (m3) | Bouwlaag
2360183 | 01 eerste verdieping | 968012 | 0.00623329 | Level: 01 eerste verdieping
2360292 | 01 eerste verdieping | 968012 | 0.00623329 | Level: 01 eerste verdieping
2360360 | 02 tweede verdieping | 1025674 | 0.00660529 | Level: 02 tweede verdieping
2360362 | 02 tweede verdieping | 1025674 | 0.00660529 | Level: 02 tweede verdieping
2360368 | 00 begane grond | 1003172 | 0.00646012 | Level: 00 begane grond
2360370 | 00 begane grond | 1003172 | 0.00646012 | Level: 00 begane grond
2360520 | 03 derde verdieping | 1261949 | 0.00812959 | Level: 03 derde verdieping
2360522 | 03 derde verdieping | 1261949 | 0.00812959 | Level: 03 derde verdieping
3462639 | 02 tweede verdieping | 733143 | 0.00471807 | Level: 02 tweede verdieping
3466623 | 02 tweede verdieping | 733143 | 0.00471807 | Level: 02 tweede verdieping
3466645 | 02 tweede verdieping | 733143 | 0.00471807 | Level: 02 tweede verdieping
3467453 | 02 tweede verdieping | 733143 | 0.00471807 | Level: 02 tweede verdieping | Pset_ColumnCommon - Slope: 0 deg
3467473 | 02 tweede verdieping | 696576 | 0.00448216 | Level: 02 tweede verdieping

# IfcColumn: 28_PBT_SC_staal_massief_rond:D30 (2)
In: 00 begane grond
Type - PredefinedType: COLUMN; Classification: 28.11 hoofddraagconstructies - kolommen en liggers, kolom-/liggerconstructies (Uniformat); Material: 00_PBT_MAT_staal
Type - Pset_ColumnCommon - IsExternal: no; LoadBearing: yes
Type - Pset_ProductRequirements - Category: Structural Columns
Type - Pset_ReinforcementBarPitchOfColumn - Description: $30
Type - Pset_Pieters - Diameter: 30 mm; Codering - NL-SfB: 28.11; Omschrijving NL-SfB: hoofddraagconstructies - kolommen en liggers, kolom-/liggerconstructies; Materiaal: 00_PBT_MAT_staal; Materiaalkwaliteit: S355; Description: $30
BaseQuantities - CrossSectionArea: 132748 mm2; NetVolume: 0.00198052 m3
Pset_ColumnCommon - Reference: 28_PBT_SC_staal_massief_rond:D30
Pset_QuantityTakeOff - Reference: 28_PBT_SC_staal_massief_rond:D30
Pset_ReinforcementBarPitchOfColumn - Reference: 28_PBT_SC_staal_massief_rond:D30
Pset_Pieters - Bouwlaag: Level: 00 begane grond; Naamgeving element: 28_PBT_SC_staal_massief_rond: D30; Fase: Nieuw
Name (28_PBT_SC_staal_massief_rond:D30:...)
5512467
5513231

# IfcColumn: 28_PBT_SC_staal_massief_rond:D40 (2)
In: 01 eerste verdieping
Type - PredefinedType: COLUMN; Classification: 28.11 hoofddraagconstructies - kolommen en liggers, kolom-/liggerconstructies (Uniformat); Material: 00_PBT_MAT_staal_S355
Type - Pset_ColumnCommon - IsExternal: no; LoadBearing: yes
Type - Pset_ProductRequirements - Category: Structural Columns
Type - Pset_ReinforcementBarPitchOfColumn - Description: $40
Type - Pset_Pieters - Diameter: 40 mm; Codering - NL-SfB: 28.11; Omschrijving NL-SfB: hoofddraagconstructies - kolommen en liggers, kolom-/liggerconstructies; Materiaal: 00_PBT_MAT_staal_S355; Materiaalkwaliteit: S355; Description: $40
BaseQuantities - CrossSectionArea: 560020 mm2; NetVolume: 0.0111747 m3
Pset_ColumnCommon - Reference: 28_PBT_SC_staal_massief_rond:D40
Pset_QuantityTakeOff - Reference: 28_PBT_SC_staal_massief_rond:D40
Pset_ReinforcementBarPitchOfColumn - Reference: 28_PBT_SC_staal_massief_rond:D40
Pset_Pieters - Bouwlaag: Level: 01 eerste verdieping; Naamgeving element: 28_PBT_SC_staal_massief_rond: D40; Fase: Nieuw
Name (28_PBT_SC_staal_massief_rond:D40:...)
5513385
5513572

# IfcFooting: 11_PBT_SFO_damwand_ter indicatie:Damwand ter indicatie (2)
In: -2 kelder
Type - Classification: 11.15 bodemvoorzieningen - grond, damwanden (Uniformat); Material: 00_PBT_MAT_staal
Pset_ProductRequirements - Category: Structural Foundations
Pset_QuantityTakeOff - Reference: 11_PBT_SFO_damwand_ter indicatie:Damwand ter indicatie
Pset_ReinforcementBarCountOfIndependentFooting - Description: stalen damwand ter indicatie + waterglasinjectie; Reference: 11_PBT_SFO_damwand_ter indicatie:Damwand ter indicatie; sets with these values: 2
Pset_Pieters - Dragend/niet dragend: yes; Lengte poer: 20000 mm; Bouwlaag: Level: NAP; Naamgeving element: 11_PBT_SFO_damwand_ter indicatie: Damwand ter indicatie; Codering - NL-SfB: 11.15; Omschrijving NL-SfB: bodemvoorzieningen - grond, damwanden; Fase: Nieuw; Materiaal: 00_PBT_MAT_staal; Description: stalen damwand ter indicatie + waterglasinjectie
Name (11_PBT_SFO_damwand_ter indicatie:Damwand ter indicatie:...)
3957708
3958209

# IfcFooting: 11_PBT_SFO_damwand_ter indicatie:Damwand ter indicatie, 11_PBT_SFO_damwand_ter indicatie:Damwand ter indicatie:3957291
In: -2 kelder
Type - Classification: 11.15 bodemvoorzieningen - grond, damwanden (Uniformat); Material: 00_PBT_MAT_staal (11)
Pset_ProductRequirements - Category: Structural Foundations
Pset_QuantityTakeOff - Reference: 11_PBT_SFO_damwand_ter indicatie:Damwand ter indicatie
Pset_ReinforcementBarCountOfIndependentFooting - Description: stalen damwand ter indicatie + waterglasinjectie; Reference: 11_PBT_SFO_damwand_ter indicatie:Damwand ter indicatie; sets with these values: 2
Pset_Pieters - Dragend/niet dragend: yes; Lengte poer: 20000 mm; Bouwlaag: Level: NAP; Naamgeving element: 11_PBT_SFO_damwand_ter indicatie: Damwand ter indicatie; Codering - NL-SfB: 11.15; Omschrijving NL-SfB: bodemvoorzieningen - grond, damwanden; Fase: Nieuw; Materiaal: 00_PBT_MAT_staal; Description: stalen damwand ter indicatie + waterglasinjectie

# IfcFooting: 16_PBT_SC_beton_opstort_rechthoekig:C30/37_250x400, 16_PBT_SC_beton_opstort_rechthoekig:C30/37_250x400:3590447
In: 05 vijfde verdieping
Type - Classification: 16.10 funderingsconstructies - voeten en balken, algemeen (verzamelniveau) (Uniformat); Material: 00_PBT_MAT_beton t.p.g._C30/37
Pset_ProductRequirements - Category: Structural Columns
Pset_QuantityTakeOff - Reference: 16_PBT_SC_beton_opstort_rechthoekig:C30/37_250x400
Pset_ReinforcementBarCountOfIndependentFooting - Description: opstort 250x400; Reference: 16_PBT_SC_beton_opstort_rechthoekig:C30/37_250x400; sets with these values: 2
Pset_Pieters - Lengte poer: 200 mm; Breedte: 250 mm; Hoogte: 400 mm; Bouwlaag: Level: 05 vijfde verdieping; Naamgeving element: 16_PBT_SC_beton_opstort_rechthoekig: C30/37_250x400; Codering - NL-SfB: 16.10; Omschrijving NL-SfB: funderingsconstructies - voeten en balken, algemeen (verzamelniveau); Fase: Nieuw; Materiaal: 00_PBT_MAT_beton t.p.g._C30/37; Materiaalkwaliteit: C30/37; Description: opstort 250x400

# IfcFooting: 16_PBT_SFO_beton_poer:1000x2000x900_bestaand (6)
In: -1 kelder
Type - Classification: 16.13 funderingsconstructies - voeten en balken, fundatie poeren (Uniformat); Material: 00_PBT_MAT_beton t.p.g.
Pset_ProductRequirements - Category: Structural Foundations
Pset_QuantityTakeOff - Reference: 16_PBT_SFO_beton_poer:1000x2000x900_bestaand
Pset_ReinforcementBarCountOfIndependentFooting - Description: poer 1000x2000x900; Reference: 16_PBT_SFO_beton_poer:1000x2000x900_bestaand; sets with these values: 2
Pset_Pieters - Dragend/niet dragend: yes; Lengte poer: 2000 mm; Breedte: 1000 mm; Hoogte: 900 mm; Bouwlaag: Level: -1 kelder_Offset1000; Naamgeving element: 16_PBT_SFO_beton_poer: 1000x2000x900_bestaand; Codering - NL-SfB: 16.13; Omschrijving NL-SfB: funderingsconstructies - voeten en balken, fundatie poeren; Fase: Bestaand; Materiaal: 00_PBT_MAT_beton t.p.g.; Description: poer 1000x2000x900
Name (16_PBT_SFO_beton_poer:1000x2000x900_bestaand:...)
1369053
1373168
1373235
1373302
1373304
1400777

# IfcFooting: 16_PBT_SFO_beton_poer:2000x2000x900_bestaand (7)
In: -1 kelder
Type - Classification: 16.13 funderingsconstructies - voeten en balken, fundatie poeren (Uniformat); Material: 00_PBT_MAT_beton t.p.g.
Pset_ProductRequirements - Category: Structural Foundations
Pset_QuantityTakeOff - Reference: 16_PBT_SFO_beton_poer:2000x2000x900_bestaand
Pset_ReinforcementBarCountOfIndependentFooting - Description: poer 2000x2000x900; Reference: 16_PBT_SFO_beton_poer:2000x2000x900_bestaand; sets with these values: 2
Pset_Pieters - Dragend/niet dragend: yes; Lengte poer: 2000 mm; Breedte: 2000 mm; Hoogte: 900 mm; Bouwlaag: Level: -1 kelder_Offset1000; Naamgeving element: 16_PBT_SFO_beton_poer: 2000x2000x900_bestaand; Codering - NL-SfB: 16.13; Omschrijving NL-SfB: funderingsconstructies - voeten en balken, fundatie poeren; Fase: Bestaand; Materiaal: 00_PBT_MAT_beton t.p.g.; Description: poer 2000x2000x900
Name (16_PBT_SFO_beton_poer:2000x2000x900_bestaand:...)
1376975
1377334
1377780
1377867
1377941
1377958
1377977

# IfcFooting: 16_PBT_SFO_beton_poer:2600x2600x1500_C53/65, 16_PBT_SFO_beton_poer:2600x2600x1500_C53/65:3051232
In: -1 kelder
Type - Classification: 16.13 funderingsconstructies - voeten en balken, fundatie poeren (Uniformat); Material: 00_PBT_MAT_beton t.p.g._C53/65
Pset_ProductRequirements - Category: Structural Foundations
Pset_QuantityTakeOff - Reference: 16_PBT_SFO_beton_poer:2600x2600x1500_C53/65
Pset_ReinforcementBarCountOfIndependentFooting - Description: poer 2600x2600x1500 C53/65; Reference: 16_PBT_SFO_beton_poer:2600x2600x1500_C53/65; sets with these values: 2
Pset_Pieters - Dragend/niet dragend: yes; Lengte poer: 2600 mm; Breedte: 2600 mm; Hoogte: 1500 mm; Bouwlaag: Level: -1 kelder_Offset1000; Naamgeving element: 16_PBT_SFO_beton_poer: 2600x2600x1500_C53/65; Codering - NL-SfB: 16.13; Omschrijving NL-SfB: funderingsconstructies - voeten en balken, fundatie poeren; Fase: Nieuw; Materiaal: 00_PBT_MAT_beton t.p.g._C53/65; Materiaalkwaliteit: C53/65; Description: poer 2600x2600x1500 C53/65

# IfcFooting: 16_PBT_SFO_beton_poer:5400x2000x900_bestaand (2)
In: -1 kelder
Type - Classification: 16.13 funderingsconstructies - voeten en balken, fundatie poeren (Uniformat); Material: 00_PBT_MAT_beton t.p.g.
Pset_ProductRequirements - Category: Structural Foundations
Pset_QuantityTakeOff - Reference: 16_PBT_SFO_beton_poer:5400x2000x900_bestaand
Pset_ReinforcementBarCountOfIndependentFooting - Description: poer 5400x2000x900; Reference: 16_PBT_SFO_beton_poer:5400x2000x900_bestaand; sets with these values: 2
Pset_Pieters - Dragend/niet dragend: yes; Lengte poer: 2000 mm; Breedte: 5400 mm; Hoogte: 900 mm; Bouwlaag: Level: -1 kelder_Offset1000; Naamgeving element: 16_PBT_SFO_beton_poer: 5400x2000x900_bestaand; Codering - NL-SfB: 16.13; Omschrijving NL-SfB: funderingsconstructies - voeten en balken, fundatie poeren; Fase: Bestaand; Materiaal: 00_PBT_MAT_beton t.p.g.; Description: poer 5400x2000x900
Name (16_PBT_SFO_beton_poer:5400x2000x900_bestaand:...)
1375581
1376252

# IfcFooting: 16_PBT_SFO_beton_poer:C30/37_1000x5000x1870, 16_PBT_SFO_beton_poer:C30/37_1000x5000x1870:3040751
In: 00 begane grond
Type - Classification: 16.13 funderingsconstructies - voeten en balken, fundatie poeren (Uniformat); Material: 00_PBT_MAT_beton t.p.g._C30/37
Pset_ProductRequirements - Category: Structural Foundations
Pset_QuantityTakeOff - Reference: 16_PBT_SFO_beton_poer:C30/37_1000x5000x1870
Pset_ReinforcementBarCountOfIndependentFooting - Description: poer 1000x5000x1870; Reference: 16_PBT_SFO_beton_poer:C30/37_1000x5000x1870; sets with these values: 2
Pset_Pieters - Dragend/niet dragend: yes; Lengte poer: 5000 mm; Breedte: 1000 mm; Hoogte: 1870 mm; Bouwlaag: Level: 00 begane grond; Naamgeving element: 16_PBT_SFO_beton_poer: C30/37_1000x5000x1870; Codering - NL-SfB: 16.13; Omschrijving NL-SfB: funderingsconstructies - voeten en balken, fundatie poeren; Fase: Nieuw; Materiaal: 00_PBT_MAT_beton t.p.g._C30/37; Materiaalkwaliteit: C30/37; Description: poer 1000x5000x1870

# IfcFooting: 16_PBT_SFO_beton_poer:C30/37_2750x2962x1300, 16_PBT_SFO_beton_poer:C30/37_2750x2962x1300:3042996
In: 00 begane grond
Type - Classification: 16.13 funderingsconstructies - voeten en balken, fundatie poeren (Uniformat); Material: 00_PBT_MAT_beton t.p.g._C30/37
Pset_ProductRequirements - Category: Structural Foundations
Pset_QuantityTakeOff - Reference: 16_PBT_SFO_beton_poer:C30/37_2750x2962x1300
Pset_ReinforcementBarCountOfIndependentFooting - Description: poer 2750x2962x1300; Reference: 16_PBT_SFO_beton_poer:C30/37_2750x2962x1300; sets with these values: 2
Pset_Pieters - Dragend/niet dragend: yes; Lengte poer: 2750 mm; Breedte: 2961.2 mm; Hoogte: 1300 mm; Bouwlaag: Level: 00 begane grond; Naamgeving element: 16_PBT_SFO_beton_poer: C30/37_2750x2962x1300; Codering - NL-SfB: 16.13; Omschrijving NL-SfB: funderingsconstructies - voeten en balken, fundatie poeren; Fase: Nieuw; Materiaal: 00_PBT_MAT_beton t.p.g._C30/37; Materiaalkwaliteit: C30/37; Description: poer 2750x2962x1300

# IfcFooting: 16_PBT_SFO_beton_poer:C30/37_3500x3500x1600, 16_PBT_SFO_beton_poer:C30/37_3500x3500x1600:3174846
In: -1 kelder
Type - Classification: 16.13 funderingsconstructies - voeten en balken, fundatie poeren (Uniformat); Material: 00_PBT_MAT_beton t.p.g._C30/37
Pset_ProductRequirements - Category: Structural Foundations
Pset_QuantityTakeOff - Reference: 16_PBT_SFO_beton_poer:C30/37_3500x3500x1600
Pset_ReinforcementBarCountOfIndependentFooting - Description: poer 3500x3500x1600; Reference: 16_PBT_SFO_beton_poer:C30/37_3500x3500x1600; sets with these values: 2
Pset_Pieters - Dragend/niet dragend: yes; Lengte poer: 3500 mm; Breedte: 3500 mm; Hoogte: 1600 mm; Bouwlaag: Level: -1 kelder; Naamgeving element: 16_PBT_SFO_beton_poer: C30/37_3500x3500x1600; Codering - NL-SfB: 16.13; Omschrijving NL-SfB: funderingsconstructies - voeten en balken, fundatie poeren; Fase: Nieuw; Materiaal: 00_PBT_MAT_beton t.p.g._C30/37; Materiaalkwaliteit: C30/37; Description: poer 3500x3500x1600

# IfcFooting: 16_PBT_SFO_poer schuine onderzijde as B:16_PBT_SFO_poer schuine onderzijde as B_C53/65, 16_PBT_SFO_poer schuine onderzijde as B:16_PBT_SFO_poer schuine onderzijde as B_C53/65:4231019
In: -1 kelder
Type - Material: 00_PBT_MAT_beton t.p.g._C53/65
Pset_ProductRequirements - Category: Structural Foundations
Pset_QuantityTakeOff - Reference: 16_PBT_SFO_poer schuine onderzijde as B:16_PBT_SFO_poer schuine onderzijde as B_C53/65
Pset_ReinforcementBarCountOfIndependentFooting - Description: poerstrook; Reference: 16_PBT_SFO_poer schuine onderzijde as B:16_PBT_SFO_poer schuine onderzijde as B_C53/65; sets with these values: 2
Pset_Pieters - Bouwlaag: Level: -1 kelder; Naamgeving element: 16_PBT_SFO_poer schuine onderzijde as B: 16_PBT_SFO_poer schuine onderzijde as B_C53/65; Fase: Nieuw; Materiaal: 00_PBT_MAT_beton t.p.g._C53/65; Materiaalkwaliteit: C53/65; Description: poerstrook

# IfcFooting: 16_PBT_SF_funderingsbalk enkele sponning:C30/37_1000x2060/250x400, 16_PBT_SF_funderingsbalk enkele sponning:C30/37_1000x2060/250x400:4509702
In: -1 kelder
Type - Classification: 16.13 funderingsconstructies - voeten en balken, fundatie poeren (Uniformat); Material: 00_PBT_MAT_beton t.p.g._C30/37
Pset_ProductRequirements - Category: Structural Framing
Pset_QuantityTakeOff - Reference: 16_PBT_SF_funderingsbalk enkele sponning:C30/37_1000x2060/250x400; sets with these values: 3
Pset_Pieters - Lengte poer: 5229.06 mm; Breedte: 1000 mm; Hoogte: 2060 mm; Bouwlaag: Level: -1 kelder; Naamgeving element: 16_PBT_SF_funderingsbalk enkele sponning: C30/37_1000x2060/250x400; Codering - NL-SfB: 16.13; Omschrijving NL-SfB: funderingsconstructies - voeten en balken, fundatie poeren; Fase: Nieuw; Materiaal: 00_PBT_MAT_beton t.p.g._C30/37; Materiaalkwaliteit: C30/37

# IfcFooting: 16_PBT_SF_funderingsbalk enkele sponning:C30/37_2050x2060/250x400, 16_PBT_SF_funderingsbalk enkele sponning:C30/37_2050x2060/250x400:4509880
In: -1 kelder
Type - Classification: 16.13 funderingsconstructies - voeten en balken, fundatie poeren (Uniformat); Material: 00_PBT_MAT_beton t.p.g._C30/37
Pset_ProductRequirements - Category: Structural Framing
Pset_QuantityTakeOff - Reference: 16_PBT_SF_funderingsbalk enkele sponning:C30/37_2050x2060/250x400; sets with these values: 3
Pset_Pieters - Lengte poer: 3100 mm; Breedte: 2050 mm; Hoogte: 2060 mm; Bouwlaag: Level: -1 kelder; Naamgeving element: 16_PBT_SF_funderingsbalk enkele sponning: C30/37_2050x2060/250x400; Codering - NL-SfB: 16.13; Omschrijving NL-SfB: funderingsconstructies - voeten en balken, fundatie poeren; Fase: Nieuw; Materiaal: 00_PBT_MAT_beton t.p.g._C30/37; Materiaalkwaliteit: C30/37

# IfcFooting: 16_PBT_SF_funderingsbalk enkele sponning:C30/37_800x2060/450x400, 16_PBT_SF_funderingsbalk enkele sponning:C30/37_800x2060/450x400:4510067
In: -1 kelder
Type - Classification: 16.13 funderingsconstructies - voeten en balken, fundatie poeren (Uniformat); Material: 00_PBT_MAT_beton t.p.g._C30/37
Pset_ProductRequirements - Category: Structural Framing
Pset_QuantityTakeOff - Reference: 16_PBT_SF_funderingsbalk enkele sponning:C30/37_800x2060/450x400; sets with these values: 3
Pset_Pieters - Lengte poer: 4910 mm; Breedte: 800 mm; Hoogte: 2060 mm; Bouwlaag: Level: -1 kelder; Naamgeving element: 16_PBT_SF_funderingsbalk enkele sponning: C30/37_800x2060/450x400; Codering - NL-SfB: 16.13; Omschrijving NL-SfB: funderingsconstructies - voeten en balken, fundatie poeren; Fase: Nieuw; Materiaal: 00_PBT_MAT_beton t.p.g._C30/37; Materiaalkwaliteit: C30/37

# IfcFooting: 16_PBT_SF_funderingsbalk:400x1360_bestaand, 16_PBT_SF_funderingsbalk:400x1360_bestaand:1311944
In: -1 kelder
Type - Classification: 16.12 funderingsconstructies - voeten en balken, fundatie balken (Uniformat); Material: 00_PBT_MAT_beton t.p.g.
Pset_ProductRequirements - Category: Structural Framing
Pset_QuantityTakeOff - Reference: 16_PBT_SF_funderingsbalk:400x1360_bestaand
Pset_ReinforcementBarCountOfIndependentFooting - Description: 400x1360; Reference: 16_PBT_SF_funderingsbalk:400x1360_bestaand; sets with these values: 2
Pset_Pieters - Dragend/niet dragend: yes; Lengte poer: 3600 mm; Breedte: 400 mm; Hoogte: 1360 mm; Bouwlaag: Level: -1 kelder_Offset1000; Naamgeving element: 16_PBT_SF_funderingsbalk: 400x1360_bestaand; Codering - NL-SfB: 16.12; Omschrijving NL-SfB: funderingsconstructies - voeten en balken, fundatie balken; Fase: Bestaand; Materiaal: 00_PBT_MAT_beton t.p.g.; Description: 400x1360

# IfcFooting: 16_PBT_SF_funderingsbalk:400x960_bestaand, 16_PBT_SF_funderingsbalk:400x960_bestaand:1363416
In: -1 kelder
Type - Classification: 16.12 funderingsconstructies - voeten en balken, fundatie balken (Uniformat); Material: 00_PBT_MAT_beton t.p.g.
Pset_ProductRequirements - Category: Structural Framing
Pset_QuantityTakeOff - Reference: 16_PBT_SF_funderingsbalk:400x960_bestaand
Pset_ReinforcementBarCountOfIndependentFooting - Description: 400x960; Reference: 16_PBT_SF_funderingsbalk:400x960_bestaand; sets with these values: 2
Pset_Pieters - Dragend/niet dragend: yes; Lengte poer: 2410 mm; Breedte: 400 mm; Hoogte: 960 mm; Bouwlaag: Level: -1 kelder_Offset1000; Naamgeving element: 16_PBT_SF_funderingsbalk: 400x960_bestaand; Codering - NL-SfB: 16.12; Omschrijving NL-SfB: funderingsconstructies - voeten en balken, fundatie balken; Fase: Bestaand; Materiaal: 00_PBT_MAT_beton t.p.g.; Description: 400x960

# IfcFooting: 16_PBT_SF_funderingsbalk:470x1360_bestaand, 16_PBT_SF_funderingsbalk:470x1360_bestaand:1311947
In: -1 kelder
Type - Classification: 16.12 funderingsconstructies - voeten en balken, fundatie balken (Uniformat); Material: 00_PBT_MAT_beton t.p.g.
Pset_ProductRequirements - Category: Structural Framing
Pset_QuantityTakeOff - Reference: 16_PBT_SF_funderingsbalk:470x1360_bestaand
Pset_ReinforcementBarCountOfIndependentFooting - Description: 470x1360; Reference: 16_PBT_SF_funderingsbalk:470x1360_bestaand; sets with these values: 2
Pset_Pieters - Dragend/niet dragend: yes; Lengte poer: 3300 mm; Breedte: 470 mm; Hoogte: 1360 mm; Bouwlaag: Level: -1 kelder_Offset1000; Naamgeving element: 16_PBT_SF_funderingsbalk: 470x1360_bestaand; Codering - NL-SfB: 16.12; Omschrijving NL-SfB: funderingsconstructies - voeten en balken, fundatie balken; Fase: Bestaand; Materiaal: 00_PBT_MAT_beton t.p.g.; Description: 470x1360

# IfcFooting: 16_PBT_SF_funderingsbalk:500x2480_bestaand (3)
In: -1 kelder
Type - Classification: 16.12 funderingsconstructies - voeten en balken, fundatie balken (Uniformat); Material: 00_PBT_MAT_beton t.p.g.
Pset_ProductRequirements - Category: Structural Framing
Pset_QuantityTakeOff - Reference: 16_PBT_SF_funderingsbalk:500x2480_bestaand
Pset_ReinforcementBarCountOfIndependentFooting - Description: 500x2480; Reference: 16_PBT_SF_funderingsbalk:500x2480_bestaand; sets with these values: 2
Pset_Pieters - Dragend/niet dragend: yes; Breedte: 500 mm; Hoogte: 2480 mm; Bouwlaag: Level: -1 kelder_Offset1000; Naamgeving element: 16_PBT_SF_funderingsbalk: 500x2480_bestaand; Codering - NL-SfB: 16.12; Omschrijving NL-SfB: funderingsconstructies - voeten en balken, fundatie balken; Fase: Bestaand; Materiaal: 00_PBT_MAT_beton t.p.g.; Description: 500x2480
Name (16_PBT_SF_funderingsbalk:500x2480_bestaand:...) | Lengte poer (mm)
1349451 | 14332.6
1349628 | 3100
1349720 | 3140

# IfcFooting: 16_PBT_SF_funderingsbalk:500x3180_bestaand, 16_PBT_SF_funderingsbalk:500x3180_bestaand:1349806
In: -1 kelder
Type - Classification: 16.12 funderingsconstructies - voeten en balken, fundatie balken (Uniformat); Material: 00_PBT_MAT_beton t.p.g.
Pset_ProductRequirements - Category: Structural Framing
Pset_QuantityTakeOff - Reference: 16_PBT_SF_funderingsbalk:500x3180_bestaand
Pset_ReinforcementBarCountOfIndependentFooting - Description: 500x3180; Reference: 16_PBT_SF_funderingsbalk:500x3180_bestaand; sets with these values: 2
Pset_Pieters - Dragend/niet dragend: yes; Lengte poer: 13700 mm; Breedte: 500 mm; Hoogte: 3180 mm; Bouwlaag: Level: -1 kelder_Offset1000; Naamgeving element: 16_PBT_SF_funderingsbalk: 500x3180_bestaand; Codering - NL-SfB: 16.12; Omschrijving NL-SfB: funderingsconstructies - voeten en balken, fundatie balken; Fase: Bestaand; Materiaal: 00_PBT_MAT_beton t.p.g.; Description: 500x3180

# IfcFooting: 16_PBT_SF_funderingsbalk:500x960_bestaand, 16_PBT_SF_funderingsbalk:500x960_bestaand:1363959
In: -1 kelder
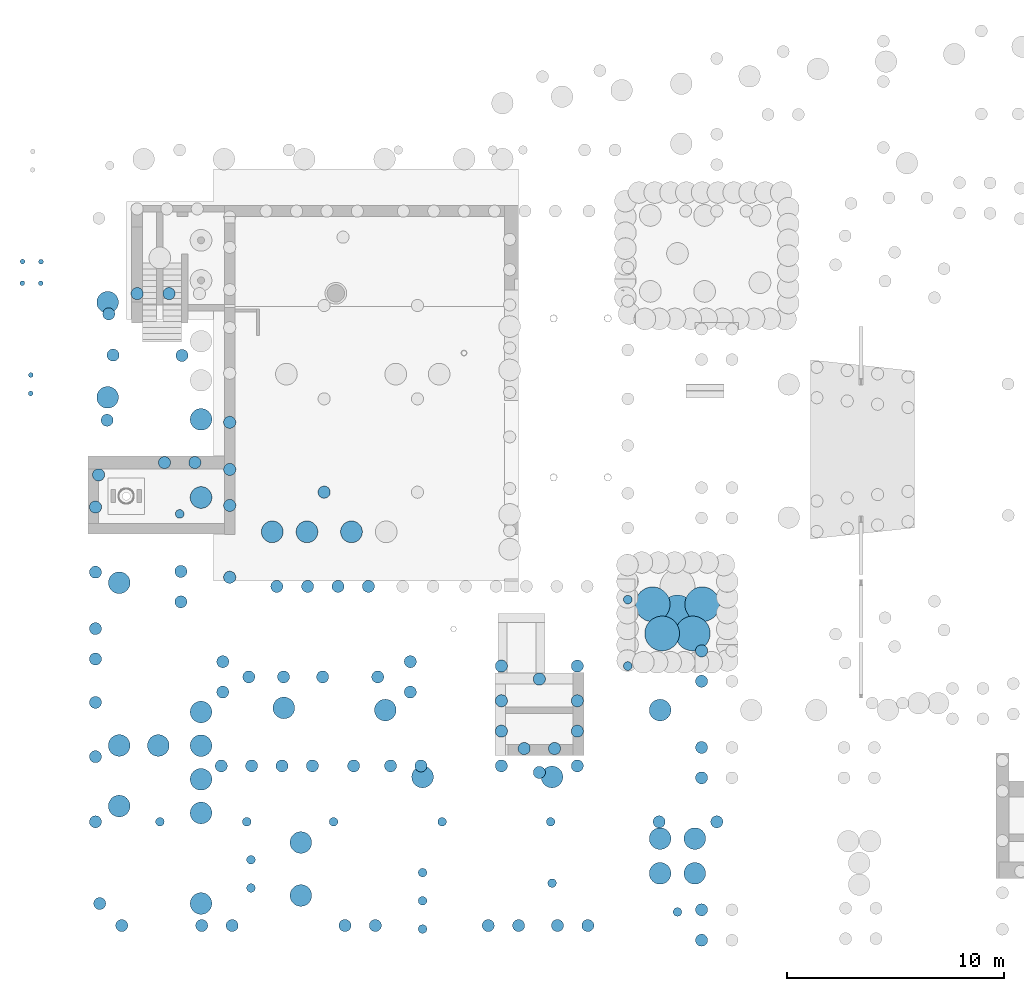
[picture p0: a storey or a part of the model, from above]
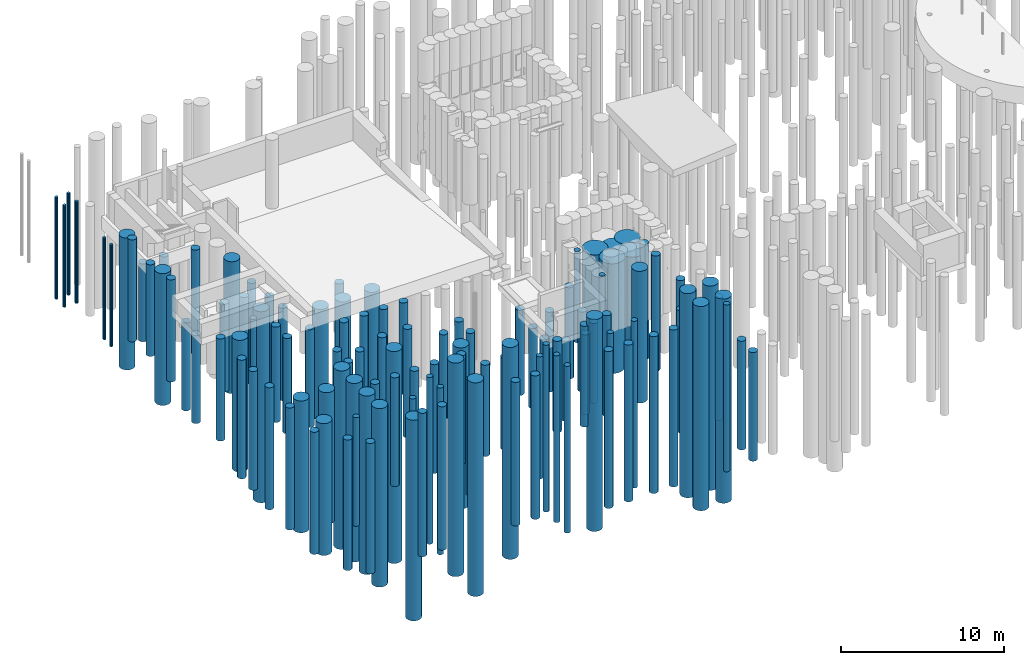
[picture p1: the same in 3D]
Properties of the parts of a building model (IFC2X3), part 11 of 18

# IfcFooting: 16_PBT_SF_funderingsbalk:500x960_bestaand, 16_PBT_SF_funderingsbalk:500x960_bestaand:1363959
Type - Classification: 16.12 funderingsconstructies - voeten en balken, fundatie balken (Uniformat); Material: 00_PBT_MAT_beton t.p.g.
Pset_ProductRequirements - Category: Structural Framing
Pset_QuantityTakeOff - Reference: 16_PBT_SF_funderingsbalk:500x960_bestaand
Pset_ReinforcementBarCountOfIndependentFooting - Description: 500x960; Reference: 16_PBT_SF_funderingsbalk:500x960_bestaand; sets with these values: 2
Pset_Pieters - Dragend/niet dragend: yes; Lengte poer: 6010 mm; Breedte: 500 mm; Hoogte: 960 mm; Bouwlaag: Level: -1 kelder_Offset1000; Naamgeving element: 16_PBT_SF_funderingsbalk: 500x960_bestaand; Codering - NL-SfB: 16.12; Omschrijving NL-SfB: funderingsconstructies - voeten en balken, fundatie balken; Fase: Bestaand; Materiaal: 00_PBT_MAT_beton t.p.g.; Description: 500x960

# IfcFooting: 16_PBT_SF_funderingsbalk:510x960_bestaand, 16_PBT_SF_funderingsbalk:510x960_bestaand:1363607
In: -1 kelder
Type - Classification: 16.12 funderingsconstructies - voeten en balken, fundatie balken (Uniformat); Material: 00_PBT_MAT_beton t.p.g.
Pset_ProductRequirements - Category: Structural Framing
Pset_QuantityTakeOff - Reference: 16_PBT_SF_funderingsbalk:510x960_bestaand
Pset_ReinforcementBarCountOfIndependentFooting - Description: 510x960; Reference: 16_PBT_SF_funderingsbalk:510x960_bestaand; sets with these values: 2
Pset_Pieters - Dragend/niet dragend: yes; Lengte poer: 5240 mm; Breedte: 510 mm; Hoogte: 960 mm; Bouwlaag: Level: -1 kelder_Offset1000; Naamgeving element: 16_PBT_SF_funderingsbalk: 510x960_bestaand; Codering - NL-SfB: 16.12; Omschrijving NL-SfB: funderingsconstructies - voeten en balken, fundatie balken; Fase: Bestaand; Materiaal: 00_PBT_MAT_beton t.p.g.; Description: 510x960

# IfcFooting: 16_PBT_SF_funderingsbalk:600x1360_bestaand (2)
In: -1 kelder
Type - Classification: 16.12 funderingsconstructies - voeten en balken, fundatie balken (Uniformat); Material: 00_PBT_MAT_beton t.p.g.
Pset_ProductRequirements - Category: Structural Framing
Pset_QuantityTakeOff - Reference: 16_PBT_SF_funderingsbalk:600x1360_bestaand
Pset_ReinforcementBarCountOfIndependentFooting - Description: 600x1360; Reference: 16_PBT_SF_funderingsbalk:600x1360_bestaand; sets with these values: 2
Pset_Pieters - Dragend/niet dragend: yes; Lengte poer: 1530 mm; Breedte: 600 mm; Hoogte: 1360 mm; Bouwlaag: Level: -1 kelder_Offset1000; Naamgeving element: 16_PBT_SF_funderingsbalk: 600x1360_bestaand; Codering - NL-SfB: 16.12; Omschrijving NL-SfB: funderingsconstructies - voeten en balken, fundatie balken; Fase: Bestaand; Materiaal: 00_PBT_MAT_beton t.p.g.; Description: 600x1360
Name (16_PBT_SF_funderingsbalk:600x1360_bestaand:...)
1310882
1311842

# IfcFooting: 16_PBT_SF_funderingsbalk:615x1180_bestaand, 16_PBT_SF_funderingsbalk:615x1180_bestaand:1403564
In: -1 kelder
Type - Classification: 16.12 funderingsconstructies - voeten en balken, fundatie balken (Uniformat); Material: 00_PBT_MAT_beton t.p.g.
Pset_ProductRequirements - Category: Structural Framing
Pset_QuantityTakeOff - Reference: 16_PBT_SF_funderingsbalk:615x1180_bestaand
Pset_ReinforcementBarCountOfIndependentFooting - Description: 615x1180; Reference: 16_PBT_SF_funderingsbalk:615x1180_bestaand; sets with these values: 2
Pset_Pieters - Dragend/niet dragend: yes; Lengte poer: 4604.77 mm; Breedte: 615 mm; Hoogte: 1180 mm; Bouwlaag: Level: -1 kelder_Offset1000; Naamgeving element: 16_PBT_SF_funderingsbalk: 615x1180_bestaand; Codering - NL-SfB: 16.12; Omschrijving NL-SfB: funderingsconstructies - voeten en balken, fundatie balken; Fase: Bestaand; Materiaal: 00_PBT_MAT_beton t.p.g.; Description: 615x1180

# IfcFooting: 16_PBT_SF_funderingsbalk:C30/37_1000x1005, 16_PBT_SF_funderingsbalk:C30/37_1000x1005:3855712
In: 00 begane grond
Type - Classification: 16.12 funderingsconstructies - voeten en balken, fundatie balken (Uniformat); Material: 00_PBT_MAT_beton t.p.g._C30/37
Pset_ProductRequirements - Category: Structural Framing
Pset_QuantityTakeOff - Reference: 16_PBT_SF_funderingsbalk:C30/37_1000x1005
Pset_ReinforcementBarCountOfIndependentFooting - Description: 1000x1005; Reference: 16_PBT_SF_funderingsbalk:C30/37_1000x1005; sets with these values: 2
Pset_Pieters - Lengte poer: 1940.89 mm; Breedte: 1000 mm; Hoogte: 1005 mm; Bouwlaag: Level: 00 begane grond; Naamgeving element: 16_PBT_SF_funderingsbalk: C30/37_1000x1005; Codering - NL-SfB: 16.12; Omschrijving NL-SfB: funderingsconstructies - voeten en balken, fundatie balken; Fase: Nieuw; Materiaal: 00_PBT_MAT_beton t.p.g._C30/37; Materiaalkwaliteit: C30/37; Description: 1000x1005

# IfcFooting: 16_PBT_SF_funderingsbalk:C30/37_1000x600 (2)
In: 00 begane grond
Type - Classification: 16.12 funderingsconstructies - voeten en balken, fundatie balken (Uniformat); Material: 00_PBT_MAT_beton t.p.g._C30/37
Pset_ProductRequirements - Category: Structural Framing
Pset_QuantityTakeOff - Reference: 16_PBT_SF_funderingsbalk:C30/37_1000x600
Pset_ReinforcementBarCountOfIndependentFooting - Description: 1000x600; Reference: 16_PBT_SF_funderingsbalk:C30/37_1000x600; sets with these values: 2
Pset_Pieters - Breedte: 1000 mm; Hoogte: 600 mm; Bouwlaag: Level: 00 begane grond; Naamgeving element: 16_PBT_SF_funderingsbalk: C30/37_1000x600; Codering - NL-SfB: 16.12; Omschrijving NL-SfB: funderingsconstructies - voeten en balken, fundatie balken; Fase: Nieuw; Materiaal: 00_PBT_MAT_beton t.p.g._C30/37; Materiaalkwaliteit: C30/37; Description: 1000x600
Name (16_PBT_SF_funderingsbalk:C30/37_1000x600:...) | Lengte poer (mm)
2684996 | 15463.7
3044192 | 22909.7

# IfcFooting: 16_PBT_SF_funderingsbalk:C30/37_1000x740, 16_PBT_SF_funderingsbalk:C30/37_1000x740:2675348
In: 00 begane grond
Type - Classification: 16.12 funderingsconstructies - voeten en balken, fundatie balken (Uniformat); Material: 00_PBT_MAT_beton t.p.g._C30/37
Pset_ProductRequirements - Category: Structural Framing
Pset_QuantityTakeOff - Reference: 16_PBT_SF_funderingsbalk:C30/37_1000x740
Pset_ReinforcementBarCountOfIndependentFooting - Description: 1000x740; Reference: 16_PBT_SF_funderingsbalk:C30/37_1000x740; sets with these values: 2
Pset_Pieters - Lengte poer: 3300 mm; Breedte: 1000 mm; Hoogte: 740 mm; Bouwlaag: Level: 00 begane grond; Naamgeving element: 16_PBT_SF_funderingsbalk: C30/37_1000x740; Codering - NL-SfB: 16.12; Omschrijving NL-SfB: funderingsconstructies - voeten en balken, fundatie balken; Fase: Nieuw; Materiaal: 00_PBT_MAT_beton t.p.g._C30/37; Materiaalkwaliteit: C30/37; Description: 1000x740

# IfcFooting: 16_PBT_SF_funderingsbalk:C30/37_1000x970, 16_PBT_SF_funderingsbalk:C30/37_1000x970:3854422
In: 00 begane grond
Type - Classification: 16.12 funderingsconstructies - voeten en balken, fundatie balken (Uniformat); Material: 00_PBT_MAT_beton t.p.g._C30/37
Pset_ProductRequirements - Category: Structural Framing
Pset_QuantityTakeOff - Reference: 16_PBT_SF_funderingsbalk:C30/37_1000x970
Pset_ReinforcementBarCountOfIndependentFooting - Description: 1000x970; Reference: 16_PBT_SF_funderingsbalk:C30/37_1000x970; sets with these values: 2
Pset_Pieters - Lengte poer: 1895 mm; Breedte: 1000 mm; Hoogte: 970 mm; Bouwlaag: Level: 00 begane grond; Naamgeving element: 16_PBT_SF_funderingsbalk: C30/37_1000x970; Codering - NL-SfB: 16.12; Omschrijving NL-SfB: funderingsconstructies - voeten en balken, fundatie balken; Fase: Nieuw; Materiaal: 00_PBT_MAT_beton t.p.g._C30/37; Materiaalkwaliteit: C30/37; Description: 1000x970

# IfcFooting: 16_PBT_SF_funderingsbalk:C30/37_1200x600, 16_PBT_SF_funderingsbalk:C30/37_1200x600:4452520
In: 00 begane grond
Type - Classification: 16.12 funderingsconstructies - voeten en balken, fundatie balken (Uniformat); Material: 00_PBT_MAT_beton t.p.g._C30/37
Pset_ProductRequirements - Category: Structural Framing
Pset_QuantityTakeOff - Reference: 16_PBT_SF_funderingsbalk:C30/37_1200x600
Pset_ReinforcementBarCountOfIndependentFooting - Description: 1200x600; Reference: 16_PBT_SF_funderingsbalk:C30/37_1200x600; sets with these values: 2
Pset_Pieters - Lengte poer: 1200 mm; Breedte: 1200 mm; Hoogte: 600 mm; Bouwlaag: Level: 00 begane grond; Naamgeving element: 16_PBT_SF_funderingsbalk: C30/37_1200x600; Codering - NL-SfB: 16.12; Omschrijving NL-SfB: funderingsconstructies - voeten en balken, fundatie balken; Fase: Nieuw; Materiaal: 00_PBT_MAT_beton t.p.g._C30/37; Materiaalkwaliteit: C30/37; Description: 1200x600

# IfcFooting: 16_PBT_SF_funderingsbalk:C30/37_300x250_aangestorte nok, 16_PBT_SF_funderingsbalk:C30/37_300x250_aangestorte nok:6085793
In: 00 begane grond
Type - Classification: 16.12 funderingsconstructies - voeten en balken, fundatie balken (Uniformat); Material: 00_PBT_MAT_beton t.p.g._C30/37
Pset_ProductRequirements - Category: Structural Framing
Pset_QuantityTakeOff - Reference: 16_PBT_SF_funderingsbalk:C30/37_300x250_aangestorte nok
Pset_ReinforcementBarCountOfIndependentFooting - Description: aangestorte nok 300x250; Reference: 16_PBT_SF_funderingsbalk:C30/37_300x250_aangestorte nok; sets with these values: 2
Pset_Pieters - Lengte poer: 32700 mm; Breedte: 300 mm; Hoogte: 250 mm; Bouwlaag: Level: 00 begane grond; Naamgeving element: 16_PBT_SF_funderingsbalk: C30/37_300x250_aangestorte nok; Codering - NL-SfB: 16.12; Omschrijving NL-SfB: funderingsconstructies - voeten en balken, fundatie balken; Fase: Nieuw; Materiaal: 00_PBT_MAT_beton t.p.g._C30/37; Materiaalkwaliteit: C30/37; Description: aangestorte nok 300x250; Type Comments: aangestorte nok 300x250

# IfcFooting: 16_PBT_SF_funderingsbalk:C30/37_310x300_aangestorte nok, 16_PBT_SF_funderingsbalk:C30/37_310x300_aangestorte nok:5975052
In: 00 begane grond
Type - Classification: 16.12 funderingsconstructies - voeten en balken, fundatie balken (Uniformat); Material: 00_PBT_MAT_beton t.p.g._C30/37
Pset_ProductRequirements - Category: Structural Framing
Pset_QuantityTakeOff - Reference: 16_PBT_SF_funderingsbalk:C30/37_310x300_aangestorte nok
Pset_ReinforcementBarCountOfIndependentFooting - Description: 310x300; Reference: 16_PBT_SF_funderingsbalk:C30/37_310x300_aangestorte nok; sets with these values: 2
Pset_Pieters - Lengte poer: 3046 mm; Breedte: 310 mm; Hoogte: 300 mm; Bouwlaag: Level: 00 begane grond; Naamgeving element: 16_PBT_SF_funderingsbalk: C30/37_310x300_aangestorte nok; Codering - NL-SfB: 16.12; Omschrijving NL-SfB: funderingsconstructies - voeten en balken, fundatie balken; Fase: Nieuw; Materiaal: 00_PBT_MAT_beton t.p.g._C30/37; Materiaalkwaliteit: C30/37; Description: 310x300; Type Comments: aangestorte nok 310x300

# IfcFooting: 16_PBT_SF_funderingsbalk:C30/37_360x300_aangestorte nok, 16_PBT_SF_funderingsbalk:C30/37_360x300_aangestorte nok:5975441
In: 00 begane grond
Type - Classification: 16.12 funderingsconstructies - voeten en balken, fundatie balken (Uniformat); Material: 00_PBT_MAT_beton t.p.g._C30/37
Pset_ProductRequirements - Category: Structural Framing
Pset_QuantityTakeOff - Reference: 16_PBT_SF_funderingsbalk:C30/37_360x300_aangestorte nok
Pset_ReinforcementBarCountOfIndependentFooting - Description: 360x300; Reference: 16_PBT_SF_funderingsbalk:C30/37_360x300_aangestorte nok; sets with these values: 2
Pset_Pieters - Lengte poer: 3255 mm; Breedte: 360 mm; Hoogte: 300 mm; Bouwlaag: Level: 00 begane grond; Naamgeving element: 16_PBT_SF_funderingsbalk: C30/37_360x300_aangestorte nok; Codering - NL-SfB: 16.12; Omschrijving NL-SfB: funderingsconstructies - voeten en balken, fundatie balken; Fase: Nieuw; Materiaal: 00_PBT_MAT_beton t.p.g._C30/37; Materiaalkwaliteit: C30/37; Description: 360x300; Type Comments: aangestorte nok 360x300

# IfcFooting: 16_PBT_SF_funderingsbalk:C30/37_500x600, 16_PBT_SF_funderingsbalk:C30/37_500x600:2668459
In: 00 begane grond
Type - Classification: 16.12 funderingsconstructies - voeten en balken, fundatie balken (Uniformat); Material: 00_PBT_MAT_beton t.p.g._C30/37
Pset_ProductRequirements - Category: Structural Framing
Pset_QuantityTakeOff - Reference: 16_PBT_SF_funderingsbalk:C30/37_500x600
Pset_ReinforcementBarCountOfIndependentFooting - Description: 500x600; Reference: 16_PBT_SF_funderingsbalk:C30/37_500x600; sets with these values: 2
Pset_Pieters - Lengte poer: 5445 mm; Breedte: 500 mm; Hoogte: 600 mm; Bouwlaag: Level: 00 begane grond; Naamgeving element: 16_PBT_SF_funderingsbalk: C30/37_500x600; Codering - NL-SfB: 16.12; Omschrijving NL-SfB: funderingsconstructies - voeten en balken, fundatie balken; Fase: Nieuw; Materiaal: 00_PBT_MAT_beton t.p.g._C30/37; Materiaalkwaliteit: C30/37; Description: 500x600

# IfcFooting: 16_PBT_SF_funderingsbalk:C30/37_600x600 (4)
In: 00 begane grond
Type - Classification: 16.12 funderingsconstructies - voeten en balken, fundatie balken (Uniformat); Material: 00_PBT_MAT_beton t.p.g._C30/37
Pset_ProductRequirements - Category: Structural Framing
Pset_QuantityTakeOff - Reference: 16_PBT_SF_funderingsbalk:C30/37_600x600
Pset_ReinforcementBarCountOfIndependentFooting - Description: 600x600; Reference: 16_PBT_SF_funderingsbalk:C30/37_600x600; sets with these values: 2
Pset_Pieters - Lengte poer: 5445 mm; Breedte: 600 mm; Hoogte: 600 mm; Bouwlaag: Level: 00 begane grond; Naamgeving element: 16_PBT_SF_funderingsbalk: C30/37_600x600; Codering - NL-SfB: 16.12; Omschrijving NL-SfB: funderingsconstructies - voeten en balken, fundatie balken; Fase: Nieuw; Materiaal: 00_PBT_MAT_beton t.p.g._C30/37; Materiaalkwaliteit: C30/37; Description: 600x600
Name (16_PBT_SF_funderingsbalk:C30/37_600x600:...)
2667824
2667986
3044346
3044359

# IfcFooting: 16_PBT_SF_funderingsbalk:C30/37_700x600 (3)
In: 00 begane grond
Type - Classification: 16.12 funderingsconstructies - voeten en balken, fundatie balken (Uniformat); Material: 00_PBT_MAT_beton t.p.g._C30/37
Pset_ProductRequirements - Category: Structural Framing
Pset_QuantityTakeOff - Reference: 16_PBT_SF_funderingsbalk:C30/37_700x600
Pset_ReinforcementBarCountOfIndependentFooting - Description: 700x600; Reference: 16_PBT_SF_funderingsbalk:C30/37_700x600; sets with these values: 2
Pset_Pieters - Breedte: 700 mm; Hoogte: 600 mm; Bouwlaag: Level: 00 begane grond; Naamgeving element: 16_PBT_SF_funderingsbalk: C30/37_700x600; Codering - NL-SfB: 16.12; Omschrijving NL-SfB: funderingsconstructies - voeten en balken, fundatie balken; Fase: Nieuw; Materiaal: 00_PBT_MAT_beton t.p.g._C30/37; Materiaalkwaliteit: C30/37; Description: 700x600
Name (16_PBT_SF_funderingsbalk:C30/37_700x600:...) | Lengte poer (mm)
2668573 | 2570.32
3855399 | 1711.14
3896595 | 3465

# IfcFooting: 16_PBT_SF_funderingsbalk:C30/37_800x600, 16_PBT_SF_funderingsbalk:C30/37_800x600:2675907
In: 00 begane grond
Type - Classification: 16.12 funderingsconstructies - voeten en balken, fundatie balken (Uniformat); Material: 00_PBT_MAT_beton t.p.g._C30/37
Pset_ProductRequirements - Category: Structural Framing
Pset_QuantityTakeOff - Reference: 16_PBT_SF_funderingsbalk:C30/37_800x600
Pset_ReinforcementBarCountOfIndependentFooting - Description: 800x600; Reference: 16_PBT_SF_funderingsbalk:C30/37_800x600; sets with these values: 2
Pset_Pieters - Lengte poer: 2180 mm; Breedte: 800 mm; Hoogte: 600 mm; Bouwlaag: Level: 00 begane grond; Naamgeving element: 16_PBT_SF_funderingsbalk: C30/37_800x600; Codering - NL-SfB: 16.12; Omschrijving NL-SfB: funderingsconstructies - voeten en balken, fundatie balken; Fase: Nieuw; Materiaal: 00_PBT_MAT_beton t.p.g._C30/37; Materiaalkwaliteit: C30/37; Description: 800x600

# IfcFooting: 16_PBT_SF_funderingsbalk_driehoek:300x300_bestaand (17)
In: -1 kelder
Type - Classification: 16.12 funderingsconstructies - voeten en balken, fundatie balken (Uniformat); Material: 00_PBT_MAT_beton t.p.g.
Pset_ProductRequirements - Category: Structural Framing
Pset_QuantityTakeOff - Reference: 16_PBT_SF_funderingsbalk_driehoek:300x300_bestaand
Pset_ReinforcementBarCountOfIndependentFooting - Description: 600x1360; Reference: 16_PBT_SF_funderingsbalk_driehoek:300x300_bestaand; sets with these values: 2
Pset_Pieters - Dragend/niet dragend: yes; Breedte: 300 mm; Hoogte: 300 mm; Bouwlaag: Level: -1 kelder_Offset1000; Naamgeving element: 16_PBT_SF_funderingsbalk_driehoek: 300x300_bestaand; Codering - NL-SfB: 16.12; Omschrijving NL-SfB: funderingsconstructies - voeten en balken, fundatie balken; Fase: Bestaand; Materiaal: 00_PBT_MAT_beton t.p.g.; Description: 600x1360
Name (16_PBT_SF_funderingsbalk_driehoek:300x300_bestaand:...) | Lengte poer (mm)
1327608 | 6090
1327820 | 6090
1327874 | 2000
1327976 | 6090
1327978 | 6090
1327980 | 2000
1329392 | 3800
1329394 | 3800
1329396 | 2000
1335145 | 4420
1335147 | 6090
1335149 | 2000
1335198 | 6090
1335200 | 4420
1335202 | 2000
1335248 | 2847.14
1335250 | 6790

# IfcFooting: Foundation Slab:16_PBT_FS_beton t.p.g._d=2300_C53/65, Foundation Slab:16_PBT_FS_beton t.p.g._d=2300_C53/65:4426924
In: 00 begane grond
Classification: 16.13 funderingsconstructies - voeten en balken, fundatie poeren (Uniformat); Material: 00_PBT_MAT_beton t.p.g._C53/65
Pset_ElementShading - Roughness: 304.8 mm
Pset_ProductRequirements - Category: Structural Foundations
Pset_QuantityTakeOff - Reference: Foundation Slab:16_PBT_FS_beton t.p.g._d=2300_C53/65
Pset_ReinforcementBarCountOfIndependentFooting - Description: poer d=2300; Reference: Foundation Slab:16_PBT_FS_beton t.p.g._d=2300_C53/65; sets with these values: 2
Pset_Pieters - Lengte poer: 4872 mm; Breedte: 5977.95 mm; Hoogte: 2300 mm; Bouwlaag: Level: 00 begane grond; Naamgeving element: Foundation Slab: 16_PBT_FS_beton t.p.g._d=2300_C53/65; Codering - NL-SfB: 16.13; Omschrijving NL-SfB: funderingsconstructies - voeten en balken, fundatie poeren; Fase: Nieuw; Materiaal: 00_PBT_MAT_beton t.p.g._C53/65; Materiaalkwaliteit: C53/65; Description: poer d=2300; Type Comments: d=2300

# IfcFooting: Foundation Slab:16_PBT_FS_beton t.p.g._poer h=1870_C30/37, Foundation Slab:16_PBT_FS_beton t.p.g._poer h=1870_C30/37:2905390
In: -1 kelder
Classification: 16.13 funderingsconstructies - voeten en balken, fundatie poeren (Uniformat); Material: 00_PBT_MAT_beton t.p.g._C30/37
Pset_ElementShading - Roughness: 304.8 mm
Pset_ProductRequirements - Category: Structural Foundations
Pset_QuantityTakeOff - Reference: Foundation Slab:16_PBT_FS_beton t.p.g._poer h=1870_C30/37
Pset_ReinforcementBarCountOfIndependentFooting - Description: poer h=1870; Reference: Foundation Slab:16_PBT_FS_beton t.p.g._poer h=1870_C30/37; sets with these values: 2
Pset_Pieters - Dragend/niet dragend: yes; Lengte poer: 1350 mm; Breedte: 4867.86 mm; Hoogte: 1870 mm; Bouwlaag: Level: -1 kelder; Naamgeving element: Foundation Slab: 16_PBT_FS_beton t.p.g._poer h=1870_C30/37; Codering - NL-SfB: 16.13; Omschrijving NL-SfB: funderingsconstructies - voeten en balken, fundatie poeren; Fase: Nieuw; Materiaal: 00_PBT_MAT_beton t.p.g._C30/37; Materiaalkwaliteit: C30/37; Description: poer h=1870; Type Comments: poer h=1870

# IfcOpeningElement: Opening (541)
Name | In | Classification | Height (mm) | Width (mm) | Reference | sets with these values | Category
Foundation Slab:13_PBT_FS_beton t.p.g._d=400_bestaand:1323753:2 | -1 kelder | 13.20 vloeren op grondslag - constructief, algemeen (verzamelniveau) (Uniformat) | 2500 | 5785 | Foundation Slab:13_PBT_FS_beton t.p.g._d=400_bestaand | 2 | Structural Foundations | BaseQuantities - Depth: 400 mm; Pset_ElementShading - Roughness: 304.8 mm
Foundation Slab:13_PBT_FS_beton t.p.g._d=400_bestaand:1323753:3 | -1 kelder | 13.20 vloeren op grondslag - constructief, algemeen (verzamelniveau) (Uniformat) | 4200 | 6160.02 | Foundation Slab:13_PBT_FS_beton t.p.g._d=400_bestaand | 2 | Structural Foundations | BaseQuantities - Depth: 400 mm; Pset_ElementShading - Roughness: 304.8 mm
Basic Wall:28_PBT_WA_beton t.p.g._d=250_bestaand:1385873 | -1 kelder | 28.21 hoofddraagconstructies - wanden en vloeren, wand-/vloerconstructies (Uniformat) | 150 | 400 | Basic Wall:28_PBT_WA_beton t.p.g._d=250_bestaand | 2 | <Sketch> | Pset_ElementShading - Roughness: 304.8 mm
Basic Wall:28_PBT_WA_beton t.p.g._d=250_bestaand:1385873 | -1 kelder | 28.21 hoofddraagconstructies - wanden en vloeren, wand-/vloerconstructies (Uniformat) | 2420 | 1800 | Basic Wall:28_PBT_WA_beton t.p.g._d=250_bestaand | 2 | <Sketch> | Pset_ElementShading - Roughness: 304.8 mm
Basic Wall:16_PBT_WA_beton t.p.g._d=250_bestaand:1313619 | -1 kelder | 16.20 funderingsconstructies - keerwanden, algemeen (verzamelniveau) (Uniformat) | 300 | 200 | Basic Wall:16_PBT_WA_beton t.p.g._d=250_bestaand | 2 | <Sketch> | Pset_ElementShading - Roughness: 304.8 mm
Basic Wall:16_PBT_WA_beton t.p.g._d=250_bestaand:1313619 | -1 kelder | 16.20 funderingsconstructies - keerwanden, algemeen (verzamelniveau) (Uniformat) | 338.744 | 200 | Basic Wall:16_PBT_WA_beton t.p.g._d=250_bestaand | 2 | <Sketch> | Pset_ElementShading - Roughness: 304.8 mm
Basic Wall:16_PBT_WA_beton t.p.g._d=250_bestaand:1313619 | -1 kelder | 16.20 funderingsconstructies - keerwanden, algemeen (verzamelniveau) (Uniformat) | 500 | 830 | Basic Wall:16_PBT_WA_beton t.p.g._d=250_bestaand | 2 | <Sketch> | Pset_ElementShading - Roughness: 304.8 mm
Basic Wall:16_PBT_WA_beton t.p.g._d=250_bestaand:1313619 | -1 kelder | 16.20 funderingsconstructies - keerwanden, algemeen (verzamelniveau) (Uniformat) | 1190 | 3061.06 | Basic Wall:16_PBT_WA_beton t.p.g._d=250_bestaand | 2 | <Sketch> | Pset_ElementShading - Roughness: 304.8 mm
2 x Basic Wall:28_PBT_WA_beton t.p.g._d=300_bestaand:250799 | 00 begane grond | 28.21 hoofddraagconstructies - wanden en vloeren, wand-/vloerconstructies (Uniformat) | 2240 | 436.256 | Basic Wall:28_PBT_WA_beton t.p.g._d=300_bestaand | 2 | <Sketch> | Pset_ElementShading - Roughness: 304.8 mm
Basic Wall:28_PBT_WA_beton t.p.g._d=300_bestaand:250799 | 00 begane grond | 28.21 hoofddraagconstructies - wanden en vloeren, wand-/vloerconstructies (Uniformat) | 5978.57 | 2240 | Basic Wall:28_PBT_WA_beton t.p.g._d=300_bestaand | 2 | <Sketch> | Pset_ElementShading - Roughness: 304.8 mm
Foundation Slab:13_PBT_FS_beton t.p.g._d=1300_bestaand:1349133:2 | -2 kelder | 13.20 vloeren op grondslag - constructief, algemeen (verzamelniveau) (Uniformat) |  |  | Foundation Slab:13_PBT_FS_beton t.p.g._d=1300_bestaand | 2 | Structural Foundations | BaseQuantities - Depth: 1300 mm; Area: 82386.1 mm2; Pset_ElementShading - Roughness: 304.8 mm
Foundation Slab:13_PBT_FS_beton t.p.g._d=1300_bestaand:1349133:3 | -2 kelder | 13.20 vloeren op grondslag - constructief, algemeen (verzamelniveau) (Uniformat) |  |  | Foundation Slab:13_PBT_FS_beton t.p.g._d=1300_bestaand | 2 | Structural Foundations | BaseQuantities - Depth: 1300 mm; Area: 82386.1 mm2; Pset_ElementShading - Roughness: 304.8 mm
Foundation Slab:13_PBT_FS_beton t.p.g._d=1300_bestaand:1349133:4 | -2 kelder | 13.20 vloeren op grondslag - constructief, algemeen (verzamelniveau) (Uniformat) |  |  | Foundation Slab:13_PBT_FS_beton t.p.g._d=1300_bestaand | 2 | Structural Foundations | BaseQuantities - Depth: 1300 mm; Area: 82386.1 mm2; Pset_ElementShading - Roughness: 304.8 mm
Foundation Slab:13_PBT_FS_beton t.p.g._d=1300_bestaand:1349133:5 | -2 kelder | 13.20 vloeren op grondslag - constructief, algemeen (verzamelniveau) (Uniformat) |  |  | Foundation Slab:13_PBT_FS_beton t.p.g._d=1300_bestaand | 2 | Structural Foundations | BaseQuantities - Depth: 1300 mm; Area: 82386.1 mm2; Pset_ElementShading - Roughness: 304.8 mm
Basic Wall:16_PBT_WA_beton t.p.g._d=250_bestaand:1313619 | -1 kelder | 16.20 funderingsconstructies - keerwanden, algemeen (verzamelniveau) (Uniformat) | 1870 | 828.289 | Basic Wall:16_PBT_WA_beton t.p.g._d=250_bestaand | 2 | <Sketch> | Pset_ElementShading - Roughness: 304.8 mm
Basic Wall:16_PBT_WA_beton t.p.g._d=250_bestaand:1313619 | -1 kelder | 16.20 funderingsconstructies - keerwanden, algemeen (verzamelniveau) (Uniformat) | 1236.44 | 2000 | Basic Wall:16_PBT_WA_beton t.p.g._d=250_bestaand | 2 | <Sketch> | Pset_ElementShading - Roughness: 304.8 mm
Basic Wall:28_PBT_WA_beton t.p.g._d=300_bestaand:1358617 | -1 kelder | 28.21 hoofddraagconstructies - wanden en vloeren, wand-/vloerconstructies (Uniformat) | 2040 | 2980 | Generic Models 9:Generic Models 9 | 2 | Generic Models | BaseQuantities - Depth: 1410 mm
Basic Wall:28_PBT_WA_beton t.p.g._d=300_bestaand:1358617 | -1 kelder | 28.21 hoofddraagconstructies - wanden en vloeren, wand-/vloerconstructies (Uniformat) | 250 | 250 | Generic Models 10:Generic Models 10 | 2 | Generic Models | BaseQuantities - Depth: 1000 mm
Basic Wall:16_PBT_WA_beton t.p.g._d=300_bestaand:1331339 | -1 kelder | 16.20 funderingsconstructies - keerwanden, algemeen (verzamelniveau) (Uniformat) |  |  | Basic Wall:16_PBT_WA_beton t.p.g._d=300_bestaand | 2 | <Sketch> | Pset_ElementShading - Roughness: 304.8 mm; BaseQuantities - Area: 753999 mm2
Basic Wall:16_PBT_WA_beton t.p.g._d=250_bestaand:1313619 | -1 kelder | 16.20 funderingsconstructies - keerwanden, algemeen (verzamelniveau) (Uniformat) | 1390 | 3629.11 | Basic Wall:16_PBT_WA_beton t.p.g._d=250_bestaand | 2 | <Sketch> | Pset_ElementShading - Roughness: 304.8 mm
Basic Wall:16_PBT_WA_beton t.p.g._d=500_bestaand:6075902 | -1 kelder | 16.20 funderingsconstructies - keerwanden, algemeen (verzamelniveau) (Uniformat) | 736.102 | 150 | Basic Wall:16_PBT_WA_beton t.p.g._d=500_bestaand | 2 | <Sketch> | Pset_ElementShading - Roughness: 304.8 mm
Basic Wall:28_PBT_WA_beton t.p.g._d=500_bestaand:1384460 | -1 kelder | 28.21 hoofddraagconstructies - wanden en vloeren, wand-/vloerconstructies (Uniformat) | 200 | 100 | 00_PBT_GM_WB_rechthoek_wandsparing:100x200 | 2 | Generic Models | BaseQuantities - Depth: 500 mm
2 x Basic Wall:28_PBT_WA_beton t.p.g._d=500_bestaand:1384160 | -1 kelder | 28.21 hoofddraagconstructies - wanden en vloeren, wand-/vloerconstructies (Uniformat) | 400 | 300 | Basic Wall:28_PBT_WA_beton t.p.g._d=500_bestaand | 2 | <Sketch> | Pset_ElementShading - Roughness: 304.8 mm
Basic Wall:28_PBT_WA_beton t.p.g._d=500_bestaand:1384160 | -1 kelder | 28.21 hoofddraagconstructies - wanden en vloeren, wand-/vloerconstructies (Uniformat) | 290 | 300 | Basic Wall:28_PBT_WA_beton t.p.g._d=500_bestaand | 2 | <Sketch> | Pset_ElementShading - Roughness: 304.8 mm
3 x Basic Wall:28_PBT_WA_beton t.p.g._d=500_bestaand:1384160 | -1 kelder | 28.21 hoofddraagconstructies - wanden en vloeren, wand-/vloerconstructies (Uniformat) | 700 | 400 | Basic Wall:28_PBT_WA_beton t.p.g._d=500_bestaand | 2 | <Sketch> | Pset_ElementShading - Roughness: 304.8 mm
Basic Wall:28_PBT_WA_beton t.p.g._d=500_bestaand:1384160 | -1 kelder | 28.21 hoofddraagconstructies - wanden en vloeren, wand-/vloerconstructies (Uniformat) | 556.3 | 200 | Basic Wall:28_PBT_WA_beton t.p.g._d=500_bestaand | 2 | <Sketch> | Pset_ElementShading - Roughness: 304.8 mm
Basic Wall:28_PBT_WA_beton t.p.g._d=500_bestaand:1384160 | -1 kelder | 28.21 hoofddraagconstructies - wanden en vloeren, wand-/vloerconstructies (Uniformat) | 1054.01 | 2310 | Basic Wall:28_PBT_WA_beton t.p.g._d=500_bestaand | 2 | <Sketch> | Pset_ElementShading - Roughness: 304.8 mm
Basic Wall:28_PBT_WA_beton t.p.g._d=500_bestaand:1384160 | -1 kelder | 28.21 hoofddraagconstructies - wanden en vloeren, wand-/vloerconstructies (Uniformat) | 1975 | 2310 | Basic Wall:28_PBT_WA_beton t.p.g._d=500_bestaand | 2 | <Sketch> | Pset_ElementShading - Roughness: 304.8 mm
Basic Wall:28_PBT_WA_beton t.p.g._d=500_bestaand:1384160 | -1 kelder | 28.21 hoofddraagconstructies - wanden en vloeren, wand-/vloerconstructies (Uniformat) | 30 | 1950 | Basic Wall:28_PBT_WA_beton t.p.g._d=500_bestaand | 2 | <Sketch> | Pset_ElementShading - Roughness: 304.8 mm
Foundation Slab:13_PBT_FS_beton t.p.g._d=700_bestaand:1391276:2 | -1 kelder | 13.20 vloeren op grondslag - constructief, algemeen (verzamelniveau) (Uniformat) |  |  | Foundation Slab:13_PBT_FS_beton t.p.g._d=700_bestaand | 2 | Structural Foundations | BaseQuantities - Depth: 700 mm; Area: 82386.1 mm2; Pset_ElementShading - Roughness: 304.8 mm
Foundation Slab:13_PBT_FS_beton t.p.g._d=700_bestaand:1391276:3 | -1 kelder | 13.20 vloeren op grondslag - constructief, algemeen (verzamelniveau) (Uniformat) |  |  | Foundation Slab:13_PBT_FS_beton t.p.g._d=700_bestaand | 2 | Structural Foundations | BaseQuantities - Depth: 700 mm; Area: 82386.1 mm2; Pset_ElementShading - Roughness: 304.8 mm
Foundation Slab:13_PBT_FS_beton t.p.g._d=700_bestaand:1391276:4 | -1 kelder | 13.20 vloeren op grondslag - constructief, algemeen (verzamelniveau) (Uniformat) |  |  | Foundation Slab:13_PBT_FS_beton t.p.g._d=700_bestaand | 2 | Structural Foundations | BaseQuantities - Depth: 700 mm; Area: 82386.1 mm2; Pset_ElementShading - Roughness: 304.8 mm
Foundation Slab:13_PBT_FS_beton t.p.g._d=700_bestaand:1391276:5 | -1 kelder | 13.20 vloeren op grondslag - constructief, algemeen (verzamelniveau) (Uniformat) |  |  | Foundation Slab:13_PBT_FS_beton t.p.g._d=700_bestaand | 2 | Structural Foundations | BaseQuantities - Depth: 700 mm; Area: 82386.1 mm2; Pset_ElementShading - Roughness: 304.8 mm
Basic Wall:16_PBT_WA_beton t.p.g._d=650_bestaand:1393206:1 | -2 kelder | 16.20 funderingsconstructies - keerwanden, algemeen (verzamelniveau) (Uniformat) |  |  | Basic Wall:16_PBT_WA_beton t.p.g._d=650_bestaand | 2 | Walls | Pset_ElementShading - Roughness: 304.8 mm
 | -2 kelder
Foundation Slab:13_PBT_FS_beton t.p.g._d=500_bestaand:1401372:2 | -2 kelder | 13.20 vloeren op grondslag - constructief, algemeen (verzamelniveau) (Uniformat) |  |  | Foundation Slab:13_PBT_FS_beton t.p.g._d=500_bestaand | 2 | Structural Foundations | BaseQuantities - Depth: 500 mm; Area: 384829 mm2; Pset_ElementShading - Roughness: 304.8 mm
Basic Wall:28_PBT_WA_beton t.p.g._d=500_bestaand:1384160 | -2 kelder | 28.21 hoofddraagconstructies - wanden en vloeren, wand-/vloerconstructies (Uniformat) | 250 | 680 | Basic Wall:28_PBT_WA_beton t.p.g._d=500_bestaand | 2 | <Sketch> | Pset_ElementShading - Roughness: 304.8 mm
Basic Wall:28_PBT_WA_beton t.p.g._d=300_bestaand:250799 | -2 kelder | 28.21 hoofddraagconstructies - wanden en vloeren, wand-/vloerconstructies (Uniformat) |  |  | Basic Wall:28_PBT_WA_beton t.p.g._d=300_bestaand | 2 | <Sketch> | Pset_ElementShading - Roughness: 304.8 mm; BaseQuantities - Area: 1763736 mm2
Basic Wall:28_PBT_WA_beton t.p.g._d=300_bestaand:250799 | -2 kelder | 28.21 hoofddraagconstructies - wanden en vloeren, wand-/vloerconstructies (Uniformat) | 2480 | 400 | Basic Wall:28_PBT_WA_beton t.p.g._d=300_bestaand | 2 | <Sketch> | Pset_ElementShading - Roughness: 304.8 mm
Basic Wall:28_PBT_WA_beton t.p.g._d=300_bestaand:250799 | 00 begane grond | 28.21 hoofddraagconstructies - wanden en vloeren, wand-/vloerconstructies (Uniformat) | 5778.57 | 2240 | Basic Wall:28_PBT_WA_beton t.p.g._d=300_bestaand | 2 | <Sketch> | Pset_ElementShading - Roughness: 304.8 mm
Basic Wall:28_PBT_WA_beton t.p.g._d=300_bestaand:1482732 | 00 begane grond | 28.21 hoofddraagconstructies - wanden en vloeren, wand-/vloerconstructies (Uniformat) | 900 | 609.353 | Generic Models 17:Generic Models 17 | 2 | Generic Models | BaseQuantities - Depth: 300 mm
Basic Wall:28_PBT_WA_beton t.p.g._d=300_bestaand:250799 | 00 begane grond | 28.21 hoofddraagconstructies - wanden en vloeren, wand-/vloerconstructies (Uniformat) | 150 | 150 | Basic Wall:28_PBT_WA_beton t.p.g._d=300_bestaand | 2 | <Sketch> | Pset_ElementShading - Roughness: 304.8 mm
2 x Basic Wall:28_PBT_WA_beton t.p.g._d=400_bestaand:6076206 | 01 eerste verdieping | 28.21 hoofddraagconstructies - wanden en vloeren, wand-/vloerconstructies (Uniformat) | 2050 | 950 | Basic Wall:28_PBT_WA_beton t.p.g._d=400_bestaand | 2 | <Sketch> | Pset_ElementShading - Roughness: 304.8 mm
Basic Wall:28_PBT_WA_beton t.p.g._d=400_bestaand:6076206 | 01 eerste verdieping | 28.21 hoofddraagconstructies - wanden en vloeren, wand-/vloerconstructies (Uniformat) | 2524.66 | 3090 | Basic Wall:28_PBT_WA_beton t.p.g._d=400_bestaand | 2 | <Sketch> | Pset_ElementShading - Roughness: 304.8 mm
Basic Wall:28_PBT_WA_beton t.p.g._d=400_bestaand:6076206 | 01 eerste verdieping | 28.21 hoofddraagconstructies - wanden en vloeren, wand-/vloerconstructies (Uniformat) | 2517.08 | 2800 | Basic Wall:28_PBT_WA_beton t.p.g._d=400_bestaand | 2 | <Sketch> | Pset_ElementShading - Roughness: 304.8 mm
Basic Wall:28_PBT_WA_beton t.p.g._d=300_bestaand:250799 | 01 eerste verdieping | 28.21 hoofddraagconstructies - wanden en vloeren, wand-/vloerconstructies (Uniformat) | 5978.57 | 2580 | Basic Wall:28_PBT_WA_beton t.p.g._d=300_bestaand | 2 | <Sketch> | Pset_ElementShading - Roughness: 304.8 mm
Basic Wall:28_PBT_WA_beton t.p.g._d=300_bestaand:250799 | 01 eerste verdieping | 28.21 hoofddraagconstructies - wanden en vloeren, wand-/vloerconstructies (Uniformat) | 650 | 706.256 | Basic Wall:28_PBT_WA_beton t.p.g._d=300_bestaand | 2 | <Sketch> | Pset_ElementShading - Roughness: 304.8 mm
Basic Wall:28_PBT_WA_beton t.p.g._d=300_bestaand:250799 | 01 eerste verdieping | 28.21 hoofddraagconstructies - wanden en vloeren, wand-/vloerconstructies (Uniformat) | 5778.57 | 2580 | Basic Wall:28_PBT_WA_beton t.p.g._d=300_bestaand | 2 | <Sketch> | Pset_ElementShading - Roughness: 304.8 mm
Basic Wall:28_PBT_WA_beton t.p.g._d=300_bestaand:1610111 | 03 derde verdieping | 28.21 hoofddraagconstructies - wanden en vloeren, wand-/vloerconstructies (Uniformat) |  |  | 28_PBT_SF_betonwand_rond_hoofdzaal:betonwand_rond_hoofdzaal | 2 | Generic Models
Basic Wall:28_PBT_WA_beton t.p.g._d=300_bestaand:1610111 | 03 derde verdieping | 28.21 hoofddraagconstructies - wanden en vloeren, wand-/vloerconstructies (Uniformat) |  |  | 28_PBT_SF_betonwand_rond_hoofdzaal_ok sponning:betonwand_rond_hoofdzaal_ok sponning | 2 | Generic Models | BaseQuantities - Depth: 11978.3 mm; Area: 20590165 mm2
Basic Wall:28_PBT_WA_beton t.p.g._d=300_bestaand:1610111 | 03 derde verdieping | 28.21 hoofddraagconstructies - wanden en vloeren, wand-/vloerconstructies (Uniformat) |  |  | void te slopen dakrand rond:void te slopen dakrand rond | 2 | Generic Models | BaseQuantities - Depth: 30000 mm; Area: 43906412 mm2
2 x Basic Wall:28_PBT_WA_beton t.p.g._d=400_bestaand:6076206 | 01 eerste verdieping | 28.21 hoofddraagconstructies - wanden en vloeren, wand-/vloerconstructies (Uniformat) | 950 | 2050 | Basic Wall:28_PBT_WA_beton t.p.g._d=400_bestaand | 2 | <Sketch> | Pset_ElementShading - Roughness: 304.8 mm
Basic Wall:28_PBT_WA_beton t.p.g._d=400_bestaand:6076206 | 01 eerste verdieping | 28.21 hoofddraagconstructies - wanden en vloeren, wand-/vloerconstructies (Uniformat) | 2530.98 | 3090 | Basic Wall:28_PBT_WA_beton t.p.g._d=400_bestaand | 2 | <Sketch> | Pset_ElementShading - Roughness: 304.8 mm
Basic Wall:28_PBT_WA_beton t.p.g._d=400_bestaand:6076206 | 01 eerste verdieping | 28.21 hoofddraagconstructies - wanden en vloeren, wand-/vloerconstructies (Uniformat) | 2535.82 | 2800 | Basic Wall:28_PBT_WA_beton t.p.g._d=400_bestaand | 2 | <Sketch> | Pset_ElementShading - Roughness: 304.8 mm
Basic Wall:28_PBT_WA_beton t.p.g._d=300_bestaand:250799 | 02 tweede verdieping | 28.21 hoofddraagconstructies - wanden en vloeren, wand-/vloerconstructies (Uniformat) | 1050.2 | 3150 | Basic Wall:28_PBT_WA_beton t.p.g._d=300_bestaand | 2 | <Sketch> | Pset_ElementShading - Roughness: 304.8 mm
Basic Wall:28_PBT_WA_beton t.p.g._d=300_bestaand:250799 | 02 tweede verdieping | 28.21 hoofddraagconstructies - wanden en vloeren, wand-/vloerconstructies (Uniformat) | 5950 | 2580 | Basic Wall:28_PBT_WA_beton t.p.g._d=300_bestaand | 2 | <Sketch> | Pset_ElementShading - Roughness: 304.8 mm
Basic Wall:28_PBT_WA_beton t.p.g._d=300_C30/37:1968197 | -1 kelder | 28.21 hoofddraagconstructies - wanden en vloeren, wand-/vloerconstructies (Uniformat) | 1500 | 2490 | 00_PBT_GM_WB_rechthoek_wandsparing:1500x2490 | 2 | Generic Models | BaseQuantities - Depth: 300 mm
Basic Wall:28_PBT_WA_beton t.p.g._d=500_C30/37:1990746 | -2 kelder | 28.21 hoofddraagconstructies - wanden en vloeren, wand-/vloerconstructies (Uniformat) | 2000 | 30 | Basic Wall:28_PBT_WA_beton t.p.g._d=500_C30/37 | 2 | <Sketch> | Pset_ElementShading - Roughness: 304.8 mm
Basic Wall:28_PBT_WA_beton t.p.g._d=500_C30/37:1990746 | -2 kelder | 28.21 hoofddraagconstructies - wanden en vloeren, wand-/vloerconstructies (Uniformat) | 30 | 100 | Basic Wall:28_PBT_WA_beton t.p.g._d=500_C30/37 | 2 | <Sketch> | Pset_ElementShading - Roughness: 304.8 mm
Basic Wall:16_PBT_WA_beton t.p.g._d=250_C30/37:1992390 | 00 begane grond | 16.20 funderingsconstructies - keerwanden, algemeen (verzamelniveau) (Uniformat) | 5600 | 4550 | 00_PBT_GM_WB_rechthoek_wandsparing:5600x4550 | 2 | Generic Models | BaseQuantities - Depth: 250 mm
Basic Wall:16_PBT_WA_beton t.p.g._d=250_C30/37:1992390 | 00 begane grond | 16.20 funderingsconstructies - keerwanden, algemeen (verzamelniveau) (Uniformat) | 2460 | 1934 | 00_PBT_GM_WB_rechthoek_wandsparing:1934x2460 | 2 | Generic Models | BaseQuantities - Depth: 250 mm
3 x Basic Wall:16_PBT_WA_beton t.p.g._d=250_C30/37:1992390 | 00 begane grond | 16.20 funderingsconstructies - keerwanden, algemeen (verzamelniveau) (Uniformat) | 1210 | 2620 | 00_PBT_GM_WB_rechthoek_wandsparing:1210x2620 | 2 | Generic Models | BaseQuantities - Depth: 250 mm
Basic Wall:28_PBT_WA_beton t.p.g._d=300_C30/37:1997690 | -2 kelder | 28.21 hoofddraagconstructies - wanden en vloeren, wand-/vloerconstructies (Uniformat) | 2420 | 1975 | 00_PBT_GM_WB_rechthoek_wandsparing:1975x2420_D | 2 | Generic Models | BaseQuantities - Depth: 300 mm
Basic Wall:28_PBT_WA_beton t.p.g._d=300_C30/37:2000485 | 00 begane grond | 28.21 hoofddraagconstructies - wanden en vloeren, wand-/vloerconstructies (Uniformat) | 1500 | 2540 | 00_PBT_GM_WB_rechthoek_wandsparing:1500x2540 | 2 | Generic Models | BaseQuantities - Depth: 300 mm
Basic Wall:28_PBT_WA_beton t.p.g._d=300_C30/37:2000485 | 00 begane grond | 28.21 hoofddraagconstructies - wanden en vloeren, wand-/vloerconstructies (Uniformat) | 1500 | 2450 | 00_PBT_GM_WB_rechthoek_wandsparing:1500x2450 | 2 | Generic Models | BaseQuantities - Depth: 300 mm
Basic Wall:28_PBT_WA_beton t.p.g._d=250_C30/37:2001829 | 00 begane grond | 28.21 hoofddraagconstructies - wanden en vloeren, wand-/vloerconstructies (Uniformat) | 1810 | 2370 | 00_PBT_GM_WB_rechthoek_wandsparing:1810x2370 | 2 | Generic Models | BaseQuantities - Depth: 250 mm
Basic Wall:28_PBT_WA_beton t.p.g._d=250_C30/37:2002079 | 00 begane grond | 28.21 hoofddraagconstructies - wanden en vloeren, wand-/vloerconstructies (Uniformat) | 1934 | 2460 | 00_PBT_GM_WB_rechthoek_wandsparing:1934x2460 | 2 | Generic Models | BaseQuantities - Depth: 250 mm
3 x Basic Wall:28_PBT_WA_beton t.p.g._d=250_C30/37:2002079 | 00 begane grond | 28.21 hoofddraagconstructies - wanden en vloeren, wand-/vloerconstructies (Uniformat) | 2620 | 1210 | 00_PBT_GM_WB_rechthoek_wandsparing:1210x2620 | 2 | Generic Models | BaseQuantities - Depth: 250 mm
Basic Wall:28_PBT_WA_beton t.p.g._d=250_C30/37:2002079 | 00 begane grond | 28.21 hoofddraagconstructies - wanden en vloeren, wand-/vloerconstructies (Uniformat) | 4550 | 5600 | 00_PBT_GM_WB_rechthoek_wandsparing:5600x4550 | 2 | Generic Models | BaseQuantities - Depth: 250 mm
Basic Wall:28_PBT_WA_beton t.p.g._d=300_C53/65:2004647 | 00 begane grond | 28.21 hoofddraagconstructies - wanden en vloeren, wand-/vloerconstructies (Uniformat) | 2510 | 1054 | 00_PBT_GM_WB_rechthoek_wandsparing:1054x2510_D | 2 | Generic Models | BaseQuantities - Depth: 300 mm
Basic Wall:28_PBT_WA_beton t.p.g._d=300_C53/65:2004647 | 00 begane grond | 28.21 hoofddraagconstructies - wanden en vloeren, wand-/vloerconstructies (Uniformat) | 2420 | 1354 | 00_PBT_GM_WB_rechthoek_wandsparing:1354x2420_D | 2 | Generic Models | BaseQuantities - Depth: 300 mm
Basic Wall:28_PBT_WA_beton t.p.g._d=200_C30/37:2004943 | 00 begane grond | 28.21 hoofddraagconstructies - wanden en vloeren, wand-/vloerconstructies (Uniformat) | 100 | 300 | Basic Wall:28_PBT_WA_beton t.p.g._d=200_C30/37 | 2 | <Sketch> | Pset_ElementShading - Roughness: 304.8 mm
Basic Wall:28_PBT_WA_beton t.p.g._d=200_C30/37:2004943 | 00 begane grond | 28.21 hoofddraagconstructies - wanden en vloeren, wand-/vloerconstructies (Uniformat) | 300 | 177.923 | Basic Wall:28_PBT_WA_beton t.p.g._d=200_C30/37 | 2 | <Sketch> | Pset_ElementShading - Roughness: 304.8 mm
Basic Wall:28_PBT_WA_beton t.p.g._d=600_C30/37:2006640:1 | 00 begane grond | 28.21 hoofddraagconstructies - wanden en vloeren, wand-/vloerconstructies (Uniformat) | 600 | 1332.57 | Basic Wall:28_PBT_WA_beton t.p.g._d=600_C30/37 | 2 | Walls | BaseQuantities - Depth: 3060 mm; Pset_ElementShading - Roughness: 304.8 mm
Basic Wall:28_PBT_WA_beton t.p.g._d=600_C30/37:2006640:2 | 00 begane grond | 28.21 hoofddraagconstructies - wanden en vloeren, wand-/vloerconstructies (Uniformat) | 600 | 1332.57 | Basic Wall:28_PBT_WA_beton t.p.g._d=600_C30/37 | 2 | Walls | BaseQuantities - Depth: 3060 mm; Pset_ElementShading - Roughness: 304.8 mm
Basic Wall:28_PBT_WA_beton t.p.g._d=600_C30/37:2006640:3 | 00 begane grond | 28.21 hoofddraagconstructies - wanden en vloeren, wand-/vloerconstructies (Uniformat) | 600 | 1332.57 | Basic Wall:28_PBT_WA_beton t.p.g._d=600_C30/37 | 2 | Walls | BaseQuantities - Depth: 3060 mm; Pset_ElementShading - Roughness: 304.8 mm
Basic Wall:28_PBT_WA_beton t.p.g._d=300_C30/37:2008810 | 01 eerste verdieping | 28.21 hoofddraagconstructies - wanden en vloeren, wand-/vloerconstructies (Uniformat) | 1500 | 2450 | 00_PBT_GM_WB_rechthoek_wandsparing:1500x2450 | 2 | Generic Models | BaseQuantities - Depth: 300 mm
Basic Wall:28_PBT_WA_beton t.p.g._d=300_C30/37:2008810 | 01 eerste verdieping | 28.21 hoofddraagconstructies - wanden en vloeren, wand-/vloerconstructies (Uniformat) | 1900 | 2450 | 00_PBT_GM_WB_rechthoek_wandsparing:1900x2450 | 2 | Generic Models | BaseQuantities - Depth: 300 mm
Basic Wall:28_PBT_WA_beton t.p.g._d=250_C30/37:2008815 | 01 eerste verdieping | 28.21 hoofddraagconstructies - wanden en vloeren, wand-/vloerconstructies (Uniformat) | 3200 | 2000 | 00_PBT_GM_WB_rechthoek_wandsparing:2000x3200 | 2 | Generic Models | BaseQuantities - Depth: 250 mm
Basic Wall:28_PBT_WA_beton t.p.g._d=250_C30/37:2008817 | 01 eerste verdieping | 28.21 hoofddraagconstructies - wanden en vloeren, wand-/vloerconstructies (Uniformat) | 2200 | 3725 | 00_PBT_GM_WB_rechthoek_wandsparing:3725x2200 | 2 | Generic Models | BaseQuantities - Depth: 250 mm
2 x Basic Wall:28_PBT_WA_beton t.p.g._d=250_C30/37:2008817 | 01 eerste verdieping | 28.21 hoofddraagconstructies - wanden en vloeren, wand-/vloerconstructies (Uniformat) | 680 | 2000 | 00_PBT_GM_WB_rechthoek_wandsparing:680x2000 | 2 | Generic Models | BaseQuantities - Depth: 250 mm
3 x Basic Wall:28_PBT_WA_beton t.p.g._d=250_C30/37:2008817 | 01 eerste verdieping | 28.21 hoofddraagconstructies - wanden en vloeren, wand-/vloerconstructies (Uniformat) | 660 | 2000 | 00_PBT_GM_WB_rechthoek_wandsparing:660x2000 | 2 | Generic Models | BaseQuantities - Depth: 250 mm
2 x Basic Wall:28_PBT_WA_beton t.p.g._d=300_C30/37:2015662 | 01 eerste verdieping | 28.21 hoofddraagconstructies - wanden en vloeren, wand-/vloerconstructies (Uniformat) | 2420 | 2470 | 00_PBT_GM_WB_rechthoek_wandsparing:2470x2420_D | 2 | Generic Models | BaseQuantities - Depth: 300 mm
Basic Wall:28_PBT_WA_beton t.p.g._d=300_C30/37:2015662 | 01 eerste verdieping | 28.21 hoofddraagconstructies - wanden en vloeren, wand-/vloerconstructies (Uniformat) | 150 | 500 | 00_PBT_GM_WB_rechthoek_wandsparing:500x150 | 2 | Generic Models | BaseQuantities - Depth: 300 mm
Basic Wall:28_PBT_WA_beton t.p.g._d=300_C30/37:2015662 | 01 eerste verdieping | 28.21 hoofddraagconstructies - wanden en vloeren, wand-/vloerconstructies (Uniformat) | 150 | 800 | 00_PBT_GM_WB_rechthoek_wandsparing:800x150 | 2 | Generic Models | BaseQuantities - Depth: 300 mm
54 x  | 01 eerste verdieping
3 x Basic Wall:28_PBT_WA_beton t.p.g._d=300_C30/37:2019479 | 01 eerste verdieping | 28.21 hoofddraagconstructies - wanden en vloeren, wand-/vloerconstructies (Uniformat) | 1054 | 2420 | 00_PBT_GM_WB_rechthoek_wandsparing:1054x2420_D | 2 | Generic Models | BaseQuantities - Depth: 300 mm
Basic Wall:28_PBT_WA_beton t.p.g._d=300_C30/37:2019479 | 01 eerste verdieping | 28.21 hoofddraagconstructies - wanden en vloeren, wand-/vloerconstructies (Uniformat) | 3760 | 250 | 00_PBT_GM_WB_rechthoek_wandsparing:1100x3760 | 2 | Generic Models | BaseQuantities - Depth: 1100 mm
Basic Wall:28_PBT_WA_beton t.p.g._d=300_C30/37:2019479 | 01 eerste verdieping | 28.21 hoofddraagconstructies - wanden en vloeren, wand-/vloerconstructies (Uniformat) | 4834 | 3850 | 00_PBT_GM_WB_rechthoek_wandsparing:4834x3850 | 2 | Generic Models | BaseQuantities - Depth: 300 mm
2 x Basic Wall:28_PBT_WA_beton t.p.g._d=300_C30/37:2019479 | 01 eerste verdieping | 28.21 hoofddraagconstructies - wanden en vloeren, wand-/vloerconstructies (Uniformat) | 450 | 150 | 00_PBT_GM_WB_rechthoek_wandsparing:450x150 | 2 | Generic Models | BaseQuantities - Depth: 300 mm
Basic Wall:28_PBT_WA_beton t.p.g._d=300_C30/37:2025487 | 02 tweede verdieping | 28.21 hoofddraagconstructies - wanden en vloeren, wand-/vloerconstructies (Uniformat) | 1900 | 2450 | 00_PBT_GM_WB_rechthoek_wandsparing:1900x2450 | 2 | Generic Models | BaseQuantities - Depth: 300 mm
Basic Wall:28_PBT_WA_beton t.p.g._d=250_C30/37:2025494 | 02 tweede verdieping | 28.21 hoofddraagconstructies - wanden en vloeren, wand-/vloerconstructies (Uniformat) | 2200 | 3725 | 00_PBT_GM_WB_rechthoek_wandsparing:3725x2200 | 2 | Generic Models | BaseQuantities - Depth: 250 mm
Basic Wall:28_PBT_WA_beton t.p.g._d=250_C30/37:2025496 | 02 tweede verdieping | 28.21 hoofddraagconstructies - wanden en vloeren, wand-/vloerconstructies (Uniformat) | 460 | 1250 | 00_PBT_GM_WB_rechthoek_wandsparing:460x1250 | 2 | Generic Models | BaseQuantities - Depth: 250 mm
3 x Basic Wall:28_PBT_WA_beton t.p.g._d=250_C30/37:2025496 | 02 tweede verdieping | 28.21 hoofddraagconstructies - wanden en vloeren, wand-/vloerconstructies (Uniformat) | 570 | 1250 | 00_PBT_GM_WB_rechthoek_wandsparing:570x1250 | 2 | Generic Models | BaseQuantities - Depth: 250 mm
Basic Wall:28_PBT_WA_beton t.p.g._d=250_C30/37:2025496 | 02 tweede verdieping | 28.21 hoofddraagconstructies - wanden en vloeren, wand-/vloerconstructies (Uniformat) | 512 | 1250 | 00_PBT_GM_WB_rechthoek_wandsparing:512x1250 | 2 | Generic Models | BaseQuantities - Depth: 250 mm
Basic Wall:28_PBT_WA_beton t.p.g._d=250_C30/37:2025496 | 02 tweede verdieping | 28.21 hoofddraagconstructies - wanden en vloeren, wand-/vloerconstructies (Uniformat) | 591 | 1250 | 00_PBT_GM_WB_rechthoek_wandsparing:591x1250 | 2 | Generic Models | BaseQuantities - Depth: 250 mm
4 x Basic Wall:28_PBT_WA_beton t.p.g._d=250_C30/37:2025496 | 02 tweede verdieping | 28.21 hoofddraagconstructies - wanden en vloeren, wand-/vloerconstructies (Uniformat) | 680 | 1250 | 00_PBT_GM_WB_rechthoek_wandsparing:680x1250 | 2 | Generic Models | BaseQuantities - Depth: 250 mm
2 x Basic Wall:28_PBT_WA_beton t.p.g._d=250_C30/37:2025498 | 02 tweede verdieping | 28.21 hoofddraagconstructies - wanden en vloeren, wand-/vloerconstructies (Uniformat) | 2980 | 680 | 00_PBT_GM_WB_rechthoek_wandsparing:680x2980 | 2 | Generic Models | BaseQuantities - Depth: 250 mm
4 x Basic Wall:28_PBT_WA_beton t.p.g._d=250_C30/37:2025498 | 02 tweede verdieping | 28.21 hoofddraagconstructies - wanden en vloeren, wand-/vloerconstructies (Uniformat) | 2980 | 570 | 00_PBT_GM_WB_rechthoek_wandsparing:570x2980 | 2 | Generic Models | BaseQuantities - Depth: 250 mm
Basic Wall:28_PBT_WA_beton t.p.g._d=600_C30/37:2025504 | 02 tweede verdieping | 28.21 hoofddraagconstructies - wanden en vloeren, wand-/vloerconstructies (Uniformat) | 6134 | 5180 | 00_PBT_GM_WB_rechthoek_wandsparing:6134x5180 | 2 | Generic Models | BaseQuantities - Depth: 600 mm
Basic Wall:28_PBT_WA_beton t.p.g._d=600_C30/37:2025504 | 02 tweede verdieping | 28.21 hoofddraagconstructies - wanden en vloeren, wand-/vloerconstructies (Uniformat) | 2500 | 1975 | 00_PBT_GM_WB_rechthoek_wandsparing:1975x2500_D | 2 | Generic Models | BaseQuantities - Depth: 600 mm
Basic Wall:28_PBT_WA_beton t.p.g._d=600_C30/37:2025504 | 02 tweede verdieping | 28.21 hoofddraagconstructies - wanden en vloeren, wand-/vloerconstructies (Uniformat) | 450 | 150 | 00_PBT_GM_WB_rechthoek_wandsparing:450x150 | 2 | Generic Models | BaseQuantities - Depth: 600 mm
Basic Wall:28_PBT_WA_beton t.p.g._d=300_C30/37:2025523 | 02 tweede verdieping | 28.21 hoofddraagconstructies - wanden en vloeren, wand-/vloerconstructies (Uniformat) | 1054 | 2420 | 00_PBT_GM_WB_rechthoek_wandsparing:1054x2420_D | 2 | Generic Models | BaseQuantities - Depth: 300 mm
2 x Basic Wall:28_PBT_WA_beton t.p.g._d=300_C30/37:2025523 | 02 tweede verdieping | 28.21 hoofddraagconstructies - wanden en vloeren, wand-/vloerconstructies (Uniformat) | 450 | 150 | 00_PBT_GM_WB_rechthoek_wandsparing:450x150 | 2 | Generic Models | BaseQuantities - Depth: 300 mm
Basic Wall:28_PBT_WA_beton t.p.g._d=300_C30/37:2029650 | 01 eerste verdieping | 28.21 hoofddraagconstructies - wanden en vloeren, wand-/vloerconstructies (Uniformat) | 1975 | 2420 | 00_PBT_GM_WB_rechthoek_wandsparing:1975x2420_D | 2 | Generic Models | BaseQuantities - Depth: 300 mm
Basic Wall:28_PBT_WA_beton t.p.g._d=300_C30/37:1968638 | 02 tweede verdieping | 28.21 hoofddraagconstructies - wanden en vloeren, wand-/vloerconstructies (Uniformat) | 2413 | 1517.06 | Basic Wall:28_PBT_WA_beton t.p.g._d=300_C30/37 | 2 | <Sketch> | Pset_ElementShading - Roughness: 304.8 mm
57 x  | 03 derde verdieping
Basic Wall:28_PBT_WA_beton t.p.g._d=200_C30/37:2067076 | 02 tweede verdieping | 28.21 hoofddraagconstructies - wanden en vloeren, wand-/vloerconstructies (Uniformat) | 450 | 150 | 00_PBT_GM_WB_rechthoek_wandsparing:450x150 | 2 | Generic Models | BaseQuantities - Depth: 200 mm
Basic Wall:28_PBT_WA_beton t.p.g._d=200_C30/37:2004943 | 02 tweede verdieping | 28.21 hoofddraagconstructies - wanden en vloeren, wand-/vloerconstructies (Uniformat) | 1119.91 | 260 | Basic Wall:28_PBT_WA_beton t.p.g._d=200_C30/37 | 2 | <Sketch> | Pset_ElementShading - Roughness: 304.8 mm
Basic Wall:28_PBT_WA_beton t.p.g._d=350_C53/65:3551954 | -1 kelder | 28.21 hoofddraagconstructies - wanden en vloeren, wand-/vloerconstructies (Uniformat) |  |  | Basic Wall:28_PBT_WA_beton t.p.g._d=350_C53/65 | 2 | <Sketch> | Pset_ElementShading - Roughness: 304.8 mm; BaseQuantities - Area: 4451683 mm2
Basic Wall:28_PBT_WA_beton t.p.g._d=250_C30/37:2089234 | -1 kelder | 28.21 hoofddraagconstructies - wanden en vloeren, wand-/vloerconstructies (Uniformat) | 2490 | 2200 | 00_PBT_GM_WB_rechthoek_wandsparing:2200x2490 | 2 | Generic Models | BaseQuantities - Depth: 250 mm
Basic Wall:28_PBT_WA_beton t.p.g._d=250_C30/37:2089565 | 00 begane grond | 28.21 hoofddraagconstructies - wanden en vloeren, wand-/vloerconstructies (Uniformat) | 2200 | 2470 | 00_PBT_GM_WB_rechthoek_wandsparing:2200x2470 | 2 | Generic Models | BaseQuantities - Depth: 250 mm
Basic Wall:16_PBT_WA_beton t.p.g._d=250_C30/37:2092035 | -1 kelder | 16.20 funderingsconstructies - keerwanden, algemeen (verzamelniveau) (Uniformat) | 2600 | 250 | 00_PBT_GM_WB_rechthoek_wandsparing:995x2600 | 2 | Generic Models | BaseQuantities - Depth: 995 mm
Basic Wall:16_PBT_WA_beton t.p.g._d=250_C30/37:1993292 | -1 kelder | 16.20 funderingsconstructies - keerwanden, algemeen (verzamelniveau) (Uniformat) | 3538.5 | 970 | Basic Wall:16_PBT_WA_beton t.p.g._d=250_C30/37 | 2 | <Sketch> | Pset_ElementShading - Roughness: 304.8 mm
2 x Basic Wall:28_PBT_WA_beton t.p.g._d=350_C53/65:2092394 | 00 begane grond | 28.21 hoofddraagconstructies - wanden en vloeren, wand-/vloerconstructies (Uniformat) | 3010 | 2200 | 00_PBT_GM_WB_rechthoek_wandsparing:2200x3010 | 2 | Generic Models | BaseQuantities - Depth: 350 mm
2 x Basic Wall:28_PBT_WA_beton t.p.g._d=350_C53/65:2092394 | 00 begane grond | 28.21 hoofddraagconstructies - wanden en vloeren, wand-/vloerconstructies (Uniformat) | 2765 | 790 | 00_PBT_GM_WB_rechthoek_wandsparing:790x2765 | 2 | Generic Models | BaseQuantities - Depth: 350 mm
Basic Wall:28_PBT_WA_beton t.p.g._d=350_C53/65:2092394 | 00 begane grond | 28.21 hoofddraagconstructies - wanden en vloeren, wand-/vloerconstructies (Uniformat) | 2460 | 1200 | 00_PBT_GM_WB_rechthoek_wandsparing:1200x2460 | 2 | Generic Models | BaseQuantities - Depth: 350 mm
Basic Wall:28_PBT_WA_beton t.p.g._d=350_C53/65:2092394 | 00 begane grond | 28.21 hoofddraagconstructies - wanden en vloeren, wand-/vloerconstructies (Uniformat) | 2460 | 250 | 00_PBT_GM_WB_rechthoek_wandsparing:1934x2460 | 2 | Generic Models | BaseQuantities - Depth: 1934 mm
Basic Wall:28_PBT_WA_beton t.p.g._d=350_C53/65:2092394 | 00 begane grond | 28.21 hoofddraagconstructies - wanden en vloeren, wand-/vloerconstructies (Uniformat) | 2540 | 1580 | 00_PBT_GM_WB_rechthoek_wandsparing:1580x2540 | 2 | Generic Models | BaseQuantities - Depth: 350 mm
Basic Wall:28_PBT_WA_beton t.p.g._d=350_C53/65:2092394 | 00 begane grond | 28.21 hoofddraagconstructies - wanden en vloeren, wand-/vloerconstructies (Uniformat) | 2500 | 1054 | 00_PBT_GM_WB_rechthoek_wandsparing:1054x2500_D | 2 | Generic Models | BaseQuantities - Depth: 350 mm
Basic Wall:28_PBT_WA_beton t.p.g._d=250_C30/37:2095896 | 00 begane grond | 28.21 hoofddraagconstructies - wanden en vloeren, wand-/vloerconstructies (Uniformat) | 600 | 925 | 00_PBT_GM_WB_rechthoek_wandsparing:925x600 | 2 | Generic Models | BaseQuantities - Depth: 250 mm
Basic Wall:28_PBT_WA_beton t.p.g._d=200_C30/37:2097008 | 00 begane grond | 28.21 hoofddraagconstructies - wanden en vloeren, wand-/vloerconstructies (Uniformat) | 2620 | 1580 | 00_PBT_GM_WB_rechthoek_wandsparing:1580x2620 | 2 | Generic Models | BaseQuantities - Depth: 200 mm
Basic Wall:28_PBT_WA_beton t.p.g._d=350_C30/37:2097595 | 00 begane grond | 28.21 hoofddraagconstructies - wanden en vloeren, wand-/vloerconstructies (Uniformat) | 2590 | 2225 | 00_PBT_GM_WB_rechthoek_wandsparing:2225x2590_D | 2 | Generic Models | BaseQuantities - Depth: 350 mm
Basic Wall:28_PBT_WA_beton t.p.g._d=350_C30/37:2102046 | 01 eerste verdieping | 28.21 hoofddraagconstructies - wanden en vloeren, wand-/vloerconstructies (Uniformat) | 2530 | 1580 | 00_PBT_GM_WB_rechthoek_wandsparing:1580x2530 | 2 | Generic Models | BaseQuantities - Depth: 350 mm
2 x Basic Wall:28_PBT_WA_beton t.p.g._d=350_C30/37:2102046 | 01 eerste verdieping | 28.21 hoofddraagconstructies - wanden en vloeren, wand-/vloerconstructies (Uniformat) | 2500 | 1054 | 00_PBT_GM_WB_rechthoek_wandsparing:1054x2500_D | 2 | Generic Models | BaseQuantities - Depth: 350 mm
Basic Wall:28_PBT_WA_beton t.p.g._d=350_C30/37:2102046 | 01 eerste verdieping | 28.21 hoofddraagconstructies - wanden en vloeren, wand-/vloerconstructies (Uniformat) | 2590 | 1900 | 00_PBT_GM_WB_rechthoek_wandsparing:1900x2590_D | 2 | Generic Models | BaseQuantities - Depth: 350 mm
Basic Wall:28_PBT_WA_beton t.p.g._d=350_C30/37:2102046 | 01 eerste verdieping | 28.21 hoofddraagconstructies - wanden en vloeren, wand-/vloerconstructies (Uniformat) | 150 | 300 | 00_PBT_GM_WB_rechthoek_wandsparing:300x150 | 2 | Generic Models | BaseQuantities - Depth: 350 mm
Basic Wall:28_PBT_WA_beton t.p.g._d=200_C30/37:2102064 | 01 eerste verdieping | 28.21 hoofddraagconstructies - wanden en vloeren, wand-/vloerconstructies (Uniformat) | 1580 | 2300 | 00_PBT_GM_WB_rechthoek_wandsparing:1580x2300 | 2 | Generic Models | BaseQuantities - Depth: 200 mm
Basic Wall:28_PBT_WA_beton t.p.g._d=250_C30/37:2103321 | 02 tweede verdieping | 28.21 hoofddraagconstructies - wanden en vloeren, wand-/vloerconstructies (Uniformat) | 954 | 2220 | 00_PBT_GM_WB_rechthoek_wandsparing:954x2220 | 2 | Generic Models | BaseQuantities - Depth: 250 mm
Basic Wall:28_PBT_WA_beton t.p.g._d=350_C30/37:2103333 | 02 tweede verdieping | 28.21 hoofddraagconstructies - wanden en vloeren, wand-/vloerconstructies (Uniformat) | 2500 | 1054 | 00_PBT_GM_WB_rechthoek_wandsparing:1054x2500_D | 2 | Generic Models | BaseQuantities - Depth: 350 mm
2 x Basic Wall:28_PBT_WA_beton t.p.g._d=350_C30/37:2103333 | 02 tweede verdieping | 28.21 hoofddraagconstructies - wanden en vloeren, wand-/vloerconstructies (Uniformat) | 2530 | 1580 | 00_PBT_GM_WB_rechthoek_wandsparing:1580x2530 | 2 | Generic Models | BaseQuantities - Depth: 350 mm
Basic Wall:28_PBT_WA_beton t.p.g._d=350_C30/37:2103333 | 02 tweede verdieping | 28.21 hoofddraagconstructies - wanden en vloeren, wand-/vloerconstructies (Uniformat) | 2420 | 1254 | 00_PBT_GM_WB_rechthoek_wandsparing:1254x2420_D | 2 | Generic Models | BaseQuantities - Depth: 350 mm
2 x Basic Wall:28_PBT_WA_beton t.p.g._d=350_C30/37:2103333 | 02 tweede verdieping | 28.21 hoofddraagconstructies - wanden en vloeren, wand-/vloerconstructies (Uniformat) | 130 | 400 | 00_PBT_GM_WB_rechthoek_wandsparing:400x130 | 2 | Generic Models | BaseQuantities - Depth: 350 mm
Basic Wall:28_PBT_WA_beton t.p.g._d=350_C30/37:2103333 | 02 tweede verdieping | 28.21 hoofddraagconstructies - wanden en vloeren, wand-/vloerconstructies (Uniformat) | 2590 | 1900 | 00_PBT_GM_WB_rechthoek_wandsparing:1900x2590_D | 2 | Generic Models | BaseQuantities - Depth: 350 mm
Basic Wall:28_PBT_WA_beton t.p.g._d=350_C30/37:2103333 | 02 tweede verdieping | 28.21 hoofddraagconstructies - wanden en vloeren, wand-/vloerconstructies (Uniformat) | 150 | 400 | 00_PBT_GM_WB_rechthoek_wandsparing:400x150 | 2 | Generic Models | BaseQuantities - Depth: 350 mm
Basic Wall:28_PBT_WA_beton t.p.g._d=350_C30/37:2103333 | 02 tweede verdieping | 28.21 hoofddraagconstructies - wanden en vloeren, wand-/vloerconstructies (Uniformat) | 150 | 300 | 00_PBT_GM_WB_rechthoek_wandsparing:300x150 | 2 | Generic Models | BaseQuantities - Depth: 350 mm
Basic Wall:28_PBT_WA_beton t.p.g._d=200_C30/37:2103338 | 02 tweede verdieping | 28.21 hoofddraagconstructies - wanden en vloeren, wand-/vloerconstructies (Uniformat) | 2300 | 1580 | 00_PBT_GM_WB_rechthoek_wandsparing:1580x2300 | 2 | Generic Models | BaseQuantities - Depth: 200 mm
Basic Wall:28_PBT_WA_beton t.p.g._d=350_C30/37:2103354 | 02 tweede verdieping | 28.21 hoofddraagconstructies - wanden en vloeren, wand-/vloerconstructies (Uniformat) | 2420 | 1054 | 00_PBT_GM_WB_rechthoek_wandsparing:1054x2420_D | 2 | Generic Models | BaseQuantities - Depth: 350 mm
Basic Wall:28_PBT_WA_beton t.p.g._d=500_C30/37:2129158 | -1 kelder | 28.21 hoofddraagconstructies - wanden en vloeren, wand-/vloerconstructies (Uniformat) | 2780 | 1100 | 00_PBT_GM_WB_rechthoek_wandsparing:1100x2780 | 2 | Generic Models | BaseQuantities - Depth: 500 mm
Basic Wall:28_PBT_WA_beton t.p.g._d=500_C30/37:2129158 | -1 kelder | 28.21 hoofddraagconstructies - wanden en vloeren, wand-/vloerconstructies (Uniformat) | 200 | 100 | 00_PBT_GM_WB_rechthoek_wandsparing:100x200 | 2 | Generic Models | BaseQuantities - Depth: 500 mm
Basic Wall:28_PBT_WA_beton t.p.g._d=500_C30/37:2129158 | -1 kelder | 28.21 hoofddraagconstructies - wanden en vloeren, wand-/vloerconstructies (Uniformat) | 200 | 750 | 00_PBT_GM_WB_rechthoek_wandsparing:750x200 | 2 | Generic Models | BaseQuantities - Depth: 500 mm
Basic Wall:16_PBT_WA_beton t.p.g._d=350_C53/65:2133111 | -1 kelder | 16.20 funderingsconstructies - keerwanden, algemeen (verzamelniveau) (Uniformat) | 450 | 740 | 00_PBT_GM_WB_rechthoek_wandsparing:740x450 | 2 | Generic Models | BaseQuantities - Depth: 350 mm
2 x Basic Wall:28_PBT_WA_beton t.p.g._d=300_C30/37:1968638 | 00 begane grond | 28.21 hoofddraagconstructies - wanden en vloeren, wand-/vloerconstructies (Uniformat) | 1820 | 436.256 | Basic Wall:28_PBT_WA_beton t.p.g._d=300_C30/37 | 2 | <Sketch> | Pset_ElementShading - Roughness: 304.8 mm
Basic Wall:28_PBT_WA_beton t.p.g._d=300_C30/37:1968638 | 00 begane grond | 28.21 hoofddraagconstructies - wanden en vloeren, wand-/vloerconstructies (Uniformat) | 400 | 2216.5 | Basic Wall:28_PBT_WA_beton t.p.g._d=300_C30/37 | 2 | <Sketch> | Pset_ElementShading - Roughness: 304.8 mm
Basic Wall:28_PBT_WA_beton t.p.g._d=250_C30/37:2155519 | 03 derde verdieping | 28.21 hoofddraagconstructies - wanden en vloeren, wand-/vloerconstructies (Uniformat) | 954 | 2220 | 00_PBT_GM_WB_rechthoek_wandsparing:954x2220 | 2 | Generic Models | BaseQuantities - Depth: 250 mm
Basic Wall:28_PBT_WA_beton t.p.g._d=350_C30/37:2155521 | 03 derde verdieping | 28.21 hoofddraagconstructies - wanden en vloeren, wand-/vloerconstructies (Uniformat) | 2450 | 1980 | 00_PBT_GM_WB_rechthoek_wandsparing:1980x2450 | 2 | Generic Models | BaseQuantities - Depth: 350 mm
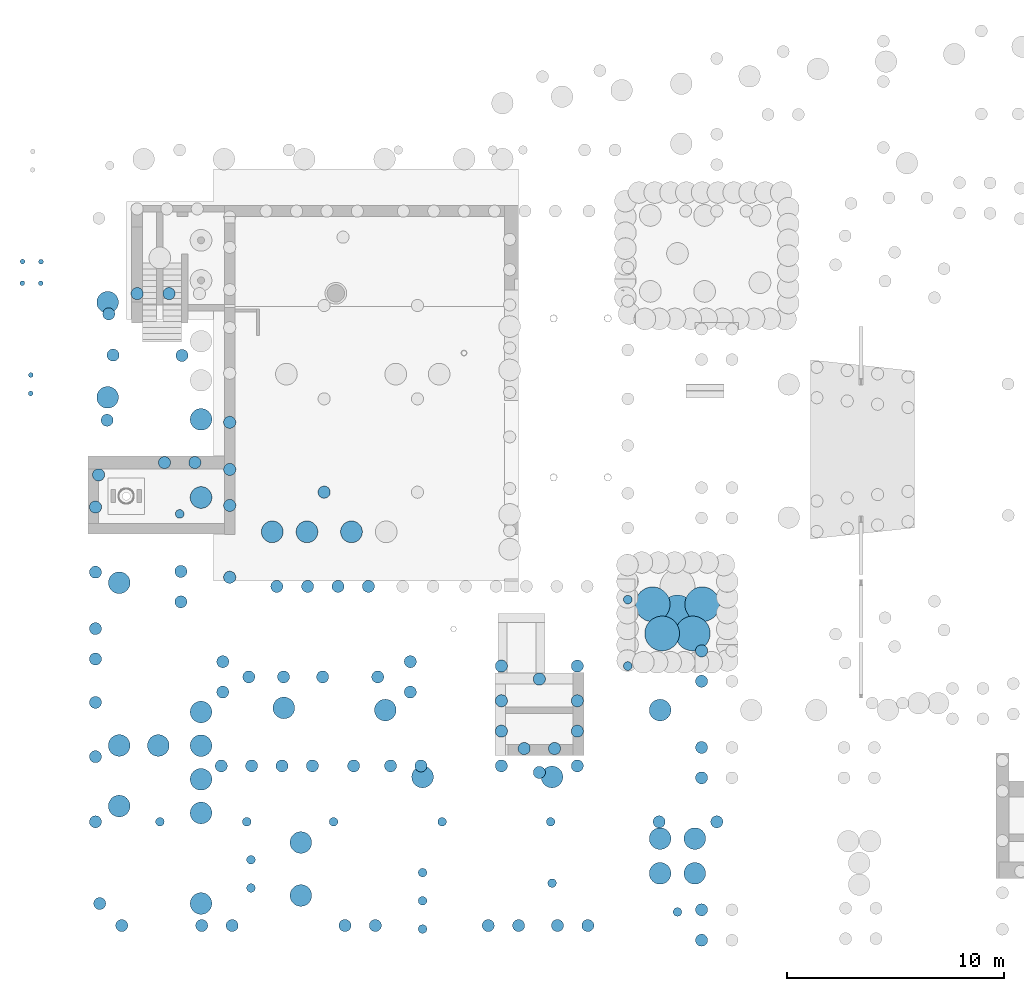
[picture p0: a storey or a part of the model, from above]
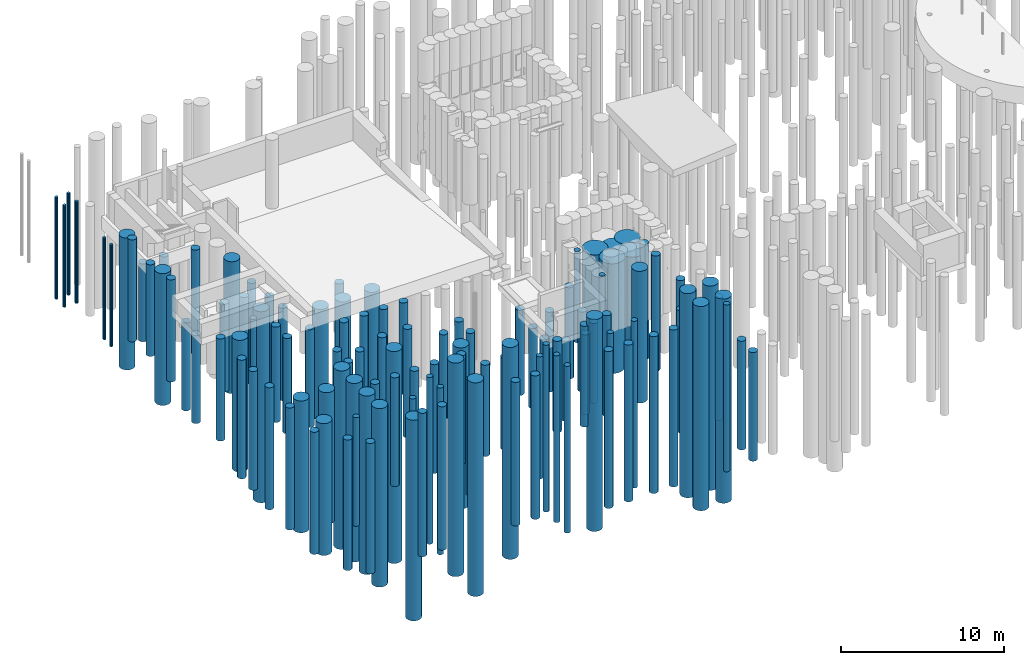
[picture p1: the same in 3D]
Properties of the parts of a building model (IFC2X3), part 12 of 18

# IfcOpeningElement: Opening (541)
Name | In | Classification | Height (mm) | Width (mm) | Reference | sets with these values | Category
Basic Wall:28_PBT_WA_beton t.p.g._d=350_C30/37:2155521 | 03 derde verdieping | 28.21 hoofddraagconstructies - wanden en vloeren, wand-/vloerconstructies (Uniformat) | 2420 | 1254 | 00_PBT_GM_WB_rechthoek_wandsparing:1254x2420_D | 2 | Generic Models | BaseQuantities - Depth: 350 mm
Basic Wall:28_PBT_WA_beton t.p.g._d=350_C30/37:2155521 | 03 derde verdieping | 28.21 hoofddraagconstructies - wanden en vloeren, wand-/vloerconstructies (Uniformat) | 2530 | 1580 | 00_PBT_GM_WB_rechthoek_wandsparing:1580x2530 | 2 | Generic Models | BaseQuantities - Depth: 350 mm
Basic Wall:28_PBT_WA_beton t.p.g._d=350_C30/37:2155521 | 03 derde verdieping | 28.21 hoofddraagconstructies - wanden en vloeren, wand-/vloerconstructies (Uniformat) | 2420 | 1054 | 00_PBT_GM_WB_rechthoek_wandsparing:1054x2420_D | 2 | Generic Models | BaseQuantities - Depth: 350 mm
Basic Wall:28_PBT_WA_beton t.p.g._d=350_C30/37:1365168 | 03 derde verdieping | 28.21 hoofddraagconstructies - wanden en vloeren, wand-/vloerconstructies (Uniformat) | 3125 | 20510 | Basic Wall:28_PBT_WA_beton t.p.g._d=350_C30/37 | 2 | <Sketch> | Pset_ElementShading - Roughness: 304.8 mm
Basic Wall:28_PBT_WA_beton t.p.g._d=200_C30/37:2155526 | 03 derde verdieping | 28.21 hoofddraagconstructies - wanden en vloeren, wand-/vloerconstructies (Uniformat) | 2450 | 1580 | 00_PBT_GM_WB_rechthoek_wandsparing:1580x2450 | 2 | Generic Models | BaseQuantities - Depth: 200 mm
Basic Wall:28_PBT_WA_beton t.p.g._d=300_C30/37:1968638 | 03 derde verdieping | 28.21 hoofddraagconstructies - wanden en vloeren, wand-/vloerconstructies (Uniformat) | 1246.26 | 3575 | Basic Wall:28_PBT_WA_beton t.p.g._d=300_C30/37 | 2 | <Sketch> | Pset_ElementShading - Roughness: 304.8 mm
Basic Wall:28_PBT_WA_beton t.p.g._d=350_C30/37:2158144 | 04 vierde verdieping | 28.21 hoofddraagconstructies - wanden en vloeren, wand-/vloerconstructies (Uniformat) | 2450 | 1980 | 00_PBT_GM_WB_rechthoek_wandsparing:1980x2450 | 2 | Generic Models | BaseQuantities - Depth: 350 mm
Basic Wall:28_PBT_WA_beton t.p.g._d=350_C30/37:2158144 | 04 vierde verdieping | 28.21 hoofddraagconstructies - wanden en vloeren, wand-/vloerconstructies (Uniformat) | 2420 | 1054 | 00_PBT_GM_WB_rechthoek_wandsparing:1054x2420_D | 2 | Generic Models | BaseQuantities - Depth: 350 mm
Basic Wall:28_PBT_WA_beton t.p.g._d=350_C30/37:2158144 | 04 vierde verdieping | 28.21 hoofddraagconstructies - wanden en vloeren, wand-/vloerconstructies (Uniformat) | 2460 | 250 | 00_PBT_GM_WB_rechthoek_wandsparing:1034x2460 | 2 | Generic Models | BaseQuantities - Depth: 1034 mm
Basic Wall:28_PBT_WA_beton t.p.g._d=350_C30/37:2158146 | 04 vierde verdieping | 28.21 hoofddraagconstructies - wanden en vloeren, wand-/vloerconstructies (Uniformat) | 2460 | 250 | 00_PBT_GM_WB_rechthoek_wandsparing:1034x2460 | 2 | Generic Models | BaseQuantities - Depth: 1034 mm
Basic Wall:28_PBT_WA_beton t.p.g._d=350_C30/37:2158146 | 04 vierde verdieping | 28.21 hoofddraagconstructies - wanden en vloeren, wand-/vloerconstructies (Uniformat) | 2450 | 1980 | 00_PBT_GM_WB_rechthoek_wandsparing:1980x2450 | 2 | Generic Models | BaseQuantities - Depth: 350 mm
Basic Wall:28_PBT_WA_beton t.p.g._d=350_C30/37:2158146 | 04 vierde verdieping | 28.21 hoofddraagconstructies - wanden en vloeren, wand-/vloerconstructies (Uniformat) | 2420 | 1054 | 00_PBT_GM_WB_rechthoek_wandsparing:1054x2420_D | 2 | Generic Models | BaseQuantities - Depth: 350 mm
Basic Wall:28_PBT_WA_beton t.p.g._d=200_C30/37:2158148:1 | 04 vierde verdieping | 28.21 hoofddraagconstructies - wanden en vloeren, wand-/vloerconstructies (Uniformat) |  |  | Basic Wall:28_PBT_WA_beton t.p.g._d=200_C30/37 | 2 | Walls | Pset_ElementShading - Roughness: 304.8 mm
Basic Wall:28_PBT_WA_beton t.p.g._d=350_C30/37:2158156 | 04 vierde verdieping | 28.21 hoofddraagconstructies - wanden en vloeren, wand-/vloerconstructies (Uniformat) | 2420 | 1054 | 00_PBT_GM_WB_rechthoek_wandsparing:1054x2420_D | 2 | Generic Models | BaseQuantities - Depth: 350 mm
Basic Wall:28_PBT_WA_beton t.p.g._d=400_C30/37:2200104:1 | 01 eerste verdieping | 28.21 hoofddraagconstructies - wanden en vloeren, wand-/vloerconstructies (Uniformat) |  |  | Basic Wall:28_PBT_WA_beton t.p.g._d=400_C30/37 | 2 | Walls | Pset_ElementShading - Roughness: 304.8 mm
Basic Wall:28_PBT_WA_beton t.p.g._d=250_C30/37:2203248 | 05 vijfde verdieping | 28.21 hoofddraagconstructies - wanden en vloeren, wand-/vloerconstructies (Uniformat) | 1034 | 2460 | 00_PBT_GM_WB_rechthoek_wandsparing:1034x2460 | 2 | Generic Models | BaseQuantities - Depth: 250 mm
8 x  | 05 vijfde verdieping
70 x  | 04 vierde verdieping
Basic Wall:28_PBT_WA_beton t.p.g._d=250_C30/37:2208992 | 03 derde verdieping | 28.21 hoofddraagconstructies - wanden en vloeren, wand-/vloerconstructies (Uniformat) | 2780 | 570 | 00_PBT_GM_WB_rechthoek_wandsparing:570x2780 | 2 | Generic Models | BaseQuantities - Depth: 250 mm
2 x Basic Wall:28_PBT_WA_beton t.p.g._d=250_C30/37:2208992 | 03 derde verdieping | 28.21 hoofddraagconstructies - wanden en vloeren, wand-/vloerconstructies (Uniformat) | 2780 | 680 | 00_PBT_GM_WB_rechthoek_wandsparing:680x2780 | 2 | Generic Models | BaseQuantities - Depth: 250 mm
Basic Wall:28_PBT_WA_beton t.p.g._d=250_C30/37:1974447 | 03 derde verdieping | 28.21 hoofddraagconstructies - wanden en vloeren, wand-/vloerconstructies (Uniformat) | 4230.56 | 1155 | Basic Wall:28_PBT_WA_beton t.p.g._d=250_C30/37 | 2 | <Sketch> | Pset_ElementShading - Roughness: 304.8 mm
Basic Wall:28_PBT_WA_beton t.p.g._d=350_C30/37:2238051 | -1 kelder | 28.21 hoofddraagconstructies - wanden en vloeren, wand-/vloerconstructies (Uniformat) | 2450 | 1054 | 00_PBT_GM_WB_rechthoek_wandsparing:1054x2450_D | 2 | Generic Models | BaseQuantities - Depth: 350 mm
2 x Basic Wall:16_PBT_WA_beton t.p.g._d=300_C30/37:1993529 | -1 kelder | 16.20 funderingsconstructies - keerwanden, algemeen (verzamelniveau) (Uniformat) | 30 | 560 | Basic Wall:16_PBT_WA_beton t.p.g._d=300_C30/37 | 2 | <Sketch> | Pset_ElementShading - Roughness: 304.8 mm
Basic Wall:16_PBT_WA_beton t.p.g._d=300_C30/37:1993529 | -1 kelder | 16.20 funderingsconstructies - keerwanden, algemeen (verzamelniveau) (Uniformat) | 30 | 365 | Basic Wall:16_PBT_WA_beton t.p.g._d=300_C30/37 | 2 | <Sketch> | Pset_ElementShading - Roughness: 304.8 mm
Basic Wall:16_PBT_WA_beton t.p.g._d=300_C30/37:1993529 | -1 kelder | 16.20 funderingsconstructies - keerwanden, algemeen (verzamelniveau) (Uniformat) | 365 | 20 | Basic Wall:16_PBT_WA_beton t.p.g._d=300_C30/37 | 2 | <Sketch> | Pset_ElementShading - Roughness: 304.8 mm
2 x Basic Wall:16_PBT_WA_beton t.p.g._d=300_C30/37:1993529 | -1 kelder | 16.20 funderingsconstructies - keerwanden, algemeen (verzamelniveau) (Uniformat) | 20 | 560 | Basic Wall:16_PBT_WA_beton t.p.g._d=300_C30/37 | 2 | <Sketch> | Pset_ElementShading - Roughness: 304.8 mm
Basic Wall:16_PBT_WA_beton t.p.g._d=300_C30/37:1993529 | -1 kelder | 16.20 funderingsconstructies - keerwanden, algemeen (verzamelniveau) (Uniformat) | 20 | 565 | Basic Wall:16_PBT_WA_beton t.p.g._d=300_C30/37 | 2 | <Sketch> | Pset_ElementShading - Roughness: 304.8 mm
Basic Wall:16_PBT_WA_beton t.p.g._d=300_C30/37:1993529 | -1 kelder | 16.20 funderingsconstructies - keerwanden, algemeen (verzamelniveau) (Uniformat) | 565 | 30 | Basic Wall:16_PBT_WA_beton t.p.g._d=300_C30/37 | 2 | <Sketch> | Pset_ElementShading - Roughness: 304.8 mm
Basic Wall:28_PBT_WA_beton t.p.g._d=150_C30/37:2327895 | 02 tweede verdieping | 28.21 hoofddraagconstructies - wanden en vloeren, wand-/vloerconstructies (Uniformat) | 930 | 700 | 00_PBT_GM_WB_rechthoek_wandsparing:700x930 | 2 | Generic Models | BaseQuantities - Depth: 150 mm
Basic Wall:28_PBT_WA_beton t.p.g._d=150_C30/37:2327895 | 02 tweede verdieping | 28.21 hoofddraagconstructies - wanden en vloeren, wand-/vloerconstructies (Uniformat) | 150 | 450 | 00_PBT_GM_WB_rechthoek_wandsparing:450x150 | 2 | Generic Models | BaseQuantities - Depth: 150 mm
Basic Wall:28_PBT_WA_beton t.p.g._d=150_C30/37:2327895 | 02 tweede verdieping | 28.21 hoofddraagconstructies - wanden en vloeren, wand-/vloerconstructies (Uniformat) | 700 | 930 | 00_PBT_GM_WB_rechthoek_wandsparing:700x930 | 2 | Generic Models | BaseQuantities - Depth: 150 mm
Basic Wall:28_PBT_WA_beton t.p.g._d=150_C30/37:2327895 | 02 tweede verdieping | 28.21 hoofddraagconstructies - wanden en vloeren, wand-/vloerconstructies (Uniformat) | 450 | 150 | 00_PBT_GM_WB_rechthoek_wandsparing:450x150 | 2 | Generic Models | BaseQuantities - Depth: 150 mm
2 x Basic Wall:28_PBT_WA_beton t.p.g._d=150_C30/37:2327895 | 02 tweede verdieping | 28.21 hoofddraagconstructies - wanden en vloeren, wand-/vloerconstructies (Uniformat) | 400 | 400 | 00_PBT_GM_WB_rechthoek_wandsparing:400x400 | 2 | Generic Models | BaseQuantities - Depth: 150 mm
Basic Wall:28_PBT_WA_beton t.p.g._d=150_C30/37:2327897 | 02 tweede verdieping | 28.21 hoofddraagconstructies - wanden en vloeren, wand-/vloerconstructies (Uniformat) | 700 | 930 | 00_PBT_GM_WB_rechthoek_wandsparing:700x930 | 2 | Generic Models | BaseQuantities - Depth: 150 mm
Basic Wall:28_PBT_WA_beton t.p.g._d=150_C30/37:2327897 | 02 tweede verdieping | 28.21 hoofddraagconstructies - wanden en vloeren, wand-/vloerconstructies (Uniformat) | 450 | 150 | 00_PBT_GM_WB_rechthoek_wandsparing:450x150 | 2 | Generic Models | BaseQuantities - Depth: 150 mm
Basic Wall:28_PBT_WA_beton t.p.g._d=150_C30/37:2327897 | 02 tweede verdieping | 28.21 hoofddraagconstructies - wanden en vloeren, wand-/vloerconstructies (Uniformat) | 400 | 400 | 00_PBT_GM_WB_rechthoek_wandsparing:400x400 | 2 | Generic Models | BaseQuantities - Depth: 150 mm
Basic Wall:28_PBT_WA_beton t.p.g._d=150_C30/37:2327897 | 02 tweede verdieping | 28.21 hoofddraagconstructies - wanden en vloeren, wand-/vloerconstructies (Uniformat) | 930 | 700 | 00_PBT_GM_WB_rechthoek_wandsparing:700x930 | 2 | Generic Models | BaseQuantities - Depth: 150 mm
Basic Wall:28_PBT_WA_beton t.p.g._d=150_C30/37:2327897 | 02 tweede verdieping | 28.21 hoofddraagconstructies - wanden en vloeren, wand-/vloerconstructies (Uniformat) | 150 | 450 | 00_PBT_GM_WB_rechthoek_wandsparing:450x150 | 2 | Generic Models | BaseQuantities - Depth: 150 mm
Basic Wall:28_PBT_WA_beton t.p.g._d=150_C30/37:2328659 | 02 tweede verdieping | 28.21 hoofddraagconstructies - wanden en vloeren, wand-/vloerconstructies (Uniformat) | 150 | 450 | 00_PBT_GM_WB_rechthoek_wandsparing:450x150 | 2 | Generic Models | BaseQuantities - Depth: 150 mm
Basic Wall:28_PBT_WA_beton t.p.g._d=150_C30/37:2328659 | 02 tweede verdieping | 28.21 hoofddraagconstructies - wanden en vloeren, wand-/vloerconstructies (Uniformat) | 450 | 150 | 00_PBT_GM_WB_rechthoek_wandsparing:450x150 | 2 | Generic Models | BaseQuantities - Depth: 150 mm
2 x Basic Wall:28_PBT_WA_beton t.p.g._d=150_C30/37:2328659 | 02 tweede verdieping | 28.21 hoofddraagconstructies - wanden en vloeren, wand-/vloerconstructies (Uniformat) | 400 | 400 | 00_PBT_GM_WB_rechthoek_wandsparing:400x400 | 2 | Generic Models | BaseQuantities - Depth: 150 mm
Basic Wall:28_PBT_WA_beton t.p.g._d=150_C30/37:2328661 | 02 tweede verdieping | 28.21 hoofddraagconstructies - wanden en vloeren, wand-/vloerconstructies (Uniformat) | 450 | 150 | 00_PBT_GM_WB_rechthoek_wandsparing:450x150 | 2 | Generic Models | BaseQuantities - Depth: 150 mm
Basic Wall:28_PBT_WA_beton t.p.g._d=150_C30/37:2328661 | 02 tweede verdieping | 28.21 hoofddraagconstructies - wanden en vloeren, wand-/vloerconstructies (Uniformat) | 150 | 450 | 00_PBT_GM_WB_rechthoek_wandsparing:450x150 | 2 | Generic Models | BaseQuantities - Depth: 150 mm
2 x Basic Wall:28_PBT_WA_beton t.p.g._d=150_C30/37:2328661 | 02 tweede verdieping | 28.21 hoofddraagconstructies - wanden en vloeren, wand-/vloerconstructies (Uniformat) | 400 | 400 | 00_PBT_GM_WB_rechthoek_wandsparing:400x400 | 2 | Generic Models | BaseQuantities - Depth: 150 mm
Basic Wall:28_PBT_WA_beton t.p.g._d=150_C30/37:2328663 | 02 tweede verdieping | 28.21 hoofddraagconstructies - wanden en vloeren, wand-/vloerconstructies (Uniformat) | 450 | 150 | 00_PBT_GM_WB_rechthoek_wandsparing:450x150 | 2 | Generic Models | BaseQuantities - Depth: 150 mm
Basic Wall:28_PBT_WA_beton t.p.g._d=150_C30/37:2328663 | 02 tweede verdieping | 28.21 hoofddraagconstructies - wanden en vloeren, wand-/vloerconstructies (Uniformat) | 150 | 450 | 00_PBT_GM_WB_rechthoek_wandsparing:450x150 | 2 | Generic Models | BaseQuantities - Depth: 150 mm
2 x Basic Wall:28_PBT_WA_beton t.p.g._d=150_C30/37:2328663 | 02 tweede verdieping | 28.21 hoofddraagconstructies - wanden en vloeren, wand-/vloerconstructies (Uniformat) | 400 | 400 | 00_PBT_GM_WB_rechthoek_wandsparing:400x400 | 2 | Generic Models | BaseQuantities - Depth: 150 mm
Basic Wall:28_PBT_WA_beton t.p.g._d=150_C30/37:2328665 | 02 tweede verdieping | 28.21 hoofddraagconstructies - wanden en vloeren, wand-/vloerconstructies (Uniformat) | 450 | 150 | 00_PBT_GM_WB_rechthoek_wandsparing:450x150 | 2 | Generic Models | BaseQuantities - Depth: 150 mm
Basic Wall:28_PBT_WA_beton t.p.g._d=150_C30/37:2328665 | 02 tweede verdieping | 28.21 hoofddraagconstructies - wanden en vloeren, wand-/vloerconstructies (Uniformat) | 150 | 450 | 00_PBT_GM_WB_rechthoek_wandsparing:450x150 | 2 | Generic Models | BaseQuantities - Depth: 150 mm
2 x Basic Wall:28_PBT_WA_beton t.p.g._d=150_C30/37:2328665 | 02 tweede verdieping | 28.21 hoofddraagconstructies - wanden en vloeren, wand-/vloerconstructies (Uniformat) | 400 | 400 | 00_PBT_GM_WB_rechthoek_wandsparing:400x400 | 2 | Generic Models | BaseQuantities - Depth: 150 mm
28 x  | 02 tweede verdieping
2 x Floor:28_PBT_FL_kanaalplaat_d=320:2454653:2 | 03 derde verdieping | 28.21 hoofddraagconstructies - wanden en vloeren, wand-/vloerconstructies (Uniformat) | 1099.17 | 384.556 | Floor:28_PBT_FL_kanaalplaat_d=320 | 2 | Floors | BaseQuantities - Depth: 320 mm; Pset_ElementShading - Roughness: 304.8 mm
Basic Wall:28_PBT_WA_beton t.p.g._d=250_C30/37:1974447 | 05 vijfde verdieping | 28.21 hoofddraagconstructies - wanden en vloeren, wand-/vloerconstructies (Uniformat) | 2260 | 3675.74 | Basic Wall:28_PBT_WA_beton t.p.g._d=250_C30/37 | 2 | <Sketch> | Pset_ElementShading - Roughness: 304.8 mm
9 x  | 06 zesde verdieping
Basic Wall:28_PBT_WA_beton t.p.g._d=250_C30/37:2670776 | 00 begane grond | 28.21 hoofddraagconstructies - wanden en vloeren, wand-/vloerconstructies (Uniformat) | 995 | 2600 | 00_PBT_GM_WB_rechthoek_wandsparing:995x2600 | 2 | Generic Models | BaseQuantities - Depth: 250 mm
Basic Wall:28_PBT_WA_beton t.p.g._d=250_C30/37:1974447 | 00 begane grond | 28.21 hoofddraagconstructies - wanden en vloeren, wand-/vloerconstructies (Uniformat) | 4510 | 175 | Basic Wall:28_PBT_WA_beton t.p.g._d=250_C30/37 | 2 | <Sketch> | Pset_ElementShading - Roughness: 304.8 mm
8 x  | 00 begane grond
Floor:28_PBT_FL_beton t.p.g._d=600_C30/37:2670902:2 | 00 begane grond | 28.21 hoofddraagconstructies - wanden en vloeren, wand-/vloerconstructies (Uniformat) |  |  | Floor:28_PBT_FL_beton t.p.g._d=600_C30/37 | 2 | Floors | BaseQuantities - Depth: 600 mm; Area: 2817428 mm2; Pset_ElementShading - Roughness: 304.8 mm
Floor:28_PBT_FL_beton t.p.g._d=600_C30/37:2670902:3 | 00 begane grond | 28.21 hoofddraagconstructies - wanden en vloeren, wand-/vloerconstructies (Uniformat) | 2300 | 1500 | Floor:28_PBT_FL_beton t.p.g._d=600_C30/37 | 2 | Floors | BaseQuantities - Depth: 600 mm; Pset_ElementShading - Roughness: 304.8 mm
Basic Wall:16_PBT_WA_beton t.p.g._d=320_C30/37:2675493:1 | 00 begane grond | 16.20 funderingsconstructies - keerwanden, algemeen (verzamelniveau) (Uniformat) |  |  | Basic Wall:16_PBT_WA_beton t.p.g._d=320_C30/37 | 2 | Walls | Pset_ElementShading - Roughness: 304.8 mm
Basic Wall:28_PBT_WA_beton t.p.g._d=200_C30/37:2688640 | 03 derde verdieping | 28.21 hoofddraagconstructies - wanden en vloeren, wand-/vloerconstructies (Uniformat) | 3055 | 591 | 00_PBT_GM_WB_rechthoek_wandsparing:591x3055 | 2 | Generic Models | BaseQuantities - Depth: 200 mm
Basic Wall:28_PBT_WA_beton t.p.g._d=200_C30/37:2688640 | 03 derde verdieping | 28.21 hoofddraagconstructies - wanden en vloeren, wand-/vloerconstructies (Uniformat) | 3055 | 702 | 00_PBT_GM_WB_rechthoek_wandsparing:702x3055 | 2 | Generic Models | BaseQuantities - Depth: 200 mm
2 x Basic Wall:28_PBT_WA_beton t.p.g._d=250_C30/37:2835617 | 00 begane grond | 28.21 hoofddraagconstructies - wanden en vloeren, wand-/vloerconstructies (Uniformat) | 1934 | 2460 | 00_PBT_GM_WB_rechthoek_wandsparing:1934x2460 | 2 | Generic Models | BaseQuantities - Depth: 250 mm
Basic Wall:28_PBT_WA_beton t.p.g._d=500_C30/37:2860199 | 00 begane grond | 28.21 hoofddraagconstructies - wanden en vloeren, wand-/vloerconstructies (Uniformat) | 2000 | 1100 | 00_PBT_GM_WB_rechthoek_wandsparing:2000x1100 | 2 | Generic Models | BaseQuantities - Depth: 500 mm
Basic Wall:28_PBT_WA_beton t.p.g._d=500_C30/37:2860199 | 00 begane grond | 28.21 hoofddraagconstructies - wanden en vloeren, wand-/vloerconstructies (Uniformat) | 1100 | 350 | 00_PBT_GM_WB_rechthoek_wandsparing:1100x350 | 2 | Generic Models | BaseQuantities - Depth: 500 mm
Basic Wall:28_PBT_WA_beton t.p.g._d=500_C30/37:2860199 | 00 begane grond | 28.21 hoofddraagconstructies - wanden en vloeren, wand-/vloerconstructies (Uniformat) | 1300 | 350 | 00_PBT_GM_WB_rechthoek_wandsparing:1300x350 | 2 | Generic Models | BaseQuantities - Depth: 500 mm
Basic Wall:28_PBT_WA_beton t.p.g._d=200_C30/37:2901730 | 00 begane grond | 28.21 hoofddraagconstructies - wanden en vloeren, wand-/vloerconstructies (Uniformat) | 2600 | 250 | 00_PBT_GM_WB_rechthoek_wandsparing:995x2600 | 2 | Generic Models | BaseQuantities - Depth: 995 mm
Basic Wall:16_PBT_WA_beton t.p.g._d=300_bestaand:1331339 | -1 kelder | 16.20 funderingsconstructies - keerwanden, algemeen (verzamelniveau) (Uniformat) | 150 | 400 | Basic Wall:16_PBT_WA_beton t.p.g._d=300_bestaand | 2 | <Sketch> | Pset_ElementShading - Roughness: 304.8 mm
Basic Wall:16_PBT_WA_beton t.p.g._d=300_bestaand:1331339 | -1 kelder | 16.20 funderingsconstructies - keerwanden, algemeen (verzamelniveau) (Uniformat) | 400 | 675 | Basic Wall:16_PBT_WA_beton t.p.g._d=300_bestaand | 2 | <Sketch> | Pset_ElementShading - Roughness: 304.8 mm
Basic Wall:16_PBT_WA_beton t.p.g._d=300_bestaand:1331339 | -1 kelder | 16.20 funderingsconstructies - keerwanden, algemeen (verzamelniveau) (Uniformat) | 100 | 400 | Basic Wall:16_PBT_WA_beton t.p.g._d=300_bestaand | 2 | <Sketch> | Pset_ElementShading - Roughness: 304.8 mm
Basic Wall:16_PBT_WA_beton t.p.g._d=300_bestaand:1331339 | -1 kelder | 16.20 funderingsconstructies - keerwanden, algemeen (verzamelniveau) (Uniformat) |  |  | Basic Wall:16_PBT_WA_beton t.p.g._d=300_bestaand | 2 | <Sketch> | Pset_ElementShading - Roughness: 304.8 mm; BaseQuantities - Area: 5110190 mm2
Basic Wall:16_PBT_WA_beton t.p.g._d=300_bestaand:1331339 | -1 kelder | 16.20 funderingsconstructies - keerwanden, algemeen (verzamelniveau) (Uniformat) | 2427 | 1909.16 | Basic Wall:16_PBT_WA_beton t.p.g._d=300_bestaand | 2 | <Sketch> | Pset_ElementShading - Roughness: 304.8 mm
Basic Wall:28_PBT_WA_beton t.p.g._d=300_C30/37:1968638 | 04 vierde verdieping | 28.21 hoofddraagconstructies - wanden en vloeren, wand-/vloerconstructies (Uniformat) | 497.028 | 1490 | Basic Wall:28_PBT_WA_beton t.p.g._d=300_C30/37 | 2 | <Sketch> | Pset_ElementShading - Roughness: 304.8 mm
Basic Wall:28_PBT_WA_beton t.p.g._d=300_C30/37:1968638 | 04 vierde verdieping | 28.21 hoofddraagconstructies - wanden en vloeren, wand-/vloerconstructies (Uniformat) |  |  | Basic Wall:28_PBT_WA_beton t.p.g._d=300_C30/37 | 2 | <Sketch> | Pset_ElementShading - Roughness: 304.8 mm; BaseQuantities - Area: 173887 mm2
Basic Wall:28_PBT_WA_beton t.p.g._d=300_C30/37:1968638 | 04 vierde verdieping | 28.21 hoofddraagconstructies - wanden en vloeren, wand-/vloerconstructies (Uniformat) |  |  | Basic Wall:28_PBT_WA_beton t.p.g._d=300_C30/37 | 2 | <Sketch> | Pset_ElementShading - Roughness: 304.8 mm; BaseQuantities - Area: 183486 mm2
Basic Wall:28_PBT_WA_beton t.p.g._d=300_C30/37:1968638 | -2 kelder | 28.21 hoofddraagconstructies - wanden en vloeren, wand-/vloerconstructies (Uniformat) |  |  | Basic Wall:28_PBT_WA_beton t.p.g._d=300_C30/37 | 2 | <Sketch> | Pset_ElementShading - Roughness: 304.8 mm; BaseQuantities - Area: 300825 mm2
Basic Wall:16_PBT_WA_beton t.p.g._d=300_bestaand:1331339 | -1 kelder | 16.20 funderingsconstructies - keerwanden, algemeen (verzamelniveau) (Uniformat) | 1130 | 350 | Basic Wall:16_PBT_WA_beton t.p.g._d=300_bestaand | 2 | <Sketch> | Pset_ElementShading - Roughness: 304.8 mm
Basic Wall:16_PBT_WA_beton t.p.g._d=300_bestaand:1331339 | -1 kelder | 16.20 funderingsconstructies - keerwanden, algemeen (verzamelniveau) (Uniformat) | 314.113 | 350 | Basic Wall:16_PBT_WA_beton t.p.g._d=300_bestaand | 2 | <Sketch> | Pset_ElementShading - Roughness: 304.8 mm
Basic Wall:16_PBT_WA_beton t.p.g._d=350_bestaand:6076379 | -1 kelder | 16.20 funderingsconstructies - keerwanden, algemeen (verzamelniveau) (Uniformat) | 210 | 1357 | Basic Wall:16_PBT_WA_beton t.p.g._d=350_bestaand | 2 | <Sketch> | Pset_ElementShading - Roughness: 304.8 mm
Basic Wall:28_PBT_WA_beton t.p.g._d=500_C30/37:3078596:1 | -1 kelder | 28.21 hoofddraagconstructies - wanden en vloeren, wand-/vloerconstructies (Uniformat) |  |  | Basic Wall:28_PBT_WA_beton t.p.g._d=500_C30/37 | 2 | Walls | Pset_ElementShading - Roughness: 304.8 mm
Basic Wall:28_PBT_WA_beton t.p.g._d=500_C30/37:3107368:1 | -1 kelder | 28.21 hoofddraagconstructies - wanden en vloeren, wand-/vloerconstructies (Uniformat) |  |  | Basic Wall:28_PBT_WA_beton t.p.g._d=500_C30/37 | 2 | Walls | Pset_ElementShading - Roughness: 304.8 mm
Floor:28_PBT_FL_kanaalplaat_d=320:3155322:2 | 01 eerste verdieping | 28.21 hoofddraagconstructies - wanden en vloeren, wand-/vloerconstructies (Uniformat) | 150 | 450 | Floor:28_PBT_FL_kanaalplaat_d=320 | 2 | Floors | BaseQuantities - Depth: 320 mm; Pset_ElementShading - Roughness: 304.8 mm
Floor:28_PBT_FL_kanaalplaat_d=320:3155322:3 | 01 eerste verdieping | 28.21 hoofddraagconstructies - wanden en vloeren, wand-/vloerconstructies (Uniformat) | 450 | 150 | Floor:28_PBT_FL_kanaalplaat_d=320 | 2 | Floors | BaseQuantities - Depth: 320 mm; Pset_ElementShading - Roughness: 304.8 mm
Basic Wall:28_PBT_WA_beton t.p.g._d=200_C30/37:3460018 | 02 tweede verdieping | 28.21 hoofddraagconstructies - wanden en vloeren, wand-/vloerconstructies (Uniformat) | 1580 | 2300 | 00_PBT_GM_WB_rechthoek_wandsparing:1580x2300 | 2 | Generic Models | BaseQuantities - Depth: 200 mm
Basic Wall:28_PBT_WA_beton t.p.g._d=300_bestaand:250799 | -1 kelder | 28.21 hoofddraagconstructies - wanden en vloeren, wand-/vloerconstructies (Uniformat) | 417.546 | 1276.68 | Basic Wall:28_PBT_WA_beton t.p.g._d=300_bestaand | 2 | <Sketch> | Pset_ElementShading - Roughness: 304.8 mm
Basic Wall:28_PBT_WA_beton t.p.g._d=250_C30/37:1974447 | -1 kelder | 28.21 hoofddraagconstructies - wanden en vloeren, wand-/vloerconstructies (Uniformat) | 563.651 | 1960 | Basic Wall:28_PBT_WA_beton t.p.g._d=250_C30/37 | 2 | <Sketch> | Pset_ElementShading - Roughness: 304.8 mm
Basic Wall:28_PBT_WA_beton t.p.g._d=250_C30/37:3859853 | -1 kelder | 28.21 hoofddraagconstructies - wanden en vloeren, wand-/vloerconstructies (Uniformat) | 550 | 900 | 00_PBT_GM_WB_rechthoek_wandsparing:900x550 | 2 | Generic Models | BaseQuantities - Depth: 250 mm
Basic Wall:28_PBT_WA_beton t.p.g._d=250_C30/37:3859853 | -1 kelder | 28.21 hoofddraagconstructies - wanden en vloeren, wand-/vloerconstructies (Uniformat) | 200 | 750 | 00_PBT_GM_WB_rechthoek_wandsparing:750x200 | 2 | Generic Models | BaseQuantities - Depth: 250 mm
Basic Wall:28_PBT_WA_beton t.p.g._d=250_C30/37:3860134 | -1 kelder | 28.21 hoofddraagconstructies - wanden en vloeren, wand-/vloerconstructies (Uniformat) | 800 | 1000 | 00_PBT_GM_WB_rechthoek_wandsparing:1000x800 | 2 | Generic Models | BaseQuantities - Depth: 250 mm
Basic Wall:28_PBT_WA_beton t.p.g._d=250_C30/37:3860208 | -1 kelder | 28.21 hoofddraagconstructies - wanden en vloeren, wand-/vloerconstructies (Uniformat) | 800 | 250 | 00_PBT_GM_WB_rechthoek_wandsparing:1000x800 | 2 | Generic Models | BaseQuantities - Depth: 1000 mm
Basic Wall:16_PBT_WA_beton t.p.g._d=350_C53/65:3883023 | 00 begane grond | 16.20 funderingsconstructies - keerwanden, algemeen (verzamelniveau) (Uniformat) | 450 | 740 | 00_PBT_GM_WB_rechthoek_wandsparing:740x450 | 2 | Generic Models | BaseQuantities - Depth: 350 mm
Basic Wall:16_PBT_WA_beton t.p.g._d=350_C53/65:3883023 | 00 begane grond | 16.20 funderingsconstructies - keerwanden, algemeen (verzamelniveau) (Uniformat) | 2540 | 1580 | 00_PBT_GM_WB_rechthoek_wandsparing:1580x2540 | 2 | Generic Models | BaseQuantities - Depth: 350 mm
Basic Wall:16_PBT_WA_beton t.p.g._d=250_bestaand:1313619 | -1 kelder | 16.20 funderingsconstructies - keerwanden, algemeen (verzamelniveau) (Uniformat) | 700 | 525.774 | Basic Wall:16_PBT_WA_beton t.p.g._d=250_bestaand | 2 | <Sketch> | Pset_ElementShading - Roughness: 304.8 mm
Basic Wall:28_PBT_WA_beton t.p.g._d=500_C30/37:4317149 | 00 begane grond | 28.21 hoofddraagconstructies - wanden en vloeren, wand-/vloerconstructies (Uniformat) | 1800 | 600 | 00_PBT_GM_WB_rechthoek_wandsparing:1800x600 | 2 | Generic Models | BaseQuantities - Depth: 500 mm
Basic Wall:28_PBT_WA_HSB_d=183:4336948 | 02 tweede verdieping | 28.21 hoofddraagconstructies - wanden en vloeren, wand-/vloerconstructies (Uniformat) | 2620 | 1150 | 00_PBT_GM_WB_rechthoek_wandsparing:1150x2620 | 2 | Generic Models | BaseQuantities - Depth: 183 mm
Basic Wall:28_PBT_WA_HSB_d=183:4336948 | 02 tweede verdieping | 28.21 hoofddraagconstructies - wanden en vloeren, wand-/vloerconstructies (Uniformat) | 2620 | 183 | 00_PBT_GM_WB_rechthoek_wandsparing:1034x2620 | 2 | Generic Models | BaseQuantities - Depth: 1034 mm
Basic Wall:28_PBT_WA_HSB_d=183:4337328 | 02 tweede verdieping | 28.21 hoofddraagconstructies - wanden en vloeren, wand-/vloerconstructies (Uniformat) | 2620 | 1034 | 00_PBT_GM_WB_rechthoek_wandsparing:1034x2620 | 2 | Generic Models | BaseQuantities - Depth: 183 mm
Basic Wall:28_PBT_WA_beton t.p.g._d=250_C30/37:4454259 | 01 eerste verdieping | 28.21 hoofddraagconstructies - wanden en vloeren, wand-/vloerconstructies (Uniformat) | 581 | 3760 | 00_PBT_GM_WB_rechthoek_wandsparing:581x3760 | 2 | Generic Models | BaseQuantities - Depth: 250 mm
Basic Wall:28_PBT_WA_beton t.p.g._d=250_C30/37:4454259 | 01 eerste verdieping | 28.21 hoofddraagconstructies - wanden en vloeren, wand-/vloerconstructies (Uniformat) | 1100 | 3760 | 00_PBT_GM_WB_rechthoek_wandsparing:1100x3760 | 2 | Generic Models | BaseQuantities - Depth: 250 mm
Basic Wall:28_PBT_WA_beton t.p.g._d=500_C30/37:4476155 | -1 kelder | 28.21 hoofddraagconstructies - wanden en vloeren, wand-/vloerconstructies (Uniformat) | 1850 | 2000 | 00_PBT_GM_WB_rechthoek_wandsparing:2000x1850 | 2 | Generic Models | BaseQuantities - Depth: 500 mm
Basic Wall:28_PBT_WA_beton t.p.g._d=300_C53/65:3042423 | -1 kelder | 28.21 hoofddraagconstructies - wanden en vloeren, wand-/vloerconstructies (Uniformat) | 245.791 | 635 | Basic Wall:28_PBT_WA_beton t.p.g._d=300_C53/65 | 2 | <Sketch> | Pset_ElementShading - Roughness: 304.8 mm
Floor:28_PBT_FL_druklaag_d=100_C30/37:4637198:2 | -1 kelder | 28.21 hoofddraagconstructies - wanden en vloeren, wand-/vloerconstructies (Uniformat) |  |  | Floor:28_PBT_FL_druklaag_d=100_C30/37 | 2 | Floors | BaseQuantities - Depth: 100 mm; Area: 507253 mm2; Pset_ElementShading - Roughness: 304.8 mm
Floor:28_PBT_FL_druklaag_d=100_C30/37:4640256:2 | -1 kelder | 28.21 hoofddraagconstructies - wanden en vloeren, wand-/vloerconstructies (Uniformat) |  |  | Floor:28_PBT_FL_druklaag_d=100_C30/37 | 2 | Floors | BaseQuantities - Depth: 100 mm; Area: 2259500 mm2; Pset_ElementShading - Roughness: 304.8 mm
Floor:28_PBT_FL_druklaag_d=100_C30/37:4640924:2 | -1 kelder | 28.21 hoofddraagconstructies - wanden en vloeren, wand-/vloerconstructies (Uniformat) | 300 | 500 | Floor:28_PBT_FL_druklaag_d=100_C30/37 | 2 | Floors | BaseQuantities - Depth: 100 mm; Pset_ElementShading - Roughness: 304.8 mm
Basic Wall:28_PBT_WA_beton t.p.g._d=300_C30/37:1968638 | 01 eerste verdieping | 28.21 hoofddraagconstructies - wanden en vloeren, wand-/vloerconstructies (Uniformat) | 1921.26 | 1200 | Basic Wall:28_PBT_WA_beton t.p.g._d=300_C30/37 | 2 | <Sketch> | Pset_ElementShading - Roughness: 304.8 mm
Basic Wall:28_PBT_WA_beton t.p.g._d=300_C30/37:1968638 | 01 eerste verdieping | 28.21 hoofddraagconstructies - wanden en vloeren, wand-/vloerconstructies (Uniformat) | 1436.26 | 3910 | Basic Wall:28_PBT_WA_beton t.p.g._d=300_C30/37 | 2 | <Sketch> | Pset_ElementShading - Roughness: 304.8 mm
Basic Wall:28_PBT_WA_beton t.p.g._d=300_C30/37:1968638 | 01 eerste verdieping | 28.21 hoofddraagconstructies - wanden en vloeren, wand-/vloerconstructies (Uniformat) |  |  | Basic Wall:28_PBT_WA_beton t.p.g._d=300_C30/37 | 2 | <Sketch> | Pset_ElementShading - Roughness: 304.8 mm; BaseQuantities - Area: 1165652 mm2
Basic Wall:28_PBT_WA_beton t.p.g._d=300_C30/37:1968638 | 01 eerste verdieping | 28.21 hoofddraagconstructies - wanden en vloeren, wand-/vloerconstructies (Uniformat) |  |  | Basic Wall:28_PBT_WA_beton t.p.g._d=300_C30/37 | 2 | <Sketch> | Pset_ElementShading - Roughness: 304.8 mm; BaseQuantities - Area: 727444 mm2
Basic Wall:28_PBT_WA_beton t.p.g._d=300_C30/37:1968638 | 02 tweede verdieping | 28.21 hoofddraagconstructies - wanden en vloeren, wand-/vloerconstructies (Uniformat) | 400 | 1050.2 | Basic Wall:28_PBT_WA_beton t.p.g._d=300_C30/37 | 2 | <Sketch> | Pset_ElementShading - Roughness: 304.8 mm
Basic Wall:28_PBT_WA_beton t.p.g._d=300_C30/37:1968638 | 04 vierde verdieping | 28.21 hoofddraagconstructies - wanden en vloeren, wand-/vloerconstructies (Uniformat) |  |  | Basic Wall:28_PBT_WA_beton t.p.g._d=300_C30/37 | 2 | <Sketch> | Pset_ElementShading - Roughness: 304.8 mm; BaseQuantities - Area: 2225514 mm2
Basic Wall:28_PBT_WA_beton t.p.g._d=300_C30/37:1968638 | 04 vierde verdieping | 28.21 hoofddraagconstructies - wanden en vloeren, wand-/vloerconstructies (Uniformat) |  |  | Basic Wall:28_PBT_WA_beton t.p.g._d=300_C30/37 | 2 | <Sketch> | Pset_ElementShading - Roughness: 304.8 mm; BaseQuantities - Area: 1181929 mm2
Basic Wall:28_PBT_WA_beton t.p.g._d=300_C30/37:1968638 | 04 vierde verdieping | 28.21 hoofddraagconstructies - wanden en vloeren, wand-/vloerconstructies (Uniformat) |  |  | Basic Wall:28_PBT_WA_beton t.p.g._d=300_C30/37 | 2 | <Sketch> | Pset_ElementShading - Roughness: 304.8 mm; BaseQuantities - Area: 6046031 mm2
2 x Basic Wall:28_PBT_WA_beton t.p.g._d=300_C30/37:1968638 | 03 derde verdieping | 28.21 hoofddraagconstructies - wanden en vloeren, wand-/vloerconstructies (Uniformat) | 790.896 | 1330 | Basic Wall:28_PBT_WA_beton t.p.g._d=300_C30/37 | 2 | <Sketch> | Pset_ElementShading - Roughness: 304.8 mm
Floor:28_PBT_FL_druklaag_d=350_C30/37:6039979:2 | -1 kelder | 28.21 hoofddraagconstructies - wanden en vloeren, wand-/vloerconstructies (Uniformat) | 300 | 300 | Floor:28_PBT_FL_druklaag_d=350_C30/37 | 2 | Floors | BaseQuantities - Depth: 350 mm; Pset_ElementShading - Roughness: 304.8 mm
Floor:28_PBT_FL_druklaag_d=350_C30/37:6039979:3 | -1 kelder | 28.21 hoofddraagconstructies - wanden en vloeren, wand-/vloerconstructies (Uniformat) | 300 | 300 | Floor:28_PBT_FL_druklaag_d=350_C30/37 | 2 | Floors | BaseQuantities - Depth: 350 mm; Pset_ElementShading - Roughness: 304.8 mm
Floor:28_PBT_FL_druklaag_d=350_C30/37:6039979:4 | -1 kelder | 28.21 hoofddraagconstructies - wanden en vloeren, wand-/vloerconstructies (Uniformat) | 300 | 300 | Floor:28_PBT_FL_druklaag_d=350_C30/37 | 2 | Floors | BaseQuantities - Depth: 350 mm; Pset_ElementShading - Roughness: 304.8 mm
Floor:28_PBT_FL_druklaag_d=350_C30/37:6039979:5 | -1 kelder | 28.21 hoofddraagconstructies - wanden en vloeren, wand-/vloerconstructies (Uniformat) | 300 | 300 | Floor:28_PBT_FL_druklaag_d=350_C30/37 | 2 | Floors | BaseQuantities - Depth: 350 mm; Pset_ElementShading - Roughness: 304.8 mm
2 x Basic Wall:28_PBT_WA_beton t.p.g._d=300_C30/37:1968638 | 04 vierde verdieping | 28.21 hoofddraagconstructies - wanden en vloeren, wand-/vloerconstructies (Uniformat) | 680 | 380 | Basic Wall:28_PBT_WA_beton t.p.g._d=300_C30/37 | 2 | <Sketch> | Pset_ElementShading - Roughness: 304.8 mm
Basic Wall:28_PBT_WA_beton t.p.g._d=300_C30/37:6358456 | -1 kelder | 28.21 hoofddraagconstructies - wanden en vloeren, wand-/vloerconstructies (Uniformat) | 350 | 250 | 00_PBT_GM_WB_rechthoek_wandsparing:250x350 | 2 | Generic Models | BaseQuantities - Depth: 300 mm
Basic Wall:28_PBT_WA_beton t.p.g._d=300_C30/37:6358456 | -1 kelder | 28.21 hoofddraagconstructies - wanden en vloeren, wand-/vloerconstructies (Uniformat) | 130 | 450 | 00_PBT_GM_WB_rechthoek_wandsparing:450x130 | 2 | Generic Models | BaseQuantities - Depth: 300 mm
Basic Wall:28_PBT_WA_beton t.p.g._d=250_C30/37:6360717 | 01 eerste verdieping | 28.21 hoofddraagconstructies - wanden en vloeren, wand-/vloerconstructies (Uniformat) | 1100 | 3760 | 00_PBT_GM_WB_rechthoek_wandsparing:1100x3760 | 2 | Generic Models | BaseQuantities - Depth: 250 mm
Basic Wall:28_PBT_WA_beton t.p.g._d=250_C30/37:6360717 | 01 eerste verdieping | 28.21 hoofddraagconstructies - wanden en vloeren, wand-/vloerconstructies (Uniformat) | 581 | 3760 | 00_PBT_GM_WB_rechthoek_wandsparing:581x3760 | 2 | Generic Models | BaseQuantities - Depth: 250 mm
Basic Wall:28_PBT_WA_beton t.p.g._d=250_C30/37:6360717 | 01 eerste verdieping | 28.21 hoofddraagconstructies - wanden en vloeren, wand-/vloerconstructies (Uniformat) | 4550 | 250 | 00_PBT_GM_WB_rechthoek_wandsparing:5600x4550 | 2 | Generic Models | BaseQuantities - Depth: 5600 mm

# IfcOpeningElement: Recess (16)
Classification: 28.21 hoofddraagconstructies - wanden en vloeren, wand-/vloerconstructies (Uniformat)
Pset_OpeningElementCommon - sets with these values: 2
Name (Basic Wall:...) | In | Reference | Category | Depth (mm) | Height (mm) | Width (mm)
28_PBT_WA_beton t.p.g._d=300_bestaand:1358617 | -1 kelder | Generic Models 7:Generic Models 7 | Generic Models
28_PBT_WA_beton t.p.g._d=600_C30/37:2025504 | 02 tweede verdieping | 00_PBT_GM_FB_inkassing:19155x205x200 | Generic Models | 200 | 205 | 19155
3 x 28_PBT_WA_beton t.p.g._d=300_bestaand:2201684 | 02 tweede verdieping | Basic Wall:28_PBT_WA_beton t.p.g._d=300_bestaand | Rectangular Arc Wall Opening | 200 | BaseQuantities - Area: 119381 mm2; Pset_ElementShading - Roughness: 304.8 mm
28_PBT_WA_beton t.p.g._d=300_bestaand:2201684 | 02 tweede verdieping | Generic Models 13:Generic Models 13 | Generic Models | 150 | 500 | 693.453
28_PBT_WA_beton t.p.g._d=500_C30/37:4475532 | -1 kelder | 00_PBT_GM_FB_inkassing:2463x60x320 | Generic Models | 320 | 2463 | 60
28_PBT_WA_beton t.p.g._d=620_C30/37:4549909 | -1 kelder | 00_PBT_GM_WB_rechthoek_wandsparing:1054x2420_D | Generic Models | 300 | 1054 | 2420
28_PBT_WA_beton t.p.g._d=500_C30/37:5110971 | -1 kelder | 00_PBT_GM_WB_rechthoek_wandsparing:1500x2490 | Generic Models | 300 | 1500 | 2490
2 x 28_PBT_WA_beton t.p.g._d=500_C53/65:5537328 | -1 kelder | 00_PBT_GM_WB_rechthoek_wandsparing:1975x2420_D | Generic Models | 300 | 2420 | 1975
2 x 28_PBT_WA_beton t.p.g._d=500_C53/65:5537328 | -1 kelder | 00_PBT_GM_WB_rechthoek_wandsparing:1054x2420_D | Generic Models | 300 | 2420 | 1054
28_PBT_WA_beton t.p.g._d=500_C53/65:5537328 | -1 kelder | 00_PBT_GM_WB_rechthoek_wandsparing:1504x2930 | Generic Models | 300 | 2930 | 1504
28_PBT_WA_beton t.p.g._d=500_C53/65:5537328 | -1 kelder | 00_PBT_GM_WB_rechthoek_wandsparing:675x200 | Generic Models | 300 | 200 | 675
28_PBT_WA_beton t.p.g._d=500_C53/65:5537328 | -1 kelder | 00_PBT_GM_WB_rechthoek_wandsparing:600x250 | Generic Models | 300 | 250 | 600

# IfcPile: 17_PBT_SFO_grondkering_rond:Ø1000 (grondkering) (97)
In: -2 kelder
Classification: 17.21 paalfunderingen - geheid, dragende palen (Uniformat); Material: 00_PBT_MAT_grout
Pset_ProductRequirements - Category: Structural Foundations
Pset_QuantityTakeOff - Reference: 17_PBT_SFO_grondkering_rond:Ø1000 (grondkering)
Pset_Pieters - Dragend/niet dragend: yes; In/uitwendig: yes; Breedte/Diameter: 1000 mm; Bouwlaag: Level: NAP; Naamgeving element: 17_PBT_SFO_grondkering_rond: Ø1000 (grondkering); Codering - NL-SfB: 17.21; Omschrijving NL-SfB: paalfunderingen - geheid, dragende palen; Fase: Nieuw; Materiaal: 00_PBT_MAT_grout; Description: grondkering
Name (17_PBT_SFO_grondkering_rond:Ø1000 (grondkering):...) | O.k. fundering t.o.v. Peil (mm) | Paalpuntniveau tov NAP (mm) | Length (mm) | CrossSectionArea (mm2) | NetVolume (m3) | Group
3030368 | -3040 | -3000 | 6720 | 785379 | 4.82722 | Model Group:Array Group 4:3032808
3032812 | -3040 | -3000 | 6720 | 672060 | 4.11393 | Model Group:Array Group 4:3032814
3032832 | -3040 | -3000 | 6720 | 672060 | 4.11393 | Model Group:Array Group 4:3032834
3032837 | -3040 | -3000 | 6720 | 672069 | 4.17076 | Model Group:Array Group 4:3032839
3032856 | -3040 | -3000 | 6720 | 785338 | 4.57099 | Model Group:Array Group 4:3032858
3032870 | -3040 | -3000 | 6720 | 672002 | 3.91143 | Model Group:Array Group 4:3032872
3032875 | -3040 | -3000 | 6720 | 672002 | 3.91143 | Model Group:Array Group 4:3032877
3032880 | -3040 | -3000 | 6720 | 672002 | 3.91143 | Model Group:Array Group 4:3032882
3032885 | -3040 | -3000 | 6720 | 682624 | 3.91142 | Model Group:Array Group 4:3032887
3032895 | -3040 | -3000 | 6720 | 801351 | 4.56931 | Model Group:Array Group 4:3032897
3032900 | -3040 | -3000 | 6720 | 672002 | 3.91143 | Model Group:Array Group 4:3032902
3032905 | -3040 | -3000 | 6720 | 672002 | 3.91143 | Model Group:Array Group 4:3032907
3032910 | -3040 | -3000 | 6720 | 672002 | 3.81286
3032915 | -3040 | -3000 | 6720 | 680449 | 3.43538
3032920 | -3540 | -3000 | 6220 | 680009 | 3.38481
3032925 | -3540 | -3000 | 6220 | 672003 | 3.38487
3032935 | -3040 | -3000 | 6720 | 724516 | 3.49176 | Model Group:Array Group 4:3032937
3032940 | -3040 | -3000 | 6720 | 600546 | 3.10711 | Model Group:Array Group 4:3032942
3032945 | -3040 | -3000 | 6720 | 672003 | 3.48118 | Model Group:Array Group 4:3032947
3032950 | -3040 | -3000 | 6720 | 672112 | 3.68551 | Model Group:Array Group 4:3032952
3033025 | -3040 | -3000 | 6720 | 666738 | 3.73144 | Model Group:Array Group 4:3033027
3033045 | -3040 | -3000 | 6720 | 655205 | 3.79714 | Model Group:Array Group 4:3033047
3033050 | -3040 | -3000 | 6720 | 655253 | 3.80283 | Model Group:Array Group 4:3033052
3033063 | -3040 | -3000 | 6720 | 634089 | 3.67872 | Model Group:Array Group 4:3033065
3033083 | -3040 | -3000 | 6720 | 600777 | 3.74853 | Model Group:Array Group 4:3033085
3035498 | -990 | -3000 | 8770 | 828761 | 5.40109
3036182 | -990 | -3000 | 8770 | 875428 | 4.98929 | Model Group:Array Group 5:3036184
3052123 | -3740 | -3000 | 6020 | 785377 | 4.32799
3052545 | -3740 | -3000 | 6020 | 616779 | 3.32046 | Model Group:Array Group 7:3052547
3052569 | -3740 | -3000 | 6020 | 676361 | 3.62958 | Model Group:Array Group 7:3052571
3052574 | -3740 | -3000 | 6020 | 676361 | 3.62958 | Model Group:Array Group 7:3052576
3052579 | -3740 | -3000 | 6020 | 676361 | 3.62958 | Model Group:Array Group 7:3052581
3052584 | -3740 | -3000 | 6020 | 676267 | 3.62953 | Model Group:Array Group 7:3052586
3052589 | -3740 | -3000 | 6020 | 682522 | 3.74065 | Model Group:Array Group 7:3052591
3052706 | -4740 | -3000 | 5020 | 785385 | 3.34071
3052709 | -3740 | -3000 | 6020 | 786056 | 3.63495 | Model Group:Array Group 7:3052711
3052712 | -3740 | -3000 | 6020 | 583851 | 3.12746 | Model Group:Array Group 7:3052714
3052715 | -3740 | -3000 | 6020 | 583851 | 3.12746 | Model Group:Array Group 7:3052717
3052718 | -3740 | -3000 | 6020 | 583851 | 3.12744 | Model Group:Array Group 7:3052720
3052721 | -3740 | -3000 | 6020 | 583851 | 2.86736 | Model Group:Array Group 7:3052723
3052724 | -3740 | -3000 | 6020 | 583847 | 2.8355 | Model Group:Array Group 7:3052726
3052727 | -3740 | -3000 | 6020 | 660239 | 3.35444 | Model Group:Array Group 7:3052729
3052743 | -3740 | -3000 | 6020 | 686364 | 3.71355 | Model Group:Array Group 8:3052747
3052751 | -3740 | -3000 | 6020 | 657251 | 3.54336 | Model Group:Array Group 8:3052753
3052772 | -3740 | -3000 | 6020 | 657251 | 3.54336 | Model Group:Array Group 8:3052774
3052777 | -3740 | -3000 | 6020 | 657251 | 3.54336 | Model Group:Array Group 8:3052779
3052782 | -3740 | -3000 | 6020 | 531845 | 2.70435 | Model Group:Array Group 8:3052784
3052813 | -4940 | -3000 | 4820 | 676010 | 2.71853
3052816 | -4940 | -3000 | 4820 | 657241 | 2.62818
3052819 | -4940 | -3000 | 4820 | 657241 | 2.62818
3052822 | -4940 | -3000 | 4820 | 657241 | 2.63068
3052825 | -4940 | -3000 | 4820 | 531839 | 2.11301
3067912 | -3740 | -3000 | 6020 | 785422 | 4.20747
3067917 | -3740 | -3000 | 6020 | 605071 | 3.24299 | Model Group:Array Group 7:3067919
3067920 | -3740 | -3000 | 6020 | 657299 | 3.52468 | Model Group:Array Group 7:3067922
3067923 | -3740 | -3000 | 6020 | 657298 | 3.49978 | Model Group:Array Group 7:3067925
3067926 | -3740 | -3000 | 6020 | 657298 | 3.42258 | Model Group:Array Group 7:3067928
3067929 | -3740 | -3000 | 6020 | 657298 | 3.42258 | Model Group:Array Group 7:3067931
3067941 | -3740 | -3000 | 6020 | 785391 | 4.15633
3067944 | -3740 | -3000 | 6020 | 657252 | 3.46473
3067947 | -3740 | -3000 | 6020 | 657253 | 3.46473
3067950 | -3740 | -3000 | 6020 | 657258 | 3.46472
3386473 | -5040 | -3000 | 4720 | 684876 | 2.79006
3459807 | -3040 | -3000 | 6720 | 559884 | 3.26448 | Model Group:Array Group 4:3459809
3870984 | -3740 | -3000 | 6020 | 657298 | 3.47637 | Model Group:Array Group 7:3870986
3870987 | -3740 | -3000 | 6020 | 657298 | 3.52468 | Model Group:Array Group 7:3870989
3870990 | -3740 | -3000 | 6020 | 657297 | 3.52468 | Model Group:Array Group 7:3870992
3870993 | -3740 | -3000 | 6020 | 539336 | 2.99516 | Model Group:Array Group 7:3870995
3871026 | -3740 | -3000 | 6020 | 657232 | 3.46473
3871038 | -3740 | -3000 | 6020 | 657233 | 3.46473
3871050 | -3740 | -3000 | 6020 | 657239 | 3.46474
3871074 | -890 | -3000 | 8870 | 798974 | 6.02856
3871086 | -890 | -3000 | 8870 | 719699 | 5.3013
3871098 | -890 | -3000 | 8870 | 692905 | 5.27026
3871108 | -890 | -3000 | 8870 | 692906 | 5.27026
3871118 | -890 | -3000 | 8870 | 692907 | 5.27026
3871286 | -5040 | -3000 | 4720 | 673337 | 2.73885
4512465 | -890 | -3000 | 8870 | 692908 | 5.27026
4512519 | -890 | -3000 | 8870 | 692909 | 5.27026
4512530 | -890 | -3000 | 8870 | 692910 | 5.27026
4512541 | -890 | -3000 | 8870 | 692910 | 5.27029
4512552 | -890 | -3000 | 8870 | 692959 | 5.30651
4512563 | -890 | -3000 | 8870 | 1046033 | 5.41214
4512661 | -3740 | -3000 | 6020 | 785385 | 4.21574
4512663 | -3740 | -3000 | 6020 | 657242 | 3.5107
4512665 | -3740 | -3000 | 6020 | 583492 | 2.61374
4512667 | -3740 | -3000 | 6020 | 657242 | 3.5107
4512669 | -3740 | -3000 | 6020 | 529099 | 2.80567
5166670 | 160 | 0 | 6920 | 785383 | 5.12085 | BaseQuantities - OuterSurfaceArea: 20483184 mm2; GrossSurfaceArea: 22053982 mm2; GrossVolume: 5.1208 m3
5166815 | 160 | 0 | 6920 | 613308 | 3.99879 | BaseQuantities - OuterSurfaceArea: 20483184 mm2; GrossSurfaceArea: 21710177 mm2; GrossVolume: 4 m3
5166897 | 160 | 0 | 6920 | 785383 | 4.90283
5166899 | 160 | 0 | 6920 | 613308 | 3.99879 | BaseQuantities - OuterSurfaceArea: 20483184 mm2; GrossSurfaceArea: 21710177 mm2; GrossVolume: 4 m3
5166931 | 160 | 0 | 6920 | 785383 | 5.12085 | BaseQuantities - OuterSurfaceArea: 20483184 mm2; GrossSurfaceArea: 22053982 mm2; GrossVolume: 5.1208 m3
5166933 | 160 | 0 | 6920 | 613308 | 3.99879 | BaseQuantities - OuterSurfaceArea: 20483184 mm2; GrossSurfaceArea: 21710177 mm2; GrossVolume: 4 m3
5166944 | -950 | 0 | 5810 | 785387 | 4.24898 | BaseQuantities - OuterSurfaceArea: 16996016 mm2; GrossSurfaceArea: 18566814 mm2; GrossVolume: 4.24901 m3
5166946 | -950 | 0 | 5810 | 692242 | 3.74505 | BaseQuantities - OuterSurfaceArea: 16996016 mm2; GrossSurfaceArea: 18374907 mm2; GrossVolume: 3.7299 m3
5167144 | 160 | 0 | 6920 | 888792 | 5.0794

# IfcPile: 17_PBT_SFO_paal_rond:Ø1000 (jetgroutpaal) binnen kelder (70)
In: -2 kelder
Classification: 17.21 paalfunderingen - geheid, dragende palen (Uniformat); Material: 00_PBT_MAT_grout
Pset_ProductRequirements - Category: Structural Foundations
Pset_QuantityTakeOff - Reference: 17_PBT_SFO_paal_rond:Ø1000 (jetgroutpaal) binnen kelder
Pset_Pieters - Dragend/niet dragend: yes; In/uitwendig: yes; Breedte/Diameter: 1000 mm; Bouwlaag: Level: NAP; Naamgeving element: 17_PBT_SFO_paal_rond: Ø1000 (jetgroutpaal) binnen kelder; Codering - NL-SfB: 17.21; Omschrijving NL-SfB: paalfunderingen - geheid, dragende palen; Fase: Nieuw; Materiaal: 00_PBT_MAT_grout; Description: Jetgroutpaal
Name (17_PBT_SFO_paal_rond:Ø1000 (jetgroutpaal) binnen kelder:...) | O.k. fundering t.o.v. Peil (mm) | Paalpuntniveau tov NAP (mm) | Paalcode afhakniveau | Paalcode paalpuntniveau | Length (mm) | NetVolume (m3)
2995532 | -3040 | -13250 | j | B | 16970 | 13.0139 | BaseQuantities - CrossSectionArea: 785399 mm2; OuterSurfaceArea: 52056190 mm2; GrossSurfaceArea: 53626988 mm2; GrossVolume: 13.0141 m3
2996114 | -3040 | -13250 | j | B | 16970 | 13.0139
2996125 | -3040 | -13250 | j | B | 16970 | 13.0139
2996136 | -4000 | -13250 | o | B | 16010 | 12.26 | BaseQuantities - CrossSectionArea: 785399 mm2; OuterSurfaceArea: 49040261 mm2; GrossSurfaceArea: 50611059 mm2; GrossVolume: 12.2601 m3
2996147 | -3040 | -7250 | j | A | 10970 | 8.30159 | BaseQuantities - CrossSectionArea: 785399 mm2; OuterSurfaceArea: 33206634 mm2; GrossSurfaceArea: 34777432 mm2; GrossVolume: 8.30167 m3
2997918 | -3040 | -7250 | j | A | 10970 | 8.30159
2998203 | -3040 | -7250 | j | A | 10970 | 8.30159 | BaseQuantities - CrossSectionArea: 785399 mm2; OuterSurfaceArea: 33206634 mm2; GrossSurfaceArea: 34777432 mm2; GrossVolume: 8.30167 m3
2998267 | -3040 | -7250 | j | A | 10970 | 8.30159
2998280 | -3040 | -7250 | j | A | 10970 | 8.30159
2998339 | -3340 | -13250 | m | B | 16670 | 12.7783 | BaseQuantities - CrossSectionArea: 785399 mm2; OuterSurfaceArea: 51113712 mm2; GrossSurfaceArea: 52684510 mm2; GrossVolume: 12.7784 m3
2998350 | -3040 | -7250 | j | A | 10970 | 8.30159
2998727 | -3040 | -7250 | j | A | 10970 | 8.30159
2998776 | -3040 | -7250 | j | A | 10970 | 8.30159
3040274 | -3180 | -13250 | l | B | 16830 | 12.904 | BaseQuantities - CrossSectionArea: 785399 mm2; OuterSurfaceArea: 51616367 mm2; GrossSurfaceArea: 53187165 mm2; GrossVolume: 12.9041 m3
3040327 | -3180 | -13250 | l | B | 16830 | 12.904
3040428 | -3740 | -7250 | n | A | 10270 | 7.75182 | BaseQuantities - CrossSectionArea: 785399 mm2; OuterSurfaceArea: 31007519 mm2; GrossSurfaceArea: 32578317 mm2; GrossVolume: 7.75189 m3
3040534 | -3180 | -7250 | l | A | 10830 | 8.19164 | BaseQuantities - CrossSectionArea: 785399 mm2; OuterSurfaceArea: 32766811 mm2; GrossSurfaceArea: 34337609 mm2; GrossVolume: 8.19171 m3
3040918 | -2530 | -7250 | h | A | 11480 | 8.70214 | BaseQuantities - CrossSectionArea: 785399 mm2; OuterSurfaceArea: 34808847 mm2; GrossSurfaceArea: 36379644 mm2; GrossVolume: 8.70222 m3
3040933 | -2530 | -7250 | h | A | 11480 | 8.70214
3042732 | -3740 | -10750 | n | C | 13770 | 10.5007 | BaseQuantities - CrossSectionArea: 785399 mm2; OuterSurfaceArea: 42003094 mm2; GrossSurfaceArea: 43573891 mm2; GrossVolume: 10.5008 m3
3042909 | -3740 | -10750 | n | C | 13770 | 10.5007
3042920 | -3740 | -10750 | n | C | 13770 | 10.5007
3042931 | -3740 | -10750 | n | C | 13770 | 10.5007
3045065 | -3740 | -13250 | n | B | 16270 | 12.4642 | BaseQuantities - CrossSectionArea: 785399 mm2; OuterSurfaceArea: 49857075 mm2; GrossSurfaceArea: 51427873 mm2; GrossVolume: 12.4643 m3
3045078 | -3740 | -13250 | n | B | 16270 | 12.4642
3045210 | -3740 | -10750 | n | C | 13770 | 10.5007
3045278 | -3740 | -10750 | n | C | 13770 | 10.5007
3045421 | -3740 | -10750 | n | C | 13770 | 10.5007
3045432 | -3740 | -10750 | n | C | 13770 | 10.5007
3045489 | -3740 | -13250 | n | B | 16270 | 12.4642
3045530 | -5040 | -10750 | s | C | 12470 | 9.47968 | BaseQuantities - CrossSectionArea: 785399 mm2; OuterSurfaceArea: 37919023 mm2; GrossSurfaceArea: 39489821 mm2; GrossVolume: 9.47976 m3
3045639 | -3740 | -7250 | n | A | 10270 | 7.75182
3045677 | -3740 | -7250 | n | A | 10270 | 7.75182
3045688 | -3740 | -7250 | n | A | 10270 | 7.75182
3050549 | -3740 | -7250 | n | A | 10270 | 7.75182
3050573 | -3740 | -7250 | n | A | 10270 | 7.75182
3050824 | -3740 | -7250 | n | A | 10270 | 7.75182
3053335 | -3740 | -7250 | n | A | 10270 | 7.75182
3053415 | -3740 | -7250 | n | A | 10270 | 7.75182
3053588 | -3740 | -7250 | n | A | 10270 | 7.75182
3053630 | -3740 | -7250 | n | A | 10270 | 7.75182
3053683 | -3740 | -7250 | n | A | 10270 | 7.75182
3053694 | -3740 | -7250 | n | A | 10270 | 7.75182
3053760 | -5300 | -13250 | t | B | 14710 | 11.239 | BaseQuantities - CrossSectionArea: 785399 mm2; OuterSurfaceArea: 44956191 mm2; GrossSurfaceArea: 46526989 mm2; GrossVolume: 11.2391 m3
3053802 | -6560 | -7250 | bb | A | 7450 | 5.53701 | BaseQuantities - CrossSectionArea: 785399 mm2; OuterSurfaceArea: 22148228 mm2; GrossSurfaceArea: 23719026 mm2; GrossVolume: 5.53706 m3
3054405 | -6560 | -7250 | bb | A | 7450 | 5.53701
3054418 | -6560 | -7250 | bb | A | 7450 | 5.53701
3063946 | -6560 | -7250 | bb | A | 7450 | 5.53701
3078299 | -3740 | -7250 | n | A | 10270 | 7.75182
3078388 | -3740 | -7250 | n | A | 10270 | 7.75182
3078390 | -3740 | -7250 | n | A | 10270 | 7.75182
3107366 | -3740 | -7250 | n | A | 10270 | 7.75182
3140785 | -6190 | -7250 | z | A | 7820 | 5.82761 | BaseQuantities - CrossSectionArea: 785399 mm2; OuterSurfaceArea: 23310617 mm2; GrossSurfaceArea: 24881415 mm2; GrossVolume: 5.82766 m3
3140796 | -5320 | -7250 | u | A | 8690 | 6.5109 | BaseQuantities - CrossSectionArea: 785399 mm2; OuterSurfaceArea: 26043803 mm2; GrossSurfaceArea: 27614601 mm2; GrossVolume: 6.51096 m3
3634288 | -5320 | -7250 | u | A | 8690 | 6.5109
3634325 | -6190 | -7250 | z | A | 7820 | 5.82761
3707967 | -5320 | -7250 | u | A | 8690 | 6.5109
3853255 | -3740 | -7250 | n | A | 10270 | 7.75182
3854011 | -6380 | -13250 | aa | B | 13630 | 10.3907 | BaseQuantities - CrossSectionArea: 785399 mm2; OuterSurfaceArea: 41563271 mm2; GrossSurfaceArea: 43134068 mm2; GrossVolume: 10.3908 m3
3854063 | -6180 | -13250 | y | B | 13830 | 10.5478 | BaseQuantities - CrossSectionArea: 785399 mm2; OuterSurfaceArea: 42191589 mm2; GrossSurfaceArea: 43762387 mm2; GrossVolume: 10.5479 m3
3878642 | -6190 | -7250 | z | A | 7820 | 5.82761
3878907 | -5320 | -7250 | u | A | 8690 | 6.5109
3892744 | -5320 | -7250 | u | A | 8690 | 6.5109
4261429 | -5320 | -7250 | u | A | 8690 | 6.5109
4450396 | -3340 | -13250 | m | B | 16670 | 12.7783
4549486 | -3740 | -7250 | n | A | 10270 | 7.75182
6472415 | -3740 | -13250 | n | B | 16270 | 12.4642
6472467 | -3740 | -13250 | n | B | 16270 | 12.4642
6472491 | -5820 | -13250 | cc | B | 14190 | 10.8306 | BaseQuantities - CrossSectionArea: 785399 mm2; OuterSurfaceArea: 43322563 mm2; GrossSurfaceArea: 44893360 mm2; GrossVolume: 10.8306 m3
6472520 | -5820 | -13250 | cc | B | 14190 | 10.8306

# IfcPile: 17_PBT_SFO_paal_rond:Ø1000 (jetgroutpaal) buiten kelder (59)
In: -2 kelder
Classification: 17.21 paalfunderingen - geheid, dragende palen (Uniformat); Material: 00_PBT_MAT_grout
Pset_ProductRequirements - Category: Structural Foundations
Pset_QuantityTakeOff - Reference: 17_PBT_SFO_paal_rond:Ø1000 (jetgroutpaal) buiten kelder
Pset_Pieters - Dragend/niet dragend: yes; In/uitwendig: yes; Breedte/Diameter: 1000 mm; Bouwlaag: Level: NAP; Naamgeving element: 17_PBT_SFO_paal_rond: Ø1000 (jetgroutpaal) buiten kelder; Codering - NL-SfB: 17.21; Omschrijving NL-SfB: paalfunderingen - geheid, dragende palen; Fase: Nieuw; Materiaal: 00_PBT_MAT_grout; Description: Jetgroutpaal
Name (17_PBT_SFO_paal_rond:Ø1000 (jetgroutpaal) buiten kelder:...) | O.k. fundering t.o.v. Peil (mm) | Paalpuntniveau tov NAP (mm) | Paalcode afhakniveau | Paalcode paalpuntniveau | Length (mm) | NetVolume (m3)
3039239 | -4520 | -7250 | r | A | 9490 | 7.13921 | BaseQuantities - CrossSectionArea: 785399 mm2; OuterSurfaceArea: 28557077 mm2; GrossSurfaceArea: 30127875 mm2; GrossVolume: 7.13928 m3
3039440 | -4520 | -13250 | r | B | 15490 | 11.8516 | BaseQuantities - CrossSectionArea: 785399 mm2; OuterSurfaceArea: 47406633 mm2; GrossSurfaceArea: 48977431 mm2; GrossVolume: 11.8517 m3
3039482 | -4520 | -7250 | r | A | 9490 | 7.13921
3039619 | -4520 | -13250 | r | B | 15490 | 11.8516
3039860 | -3050 | -7250 | k | A | 10960 | 8.29374 | BaseQuantities - CrossSectionArea: 785399 mm2; OuterSurfaceArea: 33175218 mm2; GrossSurfaceArea: 34746016 mm2; GrossVolume: 8.29381 m3
3040162 | -4520 | -13250 | r | B | 15490 | 11.8516
3043187 | -1815 | -10750 | f | C | 15695 | 12.0126 | BaseQuantities - CrossSectionArea: 785399 mm2; OuterSurfaceArea: 48050660 mm2; GrossSurfaceArea: 49621457 mm2; GrossVolume: 12.0127 m3
3043253 | -1815 | -10750 | f | C | 15695 | 12.0126
3043264 | -1815 | -10750 | f | C | 15695 | 12.0126
3043275 | -1815 | -10750 | f | C | 15695 | 12.0126
3044652 | -1115 | -10750 | e | C | 16395 | 12.5623 | BaseQuantities - CrossSectionArea: 785399 mm2; OuterSurfaceArea: 50249774 mm2; GrossSurfaceArea: 51820572 mm2; GrossVolume: 12.5625 m3
3044665 | -1115 | -10750 | e | C | 16395 | 12.5623
3064208 | -3740 | -7250 | n | A | 10270 | 7.75182 | BaseQuantities - CrossSectionArea: 785399 mm2; OuterSurfaceArea: 31007519 mm2; GrossSurfaceArea: 32578317 mm2; GrossVolume: 7.75189 m3
3064988 | -1020 | -7250 | d | A | 12990 | 9.88809 | BaseQuantities - CrossSectionArea: 785399 mm2; OuterSurfaceArea: 39552652 mm2; GrossSurfaceArea: 41123449 mm2; GrossVolume: 9.88817 m3
3065352 | -1020 | -7250 | d | A | 12990 | 9.88809
3065418 | -1020 | -7250 | d | A | 12990 | 9.88809
3065427 | -1020 | -7250 | d | A | 12990 | 9.88809
3065436 | -1020 | -7250 | d | A | 12990 | 9.88809
3067908 | -5380 | -7250 | v | A | 8630 | 6.46378 | BaseQuantities - CrossSectionArea: 785399 mm2; OuterSurfaceArea: 25855308 mm2; GrossSurfaceArea: 27426105 mm2; GrossVolume: 6.46383 m3
3067910 | -5380 | -7250 | v | A | 8630 | 6.46378
3070541 | -5380 | -7250 | v | A | 8630 | 6.46378
3070609 | -5380 | -7250 | v | A | 8630 | 6.46378
3073364 | -2620 | -13250 | dd | B | 17390 | 13.3438 | BaseQuantities - CrossSectionArea: 785399 mm2; OuterSurfaceArea: 53375659 mm2; GrossSurfaceArea: 54946457 mm2; GrossVolume: 13.3439 m3
3073688 | -3040 | -13250 | j | B | 16970 | 13.0139 | BaseQuantities - CrossSectionArea: 785399 mm2; OuterSurfaceArea: 52056190 mm2; GrossSurfaceArea: 53626988 mm2; GrossVolume: 13.0141 m3
3073747 | -3040 | -13250 | j | B | 16970 | 13.0139
3073820 | -2620 | -13250 | dd | B | 17390 | 13.3438
3073867 | -930 | -7250 | c | A | 13080 | 9.95877 | BaseQuantities - CrossSectionArea: 785399 mm2; OuterSurfaceArea: 39835395 mm2; GrossSurfaceArea: 41406193 mm2; GrossVolume: 9.95886 m3
3073869 | -930 | -7250 | c | A | 13080 | 9.95877
3074954 | -220 | -7250 | p | A | 13790 | 10.5164 | BaseQuantities - CrossSectionArea: 785399 mm2; OuterSurfaceArea: 42065926 mm2; GrossSurfaceArea: 43636723 mm2; GrossVolume: 10.5165 m3
3075166 | -220 | -7250 | p | A | 13790 | 10.5164
3075239 | 180 | -7250 | a | A | 14190 | 10.8306 | BaseQuantities - CrossSectionArea: 785399 mm2; OuterSurfaceArea: 43322563 mm2; GrossSurfaceArea: 44893360 mm2; GrossVolume: 10.8306 m3
3075248 | 180 | -7250 | a | A | 14190 | 10.8306
3075257 | 180 | -7250 | a | A | 14190 | 10.8306
3075292 | -1020 | -7250 | d | A | 12990 | 9.88809
3075364 | -220 | -7250 | p | A | 13790 | 10.5164
3075508 | -220 | -7250 | p | A | 13790 | 10.5164
3075519 | -220 | -7250 | p | A | 13790 | 10.5164
3075807 | -870 | -7250 | b | A | 13140 | 10.0059 | BaseQuantities - CrossSectionArea: 785399 mm2; OuterSurfaceArea: 40023890 mm2; GrossSurfaceArea: 41594688 mm2; GrossVolume: 10.006 m3
3076015 | -870 | -7250 | b | A | 13140 | 10.0059
3076057 | -870 | -7250 | b | A | 13140 | 10.0059
3076070 | -870 | -7250 | b | A | 13140 | 10.0059
3076085 | -870 | -7250 | b | A | 13140 | 10.0059
3076229 | -870 | -7250 | b | A | 13140 | 10.0059
3076271 | -5380 | -7250 | v | A | 8630 | 6.46378
3076345 | -5380 | -7250 | v | A | 8630 | 6.46378
3076719 | -2620 | -13250 | dd | B | 17390 | 13.3438
3076725 | -2620 | -13250 | dd | B | 17390 | 13.3438
3076729 | -2620 | -13250 | dd | B | 17390 | 13.3438
3076761 | -2620 | -13250 | dd | B | 17390 | 13.3438
3076789 | -2620 | -13250 | dd | B | 17390 | 13.3438 | Pset_Pieters - Comments: do not count
3077067 | -220 | -7250 | p | A | 13790 | 10.5164
3077168 | -220 | -7250 | p | A | 13790 | 10.5164
3101936 | -2080 | -10750 | g | C | 15430 | 11.8044 | BaseQuantities - CrossSectionArea: 785399 mm2; OuterSurfaceArea: 47218138 mm2; GrossSurfaceArea: 48788935 mm2; GrossVolume: 11.8045 m3
3890612 | -870 | -7250 | b | A | 13140 | 10.0059
3890623 | -870 | -7250 | b | A | 13140 | 10.0059
3890634 | -870 | -7250 | b | A | 13140 | 10.0059
3895916 | -4520 | -13250 | r | B | 15490 | 11.8516
3959790 | -870 | -7250 | b | A | 13140 | 10.0059
4512405 | -5380 | -7250 | v | A | 8630 | 6.46378

# IfcPile: 17_PBT_SFO_paal_rond:Ø1600 (jetgroutpaal) jetgroutlichaam merk B (6)
In: -2 kelder
Classification: 17.21 paalfunderingen - geheid, dragende palen (Uniformat); Material: 00_PBT_MAT_grout
Pset_ProductRequirements - Category: Structural Foundations
Pset_QuantityTakeOff - Reference: 17_PBT_SFO_paal_rond:Ø1600 (jetgroutpaal) jetgroutlichaam merk B
Pset_Pieters - Dragend/niet dragend: yes; In/uitwendig: yes; Breedte/Diameter: 1600 mm; Bouwlaag: Level: NAP; Naamgeving element: 17_PBT_SFO_paal_rond: Ø1600 (jetgroutpaal) jetgroutlichaam merk B; Codering - NL-SfB: 17.21; Omschrijving NL-SfB: paalfunderingen - geheid, dragende palen; Fase: Nieuw; Materiaal: 00_PBT_MAT_grout; Description: Jetgroutlichaam; Type Comments: 11 m2; O.k. fundering t.o.v. Peil: -5140 mm; Paalpuntniveau tov NAP: -7000 mm; Paalcode afhakniveau: u; Paalcode paalpuntniveau: G
BaseQuantities - Length: 8620 mm; NetVolume: 16.5273 m3
Name (17_PBT_SFO_paal_rond:Ø1600 (jetgroutpaal) jetgroutlichaam merk B:...)
3051846 | BaseQuantities - CrossSectionArea: 2010611 mm2; OuterSurfaceArea: 41318227 mm2; GrossSurfaceArea: 45339449 mm2; GrossVolume: 16.5272 m3
3051883
3051920
3051990
3052025
3052086

# IfcPile: 17_PBT_SFO_paal_rond:Ø1600 (jetgroutpaal) jetgroutlichaam merk D (9)
In: -2 kelder
Classification: 17.21 paalfunderingen - geheid, dragende palen (Uniformat); Material: 00_PBT_MAT_grout
Pset_ProductRequirements - Category: Structural Foundations
Pset_QuantityTakeOff - Reference: 17_PBT_SFO_paal_rond:Ø1600 (jetgroutpaal) jetgroutlichaam merk D
Pset_Pieters - Dragend/niet dragend: yes; In/uitwendig: yes; Breedte/Diameter: 1600 mm; Bouwlaag: Level: NAP; Naamgeving element: 17_PBT_SFO_paal_rond: Ø1600 (jetgroutpaal) jetgroutlichaam merk D; Codering - NL-SfB: 17.21; Omschrijving NL-SfB: paalfunderingen - geheid, dragende palen; Fase: Nieuw; Materiaal: 00_PBT_MAT_grout; Description: Jetgroutlichaam; Type Comments: 12 m2; O.k. fundering t.o.v. Peil: -3740 mm; Paalpuntniveau tov NAP: -7000 mm; Paalcode afhakniveau: p; Paalcode paalpuntniveau: G
BaseQuantities - Length: 10020 mm; NetVolume: 19.3422 m3
Name (17_PBT_SFO_paal_rond:Ø1600 (jetgroutpaal) jetgroutlichaam merk D:...)
3051670 | BaseQuantities - CrossSectionArea: 2010611 mm2; OuterSurfaceArea: 48355394 mm2; GrossSurfaceArea: 52376617 mm2; GrossVolume: 19.3421 m3
3051750
3051777
3051779
3051790
3051792
4550206
4550208
4550210

# IfcPile: 17_PBT_SFO_paal_rond:Ø219-390 (Casing-draaipaal)_bestaand (8)
In: -2 kelder
Classification: 17.21 paalfunderingen - geheid, dragende palen (Uniformat); Material: <Unnamed>
Pset_ProductRequirements - Category: Structural Foundations
Pset_QuantityTakeOff - Reference: 17_PBT_SFO_paal_rond:Ø219-390 (Casing-draaipaal)_bestaand
Pset_Pieters - Dragend/niet dragend: yes; In/uitwendig: yes; Breedte/Diameter: 219 mm; Bouwlaag: Level: NAP; Naamgeving element: 17_PBT_SFO_paal_rond: Ø219-390 (Casing-draaipaal)_bestaand; Codering - NL-SfB: 17.21; Omschrijving NL-SfB: paalfunderingen - geheid, dragende palen; Fase: Bestaand; Description: Casing-draaipaal; O.k. fundering t.o.v. Peil: -740 mm; Paalpuntniveau tov NAP: -2000 mm; Paalcode afhakniveau: e; Paalcode paalpuntniveau: A
BaseQuantities - Length: 8020 mm; NetVolume: 0.28702 m3
Name (17_PBT_SFO_paal_rond:Ø219-390 (Casing-draaipaal)_bestaand:...)
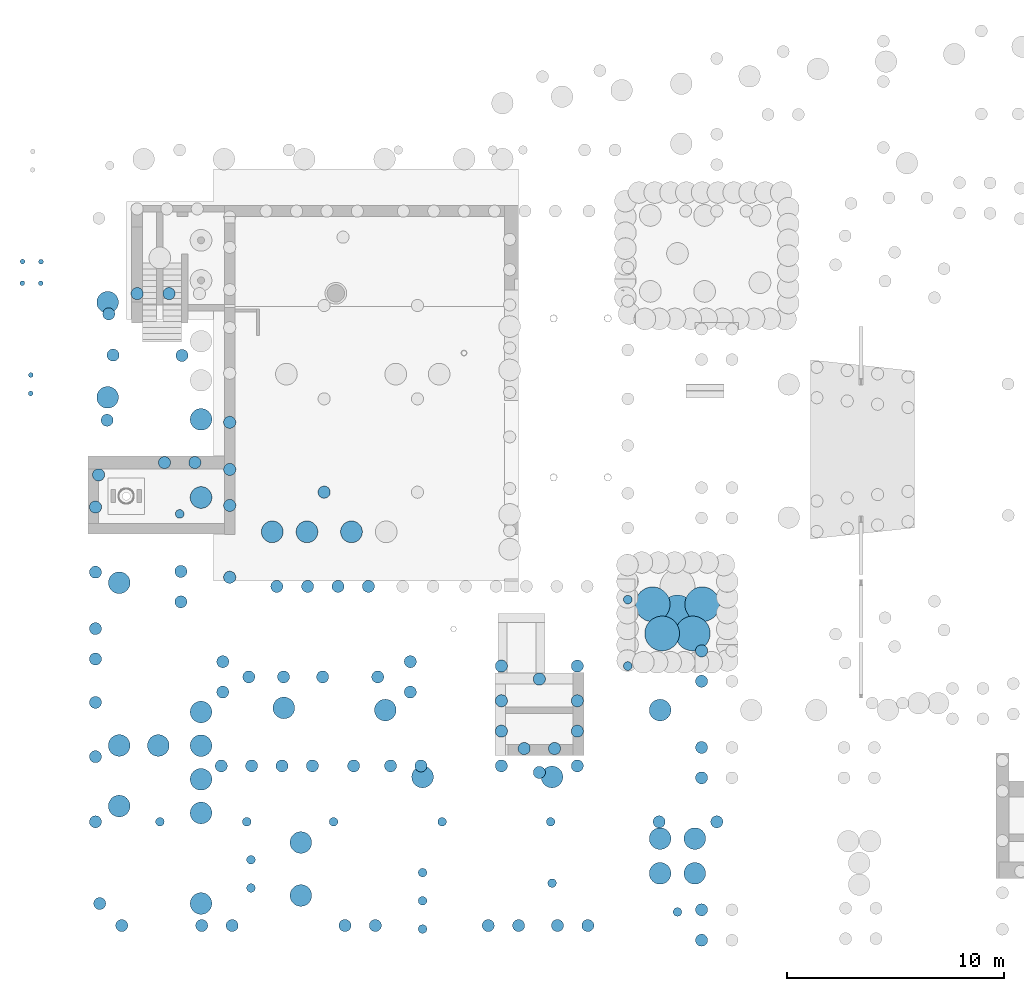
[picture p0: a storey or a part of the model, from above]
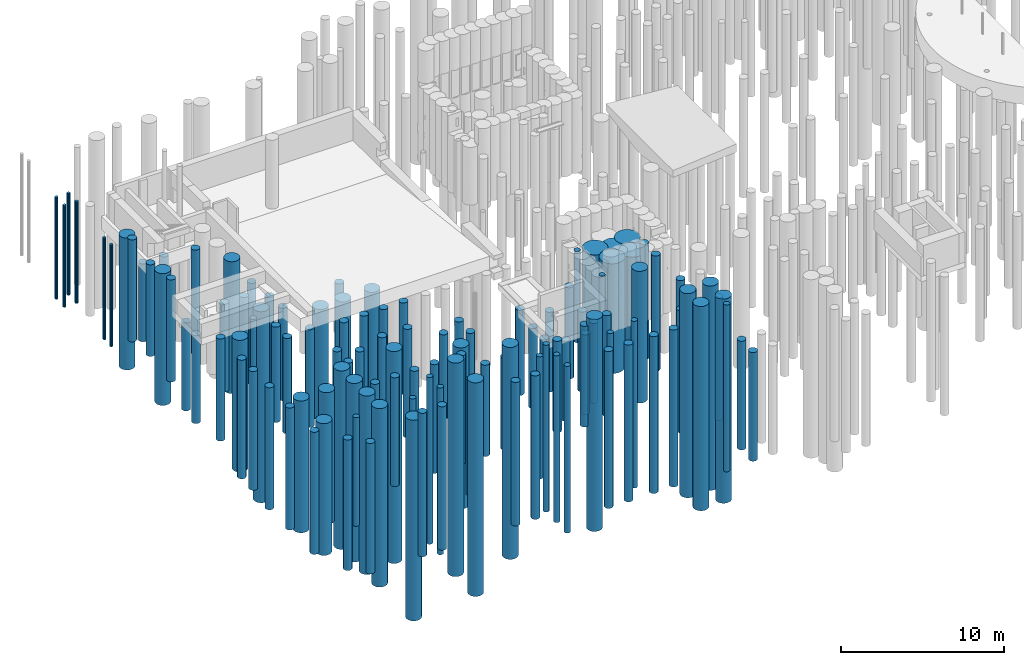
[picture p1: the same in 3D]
Properties of the parts of a building model (IFC2X3), part 13 of 18

# IfcPile: 17_PBT_SFO_paal_rond:Ø219-390 (Casing-draaipaal)_bestaand (8)
Name (17_PBT_SFO_paal_rond:Ø219-390 (Casing-draaipaal)_bestaand:...)
6073314 | BaseQuantities - CrossSectionArea: 37663.4 mm2; OuterSurfaceArea: 5242627 mm2; GrossSurfaceArea: 5317954 mm2; GrossVolume: 0.286995 m3
6073393
6073576
6073578
6073967
6073978
6073991
6074002

# IfcPile: 17_PBT_SFO_paal_rond:Ø400 (Avegaarpaal) (19)
In: -2 kelder
Classification: 17.21 paalfunderingen - geheid, dragende palen (Uniformat); Material: <Unnamed>
Pset_ProductRequirements - Category: Structural Foundations
Pset_QuantityTakeOff - Reference: 17_PBT_SFO_paal_rond:Ø400 (Avegaarpaal)
Pset_Pieters - Dragend/niet dragend: yes; In/uitwendig: yes; Breedte/Diameter: 400 mm; Bouwlaag: Level: NAP; Naamgeving element: 17_PBT_SFO_paal_rond: Ø400 (Avegaarpaal); Codering - NL-SfB: 17.21; Omschrijving NL-SfB: paalfunderingen - geheid, dragende palen; Fase: Nieuw; Description: Avegaarpaal; Paalpuntniveau tov NAP: -7250 mm; Paalcode paalpuntniveau: A
Name (17_PBT_SFO_paal_rond:Ø400 (Avegaarpaal):...) | O.k. fundering t.o.v. Peil (mm) | Paalcode afhakniveau | Length (mm) | NetVolume (m3)
3039566 | -4520 | r | 9490 | 1.14224 | BaseQuantities - CrossSectionArea: 125659 mm2; OuterSurfaceArea: 11422831 mm2; GrossSurfaceArea: 11674149 mm2; GrossVolume: 1.14224 m3
3039728 | -3050 | k | 10960 | 1.32696 | BaseQuantities - CrossSectionArea: 125659 mm2; OuterSurfaceArea: 13270087 mm2; GrossSurfaceArea: 13521406 mm2; GrossVolume: 1.32696 m3
3039808 | -3050 | k | 10960 | 1.32696
3044397 | -1115 | e | 12895 | 1.57011 | BaseQuantities - CrossSectionArea: 125659 mm2; OuterSurfaceArea: 15701680 mm2; GrossSurfaceArea: 15952998 mm2; GrossVolume: 1.57011 m3
3044478 | -1115 | e | 12895 | 1.57011
3044561 | -1115 | e | 12895 | 1.57011
3397940 | -970 | q | 13040 | 1.58833 | BaseQuantities - CrossSectionArea: 125659 mm2; OuterSurfaceArea: 15883892 mm2; GrossSurfaceArea: 16135211 mm2; GrossVolume: 1.58833 m3
3397961 | -970 | q | 13040 | 1.58833
3854367 | -970 | q | 13040 | 1.58833
3894391 | -1115 | e | 12895 | 1.57011
3894559 | -1115 | e | 12895 | 1.57011
3894571 | -1115 | e | 12895 | 1.57011
3895607 | -3050 | k | 10960 | 1.32696
3895619 | -3050 | k | 10960 | 1.32696
3895882 | -3050 | k | 10960 | 1.32696
3896039 | -970 | q | 13040 | 1.58833
3896103 | -970 | q | 13040 | 1.58833
3896971 | -4520 | r | 9490 | 1.14224
4475075 | -1115 | e | 12895 | 1.57011

# IfcPile: 17_PBT_SFO_paal_rond:Ø400 (betonpaal)_bestaand (28)
In: -2 kelder
Classification: 17.21 paalfunderingen - geheid, dragende palen (Uniformat); Material: <Unnamed>
Pset_ProductRequirements - Category: Structural Foundations
Pset_QuantityTakeOff - Reference: 17_PBT_SFO_paal_rond:Ø400 (betonpaal)_bestaand
Pset_Pieters - Dragend/niet dragend: yes; In/uitwendig: yes; Breedte/Diameter: 400 mm; Bouwlaag: Level: NAP; Naamgeving element: 17_PBT_SFO_paal_rond: Ø400 (betonpaal)_bestaand; Codering - NL-SfB: 17.21; Omschrijving NL-SfB: paalfunderingen - geheid, dragende palen; Fase: Bestaand; Description: Betonpaal
Name (17_PBT_SFO_paal_rond:Ø400 (betonpaal)_bestaand:...) | O.k. fundering t.o.v. Peil (mm) | Paalpuntniveau tov NAP (mm) | Length (mm) | NetVolume (m3)
1700020 | -1020 | -5000 | 10740 | 1.29932 | Pset_Pieters - Comments: paal inkorten vanaf -800; BaseQuantities - CrossSectionArea: 125659 mm2; OuterSurfaceArea: 12993627 mm2; GrossSurfaceArea: 13244945 mm2; GrossVolume: 1.29932 m3
1701802 | -5280 | -6000 | 7480 | 0.889668 | BaseQuantities - CrossSectionArea: 125659 mm2; OuterSurfaceArea: 8896990 mm2; GrossSurfaceArea: 9148309 mm2; GrossVolume: 0.889666 m3
1702358 | -3720 | -5500 | 8540 | 1.02287 | BaseQuantities - CrossSectionArea: 125659 mm2; OuterSurfaceArea: 10229026 mm2; GrossSurfaceArea: 10480344 mm2; GrossVolume: 1.02287 m3
1702516 | -3720 | -5500 | 8540 | 1.02287
1702561 | -3720 | -6000 | 9040 | 1.0857 | BaseQuantities - CrossSectionArea: 125659 mm2; OuterSurfaceArea: 10857344 mm2; GrossSurfaceArea: 11108662 mm2; GrossVolume: 1.08569 m3
1702572 | -3720 | -6500 | 9540 | 1.14853 | BaseQuantities - CrossSectionArea: 125659 mm2; OuterSurfaceArea: 11485663 mm2; GrossSurfaceArea: 11736981 mm2; GrossVolume: 1.14852 m3
1702585 | -3720 | -6500 | 9540 | 1.14853
1703544 | -5020 | -5500 | 7240 | 0.859509 | BaseQuantities - CrossSectionArea: 125659 mm2; OuterSurfaceArea: 8595398 mm2; GrossSurfaceArea: 8846716 mm2; GrossVolume: 0.859508 m3
1703610 | -5020 | -5500 | 7240 | 0.859509
1704783 | -890 | -6000 | 11870 | 1.44131 | Pset_Pieters - Comments: paal inkorten vanaf -800; BaseQuantities - CrossSectionArea: 125659 mm2; OuterSurfaceArea: 14413627 mm2; GrossSurfaceArea: 14664945 mm2; GrossVolume: 1.44131 m3
1704794 | -1020 | -6000 | 11740 | 1.42498 | Pset_Pieters - Comments: paal inkorten vanaf -800; BaseQuantities - CrossSectionArea: 125659 mm2; OuterSurfaceArea: 14250264 mm2; GrossSurfaceArea: 14501582 mm2; GrossVolume: 1.42497 m3
1704877 | -1020 | -6000 | 11740 | 1.42498 | Pset_Pieters - Comments: paal inkorten vanaf -800
1711527 | -330 | -6500 | 12930 | 1.57451 | BaseQuantities - CrossSectionArea: 125659 mm2; OuterSurfaceArea: 15745662 mm2; GrossSurfaceArea: 15996981 mm2; GrossVolume: 1.57451 m3
1718978 | -4220 | -6750 | 9290 | 1.11711 | BaseQuantities - CrossSectionArea: 125659 mm2; OuterSurfaceArea: 11171503 mm2; GrossSurfaceArea: 11422822 mm2; GrossVolume: 1.11711 m3
1718991 | -4220 | -6750 | 9290 | 1.11711
1720070 | -4220 | -6750 | 9290 | 1.11711
1720092 | -4220 | -6750 | 9290 | 1.11711
1721979 | -330 | -1500 | 7930 | 0.946214 | BaseQuantities - CrossSectionArea: 125659 mm2; OuterSurfaceArea: 9462477 mm2; GrossSurfaceArea: 9713795 mm2; GrossVolume: 0.946213 m3
1722030 | -330 | -1500 | 7930 | 0.946214
1722068 | -330 | -1500 | 7930 | 0.946214
1722081 | -330 | -1500 | 7930 | 0.946214
1722221 | -330 | -1500 | 7930 | 0.946214
1722232 | -330 | -1500 | 7930 | 0.946214
1722245 | -330 | -1500 | 7930 | 0.946214
1722585 | -4420 | -4500 | 6840 | 0.809246 | Pset_Pieters - Comments: paal inkorten vanaf -3040; BaseQuantities - CrossSectionArea: 125659 mm2; OuterSurfaceArea: 8092743 mm2; GrossSurfaceArea: 8344061 mm2; GrossVolume: 0.809245 m3
1722887 | -3020 | -5500 | 9240 | 1.11083 | BaseQuantities - CrossSectionArea: 125659 mm2; OuterSurfaceArea: 11108672 mm2; GrossSurfaceArea: 11359990 mm2; GrossVolume: 1.11083 m3
1722950 | -3020 | -5500 | 9240 | 1.11083
1723766 | -3020 | -6500 | 10240 | 1.23649 | BaseQuantities - CrossSectionArea: 125659 mm2; OuterSurfaceArea: 12365309 mm2; GrossSurfaceArea: 12616627 mm2; GrossVolume: 1.23649 m3

# IfcPile: 17_PBT_SFO_paal_rond:Ø560 (betonpaal)_bestaand (372)
In: -2 kelder
Classification: 17.21 paalfunderingen - geheid, dragende palen (Uniformat); Material: <Unnamed>
Pset_ProductRequirements - Category: Structural Foundations
Pset_QuantityTakeOff - Reference: 17_PBT_SFO_paal_rond:Ø560 (betonpaal)_bestaand
Pset_Pieters - Dragend/niet dragend: yes; In/uitwendig: yes; Breedte/Diameter: 560 mm; Bouwlaag: Level: NAP; Naamgeving element: 17_PBT_SFO_paal_rond: Ø560 (betonpaal)_bestaand; Codering - NL-SfB: 17.21; Omschrijving NL-SfB: paalfunderingen - geheid, dragende palen; Fase: Bestaand; Description: Betonpaal
Name (17_PBT_SFO_paal_rond:Ø560 (betonpaal)_bestaand:...) | O.k. fundering t.o.v. Peil (mm) | Paalpuntniveau tov NAP (mm) | Length (mm) | NetVolume (m3)
1700195 | -3720 | -5600 | 8640 | 2.02948 | BaseQuantities - CrossSectionArea: 246286 mm2; OuterSurfaceArea: 14496565 mm2; GrossSurfaceArea: 14989136 mm2; GrossVolume: 2.02939 m3
1700560 | -6540 | -6000 | 6220 | 1.43344 | BaseQuantities - CrossSectionArea: 246286 mm2; OuterSurfaceArea: 10239079 mm2; GrossSurfaceArea: 10731650 mm2; GrossVolume: 1.43338 m3
1700595 | -6540 | -6000 | 6220 | 1.43344
1700604 | -6540 | -6000 | 6220 | 1.43344
1700713 | -6540 | -7000 | 7220 | 1.67974 | BaseQuantities - CrossSectionArea: 246286 mm2; OuterSurfaceArea: 11998371 mm2; GrossSurfaceArea: 12490942 mm2; GrossVolume: 1.67967 m3
1700794 | -6540 | -6000 | 6220 | 1.43344
1700796 | -6540 | -6000 | 6220 | 1.43344
1700798 | -6540 | -6000 | 6220 | 1.43344
1700838 | -6540 | -7000 | 7220 | 1.67974
1700849 | -6540 | -7000 | 7220 | 1.67974
1700862 | -6421 | -7000 | 7339 | 1.70905 | BaseQuantities - CrossSectionArea: 246286 mm2; OuterSurfaceArea: 12207726 mm2; GrossSurfaceArea: 12700298 mm2; GrossVolume: 1.70898 m3
1700916 | -6167 | -6500 | 7093 | 1.64846 | BaseQuantities - CrossSectionArea: 246286 mm2; OuterSurfaceArea: 11774941 mm2; GrossSurfaceArea: 12267512 mm2; GrossVolume: 1.64839 m3
1700965 | -3720 | -5000 | 8040 | 1.8817 | BaseQuantities - CrossSectionArea: 246286 mm2; OuterSurfaceArea: 13440990 mm2; GrossSurfaceArea: 13933561 mm2; GrossVolume: 1.88162 m3
1701147 | -4500 | -5000 | 7260 | 1.68959 | BaseQuantities - CrossSectionArea: 246286 mm2; OuterSurfaceArea: 12068742 mm2; GrossSurfaceArea: 12561313 mm2; GrossVolume: 1.68952 m3
1701262 | -4500 | -6000 | 8260 | 1.93589 | BaseQuantities - CrossSectionArea: 246286 mm2; OuterSurfaceArea: 13828034 mm2; GrossSurfaceArea: 14320605 mm2; GrossVolume: 1.9358 m3
1701346 | -3720 | -5000 | 8040 | 1.8817
1701357 | -5280 | -5500 | 6980 | 1.62063 | BaseQuantities - CrossSectionArea: 246286 mm2; OuterSurfaceArea: 11576141 mm2; GrossSurfaceArea: 12068712 mm2; GrossVolume: 1.62056 m3
1701584 | -5897 | -6000 | 6863 | 1.59181 | BaseQuantities - CrossSectionArea: 246286 mm2; OuterSurfaceArea: 11370303 mm2; GrossSurfaceArea: 11862875 mm2; GrossVolume: 1.59174 m3
1701595 | -5636 | -6000 | 7124 | 1.65609 | BaseQuantities - CrossSectionArea: 246286 mm2; OuterSurfaceArea: 11829479 mm2; GrossSurfaceArea: 12322050 mm2; GrossVolume: 1.65602 m3
1701606 | -5437 | -6000 | 7323 | 1.70511 | BaseQuantities - CrossSectionArea: 246286 mm2; OuterSurfaceArea: 12179578 mm2; GrossSurfaceArea: 12672149 mm2; GrossVolume: 1.70503 m3
1701659 | -5039 | -6000 | 7721 | 1.80313 | BaseQuantities - CrossSectionArea: 246286 mm2; OuterSurfaceArea: 12879776 mm2; GrossSurfaceArea: 13372347 mm2; GrossVolume: 1.80306 m3
1701698 | -5280 | -5500 | 6980 | 1.62063
1701767 | -5280 | -5500 | 6980 | 1.62063
1701859 | -4220 | -5000 | 7540 | 1.75855 | BaseQuantities - CrossSectionArea: 246286 mm2; OuterSurfaceArea: 12561344 mm2; GrossSurfaceArea: 13053915 mm2; GrossVolume: 1.75848 m3
1701904 | -4220 | -5000 | 7540 | 1.75855
1701958 | -5280 | -5500 | 6980 | 1.62063
1702015 | -3720 | -5000 | 8040 | 1.8817
1702026 | -3720 | -6250 | 9290 | 2.18957 | BaseQuantities - CrossSectionArea: 246286 mm2; OuterSurfaceArea: 15640105 mm2; GrossSurfaceArea: 16132676 mm2; GrossVolume: 2.18948 m3
1702067 | -3720 | -6250 | 9290 | 2.18957
1702105 | -3720 | -6500 | 9540 | 2.25115 | BaseQuantities - CrossSectionArea: 246286 mm2; OuterSurfaceArea: 16079928 mm2; GrossSurfaceArea: 16572499 mm2; GrossVolume: 2.25105 m3
1702116 | -3720 | -6500 | 9540 | 2.25115
1702127 | -3720 | -6500 | 9540 | 2.25115
1702138 | -2080 | -5500 | 10180 | 2.40878 | BaseQuantities - CrossSectionArea: 246286 mm2; OuterSurfaceArea: 17205875 mm2; GrossSurfaceArea: 17698446 mm2; GrossVolume: 2.40867 m3; Pset_Pieters - Comments: paal inkorten vanaf -960
1702313 | -2080 | -5500 | 10180 | 2.40878 | Pset_Pieters - Comments: paal inkorten vanaf -960
1702367 | -1115 | -5500 | 11145 | 2.64645 | BaseQuantities - CrossSectionArea: 246286 mm2; OuterSurfaceArea: 18903591 mm2; GrossSurfaceArea: 19396162 mm2; GrossVolume: 2.64634 m3; Pset_Pieters - Comments: paal inkorten vanaf -960
1702378 | -1115 | -5500 | 11145 | 2.64645 | Pset_Pieters - Comments: paal inkorten vanaf -960
1702637 | -1115 | -5500 | 11145 | 2.64645 | Pset_Pieters - Comments: paal inkorten vanaf -960
1702639 | -1115 | -5500 | 11145 | 2.64645 | Pset_Pieters - Comments: paal inkorten vanaf -960
1702652 | -1115 | -6500 | 12145 | 2.89275 | BaseQuantities - CrossSectionArea: 246286 mm2; OuterSurfaceArea: 20662883 mm2; GrossSurfaceArea: 21155454 mm2; GrossVolume: 2.89262 m3; Pset_Pieters - Comments: paal inkorten vanaf -960
1702654 | -1115 | -6500 | 12145 | 2.89275 | Pset_Pieters - Comments: paal inkorten vanaf -960
1702665 | -1115 | -6500 | 12145 | 2.89275 | Pset_Pieters - Comments: paal inkorten vanaf -960
1702667 | -1115 | -6500 | 12145 | 2.89275 | Pset_Pieters - Comments: paal inkorten vanaf -960
1702694 | -3720 | -5500 | 8540 | 2.00485 | BaseQuantities - CrossSectionArea: 246286 mm2; OuterSurfaceArea: 14320636 mm2; GrossSurfaceArea: 14813207 mm2; GrossVolume: 2.00476 m3
1702771 | -3720 | -5500 | 8540 | 2.00485
1702780 | -3720 | -5500 | 8540 | 2.00485
1702789 | -3720 | -5500 | 8540 | 2.00485
1702798 | -3720 | -5500 | 8540 | 2.00485
1702831 | -5020 | -5500 | 7240 | 1.68466 | BaseQuantities - CrossSectionArea: 246286 mm2; OuterSurfaceArea: 12033557 mm2; GrossSurfaceArea: 12526128 mm2; GrossVolume: 1.68459 m3
1702840 | -5020 | -5500 | 7240 | 1.68466
1702849 | -5020 | -5500 | 7240 | 1.68466
1702938 | -4320 | -5500 | 7940 | 1.85707 | BaseQuantities - CrossSectionArea: 246286 mm2; OuterSurfaceArea: 13265061 mm2; GrossSurfaceArea: 13757632 mm2; GrossVolume: 1.85699 m3
1702947 | -4320 | -5500 | 7940 | 1.85707
1703002 | -5880 | -5500 | 6380 | 1.47285 | BaseQuantities - CrossSectionArea: 246286 mm2; OuterSurfaceArea: 10520565 mm2; GrossSurfaceArea: 11013137 mm2; GrossVolume: 1.47279 m3
1703029 | -5880 | -5500 | 6380 | 1.47285
1703084 | -5880 | -5500 | 6380 | 1.47285
1703086 | -5880 | -5500 | 6380 | 1.47285
1703097 | -5880 | -5500 | 6380 | 1.47285
1703099 | -5880 | -5500 | 6380 | 1.47285
1703129 | -5480 | -5500 | 6780 | 1.57137 | BaseQuantities - CrossSectionArea: 246286 mm2; OuterSurfaceArea: 11224282 mm2; GrossSurfaceArea: 11716853 mm2; GrossVolume: 1.5713 m3
1703131 | -5020 | -5500 | 7240 | 1.68466
1703156 | -5880 | -5500 | 6380 | 1.47285
1703193 | -4220 | -5500 | 8040 | 1.8817 | BaseQuantities - CrossSectionArea: 246286 mm2; OuterSurfaceArea: 13440990 mm2; GrossSurfaceArea: 13933561 mm2; GrossVolume: 1.88162 m3
1703226 | -4220 | -5500 | 8040 | 1.8817
1703237 | -4220 | -5500 | 8040 | 1.8817
1703284 | -3720 | -5500 | 8540 | 2.00485
1703293 | -3720 | -5500 | 8540 | 2.00485
1703306 | -5020 | -5000 | 6740 | 1.56152 | BaseQuantities - CrossSectionArea: 246286 mm2; OuterSurfaceArea: 11153911 mm2; GrossSurfaceArea: 11646482 mm2; GrossVolume: 1.56145 m3
1703317 | -5020 | -5000 | 6740 | 1.56152
1703328 | -5020 | -5000 | 6740 | 1.56152
1703402 | -5020 | -6000 | 7740 | 1.80781 | BaseQuantities - CrossSectionArea: 246286 mm2; OuterSurfaceArea: 12913202 mm2; GrossSurfaceArea: 13405774 mm2; GrossVolume: 1.80774 m3
1703413 | -5020 | -6000 | 7740 | 1.80781
1703422 | -5020 | -6000 | 7740 | 1.80781
1703466 | -5020 | -5500 | 7240 | 1.68466
1703475 | -5020 | -5000 | 6740 | 1.56152
1703484 | -5020 | -5000 | 6740 | 1.56152
1703495 | -5020 | -5000 | 6740 | 1.56152
1703504 | -5020 | -5500 | 7240 | 1.68466
1703515 | -5020 | -5500 | 7240 | 1.68466
1703524 | -5020 | -5500 | 7240 | 1.68466
1703535 | -5020 | -5500 | 7240 | 1.68466
1703866 | -5510 | -6000 | 7250 | 1.68713 | BaseQuantities - CrossSectionArea: 246286 mm2; OuterSurfaceArea: 12051149 mm2; GrossSurfaceArea: 12543721 mm2; GrossVolume: 1.68706 m3
1703898 | -5510 | -6000 | 7250 | 1.68713
1703933 | -6008 | -7000 | 7752 | 1.81077 | BaseQuantities - CrossSectionArea: 246286 mm2; OuterSurfaceArea: 12934314 mm2; GrossSurfaceArea: 13426885 mm2; GrossVolume: 1.81069 m3
1703935 | -6008 | -7000 | 7752 | 1.81077
1703946 | -6540 | -7000 | 7220 | 1.67974
1703948 | -6540 | -7000 | 7220 | 1.67974
1704055 | -6540 | -7000 | 7220 | 1.67974
1704086 | -6540 | -7000 | 7220 | 1.67974
1704095 | -6540 | -7000 | 7220 | 1.67974
1704104 | -6540 | -7000 | 7220 | 1.67974
1704119 | -6540 | -7000 | 7220 | 1.67974
1704128 | -6540 | -5500 | 5720 | 1.31029 | BaseQuantities - CrossSectionArea: 246286 mm2; OuterSurfaceArea: 9359433 mm2; GrossSurfaceArea: 9852004 mm2; GrossVolume: 1.31024 m3
1704137 | -6540 | -5500 | 5720 | 1.31029
1704146 | -6540 | -5500 | 5720 | 1.31029
1704161 | -3720 | -5500 | 8540 | 2.00485
1704170 | -3720 | -5500 | 8540 | 2.00485
1704179 | -3720 | -5500 | 8540 | 2.00485
1704217 | -6540 | -7000 | 7220 | 1.67974
1704266 | -6540 | -5500 | 5720 | 1.31029
1704324 | -6540 | -5500 | 5720 | 1.31029
1704335 | -6540 | -5500 | 5720 | 1.31029
1704346 | -6298 | -5500 | 5962 | 1.3699 | BaseQuantities - CrossSectionArea: 246286 mm2; OuterSurfaceArea: 9785181 mm2; GrossSurfaceArea: 10277753 mm2; GrossVolume: 1.36984 m3
1704357 | -6063 | -5500 | 6197 | 1.42778 | BaseQuantities - CrossSectionArea: 246286 mm2; OuterSurfaceArea: 10198615 mm2; GrossSurfaceArea: 10691186 mm2; GrossVolume: 1.42772 m3
1704368 | -5816 | -5500 | 6444 | 1.48861 | BaseQuantities - CrossSectionArea: 246286 mm2; OuterSurfaceArea: 10633160 mm2; GrossSurfaceArea: 11125731 mm2; GrossVolume: 1.48855 m3
1704379 | -5560 | -5500 | 6700 | 1.55166 | BaseQuantities - CrossSectionArea: 246286 mm2; OuterSurfaceArea: 11083539 mm2; GrossSurfaceArea: 11576110 mm2; GrossVolume: 1.5516 m3
1704392 | -5298 | -5500 | 6962 | 1.61619 | BaseQuantities - CrossSectionArea: 246286 mm2; OuterSurfaceArea: 11544473 mm2; GrossSurfaceArea: 12037044 mm2; GrossVolume: 1.61613 m3
1704513 | -3720 | -6000 | 9040 | 2.128 | BaseQuantities - CrossSectionArea: 246286 mm2; OuterSurfaceArea: 15200282 mm2; GrossSurfaceArea: 15692853 mm2; GrossVolume: 2.12791 m3
1704561 | -5020 | -6000 | 7740 | 1.80781
1704602 | -5020 | -6000 | 7740 | 1.80781
1704635 | -5020 | -5500 | 7240 | 1.68466
1704646 | -5020 | -5500 | 7240 | 1.68466
1704657 | -5020 | -5500 | 7240 | 1.68466
1704668 | -3720 | -5500 | 8540 | 2.00485
1704720 | -1020 | -5000 | 10740 | 2.5467 | BaseQuantities - CrossSectionArea: 246286 mm2; OuterSurfaceArea: 18191078 mm2; GrossSurfaceArea: 18683649 mm2; GrossVolume: 2.54659 m3; Pset_Pieters - Comments: paal inkorten vanaf -800
1704772 | -1020 | -6000 | 11740 | 2.793 | BaseQuantities - CrossSectionArea: 246286 mm2; OuterSurfaceArea: 19950370 mm2; GrossSurfaceArea: 20442941 mm2; GrossVolume: 2.79288 m3; Pset_Pieters - Comments: paal inkorten vanaf -800
1704918 | -890 | -6000 | 11870 | 2.82502 | BaseQuantities - CrossSectionArea: 246286 mm2; OuterSurfaceArea: 20179078 mm2; GrossSurfaceArea: 20671649 mm2; GrossVolume: 2.8249 m3; Pset_Pieters - Comments: paal inkorten vanaf -800
1705007 | -890 | -6000 | 11870 | 2.82502 | Pset_Pieters - Comments: paal inkorten vanaf -800
1705047 | -5480 | -6000 | 7280 | 1.69452 | BaseQuantities - CrossSectionArea: 246286 mm2; OuterSurfaceArea: 12103928 mm2; GrossSurfaceArea: 12596499 mm2; GrossVolume: 1.69444 m3; Pset_Pieters - Comments: paal inkorten vanaf -800
1705082 | -5480 | -6000 | 7280 | 1.69452 | Pset_Pieters - Comments: paal inkorten vanaf -800
1705117 | -6680 | -6000 | 6080 | 1.39896 | BaseQuantities - CrossSectionArea: 246286 mm2; OuterSurfaceArea: 9992778 mm2; GrossSurfaceArea: 10485349 mm2; GrossVolume: 1.3989 m3; Pset_Pieters - Comments: paal inkorten vanaf -3740
1705128 | -6680 | -6000 | 6080 | 1.39896 | Pset_Pieters - Comments: paal inkorten vanaf -3740
1705139 | -5380 | -6000 | 7380 | 1.71915 | BaseQuantities - CrossSectionArea: 246286 mm2; OuterSurfaceArea: 12279857 mm2; GrossSurfaceArea: 12772428 mm2; GrossVolume: 1.71907 m3; Pset_Pieters - Comments: paal inkorten vanaf -3740
1705166 | -4220 | -7000 | 9540 | 2.25115 | BaseQuantities - CrossSectionArea: 246286 mm2; OuterSurfaceArea: 16079928 mm2; GrossSurfaceArea: 16572499 mm2; GrossVolume: 2.25105 m3
1705168 | -4220 | -7000 | 9540 | 2.25115
1705201 | -4220 | -7000 | 9540 | 2.25115
1705203 | -4220 | -7000 | 9540 | 2.25115
1705230 | -4220 | -4500 | 7040 | 1.63541 | BaseQuantities - CrossSectionArea: 246286 mm2; OuterSurfaceArea: 11681698 mm2; GrossSurfaceArea: 12174269 mm2; GrossVolume: 1.63534 m3
1705232 | -4220 | -4500 | 7040 | 1.63541
1705234 | -4220 | -4500 | 7040 | 1.63541
1705236 | -4220 | -4500 | 7040 | 1.63541
1705247 | -4220 | -6500 | 9040 | 2.128 | BaseQuantities - CrossSectionArea: 246286 mm2; OuterSurfaceArea: 15200282 mm2; GrossSurfaceArea: 15692853 mm2; GrossVolume: 2.12791 m3
1705249 | -4220 | -6500 | 9040 | 2.128
1705251 | -4220 | -6500 | 9040 | 2.128
1705253 | -4220 | -6500 | 9040 | 2.128
1705264 | -4220 | -6500 | 9040 | 2.128
1705266 | -4220 | -6500 | 9040 | 2.128
1705268 | -4220 | -6500 | 9040 | 2.128
1705270 | -4220 | -6500 | 9040 | 2.128
1705427 | -4220 | -6000 | 8540 | 2.00485 | BaseQuantities - CrossSectionArea: 246286 mm2; OuterSurfaceArea: 14320636 mm2; GrossSurfaceArea: 14813207 mm2; GrossVolume: 2.00476 m3
1705429 | -4220 | -6000 | 8540 | 2.00485
1705431 | -4220 | -6000 | 8540 | 2.00485
1705433 | -4220 | -6000 | 8540 | 2.00485
1705496 | -3720 | -6500 | 9540 | 2.25115
1705555 | -3720 | -6500 | 9540 | 2.25115
1708184 | -870 | -6000 | 11890 | 2.82994 | BaseQuantities - CrossSectionArea: 246286 mm2; OuterSurfaceArea: 20214264 mm2; GrossSurfaceArea: 20706835 mm2; GrossVolume: 2.82982 m3; Pset_Pieters - Comments: paal inkorten vanaf -800
1708196 | -870 | -6000 | 11890 | 2.82994 | Pset_Pieters - Comments: paal inkorten vanaf -800
1708246 | -870 | -6000 | 11890 | 2.82994 | Pset_Pieters - Comments: paal inkorten vanaf -800
1709555 | -870 | -6000 | 11890 | 2.82994 | Pset_Pieters - Comments: paal inkorten vanaf -800
1709568 | -870 | -6500 | 12390 | 2.95309 | BaseQuantities - CrossSectionArea: 246286 mm2; OuterSurfaceArea: 21093910 mm2; GrossSurfaceArea: 21586481 mm2; GrossVolume: 2.95296 m3; Pset_Pieters - Comments: paal inkorten vanaf -800
1709581 | -870 | -6500 | 12390 | 2.95309 | Pset_Pieters - Comments: paal inkorten vanaf -800
1709928 | -780 | -6500 | 12480 | 2.97526 | BaseQuantities - CrossSectionArea: 246286 mm2; OuterSurfaceArea: 21252246 mm2; GrossSurfaceArea: 21744817 mm2; GrossVolume: 2.97513 m3
1709939 | -780 | -6500 | 12480 | 2.97526
1710558 | -5330 | -6000 | 7430 | 1.73146 | BaseQuantities - CrossSectionArea: 246286 mm2; OuterSurfaceArea: 12367822 mm2; GrossSurfaceArea: 12860393 mm2; GrossVolume: 1.73139 m3; Pset_Pieters - Comments: paal inkorten vanaf -800
1710569 | -890 | -6000 | 11870 | 2.82502 | Pset_Pieters - Comments: paal inkorten vanaf -800
1710751 | -780 | -4500 | 10480 | 2.48266 | BaseQuantities - CrossSectionArea: 246286 mm2; OuterSurfaceArea: 17733662 mm2; GrossSurfaceArea: 18226233 mm2; GrossVolume: 2.48256 m3
1710806 | -890 | -4500 | 10370 | 2.45557 | BaseQuantities - CrossSectionArea: 246286 mm2; OuterSurfaceArea: 17540140 mm2; GrossSurfaceArea: 18032711 mm2; GrossVolume: 2.45547 m3; Pset_Pieters - Comments: paal inkorten vanaf -800
1711435 | -780 | -5000 | 10980 | 2.60581 | BaseQuantities - CrossSectionArea: 246286 mm2; OuterSurfaceArea: 18613308 mm2; GrossSurfaceArea: 19105879 mm2; GrossVolume: 2.6057 m3
1711446 | -780 | -5000 | 10980 | 2.60581
1711455 | -780 | -6500 | 12480 | 2.97526
1711468 | -780 | -6500 | 12480 | 2.97526
1711477 | -780 | -6500 | 12480 | 2.97526
1711562 | -780 | -6500 | 12480 | 2.97526
1711629 | -780 | -6500 | 12480 | 2.97526
1711672 | -780 | -6500 | 12480 | 2.97526
1711681 | -780 | -6500 | 12480 | 2.97526
1711692 | -780 | -6500 | 12480 | 2.97526
1711979 | -2620 | -6000 | 10140 | 2.39892 | BaseQuantities - CrossSectionArea: 246286 mm2; OuterSurfaceArea: 17135503 mm2; GrossSurfaceArea: 17628074 mm2; GrossVolume: 2.39882 m3; Pset_Pieters - Comments: paal inkorten vanaf +60
1712048 | -2620 | -6000 | 10140 | 2.39892 | Pset_Pieters - Comments: paal inkorten vanaf +60
1712082 | 80 | -5500 | 12340 | 2.94077 | BaseQuantities - CrossSectionArea: 246286 mm2; OuterSurfaceArea: 21005945 mm2; GrossSurfaceArea: 21498516 mm2; GrossVolume: 2.94065 m3
1712095 | 80 | -5500 | 12340 | 2.94077
1712126 | -3720 | -5500 | 8540 | 2.00485
1712204 | -3720 | -5500 | 8540 | 2.00485
1712213 | -3720 | -5500 | 8540 | 2.00485
1712222 | -3720 | -5500 | 8540 | 2.00485
1712400 | -4220 | -6750 | 9290 | 2.18957 | BaseQuantities - CrossSectionArea: 246286 mm2; OuterSurfaceArea: 15640105 mm2; GrossSurfaceArea: 16132676 mm2; GrossVolume: 2.18948 m3
1712452 | -4220 | -6750 | 9290 | 2.18957
1712556 | -4220 | -6750 | 9290 | 2.18957
1712558 | -4220 | -6750 | 9290 | 2.18957
1712627 | -4220 | -6750 | 9290 | 2.18957
1712640 | -3720 | -6750 | 9790 | 2.31272 | BaseQuantities - CrossSectionArea: 246286 mm2; OuterSurfaceArea: 16519751 mm2; GrossSurfaceArea: 17012322 mm2; GrossVolume: 2.31262 m3
1712690 | -4220 | -6750 | 9290 | 2.18957
1712724 | -3720 | -6750 | 9790 | 2.31272
1712735 | -3720 | -6750 | 9790 | 2.31272
1712800 | -3720 | -6750 | 9790 | 2.31272
1713482 | -4220 | -6500 | 9040 | 2.128
1713493 | -4220 | -6500 | 9040 | 2.128
1714093 | -4220 | -6500 | 9040 | 2.128
1714104 | -4220 | -6500 | 9040 | 2.128
1715302 | -4220 | -6500 | 9040 | 2.128
1715313 | -4220 | -6500 | 9040 | 2.128
1716528 | -4320 | -6500 | 8940 | 2.10337 | BaseQuantities - CrossSectionArea: 246286 mm2; OuterSurfaceArea: 15024353 mm2; GrossSurfaceArea: 15516924 mm2; GrossVolume: 2.10328 m3
1716541 | -4300 | -6500 | 8960 | 2.10829 | BaseQuantities - CrossSectionArea: 246286 mm2; OuterSurfaceArea: 15059539 mm2; GrossSurfaceArea: 15552110 mm2; GrossVolume: 2.1082 m3
1716554 | -4280 | -6500 | 8980 | 2.11322 | BaseQuantities - CrossSectionArea: 246286 mm2; OuterSurfaceArea: 15094724 mm2; GrossSurfaceArea: 15587296 mm2; GrossVolume: 2.11313 m3
1716567 | -4240 | -6500 | 9020 | 2.12307 | BaseQuantities - CrossSectionArea: 246286 mm2; OuterSurfaceArea: 15165096 mm2; GrossSurfaceArea: 15657667 mm2; GrossVolume: 2.12298 m3
1716624 | -4540 | -6500 | 8720 | 2.04918 | BaseQuantities - CrossSectionArea: 246286 mm2; OuterSurfaceArea: 14637308 mm2; GrossSurfaceArea: 15129880 mm2; GrossVolume: 2.0491 m3
1716626 | -4540 | -6500 | 8720 | 2.04918
1716628 | -4520 | -6500 | 8740 | 2.05411 | BaseQuantities - CrossSectionArea: 246286 mm2; OuterSurfaceArea: 14672494 mm2; GrossSurfaceArea: 15165065 mm2; GrossVolume: 2.05402 m3
1716630 | -4500 | -6500 | 8760 | 2.05903 | BaseQuantities - CrossSectionArea: 246286 mm2; OuterSurfaceArea: 14707680 mm2; GrossSurfaceArea: 15200251 mm2; GrossVolume: 2.05895 m3
1716686 | -4540 | -6500 | 8720 | 2.04918
1716708 | -4540 | -6500 | 8720 | 2.04918
1716730 | -4520 | -6500 | 8740 | 2.05411
1716752 | -4500 | -6500 | 8760 | 2.05903
1716774 | -4320 | -6500 | 8940 | 2.10337
1716796 | -4300 | -6500 | 8960 | 2.10829
1716818 | -4280 | -6500 | 8980 | 2.11322
1716840 | -4240 | -6500 | 9020 | 2.12307
1716895 | -4220 | -6500 | 9040 | 2.128
1716917 | -4220 | -6500 | 9040 | 2.128
1716939 | -4220 | -6500 | 9040 | 2.128
1716961 | -4220 | -6500 | 9040 | 2.128
1716983 | -4220 | -6500 | 9040 | 2.128
1717005 | -4220 | -6500 | 9040 | 2.128
1717108 | -3720 | -6500 | 9540 | 2.25115
1717110 | -3720 | -6500 | 9540 | 2.25115
1717167 | -4220 | -5000 | 7540 | 1.75855
1717251 | -4220 | -5000 | 7540 | 1.75855
1717290 | -4220 | -5000 | 7540 | 1.75855
1717316 | -4220 | -5000 | 7540 | 1.75855
1717359 | -4220 | -5000 | 7540 | 1.75855
1717361 | -4220 | -5000 | 7540 | 1.75855
1717412 | -4220 | -6500 | 9040 | 2.128
1717414 | -4220 | -6500 | 9040 | 2.128
1717416 | -4220 | -6500 | 9040 | 2.128
1717418 | -4220 | -6500 | 9040 | 2.128
1717429 | -4220 | -7750 | 10290 | 2.43587 | BaseQuantities - CrossSectionArea: 246286 mm2; OuterSurfaceArea: 17399397 mm2; GrossSurfaceArea: 17891968 mm2; GrossVolume: 2.43576 m3
1717431 | -4220 | -7750 | 10290 | 2.43587
1717433 | -4220 | -7750 | 10290 | 2.43587
1717435 | -4220 | -7750 | 10290 | 2.43587
1718950 | -3720 | -5500 | 8540 | 2.00485
1718963 | -3720 | -5500 | 8540 | 2.00485
1719750 | -3720 | -6250 | 9290 | 2.18957
1719761 | -3720 | -6250 | 9290 | 2.18957
1719772 | -4220 | -6750 | 9290 | 2.18957
1719783 | -4220 | -6750 | 9290 | 2.18957
1719938 | -3720 | -6250 | 9290 | 2.18957
1719960 | -3720 | -6250 | 9290 | 2.18957
1719982 | -4220 | -6250 | 8790 | 2.06642 | BaseQuantities - CrossSectionArea: 246286 mm2; OuterSurfaceArea: 14760459 mm2; GrossSurfaceArea: 15253030 mm2; GrossVolume: 2.06634 m3
1720004 | -4220 | -6250 | 8790 | 2.06642
1720026 | -3720 | -6750 | 9790 | 2.31272
1720048 | -3720 | -6750 | 9790 | 2.31272
1720144 | -3720 | -6250 | 9290 | 2.18957
1720188 | -3720 | -6250 | 9290 | 2.18957
1720197 | -3720 | -6250 | 9290 | 2.18957
1720206 | -3720 | -6250 | 9290 | 2.18957
1720244 | -4220 | -6250 | 8790 | 2.06642
1720415 | -4220 | -6250 | 8790 | 2.06642
1720539 | -5800 | -6750 | 7710 | 1.80042 | BaseQuantities - CrossSectionArea: 246286 mm2; OuterSurfaceArea: 12860424 mm2; GrossSurfaceArea: 13352995 mm2; GrossVolume: 1.80035 m3
1720585 | -5800 | -6750 | 7710 | 1.80042
1720598 | -5800 | -6750 | 7710 | 1.80042
1720658 | -5800 | -6750 | 7710 | 1.80042
1720680 | -5800 | -6750 | 7710 | 1.80042
1720715 | -5800 | -6750 | 7710 | 1.80042
1720779 | -5800 | -6750 | 7710 | 1.80042
1720885 | -5800 | -6750 | 7710 | 1.80042
1720962 | -5800 | -6750 | 7710 | 1.80042
1720997 | -5180 | -5000 | 6580 | 1.52211 | BaseQuantities - CrossSectionArea: 246286 mm2; OuterSurfaceArea: 10872424 mm2; GrossSurfaceArea: 11364995 mm2; GrossVolume: 1.52204 m3
1721047 | -5580 | -5000 | 6180 | 1.42359 | BaseQuantities - CrossSectionArea: 246286 mm2; OuterSurfaceArea: 10168707 mm2; GrossSurfaceArea: 10661278 mm2; GrossVolume: 1.42353 m3
1721060 | -5580 | -7750 | 8930 | 2.10091 | BaseQuantities - CrossSectionArea: 246286 mm2; OuterSurfaceArea: 15006760 mm2; GrossSurfaceArea: 15499331 mm2; GrossVolume: 2.10082 m3
1721129 | -3720 | -7750 | 10790 | 2.55902 | BaseQuantities - CrossSectionArea: 246286 mm2; OuterSurfaceArea: 18279043 mm2; GrossSurfaceArea: 18771614 mm2; GrossVolume: 2.55891 m3
1721186 | -3720 | -7750 | 10790 | 2.55902
1721277 | -5580 | -7750 | 8930 | 2.10091
1721375 | -5580 | -5000 | 6180 | 1.42359
1721426 | -3720 | -5250 | 8290 | 1.94328 | BaseQuantities - CrossSectionArea: 246286 mm2; OuterSurfaceArea: 13880813 mm2; GrossSurfaceArea: 14373384 mm2; GrossVolume: 1.94319 m3
1721435 | -3720 | -5250 | 8290 | 1.94328
1721475 | -3720 | -5250 | 8290 | 1.94328
1721484 | -3720 | -5250 | 8290 | 1.94328
1721593 | -5580 | -5250 | 6430 | 1.48516 | BaseQuantities - CrossSectionArea: 246286 mm2; OuterSurfaceArea: 10608530 mm2; GrossSurfaceArea: 11101101 mm2; GrossVolume: 1.4851 m3
1721595 | -3160 | -5250 | 8850 | 2.0812 | BaseQuantities - CrossSectionArea: 246286 mm2; OuterSurfaceArea: 14866016 mm2; GrossSurfaceArea: 15358588 mm2; GrossVolume: 2.08111 m3
1721687 | -3160 | -5250 | 8850 | 2.0812
1721698 | -3160 | -5250 | 8850 | 2.0812
1721771 | -3160 | -6000 | 9600 | 2.26592 | BaseQuantities - CrossSectionArea: 246286 mm2; OuterSurfaceArea: 16185485 mm2; GrossSurfaceArea: 16678056 mm2; GrossVolume: 2.26583 m3
1721819 | -3160 | -6000 | 9600 | 2.26592
1721864 | -3160 | -5250 | 8850 | 2.0812
1721873 | -3160 | -5250 | 8850 | 2.0812
1721886 | -3160 | -5250 | 8850 | 2.0812
1721895 | -3160 | -5250 | 8850 | 2.0812
1721908 | -3160 | -5250 | 8850 | 2.0812
1722366 | -3020 | -6500 | 10240 | 2.42355 | BaseQuantities - CrossSectionArea: 246286 mm2; OuterSurfaceArea: 17311432 mm2; GrossSurfaceArea: 17804003 mm2; GrossVolume: 2.42345 m3
1722431 | -3020 | -7000 | 10740 | 2.5467 | BaseQuantities - CrossSectionArea: 246286 mm2; OuterSurfaceArea: 18191078 mm2; GrossSurfaceArea: 18683649 mm2; GrossVolume: 2.54659 m3
1722440 | -3020 | -7500 | 11240 | 2.66985 | BaseQuantities - CrossSectionArea: 246286 mm2; OuterSurfaceArea: 19070724 mm2; GrossSurfaceArea: 19563295 mm2; GrossVolume: 2.66974 m3
1722490 | -3020 | -8000 | 11740 | 2.793 | BaseQuantities - CrossSectionArea: 246286 mm2; OuterSurfaceArea: 19950370 mm2; GrossSurfaceArea: 20442941 mm2; GrossVolume: 2.79288 m3
1722503 | -3020 | -8000 | 11740 | 2.793
1722512 | -3020 | -8000 | 11740 | 2.793
1722521 | -3020 | -8000 | 11740 | 2.793
1722532 | -3020 | -9000 | 12740 | 3.03929 | BaseQuantities - CrossSectionArea: 246286 mm2; OuterSurfaceArea: 21709662 mm2; GrossSurfaceArea: 22202233 mm2; GrossVolume: 3.03916 m3
1722543 | -3020 | -9000 | 12740 | 3.03929
1722628 | -2920 | -6000 | 9840 | 2.32503 | BaseQuantities - CrossSectionArea: 246286 mm2; OuterSurfaceArea: 16607715 mm2; GrossSurfaceArea: 17100287 mm2; GrossVolume: 2.32494 m3
1722695 | -3720 | -6000 | 9040 | 2.128
1722735 | -3020 | -6000 | 9740 | 2.3004 | BaseQuantities - CrossSectionArea: 246286 mm2; OuterSurfaceArea: 16431786 mm2; GrossSurfaceArea: 16924357 mm2; GrossVolume: 2.30031 m3
1722746 | -3020 | -8000 | 11740 | 2.793
1722757 | -3020 | -9000 | 12740 | 3.03929
1722824 | -3020 | -9000 | 12740 | 3.03929
1722835 | -3020 | -9000 | 12740 | 3.03929
1722846 | -3020 | -9000 | 12740 | 3.03929
1722898 | -3320 | -9000 | 12440 | 2.9654 | BaseQuantities - CrossSectionArea: 246286 mm2; OuterSurfaceArea: 21181874 mm2; GrossSurfaceArea: 21674445 mm2; GrossVolume: 2.96528 m3
1723038 | -3320 | -9000 | 12440 | 2.9654
1723115 | -3720 | -6000 | 9040 | 2.128
1723117 | -3720 | -6000 | 9040 | 2.128
1723174 | -3720 | -6000 | 9040 | 2.128
1723240 | -3720 | -6000 | 9040 | 2.128
1723249 | -3720 | -6000 | 9040 | 2.128
1723258 | -3720 | -6000 | 9040 | 2.128
1723267 | -3720 | -6000 | 9040 | 2.128
1723326 | -3720 | -6000 | 9040 | 2.128
1723395 | -3720 | -6000 | 9040 | 2.128
1723406 | -3720 | -6000 | 9040 | 2.128
1723457 | -3720 | -6000 | 9040 | 2.128
1723606 | -3720 | -6000 | 9040 | 2.128
1723647 | -3020 | -6000 | 9740 | 2.3004
1723688 | -3020 | -6000 | 9740 | 2.3004
1723753 | -3020 | -6500 | 10240 | 2.42355
1723848 | -3020 | -6500 | 10240 | 2.42355
1723903 | -3020 | -6500 | 10240 | 2.42355
1723975 | -3720 | -6000 | 9040 | 2.128
1724034 | -3720 | -6000 | 9040 | 2.128
1724091 | -3720 | -6000 | 9040 | 2.128
1724181 | -3720 | -6000 | 9040 | 2.128
1724183 | -3720 | -6000 | 9040 | 2.128
1724218 | -3720 | -6000 | 9040 | 2.128
1724220 | -3720 | -6000 | 9040 | 2.128
1724256 | -3720 | -6000 | 9040 | 2.128
1724258 | -3720 | -6000 | 9040 | 2.128
1724260 | -3720 | -6000 | 9040 | 2.128
1724397 | -3720 | -6000 | 9040 | 2.128
1724456 | -3720 | -6000 | 9040 | 2.128
1724496 | -3720 | -6000 | 9040 | 2.128
1724509 | -3720 | -6000 | 9040 | 2.128
1724518 | -3720 | -6000 | 9040 | 2.128
1724567 | -3720 | -6000 | 9040 | 2.128
1724569 | -3720 | -6000 | 9040 | 2.128
1724571 | -3720 | -6000 | 9040 | 2.128
1724639 | -3020 | -6000 | 9740 | 2.3004
1724704 | -3020 | -7000 | 10740 | 2.5467
1724715 | -4520 | -7000 | 9240 | 2.17726 | BaseQuantities - CrossSectionArea: 246286 mm2; OuterSurfaceArea: 15552140 mm2; GrossSurfaceArea: 16044711 mm2; GrossVolume: 2.17716 m3; Pset_Pieters - Comments: paal inkorten vanaf -3040
1724782 | -3020 | -7000 | 10740 | 2.5467
1724793 | -3020 | -7000 | 10740 | 2.5467
1724804 | -3050 | -7000 | 10710 | 2.53931 | BaseQuantities - CrossSectionArea: 246286 mm2; OuterSurfaceArea: 18138299 mm2; GrossSurfaceArea: 18630870 mm2; GrossVolume: 2.5392 m3; Pset_Pieters - Comments: bestaande paal inkorten tot bk.=3050-P; Bouwdeel: bestaande hoogte = -800
1724817 | -4520 | -7000 | 9240 | 2.17726 | Pset_Pieters - Comments: paal inkorten vanaf -800
1724889 | -3020 | -7000 | 10740 | 2.5467
1724900 | -3020 | -7000 | 10740 | 2.5467
1724911 | -3020 | -7500 | 11240 | 2.66985
1724922 | -3020 | -8000 | 11740 | 2.793
1724964 | -3320 | -8500 | 11940 | 2.84226 | BaseQuantities - CrossSectionArea: 246286 mm2; OuterSurfaceArea: 20302228 mm2; GrossSurfaceArea: 20794799 mm2; GrossVolume: 2.84214 m3
1725016 | -3320 | -7000 | 10440 | 2.47281 | BaseQuantities - CrossSectionArea: 246286 mm2; OuterSurfaceArea: 17663291 mm2; GrossSurfaceArea: 18155862 mm2; GrossVolume: 2.47271 m3
1725055 | -3320 | -7000 | 10440 | 2.47281
1725108 | -3320 | -7000 | 10440 | 2.47281
1725167 | -3320 | -8500 | 11940 | 2.84226
1725203 | -3320 | -7000 | 10440 | 2.47281
1725205 | -3320 | -7000 | 10440 | 2.47281
1725207 | -3320 | -7000 | 10440 | 2.47281
1725209 | -3320 | -7000 | 10440 | 2.47281
1725211 | -3320 | -7000 | 10440 | 2.47281
1725222 | -3320 | -8500 | 11940 | 2.84226
1725224 | -3320 | -8500 | 11940 | 2.84226
1725226 | -3320 | -8500 | 11940 | 2.84226
1725228 | -3320 | -8500 | 11940 | 2.84226
1725230 | -3980 | -8500 | 11280 | 2.6797 | BaseQuantities - CrossSectionArea: 246286 mm2; OuterSurfaceArea: 19141096 mm2; GrossSurfaceArea: 19633667 mm2; GrossVolume: 2.67959 m3
1725243 | -3980 | -8500 | 11280 | 2.6797
1725245 | -3320 | -7000 | 10440 | 2.47281
1725247 | -3320 | -7000 | 10440 | 2.47281
1725249 | -3320 | -7000 | 10440 | 2.47281
1725251 | -3320 | -8500 | 11940 | 2.84226
1725299 | -3320 | -6500 | 9940 | 2.34966 | BaseQuantities - CrossSectionArea: 246286 mm2; OuterSurfaceArea: 16783645 mm2; GrossSurfaceArea: 17276216 mm2; GrossVolume: 2.34956 m3
1725301 | -3520 | -7000 | 10240 | 2.42355 | BaseQuantities - CrossSectionArea: 246286 mm2; OuterSurfaceArea: 17311432 mm2; GrossSurfaceArea: 17804003 mm2; GrossVolume: 2.42345 m3
1725303 | -4470 | -7000 | 9290 | 2.18957 | BaseQuantities - CrossSectionArea: 246286 mm2; OuterSurfaceArea: 15640105 mm2; GrossSurfaceArea: 16132676 mm2; GrossVolume: 2.18948 m3; Pset_Pieters - Comments: paal inkorten vanaf -3540
1725305 | -3320 | -6500 | 9940 | 2.34966
1725350 | -3520 | -7000 | 10240 | 2.42355
1725352 | -4520 | -7000 | 9240 | 2.17726 | Pset_Pieters - Comments: paal inkorten vanaf -3540
1725380 | -4520 | -7000 | 9240 | 2.17726 | Pset_Pieters - Comments: paal inkorten vanaf -3040
1725417 | -3020 | -6500 | 10240 | 2.42355
1725480 | -3050 | -6500 | 10210 | 2.41616 | BaseQuantities - CrossSectionArea: 246286 mm2; OuterSurfaceArea: 17258653 mm2; GrossSurfaceArea: 17751225 mm2; GrossVolume: 2.41606 m3; Pset_Pieters - Comments: paal inkorten vanaf -800
1725493 | -3050 | -6500 | 10210 | 2.41616 | Pset_Pieters - Comments: paal inkorten vanaf -800

# IfcPile: 17_PBT_SFO_putring:Ø1000 (putring)_bestaand, 17_PBT_SFO_putring:Ø1000 (putring)_bestaand:1725552
In: -2 kelder
Classification: 17.21 paalfunderingen - geheid, dragende palen (Uniformat); Material: <Unnamed>
Pset_ProductRequirements - Category: Structural Foundations
Pset_QuantityTakeOff - Reference: 17_PBT_SFO_putring:Ø1000 (putring)_bestaand
Pset_Pieters - Dragend/niet dragend: yes; In/uitwendig: yes; Breedte/Diameter: 1000 mm; Bouwlaag: Level: NAP; Naamgeving element: 17_PBT_SFO_putring: Ø1000 (putring)_bestaand; Codering - NL-SfB: 17.21; Omschrijving NL-SfB: paalfunderingen - geheid, dragende palen; Fase: Bestaand; Description: Betonpaal; O.k. fundering t.o.v. Peil: -1400 mm; Paalpuntniveau tov NAP: 960 mm
BaseQuantities - Length: 4400 mm; CrossSectionArea: 282762 mm2; OuterSurfaceArea: 12566371 mm2; GrossSurfaceArea: 13131895 mm2; GrossVolume: 1.13105 m3; NetVolume: 1.13098 m3

# IfcSlab: Floor:16_PBT_SFO_poerconstructie_d=700_C53/65, Floor:16_PBT_SFO_poerconstructie_d=700_C53/65:5720440
In: -1 kelder
Type - PredefinedType: FLOOR; Material: 00_PBT_MAT_beton t.p.g._C53/65 700 mm
Type - Pset_ElementShading - Roughness: 304.8 mm
Type - Pset_ProductRequirements - Category: Floors
Type - Pset_ReinforcementBarPitchOfSlab - Description: poerconstructie
Type - Pset_SlabCommon - IsExternal: no
Type - Pset_Pieters - Naamgeving element: 16_PBT_SFO_poerconstructie_d=700_C53/65; Codering - NL-SfB: 16.13; Omschrijving NL-SfB: funderingsconstructies - voeten en balken, fundatie poeren; Materiaal: 00_PBT_MAT_beton t.p.g._C53/65; Materiaalkwaliteit: C53/65; Description: poerconstructie
Classification: 16.13 funderingsconstructies - voeten en balken, fundatie poeren (Uniformat)
Pset_QuantityTakeOff - Reference: Floor:16_PBT_SFO_poerconstructie_d=700_C53/65
Pset_ReinforcementBarPitchOfSlab - Reference: Floor:16_PBT_SFO_poerconstructie_d=700_C53/65
Pset_SlabCommon - LoadBearing: yes; PitchAngle: 0 deg; Reference: Floor:16_PBT_SFO_poerconstructie_d=700_C53/65
Pset_Pieters - Dikte: 700 mm; Bouwlaag: Level: -1 kelder; Fase: Nieuw
BaseQuantities - GrossArea: 823754 mm2; NetArea: 823754 mm2; GrossVolume: 0.576628 m3; NetVolume: 0.576628 m3; Perimeter: 3807.47 mm; Width: 700 mm

# IfcSlab: Floor:28_PBT_FL_beton prefab_d=200 (5)
Type - PredefinedType: FLOOR; Material: 00_PBT_MAT_beton prefab 200 mm
Type - Pset_ElementShading - Roughness: 304.8 mm
Type - Pset_ProductRequirements - Category: Floors
Type - Pset_ReinforcementBarPitchOfSlab - Description: prefab betonvloer d=200
Type - Pset_SlabCommon - IsExternal: no
Type - Pset_Pieters - Naamgeving element: 28_PBT_FL_beton prefab_d=200; Codering - NL-SfB: 28.21; Omschrijving NL-SfB: hoofddraagconstructies - wanden en vloeren, wand-/vloerconstructies; Materiaal: 00_PBT_MAT_beton prefab; Materiaalkwaliteit: volgens leverancier; Description: prefab betonvloer d=200; Type Comments: d=200
Classification: 28.21 hoofddraagconstructies - wanden en vloeren, wand-/vloerconstructies (Uniformat)
Pset_QuantityTakeOff - Reference: Floor:28_PBT_FL_beton prefab_d=200
Pset_ReinforcementBarPitchOfSlab - Reference: Floor:28_PBT_FL_beton prefab_d=200
Pset_SlabCommon - LoadBearing: yes; PitchAngle: 0 deg; Reference: Floor:28_PBT_FL_beton prefab_d=200
Pset_Pieters - Dikte: 200 mm; Fase: Nieuw
BaseQuantities - Width: 200 mm
Name (Floor:28_PBT_FL_beton prefab_d=200:...) | In | Bouwlaag | GrossArea (mm2) = NetArea (mm2) | GrossVolume (m3) = NetVolume (m3) | Perimeter (mm)
2035948 | 03 derde verdieping | Level: 03 derde verdieping | 11815292 | 2.36306 | 13801.5
2643390 | 05 vijfde verdieping | Level: 05 vijfde verdieping | 10411951 | 2.08239 | 13502
2932914 | 05 vijfde verdieping | Level: 05 vijfde verdieping | 33057521 | 6.6115 | 58324.5
2935275 | 05 vijfde verdieping | Level: 05 vijfde verdieping | 12485789 | 2.49716 | 32798.4
4516189 | 04 vierde verdieping | Level: 04 vierde verdieping | 13421200 | 2.68424 | 14660

# IfcSlab: Floor:28_PBT_FL_beton t.p.g._d=100_C30/37, Floor:28_PBT_FL_beton t.p.g._d=100_C30/37:2421392
In: 03 derde verdieping
Type - PredefinedType: FLOOR; Material: 00_PBT_MAT_beton t.p.g._C30/37 100 mm
Type - Pset_ElementShading - Roughness: 304.8 mm
Type - Pset_ProductRequirements - Category: Floors
Type - Pset_ReinforcementBarPitchOfSlab - Description: i.h.w.g. betonvloer d=100
Type - Pset_SlabCommon - IsExternal: no
Type - Pset_Pieters - Naamgeving element: 28_PBT_FL_beton t.p.g._d=100_C30/37; Codering - NL-SfB: 28.21; Omschrijving NL-SfB: hoofddraagconstructies - wanden en vloeren, wand-/vloerconstructies; Materiaal: 00_PBT_MAT_beton t.p.g._C30/37; Materiaalkwaliteit: C30/37; Description: i.h.w.g. betonvloer d=100
Classification: 28.21 hoofddraagconstructies - wanden en vloeren, wand-/vloerconstructies (Uniformat)
Pset_QuantityTakeOff - Reference: Floor:28_PBT_FL_beton t.p.g._d=100_C30/37
Pset_ReinforcementBarPitchOfSlab - Reference: Floor:28_PBT_FL_beton t.p.g._d=100_C30/37
Pset_SlabCommon - LoadBearing: yes; PitchAngle: 0 deg; Reference: Floor:28_PBT_FL_beton t.p.g._d=100_C30/37
Pset_Pieters - Dikte: 100 mm; Bouwlaag: Level: 03 derde verdieping; Fase: Nieuw; Comments: (monolitisch afgewerkt)
BaseQuantities - GrossArea: 65926951 mm2; NetArea: 65926951 mm2; GrossVolume: 6.5927 m3; NetVolume: 6.5927 m3; Perimeter: 39751.5 mm; Width: 100 mm

# IfcSlab: Floor:28_PBT_FL_beton t.p.g._d=100_C30/37, Floor:28_PBT_FL_beton t.p.g._d=100_C30/37:2976261
In: 04 vierde verdieping
Type - PredefinedType: FLOOR
Type - Pset_ElementShading - Roughness: 304.8 mm
Type - Pset_ProductRequirements - Category: Floors
Type - Pset_ReinforcementBarPitchOfSlab - Description: i.h.w.g. betonvloer d=100
Type - Pset_SlabCommon - IsExternal: no
Type - Pset_Pieters - Naamgeving element: 28_PBT_FL_beton t.p.g._d=100_C30/37; Codering - NL-SfB: 28.21; Omschrijving NL-SfB: hoofddraagconstructies - wanden en vloeren, wand-/vloerconstructies; Materiaal: 00_PBT_MAT_beton t.p.g._C30/37; Materiaalkwaliteit: C30/37; Description: i.h.w.g. betonvloer d=100
Classification: 28.21 hoofddraagconstructies - wanden en vloeren, wand-/vloerconstructies (Uniformat); Material: 00_PBT_MAT_beton t.p.g._C30/37
Pset_QuantityTakeOff - Reference: Floor:28_PBT_FL_beton t.p.g._d=100_C30/37
Pset_ReinforcementBarPitchOfSlab - Reference: Floor:28_PBT_FL_beton t.p.g._d=100_C30/37
Pset_SlabCommon - LoadBearing: yes; PitchAngle: 0 deg; Reference: Floor:28_PBT_FL_beton t.p.g._d=100_C30/37
Pset_Pieters - Dikte: 100 mm; Bouwlaag: Level: 04 vierde verdieping; Fase: Nieuw
BaseQuantities - NetArea: 227812417 mm2; NetVolume: 22.6918 m3; Perimeter: 64368.4 mm

# IfcSlab: Floor:28_PBT_FL_beton t.p.g._d=120_bestaand, Floor:28_PBT_FL_beton t.p.g._d=120_bestaand:2078388
In: 00 begane grond
Type - PredefinedType: FLOOR; Material: 00_PBT_MAT_beton t.p.g. 120 mm
Type - Pset_ElementShading - Roughness: 304.8 mm
Type - Pset_ProductRequirements - Category: Floors
Type - Pset_ReinforcementBarPitchOfSlab - Description: i.h.w.g. betonvloer d=120
Type - Pset_SlabCommon - IsExternal: no
Type - Pset_Pieters - Naamgeving element: 28_PBT_FL_beton t.p.g._d=120_bestaand; Codering - NL-SfB: 28.21; Omschrijving NL-SfB: hoofddraagconstructies - wanden en vloeren, wand-/vloerconstructies; Materiaal: 00_PBT_MAT_beton t.p.g.; Description: i.h.w.g. betonvloer d=120
Classification: 28.21 hoofddraagconstructies - wanden en vloeren, wand-/vloerconstructies (Uniformat)
Pset_QuantityTakeOff - Reference: Floor:28_PBT_FL_beton t.p.g._d=120_bestaand
Pset_ReinforcementBarPitchOfSlab - Reference: Floor:28_PBT_FL_beton t.p.g._d=120_bestaand
Pset_SlabCommon - LoadBearing: yes; PitchAngle: 0 deg; Reference: Floor:28_PBT_FL_beton t.p.g._d=120_bestaand
Pset_Pieters - Dragend/niet dragend: yes; In/uitwendig: no; Dikte: 120 mm; Bouwlaag: Level: 00 begane grond_Offset1000; Fase: Bestaand
BaseQuantities - GrossArea: 1740729 mm2; NetArea: 1740729 mm2; GrossVolume: 0.208887 m3; NetVolume: 0.208887 m3; Perimeter: 12204.9 mm; Width: 120 mm

# IfcSlab: Floor:28_PBT_FL_beton t.p.g._d=150_C30/37 (4)
Type - PredefinedType: FLOOR; Material: 00_PBT_MAT_beton t.p.g._C30/37 150 mm
Type - Pset_ElementShading - Roughness: 304.8 mm
Type - Pset_ProductRequirements - Category: Floors
Type - Pset_ReinforcementBarPitchOfSlab - Description: i.h.w.g. betonvloer d=150
Type - Pset_SlabCommon - IsExternal: no
Type - Pset_Pieters - Naamgeving element: 28_PBT_FL_beton t.p.g._d=150_C30/37; Codering - NL-SfB: 28.21; Omschrijving NL-SfB: hoofddraagconstructies - wanden en vloeren, wand-/vloerconstructies; Materiaal: 00_PBT_MAT_beton t.p.g._C30/37; Materiaalkwaliteit: C30/37; Description: i.h.w.g. betonvloer d=150; Type Comments: d=150
Classification: 28.21 hoofddraagconstructies - wanden en vloeren, wand-/vloerconstructies (Uniformat)
Pset_QuantityTakeOff - Reference: Floor:28_PBT_FL_beton t.p.g._d=150_C30/37
Pset_ReinforcementBarPitchOfSlab - Reference: Floor:28_PBT_FL_beton t.p.g._d=150_C30/37
Pset_SlabCommon - LoadBearing: yes; PitchAngle: 0 deg; Reference: Floor:28_PBT_FL_beton t.p.g._d=150_C30/37
Pset_Pieters - Dikte: 150 mm; Fase: Nieuw
BaseQuantities - Width: 150 mm
Name (Floor:28_PBT_FL_beton t.p.g._d=150_C30/37:...) | In | Bouwlaag | GrossArea (mm2) = NetArea (mm2) | GrossVolume (m3) | NetVolume (m3) | Perimeter (mm)
2745338 | 01 eerste verdieping | Level: 01 eerste verdieping | 231323543 | 34.6985 | 34.6985 | 63734
2745737 | 01 eerste verdieping | Level: 01 eerste verdieping | 242179102 | 36.3269 | 36.3269 | 64800
2747630 | 02 tweede verdieping | Level: 02 tweede verdieping | 58947309 | 8.8421 | 8.8421 | 41480
6473536 | 02 tweede verdieping | Level: 02 tweede verdieping_Offset1000 | 34041439 | 5.10622 | 5.10645 | 58468.3 | Pset_Pieters - Dragend/niet dragend: yes; In/uitwendig: no

# IfcSlab: Floor:28_PBT_FL_beton t.p.g._d=150_bestaand (4)
Type - PredefinedType: FLOOR; Material: 00_PBT_MAT_beton t.p.g. 150 mm
Type - Pset_ElementShading - Roughness: 304.8 mm
Type - Pset_ProductRequirements - Category: Floors
Type - Pset_ReinforcementBarPitchOfSlab - Description: i.h.w.g. betonvloer d=150
Type - Pset_SlabCommon - IsExternal: no
Type - Pset_Pieters - Naamgeving element: 28_PBT_FL_beton t.p.g._d=150_bestaand; Codering - NL-SfB: 28.21; Omschrijving NL-SfB: hoofddraagconstructies - wanden en vloeren, wand-/vloerconstructies; Materiaal: 00_PBT_MAT_beton t.p.g.; Description: i.h.w.g. betonvloer d=150; Type Comments: d=150
Classification: 28.21 hoofddraagconstructies - wanden en vloeren, wand-/vloerconstructies (Uniformat)
Pset_QuantityTakeOff - Reference: Floor:28_PBT_FL_beton t.p.g._d=150_bestaand
Pset_ReinforcementBarPitchOfSlab - Reference: Floor:28_PBT_FL_beton t.p.g._d=150_bestaand
Pset_SlabCommon - LoadBearing: yes; Reference: Floor:28_PBT_FL_beton t.p.g._d=150_bestaand; PitchAngle: 0 deg
Pset_Pieters - Dragend/niet dragend: yes; Dikte: 150 mm; Fase: Bestaand
Name (Floor:28_PBT_FL_beton t.p.g._d=150_bestaand:...) | In | In/uitwendig | Bouwlaag | NetArea (mm2) | NetVolume (m3) | Perimeter (mm)
1305143 | 00 begane grond | yes | Level: 00 begane grond_Offset1000 | 551826 | 0.082774 | 11758 | Pset_SlabCommon - IsExternal: yes
1366605 | -1 kelder | no | Level: -1 kelder_Offset1000 | 10609000 | 1.59135 | 14860
1391710 | -1 kelder | no | Level: -1 kelder_Offset1000 | 10358400 | 1.55376 | 22000 | BaseQuantities - GrossArea: 10358400 mm2; GrossVolume: 1.55376 m3; Width: 150 mm
1398291 | -1 kelder | no | Level: -1 kelder_Offset1000 | 2662250 | 0.399338 | 8770 | BaseQuantities - GrossArea: 2662250 mm2; GrossVolume: 0.399338 m3; Width: 150 mm

# IfcSlab: Floor:28_PBT_FL_beton t.p.g._d=200_C30/37 (3)
Type - PredefinedType: FLOOR; Material: 00_PBT_MAT_beton t.p.g._C30/37 200 mm
Type - Pset_ElementShading - Roughness: 304.8 mm
Type - Pset_ProductRequirements - Category: Floors
Type - Pset_ReinforcementBarPitchOfSlab - Description: i.h.w.g. betonvloer d=200
Type - Pset_SlabCommon - IsExternal: no
Type - Pset_Pieters - Naamgeving element: 28_PBT_FL_beton t.p.g._d=200_C30/37; Codering - NL-SfB: 28.21; Omschrijving NL-SfB: hoofddraagconstructies - wanden en vloeren, wand-/vloerconstructies; Materiaal: 00_PBT_MAT_beton t.p.g._C30/37; Materiaalkwaliteit: C30/37; Description: i.h.w.g. betonvloer d=200
Classification: 28.21 hoofddraagconstructies - wanden en vloeren, wand-/vloerconstructies (Uniformat)
Pset_QuantityTakeOff - Reference: Floor:28_PBT_FL_beton t.p.g._d=200_C30/37
Pset_ReinforcementBarPitchOfSlab - Reference: Floor:28_PBT_FL_beton t.p.g._d=200_C30/37
Pset_SlabCommon - LoadBearing: yes; PitchAngle: 0 deg; Reference: Floor:28_PBT_FL_beton t.p.g._d=200_C30/37
Pset_Pieters - Dikte: 200 mm; Fase: Nieuw
Name (Floor:28_PBT_FL_beton t.p.g._d=200_C30/37:...) | In | Bouwlaag | GrossArea (mm2) | NetArea (mm2) | NetVolume (m3) | Perimeter (mm)
3054182 | -1 kelder | Level: -1 kelder_Offset1000 | 2000000 | 2000000 | 0.4 | 6600 | Pset_Pieters - Dragend/niet dragend: yes; In/uitwendig: no; BaseQuantities - GrossVolume: 0.4 m3; Width: 200 mm
3154459 | -1 kelder | Level: -1 kelder |  | 2040000 | 0.408 | 8040
4458858:3 | 00 begane grond | Level: 00 begane grond | 3978524 | 9163909 | 1.83278 | 26128.7

# IfcSlab: Floor:28_PBT_FL_beton t.p.g._d=200_C30/37 (4)
Type - PredefinedType: FLOOR
Type - Pset_ElementShading - Roughness: 304.8 mm
Type - Pset_ProductRequirements - Category: Floors
Type - Pset_ReinforcementBarPitchOfSlab - Description: i.h.w.g. betonvloer d=200
Type - Pset_SlabCommon - IsExternal: no
Type - Pset_Pieters - Naamgeving element: 28_PBT_FL_beton t.p.g._d=200_C30/37; Codering - NL-SfB: 28.21; Omschrijving NL-SfB: hoofddraagconstructies - wanden en vloeren, wand-/vloerconstructies; Materiaal: 00_PBT_MAT_beton t.p.g._C30/37; Materiaalkwaliteit: C30/37; Description: i.h.w.g. betonvloer d=200
Classification: 28.21 hoofddraagconstructies - wanden en vloeren, wand-/vloerconstructies (Uniformat)
Pset_QuantityTakeOff - Reference: Floor:28_PBT_FL_beton t.p.g._d=200_C30/37
Pset_ReinforcementBarPitchOfSlab - Reference: Floor:28_PBT_FL_beton t.p.g._d=200_C30/37
Pset_SlabCommon - LoadBearing: yes; PitchAngle: 0 deg; Reference: Floor:28_PBT_FL_beton t.p.g._d=200_C30/37
Pset_Pieters - Dikte: 200 mm; Fase: Nieuw
Name (Floor:28_PBT_FL_beton t.p.g._d=200_C30/37:...) | In | Material | Bouwlaag | NetArea (mm2) | NetVolume (m3) | Perimeter (mm)
2032241 | 02 tweede verdieping | 00_PBT_MAT_beton t.p.g._C30/37 | Level: 02 tweede verdieping | 21605244 | 4.32786 | 26304.8
2419248 | 02 tweede verdieping | 00_PBT_MAT_beton t.p.g._C30/37 | Level: 02 tweede verdieping | 22352988 | 4.12835 | 32621.5
4458858 | 00 begane grond | 00_PBT_MAT_beton t.p.g._C30/37 200 mm | Level: 00 begane grond | 9163909 | 1.83278 | 26128.7 | BaseQuantities - GrossArea: 3879235 mm2
4458858:2 | 00 begane grond | 00_PBT_MAT_beton t.p.g._C30/37 200 mm | Level: 00 begane grond | 9163909 | 1.83278 | 26128.7 | BaseQuantities - GrossArea: 1306150 mm2

# IfcSlab: Floor:28_PBT_FL_beton t.p.g._d=200_C30/37_uitvulling n.t.b., Floor:28_PBT_FL_beton t.p.g._d=200_C30/37_uitvulling n.t.b.:1998288
In: -1 kelder
Type - PredefinedType: FLOOR; Material: 00_PBT_MAT_beton t.p.g._C30/37 200 mm
Type - Pset_ElementShading - Roughness: 304.8 mm
Type - Pset_ProductRequirements - Category: Floors
Type - Pset_ReinforcementBarPitchOfSlab - Description: i.h.w.g. betonvloer d=200 uitvulling n.t.b.
Type - Pset_SlabCommon - IsExternal: no
Type - Pset_Pieters - Naamgeving element: 28_PBT_FL_beton t.p.g._d=200_C30/37_uitvulling n.t.b.; Codering - NL-SfB: 28.21; Omschrijving NL-SfB: hoofddraagconstructies - wanden en vloeren, wand-/vloerconstructies; Materiaal: 00_PBT_MAT_beton t.p.g._C30/37; Materiaalkwaliteit: C30/37; Description: i.h.w.g. betonvloer d=200 uitvulling n.t.b.; Type Comments: d=200
Classification: 28.21 hoofddraagconstructies - wanden en vloeren, wand-/vloerconstructies (Uniformat)
Pset_QuantityTakeOff - Reference: Floor:28_PBT_FL_beton t.p.g._d=200_C30/37_uitvulling n.t.b.
Pset_ReinforcementBarPitchOfSlab - Reference: Floor:28_PBT_FL_beton t.p.g._d=200_C30/37_uitvulling n.t.b.
Pset_SlabCommon - LoadBearing: yes; PitchAngle: 0 deg; Reference: Floor:28_PBT_FL_beton t.p.g._d=200_C30/37_uitvulling n.t.b.
Pset_Pieters - Dikte: 200 mm; Bouwlaag: Level: -1 kelder; Fase: Nieuw
BaseQuantities - GrossArea: 6437500 mm2; NetArea: 6437500 mm2; GrossVolume: 1.2875 m3; NetVolume: 1.2875 m3; Perimeter: 10150 mm; Width: 200 mm

# IfcSlab: Floor:28_PBT_FL_beton t.p.g._d=200_bestaand (4)
Type - PredefinedType: FLOOR; Material: 00_PBT_MAT_beton t.p.g. 200 mm
Type - Pset_ElementShading - Roughness: 304.8 mm
Type - Pset_ProductRequirements - Category: Floors
Type - Pset_ReinforcementBarPitchOfSlab - Description: i.h.w.g. betonvloer d=200
Type - Pset_SlabCommon - IsExternal: no
Type - Pset_Pieters - Naamgeving element: 28_PBT_FL_beton t.p.g._d=200_bestaand; Codering - NL-SfB: 28.21; Omschrijving NL-SfB: hoofddraagconstructies - wanden en vloeren, wand-/vloerconstructies; Materiaal: 00_PBT_MAT_beton t.p.g.; Description: i.h.w.g. betonvloer d=200
Classification: 28.21 hoofddraagconstructies - wanden en vloeren, wand-/vloerconstructies (Uniformat)
Pset_QuantityTakeOff - Reference: Floor:28_PBT_FL_beton t.p.g._d=200_bestaand
Pset_ReinforcementBarPitchOfSlab - Reference: Floor:28_PBT_FL_beton t.p.g._d=200_bestaand
Pset_SlabCommon - LoadBearing: yes; PitchAngle: 0 deg; Reference: Floor:28_PBT_FL_beton t.p.g._d=200_bestaand
Pset_Pieters - Dragend/niet dragend: yes; In/uitwendig: no; Dikte: 200 mm; Fase: Bestaand
Name (Floor:28_PBT_FL_beton t.p.g._d=200_bestaand:...) | In | Bouwlaag | NetArea (mm2) | NetVolume (m3) | Perimeter (mm) | GrossArea (mm2) | GrossVolume (m3) | Width (mm)
1401268 | -1 kelder | Level: -1 kelder_Offset1000 | 6025000 | 1.205 | 14820
1454033 | 00 begane grond | Level: 00 begane grond_Offset1000 | 599222 | 0.0479377 | 6972.51 | 599222 | 0.0479377 | 80
1562113 | 00 begane grond | Level: 00 begane grond_Offset1000 | 6299266 | 1.25986 | 11994 | 6299261 | 1.25985 | 200
1588738 | 01 eerste verdieping | Level: 01 eerste verdieping_Offset1000 | 113347158 | 22.6693 | 59075.8 | 113347072 | 22.6694 | 200

# IfcSlab: Floor:28_PBT_FL_beton t.p.g._d=250_C30/37 (2)
Type - PredefinedType: FLOOR; Material: 00_PBT_MAT_beton t.p.g._C30/37 250 mm
Type - Pset_ElementShading - Roughness: 304.8 mm
Type - Pset_ProductRequirements - Category: Floors
Type - Pset_ReinforcementBarPitchOfSlab - Description: i.h.w.g. betonvloer d=250
Type - Pset_SlabCommon - IsExternal: no
Type - Pset_Pieters - Naamgeving element: 28_PBT_FL_beton t.p.g._d=250_C30/37; Codering - NL-SfB: 28.21; Omschrijving NL-SfB: hoofddraagconstructies - wanden en vloeren, wand-/vloerconstructies; Materiaal: 00_PBT_MAT_beton t.p.g._C30/37; Materiaalkwaliteit: C30/37; Description: i.h.w.g. betonvloer d=250; Type Comments: d=250
Classification: 28.21 hoofddraagconstructies - wanden en vloeren, wand-/vloerconstructies (Uniformat)
Pset_QuantityTakeOff - Reference: Floor:28_PBT_FL_beton t.p.g._d=250_C30/37
Pset_ReinforcementBarPitchOfSlab - Reference: Floor:28_PBT_FL_beton t.p.g._d=250_C30/37
Pset_SlabCommon - LoadBearing: yes; PitchAngle: 0 deg; Reference: Floor:28_PBT_FL_beton t.p.g._d=250_C30/37
Pset_Pieters - Dikte: 250 mm; Fase: Nieuw
BaseQuantities - Width: 250 mm
Name (Floor:28_PBT_FL_beton t.p.g._d=250_C30/37:...) | In | Bouwlaag | GrossArea (mm2) = NetArea (mm2) | GrossVolume (m3) = NetVolume (m3) | Perimeter (mm)
5490304 | 00 begane grond | Level: 00 begane grond | 11760941 | 2.94024 | 15258.4
6275524 | -1 kelder | Level: -1 kelder | 20601923 | 5.15048 | 22304

# IfcSlab: Floor:28_PBT_FL_beton t.p.g._d=250_C30/37, Floor:28_PBT_FL_beton t.p.g._d=250_C30/37:2490507
In: 05 vijfde verdieping
Type - PredefinedType: FLOOR
Type - Pset_ElementShading - Roughness: 304.8 mm
Type - Pset_ProductRequirements - Category: Floors
Type - Pset_ReinforcementBarPitchOfSlab - Description: i.h.w.g. betonvloer d=250
Type - Pset_SlabCommon - IsExternal: no
Type - Pset_Pieters - Naamgeving element: 28_PBT_FL_beton t.p.g._d=250_C30/37; Codering - NL-SfB: 28.21; Omschrijving NL-SfB: hoofddraagconstructies - wanden en vloeren, wand-/vloerconstructies; Materiaal: 00_PBT_MAT_beton t.p.g._C30/37; Materiaalkwaliteit: C30/37; Description: i.h.w.g. betonvloer d=250; Type Comments: d=250
Classification: 28.21 hoofddraagconstructies - wanden en vloeren, wand-/vloerconstructies (Uniformat); Material: 00_PBT_MAT_beton t.p.g._C30/37
Pset_QuantityTakeOff - Reference: Floor:28_PBT_FL_beton t.p.g._d=250_C30/37
Pset_ReinforcementBarPitchOfSlab - Reference: Floor:28_PBT_FL_beton t.p.g._d=250_C30/37
Pset_SlabCommon - LoadBearing: yes; PitchAngle: 0 deg; Reference: Floor:28_PBT_FL_beton t.p.g._d=250_C30/37
Pset_Pieters - Dikte: 250 mm; Bouwlaag: Level: 05 vijfde verdieping; Fase: Nieuw
BaseQuantities - NetArea: 32791800 mm2; NetVolume: 8.0843 m3; Perimeter: 54142 mm

# IfcSlab: Floor:28_PBT_FL_beton t.p.g._d=250_C30/37_uitvulling n.t.b. (2)
In: -1 kelder
Type - PredefinedType: FLOOR; Material: 00_PBT_MAT_beton t.p.g._C30/37 250 mm
Type - Pset_ElementShading - Roughness: 304.8 mm
Type - Pset_ProductRequirements - Category: Floors
Type - Pset_ReinforcementBarPitchOfSlab - Description: i.h.w.g. betonvloer d=250 uitvulling n.t.b.
Type - Pset_SlabCommon - IsExternal: no
Type - Pset_Pieters - Naamgeving element: 28_PBT_FL_beton t.p.g._d=250_C30/37_uitvulling n.t.b.; Codering - NL-SfB: 28.21; Omschrijving NL-SfB: hoofddraagconstructies - wanden en vloeren, wand-/vloerconstructies; Materiaal: 00_PBT_MAT_beton t.p.g._C30/37; Materiaalkwaliteit: C30/37; Description: i.h.w.g. betonvloer d=250 uitvulling n.t.b.; Type Comments: d=250
Classification: 28.21 hoofddraagconstructies - wanden en vloeren, wand-/vloerconstructies (Uniformat)
Pset_QuantityTakeOff - Reference: Floor:28_PBT_FL_beton t.p.g._d=250_C30/37_uitvulling n.t.b.
Pset_ReinforcementBarPitchOfSlab - Reference: Floor:28_PBT_FL_beton t.p.g._d=250_C30/37_uitvulling n.t.b.
Pset_SlabCommon - LoadBearing: yes; PitchAngle: 0 deg; Reference: Floor:28_PBT_FL_beton t.p.g._d=250_C30/37_uitvulling n.t.b.
Pset_Pieters - Dikte: 250 mm; Bouwlaag: Level: -1 kelder; Fase: Nieuw
BaseQuantities - Width: 250 mm
Name (Floor:28_PBT_FL_beton t.p.g._d=250_C30/37_uitvulling n.t.b.:...) | GrossArea (mm2) = NetArea (mm2) | GrossVolume (m3) = NetVolume (m3) | Perimeter (mm)
1998017 | 17918878 | 4.47972 | 22572.7
1998229 | 39591000 | 9.89775 | 27870

# IfcSlab: Floor:28_PBT_FL_beton t.p.g._d=250_C30/37_uitvulling n.t.b., Floor:28_PBT_FL_beton t.p.g._d=250_C30/37_uitvulling n.t.b.:1998128
In: -1 kelder
Type - PredefinedType: FLOOR
Type - Pset_ElementShading - Roughness: 304.8 mm
Type - Pset_ProductRequirements - Category: Floors
Type - Pset_ReinforcementBarPitchOfSlab - Description: i.h.w.g. betonvloer d=250 uitvulling n.t.b.
Type - Pset_SlabCommon - IsExternal: no
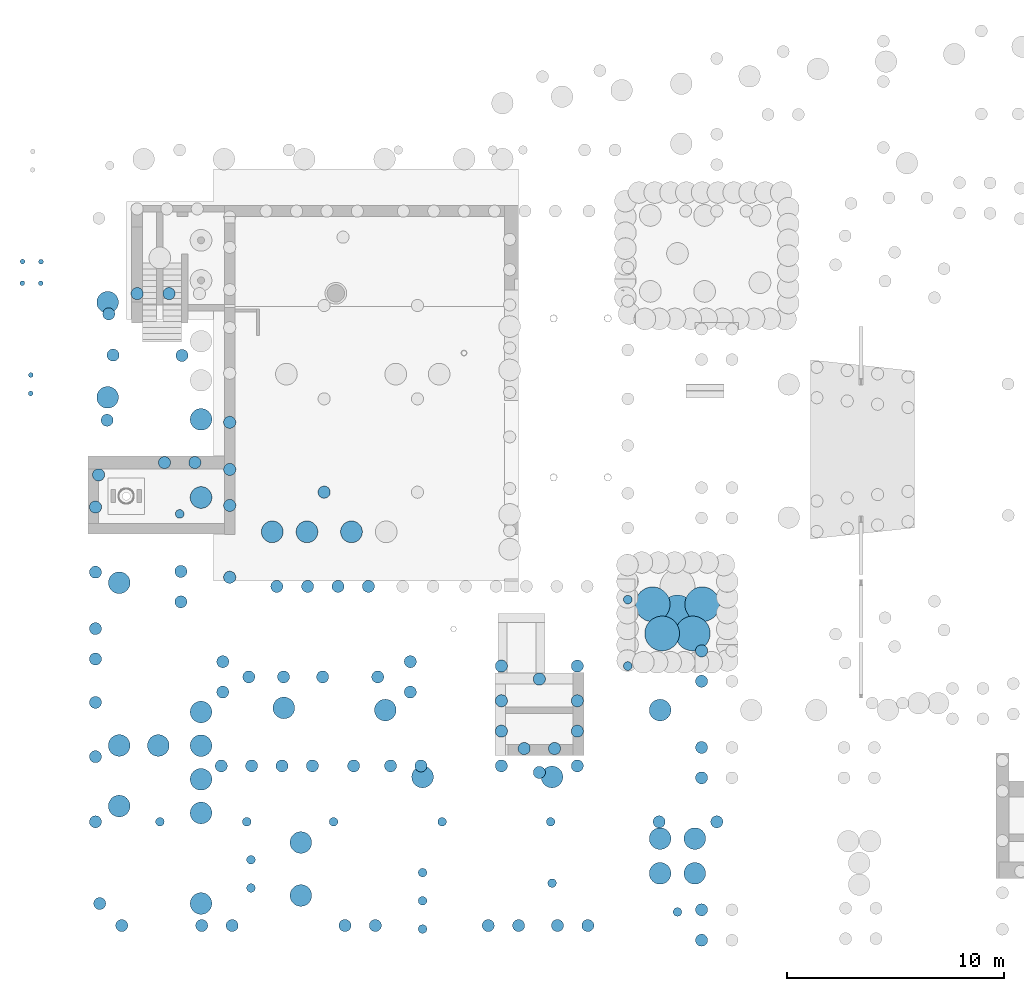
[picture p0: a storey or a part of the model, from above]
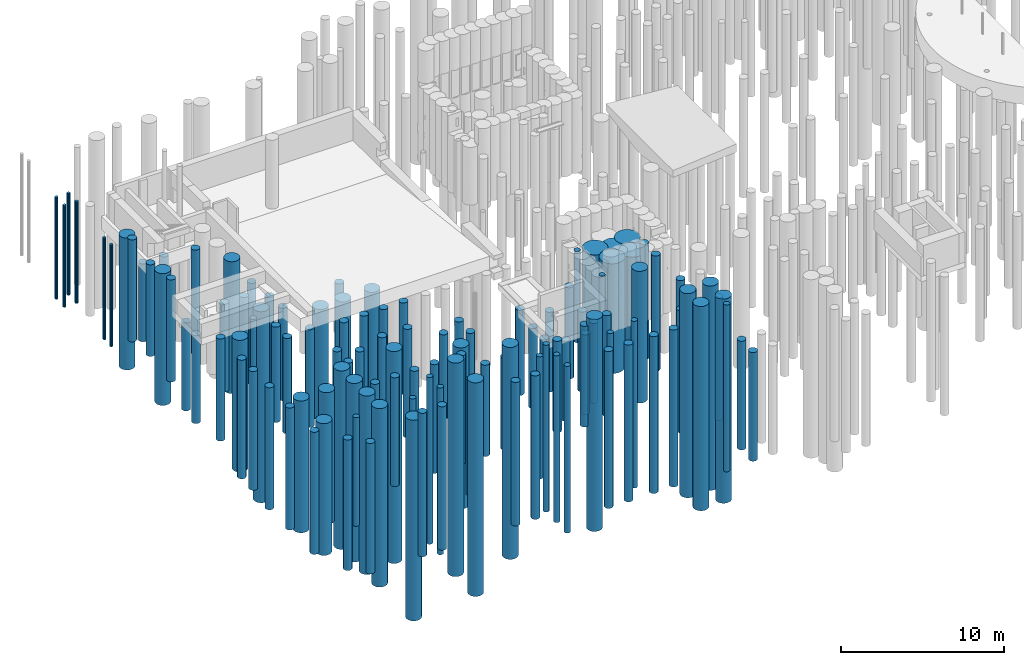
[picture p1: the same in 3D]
Properties of the parts of a building model (IFC2X3), part 14 of 18

# IfcSlab: Floor:28_PBT_FL_beton t.p.g._d=250_C30/37_uitvulling n.t.b., Floor:28_PBT_FL_beton t.p.g._d=250_C30/37_uitvulling n.t.b.:1998128
Type - Pset_Pieters - Naamgeving element: 28_PBT_FL_beton t.p.g._d=250_C30/37_uitvulling n.t.b.; Codering - NL-SfB: 28.21; Omschrijving NL-SfB: hoofddraagconstructies - wanden en vloeren, wand-/vloerconstructies; Materiaal: 00_PBT_MAT_beton t.p.g._C30/37; Materiaalkwaliteit: C30/37; Description: i.h.w.g. betonvloer d=250 uitvulling n.t.b.; Type Comments: d=250
Classification: 28.21 hoofddraagconstructies - wanden en vloeren, wand-/vloerconstructies (Uniformat); Material: 00_PBT_MAT_beton t.p.g._C30/37
Pset_QuantityTakeOff - Reference: Floor:28_PBT_FL_beton t.p.g._d=250_C30/37_uitvulling n.t.b.
Pset_ReinforcementBarPitchOfSlab - Reference: Floor:28_PBT_FL_beton t.p.g._d=250_C30/37_uitvulling n.t.b.
Pset_SlabCommon - LoadBearing: yes; PitchAngle: 0 deg; Reference: Floor:28_PBT_FL_beton t.p.g._d=250_C30/37_uitvulling n.t.b.
Pset_Pieters - Dikte: 250 mm; Bouwlaag: Level: -1 kelder; Fase: Nieuw
BaseQuantities - NetArea: 56471972 mm2; NetVolume: 13.9956 m3; Perimeter: 33307.3 mm

# IfcSlab: Floor:28_PBT_FL_beton t.p.g._d=260_C30/37, Floor:28_PBT_FL_beton t.p.g._d=260_C30/37:2432753
In: 03 derde verdieping
Type - PredefinedType: FLOOR; Material: 00_PBT_MAT_beton t.p.g._C30/37 260 mm
Type - Pset_ElementShading - Roughness: 304.8 mm
Type - Pset_ProductRequirements - Category: Floors
Type - Pset_ReinforcementBarPitchOfSlab - Description: i.h.w.g. betonvloer d=260
Type - Pset_SlabCommon - IsExternal: no
Type - Pset_Pieters - Naamgeving element: 28_PBT_FL_beton t.p.g._d=260_C30/37; Codering - NL-SfB: 28.21; Omschrijving NL-SfB: hoofddraagconstructies - wanden en vloeren, wand-/vloerconstructies; Materiaal: 00_PBT_MAT_beton t.p.g._C30/37; Materiaalkwaliteit: C30/37; Description: i.h.w.g. betonvloer d=260
Classification: 28.21 hoofddraagconstructies - wanden en vloeren, wand-/vloerconstructies (Uniformat)
Pset_QuantityTakeOff - Reference: Floor:28_PBT_FL_beton t.p.g._d=260_C30/37
Pset_ReinforcementBarPitchOfSlab - Reference: Floor:28_PBT_FL_beton t.p.g._d=260_C30/37
Pset_SlabCommon - LoadBearing: yes; PitchAngle: 0 deg; Reference: Floor:28_PBT_FL_beton t.p.g._d=260_C30/37
Pset_Pieters - Dikte: 260 mm; Bouwlaag: Level: 03 derde verdieping; Fase: Nieuw
BaseQuantities - GrossArea: 19155211 mm2; NetArea: 19155211 mm2; GrossVolume: 4.98035 m3; NetVolume: 4.98035 m3; Perimeter: 17618.5 mm; Width: 260 mm

# IfcSlab: Floor:28_PBT_FL_beton t.p.g._d=270_C30/37, Floor:28_PBT_FL_beton t.p.g._d=270_C30/37:2252060
In: 00 begane grond
Type - PredefinedType: FLOOR; Material: 00_PBT_MAT_beton t.p.g._C30/37 270 mm
Type - Pset_ElementShading - Roughness: 304.8 mm
Type - Pset_ProductRequirements - Category: Floors
Type - Pset_ReinforcementBarPitchOfSlab - Description: i.h.w.g. betonvloer d=270
Type - Pset_SlabCommon - IsExternal: no
Type - Pset_Pieters - Naamgeving element: 28_PBT_FL_beton t.p.g._d=270_C30/37; Codering - NL-SfB: 28.21; Omschrijving NL-SfB: hoofddraagconstructies - wanden en vloeren, wand-/vloerconstructies; Materiaal: 00_PBT_MAT_beton t.p.g._C30/37; Materiaalkwaliteit: C30/37; Description: i.h.w.g. betonvloer d=270; Type Comments: d=270
Classification: 28.21 hoofddraagconstructies - wanden en vloeren, wand-/vloerconstructies (Uniformat)
Pset_QuantityTakeOff - Reference: Floor:28_PBT_FL_beton t.p.g._d=270_C30/37
Pset_ReinforcementBarPitchOfSlab - Reference: Floor:28_PBT_FL_beton t.p.g._d=270_C30/37
Pset_SlabCommon - LoadBearing: yes; PitchAngle: 0 deg; Reference: Floor:28_PBT_FL_beton t.p.g._d=270_C30/37
Pset_Pieters - Dikte: 270 mm; Bouwlaag: Level: 00 begane grond; Fase: Nieuw
BaseQuantities - NetArea: 398265796 mm2; NetVolume: 107.532 m3; Perimeter: 98226.8 mm

# IfcSlab: Floor:28_PBT_FL_beton t.p.g._d=290_C30/37, Floor:28_PBT_FL_beton t.p.g._d=290_C30/37:2959973
In: 05 vijfde verdieping
Type - PredefinedType: FLOOR; Material: 00_PBT_MAT_beton t.p.g._C30/37 290 mm
Type - Pset_ElementShading - Roughness: 304.8 mm
Type - Pset_ProductRequirements - Category: Floors
Type - Pset_ReinforcementBarPitchOfSlab - Description: betonvloer d=290
Type - Pset_SlabCommon - IsExternal: no
Type - Pset_Pieters - Naamgeving element: 28_PBT_FL_beton t.p.g._d=290_C30/37; Codering - NL-SfB: 28.21; Omschrijving NL-SfB: hoofddraagconstructies - wanden en vloeren, wand-/vloerconstructies; Materiaal: 00_PBT_MAT_beton t.p.g._C30/37; Materiaalkwaliteit: C30/37; Description: betonvloer d=290
Classification: 28.21 hoofddraagconstructies - wanden en vloeren, wand-/vloerconstructies (Uniformat)
Pset_QuantityTakeOff - Reference: Floor:28_PBT_FL_beton t.p.g._d=290_C30/37
Pset_ReinforcementBarPitchOfSlab - Reference: Floor:28_PBT_FL_beton t.p.g._d=290_C30/37
Pset_SlabCommon - LoadBearing: yes; PitchAngle: 0 deg; Reference: Floor:28_PBT_FL_beton t.p.g._d=290_C30/37
Pset_Pieters - Dikte: 290 mm; Bouwlaag: Level: 05 vijfde verdieping; Fase: Nieuw
BaseQuantities - NetArea: 7452781 mm2; NetVolume: 2.40561 m3; Perimeter: 12614.3 mm

# IfcSlab: Floor:28_PBT_FL_beton t.p.g._d=290_C30/37, Floor:28_PBT_FL_beton t.p.g._d=290_C30/37:2962524
In: 05 vijfde verdieping
Type - PredefinedType: FLOOR
Type - Pset_ElementShading - Roughness: 304.8 mm
Type - Pset_ProductRequirements - Category: Floors
Type - Pset_ReinforcementBarPitchOfSlab - Description: betonvloer d=290
Type - Pset_SlabCommon - IsExternal: no
Type - Pset_Pieters - Naamgeving element: 28_PBT_FL_beton t.p.g._d=290_C30/37; Codering - NL-SfB: 28.21; Omschrijving NL-SfB: hoofddraagconstructies - wanden en vloeren, wand-/vloerconstructies; Materiaal: 00_PBT_MAT_beton t.p.g._C30/37; Materiaalkwaliteit: C30/37; Description: betonvloer d=290
Classification: 28.21 hoofddraagconstructies - wanden en vloeren, wand-/vloerconstructies (Uniformat); Material: 00_PBT_MAT_beton t.p.g._C30/37
Pset_QuantityTakeOff - Reference: Floor:28_PBT_FL_beton t.p.g._d=290_C30/37
Pset_ReinforcementBarPitchOfSlab - Reference: Floor:28_PBT_FL_beton t.p.g._d=290_C30/37
Pset_SlabCommon - LoadBearing: yes; PitchAngle: 0 deg; Reference: Floor:28_PBT_FL_beton t.p.g._d=290_C30/37
Pset_Pieters - Dikte: 290 mm; Bouwlaag: Level: 05 vijfde verdieping; Fase: Nieuw
BaseQuantities - NetArea: 49311390 mm2; NetVolume: 15.0688 m3; Perimeter: 50704.7 mm

# IfcSlab: Floor:28_PBT_FL_beton t.p.g._d=300_C30/37 (5)
Type - PredefinedType: FLOOR; Material: 00_PBT_MAT_beton t.p.g._C30/37 300 mm
Type - Pset_ElementShading - Roughness: 304.8 mm
Type - Pset_ProductRequirements - Category: Floors
Type - Pset_ReinforcementBarPitchOfSlab - Description: i.h.w.g. betonvloer d=300
Type - Pset_SlabCommon - IsExternal: no
Type - Pset_Pieters - Naamgeving element: 28_PBT_FL_beton t.p.g._d=300_C30/37; Codering - NL-SfB: 28.21; Omschrijving NL-SfB: hoofddraagconstructies - wanden en vloeren, wand-/vloerconstructies; Materiaal: 00_PBT_MAT_beton t.p.g._C30/37; Materiaalkwaliteit: C30/37; Description: i.h.w.g. betonvloer d=300
Classification: 28.21 hoofddraagconstructies - wanden en vloeren, wand-/vloerconstructies (Uniformat)
Pset_QuantityTakeOff - Reference: Floor:28_PBT_FL_beton t.p.g._d=300_C30/37
Pset_ReinforcementBarPitchOfSlab - Reference: Floor:28_PBT_FL_beton t.p.g._d=300_C30/37
Pset_SlabCommon - LoadBearing: yes; PitchAngle: 0 deg; Reference: Floor:28_PBT_FL_beton t.p.g._d=300_C30/37
Pset_Pieters - Dikte: 300 mm; Fase: Nieuw
BaseQuantities - Width: 300 mm
Name (Floor:28_PBT_FL_beton t.p.g._d=300_C30/37:...) | In | Bouwlaag | GrossArea (mm2) = NetArea (mm2) | GrossVolume (m3) = NetVolume (m3) | Perimeter (mm)
1991767 | 00 begane grond | Level: 00 begane grond | 42504894 | 12.7515 | 31268.2
2030443 | 02 tweede verdieping | Level: 02 tweede verdieping | 30708382 | 9.21251 | 37434.1
3761429 | 00 begane grond | Level: 00 begane grond | 4561307 | 1.36839 | 37398.6
5541177 | 00 begane grond | Level: 00 begane grond | 16731400 | 5.01942 | 18100
6198269 | 00 begane grond | Level: 00 begane grond | 2624896 | 0.787469 | 8661.92

# IfcSlab: Floor:28_PBT_FL_beton t.p.g._d=300_C30/37 (5)
Type - PredefinedType: FLOOR
Type - Pset_ElementShading - Roughness: 304.8 mm
Type - Pset_ProductRequirements - Category: Floors
Type - Pset_ReinforcementBarPitchOfSlab - Description: i.h.w.g. betonvloer d=300
Type - Pset_SlabCommon - IsExternal: no
Type - Pset_Pieters - Naamgeving element: 28_PBT_FL_beton t.p.g._d=300_C30/37; Codering - NL-SfB: 28.21; Omschrijving NL-SfB: hoofddraagconstructies - wanden en vloeren, wand-/vloerconstructies; Materiaal: 00_PBT_MAT_beton t.p.g._C30/37; Materiaalkwaliteit: C30/37; Description: i.h.w.g. betonvloer d=300
Classification: 28.21 hoofddraagconstructies - wanden en vloeren, wand-/vloerconstructies (Uniformat); Material: 00_PBT_MAT_beton t.p.g._C30/37
Pset_QuantityTakeOff - Reference: Floor:28_PBT_FL_beton t.p.g._d=300_C30/37
Pset_ReinforcementBarPitchOfSlab - Reference: Floor:28_PBT_FL_beton t.p.g._d=300_C30/37
Pset_SlabCommon - LoadBearing: yes; PitchAngle: 0 deg; Reference: Floor:28_PBT_FL_beton t.p.g._d=300_C30/37
Pset_Pieters - Dikte: 300 mm; Fase: Nieuw
Name (Floor:28_PBT_FL_beton t.p.g._d=300_C30/37:...) | In | Bouwlaag | NetArea (mm2) | NetVolume (m3) | Perimeter (mm)
2030276 | 02 tweede verdieping | Level: 02 tweede verdieping | 76691610 | 22.9751 | 47750
2044486 | 01 eerste verdieping | Level: 01 eerste verdieping | 48020968 | 14.2531 | 56980.3
2143252 | 00 begane grond | Level: 00 begane grond | 9965724 | 2.98519 | 14046
3338899 | 01 eerste verdieping | Level: 01 eerste verdieping | 25771517 | 7.09393 | 117432
5905198 | 02 tweede verdieping | Level: 02 tweede verdieping | 7134361 | 2.03109 | 12681.1

# IfcSlab: Floor:28_PBT_FL_beton t.p.g._d=300_bestaand (2)
In: 00 begane grond
Type - PredefinedType: FLOOR; Material: 00_PBT_MAT_beton t.p.g. 300 mm
Type - Pset_ElementShading - Roughness: 304.8 mm
Type - Pset_ProductRequirements - Category: Floors
Type - Pset_ReinforcementBarPitchOfSlab - Description: i.h.w.g. betonvloer d=300
Type - Pset_SlabCommon - IsExternal: no
Type - Pset_Pieters - Naamgeving element: 28_PBT_FL_beton t.p.g._d=300_bestaand; Codering - NL-SfB: 28.21; Omschrijving NL-SfB: hoofddraagconstructies - wanden en vloeren, wand-/vloerconstructies; Materiaal: 00_PBT_MAT_beton t.p.g.; Description: i.h.w.g. betonvloer d=300; Type Comments: d=300
Classification: 28.21 hoofddraagconstructies - wanden en vloeren, wand-/vloerconstructies (Uniformat)
Pset_QuantityTakeOff - Reference: Floor:28_PBT_FL_beton t.p.g._d=300_bestaand
Pset_ReinforcementBarPitchOfSlab - Reference: Floor:28_PBT_FL_beton t.p.g._d=300_bestaand
Pset_SlabCommon - LoadBearing: yes; PitchAngle: 0 deg; Reference: Floor:28_PBT_FL_beton t.p.g._d=300_bestaand
Pset_Pieters - Dragend/niet dragend: yes; In/uitwendig: no; Dikte: 300 mm; Bouwlaag: Level: 00 begane grond_Offset1000; Fase: Bestaand
BaseQuantities - Width: 300 mm
Name (Floor:28_PBT_FL_beton t.p.g._d=300_bestaand:...) | GrossArea (mm2) = NetArea (mm2) | GrossVolume (m3) = NetVolume (m3) | Perimeter (mm)
1909175 | 5060000 | 1.518 | 9000
2672158 | 9323658 | 2.7971 | 13154.7

# IfcSlab: Floor:28_PBT_FL_beton t.p.g._d=300_bestaand (2)
In: 00 begane grond
Type - PredefinedType: FLOOR
Type - Pset_ElementShading - Roughness: 304.8 mm
Type - Pset_ProductRequirements - Category: Floors
Type - Pset_ReinforcementBarPitchOfSlab - Description: i.h.w.g. betonvloer d=300
Type - Pset_SlabCommon - IsExternal: no
Type - Pset_Pieters - Naamgeving element: 28_PBT_FL_beton t.p.g._d=300_bestaand; Codering - NL-SfB: 28.21; Omschrijving NL-SfB: hoofddraagconstructies - wanden en vloeren, wand-/vloerconstructies; Materiaal: 00_PBT_MAT_beton t.p.g.; Description: i.h.w.g. betonvloer d=300; Type Comments: d=300
Classification: 28.21 hoofddraagconstructies - wanden en vloeren, wand-/vloerconstructies (Uniformat); Material: 00_PBT_MAT_beton t.p.g.
Pset_QuantityTakeOff - Reference: Floor:28_PBT_FL_beton t.p.g._d=300_bestaand
Pset_ReinforcementBarPitchOfSlab - Reference: Floor:28_PBT_FL_beton t.p.g._d=300_bestaand
Pset_SlabCommon - LoadBearing: yes; PitchAngle: 0 deg; Reference: Floor:28_PBT_FL_beton t.p.g._d=300_bestaand
Pset_Pieters - Dragend/niet dragend: yes; In/uitwendig: no; Dikte: 300 mm; Bouwlaag: Level: 00 begane grond_Offset1000; Fase: Bestaand
Name (Floor:28_PBT_FL_beton t.p.g._d=300_bestaand:...) | NetArea (mm2) | NetVolume (m3) | Perimeter (mm)
1341997 | 407699521 | 121.95 | 92914.2
2672709 | 14751476 | 4.3763 | 23652.2

# IfcSlab: Floor:28_PBT_FL_beton t.p.g._d=300_rand staalplaat-betonvloer_C30/37 (4)
In: 02 tweede verdieping
Type - PredefinedType: FLOOR
Type - Pset_ElementShading - Roughness: 304.8 mm
Type - Pset_ProductRequirements - Category: Floors
Type - Pset_ReinforcementBarPitchOfSlab - Description: staalplaat-betonvloer d=300
Type - Pset_SlabCommon - IsExternal: no
Type - Pset_Pieters - Naamgeving element: 28_PBT_FL_beton t.p.g._d=300_rand staalplaat-betonvloer_C30/37; Codering - NL-SfB: 28.21; Omschrijving NL-SfB: hoofddraagconstructies - wanden en vloeren, wand-/vloerconstructies; Materiaal: 00_PBT_MAT_beton t.p.g._C30/37; Materiaalkwaliteit: C30/37; Description: staalplaat-betonvloer d=300; Type Comments: d=300
Classification: 28.21 hoofddraagconstructies - wanden en vloeren, wand-/vloerconstructies (Uniformat); Material: 00_PBT_MAT_beton t.p.g._C30/37
Pset_QuantityTakeOff - Reference: Floor:28_PBT_FL_beton t.p.g._d=300_rand staalplaat-betonvloer_C30/37
Pset_ReinforcementBarPitchOfSlab - Reference: Floor:28_PBT_FL_beton t.p.g._d=300_rand staalplaat-betonvloer_C30/37
Pset_SlabCommon - LoadBearing: yes; PitchAngle: 0 deg; Reference: Floor:28_PBT_FL_beton t.p.g._d=300_rand staalplaat-betonvloer_C30/37
Pset_Pieters - Dikte: 300 mm; Bouwlaag: Level: 02 tweede verdieping; Fase: Nieuw
Name (Floor:28_PBT_FL_beton t.p.g._d=300_rand staalplaat-betonvloer_C30/37:...) | NetArea (mm2) | NetVolume (m3) | Perimeter (mm)
3628252 | 8028199 | 2.26923 | 78694
4872539 | 6983730 | 1.97885 | 44934
4872667 | 6962636 | 1.97022 | 44934
5181345 | 1495329 | 0.398289 | 6436.84

# IfcSlab: Floor:28_PBT_FL_beton t.p.g._d=320_C30/37 (2)
Type - PredefinedType: FLOOR; Material: 00_PBT_MAT_beton t.p.g._C30/37 320 mm
Type - Pset_ElementShading - Roughness: 304.8 mm
Type - Pset_ProductRequirements - Category: Floors
Type - Pset_ReinforcementBarPitchOfSlab - Description: i.h.w.g. betonvloer d=320
Type - Pset_SlabCommon - IsExternal: no
Type - Pset_Pieters - Naamgeving element: 28_PBT_FL_beton t.p.g._d=320_C30/37; Codering - NL-SfB: 28.21; Omschrijving NL-SfB: hoofddraagconstructies - wanden en vloeren, wand-/vloerconstructies; Materiaal: 00_PBT_MAT_beton t.p.g._C30/37; Materiaalkwaliteit: C30/37; Description: i.h.w.g. betonvloer d=320; Type Comments: d=320
Classification: 28.21 hoofddraagconstructies - wanden en vloeren, wand-/vloerconstructies (Uniformat)
Pset_QuantityTakeOff - Reference: Floor:28_PBT_FL_beton t.p.g._d=320_C30/37
Pset_ReinforcementBarPitchOfSlab - Reference: Floor:28_PBT_FL_beton t.p.g._d=320_C30/37
Pset_SlabCommon - LoadBearing: yes; PitchAngle: 0 deg; Reference: Floor:28_PBT_FL_beton t.p.g._d=320_C30/37
Pset_Pieters - Dikte: 320 mm; Fase: Nieuw
BaseQuantities - Width: 320 mm
Name (Floor:28_PBT_FL_beton t.p.g._d=320_C30/37:...) | In | Bouwlaag | GrossArea (mm2) = NetArea (mm2) | GrossVolume (m3) = NetVolume (m3) | Perimeter (mm)
2146876 | 01 eerste verdieping | Level: 01 eerste verdieping | 17599652 | 5.63189 | 16799.8
2156514 | 03 derde verdieping | Level: 03 derde verdieping | 64575941 | 20.6643 | 46863.5

# IfcSlab: Floor:28_PBT_FL_beton t.p.g._d=320_C30/37 (2)
Type - PredefinedType: FLOOR
Type - Pset_ElementShading - Roughness: 304.8 mm
Type - Pset_ProductRequirements - Category: Floors
Type - Pset_ReinforcementBarPitchOfSlab - Description: i.h.w.g. betonvloer d=320
Type - Pset_SlabCommon - IsExternal: no
Type - Pset_Pieters - Naamgeving element: 28_PBT_FL_beton t.p.g._d=320_C30/37; Codering - NL-SfB: 28.21; Omschrijving NL-SfB: hoofddraagconstructies - wanden en vloeren, wand-/vloerconstructies; Materiaal: 00_PBT_MAT_beton t.p.g._C30/37; Materiaalkwaliteit: C30/37; Description: i.h.w.g. betonvloer d=320; Type Comments: d=320
Classification: 28.21 hoofddraagconstructies - wanden en vloeren, wand-/vloerconstructies (Uniformat); Material: 00_PBT_MAT_beton t.p.g._C30/37
Pset_QuantityTakeOff - Reference: Floor:28_PBT_FL_beton t.p.g._d=320_C30/37
Pset_ReinforcementBarPitchOfSlab - Reference: Floor:28_PBT_FL_beton t.p.g._d=320_C30/37
Pset_SlabCommon - LoadBearing: yes; PitchAngle: 0 deg; Reference: Floor:28_PBT_FL_beton t.p.g._d=320_C30/37
Pset_Pieters - Dikte: 320 mm; Fase: Nieuw
Name (Floor:28_PBT_FL_beton t.p.g._d=320_C30/37:...) | In | Bouwlaag | NetArea (mm2) | NetVolume (m3) | Perimeter (mm)
2006136 | 00 begane grond | Level: 00 begane grond | 630123846 | 201.596 | 141947
2147576 | 01 eerste verdieping | Level: 01 eerste verdieping | 57279925 | 18.1248 | 45480.9

# IfcSlab: Floor:28_PBT_FL_beton t.p.g._d=380_bestaand (2)
In: 00 begane grond
Type - PredefinedType: FLOOR; Material: 00_PBT_MAT_beton t.p.g. 380 mm
Type - Pset_ElementShading - Roughness: 304.8 mm
Type - Pset_ProductRequirements - Category: Floors
Type - Pset_ReinforcementBarPitchOfSlab - Description: i.h.w.g. betonvloer d=380
Type - Pset_SlabCommon - IsExternal: no
Type - Pset_Pieters - Naamgeving element: 28_PBT_FL_beton t.p.g._d=380_bestaand; Codering - NL-SfB: 28.21; Omschrijving NL-SfB: hoofddraagconstructies - wanden en vloeren, wand-/vloerconstructies; Materiaal: 00_PBT_MAT_beton t.p.g.; Description: i.h.w.g. betonvloer d=380
Classification: 28.21 hoofddraagconstructies - wanden en vloeren, wand-/vloerconstructies (Uniformat)
Pset_QuantityTakeOff - Reference: Floor:28_PBT_FL_beton t.p.g._d=380_bestaand
Pset_ReinforcementBarPitchOfSlab - Reference: Floor:28_PBT_FL_beton t.p.g._d=380_bestaand
Pset_SlabCommon - LoadBearing: yes; PitchAngle: 0 deg; Reference: Floor:28_PBT_FL_beton t.p.g._d=380_bestaand
Pset_Pieters - Dragend/niet dragend: yes; In/uitwendig: no; Dikte: 380 mm; Bouwlaag: Level: 00 begane grond_Offset1000; Fase: Bestaand
Name (Floor:28_PBT_FL_beton t.p.g._d=380_bestaand:...) | NetArea (mm2) | NetVolume (m3) | Perimeter (mm)
1480531 | 5292885 | 2.0113 | 13759.4 | BaseQuantities - GrossArea: 5292885 mm2; GrossVolume: 2.0113 m3; Width: 380 mm
1481276 | 4885677 | 0.424645 | 13339.6

# IfcSlab: Floor:28_PBT_FL_beton t.p.g._d=390_C30/37, Floor:28_PBT_FL_beton t.p.g._d=390_C30/37:2421514
In: 03 derde verdieping
Type - PredefinedType: FLOOR
Type - Pset_ElementShading - Roughness: 304.8 mm
Type - Pset_ProductRequirements - Category: Floors
Type - Pset_ReinforcementBarPitchOfSlab - Description: i.h.w.g. betonvloer d=390
Type - Pset_SlabCommon - IsExternal: no
Type - Pset_Pieters - Naamgeving element: 28_PBT_FL_beton t.p.g._d=390_C30/37; Codering - NL-SfB: 28.21; Omschrijving NL-SfB: hoofddraagconstructies - wanden en vloeren, wand-/vloerconstructies; Materiaal: 00_PBT_MAT_beton t.p.g._C30/37; Materiaalkwaliteit: C30/37; Description: i.h.w.g. betonvloer d=390
Classification: 28.21 hoofddraagconstructies - wanden en vloeren, wand-/vloerconstructies (Uniformat); Material: 00_PBT_MAT_beton t.p.g._C30/37
Pset_QuantityTakeOff - Reference: Floor:28_PBT_FL_beton t.p.g._d=390_C30/37
Pset_ReinforcementBarPitchOfSlab - Reference: Floor:28_PBT_FL_beton t.p.g._d=390_C30/37
Pset_SlabCommon - LoadBearing: yes; PitchAngle: 0 deg; Reference: Floor:28_PBT_FL_beton t.p.g._d=390_C30/37
Pset_Pieters - Dikte: 390 mm; Bouwlaag: Level: 03 derde verdieping; Fase: Nieuw
BaseQuantities - NetArea: 8077389 mm2; NetVolume: 1.9365 m3; Perimeter: 30679.5 mm

# IfcSlab: Floor:28_PBT_FL_beton t.p.g._d=400_C30/37 (2)
Type - PredefinedType: FLOOR; Material: 00_PBT_MAT_beton t.p.g._C30/37 400 mm
Type - Pset_ElementShading - Roughness: 304.8 mm
Type - Pset_ProductRequirements - Category: Floors
Type - Pset_ReinforcementBarPitchOfSlab - Description: i.h.w.g. betonvloer d=400
Type - Pset_SlabCommon - IsExternal: no
Type - Pset_Pieters - Naamgeving element: 28_PBT_FL_beton t.p.g._d=400_C30/37; Codering - NL-SfB: 28.21; Omschrijving NL-SfB: hoofddraagconstructies - wanden en vloeren, wand-/vloerconstructies; Materiaal: 00_PBT_MAT_beton t.p.g._C30/37; Materiaalkwaliteit: C30/37; Description: i.h.w.g. betonvloer d=400; Type Comments: d=400
Classification: 28.21 hoofddraagconstructies - wanden en vloeren, wand-/vloerconstructies (Uniformat)
Pset_QuantityTakeOff - Reference: Floor:28_PBT_FL_beton t.p.g._d=400_C30/37
Pset_ReinforcementBarPitchOfSlab - Reference: Floor:28_PBT_FL_beton t.p.g._d=400_C30/37
Pset_SlabCommon - LoadBearing: yes; PitchAngle: 0 deg; Reference: Floor:28_PBT_FL_beton t.p.g._d=400_C30/37
Pset_Pieters - Dikte: 400 mm; Fase: Nieuw
BaseQuantities - Width: 400 mm
Name (Floor:28_PBT_FL_beton t.p.g._d=400_C30/37:...) | In | Bouwlaag | GrossArea (mm2) = NetArea (mm2) | GrossVolume (m3) = NetVolume (m3) | Perimeter (mm)
1972239 | -1 kelder | Level: -1 kelder | 15029566 | 6.01183 | 19110.8
2935222 | 05 vijfde verdieping | Level: 05 vijfde verdieping | 31205006 | 12.482 | 34936

# IfcSlab: Floor:28_PBT_FL_beton t.p.g._d=430_C30/37, Floor:28_PBT_FL_beton t.p.g._d=430_C30/37:3220660
In: 00 begane grond
Type - PredefinedType: FLOOR; Material: 00_PBT_MAT_beton t.p.g._C30/37 430 mm
Type - Pset_ElementShading - Roughness: 304.8 mm
Type - Pset_ProductRequirements - Category: Floors
Type - Pset_ReinforcementBarPitchOfSlab - Description: i.h.w.g. betonvloer d=430
Type - Pset_SlabCommon - IsExternal: no
Type - Pset_Pieters - Naamgeving element: 28_PBT_FL_beton t.p.g._d=430_C30/37; Codering - NL-SfB: 28.21; Omschrijving NL-SfB: hoofddraagconstructies - wanden en vloeren, wand-/vloerconstructies; Materiaal: 00_PBT_MAT_beton t.p.g._C30/37; Materiaalkwaliteit: C30/37; Description: i.h.w.g. betonvloer d=430; Type Comments: d=430
Classification: 28.21 hoofddraagconstructies - wanden en vloeren, wand-/vloerconstructies (Uniformat)
Pset_QuantityTakeOff - Reference: Floor:28_PBT_FL_beton t.p.g._d=430_C30/37
Pset_ReinforcementBarPitchOfSlab - Reference: Floor:28_PBT_FL_beton t.p.g._d=430_C30/37
Pset_SlabCommon - LoadBearing: yes; PitchAngle: 0 deg; Reference: Floor:28_PBT_FL_beton t.p.g._d=430_C30/37
Pset_Pieters - Dikte: 430 mm; Bouwlaag: Level: 00 begane grond; Fase: Nieuw
BaseQuantities - GrossArea: 16385393 mm2; NetArea: 16385393 mm2; GrossVolume: 7.04572 m3; NetVolume: 7.04572 m3; Perimeter: 19180 mm; Width: 430 mm

# IfcSlab: Floor:28_PBT_FL_beton t.p.g._d=450_C30/37 (8)
In: 00 begane grond
Type - PredefinedType: FLOOR; Material: 00_PBT_MAT_beton t.p.g._C30/37 450 mm
Type - Pset_ElementShading - Roughness: 304.8 mm
Type - Pset_ProductRequirements - Category: Floors
Type - Pset_ReinforcementBarPitchOfSlab - Description: i.h.w.g. betonvloer d=450
Type - Pset_SlabCommon - IsExternal: no
Type - Pset_Pieters - Naamgeving element: 28_PBT_FL_beton t.p.g._d=450_C30/37; Codering - NL-SfB: 28.21; Omschrijving NL-SfB: hoofddraagconstructies - wanden en vloeren, wand-/vloerconstructies; Materiaal: 00_PBT_MAT_beton t.p.g._C30/37; Materiaalkwaliteit: C30/37; Description: i.h.w.g. betonvloer d=450; Type Comments: d=450
Classification: 28.21 hoofddraagconstructies - wanden en vloeren, wand-/vloerconstructies (Uniformat)
Pset_QuantityTakeOff - Reference: Floor:28_PBT_FL_beton t.p.g._d=450_C30/37
Pset_ReinforcementBarPitchOfSlab - Reference: Floor:28_PBT_FL_beton t.p.g._d=450_C30/37
Pset_SlabCommon - LoadBearing: yes; PitchAngle: 0 deg; Reference: Floor:28_PBT_FL_beton t.p.g._d=450_C30/37
Pset_Pieters - Dikte: 450 mm; Bouwlaag: Level: 00 begane grond; Fase: Nieuw
Name (Floor:28_PBT_FL_beton t.p.g._d=450_C30/37:...) | NetArea (mm2) | NetVolume (m3) | Perimeter (mm)
2674636 | 1960000 | 0.882 | 5600 | BaseQuantities - GrossArea: 1960000 mm2; GrossVolume: 0.882 m3; Width: 450 mm
2674876 | 1960000 | 0.3528 | 5600
2674928 | 1960000 | 0.3528 | 5600
2674982 | 1960000 | 0.3528 | 5600
2675015 | 1960000 | 0.3528 | 5600
2675048 | 1960000 | 0.3528 | 5600
2675114 | 1960000 | 0.3528 | 5600
3890749 | 5593100 | 2.5169 | 53630.7 | BaseQuantities - GrossArea: 5593100 mm2; GrossVolume: 2.5169 m3; Width: 450 mm

# IfcSlab: Floor:28_PBT_FL_beton t.p.g._d=450_C30/37 (2)
In: 00 begane grond
Type - PredefinedType: FLOOR
Type - Pset_ElementShading - Roughness: 304.8 mm
Type - Pset_ProductRequirements - Category: Floors
Type - Pset_ReinforcementBarPitchOfSlab - Description: i.h.w.g. betonvloer d=450
Type - Pset_SlabCommon - IsExternal: no
Type - Pset_Pieters - Naamgeving element: 28_PBT_FL_beton t.p.g._d=450_C30/37; Codering - NL-SfB: 28.21; Omschrijving NL-SfB: hoofddraagconstructies - wanden en vloeren, wand-/vloerconstructies; Materiaal: 00_PBT_MAT_beton t.p.g._C30/37; Materiaalkwaliteit: C30/37; Description: i.h.w.g. betonvloer d=450; Type Comments: d=450
Classification: 28.21 hoofddraagconstructies - wanden en vloeren, wand-/vloerconstructies (Uniformat); Material: 00_PBT_MAT_beton t.p.g._C30/37
Pset_QuantityTakeOff - Reference: Floor:28_PBT_FL_beton t.p.g._d=450_C30/37
Pset_ReinforcementBarPitchOfSlab - Reference: Floor:28_PBT_FL_beton t.p.g._d=450_C30/37
Pset_SlabCommon - LoadBearing: yes; PitchAngle: 0 deg; Reference: Floor:28_PBT_FL_beton t.p.g._d=450_C30/37
Pset_Pieters - Dikte: 450 mm; Bouwlaag: Level: 00 begane grond; Fase: Nieuw
Name (Floor:28_PBT_FL_beton t.p.g._d=450_C30/37:...) | NetArea (mm2) | NetVolume (m3) | Perimeter (mm)
2673133 | 217820659 | 97.9375 | 95136
2683020 | 46499715 | 20.8846 | 101436

# IfcSlab: Floor:28_PBT_FL_beton t.p.g._d=460_C30/37, Floor:28_PBT_FL_beton t.p.g._d=460_C30/37:3220894
In: 00 begane grond
Type - PredefinedType: FLOOR; Material: 00_PBT_MAT_beton t.p.g._C30/37 460 mm
Type - Pset_ElementShading - Roughness: 304.8 mm
Type - Pset_ProductRequirements - Category: Floors
Type - Pset_ReinforcementBarPitchOfSlab - Description: i.h.w.g. betonvloer d=460
Type - Pset_SlabCommon - IsExternal: no
Type - Pset_Pieters - Naamgeving element: 28_PBT_FL_beton t.p.g._d=460_C30/37; Codering - NL-SfB: 28.21; Omschrijving NL-SfB: hoofddraagconstructies - wanden en vloeren, wand-/vloerconstructies; Materiaal: 00_PBT_MAT_beton t.p.g._C30/37; Materiaalkwaliteit: C30/37; Description: i.h.w.g. betonvloer d=460; Type Comments: d=460
Classification: 28.21 hoofddraagconstructies - wanden en vloeren, wand-/vloerconstructies (Uniformat)
Pset_QuantityTakeOff - Reference: Floor:28_PBT_FL_beton t.p.g._d=460_C30/37
Pset_ReinforcementBarPitchOfSlab - Reference: Floor:28_PBT_FL_beton t.p.g._d=460_C30/37
Pset_SlabCommon - LoadBearing: yes; PitchAngle: 0 deg; Reference: Floor:28_PBT_FL_beton t.p.g._d=460_C30/37
Pset_Pieters - Dikte: 460 mm; Bouwlaag: Level: 00 begane grond; Fase: Nieuw
BaseQuantities - GrossArea: 13880180 mm2; NetArea: 13880180 mm2; GrossVolume: 6.38488 m3; NetVolume: 6.38488 m3; Perimeter: 18298.5 mm; Width: 460 mm

# IfcSlab: Floor:28_PBT_FL_beton t.p.g._d=490_bestaand (2)
In: 01 eerste verdieping
Type - PredefinedType: FLOOR; Material: 00_PBT_MAT_beton t.p.g. 490 mm
Type - Pset_ElementShading - Roughness: 304.8 mm
Type - Pset_ProductRequirements - Category: Floors
Type - Pset_ReinforcementBarPitchOfSlab - Description: i.h.w.g. betonvloer d=490
Type - Pset_SlabCommon - IsExternal: no
Type - Pset_Pieters - Naamgeving element: 28_PBT_FL_beton t.p.g._d=490_bestaand; Codering - NL-SfB: 28.21; Omschrijving NL-SfB: hoofddraagconstructies - wanden en vloeren, wand-/vloerconstructies; Materiaal: 00_PBT_MAT_beton t.p.g.; Description: i.h.w.g. betonvloer d=490; Type Comments: d=490
Classification: 28.21 hoofddraagconstructies - wanden en vloeren, wand-/vloerconstructies (Uniformat)
Pset_QuantityTakeOff - Reference: Floor:28_PBT_FL_beton t.p.g._d=490_bestaand
Pset_ReinforcementBarPitchOfSlab - Reference: Floor:28_PBT_FL_beton t.p.g._d=490_bestaand
Pset_SlabCommon - LoadBearing: yes; PitchAngle: 0 deg; Reference: Floor:28_PBT_FL_beton t.p.g._d=490_bestaand
Pset_Pieters - Dragend/niet dragend: yes; In/uitwendig: no; Dikte: 490 mm; Bouwlaag: Level: 01 eerste verdieping_Offset1000; Fase: Bestaand
BaseQuantities - Width: 290 mm
Name (Floor:28_PBT_FL_beton t.p.g._d=490_bestaand:...) | GrossArea (mm2) | NetArea (mm2) | GrossVolume (m3) = NetVolume (m3) | Perimeter (mm)
1589151 | 17536808 | 17536770 | 5.08567 | 18367.4
1590947 | 17914487 | 17914448 | 5.1952 | 18523.3

# IfcSlab: Floor:28_PBT_FL_beton t.p.g._d=500_C30/37 (2)
In: 01 eerste verdieping
Type - PredefinedType: FLOOR; Material: 00_PBT_MAT_beton t.p.g._C30/37 500 mm
Type - Pset_ElementShading - Roughness: 304.8 mm
Type - Pset_ProductRequirements - Category: Floors
Type - Pset_ReinforcementBarPitchOfSlab - Description: i.h.w.g. betonvloer d=500
Type - Pset_SlabCommon - IsExternal: no
Type - Pset_Pieters - Naamgeving element: 28_PBT_FL_beton t.p.g._d=500_C30/37; Codering - NL-SfB: 28.21; Omschrijving NL-SfB: hoofddraagconstructies - wanden en vloeren, wand-/vloerconstructies; Materiaal: 00_PBT_MAT_beton t.p.g._C30/37; Materiaalkwaliteit: C30/37; Description: i.h.w.g. betonvloer d=500
Classification: 28.21 hoofddraagconstructies - wanden en vloeren, wand-/vloerconstructies (Uniformat)
Pset_QuantityTakeOff - Reference: Floor:28_PBT_FL_beton t.p.g._d=500_C30/37
Pset_ReinforcementBarPitchOfSlab - Reference: Floor:28_PBT_FL_beton t.p.g._d=500_C30/37
Pset_SlabCommon - LoadBearing: yes; PitchAngle: 0 deg; Reference: Floor:28_PBT_FL_beton t.p.g._d=500_C30/37
Pset_Pieters - Dikte: 500 mm; Bouwlaag: Level: 01 eerste verdieping; Fase: Nieuw
BaseQuantities - Width: 500 mm
Name (Floor:28_PBT_FL_beton t.p.g._d=500_C30/37:...) | GrossArea (mm2) = NetArea (mm2) | GrossVolume (m3) = NetVolume (m3) | Perimeter (mm)
2017293 | 335217855 | 167.609 | 75732.7
2017696 | 245548948 | 122.774 | 66724

# IfcSlab: Floor:28_PBT_FL_beton t.p.g._d=520_C30/37, Floor:28_PBT_FL_beton t.p.g._d=520_C30/37:4252628
In: 03 derde verdieping
Type - PredefinedType: FLOOR; Material: 00_PBT_MAT_beton t.p.g._C30/37 520 mm
Type - Pset_ElementShading - Roughness: 304.8 mm
Type - Pset_ProductRequirements - Category: Floors
Type - Pset_ReinforcementBarPitchOfSlab - Description: i.h.w.g. betonvloer d=520
Type - Pset_SlabCommon - IsExternal: no
Type - Pset_Pieters - Naamgeving element: 28_PBT_FL_beton t.p.g._d=520_C30/37; Codering - NL-SfB: 28.21; Omschrijving NL-SfB: hoofddraagconstructies - wanden en vloeren, wand-/vloerconstructies; Materiaal: 00_PBT_MAT_beton t.p.g._C30/37; Materiaalkwaliteit: C30/37; Description: i.h.w.g. betonvloer d=520
Classification: 28.21 hoofddraagconstructies - wanden en vloeren, wand-/vloerconstructies (Uniformat)
Pset_QuantityTakeOff - Reference: Floor:28_PBT_FL_beton t.p.g._d=520_C30/37
Pset_ReinforcementBarPitchOfSlab - Reference: Floor:28_PBT_FL_beton t.p.g._d=520_C30/37
Pset_SlabCommon - LoadBearing: yes; PitchAngle: 0 deg; Reference: Floor:28_PBT_FL_beton t.p.g._d=520_C30/37
Pset_Pieters - Dikte: 520 mm; Bouwlaag: Level: 03 derde verdieping; Fase: Nieuw
BaseQuantities - GrossArea: 6648793 mm2; NetArea: 6648793 mm2; GrossVolume: 3.45737 m3; NetVolume: 3.45737 m3; Perimeter: 53690.3 mm; Width: 520 mm

# IfcSlab: Floor:28_PBT_FL_beton t.p.g._d=530_C30/37, Floor:28_PBT_FL_beton t.p.g._d=530_C30/37:2933329
In: 00 begane grond
Type - PredefinedType: FLOOR
Type - Pset_ElementShading - Roughness: 304.8 mm
Type - Pset_ProductRequirements - Category: Floors
Type - Pset_ReinforcementBarPitchOfSlab - Description: i.h.w.g. betonvloer d=530
Type - Pset_SlabCommon - IsExternal: no
Type - Pset_Pieters - Naamgeving element: 28_PBT_FL_beton t.p.g._d=530_C30/37; Codering - NL-SfB: 28.21; Omschrijving NL-SfB: hoofddraagconstructies - wanden en vloeren, wand-/vloerconstructies; Materiaal: 00_PBT_MAT_beton t.p.g._C30/37; Materiaalkwaliteit: C30/37; Description: i.h.w.g. betonvloer d=530
Classification: 28.21 hoofddraagconstructies - wanden en vloeren, wand-/vloerconstructies (Uniformat); Material: 00_PBT_MAT_beton t.p.g._C30/37
Pset_QuantityTakeOff - Reference: Floor:28_PBT_FL_beton t.p.g._d=530_C30/37
Pset_ReinforcementBarPitchOfSlab - Reference: Floor:28_PBT_FL_beton t.p.g._d=530_C30/37
Pset_SlabCommon - LoadBearing: yes; PitchAngle: 0 deg; Reference: Floor:28_PBT_FL_beton t.p.g._d=530_C30/37
Pset_Pieters - Dikte: 530 mm; Bouwlaag: Level: 00 begane grond; Fase: Nieuw; Comments: monolitisch afgewerkt
BaseQuantities - NetArea: 158074963 mm2; NetVolume: 82.0184 m3; Perimeter: 55063 mm

# IfcSlab: Floor:28_PBT_FL_beton t.p.g._d=600_C30/37, Floor:28_PBT_FL_beton t.p.g._d=600_C30/37:2670902
In: 00 begane grond
Type - PredefinedType: FLOOR; Material: 00_PBT_MAT_beton t.p.g._C30/37 600 mm
Type - Pset_ElementShading - Roughness: 304.8 mm
Type - Pset_ProductRequirements - Category: Floors
Type - Pset_ReinforcementBarPitchOfSlab - Description: i.h.w.g. betonvloer d=600
Type - Pset_SlabCommon - IsExternal: no
Type - Pset_Pieters - Naamgeving element: 28_PBT_FL_beton t.p.g._d=600_C30/37; Codering - NL-SfB: 28.21; Omschrijving NL-SfB: hoofddraagconstructies - wanden en vloeren, wand-/vloerconstructies; Materiaal: 00_PBT_MAT_beton t.p.g._C30/37; Materiaalkwaliteit: C30/37; Description: i.h.w.g. betonvloer d=600
Classification: 28.21 hoofddraagconstructies - wanden en vloeren, wand-/vloerconstructies (Uniformat)
Pset_QuantityTakeOff - Reference: Floor:28_PBT_FL_beton t.p.g._d=600_C30/37
Pset_ReinforcementBarPitchOfSlab - Reference: Floor:28_PBT_FL_beton t.p.g._d=600_C30/37
Pset_SlabCommon - LoadBearing: yes; PitchAngle: 0 deg; Reference: Floor:28_PBT_FL_beton t.p.g._d=600_C30/37
Pset_Pieters - Dikte: 600 mm; Bouwlaag: Level: 00 begane grond; Fase: Nieuw
BaseQuantities - GrossArea: 111721619 mm2; NetArea: 103004591 mm2; NetVolume: 61.8028 m3; Perimeter: 72621.4 mm

# IfcSlab: Floor:28_PBT_FL_beton t.p.g._d=660_C30/37, Floor:28_PBT_FL_beton t.p.g._d=660_C30/37:5540904
In: 00 begane grond
Type - PredefinedType: FLOOR; Material: 00_PBT_MAT_beton t.p.g._C30/37 660 mm
Type - Pset_ElementShading - Roughness: 304.8 mm
Type - Pset_ProductRequirements - Category: Floors
Type - Pset_ReinforcementBarPitchOfSlab - Description: i.h.w.g. betonvloer d=660
Type - Pset_SlabCommon - IsExternal: no
Type - Pset_Pieters - Naamgeving element: 28_PBT_FL_beton t.p.g._d=660_C30/37; Codering - NL-SfB: 28.21; Omschrijving NL-SfB: hoofddraagconstructies - wanden en vloeren, wand-/vloerconstructies; Materiaal: 00_PBT_MAT_beton t.p.g._C30/37; Materiaalkwaliteit: C30/37; Description: i.h.w.g. betonvloer d=660; Type Comments: d=660
Classification: 28.21 hoofddraagconstructies - wanden en vloeren, wand-/vloerconstructies (Uniformat)
Pset_QuantityTakeOff - Reference: Floor:28_PBT_FL_beton t.p.g._d=660_C30/37
Pset_ReinforcementBarPitchOfSlab - Reference: Floor:28_PBT_FL_beton t.p.g._d=660_C30/37
Pset_SlabCommon - LoadBearing: yes; PitchAngle: 0 deg; Reference: Floor:28_PBT_FL_beton t.p.g._d=660_C30/37
Pset_Pieters - Dikte: 660 mm; Bouwlaag: Level: 00 begane grond; Fase: Nieuw
BaseQuantities - GrossArea: 17635061 mm2; NetArea: 17635061 mm2; GrossVolume: 11.6391 m3; NetVolume: 11.6391 m3; Perimeter: 24022 mm; Width: 660 mm

# IfcSlab: Floor:28_PBT_FL_druklaag_d=100 (=500)_C30/37, Floor:28_PBT_FL_druklaag_d=100 (=500)_C30/37:3305376
In: 04 vierde verdieping
Type - PredefinedType: FLOOR
Type - Pset_ElementShading - Roughness: 304.8 mm
Type - Pset_ProductRequirements - Category: Floors
Type - Pset_ReinforcementBarPitchOfSlab - Description: gewapende druklaag d=100
Type - Pset_SlabCommon - IsExternal: no
Type - Pset_Pieters - Naamgeving element: 28_PBT_FL_druklaag_d=100 (=500)_C30/37; Codering - NL-SfB: 28.21; Omschrijving NL-SfB: hoofddraagconstructies - wanden en vloeren, wand-/vloerconstructies; Materiaal: 00_PBT_MAT_beton t.p.g._C30/37; Materiaalkwaliteit: C30/37; Description: gewapende druklaag d=100
Classification: 28.21 hoofddraagconstructies - wanden en vloeren, wand-/vloerconstructies (Uniformat); Material: 00_PBT_MAT_beton t.p.g._C30/37
Pset_QuantityTakeOff - Reference: Floor:28_PBT_FL_druklaag_d=100 (=500)_C30/37
Pset_ReinforcementBarPitchOfSlab - Reference: Floor:28_PBT_FL_druklaag_d=100 (=500)_C30/37
Pset_SlabCommon - LoadBearing: yes; PitchAngle: 0 deg; Reference: Floor:28_PBT_FL_druklaag_d=100 (=500)_C30/37
Pset_Pieters - Dikte: 500 mm; Bouwlaag: Level: 04 vierde verdieping; Fase: Nieuw
BaseQuantities - NetArea: 549182098 mm2; NetVolume: 91.457 m3; Perimeter: 99904.6 mm

# IfcSlab: Floor:28_PBT_FL_druklaag_d=100_C30/37 (11)
In: -1 kelder
Type - PredefinedType: FLOOR; Material: 00_PBT_MAT_beton t.p.g._C30/37 100 mm
Type - Pset_ElementShading - Roughness: 304.8 mm
Type - Pset_ProductRequirements - Category: Floors
Type - Pset_ReinforcementBarPitchOfSlab - Description: gewapende druklaag d=100
Type - Pset_SlabCommon - IsExternal: no
Type - Pset_Pieters - Naamgeving element: 28_PBT_FL_druklaag_d=100_C30/37; Codering - NL-SfB: 28.21; Omschrijving NL-SfB: hoofddraagconstructies - wanden en vloeren, wand-/vloerconstructies; Materiaal: 00_PBT_MAT_beton t.p.g._C30/37; Materiaalkwaliteit: C30/37; Description: gewapende druklaag d=100
Classification: 28.21 hoofddraagconstructies - wanden en vloeren, wand-/vloerconstructies (Uniformat)
Pset_QuantityTakeOff - Reference: Floor:28_PBT_FL_druklaag_d=100_C30/37
Pset_ReinforcementBarPitchOfSlab - Reference: Floor:28_PBT_FL_druklaag_d=100_C30/37
Pset_SlabCommon - LoadBearing: yes; PitchAngle: 0 deg; Reference: Floor:28_PBT_FL_druklaag_d=100_C30/37
Pset_Pieters - Dikte: 100 mm; Bouwlaag: Level: -1 kelder; Fase: Nieuw
Name (Floor:28_PBT_FL_druklaag_d=100_C30/37:...) | GrossArea (mm2) | NetArea (mm2) | GrossVolume (m3) | NetVolume (m3) | Perimeter (mm) | Width (mm)
4636885 | 31628811 | 31628811 | 3.16288 | 3.16288 | 34042.3 | 100
4637198 | 34321375 | 33814122 |  | 3.38141 | 33778.9
4640256 | 43457859 | 41198359 |  | 4.11984 | 43028.4
4640924 | 18925434 | 18775434 |  | 1.87754 | 25562.7
4641421 | 40392903 | 40392903 | 4.03929 | 4.03929 | 29596.8 | 100
5096508 | 52270600 | 52270600 | 5.22706 | 5.22706 | 34661.8 | 100
5097144 | 11145000 | 11145000 | 1.1145 | 1.1145 | 13430 | 100
5097538 | 78770136 | 78770136 | 7.87701 | 7.87701 | 65894.7 | 100
5099144 | 21598021 | 21598021 | 2.1598 | 2.1598 | 18642.3 | 100
5352429 | 43374581 | 43374581 | 4.33746 | 4.33746 | 35022.3 | 100
5734763 | 6205641 | 6205641 | 0.620564 | 0.620564 | 12742.7 | 100

# IfcSlab: Floor:28_PBT_FL_druklaag_d=130_C30/37, Floor:28_PBT_FL_druklaag_d=130_C30/37:5353052
In: -1 kelder
Type - PredefinedType: FLOOR; Material: 00_PBT_MAT_beton t.p.g._C30/37 130 mm
Type - Pset_ElementShading - Roughness: 304.8 mm
Type - Pset_ProductRequirements - Category: Floors
Type - Pset_ReinforcementBarPitchOfSlab - Description: gewapende druklaag d=130
Type - Pset_SlabCommon - IsExternal: no
Type - Pset_Pieters - Naamgeving element: 28_PBT_FL_druklaag_d=130_C30/37; Codering - NL-SfB: 28.21; Omschrijving NL-SfB: hoofddraagconstructies - wanden en vloeren, wand-/vloerconstructies; Materiaal: 00_PBT_MAT_beton t.p.g._C30/37; Materiaalkwaliteit: C30/37; Description: gewapende druklaag d=130
Classification: 28.21 hoofddraagconstructies - wanden en vloeren, wand-/vloerconstructies (Uniformat)
Pset_QuantityTakeOff - Reference: Floor:28_PBT_FL_druklaag_d=130_C30/37
Pset_ReinforcementBarPitchOfSlab - Reference: Floor:28_PBT_FL_druklaag_d=130_C30/37
Pset_SlabCommon - LoadBearing: yes; PitchAngle: 0 deg; Reference: Floor:28_PBT_FL_druklaag_d=130_C30/37
Pset_Pieters - Dikte: 130 mm; Bouwlaag: Level: -1 kelder; Fase: Nieuw
BaseQuantities - GrossArea: 4197985 mm2; NetArea: 4197985 mm2; GrossVolume: 0.545738 m3; NetVolume: 0.545738 m3; Perimeter: 21675.5 mm; Width: 130 mm

# IfcSlab: Floor:28_PBT_FL_druklaag_d=140 (=340)_C30/37, Floor:28_PBT_FL_druklaag_d=140 (=340)_C30/37:5859718
In: 02 tweede verdieping
Type - PredefinedType: FLOOR
Type - Pset_ElementShading - Roughness: 304.8 mm
Type - Pset_ProductRequirements - Category: Floors
Type - Pset_ReinforcementBarPitchOfSlab - Description: gewapende druklaag d=140
Type - Pset_SlabCommon - IsExternal: no
Type - Pset_Pieters - Naamgeving element: 28_PBT_FL_druklaag_d=140 (=340)_C30/37; Codering - NL-SfB: 28.21; Omschrijving NL-SfB: hoofddraagconstructies - wanden en vloeren, wand-/vloerconstructies; Materiaal: 00_PBT_MAT_beton t.p.g._C30/37; Materiaalkwaliteit: C30/37; Description: gewapende druklaag d=140
Classification: 28.21 hoofddraagconstructies - wanden en vloeren, wand-/vloerconstructies (Uniformat); Material: 00_PBT_MAT_beton t.p.g._C30/37
Pset_QuantityTakeOff - Reference: Floor:28_PBT_FL_druklaag_d=140 (=340)_C30/37
Pset_ReinforcementBarPitchOfSlab - Reference: Floor:28_PBT_FL_druklaag_d=140 (=340)_C30/37
Pset_SlabCommon - LoadBearing: yes; PitchAngle: 0 deg; Reference: Floor:28_PBT_FL_druklaag_d=140 (=340)_C30/37
Pset_Pieters - Dikte: 340 mm; Bouwlaag: Level: 02 tweede verdieping; Fase: Nieuw
BaseQuantities - NetArea: 21611606 mm2; NetVolume: 3.43627 m3; Perimeter: 28767.8 mm

# IfcSlab: Floor:28_PBT_FL_druklaag_d=180 (=380)_C30/37 (3)
Type - PredefinedType: FLOOR
Type - Pset_ElementShading - Roughness: 304.8 mm
Type - Pset_ProductRequirements - Category: Floors
Type - Pset_ReinforcementBarPitchOfSlab - Description: gewapende druklaag d=180
Type - Pset_SlabCommon - IsExternal: no
Type - Pset_Pieters - Naamgeving element: 28_PBT_FL_druklaag_d=180 (=380)_C30/37; Codering - NL-SfB: 28.21; Omschrijving NL-SfB: hoofddraagconstructies - wanden en vloeren, wand-/vloerconstructies; Materiaal: 00_PBT_MAT_beton t.p.g._C30/37; Materiaalkwaliteit: C30/37; Description: gewapende druklaag d=180
Classification: 28.21 hoofddraagconstructies - wanden en vloeren, wand-/vloerconstructies (Uniformat); Material: 00_PBT_MAT_beton t.p.g._C30/37
Pset_QuantityTakeOff - Reference: Floor:28_PBT_FL_druklaag_d=180 (=380)_C30/37
Pset_ReinforcementBarPitchOfSlab - Reference: Floor:28_PBT_FL_druklaag_d=180 (=380)_C30/37
Pset_SlabCommon - LoadBearing: yes; PitchAngle: 0 deg; Reference: Floor:28_PBT_FL_druklaag_d=180 (=380)_C30/37
Pset_Pieters - Dikte: 380 mm; Fase: Nieuw
BaseQuantities - Perimeter: 23568.7 mm
Name (Floor:28_PBT_FL_druklaag_d=180 (=380)_C30/37:...) | In | Bouwlaag | NetArea (mm2) | NetVolume (m3)
5211518 | 01 eerste verdieping | Level: 01 eerste verdieping | 19511478 | 3.97679
5212716 | 02 tweede verdieping | Level: 02 tweede verdieping | 15684615 | 3.33486
5213892 | 03 derde verdieping | Level: 03 derde verdieping | 15360038 | 3.24889

# IfcSlab: Floor:28_PBT_FL_druklaag_d=300_C30/37, Floor:28_PBT_FL_druklaag_d=300_C30/37:5096944
In: -1 kelder
Type - PredefinedType: FLOOR; Material: 00_PBT_MAT_beton t.p.g._C30/37 300 mm
Type - Pset_ElementShading - Roughness: 304.8 mm
Type - Pset_ProductRequirements - Category: Floors
Type - Pset_ReinforcementBarPitchOfSlab - Description: gewapende druklaag d=300
Type - Pset_SlabCommon - IsExternal: no
Type - Pset_Pieters - Naamgeving element: 28_PBT_FL_druklaag_d=300_C30/37; Codering - NL-SfB: 28.21; Omschrijving NL-SfB: hoofddraagconstructies - wanden en vloeren, wand-/vloerconstructies; Materiaal: 00_PBT_MAT_beton t.p.g._C30/37; Materiaalkwaliteit: C30/37; Description: gewapende druklaag d=300
Classification: 28.21 hoofddraagconstructies - wanden en vloeren, wand-/vloerconstructies (Uniformat)
Pset_QuantityTakeOff - Reference: Floor:28_PBT_FL_druklaag_d=300_C30/37
Pset_ReinforcementBarPitchOfSlab - Reference: Floor:28_PBT_FL_druklaag_d=300_C30/37
Pset_SlabCommon - LoadBearing: yes; PitchAngle: 0 deg; Reference: Floor:28_PBT_FL_druklaag_d=300_C30/37
Pset_Pieters - Dikte: 300 mm; Bouwlaag: Level: -1 kelder; Fase: Nieuw
BaseQuantities - GrossArea: 11685965 mm2; NetArea: 11685965 mm2; GrossVolume: 3.50579 m3; NetVolume: 3.50579 m3; Perimeter: 14862.2 mm; Width: 300 mm

# IfcSlab: Floor:28_PBT_FL_druklaag_d=350_C30/37, Floor:28_PBT_FL_druklaag_d=350_C30/37:6039979
In: -1 kelder
Type - PredefinedType: FLOOR; Material: 00_PBT_MAT_beton t.p.g._C30/37 350 mm
Type - Pset_ElementShading - Roughness: 304.8 mm
Type - Pset_ProductRequirements - Category: Floors
Type - Pset_ReinforcementBarPitchOfSlab - Description: gewapende druklaag d=350
Type - Pset_SlabCommon - IsExternal: no
Type - Pset_Pieters - Naamgeving element: 28_PBT_FL_druklaag_d=350_C30/37; Codering - NL-SfB: 28.21; Omschrijving NL-SfB: hoofddraagconstructies - wanden en vloeren, wand-/vloerconstructies; Materiaal: 00_PBT_MAT_beton t.p.g._C30/37; Materiaalkwaliteit: C30/37; Description: gewapende druklaag d=350
Classification: 28.21 hoofddraagconstructies - wanden en vloeren, wand-/vloerconstructies (Uniformat)
Pset_QuantityTakeOff - Reference: Floor:28_PBT_FL_druklaag_d=350_C30/37
Pset_ReinforcementBarPitchOfSlab - Reference: Floor:28_PBT_FL_druklaag_d=350_C30/37
Pset_SlabCommon - LoadBearing: yes; PitchAngle: 0 deg; Reference: Floor:28_PBT_FL_druklaag_d=350_C30/37
Pset_Pieters - Dikte: 350 mm; Bouwlaag: Level: -1 kelder; Fase: Nieuw
BaseQuantities - GrossArea: 84694474 mm2; NetArea: 84331858 mm2; NetVolume: 29.5167 m3; Perimeter: 48414.5 mm

# IfcSlab: Floor:28_PBT_FL_druklaag_d=50 (=370)_C30/37 (3)
In: 04 vierde verdieping
Type - PredefinedType: FLOOR
Type - Pset_ElementShading - Roughness: 304.8 mm
Type - Pset_ProductRequirements - Category: Floors
Type - Pset_ReinforcementBarPitchOfSlab - Description: gewapende druklaag d=50
Type - Pset_SlabCommon - IsExternal: no
Type - Pset_Pieters - Naamgeving element: 28_PBT_FL_druklaag_d=50 (=370)_C30/37; Codering - NL-SfB: 28.21; Omschrijving NL-SfB: hoofddraagconstructies - wanden en vloeren, wand-/vloerconstructies; Materiaal: 00_PBT_MAT_beton t.p.g._C30/37; Materiaalkwaliteit: C30/37; Description: gewapende druklaag d=50
Classification: 28.21 hoofddraagconstructies - wanden en vloeren, wand-/vloerconstructies (Uniformat); Material: 00_PBT_MAT_beton t.p.g._C30/37
Pset_QuantityTakeOff - Reference: Floor:28_PBT_FL_druklaag_d=50 (=370)_C30/37
Pset_ReinforcementBarPitchOfSlab - Reference: Floor:28_PBT_FL_druklaag_d=50 (=370)_C30/37
Pset_SlabCommon - LoadBearing: yes; Reference: Floor:28_PBT_FL_druklaag_d=50 (=370)_C30/37
Pset_Pieters - Dikte: 370 mm; Bouwlaag: Level: 04 vierde verdieping; Fase: Nieuw
Name (Floor:28_PBT_FL_druklaag_d=50 (=370)_C30/37:...) | PitchAngle (deg) | NetArea (mm2) | NetVolume (m3) | Perimeter (mm)
2753868 | 4.57156 | 113066630 | 10.979 | 55769.1
2754378 | 9 | 127196551 | 11.0386 | 55774.2
2796911 | 21.3 | 109006672 | 12.0595 | 53411

# IfcSlab: Floor:28_PBT_FL_druklaag_d=60 (=260)_C30/37 (3)
In: 03 derde verdieping
Type - PredefinedType: FLOOR
Type - Pset_ElementShading - Roughness: 304.8 mm
Type - Pset_ProductRequirements - Category: Floors
Type - Pset_ReinforcementBarPitchOfSlab - Description: gewapende druklaag d=60
Type - Pset_SlabCommon - IsExternal: no
Type - Pset_Pieters - Naamgeving element: 28_PBT_FL_druklaag_d=60 (=260)_C30/37; Codering - NL-SfB: 28.21; Omschrijving NL-SfB: hoofddraagconstructies - wanden en vloeren, wand-/vloerconstructies; Materiaal: 00_PBT_MAT_beton t.p.g._C30/37; Materiaalkwaliteit: C30/37; Description: gewapende druklaag d=60
Classification: 28.21 hoofddraagconstructies - wanden en vloeren, wand-/vloerconstructies (Uniformat); Material: 00_PBT_MAT_beton t.p.g._C30/37
Pset_QuantityTakeOff - Reference: Floor:28_PBT_FL_druklaag_d=60 (=260)_C30/37
Pset_ReinforcementBarPitchOfSlab - Reference: Floor:28_PBT_FL_druklaag_d=60 (=260)_C30/37
Pset_SlabCommon - LoadBearing: yes; PitchAngle: 0 deg; Reference: Floor:28_PBT_FL_druklaag_d=60 (=260)_C30/37
Pset_Pieters - Dikte: 260 mm; Bouwlaag: Level: 03 derde verdieping; Fase: Nieuw
Name (Floor:28_PBT_FL_druklaag_d=60 (=260)_C30/37:...) | NetArea (mm2) | NetVolume (m3) | Perimeter (mm)
2419080 | 143109087 | 11.9979 | 88026.7
2424215 | 231973513 | 16.3549 | 180268
4262079 | 9687578 | 0.810162 | 14955.4

# IfcSlab: Floor:28_PBT_FL_druklaag_d=60 (=320)_C30/37 (5)
Type - PredefinedType: FLOOR
Type - Pset_ElementShading - Roughness: 304.8 mm
Type - Pset_ProductRequirements - Category: Floors
Type - Pset_ReinforcementBarPitchOfSlab - Description: gewapende druklaag d=60
Type - Pset_SlabCommon - IsExternal: no
Type - Pset_Pieters - Naamgeving element: 28_PBT_FL_druklaag_d=60 (=320)_C30/37; Codering - NL-SfB: 28.21; Omschrijving NL-SfB: hoofddraagconstructies - wanden en vloeren, wand-/vloerconstructies; Materiaal: 00_PBT_MAT_beton t.p.g._C30/37; Materiaalkwaliteit: C30/37; Description: gewapende druklaag d=60
Classification: 28.21 hoofddraagconstructies - wanden en vloeren, wand-/vloerconstructies (Uniformat); Material: 00_PBT_MAT_beton t.p.g._C30/37
Pset_QuantityTakeOff - Reference: Floor:28_PBT_FL_druklaag_d=60 (=320)_C30/37
Pset_ReinforcementBarPitchOfSlab - Reference: Floor:28_PBT_FL_druklaag_d=60 (=320)_C30/37
Pset_SlabCommon - LoadBearing: yes; Reference: Floor:28_PBT_FL_druklaag_d=60 (=320)_C30/37
Pset_Pieters - Dikte: 320 mm; Fase: Nieuw
Name (Floor:28_PBT_FL_druklaag_d=60 (=320)_C30/37:...) | In | PitchAngle (deg) | Bouwlaag | NetArea (mm2) | NetVolume (m3) | Perimeter (mm)
2490689 | 06 zesde verdieping | 0 | Level: 06 zesde verdieping | 284107975 | 24.8169 | 67697.1
2599623 | 06 zesde verdieping | 0 | Level: 06 zesde verdieping | 167443626 | 16.0597 | 55580.6
2600265 | 06 zesde verdieping | 0 | Level: 06 zesde verdieping | 184066125 | 18.5046 | 64511.8
2968723 | 04 vierde verdieping | 9 | Level: 04 vierde verdieping | 151516732 | 12.1943 | 57122.5
2969493 | 04 vierde verdieping | 0 | Level: 04 vierde verdieping | 83121332 | 5.64937 | 48645.8

# IfcSlab: Floor:28_PBT_FL_druklaag_d=60 (=380)_C30/37 (6)
Type - PredefinedType: FLOOR
Type - Pset_ElementShading - Roughness: 304.8 mm
Type - Pset_ProductRequirements - Category: Floors
Type - Pset_ReinforcementBarPitchOfSlab - Description: gewapende druklaag d=60
Type - Pset_SlabCommon - IsExternal: no
Type - Pset_Pieters - Naamgeving element: 28_PBT_FL_druklaag_d=60 (=380)_C30/37; Codering - NL-SfB: 28.21; Omschrijving NL-SfB: hoofddraagconstructies - wanden en vloeren, wand-/vloerconstructies; Materiaal: 00_PBT_MAT_beton t.p.g._C30/37; Materiaalkwaliteit: C30/37; Description: gewapende druklaag d=60
Classification: 28.21 hoofddraagconstructies - wanden en vloeren, wand-/vloerconstructies (Uniformat); Material: 00_PBT_MAT_beton t.p.g._C30/37
Pset_QuantityTakeOff - Reference: Floor:28_PBT_FL_druklaag_d=60 (=380)_C30/37
Pset_ReinforcementBarPitchOfSlab - Reference: Floor:28_PBT_FL_druklaag_d=60 (=380)_C30/37
Pset_SlabCommon - LoadBearing: yes; PitchAngle: 0 deg; Reference: Floor:28_PBT_FL_druklaag_d=60 (=380)_C30/37
Pset_Pieters - Dikte: 380 mm; Fase: Nieuw
Name (Floor:28_PBT_FL_druklaag_d=60 (=380)_C30/37:...) | In | Bouwlaag | NetArea (mm2) | NetVolume (m3) | Perimeter (mm)
2362857 | 01 eerste verdieping | Level: 01 eerste verdieping | 189515173 | 15.9588 | 70771.1
2385557 | 01 eerste verdieping | Level: 01 eerste verdieping | 397514013 | 39.8494 | 120811
2404954 | 02 tweede verdieping | Level: 02 tweede verdieping | 233800005 | 24.5335 | 89179.2
2836537 | 03 derde verdieping | Level: 03 derde verdieping | 121520492 | 12.8658 | 70625.5
2840819 | 03 derde verdieping | Level: 03 derde verdieping | 136824572 | 13.9495 | 69797
5521337 | 02 tweede verdieping | Level: 02 tweede verdieping | 184813859 | 15.2653 | 69779.8

# IfcSlab: Floor:28_PBT_FL_druklaag_d=60 (=445)_C30/37, Floor:28_PBT_FL_druklaag_d=60 (=445)_C30/37:2668897
In: 00 begane grond
Type - PredefinedType: FLOOR
Type - Pset_ElementShading - Roughness: 304.8 mm
Type - Pset_ProductRequirements - Category: Floors
Type - Pset_ReinforcementBarPitchOfSlab - Description: gewapende druklaag d=60
Type - Pset_SlabCommon - IsExternal: no
Type - Pset_Pieters - Naamgeving element: 28_PBT_FL_druklaag_d=60 (=445)_C30/37; Codering - NL-SfB: 28.21; Omschrijving NL-SfB: hoofddraagconstructies - wanden en vloeren, wand-/vloerconstructies; Materiaal: 00_PBT_MAT_beton t.p.g._C30/37; Materiaalkwaliteit: C30/37; Description: gewapende druklaag d=60
Classification: 28.21 hoofddraagconstructies - wanden en vloeren, wand-/vloerconstructies (Uniformat); Material: 00_PBT_MAT_beton t.p.g._C30/37
Pset_QuantityTakeOff - Reference: Floor:28_PBT_FL_druklaag_d=60 (=445)_C30/37
Pset_ReinforcementBarPitchOfSlab - Reference: Floor:28_PBT_FL_druklaag_d=60 (=445)_C30/37
Pset_SlabCommon - LoadBearing: yes; PitchAngle: 0 deg; Reference: Floor:28_PBT_FL_druklaag_d=60 (=445)_C30/37
Pset_Pieters - Dikte: 445 mm; Bouwlaag: Level: 00 begane grond; Fase: Nieuw
BaseQuantities - NetArea: 123745441 mm2; NetVolume: 19.0134 m3; Perimeter: 59941.8 mm

# IfcSlab: Floor:28_PBT_FL_druklaag_d=600_C30/37, Floor:28_PBT_FL_druklaag_d=600_C30/37:4640657
In: -1 kelder
Type - PredefinedType: FLOOR; Material: 00_PBT_MAT_beton t.p.g._C30/37 600 mm
Type - Pset_ElementShading - Roughness: 304.8 mm
Type - Pset_ProductRequirements - Category: Floors
Type - Pset_ReinforcementBarPitchOfSlab - Description: gewapende druklaag d=600
Type - Pset_SlabCommon - IsExternal: no
Type - Pset_Pieters - Naamgeving element: 28_PBT_FL_druklaag_d=600_C30/37; Codering - NL-SfB: 28.21; Omschrijving NL-SfB: hoofddraagconstructies - wanden en vloeren, wand-/vloerconstructies; Materiaal: 00_PBT_MAT_beton t.p.g._C30/37; Materiaalkwaliteit: C30/37; Description: gewapende druklaag d=600
Classification: 28.21 hoofddraagconstructies - wanden en vloeren, wand-/vloerconstructies (Uniformat)
Pset_QuantityTakeOff - Reference: Floor:28_PBT_FL_druklaag_d=600_C30/37
Pset_ReinforcementBarPitchOfSlab - Reference: Floor:28_PBT_FL_druklaag_d=600_C30/37
Pset_SlabCommon - LoadBearing: yes; PitchAngle: 0 deg; Reference: Floor:28_PBT_FL_druklaag_d=600_C30/37
Pset_Pieters - Dikte: 600 mm; Bouwlaag: Level: -1 kelder; Fase: Nieuw
BaseQuantities - GrossArea: 4090638 mm2; NetArea: 4090638 mm2; GrossVolume: 2.45438 m3; NetVolume: 2.45438 m3; Perimeter: 8657.49 mm; Width: 600 mm

# IfcSlab: Floor:28_PBT_FL_druklaag_d=80 (=195)_C30/37, Floor:28_PBT_FL_druklaag_d=80 (=195)_C30/37:5009259
In: 04 vierde verdieping
Type - PredefinedType: FLOOR
Type - Pset_ElementShading - Roughness: 304.8 mm
Type - Pset_ProductRequirements - Category: Floors
Type - Pset_ReinforcementBarPitchOfSlab - Description: gewapende druklaag d=80
Type - Pset_SlabCommon - IsExternal: no
Type - Pset_Pieters - Naamgeving element: 28_PBT_FL_druklaag_d=80 (=195)_C30/37; Codering - NL-SfB: 28.21; Omschrijving NL-SfB: hoofddraagconstructies - wanden en vloeren, wand-/vloerconstructies; Materiaal: 00_PBT_MAT_beton t.p.g._C30/37; Materiaalkwaliteit: C30/37; Description: gewapende druklaag d=80
Classification: 28.21 hoofddraagconstructies - wanden en vloeren, wand-/vloerconstructies (Uniformat); Material: 00_PBT_MAT_beton t.p.g._C30/37
Pset_QuantityTakeOff - Reference: Floor:28_PBT_FL_druklaag_d=80 (=195)_C30/37
Pset_ReinforcementBarPitchOfSlab - Reference: Floor:28_PBT_FL_druklaag_d=80 (=195)_C30/37
Pset_SlabCommon - LoadBearing: yes; PitchAngle: 0 deg; Reference: Floor:28_PBT_FL_druklaag_d=80 (=195)_C30/37
Pset_Pieters - Dikte: 195 mm; Bouwlaag: Level: 04 vierde verdieping; Fase: Nieuw
BaseQuantities - NetArea: 152117 mm2; NetVolume: 0.0258774 m3; Perimeter: 2129.61 mm

# IfcSlab: Floor:28_PBT_FL_druklaag_d=80 (=280)_C30/37, Floor:28_PBT_FL_druklaag_d=80 (=280)_C30/37:2156788
In: 03 derde verdieping
Type - PredefinedType: FLOOR
Type - Pset_ElementShading - Roughness: 304.8 mm
Type - Pset_ProductRequirements - Category: Floors
Type - Pset_ReinforcementBarPitchOfSlab - Description: gewapende druklaag d=80
Type - Pset_SlabCommon - IsExternal: no
Type - Pset_Pieters - Naamgeving element: 28_PBT_FL_druklaag_d=80 (=280)_C30/37; Codering - NL-SfB: 28.21; Omschrijving NL-SfB: hoofddraagconstructies - wanden en vloeren, wand-/vloerconstructies; Materiaal: 00_PBT_MAT_beton t.p.g._C30/37; Materiaalkwaliteit: C30/37; Description: gewapende druklaag d=80
Classification: 28.21 hoofddraagconstructies - wanden en vloeren, wand-/vloerconstructies (Uniformat); Material: 00_PBT_MAT_beton t.p.g._C30/37
Pset_QuantityTakeOff - Reference: Floor:28_PBT_FL_druklaag_d=80 (=280)_C30/37
Pset_ReinforcementBarPitchOfSlab - Reference: Floor:28_PBT_FL_druklaag_d=80 (=280)_C30/37
Pset_SlabCommon - LoadBearing: yes; PitchAngle: 0 deg; Reference: Floor:28_PBT_FL_druklaag_d=80 (=280)_C30/37
Pset_Pieters - Dikte: 280 mm; Bouwlaag: Level: 03 derde verdieping; Fase: Nieuw
BaseQuantities - NetArea: 63964833 mm2; NetVolume: 7.5592 m3; Perimeter: 39687.5 mm

# IfcSlab: Floor:28_PBT_FL_druklaag_d=80 (=340)_C30/37, Floor:28_PBT_FL_druklaag_d=80 (=340)_C30/37:2404102
In: 02 tweede verdieping
Type - PredefinedType: FLOOR; Material: 00_PBT_MAT_beton t.p.g._C30/37 340 mm
Type - Pset_ElementShading - Roughness: 304.8 mm
Type - Pset_ProductRequirements - Category: Floors
Type - Pset_ReinforcementBarPitchOfSlab - Description: gewapende druklaag d=80
Type - Pset_SlabCommon - IsExternal: no
Type - Pset_Pieters - Naamgeving element: 28_PBT_FL_druklaag_d=80 (=340)_C30/37; Codering - NL-SfB: 28.21; Omschrijving NL-SfB: hoofddraagconstructies - wanden en vloeren, wand-/vloerconstructies; Materiaal: 00_PBT_MAT_beton t.p.g._C30/37; Materiaalkwaliteit: C30/37; Description: gewapende druklaag d=80
Classification: 28.21 hoofddraagconstructies - wanden en vloeren, wand-/vloerconstructies (Uniformat)
Pset_QuantityTakeOff - Reference: Floor:28_PBT_FL_druklaag_d=80 (=340)_C30/37
Pset_ReinforcementBarPitchOfSlab - Reference: Floor:28_PBT_FL_druklaag_d=80 (=340)_C30/37
Pset_SlabCommon - LoadBearing: yes; PitchAngle: 0 deg; Reference: Floor:28_PBT_FL_druklaag_d=80 (=340)_C30/37
Pset_Pieters - Dikte: 340 mm; Bouwlaag: Level: 02 tweede verdieping; Fase: Nieuw
BaseQuantities - NetArea: 118796281 mm2; NetVolume: 10.005 m3; Perimeter: 61800.8 mm

# IfcSlab: Floor:28_PBT_FL_druklaag_d=80 (=400)_C30/37, Floor:28_PBT_FL_druklaag_d=80 (=400)_C30/37:3568433
In: 01 eerste verdieping
Type - PredefinedType: FLOOR; Material: 00_PBT_MAT_beton t.p.g._C30/37 400 mm
Type - Pset_ElementShading - Roughness: 304.8 mm
Type - Pset_ProductRequirements - Category: Floors
Type - Pset_ReinforcementBarPitchOfSlab - Description: gewapende druklaag d=80
Type - Pset_SlabCommon - IsExternal: no
Type - Pset_Pieters - Naamgeving element: 28_PBT_FL_druklaag_d=80 (=400)_C30/37; Codering - NL-SfB: 28.21; Omschrijving NL-SfB: hoofddraagconstructies - wanden en vloeren, wand-/vloerconstructies; Materiaal: 00_PBT_MAT_beton t.p.g._C30/37; Materiaalkwaliteit: C30/37; Description: gewapende druklaag d=80
Classification: 28.21 hoofddraagconstructies - wanden en vloeren, wand-/vloerconstructies (Uniformat)
Pset_QuantityTakeOff - Reference: Floor:28_PBT_FL_druklaag_d=80 (=400)_C30/37
Pset_ReinforcementBarPitchOfSlab - Reference: Floor:28_PBT_FL_druklaag_d=80 (=400)_C30/37
Pset_SlabCommon - LoadBearing: yes; PitchAngle: 0 deg; Reference: Floor:28_PBT_FL_druklaag_d=80 (=400)_C30/37
Pset_Pieters - Dikte: 400 mm; Bouwlaag: Level: 01 eerste verdieping; Fase: Nieuw
BaseQuantities - NetArea: 44902886 mm2; NetVolume: 3.84235 m3; Perimeter: 31417.5 mm

# IfcSlab: Floor:28_PBT_FL_druklaag_d=80 (=400)_C30/37 (8)
Type - PredefinedType: FLOOR
Type - Pset_ElementShading - Roughness: 304.8 mm
Type - Pset_ProductRequirements - Category: Floors
Type - Pset_ReinforcementBarPitchOfSlab - Description: gewapende druklaag d=80
Type - Pset_SlabCommon - IsExternal: no
Type - Pset_Pieters - Naamgeving element: 28_PBT_FL_druklaag_d=80 (=400)_C30/37; Codering - NL-SfB: 28.21; Omschrijving NL-SfB: hoofddraagconstructies - wanden en vloeren, wand-/vloerconstructies; Materiaal: 00_PBT_MAT_beton t.p.g._C30/37; Materiaalkwaliteit: C30/37; Description: gewapende druklaag d=80
Classification: 28.21 hoofddraagconstructies - wanden en vloeren, wand-/vloerconstructies (Uniformat); Material: 00_PBT_MAT_beton t.p.g._C30/37
Pset_QuantityTakeOff - Reference: Floor:28_PBT_FL_druklaag_d=80 (=400)_C30/37
Pset_ReinforcementBarPitchOfSlab - Reference: Floor:28_PBT_FL_druklaag_d=80 (=400)_C30/37
Pset_SlabCommon - LoadBearing: yes; PitchAngle: 0 deg; Reference: Floor:28_PBT_FL_druklaag_d=80 (=400)_C30/37
Pset_Pieters - Dikte: 400 mm; Fase: Nieuw
Name (Floor:28_PBT_FL_druklaag_d=80 (=400)_C30/37:...) | In | Bouwlaag | NetArea (mm2) | NetVolume (m3) | Perimeter (mm)
2397569 | 04 vierde verdieping | Level: 04 vierde verdieping | 59721833 | 5.98826 | 44821.8
2404579 | 02 tweede verdieping | Level: 02 tweede verdieping | 96068988 | 9.09182 | 53853.4
2435781 | 04 vierde verdieping | Level: 04 vierde verdieping | 86145973 | 10.2409 | 60588.4
2439356 | 05 vijfde verdieping | Level: 05 vijfde verdieping | 92339265 | 11.7266 | 60834.7
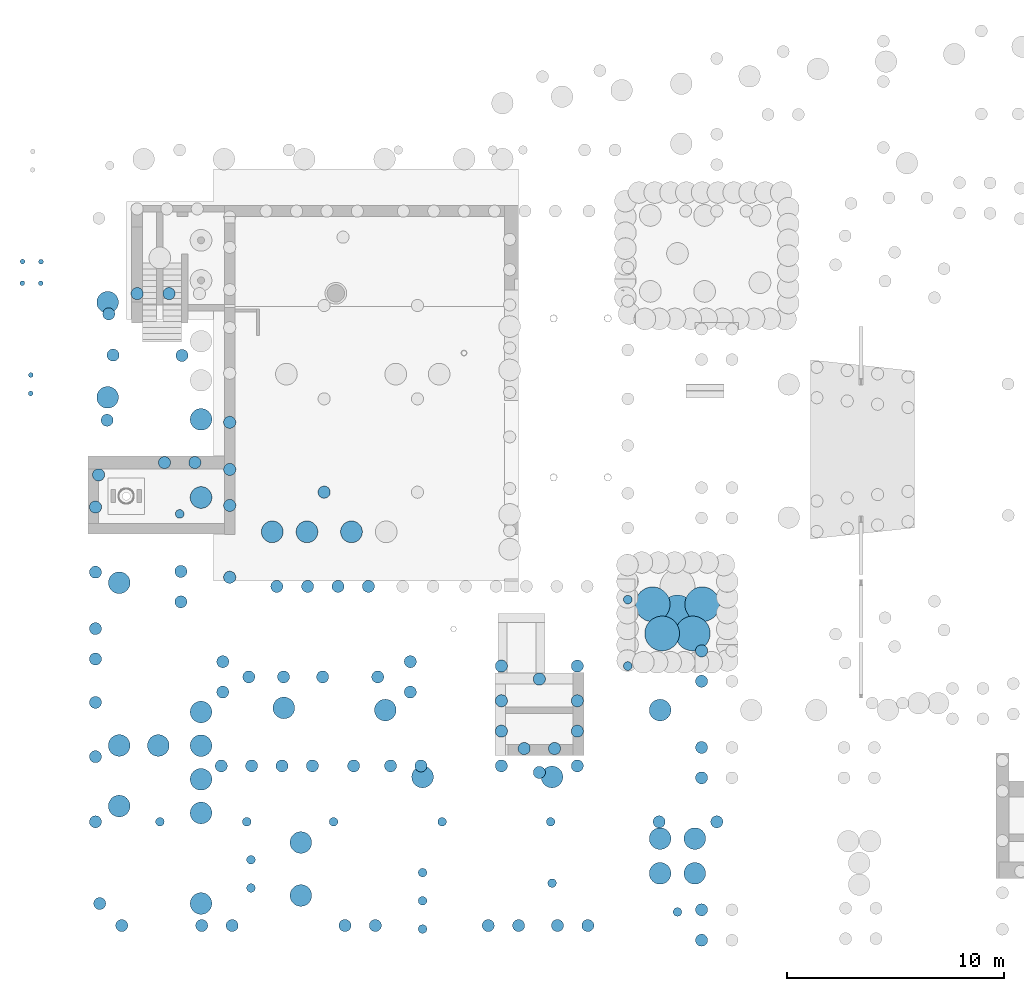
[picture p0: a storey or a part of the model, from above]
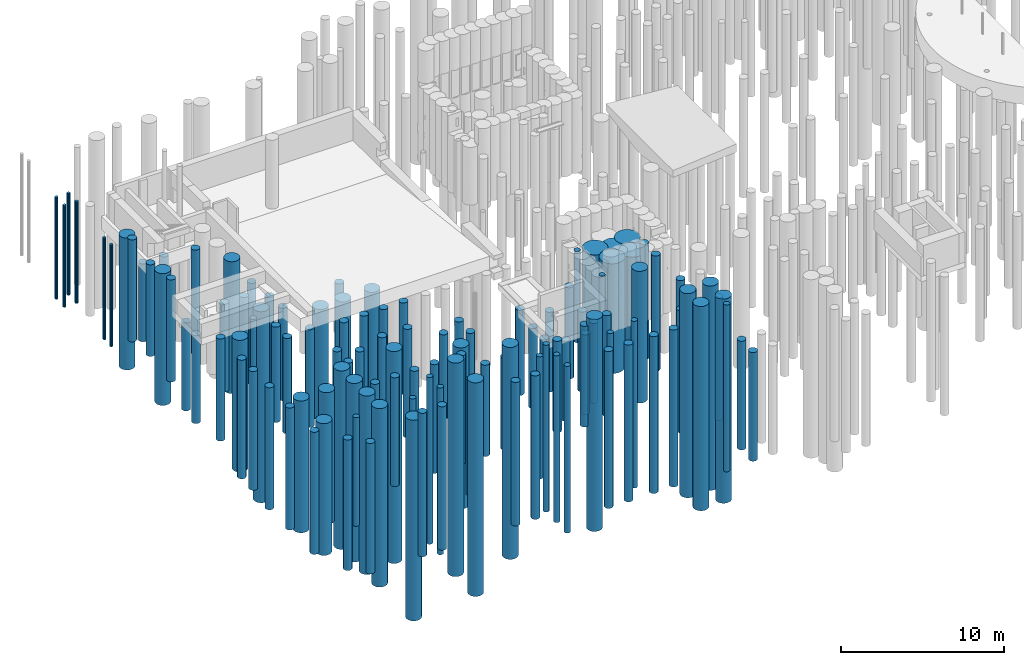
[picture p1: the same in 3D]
Properties of the parts of a building model (IFC2X3), part 15 of 18

# IfcSlab: Floor:28_PBT_FL_druklaag_d=80 (=400)_C30/37 (8)
Name (Floor:28_PBT_FL_druklaag_d=80 (=400)_C30/37:...) | In | Bouwlaag | NetArea (mm2) | NetVolume (m3) | Perimeter (mm)
2829928 | 04 vierde verdieping | Level: 04 vierde verdieping | 76639667 | 9.32619 | 52232.5
2834862 | 04 vierde verdieping | Level: 04 vierde verdieping | 130286550 | 16.7395 | 67959.8
2852328 | 04 vierde verdieping | Level: 04 vierde verdieping | 59632616 | 8.22969 | 47484.4
5518774 | 01 eerste verdieping | Level: 01 eerste verdieping | 115948897 | 11.6833 | 72283.9

# IfcSlab: Floor:28_PBT_FL_druklaag_d=80_C30/37, Floor:28_PBT_FL_druklaag_d=80_C30/37:4755854
In: 04 vierde verdieping
Type - PredefinedType: FLOOR; Material: 00_PBT_MAT_beton t.p.g._C30/37 80 mm
Type - Pset_ElementShading - Roughness: 304.8 mm
Type - Pset_ProductRequirements - Category: Floors
Type - Pset_ReinforcementBarPitchOfSlab - Description: gewapende druklaag d=80
Type - Pset_SlabCommon - IsExternal: no
Type - Pset_Pieters - Naamgeving element: 28_PBT_FL_druklaag_d=80_C30/37; Codering - NL-SfB: 28.21; Omschrijving NL-SfB: hoofddraagconstructies - wanden en vloeren, wand-/vloerconstructies; Materiaal: 00_PBT_MAT_beton t.p.g._C30/37; Materiaalkwaliteit: C30/37; Description: gewapende druklaag d=80
Classification: 28.21 hoofddraagconstructies - wanden en vloeren, wand-/vloerconstructies (Uniformat)
Pset_QuantityTakeOff - Reference: Floor:28_PBT_FL_druklaag_d=80_C30/37
Pset_ReinforcementBarPitchOfSlab - Reference: Floor:28_PBT_FL_druklaag_d=80_C30/37
Pset_SlabCommon - LoadBearing: yes; PitchAngle: 0 deg; Reference: Floor:28_PBT_FL_druklaag_d=80_C30/37
Pset_Pieters - Dikte: 80 mm; Bouwlaag: Level: 04 vierde verdieping; Fase: Nieuw
BaseQuantities - GrossArea: 178747 mm2; NetArea: 178747 mm2; GrossVolume: 0.00859952 m3; NetVolume: 0.00429976 m3; Perimeter: 3597.13 mm; Width: 48.11 mm

# IfcSlab: Floor:28_PBT_FL_druklaag_d=80_C30/37, Floor:28_PBT_FL_druklaag_d=80_C30/37:4742031
In: 04 vierde verdieping
Type - PredefinedType: FLOOR
Type - Pset_ElementShading - Roughness: 304.8 mm
Type - Pset_ProductRequirements - Category: Floors
Type - Pset_ReinforcementBarPitchOfSlab - Description: gewapende druklaag d=80
Type - Pset_SlabCommon - IsExternal: no
Type - Pset_Pieters - Naamgeving element: 28_PBT_FL_druklaag_d=80_C30/37; Codering - NL-SfB: 28.21; Omschrijving NL-SfB: hoofddraagconstructies - wanden en vloeren, wand-/vloerconstructies; Materiaal: 00_PBT_MAT_beton t.p.g._C30/37; Materiaalkwaliteit: C30/37; Description: gewapende druklaag d=80
Classification: 28.21 hoofddraagconstructies - wanden en vloeren, wand-/vloerconstructies (Uniformat); Material: 00_PBT_MAT_beton t.p.g._C30/37
Pset_QuantityTakeOff - Reference: Floor:28_PBT_FL_druklaag_d=80_C30/37
Pset_ReinforcementBarPitchOfSlab - Reference: Floor:28_PBT_FL_druklaag_d=80_C30/37
Pset_SlabCommon - LoadBearing: yes; PitchAngle: 0 deg; Reference: Floor:28_PBT_FL_druklaag_d=80_C30/37
Pset_Pieters - Dikte: 80 mm; Bouwlaag: Level: 04 vierde verdieping; Fase: Nieuw
BaseQuantities - NetArea: 9885408 mm2; NetVolume: 0.359968 m3; Perimeter: 43965.5 mm

# IfcSlab: Floor:28_PBT_FL_geïsoleerde kanaalplaat_d=200 (4)
In: 00 begane grond
Type - PredefinedType: FLOOR; Material: 00_PBT_MAT_systeemvloer 200 mm, 00_PBT_MAT_isolatie 180 mm
Type - Pset_ElementShading - Roughness: 304.8 mm
Type - Pset_ProductRequirements - Category: Floors
Type - Pset_ReinforcementBarPitchOfSlab - Description: geïsoleerde kanaalplaatvloer
Type - Pset_SlabCommon - IsExternal: no
Type - Pset_Pieters - Naamgeving element: 28_PBT_FL_geïsoleerde kanaalplaat_d=200; Codering - NL-SfB: 28.21; Omschrijving NL-SfB: hoofddraagconstructies - wanden en vloeren, wand-/vloerconstructies; Materiaal: 00_PBT_MAT_systeemvloer; Materiaalkwaliteit: volgens leverancier; Description: geïsoleerde kanaalplaatvloer
Classification: 28.21 hoofddraagconstructies - wanden en vloeren, wand-/vloerconstructies (Uniformat)
Pset_QuantityTakeOff - Reference: Floor:28_PBT_FL_geïsoleerde kanaalplaat_d=200
Pset_ReinforcementBarPitchOfSlab - Reference: Floor:28_PBT_FL_geïsoleerde kanaalplaat_d=200
Pset_SlabCommon - LoadBearing: yes; PitchAngle: 0 deg; Reference: Floor:28_PBT_FL_geïsoleerde kanaalplaat_d=200
Pset_Pieters - Dikte: 380 mm; Bouwlaag: Level: 00 begane grond; Fase: Nieuw
BaseQuantities - Width: 380 mm
Name (Floor:28_PBT_FL_geïsoleerde kanaalplaat_d=200:...) | GrossArea (mm2) = NetArea (mm2) | GrossVolume (m3) = NetVolume (m3) | Perimeter (mm)
2667354 | 72773836 | 27.6541 | 42941.3
2668705 | 9062379 | 3.4437 | 12941.3
2668781 | 9062379 | 3.4437 | 12941.3
2669401 | 3978606 | 1.51187 | 10641.3

# IfcSlab: Floor:28_PBT_FL_hout_d=24 (4)
Type - PredefinedType: FLOOR; Material: 00_PBT_MAT_hout 24 mm
Type - Pset_ElementShading - Roughness: 304.8 mm
Type - Pset_ProductRequirements - Category: Floors
Type - Pset_ReinforcementBarPitchOfSlab - Description: multiplex d=24
Type - Pset_SlabCommon - IsExternal: no
Type - Pset_Pieters - Naamgeving element: 28_PBT_FL_hout_d=24; Codering - NL-SfB: 28.21; Omschrijving NL-SfB: hoofddraagconstructies - wanden en vloeren, wand-/vloerconstructies; Materiaal: 00_PBT_MAT_hout; Description: multiplex d=24
Classification: 28.21 hoofddraagconstructies - wanden en vloeren, wand-/vloerconstructies (Uniformat)
Pset_QuantityTakeOff - Reference: Floor:28_PBT_FL_hout_d=24
Pset_ReinforcementBarPitchOfSlab - Reference: Floor:28_PBT_FL_hout_d=24
Pset_SlabCommon - LoadBearing: yes; PitchAngle: 0 deg; Reference: Floor:28_PBT_FL_hout_d=24
Pset_Pieters - Dikte: 24 mm; Fase: Nieuw
BaseQuantities - Width: 24 mm
Name (Floor:28_PBT_FL_hout_d=24:...) | In | Bouwlaag | GrossArea (mm2) = NetArea (mm2) | GrossVolume (m3) = NetVolume (m3) | Perimeter (mm)
2974620 | 04 vierde verdieping | Level: 04 vierde verdieping | 228357311 | 5.48058 | 64107.5
2976213 | 04 vierde verdieping | Level: 04 vierde verdieping | 225212757 | 5.40511 | 64071.3
4336408 | 03 derde verdieping | Level: 03 derde verdieping | 15605041 | 0.374521 | 20390.2
4472258 | 05 vijfde verdieping | Level: 05 vijfde verdieping | 3249608 | 0.0779906 | 7213.35

# IfcSlab: Floor:28_PBT_FL_kanaalplaat_d=200 (4)
In: 03 derde verdieping
Type - PredefinedType: FLOOR; Material: 00_PBT_MAT_systeemvloer 200 mm
Type - Pset_ElementShading - Roughness: 304.8 mm
Type - Pset_ProductRequirements - Category: Floors
Type - Pset_ReinforcementBarPitchOfSlab - Description: kanaalplaatvloer d=200
Type - Pset_SlabCommon - IsExternal: no
Type - Pset_Pieters - Naamgeving element: 28_PBT_FL_kanaalplaat_d=200; Codering - NL-SfB: 28.21; Omschrijving NL-SfB: hoofddraagconstructies - wanden en vloeren, wand-/vloerconstructies; Materiaal: 00_PBT_MAT_systeemvloer; Materiaalkwaliteit: volgens leverancier; Description: kanaalplaatvloer d=200
Classification: 28.21 hoofddraagconstructies - wanden en vloeren, wand-/vloerconstructies (Uniformat)
Pset_QuantityTakeOff - Reference: Floor:28_PBT_FL_kanaalplaat_d=200
Pset_ReinforcementBarPitchOfSlab - Reference: Floor:28_PBT_FL_kanaalplaat_d=200
Pset_SlabCommon - LoadBearing: yes; PitchAngle: 0 deg; Reference: Floor:28_PBT_FL_kanaalplaat_d=200
Pset_Pieters - Dikte: 200 mm; Bouwlaag: Level: 03 derde verdieping; Fase: Nieuw
Name (Floor:28_PBT_FL_kanaalplaat_d=200:...) | GrossArea (mm2) | NetArea (mm2) | NetVolume (m3) | Perimeter (mm)
2424201:5 | 8463684 | 52741801 | 10.5484 | 71986.5
2424630 | 145926747 | 143552797 | 28.7106 | 85908.3
2836730 | 88757988 | 79182536 | 15.8365 | 49637.4
4262283 | 9336219 | 9336219 | 1.86724 | 14585.4 | BaseQuantities - GrossVolume: 1.86724 m3; Width: 200 mm

# IfcSlab: Floor:28_PBT_FL_kanaalplaat_d=200 (4)
In: 03 derde verdieping
Type - PredefinedType: FLOOR
Type - Pset_ElementShading - Roughness: 304.8 mm
Type - Pset_ProductRequirements - Category: Floors
Type - Pset_ReinforcementBarPitchOfSlab - Description: kanaalplaatvloer d=200
Type - Pset_SlabCommon - IsExternal: no
Type - Pset_Pieters - Naamgeving element: 28_PBT_FL_kanaalplaat_d=200; Codering - NL-SfB: 28.21; Omschrijving NL-SfB: hoofddraagconstructies - wanden en vloeren, wand-/vloerconstructies; Materiaal: 00_PBT_MAT_systeemvloer; Materiaalkwaliteit: volgens leverancier; Description: kanaalplaatvloer d=200
Classification: 28.21 hoofddraagconstructies - wanden en vloeren, wand-/vloerconstructies (Uniformat); Material: 00_PBT_MAT_systeemvloer 200 mm
Pset_QuantityTakeOff - Reference: Floor:28_PBT_FL_kanaalplaat_d=200
Pset_ReinforcementBarPitchOfSlab - Reference: Floor:28_PBT_FL_kanaalplaat_d=200
Pset_SlabCommon - LoadBearing: yes; PitchAngle: 0 deg; Reference: Floor:28_PBT_FL_kanaalplaat_d=200
Pset_Pieters - Dikte: 200 mm; Bouwlaag: Level: 03 derde verdieping; Fase: Nieuw
BaseQuantities - NetArea: 52741801 mm2; NetVolume: 10.5484 m3; Perimeter: 71986.5 mm
Name (Floor:28_PBT_FL_kanaalplaat_d=200:...) | GrossArea (mm2)
2424201 | 28221047
2424201:2 | 1072985
2424201:3 | 12550676
2424201:4 | 5755951

# IfcSlab: Floor:28_PBT_FL_kanaalplaat_d=260 (6)
Type - PredefinedType: FLOOR; Material: 00_PBT_MAT_systeemvloer 260 mm
Type - Pset_ElementShading - Roughness: 304.8 mm
Type - Pset_ProductRequirements - Category: Floors
Type - Pset_ReinforcementBarPitchOfSlab - Description: kanaalplaatvloer d=260
Type - Pset_SlabCommon - IsExternal: no
Type - Pset_Pieters - Naamgeving element: 28_PBT_FL_kanaalplaat_d=260; Codering - NL-SfB: 28.21; Omschrijving NL-SfB: hoofddraagconstructies - wanden en vloeren, wand-/vloerconstructies; Materiaal: 00_PBT_MAT_systeemvloer; Materiaalkwaliteit: volgens leverancier; Description: kanaalplaatvloer d=260; Type Comments: d=260
Classification: 28.21 hoofddraagconstructies - wanden en vloeren, wand-/vloerconstructies (Uniformat)
Pset_QuantityTakeOff - Reference: Floor:28_PBT_FL_kanaalplaat_d=260
Pset_ReinforcementBarPitchOfSlab - Reference: Floor:28_PBT_FL_kanaalplaat_d=260
Pset_SlabCommon - LoadBearing: yes; Reference: Floor:28_PBT_FL_kanaalplaat_d=260
Pset_Pieters - Dikte: 260 mm; Fase: Nieuw
Name (Floor:28_PBT_FL_kanaalplaat_d=260:...) | In | PitchAngle (deg) | Bouwlaag | GrossArea (mm2) | NetArea (mm2) | NetVolume (m3) | Perimeter (mm)
2403913 | 02 tweede verdieping | 0 | Level: 02 tweede verdieping | 116156214 | 116156214 | 30.2006 | 61600.8 | BaseQuantities - GrossVolume: 30.2006 m3; Width: 260 mm
2643893 | 06 zesde verdieping | 0 | Level: 06 zesde verdieping | 150077745 | 143847956 | 37.4005 | 53055.4
2643902 | 06 zesde verdieping | 0 | Level: 06 zesde verdieping | 89719011 | 89719011 | 23.3269 | 46476.2 | BaseQuantities - GrossVolume: 23.3269 m3; Width: 260 mm
2645905 | 06 zesde verdieping | 0 | Level: 06 zesde verdieping | 71284187 | 64989744 | 16.8973 | 49561
2968733 | 04 vierde verdieping | 9 | Level: 04 vierde verdieping | 142462786 | 139452502 | 36.2567 | 55570.9
2969632 | 04 vierde verdieping | 0 | Level: 04 vierde verdieping | 83121332 | 80574845 | 20.9495 | 48645.8

# IfcSlab: Floor:28_PBT_FL_kanaalplaat_d=260, Floor:28_PBT_FL_kanaalplaat_d=260:2643884
In: 06 zesde verdieping
Type - PredefinedType: FLOOR
Type - Pset_ElementShading - Roughness: 304.8 mm
Type - Pset_ProductRequirements - Category: Floors
Type - Pset_ReinforcementBarPitchOfSlab - Description: kanaalplaatvloer d=260
Type - Pset_SlabCommon - IsExternal: no
Type - Pset_Pieters - Naamgeving element: 28_PBT_FL_kanaalplaat_d=260; Codering - NL-SfB: 28.21; Omschrijving NL-SfB: hoofddraagconstructies - wanden en vloeren, wand-/vloerconstructies; Materiaal: 00_PBT_MAT_systeemvloer; Materiaalkwaliteit: volgens leverancier; Description: kanaalplaatvloer d=260; Type Comments: d=260
Classification: 28.21 hoofddraagconstructies - wanden en vloeren, wand-/vloerconstructies (Uniformat); Material: 00_PBT_MAT_systeemvloer
Pset_QuantityTakeOff - Reference: Floor:28_PBT_FL_kanaalplaat_d=260
Pset_ReinforcementBarPitchOfSlab - Reference: Floor:28_PBT_FL_kanaalplaat_d=260
Pset_SlabCommon - LoadBearing: yes; PitchAngle: 0 deg; Reference: Floor:28_PBT_FL_kanaalplaat_d=260
Pset_Pieters - Dikte: 260 mm; Bouwlaag: Level: 06 zesde verdieping; Fase: Nieuw
BaseQuantities - NetArea: 254265530 mm2; NetVolume: 65.4283 m3; Perimeter: 65796.6 mm

# IfcSlab: Floor:28_PBT_FL_kanaalplaat_d=320 (20)
Type - PredefinedType: FLOOR; Material: 00_PBT_MAT_systeemvloer 320 mm
Type - Pset_ElementShading - Roughness: 304.8 mm
Type - Pset_ProductRequirements - Category: Floors
Type - Pset_ReinforcementBarPitchOfSlab - Description: kanaalplaatvloer d=320
Type - Pset_SlabCommon - IsExternal: no
Type - Pset_Pieters - Naamgeving element: 28_PBT_FL_kanaalplaat_d=320; Codering - NL-SfB: 28.21; Omschrijving NL-SfB: hoofddraagconstructies - wanden en vloeren, wand-/vloerconstructies; Materiaal: 00_PBT_MAT_systeemvloer; Materiaalkwaliteit: volgens leverancier; Description: kanaalplaatvloer d=320
Classification: 28.21 hoofddraagconstructies - wanden en vloeren, wand-/vloerconstructies (Uniformat)
Pset_QuantityTakeOff - Reference: Floor:28_PBT_FL_kanaalplaat_d=320
Pset_ReinforcementBarPitchOfSlab - Reference: Floor:28_PBT_FL_kanaalplaat_d=320
Pset_SlabCommon - LoadBearing: yes; Reference: Floor:28_PBT_FL_kanaalplaat_d=320
Pset_Pieters - Dikte: 320 mm; Fase: Nieuw
Name (Floor:28_PBT_FL_kanaalplaat_d=320:...) | In | PitchAngle (deg) | Bouwlaag | GrossArea (mm2) | NetArea (mm2) | NetVolume (m3) | Perimeter (mm)
2018220:2 | 01 eerste verdieping | 0 | Level: 01 eerste verdieping | 14835278 | 175055362 | 56.0177 | 81248.8
2031957 | 03 derde verdieping | 0 | Level: 03 derde verdieping | 108768799 | 98549806 | 31.5359 | 68670.2
2151157 | 03 derde verdieping | 0 | Level: 03 derde verdieping | 22094902 | 22094902 | 7.07037 | 20495.7 | BaseQuantities - GrossVolume: 7.07037 m3; Width: 320 mm
2204137 | 05 vijfde verdieping | 0 | Level: 05 vijfde verdieping | 84768329 | 74216399 | 23.7492 | 58421.5
2206461 | 04 vierde verdieping | 0 | Level: 04 vierde verdieping | 114546990 | 104648171 | 33.4874 | 67546
2363585:2 | 01 eerste verdieping | 0 | Level: 01 eerste verdieping | 13120681 | 334188796 | 106.94 | 160606
2391934 | 01 eerste verdieping | 0 | Level: 01 eerste verdieping | 96477361 | 96477361 | 30.8728 | 56471.4 | BaseQuantities - GrossVolume: 30.8728 m3; Width: 320 mm
2397552 | 04 vierde verdieping | 0 | Level: 04 vierde verdieping | 57806209 | 55734271 | 17.835 | 44121.5
2401849 | 01 eerste verdieping | 0 | Level: 01 eerste verdieping | 11310701 | 11310701 | 3.61942 | 17039.5 | BaseQuantities - GrossVolume: 3.61942 m3; Width: 320 mm
2402739 | 02 tweede verdieping | 0 | Level: 02 tweede verdieping | 177289238 | 170675397 | 54.6161 | 68985.1
2402957 | 02 tweede verdieping | 0 | Level: 02 tweede verdieping | 217064068 | 190041424 | 60.8133 | 87849.2
2440830 | 04 vierde verdieping | 0 | Level: 04 vierde verdieping | 84663901 | 74892116 | 23.9655 | 58706.5
2454653:4 | 03 derde verdieping | 0 | Level: 03 derde verdieping | 29654949 | 95278679 | 30.4892 | 88691.3
2753245:2 | 04 vierde verdieping | 4.57156 | Level: 04 vierde verdieping | 23098860 | 96515022 | 30.8438 | 100309
2754478:2 | 04 vierde verdieping | 9 | Level: 04 vierde verdieping | 46871011 | 111663028 | 35.7265 | 99574.8
2797250 | 04 vierde verdieping | 21.3 | Level: 04 vierde verdieping | 85623012 | 87122395 | 27.8658 | 54731.1
2829967 | 04 vierde verdieping | 0 | Level: 04 vierde verdieping | 69982152 | 63955381 | 20.4657 | 48629.1
2852493 | 04 vierde verdieping | 0 | Level: 04 vierde verdieping | 51517121 | 47043431 | 15.0539 | 40060.9
2990548 | 02 tweede verdieping | 0 | Level: 02 tweede verdieping | 89953934 | 89953934 | 28.7853 | 52953.4 | BaseQuantities - GrossVolume: 28.7853 m3; Width: 320 mm
3155322 | 01 eerste verdieping | 0 | Level: 01 eerste verdieping | 44036987 | 43901987 | 14.0486 | 31217.5

# IfcSlab: Floor:28_PBT_FL_kanaalplaat_d=320 (7)
Type - PredefinedType: FLOOR
Type - Pset_ElementShading - Roughness: 304.8 mm
Type - Pset_ProductRequirements - Category: Floors
Type - Pset_ReinforcementBarPitchOfSlab - Description: kanaalplaatvloer d=320
Type - Pset_SlabCommon - IsExternal: no
Type - Pset_Pieters - Naamgeving element: 28_PBT_FL_kanaalplaat_d=320; Codering - NL-SfB: 28.21; Omschrijving NL-SfB: hoofddraagconstructies - wanden en vloeren, wand-/vloerconstructies; Materiaal: 00_PBT_MAT_systeemvloer; Materiaalkwaliteit: volgens leverancier; Description: kanaalplaatvloer d=320
Classification: 28.21 hoofddraagconstructies - wanden en vloeren, wand-/vloerconstructies (Uniformat); Material: 00_PBT_MAT_systeemvloer 320 mm
Pset_QuantityTakeOff - Reference: Floor:28_PBT_FL_kanaalplaat_d=320
Pset_ReinforcementBarPitchOfSlab - Reference: Floor:28_PBT_FL_kanaalplaat_d=320
Pset_SlabCommon - LoadBearing: yes; Reference: Floor:28_PBT_FL_kanaalplaat_d=320
Pset_Pieters - Dikte: 320 mm; Fase: Nieuw
Name (Floor:28_PBT_FL_kanaalplaat_d=320:...) | In | PitchAngle (deg) | Bouwlaag | GrossArea (mm2) | NetArea (mm2) | NetVolume (m3) | Perimeter (mm)
2018220 | 01 eerste verdieping | 0 | Level: 01 eerste verdieping | 163010009 | 175055362 | 56.0177 | 81248.8
2363585 | 01 eerste verdieping | 0 | Level: 01 eerste verdieping | 355924172 | 334188796 | 106.94 | 160606
2454653 | 03 derde verdieping | 0 | Level: 03 derde verdieping | 10483065 | 95278679 | 30.4892 | 88691.3
2454653:2 | 03 derde verdieping | 0 | Level: 03 derde verdieping | 31393028 | 95278679 | 30.4892 | 88691.3
2454653:3 | 03 derde verdieping | 0 | Level: 03 derde verdieping | 27469592 | 95278679 | 30.4892 | 88691.3
2753245 | 04 vierde verdieping | 4.57156 | Level: 04 vierde verdieping | 77448800 | 96515022 | 30.8438 | 100309
2754478 | 04 vierde verdieping | 9 | Level: 04 vierde verdieping | 67067657 | 111663028 | 35.7265 | 99574.8

# IfcSlab: Floor:28_PBT_FL_kanaalplaat_d=400, Floor:28_PBT_FL_kanaalplaat_d=400:2036703
In: 04 vierde verdieping
Type - PredefinedType: FLOOR; Material: 00_PBT_MAT_systeemvloer 400 mm
Type - Pset_ElementShading - Roughness: 304.8 mm
Type - Pset_ProductRequirements - Category: Floors
Type - Pset_ReinforcementBarPitchOfSlab - Description: kanaalplaatvloer d=400
Type - Pset_SlabCommon - IsExternal: no
Type - Pset_Pieters - Naamgeving element: 28_PBT_FL_kanaalplaat_d=400; Codering - NL-SfB: 28.21; Omschrijving NL-SfB: hoofddraagconstructies - wanden en vloeren, wand-/vloerconstructies; Materiaal: 00_PBT_MAT_systeemvloer; Materiaalkwaliteit: volgens leverancier; Description: kanaalplaatvloer d=400
Classification: 28.21 hoofddraagconstructies - wanden en vloeren, wand-/vloerconstructies (Uniformat)
Pset_QuantityTakeOff - Reference: Floor:28_PBT_FL_kanaalplaat_d=400
Pset_ReinforcementBarPitchOfSlab - Reference: Floor:28_PBT_FL_kanaalplaat_d=400
Pset_SlabCommon - LoadBearing: yes; PitchAngle: 0 deg; Reference: Floor:28_PBT_FL_kanaalplaat_d=400
Pset_Pieters - Dikte: 400 mm; Bouwlaag: Level: 04 vierde verdieping; Fase: Nieuw
BaseQuantities - NetArea: 482430735 mm2; NetVolume: 192.972 m3; Perimeter: 328370 mm

# IfcSlab: Floor:28_PBT_FL_massieve plaat_d=200 (8)
Type - PredefinedType: FLOOR; Material: 00_PBT_MAT_systeemvloer 200 mm
Type - Pset_ElementShading - Roughness: 304.8 mm
Type - Pset_ProductRequirements - Category: Floors
Type - Pset_ReinforcementBarPitchOfSlab - Description: massieve plaatvloer d=200
Type - Pset_SlabCommon - IsExternal: no
Type - Pset_Pieters - Naamgeving element: 28_PBT_FL_massieve plaat_d=200; Codering - NL-SfB: 28.21; Omschrijving NL-SfB: hoofddraagconstructies - wanden en vloeren, wand-/vloerconstructies; Materiaal: 00_PBT_MAT_systeemvloer; Materiaalkwaliteit: volgens leverancier; Description: massieve plaatvloer d=200
Classification: 28.21 hoofddraagconstructies - wanden en vloeren, wand-/vloerconstructies (Uniformat)
Pset_QuantityTakeOff - Reference: Floor:28_PBT_FL_massieve plaat_d=200
Pset_ReinforcementBarPitchOfSlab - Reference: Floor:28_PBT_FL_massieve plaat_d=200
Pset_SlabCommon - LoadBearing: yes; PitchAngle: 0 deg; Reference: Floor:28_PBT_FL_massieve plaat_d=200
Pset_Pieters - Dikte: 200 mm; Fase: Nieuw
Name (Floor:28_PBT_FL_massieve plaat_d=200:...) | In | Bouwlaag | GrossArea (mm2) | NetArea (mm2) | NetVolume (m3) | Perimeter (mm)
2432260 | 03 derde verdieping | Level: 03 derde verdieping | 55571221 | 55571221 | 11.1142 | 41230 | BaseQuantities - GrossVolume: 11.1142 m3; Width: 200 mm
3048156 | 02 tweede verdieping | Level: 02 tweede verdieping | 3339600 | 3339600 | 0.66792 | 8226 | BaseQuantities - GrossVolume: 0.66792 m3; Width: 200 mm
3574040 | 03 derde verdieping | Level: 03 derde verdieping | 61468270 | 55573570 | 11.1147 | 60178.7
4810833 | 03 derde verdieping | Level: 03 derde verdieping | 25224902 | 25224902 | 5.04498 | 36511.7 | BaseQuantities - GrossVolume: 5.04498 m3; Width: 200 mm
5210417 | 01 eerste verdieping | Level: 01 eerste verdieping | 17083879 | 16591167 | 3.31823 | 22722.8
5212909:2 | 02 tweede verdieping | Level: 02 tweede verdieping | 4548644 | 13469312 | 2.69386 | 25719.5
5214078 | 03 derde verdieping | Level: 03 derde verdieping | 13796358 | 13304645 | 2.66093 | 22737.9
5859838 | 02 tweede verdieping | Level: 02 tweede verdieping | 16478905 | 16478905 | 3.29578 | 22341.8 | BaseQuantities - GrossVolume: 3.29578 m3; Width: 200 mm

# IfcSlab: Floor:28_PBT_FL_massieve plaat_d=200, Floor:28_PBT_FL_massieve plaat_d=200:5212909
In: 02 tweede verdieping
Type - PredefinedType: FLOOR
Type - Pset_ElementShading - Roughness: 304.8 mm
Type - Pset_ProductRequirements - Category: Floors
Type - Pset_ReinforcementBarPitchOfSlab - Description: massieve plaatvloer d=200
Type - Pset_SlabCommon - IsExternal: no
Type - Pset_Pieters - Naamgeving element: 28_PBT_FL_massieve plaat_d=200; Codering - NL-SfB: 28.21; Omschrijving NL-SfB: hoofddraagconstructies - wanden en vloeren, wand-/vloerconstructies; Materiaal: 00_PBT_MAT_systeemvloer; Materiaalkwaliteit: volgens leverancier; Description: massieve plaatvloer d=200
Classification: 28.21 hoofddraagconstructies - wanden en vloeren, wand-/vloerconstructies (Uniformat); Material: 00_PBT_MAT_systeemvloer 200 mm
Pset_QuantityTakeOff - Reference: Floor:28_PBT_FL_massieve plaat_d=200
Pset_ReinforcementBarPitchOfSlab - Reference: Floor:28_PBT_FL_massieve plaat_d=200
Pset_SlabCommon - LoadBearing: yes; PitchAngle: 0 deg; Reference: Floor:28_PBT_FL_massieve plaat_d=200
Pset_Pieters - Dikte: 200 mm; Bouwlaag: Level: 02 tweede verdieping; Fase: Nieuw
BaseQuantities - GrossArea: 8920667 mm2; NetArea: 13469312 mm2; NetVolume: 2.69386 m3; Perimeter: 25719.5 mm

# IfcSlab: Floor:28_PBT_FL_staalplaatbeton_d=130_C30/37, Floor:28_PBT_FL_staalplaatbeton_d=130_C30/37:2426679
In: 03 derde verdieping
Type - PredefinedType: FLOOR; Material: 00_PBT_MAT_beton t.p.g._C30/37 130 mm
Type - Pset_ElementShading - Roughness: 304.8 mm
Type - Pset_ProductRequirements - Category: Floors
Type - Pset_ReinforcementBarPitchOfSlab - Description: staalplaat-betonvloer d=130
Type - Pset_SlabCommon - IsExternal: no
Type - Pset_Pieters - Naamgeving element: 28_PBT_FL_staalplaatbeton_d=130_C30/37; Codering - NL-SfB: 28.21; Omschrijving NL-SfB: hoofddraagconstructies - wanden en vloeren, wand-/vloerconstructies; Materiaal: 00_PBT_MAT_beton t.p.g._C30/37; Materiaalkwaliteit: C30/37; Description: staalplaat-betonvloer d=130; Type Comments: d=130
Classification: 28.21 hoofddraagconstructies - wanden en vloeren, wand-/vloerconstructies (Uniformat)
Pset_QuantityTakeOff - Reference: Floor:28_PBT_FL_staalplaatbeton_d=130_C30/37
Pset_ReinforcementBarPitchOfSlab - Reference: Floor:28_PBT_FL_staalplaatbeton_d=130_C30/37
Pset_SlabCommon - LoadBearing: yes; PitchAngle: 0 deg; Reference: Floor:28_PBT_FL_staalplaatbeton_d=130_C30/37
Pset_Pieters - Dikte: 130 mm; Bouwlaag: Level: 03 derde verdieping; Fase: Nieuw
BaseQuantities - GrossArea: 42457796 mm2; NetArea: 42418231 mm2; GrossVolume: 5.51951 m3; NetVolume: 5.51625 m3; Perimeter: 53210.1 mm; Width: 130 mm

# IfcSlab: Floor:28_PBT_FL_staalplaatbeton_d=150_C30/37, Floor:28_PBT_FL_staalplaatbeton_d=150_C30/37:3424627
In: -1 kelder
Type - PredefinedType: FLOOR
Type - Pset_ElementShading - Roughness: 304.8 mm
Type - Pset_ProductRequirements - Category: Floors
Type - Pset_ReinforcementBarPitchOfSlab - Description: staalplaat-betonvloer d=150
Type - Pset_SlabCommon - IsExternal: no
Type - Pset_Pieters - Naamgeving element: 28_PBT_FL_staalplaatbeton_d=150_C30/37; Codering - NL-SfB: 28.21; Omschrijving NL-SfB: hoofddraagconstructies - wanden en vloeren, wand-/vloerconstructies; Materiaal: 00_PBT_MAT_beton t.p.g._C30/37; Materiaalkwaliteit: C30/37; Description: staalplaat-betonvloer d=150; Type Comments: d=150
Classification: 28.21 hoofddraagconstructies - wanden en vloeren, wand-/vloerconstructies (Uniformat); Material: 00_PBT_MAT_beton t.p.g._C30/37, 00_PBT_MAT_staal
Pset_QuantityTakeOff - Reference: Floor:28_PBT_FL_staalplaatbeton_d=150_C30/37
Pset_ReinforcementBarPitchOfSlab - Reference: Floor:28_PBT_FL_staalplaatbeton_d=150_C30/37
Pset_SlabCommon - LoadBearing: yes; PitchAngle: 0 deg; Reference: Floor:28_PBT_FL_staalplaatbeton_d=150_C30/37
Pset_Pieters - Dikte: 150 mm; Bouwlaag: Level: -1 kelder; Fase: Nieuw
BaseQuantities - NetArea: 16724998 mm2; NetVolume: 2.50544 m3; Perimeter: 26149.8 mm

# IfcSlab: Floor:28_PBT_FL_staalplaatbeton_d=300_C30/37 (5)
Type - PredefinedType: FLOOR; Material: 00_PBT_MAT_beton t.p.g._C30/37 300 mm
Type - Pset_ElementShading - Roughness: 304.8 mm
Type - Pset_ProductRequirements - Category: Floors
Type - Pset_ReinforcementBarPitchOfSlab - Description: staalplaat-betonvloer d=300
Type - Pset_SlabCommon - IsExternal: no
Type - Pset_Pieters - Naamgeving element: 28_PBT_FL_staalplaatbeton_d=300_C30/37; Codering - NL-SfB: 28.21; Omschrijving NL-SfB: hoofddraagconstructies - wanden en vloeren, wand-/vloerconstructies; Materiaal: 00_PBT_MAT_beton t.p.g._C30/37; Materiaalkwaliteit: C30/37; Description: staalplaat-betonvloer d=300; Type Comments: d=300
Classification: 28.21 hoofddraagconstructies - wanden en vloeren, wand-/vloerconstructies (Uniformat)
Pset_QuantityTakeOff - Reference: Floor:28_PBT_FL_staalplaatbeton_d=300_C30/37
Pset_ReinforcementBarPitchOfSlab - Reference: Floor:28_PBT_FL_staalplaatbeton_d=300_C30/37
Pset_SlabCommon - LoadBearing: yes; PitchAngle: 0 deg; Reference: Floor:28_PBT_FL_staalplaatbeton_d=300_C30/37
Pset_Pieters - Dikte: 300 mm; Fase: Nieuw
Name (Floor:28_PBT_FL_staalplaatbeton_d=300_C30/37:...) | In | Bouwlaag | GrossArea (mm2) | NetArea (mm2) | NetVolume (m3) | Perimeter (mm) | GrossVolume (m3) | Width (mm)
2363970:5 | 01 eerste verdieping | Level: 01 eerste verdieping | 12010753 | 88443812 | 26.5332 | 97469.8
3627580 | 02 tweede verdieping | Level: 02 tweede verdieping | 12138000 | 12138000 | 3.6414 | 22660 | 3.6414 | 300
3755348 | 01 eerste verdieping | Level: 01 eerste verdieping | 14810736 | 14810736 | 4.44322 | 15670.9 | 4.44322 | 300
3926942 | -1 kelder | Level: -1 kelder | 36201550 | 36201550 | 10.8605 | 26506 | 10.8605 | 300
4871962 | 02 tweede verdieping | Level: 02 tweede verdieping | 12096000 | 12096000 | 3.6288 | 22660 | 3.6288 | 300

# IfcSlab: Floor:28_PBT_FL_staalplaatbeton_d=300_C30/37 (7)
Type - PredefinedType: FLOOR
Type - Pset_ElementShading - Roughness: 304.8 mm
Type - Pset_ProductRequirements - Category: Floors
Type - Pset_ReinforcementBarPitchOfSlab - Description: staalplaat-betonvloer d=300
Type - Pset_SlabCommon - IsExternal: no
Type - Pset_Pieters - Naamgeving element: 28_PBT_FL_staalplaatbeton_d=300_C30/37; Codering - NL-SfB: 28.21; Omschrijving NL-SfB: hoofddraagconstructies - wanden en vloeren, wand-/vloerconstructies; Materiaal: 00_PBT_MAT_beton t.p.g._C30/37; Materiaalkwaliteit: C30/37; Description: staalplaat-betonvloer d=300; Type Comments: d=300
Classification: 28.21 hoofddraagconstructies - wanden en vloeren, wand-/vloerconstructies (Uniformat)
Pset_QuantityTakeOff - Reference: Floor:28_PBT_FL_staalplaatbeton_d=300_C30/37
Pset_ReinforcementBarPitchOfSlab - Reference: Floor:28_PBT_FL_staalplaatbeton_d=300_C30/37
Pset_SlabCommon - LoadBearing: yes; PitchAngle: 0 deg; Reference: Floor:28_PBT_FL_staalplaatbeton_d=300_C30/37
Pset_Pieters - Dikte: 300 mm; Fase: Nieuw
Name (Floor:28_PBT_FL_staalplaatbeton_d=300_C30/37:...) | In | Material | Bouwlaag | NetArea (mm2) | NetVolume (m3) | Perimeter (mm) | GrossArea (mm2)
2148963 | 02 tweede verdieping | 00_PBT_MAT_beton t.p.g._C30/37, 00_PBT_MAT_staal | Level: 02 tweede verdieping | 157721973 | 47.2913 | 109676
2150582 | 02 tweede verdieping | 00_PBT_MAT_beton t.p.g._C30/37, 00_PBT_MAT_staal | Level: 02 tweede verdieping | 35303956 | 10.5357 | 34116.6
2363970 | 01 eerste verdieping | 00_PBT_MAT_beton t.p.g._C30/37 300 mm | Level: 01 eerste verdieping | 88443812 | 26.5332 | 97469.8 | 17965640
2363970:2 | 01 eerste verdieping | 00_PBT_MAT_beton t.p.g._C30/37 300 mm | Level: 01 eerste verdieping | 88443812 | 26.5332 | 97469.8 | 5653093
2363970:3 | 01 eerste verdieping | 00_PBT_MAT_beton t.p.g._C30/37 300 mm | Level: 01 eerste verdieping | 88443812 | 26.5332 | 97469.8 | 26767439
2363970:4 | 01 eerste verdieping | 00_PBT_MAT_beton t.p.g._C30/37 300 mm | Level: 01 eerste verdieping | 88443812 | 26.5332 | 97469.8 | 26046898
4874635 | 02 tweede verdieping | 00_PBT_MAT_beton t.p.g._C30/37, 00_PBT_MAT_staal | Level: 02 tweede verdieping | 18627731 | 5.38158 | 42554

# IfcSlab: Floor:28_PBT_FL_stalen dakplaten_d=200, Floor:28_PBT_FL_stalen dakplaten_d=200:3588631
In: 05 vijfde verdieping
Type - PredefinedType: FLOOR; Material: 00_PBT_MAT_staal 205 mm
Type - Pset_ElementShading - Roughness: 304.8 mm
Type - Pset_ProductRequirements - Category: Floors
Type - Pset_ReinforcementBarPitchOfSlab - Description: stalen dakplaten SAB200
Type - Pset_SlabCommon - IsExternal: no
Type - Pset_Pieters - Naamgeving element: 28_PBT_FL_stalen dakplaten_d=200; Codering - NL-SfB: 28.21; Omschrijving NL-SfB: hoofddraagconstructies - wanden en vloeren, wand-/vloerconstructies; Materiaal: 00_PBT_MAT_staal; Materiaalkwaliteit: volgens leverancier; Description: stalen dakplaten SAB200
Classification: 28.21 hoofddraagconstructies - wanden en vloeren, wand-/vloerconstructies (Uniformat)
Pset_QuantityTakeOff - Reference: Floor:28_PBT_FL_stalen dakplaten_d=200
Pset_ReinforcementBarPitchOfSlab - Reference: Floor:28_PBT_FL_stalen dakplaten_d=200
Pset_SlabCommon - LoadBearing: yes; Reference: Floor:28_PBT_FL_stalen dakplaten_d=200; PitchAngle: 1.41522 deg
Pset_Pieters - Dikte: 205 mm; Bouwlaag: Level: 05 vijfde verdieping; Fase: Nieuw
BaseQuantities - GrossArea: 119302513 mm2; NetArea: 119302513 mm2; GrossVolume: 24.4645 m3; NetVolume: 24.457 m3; Perimeter: 52492.8 mm; Width: 205.063 mm

# IfcSlab: Floor:28_PBT_FL_stalen dakplaten_d=200 (2)
In: 05 vijfde verdieping
Type - PredefinedType: FLOOR
Type - Pset_ElementShading - Roughness: 304.8 mm
Type - Pset_ProductRequirements - Category: Floors
Type - Pset_ReinforcementBarPitchOfSlab - Description: stalen dakplaten SAB200
Type - Pset_SlabCommon - IsExternal: no
Type - Pset_Pieters - Naamgeving element: 28_PBT_FL_stalen dakplaten_d=200; Codering - NL-SfB: 28.21; Omschrijving NL-SfB: hoofddraagconstructies - wanden en vloeren, wand-/vloerconstructies; Materiaal: 00_PBT_MAT_staal; Materiaalkwaliteit: volgens leverancier; Description: stalen dakplaten SAB200
Classification: 28.21 hoofddraagconstructies - wanden en vloeren, wand-/vloerconstructies (Uniformat); Material: 00_PBT_MAT_staal
Pset_QuantityTakeOff - Reference: Floor:28_PBT_FL_stalen dakplaten_d=200
Pset_ReinforcementBarPitchOfSlab - Reference: Floor:28_PBT_FL_stalen dakplaten_d=200
Pset_SlabCommon - LoadBearing: yes; Reference: Floor:28_PBT_FL_stalen dakplaten_d=200
Pset_Pieters - Dikte: 205 mm; Bouwlaag: Level: 05 vijfde verdieping; Fase: Nieuw
Name (Floor:28_PBT_FL_stalen dakplaten_d=200:...) | PitchAngle (deg) | NetArea (mm2) | NetVolume (m3) | Perimeter (mm)
4408706 | 2.92692 | 28326778 | 5.80446 | 22228.4
4410755 | 2.52515 | 28908529 | 5.92372 | 22390.9

# IfcSlab: Foundation Slab:13_PBT_FS_beton t.p.g._d=1000_bestaand (2)
Type - PredefinedType: BASESLAB; Material: 00_PBT_MAT_beton t.p.g. 1000 mm
Type - Pset_ElementShading - Roughness: 304.8 mm
Type - Pset_ProductRequirements - Category: Structural Foundations
Type - Pset_ReinforcementBarPitchOfSlab - Description: i.h.w.g. betonvloer d=1000
Type - Pset_SlabCommon - IsExternal: no
Type - Pset_Pieters - Naamgeving element: 13_PBT_FS_beton t.p.g._d=1000_bestaand; Codering - NL-SfB: 13.20; Omschrijving NL-SfB: vloeren op grondslag - constructief, algemeen (verzamelniveau); Materiaal: 00_PBT_MAT_beton t.p.g.; Description: i.h.w.g. betonvloer d=1000
Classification: 13.20 vloeren op grondslag - constructief, algemeen (verzamelniveau) (Uniformat)
Pset_QuantityTakeOff - Reference: Foundation Slab:13_PBT_FS_beton t.p.g._d=1000_bestaand
Pset_ReinforcementBarPitchOfSlab - Reference: Foundation Slab:13_PBT_FS_beton t.p.g._d=1000_bestaand
Pset_SlabCommon - LoadBearing: yes; IsExternal: yes; PitchAngle: 0 deg; Reference: Foundation Slab:13_PBT_FS_beton t.p.g._d=1000_bestaand
Pset_Pieters - Dragend/niet dragend: yes; In/uitwendig: yes; Dikte: 1000 mm; Fase: Bestaand
Name (Foundation Slab:13_PBT_FS_beton t.p.g._d=1000_bestaand:...) | In | Bouwlaag | NetArea (mm2) | NetVolume (m3) | Perimeter (mm) | Width (mm)
1395850 | -1 kelder | Level: -1 kelder_Offset1000 | 3228750 | 1.93725 | 9350 | 1125
1404175 | -2 kelder | Level: -2 kelder_Offset1000 | 111017500 | 111.017 | 50000 | 18050 | BaseQuantities - GrossArea: 111017500 mm2; GrossVolume: 111.017 m3

# IfcSlab: Foundation Slab:13_PBT_FS_beton t.p.g._d=1000_bestaand (2)
Type - PredefinedType: BASESLAB
Type - Pset_ElementShading - Roughness: 304.8 mm
Type - Pset_ProductRequirements - Category: Structural Foundations
Type - Pset_ReinforcementBarPitchOfSlab - Description: i.h.w.g. betonvloer d=1000
Type - Pset_SlabCommon - IsExternal: no
Type - Pset_Pieters - Naamgeving element: 13_PBT_FS_beton t.p.g._d=1000_bestaand; Codering - NL-SfB: 13.20; Omschrijving NL-SfB: vloeren op grondslag - constructief, algemeen (verzamelniveau); Materiaal: 00_PBT_MAT_beton t.p.g.; Description: i.h.w.g. betonvloer d=1000
Classification: 13.20 vloeren op grondslag - constructief, algemeen (verzamelniveau) (Uniformat); Material: 00_PBT_MAT_beton t.p.g.
Pset_QuantityTakeOff - Reference: Foundation Slab:13_PBT_FS_beton t.p.g._d=1000_bestaand
Pset_ReinforcementBarPitchOfSlab - Reference: Foundation Slab:13_PBT_FS_beton t.p.g._d=1000_bestaand
Pset_SlabCommon - LoadBearing: yes; IsExternal: yes; Reference: Foundation Slab:13_PBT_FS_beton t.p.g._d=1000_bestaand
Pset_Pieters - Dragend/niet dragend: yes; In/uitwendig: yes; Dikte: 1000 mm; Fase: Bestaand
Name (Foundation Slab:13_PBT_FS_beton t.p.g._d=1000_bestaand:...) | In | PitchAngle (deg) | Bouwlaag | NetArea (mm2) | NetVolume (m3) | Perimeter (mm) | Width (mm)
1396879 | -1 kelder | 0 | Level: -1 kelder_Offset1000 | 82735725 | 82.7221 | 50280 | 8970
1404430 | -2 kelder | 6.85707 | Level: -2 kelder_Offset1000 | 178871454 | 175.882 | 53380 | 14050

# IfcSlab: Foundation Slab:13_PBT_FS_beton t.p.g._d=1100_bestaand (2)
In: -1 kelder
Type - PredefinedType: BASESLAB
Type - Pset_ElementShading - Roughness: 304.8 mm
Type - Pset_ProductRequirements - Category: Structural Foundations
Type - Pset_ReinforcementBarPitchOfSlab - Description: i.h.w.g. betonvloer d=1100
Type - Pset_SlabCommon - IsExternal: no
Type - Pset_Pieters - Naamgeving element: 13_PBT_FS_beton t.p.g._d=1100_bestaand; Codering - NL-SfB: 13.20; Omschrijving NL-SfB: vloeren op grondslag - constructief, algemeen (verzamelniveau); Materiaal: 00_PBT_MAT_beton t.p.g.; Description: i.h.w.g. betonvloer d=1100; Type Comments: d=1100
Classification: 13.20 vloeren op grondslag - constructief, algemeen (verzamelniveau) (Uniformat); Material: 00_PBT_MAT_beton t.p.g.
Pset_QuantityTakeOff - Reference: Foundation Slab:13_PBT_FS_beton t.p.g._d=1100_bestaand
Pset_ReinforcementBarPitchOfSlab - Reference: Foundation Slab:13_PBT_FS_beton t.p.g._d=1100_bestaand
Pset_SlabCommon - LoadBearing: yes; IsExternal: yes; PitchAngle: 0 deg; Reference: Foundation Slab:13_PBT_FS_beton t.p.g._d=1100_bestaand
Pset_Pieters - Dragend/niet dragend: yes; In/uitwendig: yes; Dikte: 1100 mm; Bouwlaag: Level: -1 kelder_Offset1000; Fase: Bestaand
Name (Foundation Slab:13_PBT_FS_beton t.p.g._d=1100_bestaand:...) | NetArea (mm2) | NetVolume (m3) | Perimeter (mm) | Width (mm)
1336899 | 20234035 | 14.1971 | 20660.3 | 4430.15
1337834 | 32342011 | 27.6863 | 29404.5 | 9085 | Pset_Pieters - Comments: poerconstructie

# IfcSlab: Foundation Slab:13_PBT_FS_beton t.p.g._d=1300_bestaand, Foundation Slab:13_PBT_FS_beton t.p.g._d=1300_bestaand:1349133
In: -2 kelder
Type - PredefinedType: BASESLAB; Material: 00_PBT_MAT_beton t.p.g. 1300 mm
Type - Pset_ElementShading - Roughness: 304.8 mm
Type - Pset_ProductRequirements - Category: Structural Foundations
Type - Pset_ReinforcementBarPitchOfSlab - Description: i.h.w.g. betonvloer d=1300
Type - Pset_SlabCommon - IsExternal: no
Type - Pset_Pieters - Naamgeving element: 13_PBT_FS_beton t.p.g._d=1300_bestaand; Codering - NL-SfB: 13.20; Omschrijving NL-SfB: vloeren op grondslag - constructief, algemeen (verzamelniveau); Materiaal: 00_PBT_MAT_beton t.p.g.; Description: i.h.w.g. betonvloer d=1300
Classification: 13.20 vloeren op grondslag - constructief, algemeen (verzamelniveau) (Uniformat)
Pset_QuantityTakeOff - Reference: Foundation Slab:13_PBT_FS_beton t.p.g._d=1300_bestaand
Pset_ReinforcementBarPitchOfSlab - Reference: Foundation Slab:13_PBT_FS_beton t.p.g._d=1300_bestaand
Pset_SlabCommon - LoadBearing: yes; IsExternal: yes; PitchAngle: 0 deg; Reference: Foundation Slab:13_PBT_FS_beton t.p.g._d=1300_bestaand
Pset_Pieters - Dragend/niet dragend: yes; In/uitwendig: yes; Dikte: 1300 mm; Bouwlaag: Level: -2 kelder_Offset1000; Fase: Bestaand
BaseQuantities - GrossArea: 49270686 mm2; NetArea: 48941111 mm2; NetVolume: 63.6229 m3; Perimeter: 33898.3 mm; Width: 11189.6 mm

# IfcSlab: Foundation Slab:13_PBT_FS_beton t.p.g._d=200_C30/37, Foundation Slab:13_PBT_FS_beton t.p.g._d=200_C30/37:3914715
In: -1 kelder
Type - PredefinedType: BASESLAB; Material: 00_PBT_MAT_beton t.p.g._C30/37 200 mm
Type - Pset_ElementShading - Roughness: 304.8 mm
Type - Pset_ProductRequirements - Category: Structural Foundations
Type - Pset_ReinforcementBarPitchOfSlab - Description: betonvloer d=200
Type - Pset_SlabCommon - IsExternal: no
Type - Pset_Pieters - Naamgeving element: 13_PBT_FS_beton t.p.g._d=200_C30/37; Codering - NL-SfB: 13.20; Omschrijving NL-SfB: vloeren op grondslag - constructief, algemeen (verzamelniveau); Materiaal: 00_PBT_MAT_beton t.p.g._C30/37; Materiaalkwaliteit: C30/37; Description: betonvloer d=200; Type Comments: d=200
Classification: 13.20 vloeren op grondslag - constructief, algemeen (verzamelniveau) (Uniformat)
Pset_QuantityTakeOff - Reference: Foundation Slab:13_PBT_FS_beton t.p.g._d=200_C30/37
Pset_ReinforcementBarPitchOfSlab - Reference: Foundation Slab:13_PBT_FS_beton t.p.g._d=200_C30/37
Pset_SlabCommon - LoadBearing: yes; PitchAngle: 0 deg; Reference: Foundation Slab:13_PBT_FS_beton t.p.g._d=200_C30/37
Pset_Pieters - Dikte: 200 mm; Bouwlaag: Level: -1 kelder; Fase: Nieuw
BaseQuantities - GrossArea: 13685775 mm2; NetArea: 13685775 mm2; GrossVolume: 2.73716 m3; NetVolume: 2.73716 m3; Perimeter: 14797.7 mm; Width: 3700 mm

# IfcSlab: Foundation Slab:13_PBT_FS_beton t.p.g._d=200_bestaand, Foundation Slab:13_PBT_FS_beton t.p.g._d=200_bestaand:5078027
In: -1 kelder
Type - PredefinedType: BASESLAB; Material: 00_PBT_MAT_beton t.p.g. 200 mm
Type - Pset_ElementShading - Roughness: 304.8 mm
Type - Pset_ProductRequirements - Category: Structural Foundations
Type - Pset_ReinforcementBarPitchOfSlab - Description: betonvloer d=200
Type - Pset_SlabCommon - IsExternal: no
Type - Pset_Pieters - Naamgeving element: 13_PBT_FS_beton t.p.g._d=200_bestaand; Codering - NL-SfB: 13.20; Omschrijving NL-SfB: vloeren op grondslag - constructief, algemeen (verzamelniveau); Materiaal: 00_PBT_MAT_beton t.p.g.; Description: betonvloer d=200; Type Comments: d=200
Classification: 13.20 vloeren op grondslag - constructief, algemeen (verzamelniveau) (Uniformat)
Pset_QuantityTakeOff - Reference: Foundation Slab:13_PBT_FS_beton t.p.g._d=200_bestaand
Pset_ReinforcementBarPitchOfSlab - Reference: Foundation Slab:13_PBT_FS_beton t.p.g._d=200_bestaand
Pset_SlabCommon - LoadBearing: yes; PitchAngle: 0 deg; Reference: Foundation Slab:13_PBT_FS_beton t.p.g._d=200_bestaand
Pset_Pieters - Dikte: 200 mm; Bouwlaag: Level: -1 kelder_Offset1000; Fase: Bestaand
BaseQuantities - NetArea: 11708346 mm2; NetVolume: 2.34167 m3; Perimeter: 35200 mm; Width: 5100 mm

# IfcSlab: Foundation Slab:13_PBT_FS_beton t.p.g._d=250_bestaand, Foundation Slab:13_PBT_FS_beton t.p.g._d=250_bestaand:1657683
In: -2 kelder
Type - PredefinedType: BASESLAB; Material: 00_PBT_MAT_beton t.p.g. 250 mm
Type - Pset_ElementShading - Roughness: 304.8 mm
Type - Pset_ProductRequirements - Category: Structural Foundations
Type - Pset_ReinforcementBarPitchOfSlab - Description: i.h.w.g. betonvloer d=250
Type - Pset_SlabCommon - IsExternal: no
Type - Pset_Pieters - Naamgeving element: 13_PBT_FS_beton t.p.g._d=250_bestaand; Codering - NL-SfB: 13.20; Omschrijving NL-SfB: vloeren op grondslag - constructief, algemeen (verzamelniveau); Materiaal: 00_PBT_MAT_beton t.p.g.; Description: i.h.w.g. betonvloer d=250
Classification: 13.20 vloeren op grondslag - constructief, algemeen (verzamelniveau) (Uniformat)
Pset_QuantityTakeOff - Reference: Foundation Slab:13_PBT_FS_beton t.p.g._d=250_bestaand
Pset_ReinforcementBarPitchOfSlab - Reference: Foundation Slab:13_PBT_FS_beton t.p.g._d=250_bestaand
Pset_SlabCommon - LoadBearing: yes; IsExternal: yes; PitchAngle: 0 deg; Reference: Foundation Slab:13_PBT_FS_beton t.p.g._d=250_bestaand
Pset_Pieters - Dragend/niet dragend: yes; In/uitwendig: yes; Dikte: 250 mm; Bouwlaag: Level: -2 kelder_Offset1000; Fase: Bestaand
BaseQuantities - NetArea: 2793802 mm2; NetVolume: 0.698447 m3; Perimeter: 7899.56 mm; Width: 1700 mm

# IfcSlab: Foundation Slab:13_PBT_FS_beton t.p.g._d=300_C30/37 (4)
Type - PredefinedType: BASESLAB; Material: 00_PBT_MAT_beton t.p.g._C30/37 300 mm
Type - Pset_ElementShading - Roughness: 304.8 mm
Type - Pset_ProductRequirements - Category: Structural Foundations
Type - Pset_ReinforcementBarPitchOfSlab - Description: i.h.w.g. betonvloer d=300
Type - Pset_SlabCommon - IsExternal: no
Type - Pset_Pieters - Naamgeving element: 13_PBT_FS_beton t.p.g._d=300_C30/37; Codering - NL-SfB: 13.20; Omschrijving NL-SfB: vloeren op grondslag - constructief, algemeen (verzamelniveau); Materiaal: 00_PBT_MAT_beton t.p.g._C30/37; Materiaalkwaliteit: C30/37; Description: i.h.w.g. betonvloer d=300; Type Comments: d=300
Classification: 13.20 vloeren op grondslag - constructief, algemeen (verzamelniveau) (Uniformat)
Pset_QuantityTakeOff - Reference: Foundation Slab:13_PBT_FS_beton t.p.g._d=300_C30/37
Pset_ReinforcementBarPitchOfSlab - Reference: Foundation Slab:13_PBT_FS_beton t.p.g._d=300_C30/37
Pset_SlabCommon - LoadBearing: yes; PitchAngle: 0 deg; Reference: Foundation Slab:13_PBT_FS_beton t.p.g._d=300_C30/37
Pset_Pieters - Dikte: 300 mm; Fase: Nieuw
Name (Foundation Slab:13_PBT_FS_beton t.p.g._d=300_C30/37:...) | In | IsExternal = Dragend/niet dragend = In/uitwendig | Bouwlaag | GrossArea (mm2) = NetArea (mm2) | GrossVolume (m3) = NetVolume (m3) | Perimeter (mm) | Width (mm)
1992999 | 00 begane grond | yes | Level: 00 begane grond | 22556804 | 6.76704 | 19120 | 4240
2083485 | 00 begane grond | yes | Level: 00 begane grond | 59943355 | 17.983 | 42583.5 | 5113
2088722 | -1 kelder | yes | Level: -1 kelder | 20209624 | 6.06289 | 17999.8 | 4699.91
5076208 | -1 kelder |  | Level: -1 bk ruwe vloer bwd west | 26010000 | 7.803 | 20400 | 5100

# IfcSlab: Foundation Slab:13_PBT_FS_beton t.p.g._d=400_C30/37 (3)
Type - PredefinedType: BASESLAB; Material: 00_PBT_MAT_beton t.p.g._C30/37 400 mm
Type - Pset_ElementShading - Roughness: 304.8 mm
Type - Pset_ProductRequirements - Category: Structural Foundations
Type - Pset_ReinforcementBarPitchOfSlab - Description: betonvloer d=400
Type - Pset_SlabCommon - IsExternal: no
Type - Pset_Pieters - Naamgeving element: 13_PBT_FS_beton t.p.g._d=400_C30/37; Codering - NL-SfB: 13.20; Omschrijving NL-SfB: vloeren op grondslag - constructief, algemeen (verzamelniveau); Materiaal: 00_PBT_MAT_beton t.p.g._C30/37; Materiaalkwaliteit: C30/37; Description: betonvloer d=400; Type Comments: d=400
Classification: 13.20 vloeren op grondslag - constructief, algemeen (verzamelniveau) (Uniformat)
Pset_QuantityTakeOff - Reference: Foundation Slab:13_PBT_FS_beton t.p.g._d=400_C30/37
Pset_ReinforcementBarPitchOfSlab - Reference: Foundation Slab:13_PBT_FS_beton t.p.g._d=400_C30/37
Pset_SlabCommon - LoadBearing: yes; PitchAngle: 0 deg; Reference: Foundation Slab:13_PBT_FS_beton t.p.g._d=400_C30/37
Pset_Pieters - Dikte: 400 mm; Fase: Nieuw
Name (Foundation Slab:13_PBT_FS_beton t.p.g._d=400_C30/37:...) | In | Bouwlaag | GrossArea (mm2) = NetArea (mm2) | GrossVolume (m3) = NetVolume (m3) | Perimeter (mm) | Width (mm)
2088790 | -1 kelder | Level: -1 kelder | 46389647 | 18.5559 | 46884.6 | 6060 | Pset_SlabCommon - IsExternal: yes; Pset_Pieters - Dragend/niet dragend: yes; In/uitwendig: yes
3071686 | 00 begane grond | Level: 00 begane grond | 12472584 | 4.98903 | 17117.7 | 3758.13
4511718 | -1 kelder | Level: -1 kelder | 4242097 | 1.69684 | 10420 | 1010.02

# IfcSlab: Foundation Slab:13_PBT_FS_beton t.p.g._d=400_bestaand (7)
Type - PredefinedType: BASESLAB; Material: 00_PBT_MAT_beton t.p.g. 400 mm
Type - Pset_ElementShading - Roughness: 304.8 mm
Type - Pset_ProductRequirements - Category: Structural Foundations
Type - Pset_ReinforcementBarPitchOfSlab - Description: betonvloer d=400
Type - Pset_SlabCommon - IsExternal: no
Type - Pset_Pieters - Naamgeving element: 13_PBT_FS_beton t.p.g._d=400_bestaand; Codering - NL-SfB: 13.20; Omschrijving NL-SfB: vloeren op grondslag - constructief, algemeen (verzamelniveau); Materiaal: 00_PBT_MAT_beton t.p.g.; Description: betonvloer d=400; Type Comments: d=400
Classification: 13.20 vloeren op grondslag - constructief, algemeen (verzamelniveau) (Uniformat)
Pset_QuantityTakeOff - Reference: Foundation Slab:13_PBT_FS_beton t.p.g._d=400_bestaand
Pset_ReinforcementBarPitchOfSlab - Reference: Foundation Slab:13_PBT_FS_beton t.p.g._d=400_bestaand
Pset_SlabCommon - LoadBearing: yes; PitchAngle: 0 deg; Reference: Foundation Slab:13_PBT_FS_beton t.p.g._d=400_bestaand
Pset_Pieters - Dikte: 400 mm; Fase: Bestaand
Name (Foundation Slab:13_PBT_FS_beton t.p.g._d=400_bestaand:...) | In | IsExternal = Dragend/niet dragend = In/uitwendig | Bouwlaag | GrossArea (mm2) | NetArea (mm2) | GrossVolume (m3) | NetVolume (m3) | Perimeter (mm) | Width (mm)
1310698 | -1 kelder | yes | Level: -1 kelder_Offset1000 | 7854000 | 7854000 | 3.1416 | 3.1416 | 12140 | 1870
1313225 | -1 kelder | yes | Level: -1 kelder_Offset1000 | 607750051 | 607750051 | 243.1 | 243.1 | 117940 | 21190.2
1323753:2 | -1 kelder | yes | Level: -1 kelder_Offset1000 | 515000 | 1153897778 |  | 461.558 | 314585 | 58751.6
1364337 | -2 kelder | yes | Level: -2 kelder_Offset1000 | 13874100 | 13874100 | 5.54964 | 5.54964 | 15160 | 4490
1395744 | -2 kelder | yes | Level: -2 kelder_Offset1000 | 15580000 | 15580000 | 6.232 | 6.232 | 15800 | 4100
1397466 | -2 kelder | yes | Level: -2 kelder_Offset1000 | 5880250 | 5880250 | 2.3521 | 2.3521 | 9770 | 2150
3060469 | -1 kelder |  | Level: -1 kelder_Offset1000 | 11530600 | 11530600 | 4.61224 | 4.61224 | 14600 | 4780

# IfcSlab: Foundation Slab:13_PBT_FS_beton t.p.g._d=400_bestaand (2)
In: -1 kelder
Type - PredefinedType: BASESLAB
Type - Pset_ElementShading - Roughness: 304.8 mm
Type - Pset_ProductRequirements - Category: Structural Foundations
Type - Pset_ReinforcementBarPitchOfSlab - Description: betonvloer d=400
Type - Pset_SlabCommon - IsExternal: no
Type - Pset_Pieters - Naamgeving element: 13_PBT_FS_beton t.p.g._d=400_bestaand; Codering - NL-SfB: 13.20; Omschrijving NL-SfB: vloeren op grondslag - constructief, algemeen (verzamelniveau); Materiaal: 00_PBT_MAT_beton t.p.g.; Description: betonvloer d=400; Type Comments: d=400
Classification: 13.20 vloeren op grondslag - constructief, algemeen (verzamelniveau) (Uniformat)
Pset_QuantityTakeOff - Reference: Foundation Slab:13_PBT_FS_beton t.p.g._d=400_bestaand
Pset_ReinforcementBarPitchOfSlab - Reference: Foundation Slab:13_PBT_FS_beton t.p.g._d=400_bestaand
Pset_SlabCommon - LoadBearing: yes; IsExternal: yes; PitchAngle: 0 deg; Reference: Foundation Slab:13_PBT_FS_beton t.p.g._d=400_bestaand
Pset_Pieters - Dragend/niet dragend: yes; In/uitwendig: yes; Dikte: 400 mm; Bouwlaag: Level: -1 kelder_Offset1000; Fase: Bestaand
Name (Foundation Slab:13_PBT_FS_beton t.p.g._d=400_bestaand:...) | Material | NetArea (mm2) | NetVolume (m3) | Perimeter (mm) | Width (mm)
1323753 | 00_PBT_MAT_beton t.p.g. 400 mm | 1153897778 | 461.558 | 314585 | 58751.6 | BaseQuantities - GrossArea: 1193713640 mm2
1339068 | 00_PBT_MAT_beton t.p.g. | 88545634 | 35.1807 | 48070 | 14405

# IfcSlab: Foundation Slab:13_PBT_FS_beton t.p.g._d=500_C30/37, Foundation Slab:13_PBT_FS_beton t.p.g._d=500_C30/37:2265292
In: -1 kelder
Type - PredefinedType: BASESLAB; Material: 00_PBT_MAT_beton t.p.g._C30/37 500 mm
Type - Pset_ElementShading - Roughness: 304.8 mm
Type - Pset_ProductRequirements - Category: Structural Foundations
Type - Pset_ReinforcementBarPitchOfSlab - Description: i.h.w.g. betonvloer d=500
Type - Pset_SlabCommon - IsExternal: no
Type - Pset_Pieters - Naamgeving element: 13_PBT_FS_beton t.p.g._d=500_C30/37; Codering - NL-SfB: 13.20; Omschrijving NL-SfB: vloeren op grondslag - constructief, algemeen (verzamelniveau); Materiaal: 00_PBT_MAT_beton t.p.g._C30/37; Materiaalkwaliteit: C30/37; Description: i.h.w.g. betonvloer d=500; Type Comments: d=500
Classification: 13.20 vloeren op grondslag - constructief, algemeen (verzamelniveau) (Uniformat)
Pset_QuantityTakeOff - Reference: Foundation Slab:13_PBT_FS_beton t.p.g._d=500_C30/37
Pset_ReinforcementBarPitchOfSlab - Reference: Foundation Slab:13_PBT_FS_beton t.p.g._d=500_C30/37
Pset_SlabCommon - LoadBearing: yes; PitchAngle: 0 deg; Reference: Foundation Slab:13_PBT_FS_beton t.p.g._d=500_C30/37
Pset_Pieters - Dikte: 500 mm; Bouwlaag: Level: -1 kelder; Fase: Nieuw
BaseQuantities - GrossArea: 31115000 mm2; NetArea: 31115000 mm2; GrossVolume: 15.5575 m3; NetVolume: 15.5575 m3; Perimeter: 22500 mm; Width: 4900 mm

# IfcSlab: Foundation Slab:13_PBT_FS_beton t.p.g._d=500_bestaand, Foundation Slab:13_PBT_FS_beton t.p.g._d=500_bestaand:1401372
In: -2 kelder
Type - PredefinedType: BASESLAB; Material: 00_PBT_MAT_beton t.p.g. 500 mm
Type - Pset_ElementShading - Roughness: 304.8 mm
Type - Pset_ProductRequirements - Category: Structural Foundations
Type - Pset_ReinforcementBarPitchOfSlab - Description: i.h.w.g. betonvloer d=500
Type - Pset_SlabCommon - IsExternal: no
Type - Pset_Pieters - Naamgeving element: 13_PBT_FS_beton t.p.g._d=500_bestaand; Codering - NL-SfB: 13.20; Omschrijving NL-SfB: vloeren op grondslag - constructief, algemeen (verzamelniveau); Materiaal: 00_PBT_MAT_beton t.p.g.; Materiaalkwaliteit: C30/37; Description: i.h.w.g. betonvloer d=500; Type Comments: d=500
Classification: 13.20 vloeren op grondslag - constructief, algemeen (verzamelniveau) (Uniformat)
Pset_QuantityTakeOff - Reference: Foundation Slab:13_PBT_FS_beton t.p.g._d=500_bestaand
Pset_ReinforcementBarPitchOfSlab - Reference: Foundation Slab:13_PBT_FS_beton t.p.g._d=500_bestaand
Pset_SlabCommon - LoadBearing: yes; IsExternal: yes; PitchAngle: 0 deg; Reference: Foundation Slab:13_PBT_FS_beton t.p.g._d=500_bestaand
Pset_Pieters - Dragend/niet dragend: yes; In/uitwendig: yes; Dikte: 500 mm; Bouwlaag: Level: -2 kelder_Offset1000; Fase: Bestaand
BaseQuantities - GrossArea: 24426000 mm2; NetArea: 24040918 mm2; NetVolume: 11.3942 m3; Perimeter: 22969.1 mm; Width: 3600 mm

# IfcSlab: Foundation Slab:13_PBT_FS_beton t.p.g._d=570_bestaand, Foundation Slab:13_PBT_FS_beton t.p.g._d=570_bestaand:1399735
In: -1 kelder
Type - PredefinedType: BASESLAB; Material: 00_PBT_MAT_beton t.p.g. 570 mm
Type - Pset_ElementShading - Roughness: 304.8 mm
Type - Pset_ProductRequirements - Category: Structural Foundations
Type - Pset_ReinforcementBarPitchOfSlab - Description: i.h.w.g. betonvloer d=570
Type - Pset_SlabCommon - IsExternal: no
Type - Pset_Pieters - Naamgeving element: 13_PBT_FS_beton t.p.g._d=570_bestaand; Codering - NL-SfB: 13.20; Omschrijving NL-SfB: vloeren op grondslag - constructief, algemeen (verzamelniveau); Materiaal: 00_PBT_MAT_beton t.p.g.; Description: i.h.w.g. betonvloer d=570
Classification: 13.20 vloeren op grondslag - constructief, algemeen (verzamelniveau) (Uniformat)
Pset_QuantityTakeOff - Reference: Foundation Slab:13_PBT_FS_beton t.p.g._d=570_bestaand
Pset_ReinforcementBarPitchOfSlab - Reference: Foundation Slab:13_PBT_FS_beton t.p.g._d=570_bestaand
Pset_SlabCommon - LoadBearing: yes; IsExternal: yes; PitchAngle: 0 deg; Reference: Foundation Slab:13_PBT_FS_beton t.p.g._d=570_bestaand
Pset_Pieters - Dragend/niet dragend: yes; In/uitwendig: yes; Dikte: 570 mm; Bouwlaag: Level: -1 kelder_Offset1000; Fase: Bestaand
BaseQuantities - GrossArea: 413750 mm2; NetArea: 413750 mm2; GrossVolume: 0.235838 m3; NetVolume: 0.235838 m3; Perimeter: 3810 mm; Width: 1655 mm

# IfcSlab: Foundation Slab:13_PBT_FS_beton t.p.g._d=600_C30/37, Foundation Slab:13_PBT_FS_beton t.p.g._d=600_C30/37:4589141
In: 00 begane grond
Type - PredefinedType: BASESLAB; Material: 00_PBT_MAT_beton t.p.g._C30/37 600 mm
Type - Pset_ElementShading - Roughness: 304.8 mm
Type - Pset_ProductRequirements - Category: Structural Foundations
Type - Pset_ReinforcementBarPitchOfSlab - Description: i.h.w.g. betonvloer d=600
Type - Pset_SlabCommon - IsExternal: no
Type - Pset_Pieters - Naamgeving element: 13_PBT_FS_beton t.p.g._d=600_C30/37; Codering - NL-SfB: 13.20; Omschrijving NL-SfB: vloeren op grondslag - constructief, algemeen (verzamelniveau); Materiaal: 00_PBT_MAT_beton t.p.g._C30/37; Materiaalkwaliteit: C30/37; Description: i.h.w.g. betonvloer d=600; Type Comments: d=600
Classification: 13.20 vloeren op grondslag - constructief, algemeen (verzamelniveau) (Uniformat)
Pset_QuantityTakeOff - Reference: Foundation Slab:13_PBT_FS_beton t.p.g._d=600_C30/37
Pset_ReinforcementBarPitchOfSlab - Reference: Foundation Slab:13_PBT_FS_beton t.p.g._d=600_C30/37
Pset_SlabCommon - LoadBearing: yes; PitchAngle: 0 deg; Reference: Foundation Slab:13_PBT_FS_beton t.p.g._d=600_C30/37
Pset_Pieters - Dikte: 600 mm; Bouwlaag: Level: 00 begane grond; Fase: Nieuw
BaseQuantities - NetArea: 9243202 mm2; NetVolume: 2.77296 m3; Perimeter: 12840 mm; Width: 4240 mm

# IfcSlab: Foundation Slab:13_PBT_FS_beton t.p.g._d=700_bestaand (5)
In: -1 kelder
Type - PredefinedType: BASESLAB; Material: 00_PBT_MAT_beton t.p.g. 700 mm
Type - Pset_ElementShading - Roughness: 304.8 mm
Type - Pset_ProductRequirements - Category: Structural Foundations
Type - Pset_ReinforcementBarPitchOfSlab - Description: i.h.w.g. betonvloer d=700
Type - Pset_SlabCommon - IsExternal: no
Type - Pset_Pieters - Naamgeving element: 13_PBT_FS_beton t.p.g._d=700_bestaand; Codering - NL-SfB: 13.20; Omschrijving NL-SfB: vloeren op grondslag - constructief, algemeen (verzamelniveau); Materiaal: 00_PBT_MAT_beton t.p.g.; Description: i.h.w.g. betonvloer d=700; Type Comments: d=700
Classification: 13.20 vloeren op grondslag - constructief, algemeen (verzamelniveau) (Uniformat)
Pset_QuantityTakeOff - Reference: Foundation Slab:13_PBT_FS_beton t.p.g._d=700_bestaand
Pset_ReinforcementBarPitchOfSlab - Reference: Foundation Slab:13_PBT_FS_beton t.p.g._d=700_bestaand
Pset_SlabCommon - LoadBearing: yes; IsExternal: yes; PitchAngle: 0 deg; Reference: Foundation Slab:13_PBT_FS_beton t.p.g._d=700_bestaand
Pset_Pieters - Dragend/niet dragend: yes; In/uitwendig: yes; Dikte: 700 mm; Bouwlaag: Level: -1 kelder_Offset1000; Fase: Bestaand
Name (Foundation Slab:13_PBT_FS_beton t.p.g._d=700_bestaand:...) | NetArea (mm2) | NetVolume (m3) | Perimeter (mm) | Width (mm)
1326269 | 12220000 | 3.666 | 16220 | 6110
1326801 | 12220000 | 3.666 | 16220 | 6110
1329384 | 7640000 | 2.292 | 11640 | 3820
1335240 | 7394213 | 2.21826 | 13620 | 4810
1391276 | 65868957 | 46.1082 | 38070.2 | 6040 | BaseQuantities - GrossArea: 66198400 mm2

# IfcSlab: Foundation Slab:13_PBT_FS_beton t.p.g._d=700_bestaand (2)
In: -1 kelder
Type - PredefinedType: BASESLAB
Type - Pset_ElementShading - Roughness: 304.8 mm
Type - Pset_ProductRequirements - Category: Structural Foundations
Type - Pset_ReinforcementBarPitchOfSlab - Description: i.h.w.g. betonvloer d=700
Type - Pset_SlabCommon - IsExternal: no
Type - Pset_Pieters - Naamgeving element: 13_PBT_FS_beton t.p.g._d=700_bestaand; Codering - NL-SfB: 13.20; Omschrijving NL-SfB: vloeren op grondslag - constructief, algemeen (verzamelniveau); Materiaal: 00_PBT_MAT_beton t.p.g.; Description: i.h.w.g. betonvloer d=700; Type Comments: d=700
Classification: 13.20 vloeren op grondslag - constructief, algemeen (verzamelniveau) (Uniformat); Material: 00_PBT_MAT_beton t.p.g.
Pset_QuantityTakeOff - Reference: Foundation Slab:13_PBT_FS_beton t.p.g._d=700_bestaand
Pset_ReinforcementBarPitchOfSlab - Reference: Foundation Slab:13_PBT_FS_beton t.p.g._d=700_bestaand
Pset_SlabCommon - LoadBearing: yes; IsExternal: yes; PitchAngle: 0 deg; Reference: Foundation Slab:13_PBT_FS_beton t.p.g._d=700_bestaand
Pset_Pieters - Dragend/niet dragend: yes; In/uitwendig: yes; Dikte: 700 mm; Bouwlaag: Level: -1 kelder_Offset1000; Fase: Bestaand
BaseQuantities - NetArea: 12220000 mm2; Perimeter: 16220 mm; Width: 6110 mm
Name (Foundation Slab:13_PBT_FS_beton t.p.g._d=700_bestaand:...) | NetVolume (m3)
1335137 | 4.07424
1335190 | 4.16496

# IfcSlab: Foundation Slab:13_PBT_FS_beton t.p.g._d=740_bestaand, Foundation Slab:13_PBT_FS_beton t.p.g._d=740_bestaand:1399498
In: -1 kelder
Type - PredefinedType: BASESLAB; Material: 00_PBT_MAT_beton t.p.g. 740 mm
Type - Pset_ElementShading - Roughness: 304.8 mm
Type - Pset_ProductRequirements - Category: Structural Foundations
Type - Pset_ReinforcementBarPitchOfSlab - Description: i.h.w.g. betonvloer d=740
Type - Pset_SlabCommon - IsExternal: no
Type - Pset_Pieters - Naamgeving element: 13_PBT_FS_beton t.p.g._d=740_bestaand; Codering - NL-SfB: 13.20; Omschrijving NL-SfB: vloeren op grondslag - constructief, algemeen (verzamelniveau); Materiaal: 00_PBT_MAT_beton t.p.g.; Description: i.h.w.g. betonvloer d=740
Classification: 13.20 vloeren op grondslag - constructief, algemeen (verzamelniveau) (Uniformat)
Pset_QuantityTakeOff - Reference: Foundation Slab:13_PBT_FS_beton t.p.g._d=740_bestaand
Pset_ReinforcementBarPitchOfSlab - Reference: Foundation Slab:13_PBT_FS_beton t.p.g._d=740_bestaand
Pset_SlabCommon - LoadBearing: yes; IsExternal: yes; PitchAngle: 0 deg; Reference: Foundation Slab:13_PBT_FS_beton t.p.g._d=740_bestaand
Pset_Pieters - Dragend/niet dragend: yes; In/uitwendig: yes; Dikte: 740 mm; Bouwlaag: Level: -1 kelder_Offset1000; Fase: Bestaand
BaseQuantities - GrossArea: 30123000 mm2; NetArea: 30123000 mm2; GrossVolume: 22.291 m3; NetVolume: 22.291 m3; Perimeter: 23240 mm; Width: 7050 mm

# IfcSlab: Foundation Slab:13_PBT_FS_beton t.p.g._d=800_C30/37 (2)
In: 00 begane grond
Type - PredefinedType: BASESLAB; Material: 00_PBT_MAT_beton t.p.g._C30/37 800 mm
Type - Pset_ElementShading - Roughness: 304.8 mm
Type - Pset_ProductRequirements - Category: Structural Foundations
Type - Pset_ReinforcementBarPitchOfSlab - Description: i.h.w.g. betonvloer d=800
Type - Pset_SlabCommon - IsExternal: no
Type - Pset_Pieters - Naamgeving element: 13_PBT_FS_beton t.p.g._d=800_C30/37; Codering - NL-SfB: 13.20; Omschrijving NL-SfB: vloeren op grondslag - constructief, algemeen (verzamelniveau); Materiaal: 00_PBT_MAT_beton t.p.g._C30/37; Materiaalkwaliteit: C30/37; Description: i.h.w.g. betonvloer d=800; Type Comments: d=800
Classification: 13.20 vloeren op grondslag - constructief, algemeen (verzamelniveau) (Uniformat)
Pset_QuantityTakeOff - Reference: Foundation Slab:13_PBT_FS_beton t.p.g._d=800_C30/37
Pset_ReinforcementBarPitchOfSlab - Reference: Foundation Slab:13_PBT_FS_beton t.p.g._d=800_C30/37
Pset_SlabCommon - LoadBearing: yes; PitchAngle: 0 deg; Reference: Foundation Slab:13_PBT_FS_beton t.p.g._d=800_C30/37
Pset_Pieters - Dikte: 800 mm; Bouwlaag: Level: 00 begane grond; Fase: Nieuw
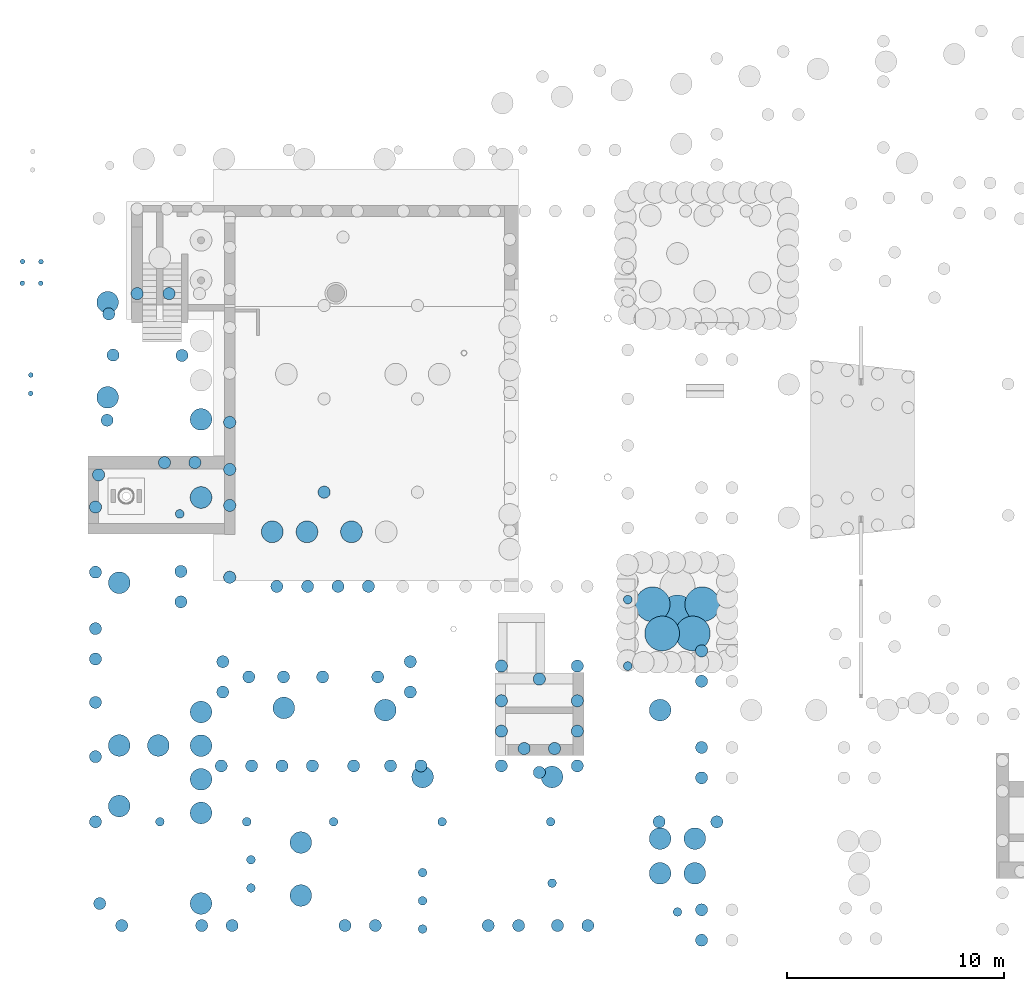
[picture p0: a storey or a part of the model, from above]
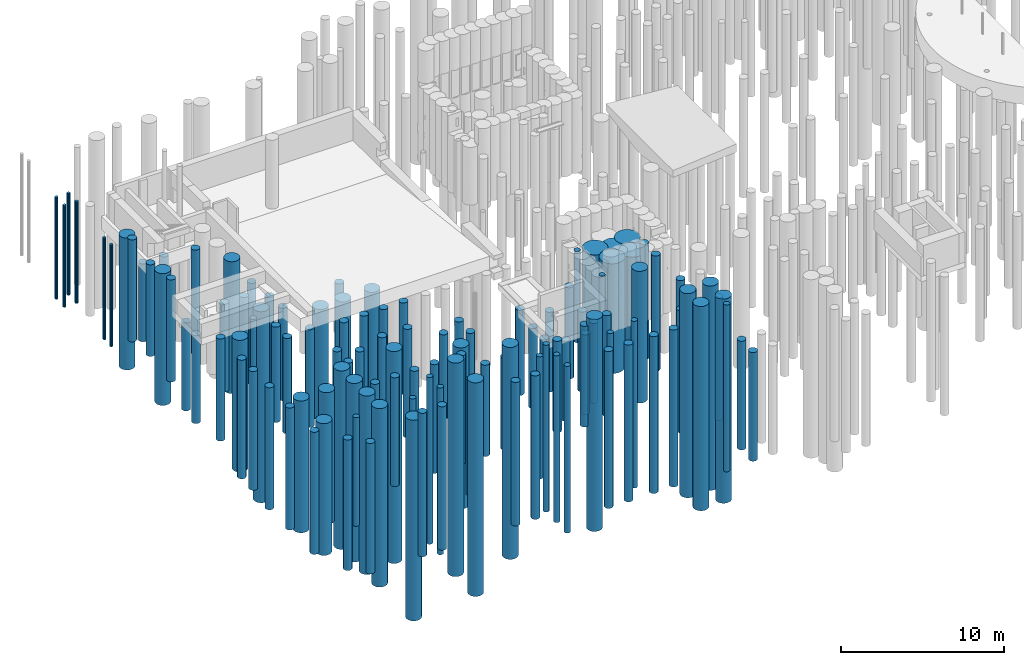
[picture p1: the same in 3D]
Properties of the parts of a building model (IFC2X3), part 16 of 18

# IfcSlab: Foundation Slab:13_PBT_FS_beton t.p.g._d=800_C30/37 (2)
Name (Foundation Slab:13_PBT_FS_beton t.p.g._d=800_C30/37:...) | GrossArea (mm2) = NetArea (mm2) | GrossVolume (m3) = NetVolume (m3) | Perimeter (mm) | Width (mm)
3882214 | 166160115 | 132.928 | 64522 | 8075.9
3882436 | 45242349 | 36.1939 | 30506.7 | 7391.37

# IfcSlab: Foundation Slab:13_PBT_FS_beton t.p.g._d=800_C30/37, Foundation Slab:13_PBT_FS_beton t.p.g._d=800_C30/37:4540272
In: 00 begane grond
Type - PredefinedType: BASESLAB
Type - Pset_ElementShading - Roughness: 304.8 mm
Type - Pset_ProductRequirements - Category: Structural Foundations
Type - Pset_ReinforcementBarPitchOfSlab - Description: i.h.w.g. betonvloer d=800
Type - Pset_SlabCommon - IsExternal: no
Type - Pset_Pieters - Naamgeving element: 13_PBT_FS_beton t.p.g._d=800_C30/37; Codering - NL-SfB: 13.20; Omschrijving NL-SfB: vloeren op grondslag - constructief, algemeen (verzamelniveau); Materiaal: 00_PBT_MAT_beton t.p.g._C30/37; Materiaalkwaliteit: C30/37; Description: i.h.w.g. betonvloer d=800; Type Comments: d=800
Classification: 13.20 vloeren op grondslag - constructief, algemeen (verzamelniveau) (Uniformat); Material: 00_PBT_MAT_beton t.p.g._C30/37
Pset_QuantityTakeOff - Reference: Foundation Slab:13_PBT_FS_beton t.p.g._d=800_C30/37
Pset_ReinforcementBarPitchOfSlab - Reference: Foundation Slab:13_PBT_FS_beton t.p.g._d=800_C30/37
Pset_SlabCommon - LoadBearing: yes; PitchAngle: 0 deg; Reference: Foundation Slab:13_PBT_FS_beton t.p.g._d=800_C30/37
Pset_Pieters - Dikte: 800 mm; Bouwlaag: Level: 00 begane grond; Fase: Nieuw
BaseQuantities - NetArea: 66328444 mm2; NetVolume: 54.5951 m3; Perimeter: 39003.3 mm; Width: 9732.23 mm

# IfcSlab: Foundation Slab:13_PBT_FS_beton t.p.g._d=900 poer_bestaand (2)
In: -1 kelder
Type - PredefinedType: BASESLAB; Material: 00_PBT_MAT_beton t.p.g. 900 mm
Type - Pset_ElementShading - Roughness: 304.8 mm
Type - Pset_ProductRequirements - Category: Structural Foundations
Type - Pset_ReinforcementBarPitchOfSlab - Description: poer h=900
Type - Pset_SlabCommon - IsExternal: no
Type - Pset_Pieters - Naamgeving element: 13_PBT_FS_beton t.p.g._d=900 poer_bestaand; Codering - NL-SfB: 13.20; Omschrijving NL-SfB: vloeren op grondslag - constructief, algemeen (verzamelniveau); Materiaal: 00_PBT_MAT_beton t.p.g.; Description: poer h=900; Type Comments: h=900
Classification: 13.20 vloeren op grondslag - constructief, algemeen (verzamelniveau) (Uniformat)
Pset_QuantityTakeOff - Reference: Foundation Slab:13_PBT_FS_beton t.p.g._d=900 poer_bestaand
Pset_ReinforcementBarPitchOfSlab - Reference: Foundation Slab:13_PBT_FS_beton t.p.g._d=900 poer_bestaand
Pset_SlabCommon - LoadBearing: yes; IsExternal: yes; PitchAngle: 0 deg; Reference: Foundation Slab:13_PBT_FS_beton t.p.g._d=900 poer_bestaand
Pset_Pieters - Dragend/niet dragend: yes; In/uitwendig: yes; Dikte: 900 mm; Bouwlaag: Level: -1 kelder_Offset1000; Fase: Bestaand
Name (Foundation Slab:13_PBT_FS_beton t.p.g._d=900 poer_bestaand:...) | NetArea (mm2) | NetVolume (m3) | Perimeter (mm) | Width (mm)
1335572 | 2120000 | 1.06 | 6120 | 2000
1374633 | 6844619 | 3.42231 | 10875 | 2272.1 | Pset_Pieters - Comments: poer h=900

# IfcSlab: Foundation Slab:13_PBT_FS_beton t.p.g._d=900 poer_bestaand (2)
In: -1 kelder
Type - PredefinedType: BASESLAB
Type - Pset_ElementShading - Roughness: 304.8 mm
Type - Pset_ProductRequirements - Category: Structural Foundations
Type - Pset_ReinforcementBarPitchOfSlab - Description: poer h=900
Type - Pset_SlabCommon - IsExternal: no
Type - Pset_Pieters - Naamgeving element: 13_PBT_FS_beton t.p.g._d=900 poer_bestaand; Codering - NL-SfB: 13.20; Omschrijving NL-SfB: vloeren op grondslag - constructief, algemeen (verzamelniveau); Materiaal: 00_PBT_MAT_beton t.p.g.; Description: poer h=900; Type Comments: h=900
Classification: 13.20 vloeren op grondslag - constructief, algemeen (verzamelniveau) (Uniformat); Material: 00_PBT_MAT_beton t.p.g.
Pset_QuantityTakeOff - Reference: Foundation Slab:13_PBT_FS_beton t.p.g._d=900 poer_bestaand
Pset_ReinforcementBarPitchOfSlab - Reference: Foundation Slab:13_PBT_FS_beton t.p.g._d=900 poer_bestaand
Pset_SlabCommon - LoadBearing: yes; IsExternal: yes; PitchAngle: 0 deg; Reference: Foundation Slab:13_PBT_FS_beton t.p.g._d=900 poer_bestaand
Pset_Pieters - Dragend/niet dragend: yes; In/uitwendig: yes; Dikte: 900 mm; Bouwlaag: Level: -1 kelder_Offset1000; Fase: Bestaand
Name (Foundation Slab:13_PBT_FS_beton t.p.g._d=900 poer_bestaand:...) | NetArea (mm2) | NetVolume (m3) | Perimeter (mm) | Width (mm)
1374065 | 6854497 | 4.28895 | 10884.9 | 2262.04 | Pset_Pieters - Comments: poer h=900
1399984 | 2925000 | 1.4875 | 6765.31 | 2000

# IfcSlab: Foundation Slab:13_PBT_FS_beton t.p.g._d=960_C30/37, Foundation Slab:13_PBT_FS_beton t.p.g._d=960_C30/37:2996489
In: -1 kelder
Type - PredefinedType: BASESLAB; Material: 00_PBT_MAT_beton t.p.g._C30/37 960 mm
Type - Pset_ElementShading - Roughness: 304.8 mm
Type - Pset_ProductRequirements - Category: Structural Foundations
Type - Pset_ReinforcementBarPitchOfSlab - Description: i.h.w.g. betonvloer d=960
Type - Pset_SlabCommon - IsExternal: no
Type - Pset_Pieters - Naamgeving element: 13_PBT_FS_beton t.p.g._d=960_C30/37; Codering - NL-SfB: 13.20; Omschrijving NL-SfB: vloeren op grondslag - constructief, algemeen (verzamelniveau); Materiaal: 00_PBT_MAT_beton t.p.g._C30/37; Materiaalkwaliteit: C30/37; Description: i.h.w.g. betonvloer d=960; Type Comments: d=960
Classification: 13.20 vloeren op grondslag - constructief, algemeen (verzamelniveau) (Uniformat)
Pset_QuantityTakeOff - Reference: Foundation Slab:13_PBT_FS_beton t.p.g._d=960_C30/37
Pset_ReinforcementBarPitchOfSlab - Reference: Foundation Slab:13_PBT_FS_beton t.p.g._d=960_C30/37
Pset_SlabCommon - LoadBearing: yes; IsExternal: yes; PitchAngle: 0 deg; Reference: Foundation Slab:13_PBT_FS_beton t.p.g._d=960_C30/37
Pset_Pieters - Dragend/niet dragend: yes; In/uitwendig: yes; Dikte: 960 mm; Bouwlaag: Level: -1 kelder; Fase: Nieuw
BaseQuantities - GrossArea: 1020000 mm2; NetArea: 1020000 mm2; GrossVolume: 0.9792 m3; NetVolume: 0.9792 m3; Perimeter: 4040 mm; Width: 1020 mm

# IfcSlab: Foundation Slab:13_PBT_FS_beton t.p.g._d=960_bestaand, Foundation Slab:13_PBT_FS_beton t.p.g._d=960_bestaand:1339554
In: -1 kelder
Type - PredefinedType: BASESLAB; Material: 00_PBT_MAT_beton t.p.g. 960 mm
Type - Pset_ElementShading - Roughness: 304.8 mm
Type - Pset_ProductRequirements - Category: Structural Foundations
Type - Pset_ReinforcementBarPitchOfSlab - Description: i.h.w.g. betonvloer d=960
Type - Pset_SlabCommon - IsExternal: no
Type - Pset_Pieters - Naamgeving element: 13_PBT_FS_beton t.p.g._d=960_bestaand; Codering - NL-SfB: 13.20; Omschrijving NL-SfB: vloeren op grondslag - constructief, algemeen (verzamelniveau); Materiaal: 00_PBT_MAT_beton t.p.g.; Materiaalkwaliteit: C30/37; Description: i.h.w.g. betonvloer d=960; Type Comments: d=960
Classification: 13.20 vloeren op grondslag - constructief, algemeen (verzamelniveau) (Uniformat)
Pset_QuantityTakeOff - Reference: Foundation Slab:13_PBT_FS_beton t.p.g._d=960_bestaand
Pset_ReinforcementBarPitchOfSlab - Reference: Foundation Slab:13_PBT_FS_beton t.p.g._d=960_bestaand
Pset_SlabCommon - LoadBearing: yes; IsExternal: yes; PitchAngle: 0 deg; Reference: Foundation Slab:13_PBT_FS_beton t.p.g._d=960_bestaand
Pset_Pieters - Dragend/niet dragend: yes; In/uitwendig: yes; Dikte: 960 mm; Bouwlaag: Level: -1 kelder_Offset1000; Fase: Bestaand
BaseQuantities - NetArea: 4637259 mm2; NetVolume: 2.59686 m3; Perimeter: 15544.5 mm; Width: 2255 mm

# IfcSlab: Foundation Slab:13_PBT_FS_grout bouwputbodem_d=1000 (3)
In: -2 kelder
Type - PredefinedType: BASESLAB; Material: 00_PBT_MAT_grout 1000 mm
Type - Pset_ElementShading - Roughness: 304.8 mm
Type - Pset_ProductRequirements - Category: Structural Foundations
Type - Pset_ReinforcementBarPitchOfSlab - Description: bouwputbodem d=1000
Type - Pset_SlabCommon - IsExternal: no
Type - Pset_Pieters - Naamgeving element: 13_PBT_FS_grout bouwputbodem_d=1000; Codering - NL-SfB: 13.20; Omschrijving NL-SfB: vloeren op grondslag - constructief, algemeen (verzamelniveau); Materiaal: 00_PBT_MAT_grout; Description: bouwputbodem d=1000
Classification: 13.20 vloeren op grondslag - constructief, algemeen (verzamelniveau) (Uniformat)
Pset_QuantityTakeOff - Reference: Foundation Slab:13_PBT_FS_grout bouwputbodem_d=1000
Pset_ReinforcementBarPitchOfSlab - Reference: Foundation Slab:13_PBT_FS_grout bouwputbodem_d=1000
Pset_SlabCommon - LoadBearing: yes; PitchAngle: 0 deg; Reference: Foundation Slab:13_PBT_FS_grout bouwputbodem_d=1000
Pset_Pieters - Dikte: 1000 mm; Bouwlaag: Level: NAP; Fase: Nieuw
Name (Foundation Slab:13_PBT_FS_grout bouwputbodem_d=1000:...) | GrossArea (mm2) = NetArea (mm2) | GrossVolume (m3) = NetVolume (m3) | Perimeter (mm) | Width (mm)
3038546 | 93135200 | 93.1352 | 49482.6 | 7038.65
3053187 | 17472000 | 17.472 | 16720 | 4200
3871324 | 39182395 | 39.1824 | 25270.1 | 5463.9

# IfcWall: Basic Wall:16_PBT_WA_beton t.p.g._d=300_bestaand (3)
In: -1 kelder
Type - PredefinedType: STANDARD; Material: 00_PBT_MAT_beton t.p.g. 300 mm
Type - Pset_ElementShading - Roughness: 304.8 mm
Type - Pset_ProductRequirements - Category: Walls
Type - Pset_ReinforcementBarPitchOfWall - Description: betonwand d=300
Type - Pset_WallCommon - IsExternal: yes
Type - Pset_Pieters - Dikte: 300 mm; Naamgeving element: 16_PBT_WA_beton t.p.g._d=300_bestaand; Codering - NL-SfB: 16.20; Omschrijving NL-SfB: funderingsconstructies - keerwanden, algemeen (verzamelniveau); Materiaal: 00_PBT_MAT_beton t.p.g.; Description: betonwand d=300
Classification: 16.20 funderingsconstructies - keerwanden, algemeen (verzamelniveau) (Uniformat)
Pset_QuantityTakeOff - Reference: Basic Wall:16_PBT_WA_beton t.p.g._d=300_bestaand
Pset_ReinforcementBarPitchOfWall - Reference: Basic Wall:16_PBT_WA_beton t.p.g._d=300_bestaand
Pset_WallCommon - LoadBearing: yes; ExtendToStructure: no; Reference: Basic Wall:16_PBT_WA_beton t.p.g._d=300_bestaand
Pset_Pieters - Dragend/niet dragend: yes; In/uitwendig: yes; Bouwlaag: Level: -1 kelder_Offset1000; Fase: Bestaand
Name (Basic Wall:16_PBT_WA_beton t.p.g._d=300_bestaand:...)
1347908
1348248
1388126

# IfcWall: Basic Wall:16_PBT_WA_beton t.p.g._d=500_bestaand, Basic Wall:16_PBT_WA_beton t.p.g._d=500_bestaand:1394072
In: -2 kelder
Type - PredefinedType: STANDARD; Material: 00_PBT_MAT_beton t.p.g. 500 mm
Type - Pset_ElementShading - Roughness: 304.8 mm
Type - Pset_ProductRequirements - Category: Walls
Type - Pset_ReinforcementBarPitchOfWall - Description: betonwand d=500
Type - Pset_WallCommon - IsExternal: yes
Type - Pset_Pieters - Dikte: 500 mm; Naamgeving element: 16_PBT_WA_beton t.p.g._d=500_bestaand; Codering - NL-SfB: 16.20; Omschrijving NL-SfB: funderingsconstructies - keerwanden, algemeen (verzamelniveau); Materiaal: 00_PBT_MAT_beton t.p.g.; Description: betonwand d=500
Classification: 16.20 funderingsconstructies - keerwanden, algemeen (verzamelniveau) (Uniformat)
Pset_QuantityTakeOff - Reference: Basic Wall:16_PBT_WA_beton t.p.g._d=500_bestaand
Pset_ReinforcementBarPitchOfWall - Reference: Basic Wall:16_PBT_WA_beton t.p.g._d=500_bestaand
Pset_WallCommon - LoadBearing: yes; ExtendToStructure: no; Reference: Basic Wall:16_PBT_WA_beton t.p.g._d=500_bestaand
Pset_Pieters - Dragend/niet dragend: yes; In/uitwendig: yes; Bouwlaag: Level: -2 kelder_Offset1000; Fase: Bestaand

# IfcWall: Basic Wall:16_PBT_WA_beton t.p.g._d=650_bestaand (3)
Type - PredefinedType: STANDARD; Material: 00_PBT_MAT_beton t.p.g. 650 mm
Type - Pset_ElementShading - Roughness: 304.8 mm
Type - Pset_ProductRequirements - Category: Walls
Type - Pset_ReinforcementBarPitchOfWall - Description: betonwand d=650
Type - Pset_WallCommon - IsExternal: yes
Type - Pset_Pieters - Dikte: 650 mm; Naamgeving element: 16_PBT_WA_beton t.p.g._d=650_bestaand; Codering - NL-SfB: 16.20; Omschrijving NL-SfB: funderingsconstructies - keerwanden, algemeen (verzamelniveau); Materiaal: 00_PBT_MAT_beton t.p.g.; Description: betonwand d=650
Classification: 16.20 funderingsconstructies - keerwanden, algemeen (verzamelniveau) (Uniformat)
Pset_QuantityTakeOff - Reference: Basic Wall:16_PBT_WA_beton t.p.g._d=650_bestaand
Pset_ReinforcementBarPitchOfWall - Reference: Basic Wall:16_PBT_WA_beton t.p.g._d=650_bestaand
Pset_WallCommon - LoadBearing: yes; ExtendToStructure: no; Reference: Basic Wall:16_PBT_WA_beton t.p.g._d=650_bestaand
Pset_Pieters - Dragend/niet dragend: yes; In/uitwendig: yes; Fase: Bestaand
Name (Basic Wall:16_PBT_WA_beton t.p.g._d=650_bestaand:...) | In | Bouwlaag
1391369 | -2 kelder | Level: -2 kelder_Offset1000
1393528 | -2 kelder | Level: -2 kelder_Offset1000
1405872 | -1 kelder | Level: -1 kelder_Offset1000

# IfcWall: Basic Wall:28_PBT_WA_beton t.p.g._d=150_C30/37 (5)
Type - PredefinedType: STANDARD; Material: 00_PBT_MAT_beton t.p.g._C30/37 150 mm
Type - Pset_ElementShading - Roughness: 304.8 mm
Type - Pset_ProductRequirements - Category: Walls
Type - Pset_ReinforcementBarPitchOfWall - Description: betonwand d=150
Type - Pset_WallCommon - IsExternal: no
Type - Pset_Pieters - Dikte: 150 mm; Naamgeving element: 28_PBT_WA_beton t.p.g._d=150_C30/37; Codering - NL-SfB: 28.21; Omschrijving NL-SfB: hoofddraagconstructies - wanden en vloeren, wand-/vloerconstructies; Materiaal: 00_PBT_MAT_beton t.p.g._C30/37; Materiaalkwaliteit: C30/37; Description: betonwand d=150; Type Comments: d=150
Classification: 28.21 hoofddraagconstructies - wanden en vloeren, wand-/vloerconstructies (Uniformat)
Pset_QuantityTakeOff - Reference: Basic Wall:28_PBT_WA_beton t.p.g._d=150_C30/37
Pset_ReinforcementBarPitchOfWall - Reference: Basic Wall:28_PBT_WA_beton t.p.g._d=150_C30/37
Pset_WallCommon - LoadBearing: yes; ExtendToStructure: no; Reference: Basic Wall:28_PBT_WA_beton t.p.g._d=150_C30/37
Pset_Pieters - Fase: Nieuw
Name (Basic Wall:28_PBT_WA_beton t.p.g._d=150_C30/37:...) | In | Dragend/niet dragend | In/uitwendig | Bouwlaag
2240464 | 01 eerste verdieping | yes | no | Level: 01 eerste verdieping
2328667 | 02 tweede verdieping | yes | no | Level: 02 tweede verdieping
2328669 | 02 tweede verdieping | yes | no | Level: 02 tweede verdieping
3573320 | 02 tweede verdieping |  |  | Level: 02 tweede verdieping
3573885 | 02 tweede verdieping |  |  | Level: 02 tweede verdieping

# IfcWall: Basic Wall:28_PBT_WA_beton t.p.g._d=150_bestaand, Basic Wall:28_PBT_WA_beton t.p.g._d=150_bestaand:1813273
In: 03 derde verdieping
Type - PredefinedType: STANDARD; Material: 00_PBT_MAT_beton t.p.g. 150 mm
Type - Pset_ElementShading - Roughness: 304.8 mm
Type - Pset_ProductRequirements - Category: Walls
Type - Pset_ReinforcementBarPitchOfWall - Description: betonwand d=150
Type - Pset_WallCommon - IsExternal: no
Type - Pset_Pieters - Dikte: 150 mm; Naamgeving element: 28_PBT_WA_beton t.p.g._d=150_bestaand; Codering - NL-SfB: 28.21; Omschrijving NL-SfB: hoofddraagconstructies - wanden en vloeren, wand-/vloerconstructies; Materiaal: 00_PBT_MAT_beton t.p.g.; Description: betonwand d=150
Classification: 28.21 hoofddraagconstructies - wanden en vloeren, wand-/vloerconstructies (Uniformat)
Pset_QuantityTakeOff - Reference: Basic Wall:28_PBT_WA_beton t.p.g._d=150_bestaand
Pset_ReinforcementBarPitchOfWall - Reference: Basic Wall:28_PBT_WA_beton t.p.g._d=150_bestaand
Pset_WallCommon - LoadBearing: yes; ExtendToStructure: no; Reference: Basic Wall:28_PBT_WA_beton t.p.g._d=150_bestaand
Pset_Pieters - Dragend/niet dragend: yes; In/uitwendig: no; Bouwlaag: Level: 03 derde verdieping_Offset1000; Fase: Bestaand

# IfcWall: Basic Wall:28_PBT_WA_beton t.p.g._d=200_C30/37 (4)
Type - PredefinedType: STANDARD; Material: 00_PBT_MAT_beton t.p.g._C30/37 200 mm
Type - Pset_ElementShading - Roughness: 304.8 mm
Type - Pset_ProductRequirements - Category: Walls
Type - Pset_ReinforcementBarPitchOfWall - Description: betonwand d=200
Type - Pset_WallCommon - IsExternal: yes
Type - Pset_Pieters - Dikte: 200 mm; Naamgeving element: 28_PBT_WA_beton t.p.g._d=200_C30/37; Codering - NL-SfB: 28.21; Omschrijving NL-SfB: hoofddraagconstructies - wanden en vloeren, wand-/vloerconstructies; Materiaal: 00_PBT_MAT_beton t.p.g._C30/37; Materiaalkwaliteit: C30/37; Description: betonwand d=200; Type Comments: d=200
Classification: 28.21 hoofddraagconstructies - wanden en vloeren, wand-/vloerconstructies (Uniformat)
Pset_QuantityTakeOff - Reference: Basic Wall:28_PBT_WA_beton t.p.g._d=200_C30/37
Pset_ReinforcementBarPitchOfWall - Reference: Basic Wall:28_PBT_WA_beton t.p.g._d=200_C30/37
Pset_WallCommon - IsExternal: no; LoadBearing: yes; ExtendToStructure: no; Reference: Basic Wall:28_PBT_WA_beton t.p.g._d=200_C30/37
Pset_Pieters - Dragend/niet dragend: yes; In/uitwendig: no; Fase: Nieuw
Name (Basic Wall:28_PBT_WA_beton t.p.g._d=200_C30/37:...) | In | Bouwlaag
2096262 | 00 begane grond | Level: 00 begane grond
2688324 | 01 eerste verdieping | Level: 01 eerste verdieping
2688510 | 02 tweede verdieping | Level: 02 tweede verdieping
2688674 | 04 vierde verdieping | Level: 04 vierde verdieping

# IfcWall: Basic Wall:28_PBT_WA_beton t.p.g._d=230_C40/50, Basic Wall:28_PBT_WA_beton t.p.g._d=230_C40/50:2158154
In: 04 vierde verdieping
Type - PredefinedType: STANDARD; Material: 00_PBT_MAT_beton t.p.g._C40/50 230 mm
Type - Pset_ElementShading - Roughness: 304.8 mm
Type - Pset_ProductRequirements - Category: Walls
Type - Pset_ReinforcementBarPitchOfWall - Description: betonwand d=230
Type - Pset_WallCommon - IsExternal: no
Type - Pset_Pieters - Dikte: 230 mm; Naamgeving element: 28_PBT_WA_beton t.p.g._d=230_C40/50; Codering - NL-SfB: 28.21; Omschrijving NL-SfB: hoofddraagconstructies - wanden en vloeren, wand-/vloerconstructies; Materiaal: 00_PBT_MAT_beton t.p.g._C40/50; Materiaalkwaliteit: C40/50; Description: betonwand d=230
Classification: 28.21 hoofddraagconstructies - wanden en vloeren, wand-/vloerconstructies (Uniformat)
Pset_QuantityTakeOff - Reference: Basic Wall:28_PBT_WA_beton t.p.g._d=230_C40/50
Pset_ReinforcementBarPitchOfWall - Reference: Basic Wall:28_PBT_WA_beton t.p.g._d=230_C40/50
Pset_WallCommon - LoadBearing: yes; ExtendToStructure: no; Reference: Basic Wall:28_PBT_WA_beton t.p.g._d=230_C40/50
Pset_Pieters - Dragend/niet dragend: yes; In/uitwendig: no; Bouwlaag: Level: 04 vierde verdieping; Fase: Nieuw

# IfcWall: Basic Wall:28_PBT_WA_beton t.p.g._d=250_C30/37 (6)
Type - PredefinedType: STANDARD; Material: 00_PBT_MAT_beton t.p.g._C30/37 250 mm
Type - Pset_ElementShading - Roughness: 304.8 mm
Type - Pset_ProductRequirements - Category: Walls
Type - Pset_ReinforcementBarPitchOfWall - Description: betonwand d=250
Type - Pset_WallCommon - IsExternal: yes
Type - Pset_Pieters - Dikte: 250 mm; Naamgeving element: 28_PBT_WA_beton t.p.g._d=250_C30/37; Codering - NL-SfB: 28.21; Omschrijving NL-SfB: hoofddraagconstructies - wanden en vloeren, wand-/vloerconstructies; Materiaal: 00_PBT_MAT_beton t.p.g._C30/37; Materiaalkwaliteit: C30/37; Description: betonwand d=250; Type Comments: d=250
Classification: 28.21 hoofddraagconstructies - wanden en vloeren, wand-/vloerconstructies (Uniformat)
Pset_QuantityTakeOff - Reference: Basic Wall:28_PBT_WA_beton t.p.g._d=250_C30/37
Pset_ReinforcementBarPitchOfWall - Reference: Basic Wall:28_PBT_WA_beton t.p.g._d=250_C30/37
Pset_WallCommon - IsExternal: no; LoadBearing: yes; ExtendToStructure: no; Reference: Basic Wall:28_PBT_WA_beton t.p.g._d=250_C30/37
Pset_Pieters - Dragend/niet dragend: yes; In/uitwendig: no; Fase: Nieuw
Name (Basic Wall:28_PBT_WA_beton t.p.g._d=250_C30/37:...) | In | Bouwlaag
2203250 | 05 vijfde verdieping | Level: 05 vijfde verdieping
2676521 | -1 kelder | Level: -1 kelder
2676781 | -1 kelder | Level: -1 kelder
3861288 | 00 begane grond | Level: 00 begane grond
3861455 | 01 eerste verdieping | Level: 01 eerste verdieping
3862266 | 02 tweede verdieping | Level: 02 tweede verdieping

# IfcWall: Basic Wall:28_PBT_WA_beton t.p.g._d=2650_C40/50, Basic Wall:28_PBT_WA_beton t.p.g._d=2650_C40/50:2906974
In: -1 kelder
Type - PredefinedType: STANDARD; Material: 00_PBT_MAT_beton t.p.g._C40/50 2650 mm
Type - Pset_ElementShading - Roughness: 304.8 mm
Type - Pset_ProductRequirements - Category: Walls
Type - Pset_ReinforcementBarPitchOfWall - Description: poer
Type - Pset_WallCommon - IsExternal: no
Type - Pset_Pieters - Dikte: 2650 mm; Naamgeving element: 28_PBT_WA_beton t.p.g._d=2650_C40/50; Codering - NL-SfB: 28.21; Omschrijving NL-SfB: hoofddraagconstructies - wanden en vloeren, wand-/vloerconstructies; Materiaal: 00_PBT_MAT_beton t.p.g._C40/50; Materiaalkwaliteit: C40/50; Description: poer
Classification: 28.21 hoofddraagconstructies - wanden en vloeren, wand-/vloerconstructies (Uniformat)
Pset_QuantityTakeOff - Reference: Basic Wall:28_PBT_WA_beton t.p.g._d=2650_C40/50
Pset_ReinforcementBarPitchOfWall - Reference: Basic Wall:28_PBT_WA_beton t.p.g._d=2650_C40/50
Pset_WallCommon - LoadBearing: yes; ExtendToStructure: yes; Reference: Basic Wall:28_PBT_WA_beton t.p.g._d=2650_C40/50
Pset_Pieters - Dragend/niet dragend: yes; In/uitwendig: no; Bouwlaag: Level: -1 kelder; Fase: Nieuw

# IfcWall: Basic Wall:28_PBT_WA_beton t.p.g._d=300_C30/37 (9)
Type - PredefinedType: STANDARD; Material: 00_PBT_MAT_beton t.p.g._C30/37 300 mm
Type - Pset_ElementShading - Roughness: 304.8 mm
Type - Pset_ProductRequirements - Category: Walls
Type - Pset_ReinforcementBarPitchOfWall - Description: betonwand d=300
Type - Pset_WallCommon - IsExternal: yes
Type - Pset_Pieters - Dikte: 300 mm; Naamgeving element: 28_PBT_WA_beton t.p.g._d=300_C30/37; Codering - NL-SfB: 28.21; Omschrijving NL-SfB: hoofddraagconstructies - wanden en vloeren, wand-/vloerconstructies; Materiaal: 00_PBT_MAT_beton t.p.g._C30/37; Materiaalkwaliteit: C30/37; Description: betonwand d=300; Type Comments: d=300
Classification: 28.21 hoofddraagconstructies - wanden en vloeren, wand-/vloerconstructies (Uniformat)
Pset_QuantityTakeOff - Reference: Basic Wall:28_PBT_WA_beton t.p.g._d=300_C30/37
Pset_ReinforcementBarPitchOfWall - Reference: Basic Wall:28_PBT_WA_beton t.p.g._d=300_C30/37
Pset_WallCommon - LoadBearing: yes; Reference: Basic Wall:28_PBT_WA_beton t.p.g._d=300_C30/37
Pset_Pieters - Fase: Nieuw
Name (Basic Wall:28_PBT_WA_beton t.p.g._d=300_C30/37:...) | In | IsExternal = In/uitwendig | ExtendToStructure | Dragend/niet dragend | Bouwlaag
1984584 | -1 kelder | no | no | yes | Level: -1 kelder
2002899 | 00 begane grond | no | yes | yes | Level: 00 begane grond
2003071 | 00 begane grond | no | no | yes | Level: 00 begane grond
2031699 | 02 tweede verdieping | no | no | yes | Level: 02 tweede verdieping
2145646 | 01 eerste verdieping | no | yes | yes | Level: 01 eerste verdieping
2211265 | 03 derde verdieping | no | no | yes | Level: 03 derde verdieping
2228405 | -1 kelder |  | no |  | Level: -1 kelder
4456899 | -1 kelder |  | no |  | Level: -1 kelder
5422355 | 04 vierde verdieping | no | no | yes | Level: 04 vierde verdieping | Pset_Pieters - Comments: bestaand wanddeel slopen met behoud van wapening en opnieuw aanstorten

# IfcWall: Basic Wall:28_PBT_WA_beton t.p.g._d=300_bestaand (22)
Type - PredefinedType: STANDARD; Material: 00_PBT_MAT_beton t.p.g. 300 mm
Type - Pset_ElementShading - Roughness: 304.8 mm
Type - Pset_ProductRequirements - Category: Walls
Type - Pset_ReinforcementBarPitchOfWall - Description: betonwand d=300
Type - Pset_WallCommon - IsExternal: no
Type - Pset_Pieters - Dikte: 300 mm; Naamgeving element: 28_PBT_WA_beton t.p.g._d=300_bestaand; Codering - NL-SfB: 28.21; Omschrijving NL-SfB: hoofddraagconstructies - wanden en vloeren, wand-/vloerconstructies; Materiaal: 00_PBT_MAT_beton t.p.g.; Description: betonwand d=300
Classification: 28.21 hoofddraagconstructies - wanden en vloeren, wand-/vloerconstructies (Uniformat)
Pset_QuantityTakeOff - Reference: Basic Wall:28_PBT_WA_beton t.p.g._d=300_bestaand
Pset_ReinforcementBarPitchOfWall - Reference: Basic Wall:28_PBT_WA_beton t.p.g._d=300_bestaand
Pset_WallCommon - LoadBearing: yes; ExtendToStructure: no; Reference: Basic Wall:28_PBT_WA_beton t.p.g._d=300_bestaand
Pset_Pieters - Fase: Bestaand
Name (Basic Wall:28_PBT_WA_beton t.p.g._d=300_bestaand:...) | In | Dragend/niet dragend | In/uitwendig | Bouwlaag
1358755 | -1 kelder | yes | no | Level: -1 kelder_Offset1000
1471749 | 02 tweede verdieping | yes | no | Level: 02 tweede verdieping_Offset1000
1471952 | 02 tweede verdieping | yes | no | Level: 02 tweede verdieping_Offset1000
1472513 | 02 tweede verdieping | yes | no | Level: 02 tweede verdieping_Offset1000
1472515 | 02 tweede verdieping | yes | no | Level: 02 tweede verdieping_Offset1000
1482826 | 00 begane grond | yes | no | Level: 00 begane grond_Offset1000
1484215 | 00 begane grond | yes | no | Level: 00 begane grond_Offset1000
1485875 | 00 begane grond | yes | no | Level: 00 begane grond_Offset1000
1570018 | 00 begane grond | yes | no | Level: 00 begane grond_Offset1000
1570837 | 00 begane grond | yes | no | Level: 00 begane grond_Offset1000
1570942 | 00 begane grond | yes | no | Level: 00 begane grond_Offset1000
1676711 | 03 derde verdieping | yes | no | Level: 03 derde verdieping_Offset1000
1745456 | 02 tweede verdieping | yes | no | Level: 02 tweede verdieping_Offset1000
1764606 | 03 derde verdieping | yes | no | Level: 03 derde verdieping_Offset1000
1767873 | 03 derde verdieping | yes | no | Level: 03 derde verdieping_Offset1000
1802119 | 03 derde verdieping | yes | no | Level: 03 derde verdieping_Offset1000
1802122 | 03 derde verdieping | yes | no | Level: 03 derde verdieping_Offset1000
1802124 | 03 derde verdieping | yes | no | Level: 03 derde verdieping_Offset1000
1955083 | 01 eerste verdieping | yes | no | Level: 01 eerste verdieping_Offset1000
1955809 | 01 eerste verdieping | yes | no | Level: 01 eerste verdieping_Offset1000
2236568 | 00 begane grond |  |  | Level: 00 begane grond_Offset1000
2237699 | 00 begane grond |  |  | Level: 00 begane grond_Offset1000

# IfcWall: Basic Wall:28_PBT_WA_beton t.p.g._d=320_C30/37, Basic Wall:28_PBT_WA_beton t.p.g._d=320_C30/37:3050173
In: -1 kelder
Type - PredefinedType: STANDARD; Material: 00_PBT_MAT_beton t.p.g._C30/37 320 mm
Type - Pset_ElementShading - Roughness: 304.8 mm
Type - Pset_ProductRequirements - Category: Walls
Type - Pset_ReinforcementBarPitchOfWall - Description: betonwand d=320
Type - Pset_WallCommon - IsExternal: no
Type - Pset_Pieters - Dikte: 320 mm; Naamgeving element: 28_PBT_WA_beton t.p.g._d=320_C30/37; Codering - NL-SfB: 28.21; Omschrijving NL-SfB: hoofddraagconstructies - wanden en vloeren, wand-/vloerconstructies; Materiaal: 00_PBT_MAT_beton t.p.g._C30/37; Materiaalkwaliteit: C30/37; Description: betonwand d=320; Type Comments: d=320
Classification: 28.21 hoofddraagconstructies - wanden en vloeren, wand-/vloerconstructies (Uniformat)
Pset_QuantityTakeOff - Reference: Basic Wall:28_PBT_WA_beton t.p.g._d=320_C30/37
Pset_ReinforcementBarPitchOfWall - Reference: Basic Wall:28_PBT_WA_beton t.p.g._d=320_C30/37
Pset_WallCommon - LoadBearing: yes; ExtendToStructure: no; Reference: Basic Wall:28_PBT_WA_beton t.p.g._d=320_C30/37
Pset_Pieters - Dragend/niet dragend: yes; In/uitwendig: no; Bouwlaag: Level: -1 kelder; Fase: Nieuw

# IfcWall: Basic Wall:28_PBT_WA_beton t.p.g._d=350_C30/37 (5)
Type - PredefinedType: STANDARD; Material: 00_PBT_MAT_beton t.p.g._C30/37 350 mm
Type - Pset_ElementShading - Roughness: 304.8 mm
Type - Pset_ProductRequirements - Category: Walls
Type - Pset_ReinforcementBarPitchOfWall - Description: betonwand d=350
Type - Pset_WallCommon - IsExternal: no
Type - Pset_Pieters - Dikte: 350 mm; Naamgeving element: 28_PBT_WA_beton t.p.g._d=350_C30/37; Codering - NL-SfB: 28.21; Omschrijving NL-SfB: hoofddraagconstructies - wanden en vloeren, wand-/vloerconstructies; Materiaal: 00_PBT_MAT_beton t.p.g._C30/37; Materiaalkwaliteit: C30/37; Description: betonwand d=350; Type Comments: d=350
Classification: 28.21 hoofddraagconstructies - wanden en vloeren, wand-/vloerconstructies (Uniformat)
Pset_QuantityTakeOff - Reference: Basic Wall:28_PBT_WA_beton t.p.g._d=350_C30/37
Pset_ReinforcementBarPitchOfWall - Reference: Basic Wall:28_PBT_WA_beton t.p.g._d=350_C30/37
Pset_WallCommon - LoadBearing: yes; Reference: Basic Wall:28_PBT_WA_beton t.p.g._d=350_C30/37
Pset_Pieters - Dragend/niet dragend: yes; Fase: Nieuw
Name (Basic Wall:28_PBT_WA_beton t.p.g._d=350_C30/37:...) | In | IsExternal | ExtendToStructure | In/uitwendig | Bouwlaag
2102048 | 01 eerste verdieping | yes | no | yes | Level: 01 eerste verdieping
2103335 | 02 tweede verdieping | yes | no | yes | Level: 02 tweede verdieping
2155534 | 03 derde verdieping |  | no | no | Level: 03 derde verdieping
2203246 | 05 vijfde verdieping | yes | yes | yes | Level: 05 vijfde verdieping
2204518 | 05 vijfde verdieping |  | no | no | Level: 05 vijfde verdieping

# IfcWall: Basic Wall:28_PBT_WA_beton t.p.g._d=350_C53/65, Basic Wall:28_PBT_WA_beton t.p.g._d=350_C53/65:2091888
In: 00 begane grond
Type - PredefinedType: STANDARD; Material: 00_PBT_MAT_beton t.p.g._C53/65 350 mm
Type - Pset_ElementShading - Roughness: 304.8 mm
Type - Pset_ProductRequirements - Category: Walls
Type - Pset_ReinforcementBarPitchOfWall - Description: betonwand d=350 C53/65
Type - Pset_WallCommon - IsExternal: no
Type - Pset_Pieters - Dikte: 350 mm; Naamgeving element: 28_PBT_WA_beton t.p.g._d=350_C53/65; Codering - NL-SfB: 28.21; Omschrijving NL-SfB: hoofddraagconstructies - wanden en vloeren, wand-/vloerconstructies; Materiaal: 00_PBT_MAT_beton t.p.g._C53/65; Materiaalkwaliteit: C53/65; Description: betonwand d=350 C53/65; Type Comments: d=350
Classification: 28.21 hoofddraagconstructies - wanden en vloeren, wand-/vloerconstructies (Uniformat)
Pset_QuantityTakeOff - Reference: Basic Wall:28_PBT_WA_beton t.p.g._d=350_C53/65
Pset_ReinforcementBarPitchOfWall - Reference: Basic Wall:28_PBT_WA_beton t.p.g._d=350_C53/65
Pset_WallCommon - LoadBearing: yes; ExtendToStructure: no; Reference: Basic Wall:28_PBT_WA_beton t.p.g._d=350_C53/65
Pset_Pieters - Dragend/niet dragend: yes; In/uitwendig: no; Bouwlaag: Level: 00 begane grond; Fase: Nieuw

# IfcWall: Basic Wall:28_PBT_WA_beton t.p.g._d=400_C30/37 (2)
In: 06 zesde verdieping
Type - PredefinedType: STANDARD; Material: 00_PBT_MAT_beton t.p.g._C30/37 400 mm
Type - Pset_ElementShading - Roughness: 304.8 mm
Type - Pset_ProductRequirements - Category: Walls
Type - Pset_ReinforcementBarPitchOfWall - Description: betonwand d=400
Type - Pset_WallCommon - IsExternal: no
Type - Pset_Pieters - Dikte: 400 mm; Naamgeving element: 28_PBT_WA_beton t.p.g._d=400_C30/37; Codering - NL-SfB: 28.21; Omschrijving NL-SfB: hoofddraagconstructies - wanden en vloeren, wand-/vloerconstructies; Materiaal: 00_PBT_MAT_beton t.p.g._C30/37; Materiaalkwaliteit: C30/37; Description: betonwand d=400
Classification: 28.21 hoofddraagconstructies - wanden en vloeren, wand-/vloerconstructies (Uniformat)
Pset_QuantityTakeOff - Reference: Basic Wall:28_PBT_WA_beton t.p.g._d=400_C30/37
Pset_ReinforcementBarPitchOfWall - Reference: Basic Wall:28_PBT_WA_beton t.p.g._d=400_C30/37
Pset_WallCommon - LoadBearing: yes; ExtendToStructure: no; Reference: Basic Wall:28_PBT_WA_beton t.p.g._d=400_C30/37
Pset_Pieters - Dragend/niet dragend: yes; In/uitwendig: no; Bouwlaag: Level: 06 zesde verdieping; Fase: Nieuw
Name (Basic Wall:28_PBT_WA_beton t.p.g._d=400_C30/37:...)
2599775
2602552

# IfcWall: Basic Wall:28_PBT_WA_beton t.p.g._d=400_bestaand (4)
In: 02 tweede verdieping
Type - PredefinedType: STANDARD; Material: 00_PBT_MAT_beton t.p.g. 400 mm
Type - Pset_ElementShading - Roughness: 304.8 mm
Type - Pset_ProductRequirements - Category: Walls
Type - Pset_ReinforcementBarPitchOfWall - Description: betonwand d=400
Type - Pset_WallCommon - IsExternal: no
Type - Pset_Pieters - Dikte: 400 mm; Naamgeving element: 28_PBT_WA_beton t.p.g._d=400_bestaand; Codering - NL-SfB: 28.21; Omschrijving NL-SfB: hoofddraagconstructies - wanden en vloeren, wand-/vloerconstructies; Materiaal: 00_PBT_MAT_beton t.p.g.; Description: betonwand d=400
Classification: 28.21 hoofddraagconstructies - wanden en vloeren, wand-/vloerconstructies (Uniformat)
Pset_QuantityTakeOff - Reference: Basic Wall:28_PBT_WA_beton t.p.g._d=400_bestaand
Pset_ReinforcementBarPitchOfWall - Reference: Basic Wall:28_PBT_WA_beton t.p.g._d=400_bestaand
Pset_WallCommon - LoadBearing: yes; ExtendToStructure: no; Reference: Basic Wall:28_PBT_WA_beton t.p.g._d=400_bestaand
Pset_Pieters - Dragend/niet dragend: yes; In/uitwendig: no; Bouwlaag: Level: 02 tweede verdieping_Offset1000; Fase: Bestaand
Name (Basic Wall:28_PBT_WA_beton t.p.g._d=400_bestaand:...)
1472610
1611438
1611535
1611565

# IfcWall: Basic Wall:28_PBT_WA_beton t.p.g._d=500_bestaand, Basic Wall:28_PBT_WA_beton t.p.g._d=500_bestaand:1407163
In: -2 kelder
Type - PredefinedType: STANDARD; Material: 00_PBT_MAT_beton t.p.g. 500 mm
Type - Pset_ElementShading - Roughness: 304.8 mm
Type - Pset_ProductRequirements - Category: Walls
Type - Pset_ReinforcementBarPitchOfWall - Description: betonwand d=500
Type - Pset_WallCommon - IsExternal: no
Type - Pset_Pieters - Dikte: 500 mm; Naamgeving element: 28_PBT_WA_beton t.p.g._d=500_bestaand; Codering - NL-SfB: 28.21; Omschrijving NL-SfB: hoofddraagconstructies - wanden en vloeren, wand-/vloerconstructies; Materiaal: 00_PBT_MAT_beton t.p.g.; Description: betonwand d=500
Classification: 28.21 hoofddraagconstructies - wanden en vloeren, wand-/vloerconstructies (Uniformat)
Pset_QuantityTakeOff - Reference: Basic Wall:28_PBT_WA_beton t.p.g._d=500_bestaand
Pset_ReinforcementBarPitchOfWall - Reference: Basic Wall:28_PBT_WA_beton t.p.g._d=500_bestaand
Pset_WallCommon - LoadBearing: yes; ExtendToStructure: no; Reference: Basic Wall:28_PBT_WA_beton t.p.g._d=500_bestaand
Pset_Pieters - Dragend/niet dragend: yes; In/uitwendig: no; Bouwlaag: Level: -2 kelder_Offset1000; Fase: Bestaand

# IfcWall: Basic Wall:28_PBT_WA_beton t.p.g._d=600_C30/37 (2)
Type - PredefinedType: STANDARD; Material: 00_PBT_MAT_beton t.p.g._C30/37 600 mm
Type - Pset_ElementShading - Roughness: 304.8 mm
Type - Pset_ProductRequirements - Category: Walls
Type - Pset_ReinforcementBarPitchOfWall - Description: betonwand d=600
Type - Pset_WallCommon - IsExternal: no
Type - Pset_Pieters - Dikte: 600 mm; Naamgeving element: 28_PBT_WA_beton t.p.g._d=600_C30/37; Codering - NL-SfB: 28.21; Omschrijving NL-SfB: hoofddraagconstructies - wanden en vloeren, wand-/vloerconstructies; Materiaal: 00_PBT_MAT_beton t.p.g._C30/37; Materiaalkwaliteit: C30/37; Description: betonwand d=600; Type Comments: d=600
Classification: 28.21 hoofddraagconstructies - wanden en vloeren, wand-/vloerconstructies (Uniformat)
Pset_QuantityTakeOff - Reference: Basic Wall:28_PBT_WA_beton t.p.g._d=600_C30/37
Pset_ReinforcementBarPitchOfWall - Reference: Basic Wall:28_PBT_WA_beton t.p.g._d=600_C30/37
Pset_WallCommon - LoadBearing: yes; Reference: Basic Wall:28_PBT_WA_beton t.p.g._d=600_C30/37
Pset_Pieters - Fase: Nieuw
Name (Basic Wall:28_PBT_WA_beton t.p.g._d=600_C30/37:...) | In | ExtendToStructure | Bouwlaag
2006640 | 00 begane grond | no | Level: 00 begane grond | Pset_Pieters - Dragend/niet dragend: yes; In/uitwendig: no
2391430 | 01 eerste verdieping | yes | Level: 01 eerste verdieping

# IfcWall: Basic Wall:28_PBT_WA_beton t.p.g._d=65_C30/37, Basic Wall:28_PBT_WA_beton t.p.g._d=65_C30/37:3178956
In: -1 kelder
Type - PredefinedType: STANDARD; Material: 00_PBT_MAT_beton t.p.g._C30/37 65 mm
Type - Pset_ElementShading - Roughness: 304.8 mm
Type - Pset_ProductRequirements - Category: Walls
Type - Pset_ReinforcementBarPitchOfWall - Description: betonnen opdikking d=65
Type - Pset_WallCommon - IsExternal: no
Type - Pset_Pieters - Dikte: 65 mm; Naamgeving element: 28_PBT_WA_beton t.p.g._d=65_C30/37; Codering - NL-SfB: 28.21; Omschrijving NL-SfB: hoofddraagconstructies - wanden en vloeren, wand-/vloerconstructies; Materiaal: 00_PBT_MAT_beton t.p.g._C30/37; Materiaalkwaliteit: C30/37; Description: betonnen opdikking d=65; Type Comments: d=65
Classification: 28.21 hoofddraagconstructies - wanden en vloeren, wand-/vloerconstructies (Uniformat)
Pset_QuantityTakeOff - Reference: Basic Wall:28_PBT_WA_beton t.p.g._d=65_C30/37
Pset_ReinforcementBarPitchOfWall - Reference: Basic Wall:28_PBT_WA_beton t.p.g._d=65_C30/37
Pset_WallCommon - LoadBearing: yes; IsExternal: yes; ExtendToStructure: no; Reference: Basic Wall:28_PBT_WA_beton t.p.g._d=65_C30/37
Pset_Pieters - Dragend/niet dragend: yes; In/uitwendig: yes; Bouwlaag: Level: -1 kelder_Offset1000; Fase: Nieuw

# IfcWall: Basic Wall:28_PBT_WA_beton t.p.g._d=700_C30/37 (5)
In: 02 tweede verdieping
Type - PredefinedType: STANDARD; Material: 00_PBT_MAT_beton t.p.g._C30/37 700 mm
Type - Pset_ElementShading - Roughness: 304.8 mm
Type - Pset_ProductRequirements - Category: Walls
Type - Pset_ReinforcementBarPitchOfWall - Description: betonwand d=700
Type - Pset_WallCommon - IsExternal: no
Type - Pset_Pieters - Dikte: 700 mm; Naamgeving element: 28_PBT_WA_beton t.p.g._d=700_C30/37; Codering - NL-SfB: 28.21; Omschrijving NL-SfB: hoofddraagconstructies - wanden en vloeren, wand-/vloerconstructies; Materiaal: 00_PBT_MAT_beton t.p.g._C30/37; Materiaalkwaliteit: C30/37; Description: betonwand d=700
Classification: 28.21 hoofddraagconstructies - wanden en vloeren, wand-/vloerconstructies (Uniformat)
Pset_QuantityTakeOff - Reference: Basic Wall:28_PBT_WA_beton t.p.g._d=700_C30/37
Pset_ReinforcementBarPitchOfWall - Reference: Basic Wall:28_PBT_WA_beton t.p.g._d=700_C30/37
Pset_WallCommon - LoadBearing: yes; ExtendToStructure: no; Reference: Basic Wall:28_PBT_WA_beton t.p.g._d=700_C30/37
Pset_Pieters - Dragend/niet dragend: yes; In/uitwendig: no; Bouwlaag: Level: 02 tweede verdieping; Fase: Nieuw
Name (Basic Wall:28_PBT_WA_beton t.p.g._d=700_C30/37:...)
2326149
2326648
2326992
2327575
5403354

# IfcWallStandardCase: Basic Wall:16_PBT_WA_beton t.p.g._d=250_C30/37 (17)
Type - PredefinedType: STANDARD; Material: 00_PBT_MAT_beton t.p.g._C30/37 250 mm
Type - Pset_ElementShading - Roughness: 304.8 mm
Type - Pset_ProductRequirements - Category: Walls
Type - Pset_ReinforcementBarPitchOfWall - Description: betonwand d=250
Type - Pset_WallCommon - IsExternal: yes
Type - Pset_Pieters - Dikte: 250 mm; Naamgeving element: 16_PBT_WA_beton t.p.g._d=250_C30/37; Codering - NL-SfB: 16.20; Omschrijving NL-SfB: funderingsconstructies - keerwanden, algemeen (verzamelniveau); Materiaal: 00_PBT_MAT_beton t.p.g._C30/37; Materiaalkwaliteit: C30/37; Description: betonwand d=250; Type Comments: d=250
Classification: 16.20 funderingsconstructies - keerwanden, algemeen (verzamelniveau) (Uniformat)
BaseQuantities - Width: 250 mm
Pset_QuantityTakeOff - Reference: Basic Wall:16_PBT_WA_beton t.p.g._d=250_C30/37
Pset_ReinforcementBarPitchOfWall - Reference: Basic Wall:16_PBT_WA_beton t.p.g._d=250_C30/37
Pset_WallCommon - LoadBearing: yes; Reference: Basic Wall:16_PBT_WA_beton t.p.g._d=250_C30/37
Pset_Pieters - Dragend/niet dragend: yes; Fase: Nieuw
Name (Basic Wall:16_PBT_WA_beton t.p.g._d=250_C30/37:...) | In | Height (mm) | Length (mm) | GrossFootprintArea (mm2) | GrossVolume (m3) | GrossSideArea (mm2) = NetSideArea (mm2) | NetVolume (m3) | ExtendToStructure | In/uitwendig | Bouwlaag
1992245 | 00 begane grond | 1090 | 5570.67 | 1392668 | 1.35176 | 5407033 | 1.35176 | yes | yes | Level: 00 begane grond
1992390 | 00 begane grond | 1410 | 5070 | 1267500 | 1.78718 | 7148700 | 1.78718 | no | yes | Level: 00 begane grond
1992453 | 00 begane grond | 1410 | 3690 | 922500 | 1.30073 | 5202901 | 1.30073 | no | yes | Level: 00 begane grond
2086591 | -1 kelder | 1170 | 4000 | 1000000 | 1.17 | 4680000 | 1.17 | no | yes | Level: -1 kelder
2087404 | -1 kelder | 1570 | 3899.91 | 974977 | 1.53071 | 6122856 | 1.53071 | no | yes | Level: -1 kelder
2087406 | -1 kelder | 1170 | 3350 | 837500 | 0.979875 | 3919500 | 0.979875 | no | yes | Level: -1 kelder
2089238 | -1 kelder | 3250 | 7100.01 | 1775002 | 5.76876 | 23075027 | 5.76876 | yes | yes | Level: -1 kelder
2089240 | -1 kelder | 3550 | 4860 | 1215000 | 4.20375 | 16815001 | 4.20375 | yes | yes | Level: -1 kelder
2092033 | -1 kelder | 2280 | 3255 | 813750 | 1.85535 | 7421400 | 1.85535 | no | no | Level: -1 kelder | Pset_WallCommon - IsExternal: no
2092035 | -1 kelder | 3250 | 4265.99 | 1066498 | 2.59409 | 10376353 | 2.59409 | no | no | Level: -1 kelder | Pset_WallCommon - IsExternal: no
2683404 | 00 begane grond | 250 | 13160 | 3290000 | 0.60475 | 2419000 | 0.60475 | no | yes | Level: 00 begane grond
2692575 | 00 begane grond | 600 | 12130 | 3032500 | 1.8195 | 7278000 | 1.8195 | no | yes | Level: 00 begane grond
2906661 | -1 kelder | 3250 | 166.426 | 41606.5 | 0.203125 | 812500 | 0.135221 | no | yes | Level: -1 kelder
3148493 | -1 kelder | 1870 | 177.74 | 44434.9 | 0.116875 | 467500 | 0.0830933 | no | yes | Level: -1 kelder_Offset1000
3148816 | -1 kelder | 1870 | 357.037 | 89259.3 | 0.166915 | 667659 | 0.166915 | no | yes | Level: -1 kelder_Offset1000
3712431 | -1 kelder | 1900 | 1914.14 | 478535 | 0.909217 | 3636868 | 0.909217 | no | no | Level: -1 kelder | Pset_WallCommon - IsExternal: no
6146899 | 00 begane grond | 600 | 3150 | 787500 | 0.4725 | 1890000 | 0.4725 | no | no | Level: 00 begane grond | Pset_WallCommon - IsExternal: no

# IfcWallStandardCase: Basic Wall:16_PBT_WA_beton t.p.g._d=250_bestaand (9)
In: -1 kelder
Type - PredefinedType: STANDARD; Material: 00_PBT_MAT_beton t.p.g. 250 mm
Type - Pset_ElementShading - Roughness: 304.8 mm
Type - Pset_ProductRequirements - Category: Walls
Type - Pset_ReinforcementBarPitchOfWall - Description: betonwand d=250
Type - Pset_WallCommon - IsExternal: yes
Type - Pset_Pieters - Dikte: 250 mm; Naamgeving element: 16_PBT_WA_beton t.p.g._d=250_bestaand; Codering - NL-SfB: 16.20; Omschrijving NL-SfB: funderingsconstructies - keerwanden, algemeen (verzamelniveau); Materiaal: 00_PBT_MAT_beton t.p.g.; Description: betonwand d=250
Classification: 16.20 funderingsconstructies - keerwanden, algemeen (verzamelniveau) (Uniformat)
BaseQuantities - Width: 250 mm
Pset_QuantityTakeOff - Reference: Basic Wall:16_PBT_WA_beton t.p.g._d=250_bestaand
Pset_ReinforcementBarPitchOfWall - Reference: Basic Wall:16_PBT_WA_beton t.p.g._d=250_bestaand
Pset_WallCommon - LoadBearing: yes; Reference: Basic Wall:16_PBT_WA_beton t.p.g._d=250_bestaand
Pset_Pieters - Bouwlaag: Level: -1 kelder_Offset1000; Fase: Bestaand
Name (Basic Wall:16_PBT_WA_beton t.p.g._d=250_bestaand:...) | Height (mm) | Length (mm) | GrossFootprintArea (mm2) | GrossVolume (m3) | GrossSideArea (mm2) | NetSideArea (mm2) | NetVolume (m3) | ExtendToStructure | Dragend/niet dragend = In/uitwendig
1319736 | 3220 | 5633.57 | 1408394 | 4.53503 | 18140108 | 18140108 | 4.53503 | no | yes
1332869 | 3510 | 2935 | 733750 | 2.56609 | 10264350 | 10264350 | 2.56609 | yes | yes
1333127 | 3290 | 4580 | 1145000 | 2.71545 | 10861789 | 10734040 | 2.68351 | no | yes
1356095 | 2100 | 2010 | 502500 | 0.609587 | 2438349 | 2438349 | 0.609587 | no | yes
1356370 | 2100 | 12445 | 3111250 | 6.01403 | 24056111 | 24056111 | 6.01403 | no | yes
1356825 | 2540 | 13160 | 3290000 | 8.3566 | 33426400 | 33426400 | 8.3566 | no | yes
1373398 | 2980 | 460 | 115000 | 0.3427 | 1370800 | 1370800 | 0.3427 | no | yes
1378028 | 2930 | 28325 | 7081250 | 19.4435 | 77774032 | 77774032 | 19.4435 | no | yes
3883642 | 2450 | 11625 | 2906250 | 7.12031 | 28481250 | 28113208 | 7.0283 | no

# IfcWallStandardCase: Basic Wall:16_PBT_WA_beton t.p.g._d=300_C30/37 (7)
Type - PredefinedType: STANDARD; Material: 00_PBT_MAT_beton t.p.g._C30/37 300 mm
Type - Pset_ElementShading - Roughness: 304.8 mm
Type - Pset_ProductRequirements - Category: Walls
Type - Pset_ReinforcementBarPitchOfWall - Description: betonwand d=300
Type - Pset_WallCommon - IsExternal: yes
Type - Pset_Pieters - Dikte: 300 mm; Naamgeving element: 16_PBT_WA_beton t.p.g._d=300_C30/37; Codering - NL-SfB: 16.20; Omschrijving NL-SfB: funderingsconstructies - keerwanden, algemeen (verzamelniveau); Materiaal: 00_PBT_MAT_beton t.p.g._C30/37; Materiaalkwaliteit: C30/37; Description: betonwand d=300; Type Comments: d=300
Classification: 16.20 funderingsconstructies - keerwanden, algemeen (verzamelniveau) (Uniformat)
BaseQuantities - Width: 300 mm
Pset_QuantityTakeOff - Reference: Basic Wall:16_PBT_WA_beton t.p.g._d=300_C30/37
Pset_ReinforcementBarPitchOfWall - Reference: Basic Wall:16_PBT_WA_beton t.p.g._d=300_C30/37
Pset_WallCommon - LoadBearing: yes; ExtendToStructure: no; Reference: Basic Wall:16_PBT_WA_beton t.p.g._d=300_C30/37
Pset_Pieters - Dragend/niet dragend: yes; Fase: Nieuw
Name (Basic Wall:16_PBT_WA_beton t.p.g._d=300_C30/37:...) | In | Height (mm) | Length (mm) | GrossFootprintArea (mm2) | GrossVolume (m3) | GrossSideArea (mm2) = NetSideArea (mm2) | NetVolume (m3) | IsExternal | In/uitwendig | Bouwlaag
2134612 | -1 kelder | 500 | 2567.56 | 770269 | 0.385135 | 1283782 | 0.385135 | no | no | Level: -1 kelder
2244508 | -1 kelder | 500 | 2530 | 759000 | 0.36105 | 1203500 | 0.36105 |  | yes | Level: -1 kelder_Offset1000
2265049 | -1 kelder | 1160 | 3820 | 1146000 | 1.32936 | 4431200 | 1.32936 | no | no | Level: -1 kelder
3130671 | -1 kelder | 2100 | 1000 | 300000 | 0.63 | 2100000 | 0.63 |  | yes | Level: -1 kelder_Offset1000
3406322 | -1 kelder | 500 | 2144.2 | 643261 | 0.321631 | 1072102 | 0.321631 | no | no | Level: -1 kelder
3871738 | -1 kelder | 3250 | 4250 | 1275000 | 4.11495 | 13716500 | 4.11495 | no | no | Level: -1 kelder
4425714 | 00 begane grond | 383 | 234.999 | 70499.6 | 0.03447 | 114900 | 0.0270013 | no | no | Level: 00 begane grond

# IfcWallStandardCase: Basic Wall:16_PBT_WA_beton t.p.g._d=300_bestaand (9)
Type - PredefinedType: STANDARD; Material: 00_PBT_MAT_beton t.p.g. 300 mm
Type - Pset_ElementShading - Roughness: 304.8 mm
Type - Pset_ProductRequirements - Category: Walls
Type - Pset_ReinforcementBarPitchOfWall - Description: betonwand d=300
Type - Pset_WallCommon - IsExternal: yes
Type - Pset_Pieters - Dikte: 300 mm; Naamgeving element: 16_PBT_WA_beton t.p.g._d=300_bestaand; Codering - NL-SfB: 16.20; Omschrijving NL-SfB: funderingsconstructies - keerwanden, algemeen (verzamelniveau); Materiaal: 00_PBT_MAT_beton t.p.g.; Description: betonwand d=300
Classification: 16.20 funderingsconstructies - keerwanden, algemeen (verzamelniveau) (Uniformat)
BaseQuantities - Width: 300 mm
Pset_QuantityTakeOff - Reference: Basic Wall:16_PBT_WA_beton t.p.g._d=300_bestaand
Pset_ReinforcementBarPitchOfWall - Reference: Basic Wall:16_PBT_WA_beton t.p.g._d=300_bestaand
Pset_WallCommon - LoadBearing: yes; ExtendToStructure: no; Reference: Basic Wall:16_PBT_WA_beton t.p.g._d=300_bestaand
Pset_Pieters - Fase: Bestaand
Name (Basic Wall:16_PBT_WA_beton t.p.g._d=300_bestaand:...) | In | Height (mm) | Length (mm) | GrossFootprintArea (mm2) | GrossVolume (m3) | GrossSideArea (mm2) | NetSideArea (mm2) | NetVolume (m3) | Dragend/niet dragend = In/uitwendig | Bouwlaag
1331287 | -1 kelder | 2980 | 7915.58 | 2366859 | 7.05324 | 23510803 | 23510803 | 7.05324 | yes | Level: -1 kelder_Offset1000
1356707 | -1 kelder | 2790 | 2750 | 825000 | 2.26815 | 7560500 | 7560500 | 2.26815 | yes | Level: -1 kelder_Offset1000
1377677 | -1 kelder | 2930 | 5030 | 1509000 | 4.20042 | 14001401 | 14001401 | 4.20042 | yes | Level: -1 kelder_Offset1000
1378266 | -1 kelder | 2650 | 19435 | 5830500 | 15.4508 | 51502750 | 51502750 | 15.043 | yes | Level: -1 kelder_Offset1000 | Pset_Pieters - Comments: bestaande betonwand d=var.
1388345 | -1 kelder | 2650 | 3275 | 982500 | 2.60363 | 8678750 | 8678750 | 2.60363 | yes | Level: -1 kelder_Offset1000
1407073 | -2 kelder | 2220 | 4265 | 1279500 | 2.78049 | 9268300 | 9268300 | 2.78049 | yes | Level: -2 kelder_Offset1000
2916309 | -1 kelder | 3220 | 10260 | 3078000 | 6.98805 | 23293484 | 22923484 | 6.87705 |  | Level: -1 kelder_Offset1000
3060762 | -1 kelder | 2650 | 4580 | 1374000 | 3.52245 | 11741500 | 11741500 | 3.52245 |  | Level: -1 kelder_Offset1000
3065088 | -1 kelder | 2650 | 5785 | 1735500 | 4.56609 | 15220311 | 15220311 | 4.56609 | yes | Level: -1 kelder_Offset1000

# IfcWallStandardCase: Basic Wall:16_PBT_WA_beton t.p.g._d=320_C30/37 (2)
In: 00 begane grond
Type - PredefinedType: STANDARD; Material: 00_PBT_MAT_beton t.p.g._C30/37 320 mm
Type - Pset_ElementShading - Roughness: 304.8 mm
Type - Pset_ProductRequirements - Category: Walls
Type - Pset_ReinforcementBarPitchOfWall - Description: betonwand d=320
Type - Pset_WallCommon - IsExternal: yes
Type - Pset_Pieters - Dikte: 320 mm; Naamgeving element: 16_PBT_WA_beton t.p.g._d=320_C30/37; Codering - NL-SfB: 16.20; Omschrijving NL-SfB: funderingsconstructies - keerwanden, algemeen (verzamelniveau); Materiaal: 00_PBT_MAT_beton t.p.g._C30/37; Materiaalkwaliteit: C30/37; Description: betonwand d=320
Classification: 16.20 funderingsconstructies - keerwanden, algemeen (verzamelniveau) (Uniformat)
BaseQuantities - Width: 320 mm
Pset_QuantityTakeOff - Reference: Basic Wall:16_PBT_WA_beton t.p.g._d=320_C30/37
Pset_ReinforcementBarPitchOfWall - Reference: Basic Wall:16_PBT_WA_beton t.p.g._d=320_C30/37
Pset_WallCommon - LoadBearing: yes; ExtendToStructure: no; Reference: Basic Wall:16_PBT_WA_beton t.p.g._d=320_C30/37
Pset_Pieters - Dragend/niet dragend: yes; In/uitwendig: yes; Fase: Nieuw
Name (Basic Wall:16_PBT_WA_beton t.p.g._d=320_C30/37:...) | Height (mm) | Length (mm) | GrossFootprintArea (mm2) | GrossVolume (m3) = NetVolume (m3) | GrossSideArea (mm2) = NetSideArea (mm2) | Bouwlaag
2675493 | 970 | 9831.74 | 3146158 | 2.67929 | 8372792 | Level: 00 begane grond
3784479 | 60 | 32065 | 10260800 | 0.615648 | 1923900 | Level: 00 bk ruwe vloer bwd zuid

# IfcWallStandardCase: Basic Wall:16_PBT_WA_beton t.p.g._d=320_bestaand, Basic Wall:16_PBT_WA_beton t.p.g._d=320_bestaand:1313558
In: -1 kelder
Type - PredefinedType: STANDARD; Material: 00_PBT_MAT_beton t.p.g. 320 mm
Type - Pset_ElementShading - Roughness: 304.8 mm
Type - Pset_ProductRequirements - Category: Walls
Type - Pset_ReinforcementBarPitchOfWall - Description: betonwand d=320
Type - Pset_WallCommon - IsExternal: yes
Type - Pset_Pieters - Dikte: 320 mm; Naamgeving element: 16_PBT_WA_beton t.p.g._d=320_bestaand; Codering - NL-SfB: 16.20; Omschrijving NL-SfB: funderingsconstructies - keerwanden, algemeen (verzamelniveau); Materiaal: 00_PBT_MAT_beton t.p.g.; Description: betonwand d=320
Classification: 16.20 funderingsconstructies - keerwanden, algemeen (verzamelniveau) (Uniformat)
BaseQuantities - Height: 1840 mm; Length: 32065 mm; Width: 320 mm; GrossFootprintArea: 10260800 mm2; GrossVolume: 18.8799 m3; GrossSideArea: 58999600 mm2; NetSideArea: 58999600 mm2; NetVolume: 18.7189 m3
Pset_QuantityTakeOff - Reference: Basic Wall:16_PBT_WA_beton t.p.g._d=320_bestaand
Pset_ReinforcementBarPitchOfWall - Reference: Basic Wall:16_PBT_WA_beton t.p.g._d=320_bestaand
Pset_WallCommon - LoadBearing: yes; Reference: Basic Wall:16_PBT_WA_beton t.p.g._d=320_bestaand; ExtendToStructure: no
Pset_Pieters - Dragend/niet dragend: yes; In/uitwendig: yes; Bouwlaag: Level: -1 kelder_Offset1000; Fase: Bestaand

# IfcWallStandardCase: Basic Wall:16_PBT_WA_beton t.p.g._d=350_C30/37 (2)
In: -1 kelder
Type - PredefinedType: STANDARD; Material: 00_PBT_MAT_beton t.p.g._C30/37 350 mm
Type - Pset_ElementShading - Roughness: 304.8 mm
Type - Pset_ProductRequirements - Category: Walls
Type - Pset_ReinforcementBarPitchOfWall - Description: betonwand d=350
Type - Pset_WallCommon - IsExternal: yes
Type - Pset_Pieters - Dikte: 350 mm; Naamgeving element: 16_PBT_WA_beton t.p.g._d=350_C30/37; Codering - NL-SfB: 16.20; Omschrijving NL-SfB: funderingsconstructies - keerwanden, algemeen (verzamelniveau); Materiaal: 00_PBT_MAT_beton t.p.g._C30/37; Materiaalkwaliteit: C30/37; Description: betonwand d=350; Type Comments: d=350
Classification: 16.20 funderingsconstructies - keerwanden, algemeen (verzamelniveau) (Uniformat)
BaseQuantities - Width: 350 mm
Pset_QuantityTakeOff - Reference: Basic Wall:16_PBT_WA_beton t.p.g._d=350_C30/37
Pset_ReinforcementBarPitchOfWall - Reference: Basic Wall:16_PBT_WA_beton t.p.g._d=350_C30/37
Pset_WallCommon - LoadBearing: yes; ExtendToStructure: no; Reference: Basic Wall:16_PBT_WA_beton t.p.g._d=350_C30/37
Pset_Pieters - Dragend/niet dragend: yes; In/uitwendig: yes; Bouwlaag: Level: -1 kelder; Fase: Nieuw
Name (Basic Wall:16_PBT_WA_beton t.p.g._d=350_C30/37:...) | Height (mm) | Length (mm) | GrossFootprintArea (mm2) | GrossVolume (m3) = NetVolume (m3) | GrossSideArea (mm2) = NetSideArea (mm2)
2087330 | 1170 | 3019.9 | 1056965 | 1.23665 | 3533283
2905890 | 3250 | 3345 | 1170750 | 3.80494 | 10871250

# IfcWallStandardCase: Basic Wall:16_PBT_WA_beton t.p.g._d=350_C53/65 (2)
Type - PredefinedType: STANDARD; Material: 00_PBT_MAT_beton t.p.g._C53/65 350 mm
Type - Pset_ElementShading - Roughness: 304.8 mm
Type - Pset_ProductRequirements - Category: Walls
Type - Pset_ReinforcementBarPitchOfWall - Description: betonwand d=350 C53/65
Type - Pset_WallCommon - IsExternal: no
Type - Pset_Pieters - Dikte: 350 mm; Naamgeving element: 16_PBT_WA_beton t.p.g._d=350_C53/65; Codering - NL-SfB: 16.20; Omschrijving NL-SfB: funderingsconstructies - keerwanden, algemeen (verzamelniveau); Materiaal: 00_PBT_MAT_beton t.p.g._C53/65; Materiaalkwaliteit: C53/65; Description: betonwand d=350 C53/65; Type Comments: d=350
Classification: 16.20 funderingsconstructies - keerwanden, algemeen (verzamelniveau) (Uniformat)
BaseQuantities - Width: 350 mm
Pset_QuantityTakeOff - Reference: Basic Wall:16_PBT_WA_beton t.p.g._d=350_C53/65
Pset_ReinforcementBarPitchOfWall - Reference: Basic Wall:16_PBT_WA_beton t.p.g._d=350_C53/65
Pset_WallCommon - LoadBearing: yes; ExtendToStructure: no; Reference: Basic Wall:16_PBT_WA_beton t.p.g._d=350_C53/65
Pset_Pieters - Fase: Nieuw
Name (Basic Wall:16_PBT_WA_beton t.p.g._d=350_C53/65:...) | In | Height (mm) | Length (mm) | GrossFootprintArea (mm2) | GrossVolume (m3) | GrossSideArea (mm2) | NetSideArea (mm2) | NetVolume (m3) | Bouwlaag
2133111 | -1 kelder | 1220 | 2567 | 898450 | 1.09611 | 3131740 | 2798740 | 0.979559 | Level: -1 kelder | Pset_Pieters - Dragend/niet dragend: yes; In/uitwendig: no
3883023 | 00 begane grond | 1510 | 4145 | 1450750 | 2.01596 | 5759900 | 5759900 | 2.01596 | Level: 00 begane grond

# IfcWallStandardCase: Basic Wall:16_PBT_WA_beton t.p.g._d=350_bestaand, Basic Wall:16_PBT_WA_beton t.p.g._d=350_bestaand:3072787
In: -1 kelder
Type - PredefinedType: STANDARD; Material: 00_PBT_MAT_beton t.p.g. 350 mm
Type - Pset_ElementShading - Roughness: 304.8 mm
Type - Pset_ProductRequirements - Category: Walls
Type - Pset_ReinforcementBarPitchOfWall - Description: betonwand d=350
Type - Pset_WallCommon - IsExternal: yes
Type - Pset_Pieters - Dikte: 350 mm; Naamgeving element: 16_PBT_WA_beton t.p.g._d=350_bestaand; Codering - NL-SfB: 16.20; Omschrijving NL-SfB: funderingsconstructies - keerwanden, algemeen (verzamelniveau); Materiaal: 00_PBT_MAT_beton t.p.g.; Description: betonwand d=350
Classification: 16.20 funderingsconstructies - keerwanden, algemeen (verzamelniveau) (Uniformat)
BaseQuantities - Height: 1900 mm; Length: 18310 mm; Width: 350 mm; GrossFootprintArea: 6408500 mm2; GrossVolume: 12.0764 m3; GrossSideArea: 34504030 mm2; NetSideArea: 34504030 mm2; NetVolume: 12.0764 m3
Pset_QuantityTakeOff - Reference: Basic Wall:16_PBT_WA_beton t.p.g._d=350_bestaand
Pset_ReinforcementBarPitchOfWall - Reference: Basic Wall:16_PBT_WA_beton t.p.g._d=350_bestaand
Pset_WallCommon - LoadBearing: yes; ExtendToStructure: no; Reference: Basic Wall:16_PBT_WA_beton t.p.g._d=350_bestaand
Pset_Pieters - Bouwlaag: Level: -1 kelder_Offset1000; Fase: Bestaand

# IfcWallStandardCase: Basic Wall:16_PBT_WA_beton t.p.g._d=365_C30/37, Basic Wall:16_PBT_WA_beton t.p.g._d=365_C30/37:2675909
In: 00 begane grond
Type - PredefinedType: STANDARD; Material: 00_PBT_MAT_beton t.p.g._C30/37 365 mm
Type - Pset_ElementShading - Roughness: 304.8 mm
Type - Pset_ProductRequirements - Category: Walls
Type - Pset_ReinforcementBarPitchOfWall - Description: betonwand d=365
Type - Pset_WallCommon - IsExternal: yes
Type - Pset_Pieters - Dikte: 365 mm; Naamgeving element: 16_PBT_WA_beton t.p.g._d=365_C30/37; Codering - NL-SfB: 16.20; Omschrijving NL-SfB: funderingsconstructies - keerwanden, algemeen (verzamelniveau); Materiaal: 00_PBT_MAT_beton t.p.g._C30/37; Materiaalkwaliteit: C30/37; Description: betonwand d=365
Classification: 16.20 funderingsconstructies - keerwanden, algemeen (verzamelniveau) (Uniformat)
BaseQuantities - Height: 970 mm; Length: 1858 mm; Width: 365 mm; GrossFootprintArea: 678170 mm2; GrossVolume: 0.657825 m3; GrossSideArea: 1802260 mm2; NetSideArea: 1802260 mm2; NetVolume: 0.657825 m3
Pset_QuantityTakeOff - Reference: Basic Wall:16_PBT_WA_beton t.p.g._d=365_C30/37
Pset_ReinforcementBarPitchOfWall - Reference: Basic Wall:16_PBT_WA_beton t.p.g._d=365_C30/37
Pset_WallCommon - LoadBearing: yes; ExtendToStructure: no; Reference: Basic Wall:16_PBT_WA_beton t.p.g._d=365_C30/37
Pset_Pieters - Dragend/niet dragend: yes; In/uitwendig: yes; Bouwlaag: Level: 00 begane grond; Fase: Nieuw

# IfcWallStandardCase: Basic Wall:16_PBT_WA_beton t.p.g._d=400_bestaand (4)
In: -2 kelder
Type - PredefinedType: STANDARD; Material: 00_PBT_MAT_beton t.p.g. 400 mm
Type - Pset_ElementShading - Roughness: 304.8 mm
Type - Pset_ProductRequirements - Category: Walls
Type - Pset_ReinforcementBarPitchOfWall - Description: betonwand d=400
Type - Pset_WallCommon - IsExternal: yes
Type - Pset_Pieters - Dikte: 400 mm; Naamgeving element: 16_PBT_WA_beton t.p.g._d=400_bestaand; Codering - NL-SfB: 16.20; Omschrijving NL-SfB: funderingsconstructies - keerwanden, algemeen (verzamelniveau); Materiaal: 00_PBT_MAT_beton t.p.g.; Description: betonwand d=400
Classification: 16.20 funderingsconstructies - keerwanden, algemeen (verzamelniveau) (Uniformat)
BaseQuantities - Width: 400 mm
Pset_QuantityTakeOff - Reference: Basic Wall:16_PBT_WA_beton t.p.g._d=400_bestaand
Pset_ReinforcementBarPitchOfWall - Reference: Basic Wall:16_PBT_WA_beton t.p.g._d=400_bestaand
Pset_WallCommon - LoadBearing: yes; ExtendToStructure: no; Reference: Basic Wall:16_PBT_WA_beton t.p.g._d=400_bestaand
Pset_Pieters - Dragend/niet dragend: yes; In/uitwendig: yes; Bouwlaag: Level: -2 kelder_Offset1000; Fase: Bestaand
Name (Basic Wall:16_PBT_WA_beton t.p.g._d=400_bestaand:...) | Height (mm) | Length (mm) | GrossFootprintArea (mm2) | GrossVolume (m3) = NetVolume (m3) | GrossSideArea (mm2) = NetSideArea (mm2)
1364468 | 2270 | 4490 | 1796000 | 4.07692 | 10192300
1397335 | 60 | 2150 | 860000 | 0.0516 | 129000
1397797 | 60 | 2335 | 934000 | 0.05604 | 140100
1397949 | 60 | 2335 | 934000 | 0.05604 | 140100

# IfcWallStandardCase: Basic Wall:16_PBT_WA_beton t.p.g._d=450_bestaand, Basic Wall:16_PBT_WA_beton t.p.g._d=450_bestaand:1367090
In: -1 kelder
Type - PredefinedType: STANDARD; Material: 00_PBT_MAT_beton t.p.g. 450 mm
Type - Pset_ElementShading - Roughness: 304.8 mm
Type - Pset_ProductRequirements - Category: Walls
Type - Pset_ReinforcementBarPitchOfWall - Description: betonwand d=450
Type - Pset_WallCommon - IsExternal: yes
Type - Pset_Pieters - Dikte: 450 mm; Naamgeving element: 16_PBT_WA_beton t.p.g._d=450_bestaand; Codering - NL-SfB: 16.20; Omschrijving NL-SfB: funderingsconstructies - keerwanden, algemeen (verzamelniveau); Materiaal: 00_PBT_MAT_beton t.p.g.; Description: betonwand d=450
Classification: 16.20 funderingsconstructies - keerwanden, algemeen (verzamelniveau) (Uniformat)
BaseQuantities - Height: 410 mm; Length: 3740 mm; Width: 450 mm; GrossFootprintArea: 1683000 mm2; GrossVolume: 0.69003 m3; GrossSideArea: 1533400 mm2; NetSideArea: 1533400 mm2; NetVolume: 0.69003 m3
Pset_QuantityTakeOff - Reference: Basic Wall:16_PBT_WA_beton t.p.g._d=450_bestaand
Pset_ReinforcementBarPitchOfWall - Reference: Basic Wall:16_PBT_WA_beton t.p.g._d=450_bestaand
Pset_WallCommon - LoadBearing: yes; ExtendToStructure: no; Reference: Basic Wall:16_PBT_WA_beton t.p.g._d=450_bestaand
Pset_Pieters - Dragend/niet dragend: yes; In/uitwendig: yes; Bouwlaag: Level: -1 kelder_Offset1000; Fase: Bestaand

# IfcWallStandardCase: Basic Wall:16_PBT_WA_beton t.p.g._d=478_C30/37, Basic Wall:16_PBT_WA_beton t.p.g._d=478_C30/37:5974662
In: 00 begane grond
Type - PredefinedType: STANDARD; Material: 00_PBT_MAT_beton t.p.g._C30/37 478 mm
Type - Pset_ElementShading - Roughness: 304.8 mm
Type - Pset_ProductRequirements - Category: Walls
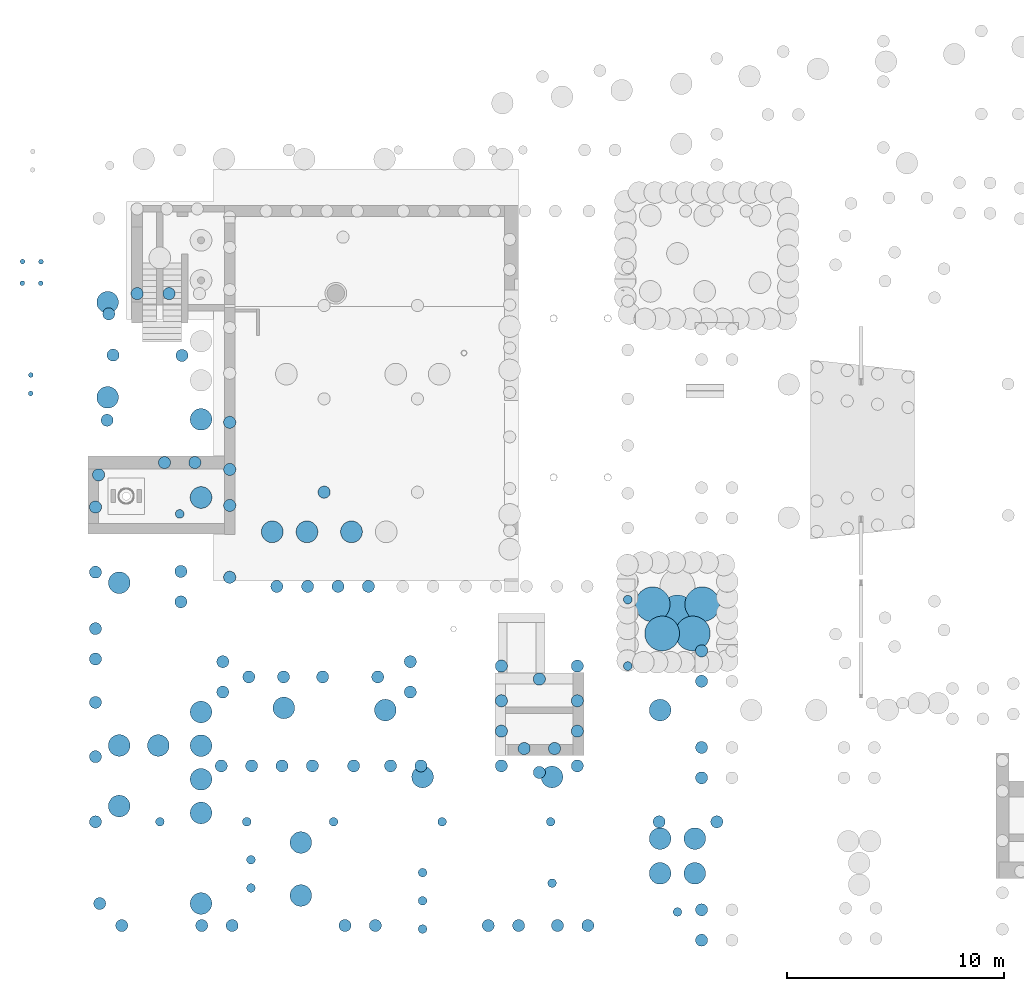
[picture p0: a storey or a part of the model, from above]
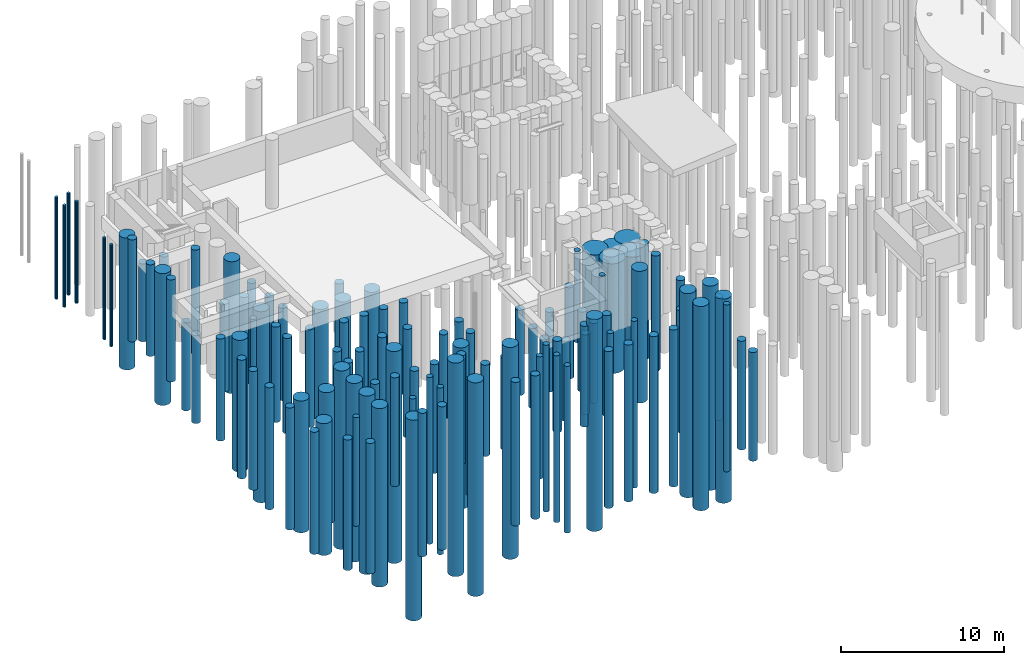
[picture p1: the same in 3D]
Properties of the parts of a building model (IFC2X3), part 17 of 18

# IfcWallStandardCase: Basic Wall:16_PBT_WA_beton t.p.g._d=478_C30/37, Basic Wall:16_PBT_WA_beton t.p.g._d=478_C30/37:5974662
Type - Pset_ReinforcementBarPitchOfWall - Description: betonwand d=478
Type - Pset_WallCommon - IsExternal: yes
Type - Pset_Pieters - Dikte: 478 mm; Naamgeving element: 16_PBT_WA_beton t.p.g._d=478_C30/37; Codering - NL-SfB: 16.20; Omschrijving NL-SfB: funderingsconstructies - keerwanden, algemeen (verzamelniveau); Materiaal: 00_PBT_MAT_beton t.p.g._C30/37; Materiaalkwaliteit: C30/37; Description: betonwand d=478
Classification: 16.20 funderingsconstructies - keerwanden, algemeen (verzamelniveau) (Uniformat)
BaseQuantities - Height: 970 mm; Length: 5632 mm; Width: 478 mm; GrossFootprintArea: 2692096 mm2; GrossVolume: 2.61133 m3; GrossSideArea: 5463040 mm2; NetSideArea: 5463040 mm2; NetVolume: 2.61133 m3
Pset_QuantityTakeOff - Reference: Basic Wall:16_PBT_WA_beton t.p.g._d=478_C30/37
Pset_ReinforcementBarPitchOfWall - Reference: Basic Wall:16_PBT_WA_beton t.p.g._d=478_C30/37
Pset_WallCommon - LoadBearing: yes; ExtendToStructure: no; Reference: Basic Wall:16_PBT_WA_beton t.p.g._d=478_C30/37
Pset_Pieters - Dragend/niet dragend: yes; In/uitwendig: yes; Bouwlaag: Level: 00 begane grond; Fase: Nieuw

# IfcWallStandardCase: Basic Wall:16_PBT_WA_beton t.p.g._d=500_C30/37, Basic Wall:16_PBT_WA_beton t.p.g._d=500_C30/37:4424088
In: 00 begane grond
Type - PredefinedType: STANDARD; Material: 00_PBT_MAT_beton t.p.g._C30/37 500 mm
Type - Pset_ElementShading - Roughness: 304.8 mm
Type - Pset_ProductRequirements - Category: Walls
Type - Pset_ReinforcementBarPitchOfWall - Description: betonwand d=500
Type - Pset_WallCommon - IsExternal: yes
Type - Pset_Pieters - Dikte: 500 mm; Naamgeving element: 16_PBT_WA_beton t.p.g._d=500_C30/37; Codering - NL-SfB: 16.20; Omschrijving NL-SfB: funderingsconstructies - keerwanden, algemeen (verzamelniveau); Materiaal: 00_PBT_MAT_beton t.p.g._C30/37; Materiaalkwaliteit: C30/37; Description: betonwand d=500; Type Comments: d=500
Classification: 16.20 funderingsconstructies - keerwanden, algemeen (verzamelniveau) (Uniformat)
BaseQuantities - Height: 1010 mm; Length: 3950.88 mm; Width: 500 mm; GrossFootprintArea: 1975438 mm2; GrossVolume: 1.99519 m3; GrossSideArea: 3990385 mm2; NetSideArea: 3990385 mm2; NetVolume: 1.86055 m3
Pset_QuantityTakeOff - Reference: Basic Wall:16_PBT_WA_beton t.p.g._d=500_C30/37
Pset_ReinforcementBarPitchOfWall - Reference: Basic Wall:16_PBT_WA_beton t.p.g._d=500_C30/37
Pset_WallCommon - IsExternal: no; LoadBearing: yes; ExtendToStructure: no; Reference: Basic Wall:16_PBT_WA_beton t.p.g._d=500_C30/37
Pset_Pieters - Dragend/niet dragend: yes; In/uitwendig: no; Bouwlaag: Level: 00 begane grond; Fase: Nieuw

# IfcWallStandardCase: Basic Wall:16_PBT_WA_beton t.p.g._d=500_bestaand (14)
Type - PredefinedType: STANDARD; Material: 00_PBT_MAT_beton t.p.g. 500 mm
Type - Pset_ElementShading - Roughness: 304.8 mm
Type - Pset_ProductRequirements - Category: Walls
Type - Pset_ReinforcementBarPitchOfWall - Description: betonwand d=500
Type - Pset_WallCommon - IsExternal: yes
Type - Pset_Pieters - Dikte: 500 mm; Naamgeving element: 16_PBT_WA_beton t.p.g._d=500_bestaand; Codering - NL-SfB: 16.20; Omschrijving NL-SfB: funderingsconstructies - keerwanden, algemeen (verzamelniveau); Materiaal: 00_PBT_MAT_beton t.p.g.; Description: betonwand d=500
Classification: 16.20 funderingsconstructies - keerwanden, algemeen (verzamelniveau) (Uniformat)
BaseQuantities - Width: 500 mm
Pset_QuantityTakeOff - Reference: Basic Wall:16_PBT_WA_beton t.p.g._d=500_bestaand
Pset_ReinforcementBarPitchOfWall - Reference: Basic Wall:16_PBT_WA_beton t.p.g._d=500_bestaand
Pset_WallCommon - LoadBearing: yes; ExtendToStructure: no; Reference: Basic Wall:16_PBT_WA_beton t.p.g._d=500_bestaand
Pset_Pieters - Fase: Bestaand
Name (Basic Wall:16_PBT_WA_beton t.p.g._d=500_bestaand:...) | In | Height (mm) | Length (mm) | GrossFootprintArea (mm2) | GrossVolume (m3) | GrossSideArea (mm2) = NetSideArea (mm2) | NetVolume (m3) | Dragend/niet dragend = In/uitwendig | Bouwlaag
1364737 | -2 kelder | 2270 | 1140 | 570000 | 1.2939 | 2587800 | 1.2939 | yes | Level: -2 kelder_Offset1000
1383953 | -1 kelder | 2930 | 13400 | 6700000 | 19.5058 | 39011585 | 19.5058 | yes | Level: -1 kelder_Offset1000
1390426 | -1 kelder | 600 | 5055 | 2527500 | 1.5165 | 3033000 | 1.5165 | yes | Level: -1 kelder_Offset1000
1390771 | -1 kelder | 600 | 5390 | 2695000 | 1.617 | 3234000 | 1.617 | yes | Level: -1 kelder_Offset1000
1392707 | -1 kelder | 300 | 1840 | 920000 | 0.276 | 552000 | 0.276 | yes | Level: -1 kelder_Offset1000
1394070 | -2 kelder | 1760 | 3825 | 1912500 | 3.366 | 6732000 | 3.366 | yes | Level: -2 kelder_Offset1000
1394272 | -2 kelder | 460 | 3850 | 1925000 | 0.8855 | 1771000 | 0.8855 | yes | Level: -2 kelder_Offset1000
1394367 | -2 kelder | 460 | 3300 | 1650000 | 0.759 | 1518000 | 0.759 | yes | Level: -2 kelder_Offset1000
1398935 | -1 kelder | 300 | 8360 | 4180000 | 1.254 | 2508000 | 1.254 | yes | Level: -1 kelder_Offset1000
1399064 | -1 kelder | 300 | 6520 | 3260000 | 0.978 | 1956000 | 0.978 | yes | Level: -1 kelder_Offset1000
1401079 | -2 kelder | 1060 | 6285 | 3142500 | 3.22087 | 6441736 | 3.21335 | yes | Level: -2 kelder_Offset1000
1401497 | -2 kelder | 1060 | 2500 | 1250000 | 1.325 | 2650000 | 1.325 | yes | Level: -2 kelder_Offset1000
1405061 | -2 kelder | 2220 | 12900 | 6450000 | 14.319 | 28638000 | 14.319 | yes | Level: -2 kelder_Offset1000
2131372 | -1 kelder | 2960 | 3725 | 1862500 | 5.513 | 11026000 | 4.94308 |  | Level: -1 kelder_Offset1000

# IfcWallStandardCase: Basic Wall:16_PBT_WA_beton t.p.g._d=520_C30/37, Basic Wall:16_PBT_WA_beton t.p.g._d=520_C30/37:4453136
In: 00 begane grond
Type - PredefinedType: STANDARD; Material: 00_PBT_MAT_beton t.p.g._C30/37 520 mm
Type - Pset_ElementShading - Roughness: 304.8 mm
Type - Pset_ProductRequirements - Category: Walls
Type - Pset_ReinforcementBarPitchOfWall - Description: betonwand d=520
Type - Pset_WallCommon - IsExternal: yes
Type - Pset_Pieters - Dikte: 520 mm; Naamgeving element: 16_PBT_WA_beton t.p.g._d=520_C30/37; Codering - NL-SfB: 16.20; Omschrijving NL-SfB: funderingsconstructies - keerwanden, algemeen (verzamelniveau); Materiaal: 00_PBT_MAT_beton t.p.g._C30/37; Materiaalkwaliteit: C30/37; Description: betonwand d=520
Classification: 16.20 funderingsconstructies - keerwanden, algemeen (verzamelniveau) (Uniformat)
BaseQuantities - Height: 970 mm; Length: 1200 mm; Width: 520 mm; GrossFootprintArea: 624000 mm2; GrossVolume: 0.60528 m3; GrossSideArea: 1164000 mm2; NetSideArea: 1164000 mm2; NetVolume: 0.60528 m3
Pset_QuantityTakeOff - Reference: Basic Wall:16_PBT_WA_beton t.p.g._d=520_C30/37
Pset_ReinforcementBarPitchOfWall - Reference: Basic Wall:16_PBT_WA_beton t.p.g._d=520_C30/37
Pset_WallCommon - LoadBearing: yes; ExtendToStructure: no; Reference: Basic Wall:16_PBT_WA_beton t.p.g._d=520_C30/37
Pset_Pieters - Dragend/niet dragend: yes; In/uitwendig: yes; Bouwlaag: Level: 00 begane grond; Fase: Nieuw

# IfcWallStandardCase: Basic Wall:16_PBT_WA_beton t.p.g._d=525_bestaand (2)
In: -1 kelder
Type - PredefinedType: STANDARD; Material: 00_PBT_MAT_beton t.p.g. 525 mm
Type - Pset_ElementShading - Roughness: 304.8 mm
Type - Pset_ProductRequirements - Category: Walls
Type - Pset_ReinforcementBarPitchOfWall - Description: betonwand d=525
Type - Pset_WallCommon - IsExternal: yes
Type - Pset_Pieters - Dikte: 525 mm; Naamgeving element: 16_PBT_WA_beton t.p.g._d=525_bestaand; Codering - NL-SfB: 16.20; Omschrijving NL-SfB: funderingsconstructies - keerwanden, algemeen (verzamelniveau); Materiaal: 00_PBT_MAT_beton t.p.g.; Description: betonwand d=525
Classification: 16.20 funderingsconstructies - keerwanden, algemeen (verzamelniveau) (Uniformat)
BaseQuantities - Width: 525 mm
Pset_QuantityTakeOff - Reference: Basic Wall:16_PBT_WA_beton t.p.g._d=525_bestaand
Pset_ReinforcementBarPitchOfWall - Reference: Basic Wall:16_PBT_WA_beton t.p.g._d=525_bestaand
Pset_WallCommon - LoadBearing: yes; ExtendToStructure: no; Reference: Basic Wall:16_PBT_WA_beton t.p.g._d=525_bestaand
Pset_Pieters - Dragend/niet dragend: yes; In/uitwendig: yes; Bouwlaag: Level: -1 kelder_Offset1000; Fase: Bestaand
Name (Basic Wall:16_PBT_WA_beton t.p.g._d=525_bestaand:...) | Height (mm) | Length (mm) | GrossFootprintArea (mm2) | GrossVolume (m3) = NetVolume (m3) | GrossSideArea (mm2) = NetSideArea (mm2)
1390267 | 600 | 10460 | 5491500 | 3.2949 | 6276000
1392705 | 300 | 4220 | 2215500 | 0.66465 | 1266000

# IfcWallStandardCase: Basic Wall:16_PBT_WA_beton t.p.g._d=600_bestaand (3)
Type - PredefinedType: STANDARD; Material: 00_PBT_MAT_beton t.p.g. 600 mm
Type - Pset_ElementShading - Roughness: 304.8 mm
Type - Pset_ProductRequirements - Category: Walls
Type - Pset_ReinforcementBarPitchOfWall - Description: betonwand d=600
Type - Pset_WallCommon - IsExternal: yes
Type - Pset_Pieters - Dikte: 600 mm; Naamgeving element: 16_PBT_WA_beton t.p.g._d=600_bestaand; Codering - NL-SfB: 16.20; Omschrijving NL-SfB: funderingsconstructies - keerwanden, algemeen (verzamelniveau); Materiaal: 00_PBT_MAT_beton t.p.g.; Description: betonwand d=600
Classification: 16.20 funderingsconstructies - keerwanden, algemeen (verzamelniveau) (Uniformat)
BaseQuantities - Width: 600 mm
Pset_QuantityTakeOff - Reference: Basic Wall:16_PBT_WA_beton t.p.g._d=600_bestaand
Pset_ReinforcementBarPitchOfWall - Reference: Basic Wall:16_PBT_WA_beton t.p.g._d=600_bestaand
Pset_WallCommon - LoadBearing: yes; ExtendToStructure: no; Reference: Basic Wall:16_PBT_WA_beton t.p.g._d=600_bestaand
Pset_Pieters - Dragend/niet dragend: yes; In/uitwendig: yes; Fase: Bestaand
Name (Basic Wall:16_PBT_WA_beton t.p.g._d=600_bestaand:...) | In | Height (mm) | Length (mm) | GrossFootprintArea (mm2) | GrossVolume (m3) | GrossSideArea (mm2) = NetSideArea (mm2) | NetVolume (m3) | Bouwlaag
1365545 | -2 kelder | 1460 | 5775 | 3465000 | 5.0589 | 8431500 | 5.0589 | Level: -2 kelder_Offset1000
1392709 | -1 kelder | 300 | 5380 | 3228000 | 0.9684 | 1614000 | 0.9684 | Level: -1 kelder_Offset1000
1400936 | -2 kelder | 1060 | 6285 | 3771000 | 3.97688 | 6628128 | 3.96605 | Level: -2 kelder_Offset1000

# IfcWallStandardCase: Basic Wall:16_PBT_WA_beton t.p.g._d=650_bestaand, Basic Wall:16_PBT_WA_beton t.p.g._d=650_bestaand:1393206
In: -2 kelder
Type - PredefinedType: STANDARD; Material: 00_PBT_MAT_beton t.p.g. 650 mm
Type - Pset_ElementShading - Roughness: 304.8 mm
Type - Pset_ProductRequirements - Category: Walls
Type - Pset_ReinforcementBarPitchOfWall - Description: betonwand d=650
Type - Pset_WallCommon - IsExternal: yes
Type - Pset_Pieters - Dikte: 650 mm; Naamgeving element: 16_PBT_WA_beton t.p.g._d=650_bestaand; Codering - NL-SfB: 16.20; Omschrijving NL-SfB: funderingsconstructies - keerwanden, algemeen (verzamelniveau); Materiaal: 00_PBT_MAT_beton t.p.g.; Description: betonwand d=650
Classification: 16.20 funderingsconstructies - keerwanden, algemeen (verzamelniveau) (Uniformat)
BaseQuantities - Height: 1820 mm; Length: 3880 mm; Width: 650 mm; GrossFootprintArea: 2522000 mm2; GrossVolume: 4.36254 m3; GrossSideArea: 6711600 mm2; NetSideArea: 6711600 mm2; NetVolume: 4.30554 m3
Pset_QuantityTakeOff - Reference: Basic Wall:16_PBT_WA_beton t.p.g._d=650_bestaand
Pset_ReinforcementBarPitchOfWall - Reference: Basic Wall:16_PBT_WA_beton t.p.g._d=650_bestaand
Pset_WallCommon - LoadBearing: yes; ExtendToStructure: no; Reference: Basic Wall:16_PBT_WA_beton t.p.g._d=650_bestaand
Pset_Pieters - Dragend/niet dragend: yes; In/uitwendig: yes; Bouwlaag: Level: -2 kelder_Offset1000; Fase: Bestaand

# IfcWallStandardCase: Basic Wall:16_PBT_WA_beton t.p.g._d=750_bestaand (2)
In: -2 kelder
Type - PredefinedType: STANDARD; Material: 00_PBT_MAT_beton t.p.g. 750 mm
Type - Pset_ElementShading - Roughness: 304.8 mm
Type - Pset_ProductRequirements - Category: Walls
Type - Pset_ReinforcementBarPitchOfWall - Description: betonwand d=750
Type - Pset_WallCommon - IsExternal: yes
Type - Pset_Pieters - Dikte: 750 mm; Naamgeving element: 16_PBT_WA_beton t.p.g._d=750_bestaand; Codering - NL-SfB: 16.20; Omschrijving NL-SfB: funderingsconstructies - keerwanden, algemeen (verzamelniveau); Materiaal: 00_PBT_MAT_beton t.p.g.; Description: betonwand d=750
Classification: 16.20 funderingsconstructies - keerwanden, algemeen (verzamelniveau) (Uniformat)
BaseQuantities - Height: 2270 mm; Width: 750 mm
Pset_QuantityTakeOff - Reference: Basic Wall:16_PBT_WA_beton t.p.g._d=750_bestaand
Pset_ReinforcementBarPitchOfWall - Reference: Basic Wall:16_PBT_WA_beton t.p.g._d=750_bestaand
Pset_WallCommon - LoadBearing: yes; ExtendToStructure: no; Reference: Basic Wall:16_PBT_WA_beton t.p.g._d=750_bestaand
Pset_Pieters - Dragend/niet dragend: yes; In/uitwendig: yes; Bouwlaag: Level: -2 kelder_Offset1000; Fase: Bestaand
Name (Basic Wall:16_PBT_WA_beton t.p.g._d=750_bestaand:...) | Length (mm) | GrossFootprintArea (mm2) | GrossVolume (m3) = NetVolume (m3) | GrossSideArea (mm2) = NetSideArea (mm2)
1364983 | 2540 | 1905000 | 3.6966 | 4928800
1365445 | 950 | 712500 | 1.61737 | 2156500

# IfcWallStandardCase: Basic Wall:28_PBT_WA_HSB_d=144 (2)
In: 02 tweede verdieping
Type - PredefinedType: STANDARD; Material: 00_PBT_MAT_hout 12 mm, 00_PBT_MAT_isolatie 120 mm, 00_PBT_MAT_hout 12 mm
Type - Pset_ElementShading - Roughness: 304.8 mm
Type - Pset_ProductRequirements - Category: Walls
Type - Pset_ReinforcementBarPitchOfWall - Description: dragend HSB
Type - Pset_WallCommon - IsExternal: no
Type - Pset_Pieters - Dikte: 144 mm; Naamgeving element: 28_PBT_WA_HSB_d=144; Codering - NL-SfB: 28.21; Omschrijving NL-SfB: hoofddraagconstructies - wanden en vloeren, wand-/vloerconstructies; Materiaal: 00_PBT_MAT_isolatie; Materiaalkwaliteit: volgens leverancier; Description: dragend HSB
Classification: 28.21 hoofddraagconstructies - wanden en vloeren, wand-/vloerconstructies (Uniformat)
BaseQuantities - Height: 1711 mm; Width: 144 mm
Pset_QuantityTakeOff - Reference: Basic Wall:28_PBT_WA_HSB_d=144
Pset_ReinforcementBarPitchOfWall - Reference: Basic Wall:28_PBT_WA_HSB_d=144
Pset_WallCommon - LoadBearing: yes; ExtendToStructure: no; Reference: Basic Wall:28_PBT_WA_HSB_d=144
Pset_Pieters - Bouwlaag: Level: 02 tweede verdieping; Fase: Nieuw
Name (Basic Wall:28_PBT_WA_HSB_d=144:...) | Length (mm) | GrossFootprintArea (mm2) | GrossVolume (m3) = NetVolume (m3) | GrossSideArea (mm2) = NetSideArea (mm2)
4336784 | 5270.01 | 758881 | 1.29845 | 9016983
4337768 | 1373.06 | 197721 | 0.338301 | 2349312

# IfcWallStandardCase: Basic Wall:28_PBT_WA_HSB_d=183 (2)
In: 02 tweede verdieping
Type - PredefinedType: STANDARD; Material: 00_PBT_MAT_hout 12 mm, 00_PBT_MAT_isolatie 159 mm, 00_PBT_MAT_hout 12 mm
Type - Pset_ElementShading - Roughness: 304.8 mm
Type - Pset_ProductRequirements - Category: Walls
Type - Pset_ReinforcementBarPitchOfWall - Description: dragend HSB
Type - Pset_WallCommon - IsExternal: no
Type - Pset_Pieters - Dikte: 183 mm; Naamgeving element: 28_PBT_WA_HSB_d=183; Codering - NL-SfB: 28.21; Omschrijving NL-SfB: hoofddraagconstructies - wanden en vloeren, wand-/vloerconstructies; Materiaal: 00_PBT_MAT_isolatie; Materiaalkwaliteit: volgens leverancier; Description: dragend HSB
Classification: 28.21 hoofddraagconstructies - wanden en vloeren, wand-/vloerconstructies (Uniformat)
BaseQuantities - Height: 3096 mm; Width: 183 mm
Pset_QuantityTakeOff - Reference: Basic Wall:28_PBT_WA_HSB_d=183
Pset_ReinforcementBarPitchOfWall - Reference: Basic Wall:28_PBT_WA_HSB_d=183
Pset_WallCommon - LoadBearing: yes; ExtendToStructure: no; Reference: Basic Wall:28_PBT_WA_HSB_d=183
Pset_Pieters - Bouwlaag: Level: 02 tweede verdieping; Fase: Nieuw
Name (Basic Wall:28_PBT_WA_HSB_d=183:...) | Length (mm) | GrossFootprintArea (mm2) | GrossVolume (m3) = NetVolume (m3) | GrossSideArea (mm2) = NetSideArea (mm2)
4336948 | 3408.02 | 623667 | 1.37949 | 7538223
4337328 | 2050 | 375150 | 0.665703 | 3637719

# IfcWallStandardCase: Basic Wall:28_PBT_WA_beton prefab_d=200 (25)
Type - PredefinedType: STANDARD; Material: 00_PBT_MAT_beton prefab 200 mm
Type - Pset_ElementShading - Roughness: 304.8 mm
Type - Pset_ProductRequirements - Category: Walls
Type - Pset_ReinforcementBarPitchOfWall - Description: prefab betonwand
Type - Pset_WallCommon - IsExternal: no
Type - Pset_Pieters - Dikte: 200 mm; Naamgeving element: 28_PBT_WA_beton prefab_d=200; Codering - NL-SfB: 28.21; Omschrijving NL-SfB: hoofddraagconstructies - wanden en vloeren, wand-/vloerconstructies; Materiaal: 00_PBT_MAT_beton prefab; Materiaalkwaliteit: volgens leverancier; Description: prefab betonwand; Type Comments: d=200
Classification: 28.21 hoofddraagconstructies - wanden en vloeren, wand-/vloerconstructies (Uniformat)
BaseQuantities - Width: 200 mm
Pset_QuantityTakeOff - Reference: Basic Wall:28_PBT_WA_beton prefab_d=200
Pset_ReinforcementBarPitchOfWall - Reference: Basic Wall:28_PBT_WA_beton prefab_d=200
Pset_WallCommon - LoadBearing: yes; ExtendToStructure: no; Reference: Basic Wall:28_PBT_WA_beton prefab_d=200
Pset_Pieters - Dragend/niet dragend: yes; In/uitwendig: no; Fase: Nieuw
Name (Basic Wall:28_PBT_WA_beton prefab_d=200:...) | In | Height (mm) | Length (mm) | GrossFootprintArea (mm2) | GrossVolume (m3) = NetVolume (m3) | GrossSideArea (mm2) = NetSideArea (mm2) | Bouwlaag
2090471 | 00 begane grond | 5210 | 1170 | 234000 | 1.21914 | 6095700 | Level: 00 begane grond
2090665 | 00 begane grond | 5210 | 28180.8 | 5636163 | 29.3644 | 146822046 | Level: 00 begane grond
2091291 | 00 begane grond | 5210 | 931 | 186200 | 0.970102 | 4850510 | Level: 00 begane grond
2091351 | 00 begane grond | 5200 | 2531.19 | 506237 | 2.63243 | 13162162 | Level: 00 begane grond
2091419 | 00 begane grond | 5210 | 15598.6 | 3119716 | 16.2537 | 81268613 | Level: 00 begane grond
2102030 | 01 eerste verdieping | 3720 | 1170 | 234000 | 0.87048 | 4352400 | Level: 01 eerste verdieping
2102032 | 01 eerste verdieping | 3720 | 28180.8 | 5636163 | 20.9665 | 104832632 | Level: 01 eerste verdieping
2102040 | 01 eerste verdieping | 3720 | 931 | 186200 | 0.692664 | 3463320 | Level: 01 eerste verdieping
2102042 | 01 eerste verdieping | 3740 | 2531.19 | 506237 | 1.89333 | 9466632 | Level: 01 eerste verdieping
2102044 | 01 eerste verdieping | 3720 | 15598.6 | 3119716 | 11.6053 | 58026726 | Level: 01 eerste verdieping
2103323 | 02 tweede verdieping | 3740 | 1170 | 234000 | 0.87516 | 4375800 | Level: 02 tweede verdieping
2103325 | 02 tweede verdieping | 3730 | 28180.8 | 5636163 | 21.0229 | 105114440 | Level: 02 tweede verdieping
2103327 | 02 tweede verdieping | 3730 | 931 | 186200 | 0.694526 | 3472630 | Level: 02 tweede verdieping
2103329 | 02 tweede verdieping | 3720 | 2531.19 | 506237 | 1.8832 | 9416008 | Level: 02 tweede verdieping
2103331 | 02 tweede verdieping | 3730 | 15598.6 | 3119716 | 11.6365 | 58182712 | Level: 02 tweede verdieping
2155048 | 03 derde verdieping | 3955 | 1170 | 234000 | 0.92547 | 4627350 | Level: 03 derde verdieping
2155050 | 03 derde verdieping | 3965 | 28180.8 | 5636163 | 22.3474 | 111736932 | Level: 03 derde verdieping
2155052 | 03 derde verdieping | 3965 | 931 | 186200 | 0.738283 | 3691415 | Level: 03 derde verdieping
2155054 | 03 derde verdieping | 3965 | 2531.19 | 506237 | 2.00723 | 10036149 | Level: 03 derde verdieping
2155056 | 03 derde verdieping | 3965 | 15598.6 | 3119716 | 12.3697 | 61848378 | Level: 03 derde verdieping
2157746 | 04 vierde verdieping | 4030 | 1170 | 234000 | 0.94302 | 4715100 | Level: 04 vierde verdieping
2157748 | 04 vierde verdieping | 4030 | 28180.8 | 5636163 | 22.7137 | 113568684 | Level: 04 vierde verdieping
2157750 | 04 vierde verdieping | 4030 | 931 | 186200 | 0.750386 | 3751930 | Level: 04 vierde verdieping
2157752 | 04 vierde verdieping | 4030 | 2531.19 | 506237 | 2.04014 | 10200676 | Level: 04 vierde verdieping
2157754 | 04 vierde verdieping | 4030 | 15598.6 | 3119716 | 12.5725 | 62862286 | Level: 04 vierde verdieping

# IfcWallStandardCase: Basic Wall:28_PBT_WA_beton t.p.g._d=150_C30/37 (48)
Type - PredefinedType: STANDARD; Material: 00_PBT_MAT_beton t.p.g._C30/37 150 mm
Type - Pset_ElementShading - Roughness: 304.8 mm
Type - Pset_ProductRequirements - Category: Walls
Type - Pset_ReinforcementBarPitchOfWall - Description: betonwand d=150
Type - Pset_WallCommon - IsExternal: no
Type - Pset_Pieters - Dikte: 150 mm; Naamgeving element: 28_PBT_WA_beton t.p.g._d=150_C30/37; Codering - NL-SfB: 28.21; Omschrijving NL-SfB: hoofddraagconstructies - wanden en vloeren, wand-/vloerconstructies; Materiaal: 00_PBT_MAT_beton t.p.g._C30/37; Materiaalkwaliteit: C30/37; Description: betonwand d=150; Type Comments: d=150
Classification: 28.21 hoofddraagconstructies - wanden en vloeren, wand-/vloerconstructies (Uniformat)
BaseQuantities - Width: 150 mm
Pset_QuantityTakeOff - Reference: Basic Wall:28_PBT_WA_beton t.p.g._d=150_C30/37
Pset_ReinforcementBarPitchOfWall - Reference: Basic Wall:28_PBT_WA_beton t.p.g._d=150_C30/37
Pset_WallCommon - LoadBearing: yes; ExtendToStructure: no; Reference: Basic Wall:28_PBT_WA_beton t.p.g._d=150_C30/37
Pset_Pieters - Dragend/niet dragend: yes; Fase: Nieuw
Name (Basic Wall:28_PBT_WA_beton t.p.g._d=150_C30/37:...) | In | Height (mm) | Length (mm) | GrossFootprintArea (mm2) | GrossVolume (m3) | GrossSideArea (mm2) | NetSideArea (mm2) | NetVolume (m3) | In/uitwendig | Bouwlaag
2239653 | 00 begane grond | 3170 | 1600 | 240000 | 0.7608 | 5072000 | 5072000 | 0.7608 | no | Level: 00 begane grond
2239747 | 00 begane grond | 3170 | 1600 | 240000 | 0.7608 | 5072000 | 5072000 | 0.7608 | no | Level: 00 begane grond
2239819 | 00 begane grond | 3170 | 1600 | 240000 | 0.7608 | 5072000 | 5072000 | 0.7608 | no | Level: 00 begane grond
2239910 | 00 begane grond | 3170 | 1600 | 240000 | 0.7608 | 5072000 | 5072000 | 0.7608 | no | Level: 00 begane grond
2239963 | 00 begane grond | 3170 | 1600 | 240000 | 0.7608 | 5072000 | 5072000 | 0.7608 | no | Level: 00 begane grond
2240063 | 00 begane grond | 3170 | 1600 | 240000 | 0.7608 | 5072000 | 5072000 | 0.7608 | no | Level: 00 begane grond
2240127 | 00 begane grond | 3170 | 1600 | 240000 | 0.7608 | 5072000 | 5072000 | 0.7608 | no | Level: 00 begane grond
2240259 | 00 begane grond | 3170 | 1600 | 240000 | 0.7608 | 5072000 | 5072000 | 0.7608 | no | Level: 00 begane grond
2240452 | 01 eerste verdieping | 1630 | 3241.6 | 486240 | 0.655938 | 4372922 | 4372922 | 0.655578 | no | Level: 01 eerste verdieping
2240454 | 01 eerste verdieping | 1630 | 3240.75 | 486112 | 0.655783 | 4371887 | 4371887 | 0.65542 | no | Level: 01 eerste verdieping
2240456 | 01 eerste verdieping | 1340 | 3258.41 | 488762 | 0.654941 | 4366275 | 4366275 | 0.654941 | no | Level: 01 eerste verdieping
2240458 | 01 eerste verdieping | 1630 | 3257.59 | 488638 | 0.659795 | 4398635 | 4398635 | 0.659424 | no | Level: 01 eerste verdieping
2240460 | 01 eerste verdieping | 1630 | 3243.71 | 486556 | 0.656196 | 4374641 | 4374641 | 0.655836 | no | Level: 01 eerste verdieping
2240462 | 01 eerste verdieping | 1630 | 3244.5 | 486674 | 0.656221 | 4374805 | 4374805 | 0.655858 | no | Level: 01 eerste verdieping
2240466 | 01 eerste verdieping | 1630 | 3389.74 | 508461 | 0.685342 | 4568950 | 4568950 | 0.684971 | no | Level: 01 eerste verdieping
2327265 | 01 eerste verdieping | 3730 | 3241.6 | 486240 | 1.78176 | 11878401 | 11878401 | 1.78176 | no | Level: 01 eerste verdieping
2327267 | 01 eerste verdieping | 3730 | 3240.75 | 486112 | 1.78128 | 11875217 | 11875217 | 1.78128 | no | Level: 01 eerste verdieping
2327269 | 01 eerste verdieping | 3730 | 3258.41 | 488762 | 1.82308 | 12153885 | 12153885 | 1.82308 | no | Level: 01 eerste verdieping
2327271 | 01 eerste verdieping | 3730 | 3257.59 | 488638 | 1.82262 | 12150796 | 12150796 | 1.82262 | no | Level: 01 eerste verdieping
2327273 | 01 eerste verdieping | 3730 | 3243.71 | 486556 | 1.78285 | 11885686 | 11885686 | 1.78285 | no | Level: 01 eerste verdieping
2327275 | 01 eerste verdieping | 3730 | 3244.5 | 486674 | 1.7833 | 11888634 | 11888634 | 1.7833 | no | Level: 01 eerste verdieping
2327277 | 01 eerste verdieping | 3730 | 3236.84 | 485526 | 1.78006 | 11867075 | 11867075 | 1.78006 | no | Level: 01 eerste verdieping
2327279 | 01 eerste verdieping | 3730 | 3237.81 | 485672 | 1.7806 | 11870683 | 11870683 | 1.7806 | no | Level: 01 eerste verdieping
2327895 | 02 tweede verdieping | 2480 | 4121.13 | 618169 | 0.677282 | 4515212 | 4355212 | 0.653282 | no | Level: 02 tweede verdieping
2327897 | 02 tweede verdieping | 2480 | 4121.11 | 618166 | 0.686591 | 4577273 | 4349773 | 0.652466 | no | Level: 02 tweede verdieping
2328659 | 02 tweede verdieping | 2480 | 4095.95 | 614392 | 0.78448 | 5229868 | 5002368 | 0.750355 | no | Level: 02 tweede verdieping
2328661 | 02 tweede verdieping | 2480 | 4095.19 | 614278 | 0.784513 | 5230088 | 5002588 | 0.750388 | no | Level: 02 tweede verdieping
2328663 | 02 tweede verdieping | 2480 | 4088.94 | 613341 | 0.784496 | 5229971 | 5002471 | 0.750371 | no | Level: 02 tweede verdieping
2328665 | 02 tweede verdieping | 2480 | 4089.57 | 613435 | 0.784437 | 5229580 | 5002080 | 0.750312 | no | Level: 02 tweede verdieping
3775616 | 00 begane grond | 860 | 3476 | 521399 | 0.448404 | 2989357 | 2989357 | 0.448404 | yes | Level: 00 begane grond | Pset_WallCommon - IsExternal: yes
3775749 | 00 begane grond | 860 | 3476 | 521399 | 0.448404 | 2989357 | 2989357 | 0.448404 | yes | Level: 00 begane grond | Pset_WallCommon - IsExternal: yes
3775773 | 00 begane grond | 860 | 3476 | 521399 | 0.448404 | 2989357 | 2989357 | 0.448404 | yes | Level: 00 begane grond | Pset_WallCommon - IsExternal: yes
3775799 | 00 begane grond | 860 | 3326 | 498899 | 0.429054 | 2860357 | 2860357 | 0.429054 | yes | Level: 00 begane grond | Pset_WallCommon - IsExternal: yes
4421291 | -1 kelder | 2980 | 4500 | 675000 | 2.0115 | 13410000 | 13410000 | 2.0115 | no | Level: -1 kelder
4421293 | -1 kelder | 2980 | 4500 | 675000 | 2.0115 | 13410000 | 13410000 | 2.0115 | no | Level: -1 kelder
4421295 | -1 kelder | 2980 | 4500 | 675000 | 2.0115 | 13410000 | 13410000 | 2.0115 | no | Level: -1 kelder
4421297 | -1 kelder | 2980 | 4500 | 675000 | 2.0115 | 13410000 | 13410000 | 2.0115 | no | Level: -1 kelder
4421299 | -1 kelder | 2980 | 4500 | 675000 | 2.0115 | 13410000 | 13410000 | 2.0115 | no | Level: -1 kelder
4421301 | -1 kelder | 2980 | 4500 | 675000 | 2.0115 | 13410000 | 13410000 | 2.0115 | no | Level: -1 kelder
4421303 | -1 kelder | 2980 | 4500 | 675000 | 1.97044 | 13136263 | 13136263 | 1.97006 | no | Level: -1 kelder
4421305 | -1 kelder | 2980 | 4500 | 675000 | 2.0115 | 13410000 | 13410000 | 2.0115 | no | Level: -1 kelder
4458457 | 00 begane grond | 860 | 816.007 | 122401 | 0.105265 | 701766 | 701766 | 0.105265 | yes | Level: 00 begane grond | Pset_WallCommon - IsExternal: yes
4458721 | 00 begane grond | 860 | 994.571 | 149186 | 0.1283 | 855331 | 855331 | 0.1283 | yes | Level: 00 begane grond | Pset_WallCommon - IsExternal: yes
4458987 | 00 begane grond | 860 | 375.763 | 56364.4 | 0.0484734 | 323156 | 323156 | 0.0484734 | yes | Level: 00 begane grond | Pset_WallCommon - IsExternal: yes
5402859 | 01 eerste verdieping | 2910 | 700 | 105000 | 0.30555 | 2037000 | 2037000 | 0.30555 | no | Level: 01 eerste verdieping | Pset_Pieters - Comments: bestaand wanddeel slopen met behoud van wapening en opnieuw aanstorten
5406954 | 01 eerste verdieping | 4690 | 700 | 105000 | 0.49245 | 3283000 | 3283000 | 0.49245 | no | Level: 01 eerste verdieping | Pset_Pieters - Comments: bestaand wanddeel slopen met behoud van wapening en opnieuw aanstorten
5408190 | 01 eerste verdieping | 4540 | 700 | 105000 | 0.4767 | 3178000 | 3178000 | 0.4767 | no | Level: 01 eerste verdieping | Pset_Pieters - Comments: bestaand wanddeel slopen met behoud van wapening en opnieuw aanstorten
5409299 | 01 eerste verdieping | 4540 | 700 | 105000 | 0.4767 | 3178000 | 3178000 | 0.4767 | no | Level: 01 eerste verdieping | Pset_Pieters - Comments: bestaand wanddeel slopen met behoud van wapening en opnieuw aanstorten

# IfcWallStandardCase: Basic Wall:28_PBT_WA_beton t.p.g._d=150_bestaand, Basic Wall:28_PBT_WA_beton t.p.g._d=150_bestaand:1365284
In: -2 kelder
Type - PredefinedType: STANDARD; Material: 00_PBT_MAT_beton t.p.g. 150 mm
Type - Pset_ElementShading - Roughness: 304.8 mm
Type - Pset_ProductRequirements - Category: Walls
Type - Pset_ReinforcementBarPitchOfWall - Description: betonwand d=150
Type - Pset_WallCommon - IsExternal: no
Type - Pset_Pieters - Dikte: 150 mm; Naamgeving element: 28_PBT_WA_beton t.p.g._d=150_bestaand; Codering - NL-SfB: 28.21; Omschrijving NL-SfB: hoofddraagconstructies - wanden en vloeren, wand-/vloerconstructies; Materiaal: 00_PBT_MAT_beton t.p.g.; Description: betonwand d=150
Classification: 28.21 hoofddraagconstructies - wanden en vloeren, wand-/vloerconstructies (Uniformat)
BaseQuantities - Height: 2270 mm; Length: 3240 mm; Width: 150 mm; GrossFootprintArea: 486000 mm2; GrossVolume: 1.10322 m3; GrossSideArea: 7354800 mm2; NetSideArea: 7354800 mm2; NetVolume: 1.10322 m3
Pset_QuantityTakeOff - Reference: Basic Wall:28_PBT_WA_beton t.p.g._d=150_bestaand
Pset_ReinforcementBarPitchOfWall - Reference: Basic Wall:28_PBT_WA_beton t.p.g._d=150_bestaand
Pset_WallCommon - LoadBearing: yes; ExtendToStructure: no; Reference: Basic Wall:28_PBT_WA_beton t.p.g._d=150_bestaand
Pset_Pieters - Dragend/niet dragend: yes; In/uitwendig: no; Bouwlaag: Level: -2 kelder_Offset1000; Fase: Bestaand

# IfcWallStandardCase: Basic Wall:28_PBT_WA_beton t.p.g._d=200_C30/37 (39)
Type - PredefinedType: STANDARD; Material: 00_PBT_MAT_beton t.p.g._C30/37 200 mm
Type - Pset_ElementShading - Roughness: 304.8 mm
Type - Pset_ProductRequirements - Category: Walls
Type - Pset_ReinforcementBarPitchOfWall - Description: betonwand d=200
Type - Pset_WallCommon - IsExternal: yes
Type - Pset_Pieters - Dikte: 200 mm; Naamgeving element: 28_PBT_WA_beton t.p.g._d=200_C30/37; Codering - NL-SfB: 28.21; Omschrijving NL-SfB: hoofddraagconstructies - wanden en vloeren, wand-/vloerconstructies; Materiaal: 00_PBT_MAT_beton t.p.g._C30/37; Materiaalkwaliteit: C30/37; Description: betonwand d=200; Type Comments: d=200
Classification: 28.21 hoofddraagconstructies - wanden en vloeren, wand-/vloerconstructies (Uniformat)
BaseQuantities - Width: 200 mm
Pset_QuantityTakeOff - Reference: Basic Wall:28_PBT_WA_beton t.p.g._d=200_C30/37
Pset_ReinforcementBarPitchOfWall - Reference: Basic Wall:28_PBT_WA_beton t.p.g._d=200_C30/37
Pset_WallCommon - LoadBearing: yes; Reference: Basic Wall:28_PBT_WA_beton t.p.g._d=200_C30/37
Pset_Pieters - Fase: Nieuw
Name (Basic Wall:28_PBT_WA_beton t.p.g._d=200_C30/37:...) | In | Height (mm) | Length (mm) | GrossFootprintArea (mm2) | GrossVolume (m3) | GrossSideArea (mm2) | NetSideArea (mm2) | NetVolume (m3) | IsExternal | ExtendToStructure | Dragend/niet dragend | In/uitwendig | Bouwlaag
2004872 | 00 begane grond | 5110 | 3745.65 | 749130 | 3.79938 | 18996885 | 18996885 | 3.79938 | no | yes | yes | no | Level: 00 begane grond
2005189 | 00 begane grond | 2410 | 2050 | 410000 | 0.9881 | 4940500 | 4940500 | 0.9881 | no | no | yes | no | Level: 00 begane grond
2005401 | 00 begane grond | 2390 | 2050 | 410000 | 0.9799 | 4899500 | 4899500 | 0.9799 | no | no | yes | no | Level: 00 begane grond
2032095 | 01 eerste verdieping | 3440 | 2250 | 450000 | 1.548 | 7740000 | 7740000 | 1.548 | no | no | yes | no | Level: 01 eerste verdieping
2066758 | 01 eerste verdieping | 3440 | 3267.72 | 653545 | 2.19096 | 10954775 | 10954775 | 2.19096 | no | yes | yes | no | Level: 01 eerste verdieping
2067076 | 02 tweede verdieping | 3480 | 2786.97 | 557394 | 1.8737 | 9368483 | 9300983 | 1.8602 | no | no | yes | no | Level: 02 tweede verdieping
2090985 | 00 begane grond | 3740 | 5997 | 1199400 | 4.48576 | 22428780 | 22428780 | 4.48576 | no | no | yes | no | Level: 00 begane grond
2094879 | 00 begane grond | 4790 | 21312 | 4262399 | 20.0157 | 100078327 | 100078327 | 20.0157 |  | yes | yes | yes | Level: 00 begane grond
2096434 | 00 begane grond | 4060 | 3400.89 | 680178 | 2.76152 | 13807614 | 13807614 | 2.76152 | no | no | yes | no | Level: 00 begane grond
2096612 | 00 begane grond | 4060 | 3950.74 | 790149 | 3.208 | 16040020 | 16040020 | 3.208 | no | no | yes | no | Level: 00 begane grond
2097008 | 00 begane grond | 4060 | 2210.13 | 442026 | 0.966704 | 4833518 | 4833518 | 0.966704 | no | no | yes | no | Level: 00 begane grond
2102056 | 01 eerste verdieping | 3730 | 2800.13 | 560026 | 2.0889 | 10444476 | 10444476 | 2.0889 | no | no | yes | no | Level: 01 eerste verdieping
2102058 | 01 eerste verdieping | 3730 | 3400.74 | 680149 | 2.53695 | 12684775 | 12684775 | 2.53695 | no | no | yes | no | Level: 01 eerste verdieping
2102060 | 01 eerste verdieping | 5120 | 3950.74 | 790149 | 4.04556 | 20227809 | 20227809 | 4.04556 | no | no | yes | no | Level: 01 eerste verdieping
2102064 | 01 eerste verdieping | 5120 | 2210.13 | 442026 | 2.26317 | 11315854 | 11315854 | 2.26317 | no | no | yes | no | Level: 01 eerste verdieping
2103338 | 02 tweede verdieping | 3720 | 2800.13 | 560026 | 2.08329 | 10416475 | 6782475 | 1.35649 | no | no | yes | no | Level: 02 tweede verdieping
2103340 | 02 tweede verdieping | 3730 | 3400.74 | 680149 | 2.53695 | 12684775 | 12684775 | 2.53695 | no | no | yes | no | Level: 02 tweede verdieping
2155526 | 03 derde verdieping | 3965 | 2800.13 | 560026 | 2.2205 | 11102506 | 7231506 | 1.4463 | no | no | yes | no | Level: 03 derde verdieping
2155528 | 03 derde verdieping | 3955 | 3400.74 | 680149 | 2.68999 | 13449942 | 13449942 | 2.68999 | no | no | yes | no | Level: 03 derde verdieping
2158148 | 04 vierde verdieping | 3855 | 2800.13 | 560026 | 2.1589 | 10794492 | 9986492 | 1.99734 | no | no | yes | no | Level: 04 vierde verdieping
2158150 | 04 vierde verdieping | 3855 | 3400.74 | 680149 | 2.62197 | 13109868 | 13109868 | 2.62197 | no | no | yes | no | Level: 04 vierde verdieping
2204520 | 05 vijfde verdieping | 1565 | 2800 | 560000 | 0.8764 | 4381999 | 4381999 | 0.8764 | no | no | yes | no | Level: 05 vijfde verdieping
2204522 | 05 vijfde verdieping | 1565 | 3400.89 | 680178 | 1.06448 | 5322392 | 5322392 | 1.06448 | no | no | yes | no | Level: 05 vijfde verdieping
2688640 | 03 derde verdieping | 3340 | 4470 | 894000 | 2.98596 | 14929800 | 10979685 | 2.19594 | no | no | yes | no | Level: 03 derde verdieping
2901730 | 00 begane grond | 5330 | 4765.99 | 953198 | 4.67192 | 23359599 | 23359599 | 4.67192 |  | no | yes | yes | Level: 00 begane grond
3048400 | 02 tweede verdieping | 165 | 4149.69 | 829938 | 0.13694 | 684699 | 684699 | 0.13694 | no | no | yes | no | Level: 02 tweede verdieping
3460018 | 02 tweede verdieping | 2300 | 2410.13 | 482026 | 0.4255 | 2127500 | 2127500 | 0.381859 | no | no | yes | no | Level: 02 tweede verdieping
3460244 | 02 tweede verdieping | 2300 | 3750.74 | 750149 | 1.72534 | 8626711 | 8626711 | 1.72534 |  | no |  |  | Level: 02 tweede verdieping
4530462 | 01 eerste verdieping | 1620 | 4564.56 | 908578 | 1.47892 | 7394589 | 7394589 | 1.4719 | no | no | yes | no | Level: 01 eerste verdieping
4530581 | 01 eerste verdieping | 1710 | 4523.49 | 900400 | 1.54703 | 7735173 | 7735173 | 1.53968 | no | no | yes | no | Level: 01 eerste verdieping
4530644 | 01 eerste verdieping | 1630 | 4555.63 | 906793 | 1.48514 | 7425684 | 7425684 | 1.47807 | no | no | yes | no | Level: 01 eerste verdieping
4530955 | 01 eerste verdieping | 2460 | 4523.49 | 900400 | 2.22556 | 11127793 | 11127793 | 2.21499 |  | no |  |  | Level: 01 eerste verdieping
4531431 | 01 eerste verdieping | 2460 | 4564.56 | 908578 | 2.24576 | 11228820 | 11228820 | 2.2351 |  | no |  |  | Level: 01 eerste verdieping
4531674 | 01 eerste verdieping | 2460 | 4555.63 | 906793 | 2.24137 | 11206861 | 11206861 | 2.23071 |  | no |  |  | Level: 01 eerste verdieping
5975829 | 00 begane grond | 4580 | 3065 | 613000 | 2.80754 | 14037700 | 14037700 | 2.80754 | no | yes | yes | no | Level: 00 begane grond
5976257 | 00 begane grond | 3740 | 4863.74 | 972749 | 3.63808 | 18190402 | 18190402 | 3.63808 | no | no | yes | no | Level: 00 begane grond
6277207 | -1 kelder | 1200 | 7762 | 1552400 | 1.86288 | 9314400 | 9314400 | 1.86288 | no | no | yes | no | Level: -1 kelder
6277497 | -1 kelder | 1200 | 2454.11 | 490823 | 0.588987 | 2944935 | 2944935 | 0.588987 | no | no | yes | no | Level: -1 kelder
6277875 | -1 kelder | 1200 | 2500 | 500000 | 0.6 | 3000000 | 3000000 | 0.6 | no | no | yes | no | Level: -1 kelder

# IfcWallStandardCase: Basic Wall:28_PBT_WA_beton t.p.g._d=200_bestaand, Basic Wall:28_PBT_WA_beton t.p.g._d=200_bestaand:1355362
In: -1 kelder
Type - PredefinedType: STANDARD; Material: 00_PBT_MAT_beton t.p.g. 200 mm
Type - Pset_ElementShading - Roughness: 304.8 mm
Type - Pset_ProductRequirements - Category: Walls
Type - Pset_ReinforcementBarPitchOfWall - Description: betonwand d=200
Type - Pset_WallCommon - IsExternal: no
Type - Pset_Pieters - Dikte: 200 mm; Naamgeving element: 28_PBT_WA_beton t.p.g._d=200_bestaand; Codering - NL-SfB: 28.21; Omschrijving NL-SfB: hoofddraagconstructies - wanden en vloeren, wand-/vloerconstructies; Materiaal: 00_PBT_MAT_beton t.p.g.; Description: betonwand d=200
Classification: 28.21 hoofddraagconstructies - wanden en vloeren, wand-/vloerconstructies (Uniformat)
BaseQuantities - Height: 3280 mm; Length: 1423.38 mm; Width: 200 mm; GrossFootprintArea: 284677 mm2; GrossVolume: 0.93374 m3; GrossSideArea: 4668698 mm2; NetSideArea: 4668698 mm2; NetVolume: 0.93374 m3
Pset_QuantityTakeOff - Reference: Basic Wall:28_PBT_WA_beton t.p.g._d=200_bestaand
Pset_ReinforcementBarPitchOfWall - Reference: Basic Wall:28_PBT_WA_beton t.p.g._d=200_bestaand
Pset_WallCommon - LoadBearing: yes; ExtendToStructure: no; Reference: Basic Wall:28_PBT_WA_beton t.p.g._d=200_bestaand
Pset_Pieters - Dragend/niet dragend: yes; In/uitwendig: no; Bouwlaag: Level: -1 kelder_Offset1000; Fase: Bestaand

# IfcWallStandardCase: Basic Wall:28_PBT_WA_beton t.p.g._d=230_C40/50 (4)
Type - PredefinedType: STANDARD; Material: 00_PBT_MAT_beton t.p.g._C40/50 230 mm
Type - Pset_ElementShading - Roughness: 304.8 mm
Type - Pset_ProductRequirements - Category: Walls
Type - Pset_ReinforcementBarPitchOfWall - Description: betonwand d=230
Type - Pset_WallCommon - IsExternal: no
Type - Pset_Pieters - Dikte: 230 mm; Naamgeving element: 28_PBT_WA_beton t.p.g._d=230_C40/50; Codering - NL-SfB: 28.21; Omschrijving NL-SfB: hoofddraagconstructies - wanden en vloeren, wand-/vloerconstructies; Materiaal: 00_PBT_MAT_beton t.p.g._C40/50; Materiaalkwaliteit: C40/50; Description: betonwand d=230
Classification: 28.21 hoofddraagconstructies - wanden en vloeren, wand-/vloerconstructies (Uniformat)
BaseQuantities - Width: 230 mm
Pset_QuantityTakeOff - Reference: Basic Wall:28_PBT_WA_beton t.p.g._d=230_C40/50
Pset_ReinforcementBarPitchOfWall - Reference: Basic Wall:28_PBT_WA_beton t.p.g._d=230_C40/50
Pset_WallCommon - LoadBearing: yes; Reference: Basic Wall:28_PBT_WA_beton t.p.g._d=230_C40/50
Pset_Pieters - Dragend/niet dragend: yes; In/uitwendig: no; Fase: Nieuw
Name (Basic Wall:28_PBT_WA_beton t.p.g._d=230_C40/50:...) | In | Height (mm) | Length (mm) | GrossFootprintArea (mm2) | GrossVolume (m3) = NetVolume (m3) | GrossSideArea (mm2) = NetSideArea (mm2) | ExtendToStructure | Bouwlaag
2097352 | 00 begane grond | 4050 | 27151.9 | 6244931 | 25.292 | 109965082 | no | Level: 00 begane grond
2102070 | 01 eerste verdieping | 3740 | 27151.9 | 6244931 | 23.2942 | 101278983 | no | Level: 01 eerste verdieping
2103352 | 02 tweede verdieping | 3730 | 26901.9 | 6187431 | 23.0707 | 100307177 | yes | Level: 02 tweede verdieping
2155532 | 03 derde verdieping | 3965 | 25675 | 5905250 | 23.4143 | 101801374 | no | Level: 03 derde verdieping

# IfcWallStandardCase: Basic Wall:28_PBT_WA_beton t.p.g._d=250_C30/37 (75)
Type - PredefinedType: STANDARD; Material: 00_PBT_MAT_beton t.p.g._C30/37 250 mm
Type - Pset_ElementShading - Roughness: 304.8 mm
Type - Pset_ProductRequirements - Category: Walls
Type - Pset_ReinforcementBarPitchOfWall - Description: betonwand d=250
Type - Pset_WallCommon - IsExternal: yes
Type - Pset_Pieters - Dikte: 250 mm; Naamgeving element: 28_PBT_WA_beton t.p.g._d=250_C30/37; Codering - NL-SfB: 28.21; Omschrijving NL-SfB: hoofddraagconstructies - wanden en vloeren, wand-/vloerconstructies; Materiaal: 00_PBT_MAT_beton t.p.g._C30/37; Materiaalkwaliteit: C30/37; Description: betonwand d=250; Type Comments: d=250
Classification: 28.21 hoofddraagconstructies - wanden en vloeren, wand-/vloerconstructies (Uniformat)
BaseQuantities - Width: 250 mm
Pset_QuantityTakeOff - Reference: Basic Wall:28_PBT_WA_beton t.p.g._d=250_C30/37
Pset_ReinforcementBarPitchOfWall - Reference: Basic Wall:28_PBT_WA_beton t.p.g._d=250_C30/37
Pset_WallCommon - LoadBearing: yes; Reference: Basic Wall:28_PBT_WA_beton t.p.g._d=250_C30/37
Pset_Pieters - Fase: Nieuw
Name (Basic Wall:28_PBT_WA_beton t.p.g._d=250_C30/37:...) | In | Height (mm) | Length (mm) | GrossFootprintArea (mm2) | GrossVolume (m3) | GrossSideArea (mm2) | NetSideArea (mm2) | NetVolume (m3) | IsExternal | ExtendToStructure | Dragend/niet dragend | In/uitwendig | Bouwlaag
1974330 | -1 kelder | 2650 | 3754.11 | 938528 | 2.45037 | 9801489 | 9801489 | 2.45037 | no | no | yes | no | Level: -1 kelder
1974332 | -1 kelder | 2930 | 11880 | 2970000 | 8.16535 | 32661393 | 32661393 | 8.16535 | no | no | yes | no | Level: -1 kelder
2001439 | 00 begane grond | 5110 | 3614.96 | 900350 | 4.61812 | 18472467 | 18472467 | 4.60079 | no | no | yes | no | Level: 00 begane grond
2001829 | 00 begane grond | 5110 | 18634.8 | 4658696 | 22.7335 | 90934051 | 90934051 | 22.7335 | no | no | yes | no | Level: 00 begane grond
2002079 | 00 begane grond | 5110 | 35653.7 | 8913418 | 35.6105 | 142442029 | 142442029 | 35.6105 | no | no | yes | no | Level: 00 begane grond
2006027 | 00 begane grond | 5030 | 24338.3 | 6079485 | 30.3096 | 121238210 | 121238210 | 30.3021 | no | no | yes | no | Level: 00 begane grond
2008815 | 01 eerste verdieping | 3730 | 3614.96 | 900350 | 3.37095 | 13483817 | 7083817 | 1.75831 | no | no | yes | no | Level: 01 eerste verdieping
2008817 | 01 eerste verdieping | 4235 | 18634.8 | 4658696 | 0.34 | 1360000 | 70245440 | 17.5614 | no | no | yes | no | Level: 01 eerste verdieping
2008820 | 01 eerste verdieping | 4235 | 35653.7 | 8913418 | 37.7483 | 150993305 | 150993305 | 37.7483 | no | no | yes | no | Level: 01 eerste verdieping
2008824 | 01 eerste verdieping | 3730 | 24338.3 | 6079485 | 22.6828 | 90731290 | 90731290 | 22.6765 | no | no | yes | no | Level: 01 eerste verdieping
2025492 | 02 tweede verdieping | 3390 | 3363.5 | 837483 | 2.85056 | 11402254 | 11402254 | 2.83907 | no | no | yes | no | Level: 02 tweede verdieping
2025494 | 02 tweede verdieping | 2885 | 18634.8 | 4658696 | 11.8898 | 47559230 | 47559230 | 11.8898 | no | no | yes | no | Level: 02 tweede verdieping
2025496 | 02 tweede verdieping | 2885 | 35653.7 | 8913418 | 0.2125 | 850000 | 95369596 | 23.8424 | no | no | yes | no | Level: 02 tweede verdieping
2025498 | 02 tweede verdieping | 3470 | 24589.7 | 6142352 | 18.603 | 74412131 | 74412131 | 18.5971 | no | no | yes | no | Level: 02 tweede verdieping
2034830 | 03 derde verdieping | 1720 | 3750 | 937500 | 1.6125 | 6450000 | 6450000 | 1.6125 | no | no | yes | no | Level: 03 derde verdieping
2089234 | -1 kelder | 3280 | 3750 | 937500 | 1.7055 | 6822001 | 6822001 | 1.7055 |  | yes | yes | yes | Level: -1 kelder
2089565 | 00 begane grond | 4720 | 4000 | 1000000 | 3.3115 | 13246001 | 13246001 | 3.3115 |  | no | yes | yes | Level: 00 begane grond
2089569 | 00 begane grond | 3740 | 3899.91 | 974977 | 3.64641 | 14585657 | 14585657 | 3.64641 |  | no | yes | yes | Level: 00 begane grond
2089571 | 00 begane grond | 4720 | 4610 | 1152500 | 5.14335 | 20573405 | 20573405 | 5.14335 |  | yes | yes | yes | Level: 00 begane grond
2095597 | 00 begane grond | 3600 | 1973.66 | 493415 | 1.77629 | 7105175 | 7105175 | 1.77629 |  | yes | yes | yes | Level: 00 begane grond
2095896 | 00 begane grond | 3600 | 2267.56 | 566891 | 2.04081 | 8163224 | 7608224 | 1.90206 | no | yes | yes | no | Level: 00 begane grond
2096918 | 00 begane grond | 4050 | 15098.2 | 3774542 | 15.2869 | 61147582 | 61147582 | 15.2869 | no | no | yes | no | Level: 00 begane grond
2097215 | 00 begane grond | 4050 | 2460.13 | 615032 | 2.49088 | 9963517 | 9963517 | 2.49088 | no | no | yes | no | Level: 00 begane grond
2097273 | 00 begane grond | 4050 | 540.832 | 135208 | 0.547592 | 2190368 | 2190368 | 0.547592 | no | no | yes | no | Level: 00 begane grond
2100675 | 00 begane grond | 4380 | 2698.52 | 674630 | 2.95488 | 11819523 | 11819523 | 2.95488 | no | no | yes | no | Level: 00 begane grond
2102025 | 01 eerste verdieping | 2740 | 4000 | 1000001 | 2.72162 | 10886481 | 10886481 | 2.72162 |  | no | yes | yes | Level: 01 eerste verdieping
2102062 | 01 eerste verdieping | 5130 | 15098.2 | 3774542 | 19.3634 | 77453603 | 77453603 | 19.3634 | no | no | yes | no | Level: 01 eerste verdieping
2102066 | 01 eerste verdieping | 5130 | 2210.13 | 552532 | 2.83449 | 11337955 | 11337955 | 2.83449 | no | no | yes | no | Level: 01 eerste verdieping
2102068 | 01 eerste verdieping | 5130 | 790.832 | 197708 | 1.01424 | 4056967 | 4056967 | 1.01424 | no | no | yes | no | Level: 01 eerste verdieping
2102920 | 01 eerste verdieping | 3730 | 2698.52 | 674630 | 2.51637 | 10065484 | 10065484 | 2.51637 | no | no | yes | no | Level: 01 eerste verdieping
2102922 | 01 eerste verdieping | 3730 | 9469.22 | 2367306 | 8.83005 | 35320208 | 35320208 | 8.83005 | no | no | yes | no | Level: 01 eerste verdieping
2103321 | 02 tweede verdieping | 3540 | 3885 | 971250 | 2.92716 | 11708621 | 11708621 | 2.92716 |  | no | yes | yes | Level: 02 tweede verdieping
2103342 | 02 tweede verdieping | 2300 | 790.832 | 197708 | 0.454728 | 1818913 | 1818913 | 0.454728 | no | no | yes | no | Level: 02 tweede verdieping
2103358 | 02 tweede verdieping | 3470 | 2698.52 | 674630 | 2.34097 | 9363868 | 9363868 | 2.34097 | no | no | yes | no | Level: 02 tweede verdieping
2103360 | 02 tweede verdieping | 3930 | 9469.22 | 2367306 | 8.91431 | 35657249 | 35657249 | 8.91431 | no | no | yes | no | Level: 02 tweede verdieping
2155519 | 03 derde verdieping | 3565 | 3885 | 971250 | 3.44859 | 13794366 | 13794366 | 3.44859 |  | no | yes | yes | Level: 03 derde verdieping
2155530 | 03 derde verdieping | 4085 | 19389.7 | 4847436 | 19.8018 | 79207104 | 79207104 | 19.8018 | no | no | yes | no | Level: 03 derde verdieping
2158152 | 04 vierde verdieping | 3355 | 19389.7 | 4847436 | 16.1799 | 64719471 | 64719471 | 16.1799 | no | yes | yes | no | Level: 04 vierde verdieping
2203248 | 05 vijfde verdieping | 2550 | 18348.7 | 4587186 | 11.1441 | 44576537 | 44576537 | 11.1441 | no | no | yes | no | Level: 05 vijfde verdieping
2208992 | 03 derde verdieping | 4790 | 15629.1 | 3907283 | 16.153 | 64611846 | 64611846 | 16.153 | no | no | yes | no | Level: 03 derde verdieping
2640805 | 02 tweede verdieping | 2300 | 15098.2 | 3774542 | 8.68145 | 34725787 | 34725787 | 8.68145 | no | no | yes | no | Level: 02 tweede verdieping
2640988 | 03 derde verdieping | 3765 | 15248.2 | 3812042 | 14.3523 | 57409354 | 57409354 | 14.3523 | no | no | yes | no | Level: 03 derde verdieping
2641528 | 04 vierde verdieping | 2130 | 15248.2 | 3812042 | 8.11965 | 32478599 | 32478599 | 8.11965 | no | no | yes | no | Level: 04 vierde verdieping
2641715 | 05 vijfde verdieping | 4560 | 18598.7 | 4649686 | 19.1681 | 76672478 | 76672296 | 19.1681 | no | no | yes | no | Level: 05 vijfde verdieping
2670776 | 00 begane grond | 5330 | 4960 | 1240000 | 5.48408 | 21936301 | 21936301 | 5.48408 | no | no | yes | no | Level: 00 begane grond
2687700 | 02 tweede verdieping | 3730 | 4610 | 1152500 | 4.29883 | 17195301 | 17195301 | 4.29883 | no | no | yes | no | Level: 02 tweede verdieping
2687709 | 03 derde verdieping | 3340 | 4610 | 1152500 | 3.84935 | 15397401 | 15397401 | 3.84935 | no | no | yes | no | Level: 03 derde verdieping
2687718 | 04 vierde verdieping | 4080 | 4610 | 1152500 | 4.7022 | 18808801 | 18808801 | 4.7022 | no | no | yes | no | Level: 04 vierde verdieping
2688005 | 01 eerste verdieping | 3810 | 4610 | 1152500 | 4.39103 | 17564101 | 17564101 | 4.39103 | no | no | yes | no | Level: 01 eerste verdieping
2690646 | 04 vierde verdieping | 3455 | 3535 | 883750 | 3.05336 | 12213426 | 12213426 | 3.05336 |  | no | yes | yes | Level: 04 vierde verdieping
2835617 | 00 begane grond | 4380 | 9469.22 | 2367306 | 7.25084 | 29003374 | 29003374 | 7.25084 | no | no | yes | no | Level: 00 begane grond
2906972 | -1 kelder | 3070 | 3208.13 | 802032 | 2.28982 | 9159292 | 9159292 | 2.28982 | no | yes | yes | no | Level: -1 kelder
2912207 | 00 begane grond | 660 | 4149.91 | 1037477 | 0.684735 | 2738940 | 2738940 | 0.684735 |  | yes | yes | yes | Level: 00 ok ruwe vloer bwd zuid
2961368 | 04 vierde verdieping | 2540 | 2230.14 | 557535 | 1.41614 | 5664558 | 5664558 | 1.41614 | no | no | yes | no | Level: 04 vierde verdieping
3232587 | 04 vierde verdieping | 2130 | 3562 | 890500 | 1.89676 | 7587060 | 7587060 | 1.89676 | no | no | yes | no | Level: 04 bk ruwe vloer
3460175 | 02 tweede verdieping | 2300 | 2210.13 | 552532 | 1.27082 | 5083294 | 5083294 | 1.27082 | no | no | yes | no | Level: 02 tweede verdieping
3741544 | -1 kelder | 3300 | 1973.66 | 493415 | 1.2427 | 4970811 | 4970811 | 1.2427 |  | no | yes | yes | Level: -1 kelder
3858205 | 00 begane grond | 4380 | 4278.86 | 1068025 | 4.68535 | 18741416 | 18741416 | 4.67795 | no | no | yes | no | Level: 00 begane grond
3859853 | -1 kelder | 4790 | 12400 | 3100000 | 14.7253 | 58901000 | 58751000 | 14.6436 | no | no | yes | no | Level: -1 kelder
3860134 | -1 kelder | 2930 | 8300 | 2075000 | 5.87975 | 23519000 | 23519000 | 5.87975 | no | no | yes | no | Level: -1 kelder
3860208 | -1 kelder | 4760.74 | 9403 | 2350750 | 9.08545 | 36341796 | 36341796 | 9.08545 | no | no | yes | no | Level: -1 kelder
3860835 | 01 eerste verdieping | 3730 | 4278.86 | 1068025 | 3.99004 | 15960156 | 15960156 | 3.98373 | no | no | yes | no | Level: 01 eerste verdieping
3861111 | 02 tweede verdieping | 3470 | 4278.86 | 1068025 | 3.71191 | 14847652 | 14847652 | 3.70605 | no | no | yes | no | Level: 02 tweede verdieping
4309632 | 01 eerste verdieping | 3410 | 4314 | 1078500 | 3.61822 | 14472900 | 14472900 | 3.61822 |  | no |  |  | Level: 01 eerste verdieping
4309811 | 02 tweede verdieping | 3550 | 4314 | 1078500 | 3.81667 | 15266700 | 15266700 | 3.81667 |  | no |  |  | Level: 02 tweede verdieping
4412888 | 00 begane grond | 4480 | 3400.88 | 850219 | 3.80898 | 15235930 | 15235930 | 3.80898 | no | no | yes | no | Level: 00 begane grond
4414367 | 01 eerste verdieping | 3730 | 3400.74 | 850186 | 3.17119 | 12684775 | 12684775 | 3.17119 | no | no | yes | no | Level: 01 eerste verdieping
4414425 | 02 tweede verdieping | 3730 | 3400.74 | 850186 | 3.17119 | 12684775 | 12684775 | 3.17119 | no | no | yes | no | Level: 02 tweede verdieping
4414487 | 03 derde verdieping | 3965 | 3400.74 | 850186 | 3.37099 | 13483950 | 13483950 | 3.37099 | no | no | yes | no | Level: 03 derde verdieping
4414543 | 04 vierde verdieping | 3845 | 3400.74 | 850186 | 3.26897 | 13075860 | 13075860 | 3.26897 | no | no | yes | no | Level: 04 vierde verdieping
4414625 | 05 vijfde verdieping | 1565 | 3400.89 | 850222 | 1.3306 | 5322392 | 5322392 | 1.3306 | no | no | yes | no | Level: 05 vijfde verdieping
4453882 | 02 tweede verdieping | 2885 | 4499.74 | 1124936 | 3.24544 | 12981763 | 12981763 | 3.24544 | no | no | yes | no | Level: 02 tweede verdieping
4454259 | 01 eerste verdieping | 4235 | 4649.74 | 1162436 | 3.34278 | 13371108 | 13371108 | 3.34278 | no | no | yes | no | Level: 01 eerste verdieping
5486060 | 03 derde verdieping | 3365 | 3562 | 890500 | 2.99653 | 11986130 | 11986130 | 2.99653 | no | no | yes | no | Level: 03 derde verdieping
6360717 | 01 eerste verdieping | 560 | 4649.74 | 1162436 | 0.560233 | 2240934 | 2240934 | 0.560233 | no | no | yes | no | Level: 01 eerste verdieping

# IfcWallStandardCase: Basic Wall:28_PBT_WA_beton t.p.g._d=250_bestaand, Basic Wall:28_PBT_WA_beton t.p.g._d=250_bestaand:1331551
In: -1 kelder
Type - PredefinedType: STANDARD; Material: 00_PBT_MAT_beton t.p.g. 250 mm
Type - Pset_ElementShading - Roughness: 304.8 mm
Type - Pset_ProductRequirements - Category: Walls
Type - Pset_ReinforcementBarPitchOfWall - Description: betonwand d=250
Type - Pset_WallCommon - IsExternal: no
Type - Pset_Pieters - Dikte: 250 mm; Naamgeving element: 28_PBT_WA_beton t.p.g._d=250_bestaand; Codering - NL-SfB: 28.21; Omschrijving NL-SfB: hoofddraagconstructies - wanden en vloeren, wand-/vloerconstructies; Materiaal: 00_PBT_MAT_beton t.p.g.; Description: betonwand d=250
Classification: 28.21 hoofddraagconstructies - wanden en vloeren, wand-/vloerconstructies (Uniformat)
BaseQuantities - Height: 3220 mm; Length: 18175 mm; Width: 250 mm; GrossFootprintArea: 4543750 mm2; GrossVolume: 13.5419 m3; GrossSideArea: 54167500 mm2; NetSideArea: 54107500 mm2; NetVolume: 13.5269 m3
Pset_QuantityTakeOff - Reference: Basic Wall:28_PBT_WA_beton t.p.g._d=250_bestaand
Pset_ReinforcementBarPitchOfWall - Reference: Basic Wall:28_PBT_WA_beton t.p.g._d=250_bestaand
Pset_WallCommon - LoadBearing: yes; ExtendToStructure: no; Reference: Basic Wall:28_PBT_WA_beton t.p.g._d=250_bestaand
Pset_Pieters - Dragend/niet dragend: yes; In/uitwendig: no; Bouwlaag: Level: -1 kelder_Offset1000; Fase: Bestaand

# IfcWallStandardCase: Basic Wall:28_PBT_WA_beton t.p.g._d=300_C30/37 (70)
Type - PredefinedType: STANDARD; Material: 00_PBT_MAT_beton t.p.g._C30/37 300 mm
Type - Pset_ElementShading - Roughness: 304.8 mm
Type - Pset_ProductRequirements - Category: Walls
Type - Pset_ReinforcementBarPitchOfWall - Description: betonwand d=300
Type - Pset_WallCommon - IsExternal: yes
Type - Pset_Pieters - Dikte: 300 mm; Naamgeving element: 28_PBT_WA_beton t.p.g._d=300_C30/37; Codering - NL-SfB: 28.21; Omschrijving NL-SfB: hoofddraagconstructies - wanden en vloeren, wand-/vloerconstructies; Materiaal: 00_PBT_MAT_beton t.p.g._C30/37; Materiaalkwaliteit: C30/37; Description: betonwand d=300; Type Comments: d=300
Classification: 28.21 hoofddraagconstructies - wanden en vloeren, wand-/vloerconstructies (Uniformat)
BaseQuantities - Width: 300 mm
Pset_QuantityTakeOff - Reference: Basic Wall:28_PBT_WA_beton t.p.g._d=300_C30/37
Pset_ReinforcementBarPitchOfWall - Reference: Basic Wall:28_PBT_WA_beton t.p.g._d=300_C30/37
Pset_WallCommon - LoadBearing: yes; Reference: Basic Wall:28_PBT_WA_beton t.p.g._d=300_C30/37
Pset_Pieters - Fase: Nieuw
Name (Basic Wall:28_PBT_WA_beton t.p.g._d=300_C30/37:...) | In | Height (mm) | Length (mm) | GrossFootprintArea (mm2) | GrossVolume (m3) | GrossSideArea (mm2) | NetSideArea (mm2) | NetVolume (m3) | IsExternal | ExtendToStructure | Dragend/niet dragend | In/uitwendig | Bouwlaag
1967408 | -1 kelder | 2650 | 2600.74 | 780223 | 2.06759 | 6891973 | 6891973 | 2.06759 | no | no | yes | no | Level: -1 kelder
1968197 | -1 kelder | 2650 | 2200.54 | 660163 | 0.628933 | 2096443 | 2096443 | 0.628933 | no | no | yes | no | Level: -1 kelder
1968378 | -1 kelder | 2650 | 3980 | 1194000 | 3.1641 | 10547000 | 10547000 | 3.1641 | no | no | yes | no | Level: -1 kelder
1982407 | -1 kelder | 1530.74 | 9403 | 2820900 | 2.72321 | 9077376 | 9077376 | 2.72321 | no | no | yes | no | Level: -1 kelder
1984277 | -1 kelder | 2630 | 4871.37 | 1461410 | 3.84351 | 12811696 | 12811696 | 3.84351 | no | no | yes | no | Level: -1 kelder
1997690 | -2 kelder | 2160 | 3100 | 930000 | 2.0088 | 6696000 | 6696000 | 2.0088 | no | no | yes | no | Level: -2 kelder
1997916 | -1 kelder | 700 | 5915 | 1774500 | 1.24215 | 4140500 | 4140500 | 1.24215 | no | no | yes | no | Level: -1 kelder
2000483 | 00 begane grond | 5110 | 2900.74 | 870223 | 4.44684 | 14822804 | 14822804 | 4.44684 | no | no | yes | no | Level: 00 begane grond
2000485 | 00 begane grond | 5110 | 2900.74 | 870223 | 3.30384 | 11012804 | 11012804 | 3.30384 | no | no | yes | no | Level: 00 begane grond
2000487 | 00 begane grond | 5110 | 3150 | 945000 | 4.82895 | 16096500 | 16096500 | 4.82895 | no | no | yes | no | Level: 00 begane grond
2008808 | 01 eerste verdieping | 4235 | 2900.74 | 870223 | 3.6854 | 12284653 | 12284653 | 3.6854 | no | no | yes | no | Level: 01 eerste verdieping
2008810 | 01 eerste verdieping | 4235 | 2900.74 | 870223 | 2.5829 | 8609653 | 8609653 | 2.5829 | no | no | yes | no | Level: 01 eerste verdieping
2008812 | 01 eerste verdieping | 4235 | 3150 | 945000 | 4.00208 | 13340250 | 13340250 | 4.00208 | no | no | yes | no | Level: 01 eerste verdieping
2015662 | 01 eerste verdieping | 6010 | 22400 | 6720000 | 40.3872 | 134624007 | 122474207 | 36.7423 | no | no | yes | no | Level: 01 eerste verdieping
2019479 | 01 eerste verdieping | 6010 | 31204 | 9361194 | 5.58327 | 18610900 | 134563834 | 40.2103 | no | no | yes | no | Level: 01 eerste verdieping
2025485 | 02 tweede verdieping | 2885 | 2900.74 | 870223 | 2.51059 | 8368648 | 8368648 | 2.51059 | no | no | yes | no | Level: 02 tweede verdieping
2025487 | 02 tweede verdieping | 2885 | 2900.74 | 870223 | 1.11409 | 3713648 | 3713648 | 1.11409 | no | no | yes | no | Level: 02 tweede verdieping
2025489 | 02 tweede verdieping | 2885 | 3150 | 945000 | 2.72633 | 9087750 | 9087750 | 2.72633 | no | no | yes | no | Level: 02 tweede verdieping
2025500 | 02 tweede verdieping | 2660 | 21800 | 6540000 | 17.3964 | 57988003 | 57988003 | 17.3964 | no | no | yes | no | Level: 02 tweede verdieping
2025523 | 02 tweede verdieping | 2660 | 31204 | 9361194 | 23.9805 | 79935086 | 79800086 | 23.94 | no | no | yes | no | Level: 02 tweede verdieping
2029650 | 01 eerste verdieping | 3720 | 6406.61 | 1921983 | 6.96748 | 23224932 | 18445432 | 5.53363 | no | yes | yes | no | Level: 01 eerste verdieping
2030115 | 02 tweede verdieping | 3220 | 5097.37 | 1529212 | 3.82586 | 12752865 | 12752865 | 3.82586 | no | no | yes | no | Level: 02 tweede verdieping
2031141 | 02 tweede verdieping | 1085 | 19250 | 5775000 | 6.15083 | 20502751 | 20502751 | 6.15083 | no | yes | yes | no | Level: 02 tweede verdieping
2034824 | 03 derde verdieping | 1720 | 2900.74 | 870223 | 1.49678 | 4989280 | 4989280 | 1.49678 | no | no | yes | no | Level: 03 derde verdieping
2034826 | 03 derde verdieping | 1720 | 2900.74 | 870223 | 1.49678 | 4989280 | 4989280 | 1.49678 | no | no | yes | no | Level: 03 derde verdieping
2034828 | 03 derde verdieping | 1720 | 3150 | 945000 | 1.6254 | 5418000 | 5418000 | 1.6254 | no | no | yes | no | Level: 03 derde verdieping
2136242 | -1 kelder | 3570 | 2453.11 | 719957 | 2.62728 | 8757598 | 8757598 | 2.57025 | no | no | yes | no | Level: -1 kelder
2136474 | -1 kelder | 3570 | 2423.11 | 710956 | 2.59515 | 8650488 | 8650488 | 2.53811 | no | yes | yes | no | Level: -1 kelder
2141845 | 00 begane grond | 4140 | 936.256 | 280877 | 0.924634 | 3082114 | 3082114 | 0.924634 | no | no | yes | no | Level: 00 begane grond | Pset_Pieters - Comments: bestaand wanddeel slopen met behoud van wapening en opnieuw aanstorten
2142054 | 00 begane grond | 2320 | 457.948 | 137384 | 0.317399 | 1057997 | 1057997 | 0.314717 | no | no | yes | no | Level: 00 begane grond
2144251 | 00 begane grond | 2240 | 457.948 | 137384 | 0.307741 | 1025803 | 1025803 | 0.307741 | no | no | yes | no | Level: 00 begane grond
2144642 | 00 begane grond | 2240 | 2539.96 | 761987 | 1.70685 | 5689499 | 5689499 | 1.70685 | no | no | yes | no | Level: 00 begane grond
2153382 | 02 tweede verdieping | 2240 | 322.312 | 96693.5 | 0.216593 | 721978 | 721978 | 0.216593 | no | no | yes | no | Level: 02 tweede verdieping_Offset1000
2153624 | 02 tweede verdieping | 2240 | 2248.83 | 670741 | 1.51121 | 5037375 | 5037375 | 1.50246 | no | no | yes | no | Level: 02 tweede verdieping_Offset1000
2153812 | 02 tweede verdieping | 2240 | 421.052 | 122408 | 0.282947 | 943157 | 943157 | 0.274193 | no | no | yes | no | Level: 02 tweede verdieping_Offset1000
2153814 | 02 tweede verdieping | 2240 | 2161.81 | 644636 | 1.45274 | 4842457 | 4842457 | 1.44398 | no | no | yes | no | Level: 02 tweede verdieping_Offset1000
2154229 | 02 tweede verdieping | 2580 | 5978.57 | 1793571 | 4.62741 | 15424714 | 15424714 | 4.62741 | no | no | yes | no | Level: 02 tweede verdieping_Offset1000
2154419 | 02 tweede verdieping | 2580 | 5778.57 | 1733571 | 4.47261 | 14908714 | 14908714 | 4.47261 | no | no | yes | no | Level: 02 tweede verdieping_Offset1000
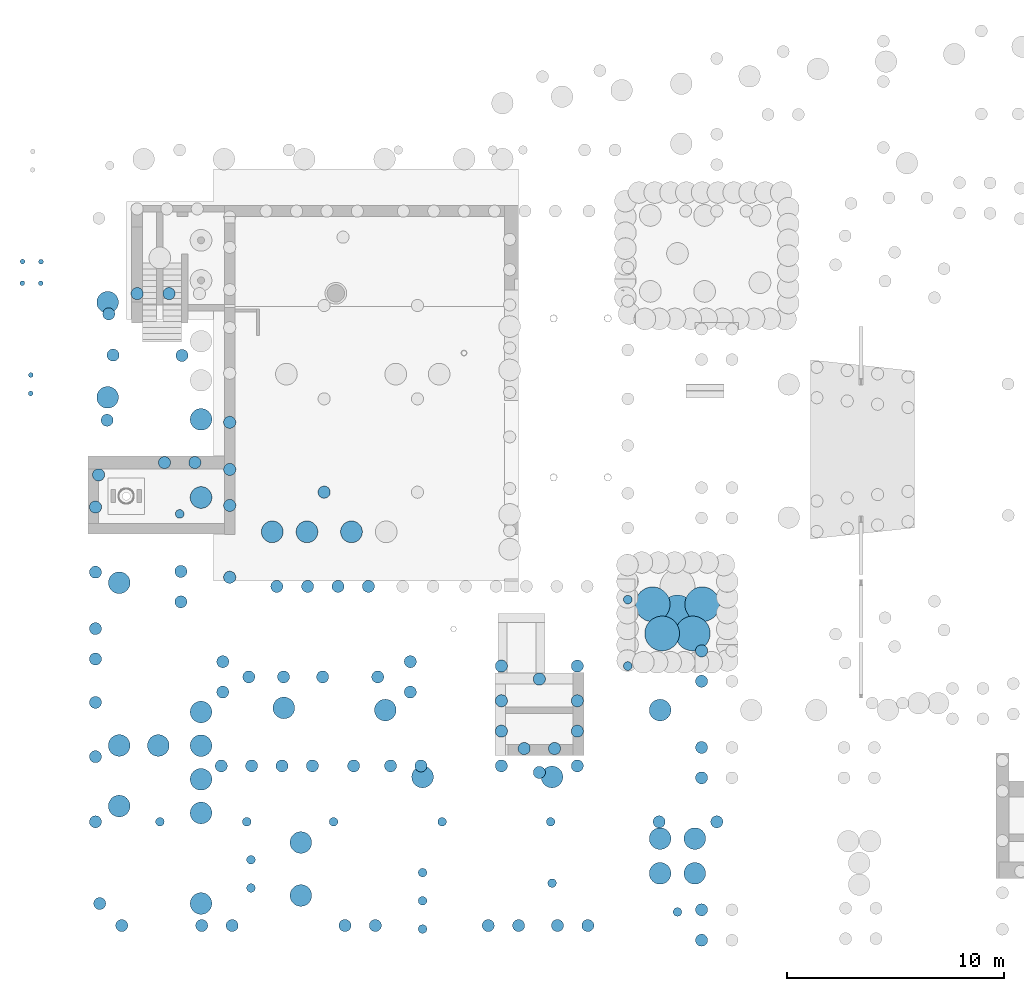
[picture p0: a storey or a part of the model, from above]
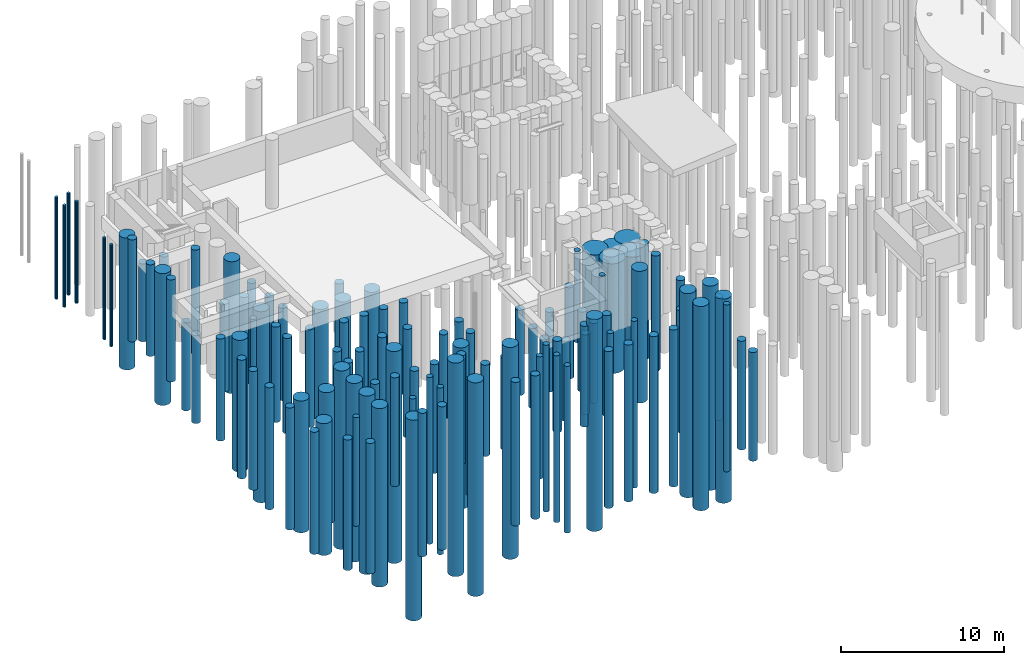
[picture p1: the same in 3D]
Properties of the parts of a building model (IFC2X3), part 18 of 18

# IfcWallStandardCase: Basic Wall:28_PBT_WA_beton t.p.g._d=300_C30/37 (70)
Name (Basic Wall:28_PBT_WA_beton t.p.g._d=300_C30/37:...) | In | Height (mm) | Length (mm) | GrossFootprintArea (mm2) | GrossVolume (m3) | GrossSideArea (mm2) | NetSideArea (mm2) | NetVolume (m3) | IsExternal | ExtendToStructure | Dragend/niet dragend | In/uitwendig | Bouwlaag
2154555 | 00 begane grond | 2580 | 5978.57 | 1793571 | 4.62741 | 15424714 | 15424714 | 4.62741 | no | no | yes | no | Level: 01 ok ruwe vloer bwd zuid
2154557 | 00 begane grond | 2580 | 5778.57 | 1733571 | 4.47261 | 14908714 | 14908714 | 4.47261 | no | no | yes | no | Level: 01 ok ruwe vloer bwd zuid
2154877 | 00 begane grond | 2640 | 2739.96 | 821987 | 1.90406 | 6346881 | 6346881 | 1.90406 | no | no | yes | no | Level: 00 begane grond
2155875 | 03 derde verdieping | 3125 | 850 | 255000 | 0.796875 | 2656250 | 2656250 | 0.796875 |  | no | yes | yes | Level: 03 derde verdieping | Pset_Pieters - Comments: bestaand wanddeel slopen met behoud van wapening en opnieuw aanstorten
2156169 | 03 derde verdieping | 4075 | 2096.26 | 628877 | 1.22606 | 4086878 | 4086878 | 1.22606 |  | no | yes | yes | Level: 03 derde verdieping | Pset_Pieters - Comments: bestaand wanddeel slopen met behoud van wapening en opnieuw aanstorten
2156978 | 03 derde verdieping | 2240 | 950 | 285000 | 0.6384 | 2128000 | 2128000 | 0.6384 | no | no | yes | no | Level: 03 derde verdieping_Offset1000
2156980 | 03 derde verdieping | 2240 | 950 | 285000 | 0.6384 | 2128000 | 2128000 | 0.6384 | no | no | yes | no | Level: 03 derde verdieping_Offset1000
2164937 | 00 begane grond | 4540 | 2935.07 | 880522 | 3.99757 | 13325234 | 13325234 | 3.99757 | no | no | yes | no | Level: 00 begane grond
2745913 | 01 eerste verdieping | 1150 | 19720 | 5916000 | 6.8034 | 22678001 | 22678001 | 6.8034 |  | no |  |  | Level: 01 eerste verdieping
2964253 | 04 vierde verdieping | 2000.06 | 7701.8 | 2310540 | 3.12623 | 10420756 | 10420756 | 3.12623 | no | no | yes | no | Level: 04 vierde verdieping
2972498 | 04 vierde verdieping | 2010.17 | 7701.8 | 2310540 | 2.8128 | 9375999 | 9375999 | 2.8128 | no | no | yes | no | Level: 04 vierde verdieping
3054942 | -2 kelder | 1820 | 5090 | 1527000 | 1.9902 | 6634001 | 6634001 | 1.9902 | no | no | yes | no | Level: -2 kelder
3711893 | 00 begane grond | 4700 | 3425.74 | 1027722 | 3.91749 | 13058308 | 13058308 | 3.88499 | no | yes | yes | no | Level: 00 begane grond_Offset1000
3807149 | 00 begane grond | 4060 | 936.256 | 280877 | 0.902164 | 3007214 | 3007214 | 0.902164 | no | no | yes | no | Level: 00 begane grond | Pset_Pieters - Comments: bestaand wanddeel slopen met behoud van wapening en opnieuw aanstorten
3864405 | 00 begane grond | 4650 | 4314 | 1294200 | 6.01803 | 20060100 | 20060100 | 6.01803 |  | yes |  |  | Level: 00 begane grond
4292137 | 00 begane grond | 3060 | 1463.69 | 309627 | 1.34366 | 4478882 | 4478882 | 0.947459 | no | no | yes | no | Level: 00 begane grond
5356982 | 02 tweede verdieping | 1630 | 995 | 298500 | 0.486555 | 1621850 | 1621850 | 0.486555 | no | no | yes | no | Level: 02 tweede verdieping_Offset1000 | Pset_Pieters - Comments: bestaand wanddeel slopen met behoud van wapening en opnieuw aanstorten
5357564 | 00 begane grond | 3170 | 1963.83 | 589149 | 1.8676 | 6225338 | 6225338 | 1.8676 |  | no |  |  | Level: 00 begane grond
5399487 | 02 tweede verdieping | 1600 | 996.96 | 299088 | 0.478541 | 1595136 | 1595136 | 0.478541 | no | no | yes | no | Level: 02 tweede verdieping_Offset1000 | Pset_Pieters - Comments: bestaand wanddeel slopen met behoud van wapening en opnieuw aanstorten
5412409 | 01 eerste verdieping | 5610 | 1936.26 | 580877 | 0.945338 | 3151128 | 3151128 | 0.945338 | no | no | yes | no | Level: 01 eerste verdieping | Pset_Pieters - Comments: bestaand wanddeel slopen met behoud van wapening en opnieuw aanstorten
5415670 | 01 eerste verdieping | 4410 | 1550.2 | 465059 | 0.956749 | 3189165 | 3189165 | 0.956749 | no | no | yes | no | Level: 01 eerste verdieping | Pset_Pieters - Comments: bestaand wanddeel slopen met behoud van wapening en opnieuw aanstorten
5416058 | 02 tweede verdieping | 950 | 1550.2 | 465059 | 0.315782 | 1052608 | 1052608 | 0.315782 | no | no | yes | no | Level: 02 tweede verdieping | Pset_Pieters - Comments: bestaand wanddeel slopen met behoud van wapening en opnieuw aanstorten
5422183 | 04 vierde verdieping | 1502.05 | 7380.34 | 2214101 | 1.2397 | 4132317 | 4132317 | 1.2397 | no | no | yes | no | Level: 04 vierde verdieping | Pset_Pieters - Comments: bestaand wanddeel slopen met behoud van wapening en opnieuw aanstorten
5422201 | 04 vierde verdieping | 1215.28 | 7889.53 | 2366859 | 1.25123 | 4170774 | 4170774 | 1.25123 | no | no | yes | no | Level: 04 vierde verdieping | Pset_Pieters - Comments: bestaand wanddeel slopen met behoud van wapening en opnieuw aanstorten
5422326 | 04 vierde verdieping | 1656.57 | 8295.52 | 2488656 | 1.39148 | 4638261 | 4638261 | 1.38869 | no | no | yes | no | Level: 04 vierde verdieping | Pset_Pieters - Comments: bestaand wanddeel slopen met behoud van wapening en opnieuw aanstorten
5756778 | 03 derde verdieping | 1563 | 3100 | 930000 | 1.45359 | 4845300 | 3793408 | 1.13802 | no | no | yes | no | Level: 03 derde verdieping | Pset_Pieters - Comments: bestaand wanddeel slopen met behoud van wapening en opnieuw aanstorten
5763766 | 03 derde verdieping | 1563 | 3100 | 930000 | 1.45359 | 4845300 | 3793408 | 1.13802 | no | no | yes | no | Level: 03 derde verdieping | Pset_Pieters - Comments: bestaand wanddeel slopen met behoud van wapening en opnieuw aanstorten
6169990 | -1 kelder | 640 | 335 | 100500 | 0.06432 | 214400 | 214400 | 0.06432 | no | no | yes | no | Level: -1 kelder
6171154 | -1 kelder | 640 | 319.653 | 95896 | 0.0613735 | 204578 | 204578 | 0.0613735 | no | no | yes | no | Level: -1 kelder
6267436 | 04 vierde verdieping | 655 | 1500 | 450000 | 0.29475 | 982500 | 724100 | 0.21723 | no | no | yes | no | Level: 04 vierde verdieping | Pset_Pieters - Comments: bestaand wanddeel slopen met behoud van wapening en opnieuw aanstorten
6267951 | 04 vierde verdieping | 655 | 1500 | 450000 | 0.29475 | 982500 | 724100 | 0.21723 | no | no | yes | no | Level: 04 vierde verdieping | Pset_Pieters - Comments: bestaand wanddeel slopen met behoud van wapening en opnieuw aanstorten
6358456 | -1 kelder | 2650 | 2800 | 840000 | 2.19975 | 7332500 | 7274000 | 2.1822 |  | no |  |  | Level: -1 kelder

# IfcWallStandardCase: Basic Wall:28_PBT_WA_beton t.p.g._d=300_C53/65 (2)
Type - PredefinedType: STANDARD; Material: 00_PBT_MAT_beton t.p.g._C53/65 300 mm
Type - Pset_ElementShading - Roughness: 304.8 mm
Type - Pset_ProductRequirements - Category: Walls
Type - Pset_ReinforcementBarPitchOfWall - Description: betonwand d=300
Type - Pset_WallCommon - IsExternal: no
Type - Pset_Pieters - Dikte: 300 mm; Naamgeving element: 28_PBT_WA_beton t.p.g._d=300_C53/65; Codering - NL-SfB: 28.21; Omschrijving NL-SfB: hoofddraagconstructies - wanden en vloeren, wand-/vloerconstructies; Materiaal: 00_PBT_MAT_beton t.p.g._C53/65; Materiaalkwaliteit: C53/65; Description: betonwand d=300; Type Comments: d=300
Classification: 28.21 hoofddraagconstructies - wanden en vloeren, wand-/vloerconstructies (Uniformat)
BaseQuantities - Width: 300 mm
Pset_QuantityTakeOff - Reference: Basic Wall:28_PBT_WA_beton t.p.g._d=300_C53/65
Pset_ReinforcementBarPitchOfWall - Reference: Basic Wall:28_PBT_WA_beton t.p.g._d=300_C53/65
Pset_WallCommon - LoadBearing: yes; ExtendToStructure: yes; Reference: Basic Wall:28_PBT_WA_beton t.p.g._d=300_C53/65
Pset_Pieters - Dragend/niet dragend: yes; In/uitwendig: no; Fase: Nieuw
Name (Basic Wall:28_PBT_WA_beton t.p.g._d=300_C53/65:...) | In | Height (mm) | Length (mm) | GrossFootprintArea (mm2) | GrossVolume (m3) = NetVolume (m3) | GrossSideArea (mm2) = NetSideArea (mm2) | Bouwlaag
2004647 | 00 begane grond | 4650 | 10771.4 | 3231410 | 12.9275 | 43091622 | Level: 00 begane grond
4571405 | -1 kelder | 1750 | 2600 | 780000 | 1.3094 | 4364679 | Level: -1 kelder_Offset1000

# IfcWallStandardCase: Basic Wall:28_PBT_WA_beton t.p.g._d=300_bestaand (21)
Type - PredefinedType: STANDARD; Material: 00_PBT_MAT_beton t.p.g. 300 mm
Type - Pset_ElementShading - Roughness: 304.8 mm
Type - Pset_ProductRequirements - Category: Walls
Type - Pset_ReinforcementBarPitchOfWall - Description: betonwand d=300
Type - Pset_WallCommon - IsExternal: no
Type - Pset_Pieters - Dikte: 300 mm; Naamgeving element: 28_PBT_WA_beton t.p.g._d=300_bestaand; Codering - NL-SfB: 28.21; Omschrijving NL-SfB: hoofddraagconstructies - wanden en vloeren, wand-/vloerconstructies; Materiaal: 00_PBT_MAT_beton t.p.g.; Description: betonwand d=300
Classification: 28.21 hoofddraagconstructies - wanden en vloeren, wand-/vloerconstructies (Uniformat)
BaseQuantities - Width: 300 mm
Pset_QuantityTakeOff - Reference: Basic Wall:28_PBT_WA_beton t.p.g._d=300_bestaand
Pset_ReinforcementBarPitchOfWall - Reference: Basic Wall:28_PBT_WA_beton t.p.g._d=300_bestaand
Pset_WallCommon - LoadBearing: yes; ExtendToStructure: no; Reference: Basic Wall:28_PBT_WA_beton t.p.g._d=300_bestaand
Pset_Pieters - Fase: Bestaand
Name (Basic Wall:28_PBT_WA_beton t.p.g._d=300_bestaand:...) | In | Height (mm) | Length (mm) | GrossFootprintArea (mm2) | GrossVolume (m3) | GrossSideArea (mm2) | NetSideArea (mm2) | NetVolume (m3) | Dragend/niet dragend | In/uitwendig | Bouwlaag
1341297 | -1 kelder | 3920 | 1788.21 | 493543 | 2.10293 | 7009771 | 7009771 | 1.93469 | yes | no | Level: -1 kelder_Offset1000
1341389 | -1 kelder | 3220 | 590.447 | 151158 | 0.570371 | 1901238 | 1901238 | 0.486729 | yes | no | Level: -1 kelder_Offset1000
1341477 | -1 kelder | 3920 | 1754.87 | 483299 | 2.06373 | 6879093 | 6879093 | 1.89453 | yes | no | Level: -1 kelder_Offset1000
1341479 | -1 kelder | 3220 | 631.34 | 163426 | 0.609874 | 2032915 | 2032915 | 0.526231 | yes | no | Level: -1 kelder_Offset1000
1344660 | 00 begane grond | 3510 | 7414.83 | 2224448 | 3.49705 | 11656831 | 11656831 | 3.49705 | yes | no | Level: 00 begane grond_Offset1000
1358121 | -1 kelder | 2980 | 1660 | 494092 | 1.48404 | 4946800 | 4946800 | 1.47239 | yes | no | Level: -1 kelder_Offset1000
1358617 | -1 kelder | 2980 | 8205.64 | 2453876 | 5.42259 | 18075290 | 18140135 | 5.42636 | yes | no | Level: -1 kelder_Offset1000
1406530 | -2 kelder | 1820 | 4063.38 | 1219015 | 1.68949 | 5631619 | 5631619 | 1.68949 | yes | no | Level: -2 kelder_Offset1000
1406934 | -2 kelder | 1820 | 1665 | 499500 | 0.90909 | 3030300 | 3030300 | 0.90909 | yes | no | Level: -2 kelder_Offset1000
1438171 | 00 begane grond | 3510 | 7214.83 | 2164448 | 3.42085 | 11402831 | 11402831 | 3.42085 | yes | no | Level: 00 begane grond_Offset1000
1482732 | 00 begane grond | 2131 | 22823.1 | 6828156 | 0.209386 | 697955 | 48179484 | 14.4338 | yes | no | Level: 00 begane grond_Offset1000
1482828 | 00 begane grond | 3170 | 2226.05 | 667816 | 2.11023 | 7034085 | 7034085 | 2.11023 | yes | no | Level: 00 begane grond_Offset1000
1485877 | 00 begane grond | 3170 | 2140.34 | 638194 | 2.03546 | 6784871 | 6784871 | 2.02307 | yes | no | Level: 00 begane grond_Offset1000
1594764 | 01 eerste verdieping | 3580 | 7414.83 | 2224448 | 3.33611 | 11120368 | 11120368 | 3.33611 | yes | no | Level: 01 eerste verdieping_Offset1000
1595361 | 01 eerste verdieping | 3580 | 7214.83 | 2164448 | 3.13839 | 10461302 | 10461302 | 3.13839 | yes | no | Level: 01 eerste verdieping_Offset1000
1610111 | 03 derde verdieping | 4184.74 | 23799.2 | 7072431 | 0.398417 | 1328055 | 83523648 | 24.7099 | yes | no | Level: 03 derde verdieping_Offset1000
1746525 | 02 tweede verdieping | 4030 | 7386.26 | 2215877 | 3.33225 | 11107493 | 11107493 | 3.33225 | yes | no | Level: 02 tweede verdieping_Offset1000
2059429 | 01 eerste verdieping | 3550 | 3999.35 | 1199805 | 4.25931 | 14197696 | 14197696 | 4.25931 | yes | no | Level: 01 eerste verdieping_Offset1000
2059858 | 01 eerste verdieping | 3550 | 4085.07 | 1225520 | 4.35059 | 14501982 | 14501982 | 4.35059 | yes | no | Level: 01 eerste verdieping_Offset1000
2201684 | 02 tweede verdieping | 2480 | 24179.3 | 7161630 | 0.19312 | 643734 | 59405432 | 17.6313 | yes | no | Level: 02 tweede verdieping
3736181 | -1 kelder | 3220 | 5015 | 1504500 | 4.68457 | 15615227 | 15615227 | 4.68457 |  |  | Level: -1 kelder_Offset1000

# IfcWallStandardCase: Basic Wall:28_PBT_WA_beton t.p.g._d=320_C30/37, Basic Wall:28_PBT_WA_beton t.p.g._d=320_C30/37:3049318
In: -1 kelder
Type - PredefinedType: STANDARD; Material: 00_PBT_MAT_beton t.p.g._C30/37 320 mm
Type - Pset_ElementShading - Roughness: 304.8 mm
Type - Pset_ProductRequirements - Category: Walls
Type - Pset_ReinforcementBarPitchOfWall - Description: betonwand d=320
Type - Pset_WallCommon - IsExternal: no
Type - Pset_Pieters - Dikte: 320 mm; Naamgeving element: 28_PBT_WA_beton t.p.g._d=320_C30/37; Codering - NL-SfB: 28.21; Omschrijving NL-SfB: hoofddraagconstructies - wanden en vloeren, wand-/vloerconstructies; Materiaal: 00_PBT_MAT_beton t.p.g._C30/37; Materiaalkwaliteit: C30/37; Description: betonwand d=320; Type Comments: d=320
Classification: 28.21 hoofddraagconstructies - wanden en vloeren, wand-/vloerconstructies (Uniformat)
BaseQuantities - Height: 2660 mm; Length: 1687.79 mm; Width: 320 mm; GrossFootprintArea: 535646 mm2; GrossVolume: 1.43665 m3; GrossSideArea: 4489518 mm2; NetSideArea: 4489518 mm2; NetVolume: 1.42482 m3
Pset_QuantityTakeOff - Reference: Basic Wall:28_PBT_WA_beton t.p.g._d=320_C30/37
Pset_ReinforcementBarPitchOfWall - Reference: Basic Wall:28_PBT_WA_beton t.p.g._d=320_C30/37
Pset_WallCommon - LoadBearing: yes; ExtendToStructure: no; Reference: Basic Wall:28_PBT_WA_beton t.p.g._d=320_C30/37
Pset_Pieters - Dragend/niet dragend: yes; In/uitwendig: no; Bouwlaag: Level: -1 kelder; Fase: Nieuw

# IfcWallStandardCase: Basic Wall:28_PBT_WA_beton t.p.g._d=350_C30/37 (11)
Type - PredefinedType: STANDARD; Material: 00_PBT_MAT_beton t.p.g._C30/37 350 mm
Type - Pset_ElementShading - Roughness: 304.8 mm
Type - Pset_ProductRequirements - Category: Walls
Type - Pset_ReinforcementBarPitchOfWall - Description: betonwand d=350
Type - Pset_WallCommon - IsExternal: no
Type - Pset_Pieters - Dikte: 350 mm; Naamgeving element: 28_PBT_WA_beton t.p.g._d=350_C30/37; Codering - NL-SfB: 28.21; Omschrijving NL-SfB: hoofddraagconstructies - wanden en vloeren, wand-/vloerconstructies; Materiaal: 00_PBT_MAT_beton t.p.g._C30/37; Materiaalkwaliteit: C30/37; Description: betonwand d=350; Type Comments: d=350
Classification: 28.21 hoofddraagconstructies - wanden en vloeren, wand-/vloerconstructies (Uniformat)
BaseQuantities - Width: 350 mm
Pset_QuantityTakeOff - Reference: Basic Wall:28_PBT_WA_beton t.p.g._d=350_C30/37
Pset_ReinforcementBarPitchOfWall - Reference: Basic Wall:28_PBT_WA_beton t.p.g._d=350_C30/37
Pset_WallCommon - LoadBearing: yes; Reference: Basic Wall:28_PBT_WA_beton t.p.g._d=350_C30/37
Pset_Pieters - Dragend/niet dragend: yes; Fase: Nieuw
Name (Basic Wall:28_PBT_WA_beton t.p.g._d=350_C30/37:...) | In | Height (mm) | Length (mm) | GrossFootprintArea (mm2) | GrossVolume (m3) | GrossSideArea (mm2) | NetSideArea (mm2) | NetVolume (m3) | ExtendToStructure | In/uitwendig | Bouwlaag
2097595 | 00 begane grond | 4720 | 8745.9 | 3061065 | 12.4313 | 35517898 | 35517898 | 12.4313 | yes | no | Level: 00 begane grond
2102046 | 01 eerste verdieping | 3730 | 7012 | 2454200 | 7.75508 | 22157360 | 22157360 | 7.75508 | no | no | Level: 01 eerste verdieping
2102072 | 01 eerste verdieping | 3060 | 4595.99 | 1608597 | 4.92231 | 14063734 | 14063734 | 4.92231 | yes | no | Level: 01 eerste verdieping
2103333 | 02 tweede verdieping | 3810 | 7012 | 2454200 | 6.92941 | 19798320 | 19694320 | 6.89301 | no | no | Level: 02 tweede verdieping
2103354 | 02 tweede verdieping | 3740 | 4595.99 | 1608597 | 5.15293 | 14722649 | 14722649 | 5.15293 | no | no | Level: 02 tweede verdieping
2155521 | 03 derde verdieping | 4910 | 30102 | 10535700 | 1.06214 | 3034680 | 75737490 | 26.5081 | no | no | Level: 03 derde verdieping
2158144 | 04 vierde verdieping | 2910 | 4302 | 1505700 | 1.791 | 5117140 | 5117140 | 1.791 | no | no | Level: 04 vierde verdieping
2158146 | 04 vierde verdieping | 2910 | 25800 | 9030000 | 26.2773 | 75077999 | 75077999 | 26.2773 | no | yes | Level: 04 vierde verdieping | Pset_WallCommon - IsExternal: yes
2158156 | 04 vierde verdieping | 4265 | 19389.7 | 6786410 | 28.1343 | 80383848 | 80383848 | 28.1343 | yes | no | Level: 04 vierde verdieping
2203252 | 05 vijfde verdieping | 3990 | 18348.7 | 6422060 | 25.624 | 73211488 | 73211488 | 25.624 | no | no | Level: 05 vijfde verdieping
2238051 | -1 kelder | 3280 | 7465.9 | 2613065 | 7.43924 | 21254975 | 21254975 | 7.43924 | yes | no | Level: -1 kelder

# IfcWallStandardCase: Basic Wall:28_PBT_WA_beton t.p.g._d=350_C53/65 (4)
Type - PredefinedType: STANDARD; Material: 00_PBT_MAT_beton t.p.g._C53/65 350 mm
Type - Pset_ElementShading - Roughness: 304.8 mm
Type - Pset_ProductRequirements - Category: Walls
Type - Pset_ReinforcementBarPitchOfWall - Description: betonwand d=350 C53/65
Type - Pset_WallCommon - IsExternal: no
Type - Pset_Pieters - Dikte: 350 mm; Naamgeving element: 28_PBT_WA_beton t.p.g._d=350_C53/65; Codering - NL-SfB: 28.21; Omschrijving NL-SfB: hoofddraagconstructies - wanden en vloeren, wand-/vloerconstructies; Materiaal: 00_PBT_MAT_beton t.p.g._C53/65; Materiaalkwaliteit: C53/65; Description: betonwand d=350 C53/65; Type Comments: d=350
Classification: 28.21 hoofddraagconstructies - wanden en vloeren, wand-/vloerconstructies (Uniformat)
BaseQuantities - Width: 350 mm
Pset_QuantityTakeOff - Reference: Basic Wall:28_PBT_WA_beton t.p.g._d=350_C53/65
Pset_ReinforcementBarPitchOfWall - Reference: Basic Wall:28_PBT_WA_beton t.p.g._d=350_C53/65
Pset_WallCommon - LoadBearing: yes; ExtendToStructure: no; Reference: Basic Wall:28_PBT_WA_beton t.p.g._d=350_C53/65
Pset_Pieters - Dragend/niet dragend: yes; Fase: Nieuw
Name (Basic Wall:28_PBT_WA_beton t.p.g._d=350_C53/65:...) | In | Height (mm) | Length (mm) | GrossFootprintArea (mm2) | GrossVolume (m3) | GrossSideArea (mm2) | NetSideArea (mm2) | NetVolume (m3) | In/uitwendig | Bouwlaag
2082066 | -1 kelder | 2760 | 6870 | 2404500 | 3.6036 | 10296004 | 10296004 | 3.6036 | no | Level: -1 kelder
2083227 | 00 begane grond | 600 | 2020 | 707000 | 0.4242 | 1212000 | 1212000 | 0.4242 | yes | Level: 00 begane grond | Pset_WallCommon - IsExternal: yes
2086421 | 00 begane grond | 630 | 6870 | 2404500 | 1.51483 | 4328100 | 4328100 | 1.51483 | no | Level: 00 begane grond
2092394 | 00 begane grond | 4060 | 9190 | 3216500 | 2.3177 | 6622000 | 20831850 | 7.29115 | yes | Level: 00 begane grond | Pset_WallCommon - IsExternal: yes

# IfcWallStandardCase: Basic Wall:28_PBT_WA_beton t.p.g._d=350_bestaand, Basic Wall:28_PBT_WA_beton t.p.g._d=350_bestaand:1365107
In: -2 kelder
Type - PredefinedType: STANDARD; Material: 00_PBT_MAT_beton t.p.g. 350 mm
Type - Pset_ElementShading - Roughness: 304.8 mm
Type - Pset_ProductRequirements - Category: Walls
Type - Pset_ReinforcementBarPitchOfWall - Description: betonwand d=350
Type - Pset_WallCommon - IsExternal: no
Type - Pset_Pieters - Dikte: 350 mm; Naamgeving element: 28_PBT_WA_beton t.p.g._d=350_bestaand; Codering - NL-SfB: 28.21; Omschrijving NL-SfB: hoofddraagconstructies - wanden en vloeren, wand-/vloerconstructies; Materiaal: 00_PBT_MAT_beton t.p.g.; Description: betonwand d=350
Classification: 28.21 hoofddraagconstructies - wanden en vloeren, wand-/vloerconstructies (Uniformat)
BaseQuantities - Height: 2270 mm; Length: 950 mm; Width: 350 mm; GrossFootprintArea: 332500 mm2; GrossVolume: 0.754775 m3; GrossSideArea: 2156500 mm2; NetSideArea: 2156500 mm2; NetVolume: 0.754775 m3
Pset_QuantityTakeOff - Reference: Basic Wall:28_PBT_WA_beton t.p.g._d=350_bestaand
Pset_ReinforcementBarPitchOfWall - Reference: Basic Wall:28_PBT_WA_beton t.p.g._d=350_bestaand
Pset_WallCommon - LoadBearing: yes; ExtendToStructure: no; Reference: Basic Wall:28_PBT_WA_beton t.p.g._d=350_bestaand
Pset_Pieters - Dragend/niet dragend: yes; In/uitwendig: no; Bouwlaag: Level: -2 kelder_Offset1000; Fase: Bestaand

# IfcWallStandardCase: Basic Wall:28_PBT_WA_beton t.p.g._d=400_C30/37 (8)
Type - PredefinedType: STANDARD; Material: 00_PBT_MAT_beton t.p.g._C30/37 400 mm
Type - Pset_ElementShading - Roughness: 304.8 mm
Type - Pset_ProductRequirements - Category: Walls
Type - Pset_ReinforcementBarPitchOfWall - Description: betonwand d=400
Type - Pset_WallCommon - IsExternal: no
Type - Pset_Pieters - Dikte: 400 mm; Naamgeving element: 28_PBT_WA_beton t.p.g._d=400_C30/37; Codering - NL-SfB: 28.21; Omschrijving NL-SfB: hoofddraagconstructies - wanden en vloeren, wand-/vloerconstructies; Materiaal: 00_PBT_MAT_beton t.p.g._C30/37; Materiaalkwaliteit: C30/37; Description: betonwand d=400
Classification: 28.21 hoofddraagconstructies - wanden en vloeren, wand-/vloerconstructies (Uniformat)
BaseQuantities - Width: 400 mm
Pset_QuantityTakeOff - Reference: Basic Wall:28_PBT_WA_beton t.p.g._d=400_C30/37
Pset_ReinforcementBarPitchOfWall - Reference: Basic Wall:28_PBT_WA_beton t.p.g._d=400_C30/37
Pset_WallCommon - LoadBearing: yes; ExtendToStructure: no; Reference: Basic Wall:28_PBT_WA_beton t.p.g._d=400_C30/37
Pset_Pieters - Dragend/niet dragend: yes; In/uitwendig: no; Fase: Nieuw
Name (Basic Wall:28_PBT_WA_beton t.p.g._d=400_C30/37:...) | In | Height (mm) | Length (mm) | GrossFootprintArea (mm2) | GrossVolume (m3) = NetVolume (m3) | GrossSideArea (mm2) = NetSideArea (mm2) | Bouwlaag
2199867 | 01 eerste verdieping | 2050 | 950 | 380000 | 0.779 | 1947500 | Level: 01 eerste verdieping_Offset1000
2200004 | 01 eerste verdieping | 2050 | 950 | 380000 | 0.779 | 1947500 | Level: 01 eerste verdieping_Offset1000
2200104 | 01 eerste verdieping | 2050 | 950 | 380000 | 0.665 | 1662500 | Level: 01 eerste verdieping_Offset1000
2200209 | 01 eerste verdieping | 2050 | 950 | 380000 | 0.779 | 1947500 | Level: 01 eerste verdieping_Offset1000
2326293 | 02 tweede verdieping | 610 | 900 | 360000 | 0.2196 | 549000 | Level: 02 tweede verdieping
2326846 | 02 tweede verdieping | 610 | 900 | 360000 | 0.2196 | 549000 | Level: 02 tweede verdieping
2327106 | 02 tweede verdieping | 610 | 900 | 360000 | 0.2196 | 549000 | Level: 02 tweede verdieping
2327690 | 02 tweede verdieping | 610 | 900 | 360000 | 0.2196 | 549000 | Level: 02 tweede verdieping

# IfcWallStandardCase: Basic Wall:28_PBT_WA_beton t.p.g._d=400_bestaand (12)
Type - PredefinedType: STANDARD; Material: 00_PBT_MAT_beton t.p.g. 400 mm
Type - Pset_ElementShading - Roughness: 304.8 mm
Type - Pset_ProductRequirements - Category: Walls
Type - Pset_ReinforcementBarPitchOfWall - Description: betonwand d=400
Type - Pset_WallCommon - IsExternal: no
Type - Pset_Pieters - Dikte: 400 mm; Naamgeving element: 28_PBT_WA_beton t.p.g._d=400_bestaand; Codering - NL-SfB: 28.21; Omschrijving NL-SfB: hoofddraagconstructies - wanden en vloeren, wand-/vloerconstructies; Materiaal: 00_PBT_MAT_beton t.p.g.; Description: betonwand d=400
Classification: 28.21 hoofddraagconstructies - wanden en vloeren, wand-/vloerconstructies (Uniformat)
BaseQuantities - Width: 400 mm
Pset_QuantityTakeOff - Reference: Basic Wall:28_PBT_WA_beton t.p.g._d=400_bestaand
Pset_ReinforcementBarPitchOfWall - Reference: Basic Wall:28_PBT_WA_beton t.p.g._d=400_bestaand
Pset_WallCommon - LoadBearing: yes; ExtendToStructure: no; Reference: Basic Wall:28_PBT_WA_beton t.p.g._d=400_bestaand
Pset_Pieters - Dragend/niet dragend: yes; In/uitwendig: no; Fase: Bestaand
Name (Basic Wall:28_PBT_WA_beton t.p.g._d=400_bestaand:...) | In | Height (mm) | Length (mm) | GrossFootprintArea (mm2) | GrossVolume (m3) | GrossSideArea (mm2) | NetSideArea (mm2) | NetVolume (m3) | Bouwlaag
1376427 | -1 kelder | 2980 | 4500 | 1800000 | 5.364 | 13410000 | 13410000 | 5.364 | Level: -1 kelder_Offset1000
1376588 | -1 kelder | 2980 | 4500 | 1800000 | 5.364 | 13410000 | 13410000 | 5.364 | Level: -1 kelder_Offset1000
1376629 | -1 kelder | 2980 | 4500 | 1800000 | 5.364 | 13410000 | 13410000 | 5.364 | Level: -1 kelder_Offset1000
1376631 | -1 kelder | 2980 | 4500 | 1800000 | 5.364 | 13410000 | 13410000 | 5.364 | Level: -1 kelder_Offset1000
1515581 | 00 begane grond | 2570 | 1600 | 640000 | 1.6448 | 4112000 | 4112000 | 1.6448 | Level: 00 begane grond_Offset1000
1566299 | 01 eerste verdieping | 3840 | 5764.26 | 2305703 | 5.73342 | 14333554 | 12386054 | 4.95442 | Level: 01 eerste verdieping_Offset1000
1571679 | 01 eerste verdieping | 3550 | 5773.5 | 2309401 | 5.37925 | 13448121 | 11500621 | 4.60025 | Level: 01 eerste verdieping_Offset1000
1612358 | 01 eerste verdieping | 3840 | 5773.5 | 2309401 | 5.73981 | 14349536 | 12402036 | 4.96081 | Level: 01 eerste verdieping_Offset1000
1612361 | 01 eerste verdieping | 3550 | 5773.51 | 2309402 | 5.35826 | 13395640 | 11448140 | 4.57926 | Level: 01 eerste verdieping_Offset1000
1929997 | 00 begane grond | 2570 | 1600 | 640000 | 1.6448 | 4112000 | 4112000 | 1.6448 | Level: 00 begane grond_Offset1000
1930200 | 00 begane grond | 2570 | 1600 | 640000 | 1.6448 | 4112000 | 4112000 | 1.6448 | Level: 00 begane grond_Offset1000
1930392 | 00 begane grond | 2570 | 1600 | 640000 | 1.6448 | 4112000 | 4112000 | 1.6448 | Level: 00 begane grond_Offset1000

# IfcWallStandardCase: Basic Wall:28_PBT_WA_beton t.p.g._d=500_C30/37 (16)
Type - PredefinedType: STANDARD; Material: 00_PBT_MAT_beton t.p.g._C30/37 500 mm
Type - Pset_ElementShading - Roughness: 304.8 mm
Type - Pset_ProductRequirements - Category: Walls
Type - Pset_ReinforcementBarPitchOfWall - Description: betonwand d=500
Type - Pset_WallCommon - IsExternal: no
Type - Pset_Pieters - Dikte: 500 mm; Naamgeving element: 28_PBT_WA_beton t.p.g._d=500_C30/37; Codering - NL-SfB: 28.21; Omschrijving NL-SfB: hoofddraagconstructies - wanden en vloeren, wand-/vloerconstructies; Materiaal: 00_PBT_MAT_beton t.p.g._C30/37; Materiaalkwaliteit: C30/37; Description: betonwand d=500; Type Comments: d=500
Classification: 28.21 hoofddraagconstructies - wanden en vloeren, wand-/vloerconstructies (Uniformat)
BaseQuantities - Width: 500 mm
Pset_QuantityTakeOff - Reference: Basic Wall:28_PBT_WA_beton t.p.g._d=500_C30/37
Pset_ReinforcementBarPitchOfWall - Reference: Basic Wall:28_PBT_WA_beton t.p.g._d=500_C30/37
Pset_WallCommon - LoadBearing: yes; Reference: Basic Wall:28_PBT_WA_beton t.p.g._d=500_C30/37
Pset_Pieters - Fase: Nieuw
Name (Basic Wall:28_PBT_WA_beton t.p.g._d=500_C30/37:...) | In | Height (mm) | Length (mm) | GrossFootprintArea (mm2) | GrossVolume (m3) | GrossSideArea (mm2) | NetSideArea (mm2) | NetVolume (m3) | ExtendToStructure | Dragend/niet dragend | In/uitwendig | Bouwlaag
1975586 | -2 kelder | 1110 | 4050 | 2025000 | 2.19625 | 4392500 | 4392500 | 2.19625 | no | yes | no | Level: -2 kelder
1988998 | -1 kelder | 300 | 290 | 145000 | 0.075 | 150000 | 150000 | 0.0435 | no | yes | no | Level: -1 kelder
1990831 | -1 kelder | 300 | 400 | 200000 | 0.075 | 150000 | 150000 | 0.06 | no | yes | no | Level: -1 kelder
1990849 | -1 kelder | 300 | 400 | 200000 | 0.075 | 150000 | 150000 | 0.06 | no | yes | no | Level: -1 kelder
1990908 | -1 kelder | 400 | 700 | 350000 | 0.14 | 280000 | 280000 | 0.14 | no | yes | no | Level: -1 kelder
1990910 | -1 kelder | 400 | 700 | 350000 | 0.14 | 280000 | 280000 | 0.14 | no | yes | no | Level: -1 kelder
1990912 | -1 kelder | 400 | 700 | 350000 | 0.14 | 280000 | 280000 | 0.14 | no | yes | no | Level: -1 kelder
2129158 | -1 kelder | 3630 | 2940 | 1470000 | 3.7971 | 7594200 | 7444200 | 3.7221 | no | yes | no | Level: -1 kelder
2860199 | 00 begane grond | 3060 | 14426.7 | 7213343 | 22.0728 | 44145658 | 41105658 | 20.5528 | no |  |  | Level: 00 begane grond
3078596 | -1 kelder | 1540 | 4563.86 | 2281929 | 3.14021 | 6280417 | 6280417 | 3.14021 | no | yes | no | Level: -1 kelder
3078781 | -1 kelder | 1540 | 3504.11 | 1752057 | 2.63721 | 5274423 | 5274423 | 2.63721 | no | yes | no | Level: -1 kelder
3107368 | -1 kelder | 1540 | 4563.86 | 2281929 | 3.14021 | 6280417 | 6280417 | 3.14021 | no | yes | no | Level: -1 kelder
4317149 | 00 begane grond | 3060 | 4265 | 2132500 | 6.52545 | 13050900 | 11970900 | 5.98545 | yes | yes | no | Level: 00 begane grond
4475532 | -1 kelder | 2930 | 3750 | 1875000 | 5.49375 | 10987501 | 10987501 | 5.44646 | no | yes | no | Level: -1 kelder_Offset1000
4476155 | -1 kelder | 2930 | 8943.92 | 4471958 | 11.2535 | 22507071 | 22507071 | 11.2535 | no |  |  | Level: -1 kelder_Offset1000
5110971 | -1 kelder | 2650 | 700.2 | 350100 | 0.927765 | 1855530 | 1855530 | 0.927765 | no | yes | no | Level: -1 kelder

# IfcWallStandardCase: Basic Wall:28_PBT_WA_beton t.p.g._d=500_C53/65 (3)
In: -1 kelder
Type - PredefinedType: STANDARD; Material: 00_PBT_MAT_beton t.p.g._C53/65 500 mm
Type - Pset_ElementShading - Roughness: 304.8 mm
Type - Pset_ProductRequirements - Category: Walls
Type - Pset_ReinforcementBarPitchOfWall - Description: betonwand d=500
Type - Pset_WallCommon - IsExternal: no
Type - Pset_Pieters - Dikte: 500 mm; Naamgeving element: 28_PBT_WA_beton t.p.g._d=500_C53/65; Codering - NL-SfB: 28.21; Omschrijving NL-SfB: hoofddraagconstructies - wanden en vloeren, wand-/vloerconstructies; Materiaal: 00_PBT_MAT_beton t.p.g._C53/65; Materiaalkwaliteit: C53/65; Description: betonwand d=500; Type Comments: d=500
Classification: 28.21 hoofddraagconstructies - wanden en vloeren, wand-/vloerconstructies (Uniformat)
BaseQuantities - Width: 500 mm
Pset_QuantityTakeOff - Reference: Basic Wall:28_PBT_WA_beton t.p.g._d=500_C53/65
Pset_ReinforcementBarPitchOfWall - Reference: Basic Wall:28_PBT_WA_beton t.p.g._d=500_C53/65
Pset_WallCommon - LoadBearing: yes; ExtendToStructure: no; Reference: Basic Wall:28_PBT_WA_beton t.p.g._d=500_C53/65
Pset_Pieters - Dragend/niet dragend: yes; In/uitwendig: no; Bouwlaag: Level: -1 kelder; Fase: Nieuw
Name (Basic Wall:28_PBT_WA_beton t.p.g._d=500_C53/65:...) | Height (mm) | Length (mm) | GrossFootprintArea (mm2) | GrossVolume (m3) = NetVolume (m3) | GrossSideArea (mm2) = NetSideArea (mm2)
3042167 | 2660 | 3760 | 1880000 | 4.9298 | 9859599
3042373 | 2560 | 1500 | 750000 | 1.92 | 3840000
5537328 | 2830 | 2305 | 1152500 | 3.26158 | 6523150

# IfcWallStandardCase: Basic Wall:28_PBT_WA_beton t.p.g._d=500_bestaand (6)
Type - PredefinedType: STANDARD; Material: 00_PBT_MAT_beton t.p.g. 500 mm
Type - Pset_ElementShading - Roughness: 304.8 mm
Type - Pset_ProductRequirements - Category: Walls
Type - Pset_ReinforcementBarPitchOfWall - Description: betonwand d=500
Type - Pset_WallCommon - IsExternal: no
Type - Pset_Pieters - Dikte: 500 mm; Naamgeving element: 28_PBT_WA_beton t.p.g._d=500_bestaand; Codering - NL-SfB: 28.21; Omschrijving NL-SfB: hoofddraagconstructies - wanden en vloeren, wand-/vloerconstructies; Materiaal: 00_PBT_MAT_beton t.p.g.; Description: betonwand d=500
Classification: 28.21 hoofddraagconstructies - wanden en vloeren, wand-/vloerconstructies (Uniformat)
BaseQuantities - Width: 500 mm
Pset_QuantityTakeOff - Reference: Basic Wall:28_PBT_WA_beton t.p.g._d=500_bestaand
Pset_ReinforcementBarPitchOfWall - Reference: Basic Wall:28_PBT_WA_beton t.p.g._d=500_bestaand
Pset_WallCommon - LoadBearing: yes; Reference: Basic Wall:28_PBT_WA_beton t.p.g._d=500_bestaand
Pset_Pieters - Fase: Bestaand
Name (Basic Wall:28_PBT_WA_beton t.p.g._d=500_bestaand:...) | In | Height (mm) | Length (mm) | GrossFootprintArea (mm2) | GrossVolume (m3) | GrossSideArea (mm2) | NetSideArea (mm2) | NetVolume (m3) | ExtendToStructure | Dragend/niet dragend | In/uitwendig | Bouwlaag
1384460 | -1 kelder | 3630 | 9460 | 4730000 | 14.6908 | 29381540 | 28214540 | 14.0338 | no | yes | no | Level: -1 kelder_Offset1000
1385189 | -1 kelder | 2930 | 17290 | 8645000 | 22.9924 | 45984800 | 38987798 | 19.4939 | no | yes | no | Level: -1 kelder_Offset1000
1405739 | -2 kelder | 1820 | 12840 | 6420000 | 6.8472 | 13694400 | 13694400 | 6.8472 | yes | yes | no | Level: -2 kelder_Offset1000
1978122 | -1 kelder | 1000 | 9960 | 4980000 | 4.98 | 9960000 | 9960000 | 4.98 | no | yes | no | Level: -1 kelder_Offset1000
3059901 | -2 kelder | 1820 | 3750 | 1875000 | 3.4125 | 6825000 | 6825000 | 3.4125 | no | yes | no | Level: -2 bk ruwe vloer orkestbak
3384074 | -2 kelder | 1140 | 298.718 | 149359 | 0.285 | 570000 | 570000 | 0.170269 | no |  |  | Level: -2 kelder_Offset1000

# IfcWallStandardCase: Basic Wall:28_PBT_WA_beton t.p.g._d=550_C30/37 (2)
In: 00 begane grond
Type - PredefinedType: STANDARD; Material: 00_PBT_MAT_beton t.p.g._C30/37 550 mm
Type - Pset_ElementShading - Roughness: 304.8 mm
Type - Pset_ProductRequirements - Category: Walls
Type - Pset_ReinforcementBarPitchOfWall - Description: betonwand d=550
Type - Pset_WallCommon - IsExternal: no
Type - Pset_Pieters - Dikte: 550 mm; Naamgeving element: 28_PBT_WA_beton t.p.g._d=550_C30/37; Codering - NL-SfB: 28.21; Omschrijving NL-SfB: hoofddraagconstructies - wanden en vloeren, wand-/vloerconstructies; Materiaal: 00_PBT_MAT_beton t.p.g._C30/37; Materiaalkwaliteit: C30/37; Description: betonwand d=550; Type Comments: d=550
Classification: 28.21 hoofddraagconstructies - wanden en vloeren, wand-/vloerconstructies (Uniformat)
BaseQuantities - Width: 550 mm
Pset_QuantityTakeOff - Reference: Basic Wall:28_PBT_WA_beton t.p.g._d=550_C30/37
Pset_ReinforcementBarPitchOfWall - Reference: Basic Wall:28_PBT_WA_beton t.p.g._d=550_C30/37
Pset_WallCommon - LoadBearing: yes; ExtendToStructure: no; Reference: Basic Wall:28_PBT_WA_beton t.p.g._d=550_C30/37
Pset_Pieters - Dragend/niet dragend: yes; In/uitwendig: no; Bouwlaag: Level: 00 begane grond; Fase: Nieuw
Name (Basic Wall:28_PBT_WA_beton t.p.g._d=550_C30/37:...) | Height (mm) | Length (mm) | GrossFootprintArea (mm2) | GrossVolume (m3) = NetVolume (m3) | GrossSideArea (mm2) = NetSideArea (mm2)
4423568 | 980 | 3000.13 | 1650071 | 1.61707 | 2940126
4423911 | 1160 | 3400.74 | 1870409 | 1.78459 | 3244717

# IfcWallStandardCase: Basic Wall:28_PBT_WA_beton t.p.g._d=600_C30/37 (5)
Type - PredefinedType: STANDARD; Material: 00_PBT_MAT_beton t.p.g._C30/37 600 mm
Type - Pset_ElementShading - Roughness: 304.8 mm
Type - Pset_ProductRequirements - Category: Walls
Type - Pset_ReinforcementBarPitchOfWall - Description: betonwand d=600
Type - Pset_WallCommon - IsExternal: no
Type - Pset_Pieters - Dikte: 600 mm; Naamgeving element: 28_PBT_WA_beton t.p.g._d=600_C30/37; Codering - NL-SfB: 28.21; Omschrijving NL-SfB: hoofddraagconstructies - wanden en vloeren, wand-/vloerconstructies; Materiaal: 00_PBT_MAT_beton t.p.g._C30/37; Materiaalkwaliteit: C30/37; Description: betonwand d=600; Type Comments: d=600
Classification: 28.21 hoofddraagconstructies - wanden en vloeren, wand-/vloerconstructies (Uniformat)
BaseQuantities - Width: 600 mm
Pset_QuantityTakeOff - Reference: Basic Wall:28_PBT_WA_beton t.p.g._d=600_C30/37
Pset_ReinforcementBarPitchOfWall - Reference: Basic Wall:28_PBT_WA_beton t.p.g._d=600_C30/37
Pset_WallCommon - LoadBearing: yes; ExtendToStructure: no; Reference: Basic Wall:28_PBT_WA_beton t.p.g._d=600_C30/37
Pset_Pieters - Dragend/niet dragend: yes; In/uitwendig: no; Fase: Nieuw
Name (Basic Wall:28_PBT_WA_beton t.p.g._d=600_C30/37:...) | In | Height (mm) | Length (mm) | GrossFootprintArea (mm2) | GrossVolume (m3) | GrossSideArea (mm2) | NetSideArea (mm2) | NetVolume (m3) | Bouwlaag
1985417 | -1 kelder | 3250 | 4100 | 2460000 | 7.9578 | 13263000 | 13263000 | 7.9578 | Level: -1 kelder
2003642 | 00 begane grond | 3560 | 4100 | 2460000 | 7.98561 | 13309346 | 13309346 | 7.98561 | Level: 00 begane grond
2015668 | 01 eerste verdieping | 1150 | 1526.69 | 916015 | 1.05342 | 1755695 | 1755695 | 1.05342 | Level: 01 eerste verdieping
2025504 | 02 tweede verdieping | 3730 | 30430.8 | 18258464 | 54.7319 | 91219910 | 91152410 | 54.3467 | Level: 02 tweede verdieping
2391563 | 01 eerste verdieping | 3330 | 1526.69 | 916015 | 3.05033 | 5083883 | 5083883 | 3.05033 | Level: 01 eerste verdieping

# IfcWallStandardCase: Basic Wall:28_PBT_WA_beton t.p.g._d=620_C30/37, Basic Wall:28_PBT_WA_beton t.p.g._d=620_C30/37:4549909
In: -1 kelder
Type - PredefinedType: STANDARD; Material: 00_PBT_MAT_beton t.p.g._C30/37 620 mm
Type - Pset_ElementShading - Roughness: 304.8 mm
Type - Pset_ProductRequirements - Category: Walls
Type - Pset_ReinforcementBarPitchOfWall - Description: betonwand d=620
Type - Pset_WallCommon - IsExternal: no
Type - Pset_Pieters - Dikte: 620 mm; Naamgeving element: 28_PBT_WA_beton t.p.g._d=620_C30/37; Codering - NL-SfB: 28.21; Omschrijving NL-SfB: hoofddraagconstructies - wanden en vloeren, wand-/vloerconstructies; Materiaal: 00_PBT_MAT_beton t.p.g._C30/37; Materiaalkwaliteit: C30/37; Description: betonwand d=620; Type Comments: d=620
Classification: 28.21 hoofddraagconstructies - wanden en vloeren, wand-/vloerconstructies (Uniformat)
BaseQuantities - Height: 2980 mm; Length: 4145.77 mm; Width: 620 mm; GrossFootprintArea: 2570376 mm2; GrossVolume: 7.65229 m3; GrossSideArea: 12342403 mm2; NetSideArea: 12342403 mm2; NetVolume: 7.2316 m3
Pset_QuantityTakeOff - Reference: Basic Wall:28_PBT_WA_beton t.p.g._d=620_C30/37
Pset_ReinforcementBarPitchOfWall - Reference: Basic Wall:28_PBT_WA_beton t.p.g._d=620_C30/37
Pset_WallCommon - LoadBearing: yes; ExtendToStructure: yes; Reference: Basic Wall:28_PBT_WA_beton t.p.g._d=620_C30/37
Pset_Pieters - Bouwlaag: Level: -1 kelder; Fase: Nieuw

# IfcWallStandardCase: Basic Wall:28_PBT_WA_beton t.p.g._d=65_C30/37 (2)
In: -1 kelder
Type - PredefinedType: STANDARD; Material: 00_PBT_MAT_beton t.p.g._C30/37 65 mm
Type - Pset_ElementShading - Roughness: 304.8 mm
Type - Pset_ProductRequirements - Category: Walls
Type - Pset_ReinforcementBarPitchOfWall - Description: betonnen opdikking d=65
Type - Pset_WallCommon - IsExternal: no
Type - Pset_Pieters - Dikte: 65 mm; Naamgeving element: 28_PBT_WA_beton t.p.g._d=65_C30/37; Codering - NL-SfB: 28.21; Omschrijving NL-SfB: hoofddraagconstructies - wanden en vloeren, wand-/vloerconstructies; Materiaal: 00_PBT_MAT_beton t.p.g._C30/37; Materiaalkwaliteit: C30/37; Description: betonnen opdikking d=65; Type Comments: d=65
Classification: 28.21 hoofddraagconstructies - wanden en vloeren, wand-/vloerconstructies (Uniformat)
BaseQuantities - Width: 65 mm
Pset_QuantityTakeOff - Reference: Basic Wall:28_PBT_WA_beton t.p.g._d=65_C30/37
Pset_ReinforcementBarPitchOfWall - Reference: Basic Wall:28_PBT_WA_beton t.p.g._d=65_C30/37
Pset_WallCommon - LoadBearing: yes; ExtendToStructure: no; Reference: Basic Wall:28_PBT_WA_beton t.p.g._d=65_C30/37
Pset_Pieters - Dragend/niet dragend: yes; Fase: Nieuw
Name (Basic Wall:28_PBT_WA_beton t.p.g._d=65_C30/37:...) | Height (mm) | Length (mm) | GrossFootprintArea (mm2) | GrossVolume (m3) = NetVolume (m3) | GrossSideArea (mm2) = NetSideArea (mm2) | In/uitwendig | Bouwlaag
3061569 | 2650 | 5780 | 375700 | 0.995605 | 15317000 | no | Level: -1 kelder
5574194 | 1260 | 2500 | 162500 | 0.20475 | 3150000 | yes | Level: -1 kelder_Offset1000 | Pset_WallCommon - IsExternal: yes

# IfcWallStandardCase: Basic Wall:28_PBT_WA_beton t.p.g._d=717_C30/37 (2)
In: -1 kelder
Type - PredefinedType: STANDARD; Material: 00_PBT_MAT_beton t.p.g._C30/37 717 mm
Type - Pset_ElementShading - Roughness: 304.8 mm
Type - Pset_ProductRequirements - Category: Walls
Type - Pset_ReinforcementBarPitchOfWall - Description: betonwand d=717
Type - Pset_WallCommon - IsExternal: no
Type - Pset_Pieters - Dikte: 717 mm; Naamgeving element: 28_PBT_WA_beton t.p.g._d=717_C30/37; Codering - NL-SfB: 28.21; Omschrijving NL-SfB: hoofddraagconstructies - wanden en vloeren, wand-/vloerconstructies; Materiaal: 00_PBT_MAT_beton t.p.g._C30/37; Materiaalkwaliteit: C30/37; Description: betonwand d=717; Type Comments: d=717
Classification: 28.21 hoofddraagconstructies - wanden en vloeren, wand-/vloerconstructies (Uniformat)
BaseQuantities - Width: 717 mm
Pset_QuantityTakeOff - Reference: Basic Wall:28_PBT_WA_beton t.p.g._d=717_C30/37
Pset_ReinforcementBarPitchOfWall - Reference: Basic Wall:28_PBT_WA_beton t.p.g._d=717_C30/37
Pset_WallCommon - LoadBearing: yes; ExtendToStructure: no; Reference: Basic Wall:28_PBT_WA_beton t.p.g._d=717_C30/37
Pset_Pieters - Bouwlaag: Level: -1 kelder; Fase: Nieuw
Name (Basic Wall:28_PBT_WA_beton t.p.g._d=717_C30/37:...) | Height (mm) | Length (mm) | GrossFootprintArea (mm2) | GrossVolume (m3) = NetVolume (m3) | GrossSideArea (mm2) = NetSideArea (mm2)
4423722 | 3070 | 1876.87 | 1345716 | 4.13135 | 5761993 | Pset_Pieters - Dragend/niet dragend: yes; In/uitwendig: no
4426159 | 1690 | 3408.13 | 2443628 | 4.12973 | 5759736

# IfcWallStandardCase: Basic Wall:28_PBT_WA_kzs_d=100_CS20 (7)
Type - PredefinedType: STANDARD; Material: 00_PBT_MAT_kalkzandsteen_CS20 100 mm
Type - Pset_ElementShading - Roughness: 304.8 mm
Type - Pset_ProductRequirements - Category: Walls
Type - Pset_ReinforcementBarPitchOfWall - Description: kzs wand d=100
Type - Pset_WallCommon - IsExternal: no
Type - Pset_Pieters - Dikte: 100 mm; Naamgeving element: 28_PBT_WA_kzs_d=100_CS20; Codering - NL-SfB: 28.21; Omschrijving NL-SfB: hoofddraagconstructies - wanden en vloeren, wand-/vloerconstructies; Materiaal: 00_PBT_MAT_kalkzandsteen_CS20; Materiaalkwaliteit: CS20; Description: kzs wand d=100
Classification: 28.21 hoofddraagconstructies - wanden en vloeren, wand-/vloerconstructies (Uniformat)
BaseQuantities - Width: 100 mm
Pset_QuantityTakeOff - Reference: Basic Wall:28_PBT_WA_kzs_d=100_CS20
Pset_ReinforcementBarPitchOfWall - Reference: Basic Wall:28_PBT_WA_kzs_d=100_CS20
Pset_WallCommon - LoadBearing: yes; ExtendToStructure: no; Reference: Basic Wall:28_PBT_WA_kzs_d=100_CS20
Pset_Pieters - Fase: Nieuw
Name (Basic Wall:28_PBT_WA_kzs_d=100_CS20:...) | In | Height (mm) | Length (mm) | GrossFootprintArea (mm2) | GrossVolume (m3) | GrossSideArea (mm2) = NetSideArea (mm2) | NetVolume (m3) | Bouwlaag
2390604 | 01 eerste verdieping | 1120 | 1563.83 | 148952 | 0.175149 | 1751495 | 0.166827 | Level: 01 eerste verdieping
2390617 | 01 eerste verdieping | 1120 | 2410 | 241000 | 0.26992 | 2699200 | 0.26992 | Level: 01 eerste verdieping
2390630 | 01 eerste verdieping | 1120 | 1848.51 | 184851 | 0.207033 | 2070328 | 0.207033 | Level: 01 eerste verdieping
2390729 | 01 eerste verdieping | 1040 | 1590 | 159000 | 0.16536 | 1653600 | 0.16536 | Level: 01 eerste verdieping
2390731 | 01 eerste verdieping | 1040 | 2410 | 241000 | 0.25064 | 2506400 | 0.25064 | Level: 01 eerste verdieping
2390733 | 01 eerste verdieping | 1040 | 1989.05 | 198905 | 0.206861 | 2068614 | 0.206861 | Level: 01 eerste verdieping
6361207 | 02 tweede verdieping | 395 | 3686.74 | 368674 | 0.13404 | 1340401 | 0.13404 | Level: 02 tweede verdieping | Pset_Pieters - Dragend/niet dragend: yes; In/uitwendig: no

# IfcWallStandardCase: Basic Wall:28_PBT_WA_kzs_d=120_CS20, Basic Wall:28_PBT_WA_kzs_d=120_CS20:6386776
In: -1 kelder
Type - PredefinedType: STANDARD; Material: 00_PBT_MAT_kalkzandsteen_CS20 120 mm
Type - Pset_ElementShading - Roughness: 304.8 mm
Type - Pset_ProductRequirements - Category: Walls
Type - Pset_ReinforcementBarPitchOfWall - Description: kzs wand d=120
Type - Pset_WallCommon - IsExternal: no
Type - Pset_Pieters - Dikte: 120 mm; Naamgeving element: 28_PBT_WA_kzs_d=120_CS20; Materiaal: 00_PBT_MAT_kalkzandsteen_CS20; Materiaalkwaliteit: CS20; Description: kzs wand d=120
BaseQuantities - Height: 1377.65 mm; Length: 1073.59 mm; Width: 120 mm; GrossFootprintArea: 128831 mm2; GrossVolume: 0.177483 m3; GrossSideArea: 1479028 mm2; NetSideArea: 1479028 mm2; NetVolume: 0.177483 m3
Pset_QuantityTakeOff - Reference: Basic Wall:28_PBT_WA_kzs_d=120_CS20
Pset_ReinforcementBarPitchOfWall - Reference: Basic Wall:28_PBT_WA_kzs_d=120_CS20
Pset_WallCommon - LoadBearing: yes; ExtendToStructure: no; Reference: Basic Wall:28_PBT_WA_kzs_d=120_CS20
Pset_Pieters - Dragend/niet dragend: yes; In/uitwendig: no; Bouwlaag: Level: -1 kelder; Fase: Nieuw

# IfcWallStandardCase: Basic Wall:28_PBT_WA_kzs_d=150_CS20 (3)
Type - PredefinedType: STANDARD; Material: 00_PBT_MAT_kalkzandsteen_CS20 150 mm
Type - Pset_ElementShading - Roughness: 304.8 mm
Type - Pset_ProductRequirements - Category: Walls
Type - Pset_ReinforcementBarPitchOfWall - Description: kzs wand d=150
Type - Pset_WallCommon - IsExternal: no
Type - Pset_Pieters - Dikte: 150 mm; Naamgeving element: 28_PBT_WA_kzs_d=150_CS20; Materiaal: 00_PBT_MAT_kalkzandsteen_CS20; Materiaalkwaliteit: CS20; Description: kzs wand d=150
BaseQuantities - Width: 150 mm
Pset_QuantityTakeOff - Reference: Basic Wall:28_PBT_WA_kzs_d=150_CS20
Pset_ReinforcementBarPitchOfWall - Reference: Basic Wall:28_PBT_WA_kzs_d=150_CS20
Pset_WallCommon - LoadBearing: yes; ExtendToStructure: no; Reference: Basic Wall:28_PBT_WA_kzs_d=150_CS20
Pset_Pieters - Fase: Nieuw
Name (Basic Wall:28_PBT_WA_kzs_d=150_CS20:...) | In | Height (mm) | Length (mm) | GrossFootprintArea (mm2) | GrossVolume (m3) | GrossSideArea (mm2) = NetSideArea (mm2) | NetVolume (m3) | Bouwlaag
4553923 | -1 kelder | 750 | 9960 | 1494000 | 1.1205 | 7470000 | 1.1205 | Level: -1 kelder_Offset1000 | Pset_Pieters - Dragend/niet dragend: yes; In/uitwendig: no
6381101 | -2 kelder | 2227.49 | 1237 | 185550 | 0.399511 | 2663407 | 0.399511 | Level: -2 kelder
6381612 | -2 kelder | 2227.49 | 975 | 146250 | 0.325771 | 2171806 | 0.324452 | Level: -2 kelder
